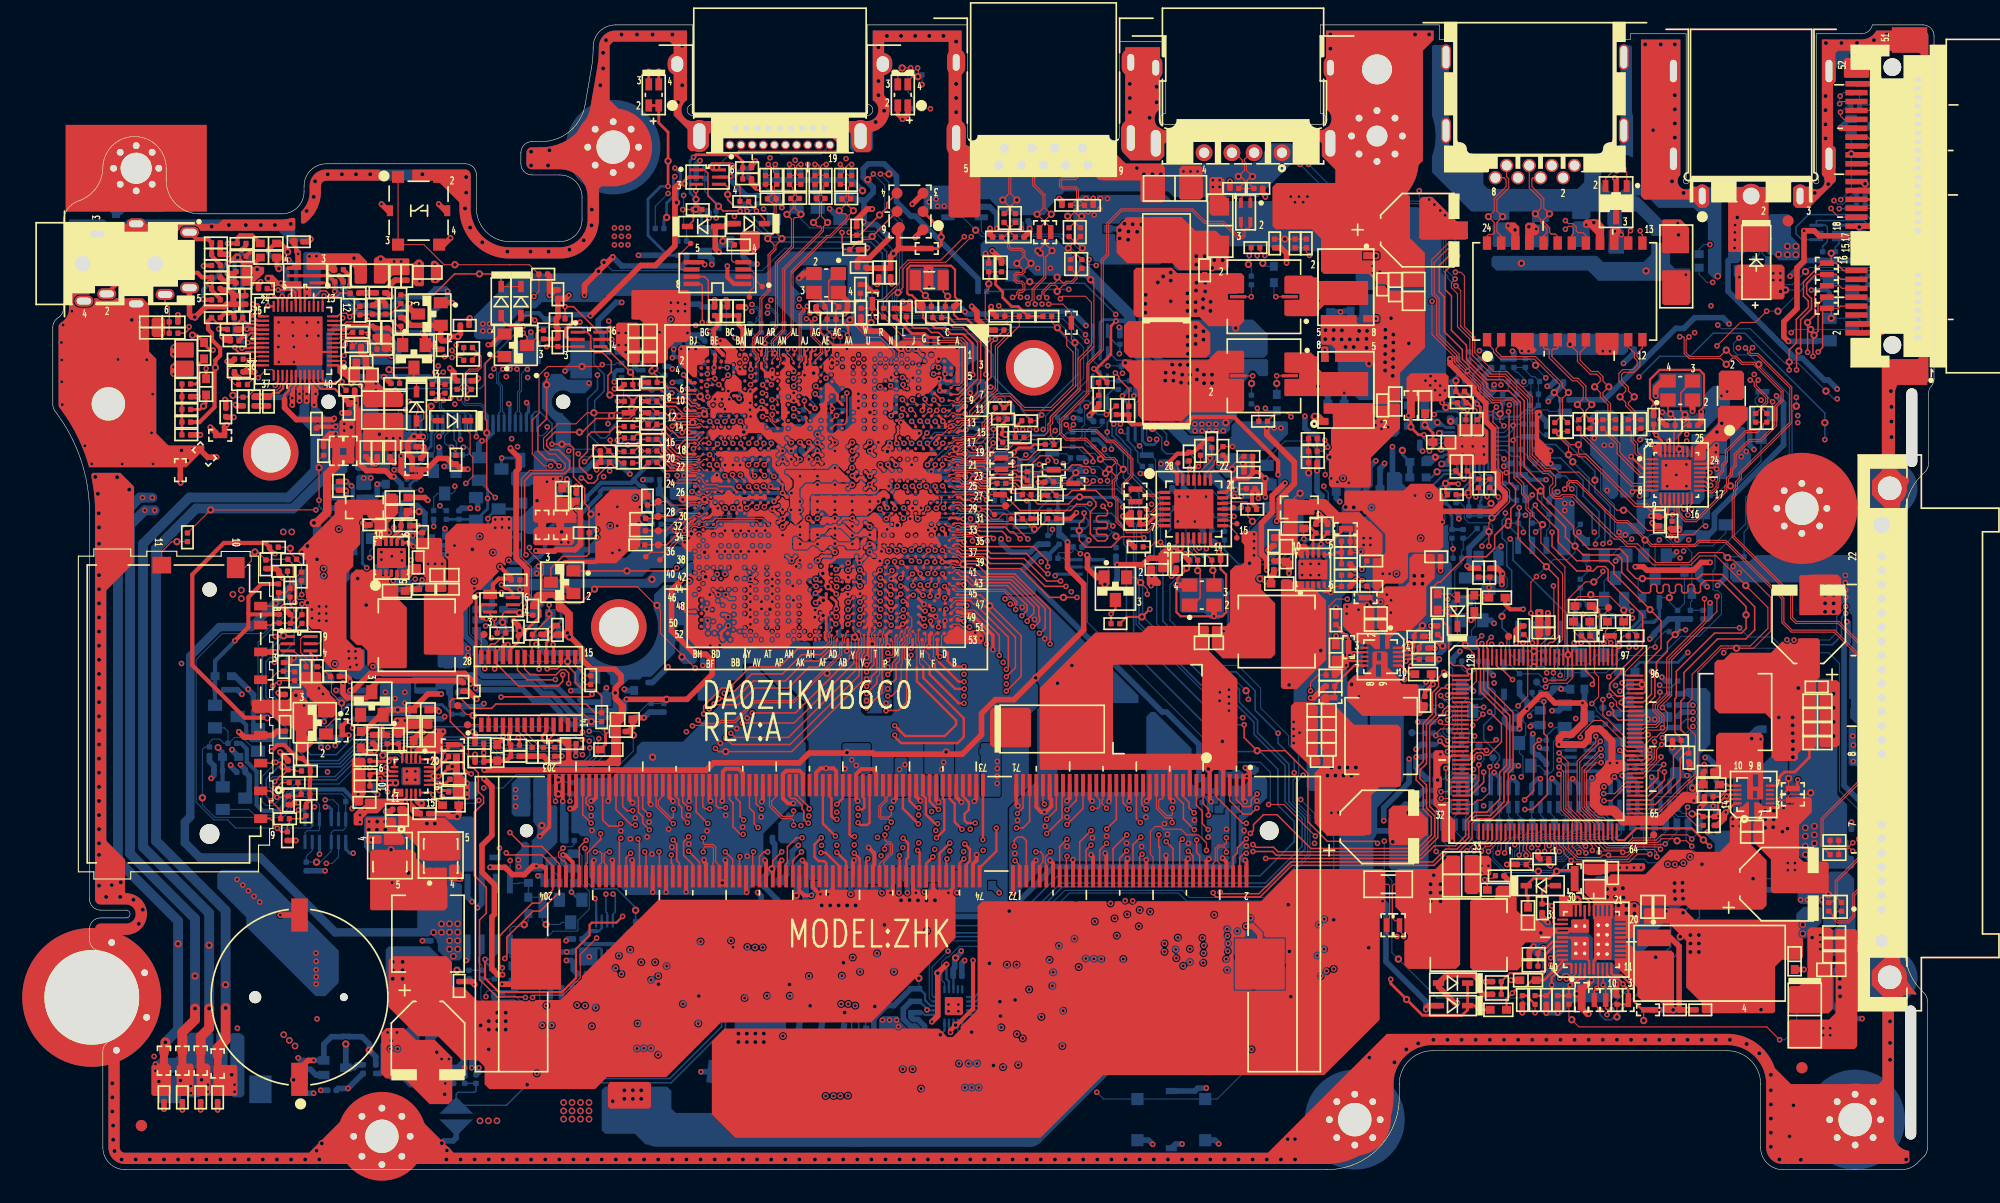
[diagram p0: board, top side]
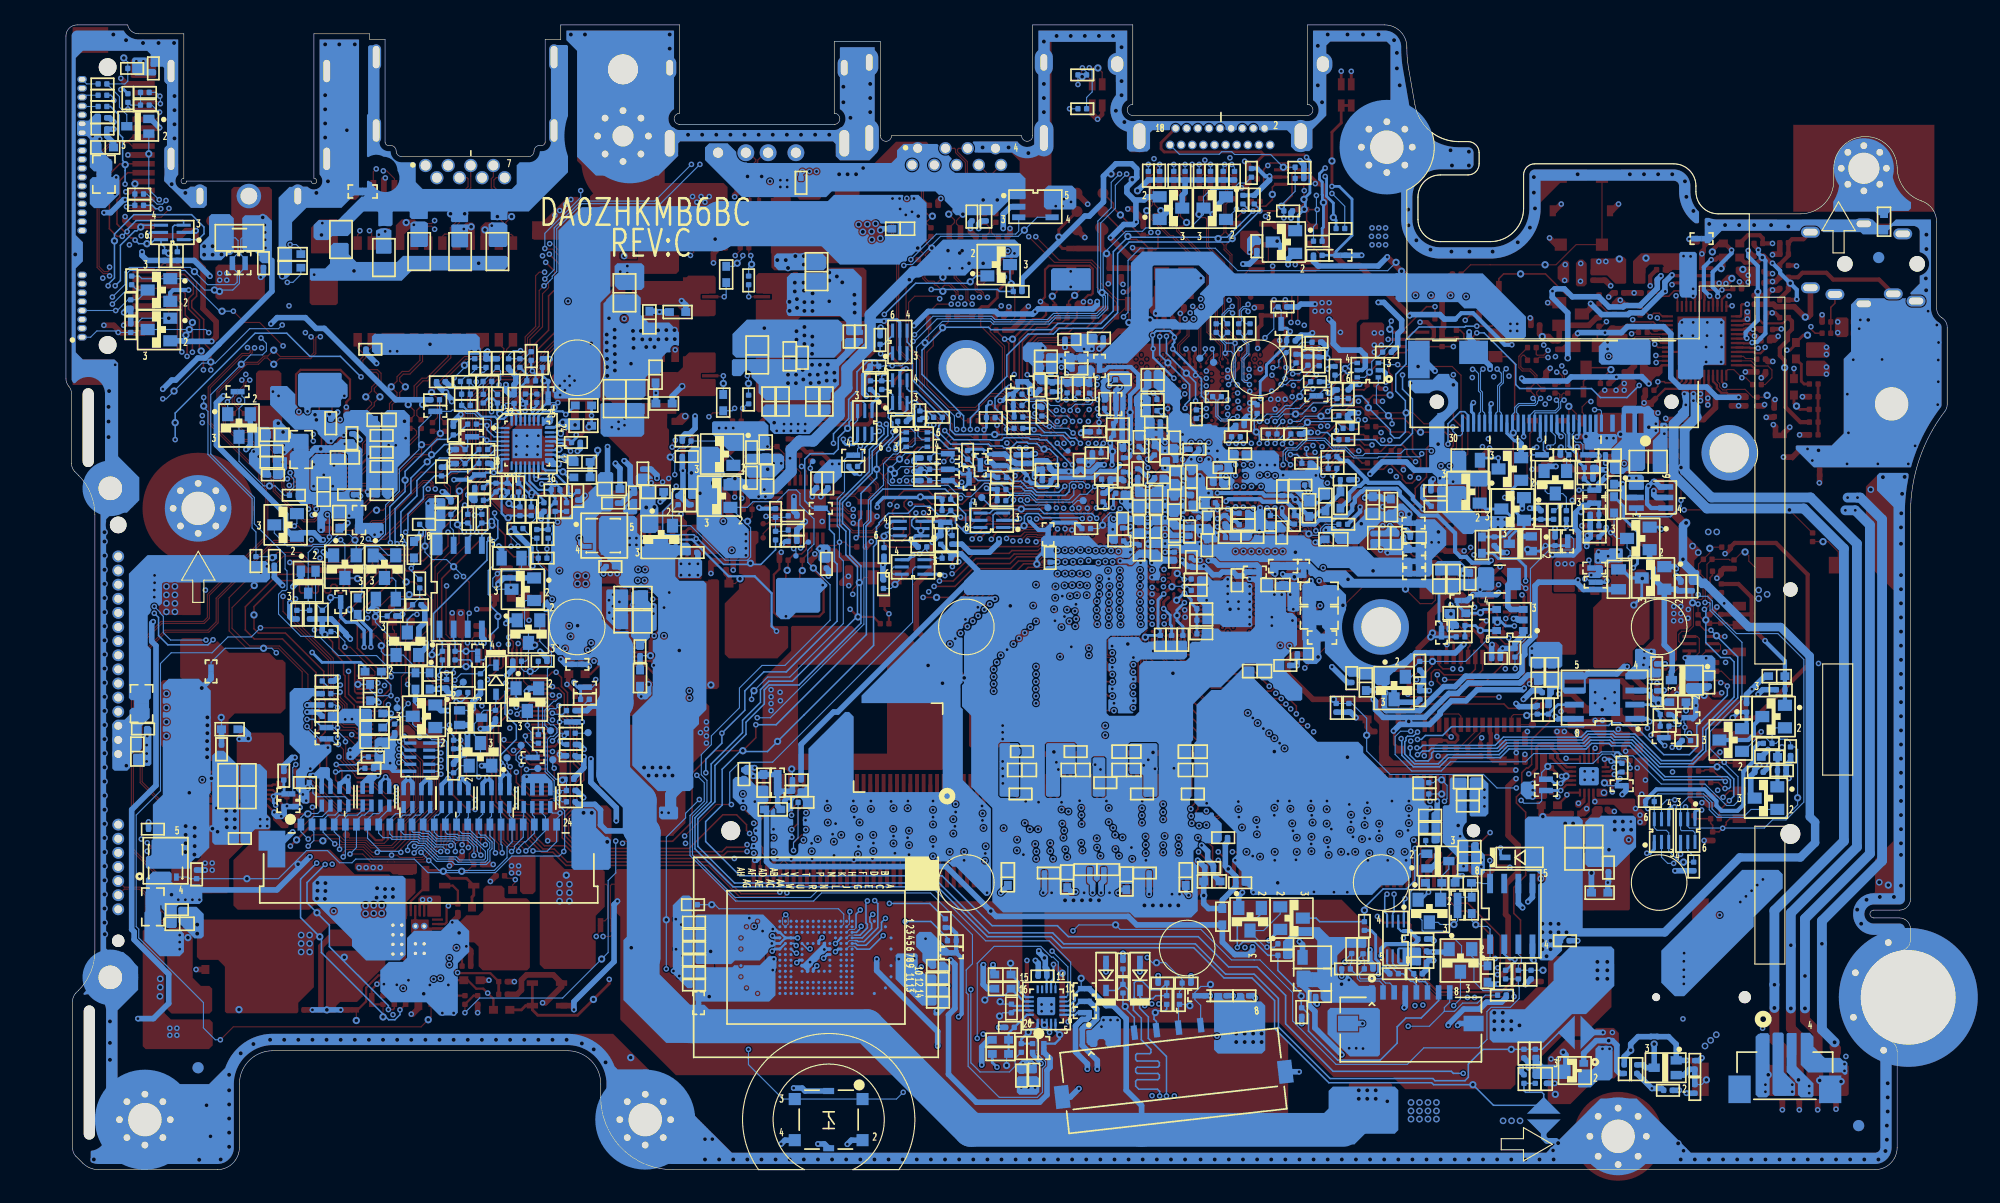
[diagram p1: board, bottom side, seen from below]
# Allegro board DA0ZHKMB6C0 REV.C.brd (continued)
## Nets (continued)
MX2: CN17.16 CP10.7 RP6.3 U18.56
MX3: CN17.14 CP10.3 RP6.4 U18.57
MX4: CN17.7 CP6.5 RP6.6 U18.58
MX5: CN17.3 CP7.5 RP6.7 U18.59
MX6: CN17.2 CP7.3 RP6.8 U18.60
MX7: CN17.1 CP7.1 RP6.9 U18.61
MY0: CN17.4 CP7.7 R394.1 U18.53
MY1: CN17.5 CP6.1 U18.52
MY2: CN17.6 CP6.3 U18.51
MY3: CN17.8 CP6.7 U18.50
MY4: CN17.9 CP11.1 U18.49
MY5: CN17.10 CP11.3 U18.48
MY6: CN17.11 CP11.5 U18.47
MY7: CN17.12 CP11.7 U18.43
MY8: CN17.13 CP10.1 U18.42
MY9: CN17.15 CP10.5 U18.41
MY10: CN17.18 CP9.3 U18.40
MY11: CN17.19 CP9.5 U18.39
MY12: CN17.21 CP8.1 U18.38
MY13: CN17.22 CP8.3 U18.37
MY14: CN17.23 CP8.5 U18.36
MY15: CN17.24 CP8.7 U18.35
NB670BST: PR40.1 PU8.10
NB670BST_S: PC49.1 PR40.2
NB670EN: PC43.2 PR147.2 PR148.2 PU8.13
NB670ENLDO: PR37.1 PR39.2 PU8.12
NB670PG: PR38.2 PU8.4
NB670SW: PC49.2 PL11.1 PR146.2 PU8.8 PU8.9 PU8.15 PU8.16
NB670VOUT: PC48.1 PR42.1 PU8.7
NB671BST: PR47.1 PU10.10
NB671BST_S: PC61.1 PR47.2
NB671EN: PC176.2 PR163.2 PU10.13
NB671FB: PR52.2 PR53.1 PU10.12
NB671PG: PR49.2 PU10.4
NB671SW: PC61.2 PL10.1 PR157.2 PU10.8 PU10.9 PU10.15 PU10.16
NBSWON#: D15.1 SW6.1 SW6.3 U18.95
NOVRP1: R112.1 U13.25
NOVRP2: R113.1 U13.24
NOVRP3: R133.1 U13.20
NOVRP4: R144.1 U13.19
PCBEEP: C40.1 U9.12
PCBEEP_EC: D16.2 U18.118
PCH_DISP_ON: Q8.3 R31.2 R111.2 U21.3
PCH_DISP_ON_C: Q8.1 U12.N30
PCH_DPST_PWM: Q29.3 R277.1 R304.1
PCH_DPST_PWM_C: Q29.4 U12.M30
PCH_LVDS_BLON: Q29.6 Q34.2 R300.2 R377.2 R535.1
PCH_LVDS_BLON_C: Q29.1 U12.J30
PCH_SLP_S0#: Q18.1 U12.G18
PCH_SLP_S0_N: Q18.3 R230.1 U18.28
PCIE_CLKREQ3#: R237.2 TP22.1 U12.BE3
PCIE_CLKREQ_CR#: R239.2 U12.BG3
PCIE_CLKREQ_LAN#: Q30.1 R242.2 U12.BG5
PCIE_CLKREQ_LAN#_IC: Q30.3 R150.2 U11.12
PCIE_CLKREQ_WLAN#: Q19.1 R246.2 R537.1 U12.BD7
PCIE_RXN1_WLAN: CN10.23 U12.AT9
PCIE_RXN2_LAN: C76.2 U12.AP10
PCIE_RXP1_WLAN: CN10.25 U12.AT10
PCIE_RXP2_LAN: C77.2 U12.AP12
PCIE_TXN1_WLAN: C154.1 CN10.31
PCIE_TXN1_WLAN_C: C154.2 U12.AV4
PCIE_TXN2_LAN: C152.1 U11.14
PCIE_TXN2_LAN_C: C152.2 U12.AT6
PCIE_TXP1_WLAN: C155.1 CN10.33
PCIE_TXP1_WLAN_C: C155.2 U12.AV6
PCIE_TXP2_LAN: C153.1 U11.13
PCIE_TXP2_LAN_C: C153.2 U12.AT7
PCIE_WAKE#_R: CN10.1 Q20.1 R232.1
PCLK_TPM: C106.1 R98.1 U16.21
PCU_V3P3_G3_PWR: C183.1 C185.2 R257.2 U12.N18 U12.N22 U12.P18
PD#: D31.2 D32.2 R82.2 U9.47
PGANG: R114.2 U13.23
PLTRST#: C359.2 Q21.6 R202.1 R217.2 R235.1 R322.1 R530.1 U11.19 U16.16 U18.7
PLTRST#_2: CN10.22 R216.1 R217.1
PM_EXTTS#0: JDIM6.198 R398.2
PMU_BATLOW#_R: R301.2 U12.K26
PROCHOT_EC: Q33.2 R358.2 U18.111
PSELF: R115.1 U13.22
PWR_SD_EN: C156.2 PQ2.2 Q46.6 R185.2
PWRLED#: R192.2 U18.62
PWROK_EC_UR: R375.1 U18.74
R_SPK+: R191.2 U9.45
R_SPK+_1: C139.1 CN19.1 R191.1
R_SPK-: R190.2 U9.44
R_SPK-_1: C138.1 CN19.2 R190.1
REGOUT: L13.1 U11.24
RESET#_USB: C248.2 R306.1 R308.2 R322.2 U13.17
RF_EN: CN10.20 U18.83
RING2: Q7.3 R30.1 R37.1 U9.17
RREF: R154.1 U13.8
RSET: R97.2 U11.31
RSMRST#: R58.2 R373.2 U12.B10
RSMRST#_UR: R373.1 U18.75
RTC_VCC_P22_PWR: C221.2 R288.1 U12.P22
RTC_X1: C46.2 R59.1 U12.C9 Y7.1
RTC_X2: C47.2 R59.2 U12.A9 Y7.2
S5_ON: PQ33.2 PQ37.2 PR126.2 PR148.1 PR163.1 PR184.2 R387.1 R391.1 U18.26
S5D: PC133.1 PQ13.2 PQ17.2 PU16.9
SATA_GP0: R252.1 U12.BA12
SATA_GP1: R260.1 U12.AY14
SATA_RCOMP_DN: R163.2 U12.AT18
SATA_RCOMP_DP: R163.1 U12.AU18
SATA_RXN0: C124.2 U12.AV16
SATA_RXN0_R: C124.1 CN14.5
SATA_RXP0: C123.2 U12.AU16
SATA_RXP0_R: C123.1 CN14.6
SATA_TXN0: C130.2 U12.BG7
SATA_TXN0_R: C130.1 CN14.3
SATA_TXP0: C129.2 U12.BF6
SATA_TXP0_R: C129.1 CN14.2
SD3_WP: R316.2 U12.BD5
SDIO3_1P8_EN#: Q50.5 U12.BF22
SDIO3_CD: Q46.2 Q46.3 R184.2
SDIO3_CD#: CN4.10 R363.2 T10.1 U12.BC24
SDIO3_CLK: R543.2 U12.AY26
SDIO3_CMD: CN4.2 R548.2 T13.1 U12.AV28
SDIO3_DATA_0: R542.2 U12.AT28
SDIO3_DATA_0C: CN4.7 R542.1 R547.2 T14.1
SDIO3_DATA_1: R541.2 U12.BD26
SDIO3_DATA_1C: CN4.8 R541.1 R546.2 T15.1
SDIO3_DATA_2: R540.2 U12.AU28
SDIO3_DATA_2C: CN4.9 R540.1 R545.2 T11.1
SDIO3_DATA_3: R544.2 U12.BA26
SDIO3_DATA_3C: CN4.1 R544.1 R549.2 T12.1
SDIO3_PWR_EN#: Q50.2 Q51.2 R365.2 U12.BD22
SDIO3_RCOMP: R293.2 U12.BF26
SDVO_CLK: Q6.4 R219.2 U12.C28
SDVO_DATA: Q6.1 R218.2 U12.C26
SENSEA: R22.1 U9.13
SERIRQ: R83.1 U18.125
SERIRQ_R: R172.2 R539.1 U16.27 U24.4
SIO_EXT_SCI#: R395.1 U18.29 U26.3
SIO_EXT_SMI#: R370.1 U18.9 U26.1
SIO_RCIN#: TP19.1 U18.122
SLEEVE: Q7.6 R33.1 R68.1 U9.18
SLP_S0IX#: Q21.4 U12.F18
SLP_S3#: Q23.4 R86.1 U12.D22
SLP_S4#: Q23.1 Q53.2 R87.1 U12.F22
SLP_SUS#_EC: Q21.3 R241.2 U18.79
SLP_SUS_ON: PR159.1 R343.1 U18.96
SMB_RUN_CLK: JDIM6.202 Q16.1 Q40.3 R67.1
SMB_RUN_DAT: JDIM6.200 Q16.4 Q40.6 R62.1
SMB_SOC_ALERTB_C: R80.2 U12.BG11
SMB_SOC_CLK: Q40.4 R73.2 U12.BH10
SMB_SOC_DATA: Q40.1 R79.2 U12.BG12
SMC: PJ7.4 PR179.1
SMD: PJ7.3 PR180.1
SOC_CLKOUT_0: R90.2 R98.2 U12.BG15
SOC_CLKOUT_1: R274.2 U12.BH14
SOC_CLKRUN#: R167.1 R279.2 U12.BG16
SOC_CORE_PIN_AA22: TP25.1 U12.AA22
SOC_CORE_PINAF30: TP26.1 U12.AF30
SOC_DDIO_RCOMP: R264.1 U12.AK13
SOC_DDIO_RCOMP_P: R264.2 U12.AK12
SOC_DRAM_PWROK: C256.1 R315.1 U12.AD42
SOC_GPIO_RCOMP: R299.2 U12.N26
SOC_GPOI7: R36.1 U12.C15
SOC_JTAG2_TCK: R60.1 U12.B16
SOC_JTAG2_TDI: R81.1 U12.A17
SOC_JTAG2_TDO: R61.1 U12.C17
SOC_JTAG2_TMS: R88.1 U12.C18
SOC_KBC_SCI: R243.1 R252.2 U26.4
SOC_KCB_SMI: R36.2 R256.1 U26.6
SOC_OVERRIDE: Q24.3 U12.BC30
SOC_OVERRIDE_NM: Q24.5 R283.1
SOC_PCIE_COMN: R263.2 U12.AP13
SOC_PCIE_COMP: R263.1 U12.AP14
SOC_PLTRST#: Q21.1 U12.F20
SOC_PMC_WAKE: R295.2 U12.F26 U25.4
SOC_PROCHOT#: R128.2 R130.2 U12.C24
SOC_PWR_BUT: R48.1 U12.N3
SOC_PWRBTN#: R280.1 U12.J26 U25.6
SOC_REST_BTN: R74.2 U12.BG9
SOC_RTEST#: C336.1 G7.1 R415.2 U12.C11
SOC_SENS_HUB_RST#: TP35.1 U12.AT32
SOC_SENSOR_HUB_WAKE: R265.2 U12.BF14
SOC_SERIRQ: R83.2 R84.2 R172.1 U12.BG13 U24.3
SOC_SPI_CLK: R121.2 U12.C22
SOC_SPI_CLK_R: R121.1 R311.1 U22.6
SOC_SPI_CLK_R1: R311.2 U18.92
SOC_SPI_CS#: R120.2 R305.2 U12.C23
SOC_SPI_CS#_R: R120.1 R354.1 U22.1
SOC_SPI_CS#_R1: R354.2 U18.90
SOC_SPI_MISO: R352.2 U12.B22
SOC_SPI_MISO_R: R352.1 R353.1 U22.2
SOC_SPI_MISO_R1: R353.2 R362.2 U18.86
SOC_SPI_MOSI: R116.2 U12.A21
SOC_SPI_MOSI_R: R116.1 R310.1 U22.5
SOC_SPI_MOSI_R1: R310.2 U18.87
SOC_UART_RX: R273.2 U12.BC16
SOC_UART_TX: R273.1 U12.BD14
SOC_USB_OC0: R105.1 U12.C20 U19.3
SOC_VCCA_PWROK: C261.1 Q32.3 R328.1 U12.AB42
SPI_3P: R319.2 U22.3
SPI_7P: R318.2 U22.7
SRT_CRST#: C332.1 G6.1 R413.2 U12.C12
SUS_LED#: R195.2 U18.16
SUS_PWRDOWNACK: R287.2 R291.2 U12.D26
SUSB#: Q23.3 R86.2 R268.1 R320.1 U18.21
SUSC#: Q23.6 R87.2 R245.1 R324.1 U18.20
SUSON: PR162.1 R171.1 U18.117
SUSWARN#_EC: R287.1 U18.113
SVID_ALERT#_SOC: R129.1 U12.B24
SVID_CLK_SOC: R134.1 U12.C25
SVID_DATA_SOC: R135.1 U12.A25
SYS_HWPG: PR36.2 PR38.1 PR49.1
SYS_SHDN#: PQ36.3 PR32.1 PR41.1 PR147.1 SW8.1 SW8.3
TEMP_MBAT: C110.2 PR174.1 PR178.1 U18.97
TEMP_MBAT_C: PJ7.5 PR178.2
THER_CPU: R327.2 R337.1
THERMDA: TP8.1 U7.2
THERMDC: TP9.1 U7.3
THRM_MOINTOR: C274.2 R337.2 R345.1 U18.100
TOUCH_PANEL_SOC_RST#: R269.2 U12.BD16
TOUCH_SCREEN_PWR: C202.2 C210.1 CN16.11 R294.1
TOUCH_SCREEN_SEL: CN16.29 Q12.3 R153.1
TOUCHPANEL_INTR#_SOC: TP21.1 U12.AU32
TP_EN_EC: CN18.8 R536.1 U18.73
TP_INT_C: Q12.1 U12.G24
TP_INT_EC#: Q41.3 R420.2 U18.11
TP_NC: R155.1 TP27.1 U12.BH30
TP_NC1: R156.1 TP32.1 U12.BG30
TP_POWER_ON: PU16.2 TP43.1 U18.25
TP_SENSOR_INT: Q42.3 R513.1 U12.B18
TP_SENSOR_INT_R: C358.2 CN18.7 Q41.1 Q45.2 R420.1 R534.1
TPCLK: C330.2 CN18.2 R406.2 U18.72
TPDATA: C329.2 CN18.3 R405.2 U18.71
TPM_VDD: C105.1 C107.1 C118.1 C119.1 C355.1 R178.2 R180.1 R182.2 R526.2 R539.2 U16.10 U16.19 U16.24
TPM_VSB: C356.2 C357.1 R526.1 R527.2 R528.2 U16.5
ULT_EDP_HPD: CN16.12 Q28.2 R276.2
UNCORE_V1P8_AN32_PWR: C241.2 C245.2 C265.2 R321.1 U12.AM30 U12.AN32 U12.U38
USB3_P0_REXT: R351.2 U12.M7
USB3_P1_REXT: R258.2 U12.M12
USB3_V1P0_G3: C165.2 C171.1 C172.2 C193.1 C220.2 R238.2 U12.B6 U12.C3 U12.C5 U12.U22 U12.V22 U12.Y19
USB30_RX1+: C23.1 R13.2 U12.D4
USB30_RX1+_R: CN6.6 R13.1
USB30_RX1-: C22.1 R12.2 U12.E3
USB30_RX1-_R: CN6.5 R12.1
USB30_TX1+: C26.1 U12.K6
USB30_TX1+_C: C26.2 R20.2
USB30_TX1+_R: C18.1 CN6.9 R20.1
USB30_TX1-: C25.1 U12.K7
USB30_TX1-_C: C25.2 R19.2
USB30_TX1-_R: C17.1 CN6.8 R19.1
USB_BT_N: CN10.36 U13.3
USB_BT_P: CN10.38 U13.4
USB_H1_N: R131.1 U12.G14
USB_H1_N1: R131.2 U13.1
USB_H1_P: R139.1 U12.J14
USB_H1_P1: R139.2 U13.2
USB_HSIC_RCOMP: R55.2 U12.A7
USB_HSIC_V1P2_G3: R240.1 U12.V18
USB_HUB_5V: TP15.1 U13.27
USB_RCOMP: R247.2 U12.C7 U12.D6
USB_USB_N: L7.2 U13.6
USB_USB_P: L7.3 U13.7
USBON#: U18.112 U19.4
USBP0+: R17.2 U12.M16
USBP0+_R: CN6.3 R17.1
USBP0-: R18.2 U12.K16
USBP0-_R: CN6.2 R18.1
USBP1+_CN: CN8.3 D7.1 L7.4
USBP1-_CN: CN8.2 D8.1 L7.1
USBP2+: CN16.27 U12.K12
USBP2-: CN16.26 U12.J12
USBP3+: CN16.24 U12.K10
USBP3-: CN16.23 U12.H10
V_BLIGHT: C190.1 C192.1 C206.2 CN16.1 CN16.2 CN16.3 R106.2 R107.2
VCORF_UR: C126.1 U18.44
VIS_V1P0_SIOX_PW: C209.1 C232.1 C233.1 C239.1 C255.1 R309.2 U12.AF21 U12.AG21 U12.AN29 U12.AN30 U12.V24 U12.Y22 U12.Y24
VL: PC47.2 PR172.1 PR173.1 PU8.11
VR_SVID_ALERT#: PR97.1 PR99.2 R127.1 R129.2
VR_SVID_CLK: PR95.2 PR96.2 R134.2
VR_SVID_DATA: PR98.2 PR104.2 R135.2
VRON: TP45.1 U18.80
WAKE_SRC_1: Q20.3 Q25.1 R266.2 R516.1 U18.84 U25.3
WIMAX_LED#: CN10.42 R204.1
WLAN_CLK_SCLK: CN10.30 Q16.6 R223.1
WLAN_CLK_SDATA: CN10.32 Q16.3 R222.1
WLAN_LED1#: CN10.44 R201.2 R203.1 R204.2
WPAN_LED#: CN10.46 R201.1
XDP_H_PRDY#: TP24.1 U12.D18
XDP_H_PREQ#: R63.1 U12.F16
XDP_H_TCK: R262.1 U12.D14
XDP_H_TDI: R251.1 U12.F12
XDP_H_TDO: R267.1 U12.G16
XDP_H_TMS: R259.1 U12.F14
XDP_H_TRST#: R250.2 U12.G12
XIN: C95.1 U13.10 Y9.1
XOUT: C96.1 U13.11 Y9.3
XTAL1: C79.1 U11.28 Y8.3
XTAL2: C78.1 U11.29 Y8.1
XTAL25_IN: C32.1 R42.1 U12.AH12 Y6.3
XTAL25_OUT: C33.1 R42.2 U12.AH10 Y6.1
N52444: PC57.2 PR43.2 PU9.5
N2441980: PC113.1 PR11.1 PU12.22
N2441992: PC19.1 PR12.2 PU12.21
N2443322: PC117.1 PR109.2
N2443370: PC101.1 PR85.2
N2443568: PR13.2 PR19.2
N2443616: PL7.4 PR89.1
N2443620: PL7.3 PR91.1
N2444597: PC123.2 PR116.2 PU12.11
N2445489: PR90.1 PR93.1 PU12.2
N2446506: PR79.2 PR86.1 TP23.1
N2446664: PR86.2 PU12.27
N2446955: PR6.1 PR7.1 PR8.2
N2448066: PR15.1 PR16.1 PR17.2
N2453156: PC95.1 PR77.2
N2453320: PR9.2 PR82.2
N2453360: PL6.4 PR75.1
N2453364: PL6.3 PR74.1
N2455134: PC111.1 PR92.2
N2455877: PC108.1 PR88.1 PU12.31
N2456910: PC98.1 PR76.1 PR78.2 PR80.1 PR81.2
N2456918: PC109.1 PR110.2 PR111.1 PU12.30
N2457578: PC16.1 PC102.2 PR10.2 PR81.1 PR87.2 PU12.29
N2457590: PC18.1 PR10.1
N2457790: PC102.1 PR80.2
N2457802: PC105.1 PR87.1
N2459346: PR107.2 PU12.8
N2459788: PC140.1 PR100.2 PR102.1 PR121.2 PR124.1
N2459816: PC137.1 PR105.2 PR106.2 PU12.12
N2460379: PC128.1 PC141.2 PR21.2 PR115.2 PR121.1 PU12.13
N2460411: PC141.1 PR124.2
N2460459: PC20.1 PR21.1
N2460593: PC136.1 PR115.1
N2481405: PC108.2 PR83.1
N2482435: PC123.1 PR117.2
N16509126: LED6.3 R192.1
N16512880: R24.1 U7.4
N16529605: TP31.1 U18.6
N16532690: R270.2 U12.M13
N16563782: PR98.1 PU12.5
N16563868: PR97.2 PU12.4
N16564009: PR95.1 PU12.3
N16585380: TP55.1 U13.18
N16624010: PC197.1 PR184.1 PU16.1
N16782265: PC112.2 PQ11.2 PQ22.3 PR134.2
N16827218: PC163.2 PQ18.3 PQ28.2 PR113.2
N16827382: LED6.1 LED6.2 R197.1 R198.1
N16853934: Q25.3 R298.2 R516.2 U11.21
N17396502: Q39.2 R414.1 R416.2
N17658483: PC78.1 PR56.1
N17711248: PR70.2 PU11.10
N17719024: PR60.1 PR61.2 PU11.37
N17726601: PC88.1 PR63.2 PU11.1
N17863079: PC89.2 PR68.1
N17863093: PR68.2 PU11.9
N17879873: TP56.1 U13.13
N17879875: TP57.1 U13.12
N18086472: LED7.3 R193.1
N18086480: LED7.4 R194.1
N18090006: R104.1 U12.B20
N18134434: D16.1 D19.1 R52.2
N18246859: C97.1 C98.1 C101.2 D24.2 R165.1 R166.1
N18278202: PR170.1 PR173.2 PU15.2
N18278204: PC183.2 PR168.1 PR169.1 PU15.8
N18278208: PD10.1 PQ35.1 PR166.1
N18278220: PQ35.3 PR169.2
N18278227: PQ33.3 PQ35.2 PR166.2
N18278261: PC188.2 PQ36.2 PR168.2 PU15.1
N18278273: PQ37.3 PR170.2
N18314354: PC28.1 PC31.1 PR23.1 PR25.1 PU7.9 PU7.10
N18314480: PC22.1 PC24.1 PR22.1 PR24.1 PU6.9 PU6.10
N18512754: PR138.2 PR139.2 PU13.6
N18512806: PC151.1 PR132.2 PU13.4
N18596580: LED6.4 R195.1
N19249672: C338.2 R426.2 U27.7 U27.8
N19253605: TP48.1 U12.G30
N19253641: TP50.1 U12.C27
N19253642: TP49.1 U12.B28
N19253643: TP51.1 U12.B26
N19253669: TP52.1 U12.AL3
N19253671: TP53.1 U12.AL1
N19661024: TP40.1 U18.107
N19667233: R181.1 R182.1 U16.7
N19667243: R180.2 U16.6
N19667397: R533.2 U16.15
N19667450: TP101.1 U16.1
N19667455: TP100.1 U16.2
N19667489: R530.2 U16.9
N19667717: TP99.1 U16.28
N19837103: Q42.2 Q45.3 R523.1
N19870274: C164.2 U8.3 U8.4 U8.9 U8.10
N20005341: Q46.5 R186.1 R363.1 R365.1
N20136993: C80.1 CN4.5 R543.1
N20159096: C282.1 D34.1 MR6.1 R361.1
N20218729: R419.2 U24.5
N20239051: PQ29.2 Q50.3 Q50.6 Q51.5 R187.2 R234.1
N20248245: PQ30.2 PQ31.2 Q51.3 Q51.6 R355.1 R356.2
N20295671: D24.1 R166.2 U18.4
N20307624: CN4.11 R316.1
N20310085: C226.2 Q27.2 R124.2 R297.1
N20311584: R34.2 U3.2
N20824488: R550.1 R551.1 U25.5
N20841552: HOLE9.1 HOLE9.2 HOLE9.3 HOLE9.4 HOLE9.5 HOLE9.6 HOLE9.7 HOLE9.8 HOLE9.9 R552.2
N38782190: PC181.2 PR167.1
N72970043: TP58.1 U13.15
N72970046: TP59.1 U13.16
N77036399: PR139.1 PR141.1
N77036417: PC155.2 PR140.1 PU13.1
N77036440: PR155.2 PU13.5
N77040681: PC154.2 PR146.1
N77040703: PR52.1 PR144.1
N77040765: PC68.2 PU10.11
N77090490: PC39.2 PR34.2
N77093840: PQ25.2 PQ26.3 PR142.2 PR143.1
N77097662: PQ21.2 PQ22.2 PQ24.3 PR136.1 PR137.2
N77098719: PC152.1 PQ24.2 PR133.2
N77135926: PR50.2 PU10.3
N77159527: PR154.2 PU14.1
N77159544: PR150.2 PR151.2 PU14.7
N77159572: PC173.2 PR153.1 PU14.2
N77164289: PQ18.2 PQ23.2 PQ27.3 PR129.2 PR130.1
N77164358: PC165.1 PQ27.2 PR152.2
N77164885: PQ12.2 PQ15.2 PQ20.3 PR118.2 PR119.1
N77164911: PC119.2 PQ14.2 PQ15.3 PR103.2
N77164954: PC143.1 PQ20.2 PR123.2
N77521058: TP41.1 U18.30
N77521417: R374.1 TP36.1
N77522500: TP18.1 U18.101
N77651911: CN10.45 R205.2
N77651913: CN10.47 R202.2
N77651966: CN10.16 R29.1
N77651968: CN10.14 R32.1
N77651970: CN10.12 R40.1
N77651972: CN10.10 R46.1
N77651974: CN10.8 R50.1
N77651983: CN10.51 R200.2
N77714296: PC34.2 PR33.2
N77766782: R535.2 U18.14
N107989610: C56.1 U9.7
N107992729: C68.2 U9.39
N107992826: C63.2 U9.35
N107992865: C63.1 U9.37
N107994632: C57.1 U9.34
N108778749: Q7.2 Q7.5 Q27.3 R35.1
N111127099: C35.1 U9.19
N202517111: PC174.2 PR157.1
N202572550: PQ12.3 PR101.2
N202573721: PQ23.3 PR127.2
N202573930: PQ25.3 PR125.2
N202576670: PQ21.3 PR135.2

Pads without a net: CN7 13 14; CN10 3 5 6 17 19 28 48 49; CN14 18 20 21 22; CN16 4; CN19 5 6; JDIM6 77 122 125; NOREF 1; NOREF#3 1; NOREF#6 1; NOREF#7 1; NOREF#8 1; NOREF#10 1; PU8 3 5; PU10 5 6; PU11 31; PU12 9 20; PU15 7; PU16 14 15; U9 14 16 20 48; U11 25 26 27; U12 AB2 AB3 AB7 AB9 AB12 AB13 AB14 AC1 AC3 AD2 AD3 AD4 AD6 AD9 AD10 AD12 AD40 AD41 AF2 AF3 AF4 AF6 AF13 AF14 AF40 AF41 AF48 AF50 AF51 AF52 AG51 AG53 AH13 AH14 AH40 AH44 AH52 AJ51 AK7 AK9 AK40 AK42 AK45 AK47 AK48 AK50 AK51 AK52 AL51 AL53 AM4 AM6 AM9 AM10 AM13 AM14 AM41 AM42 AM45 AM47 AM48 AM50 AM52 AP4 AP6 AP7 AP9 AP41 AP42 AP44 AP45 AP47 AP48 AP50 AP51 AP52 AR51 AR53 AT13 AT14 AT34 AT36 AT40 AT41 AT42 AT44 AT45 AT48 AT50 AT51 AU34 AU36 AU53 AV9 AV10 AV32 AV34 AV36 AV40 AV44 AV45 AV48 AV50 AV52 AW1 AW41 AW51 AW53 AY2 AY3 AY6 AY7 AY12 AY16 AY20 AY28 AY30 AY34 AY38 AY40 AY42 AY44 AY45 AY47 AY48 AY51 AY52 B4 B5 B12 B14 BA1 BA3 BA16 BA18 BA20 BA28 BA34 BA36 BA38 BA42 BA51 BB3 BB4 BB44 BB47 BB49 BB50 BB51 BC14 BC18 BC36 BC38 BC40 BC44 BC52 BC53 BD2 BD10 BD12 BD18 BD20 BD28 BD32 BD34 BD36 BD38 BD40 BD42 BD44 BD47 BE46 BE51 BE52 BF2 BF10 BF27 BF28 BF32 BF34 BF40 BF42 BF48 BF50 BF52 BG18 BG21 BG24 BG25 BG26 BG27 BG29 BG32 BG33 BG35 BG36 BG37 BG38 BG40 BG41 BG43 BG47 BH4 BH5 BH6 BH7 BH8 BH18 BH24 BH26 BH32 BH34 BH36 BH38 BH40 BH42 BH44 BH46 BH47 BH48 BH49 BH50 BJ9 BJ25 BJ29 BJ33 BJ37 BJ41 BJ45 C16 C21 C30 D2 D28 D32 D34 D48 E2 E46 F1 F28 F32 F34 G2 H3 H4 H5 H7 H8 J3 J18 J20 J24 J28 J34 K2 K3 K18 K20 K24 K28 K34 L1 L3 M2 M3 M4 M6 M9 M10 M18 M20 M22 M24 M32 N24 N32 N34 P2 P3 P6 P7 P10 P12 P14 P34 R1 R3 T2 T3 T4 T6 T7 T9 T10 T12 T13 T14 V2 V3 V4 V6 V9 V10 V13 V14 W1 W3 Y2 Y3 Y4 Y6 Y12 Y13; U16 3 8 12 13 14; U18 15 23 24 31 32 33 34 81 93 99 105 106 110 119 120 121; U30 A4 A6 A9 A11 AA1 AA2 AA7 AA8 AA9 AA10 AA11 AA12 AA13 AA14 AE1 AE14 AG2 AG13 AH4 AH6 AH9 AH11 B2 B13 D1 D14 H1 H2 H6 H7 H8 H9 H10 H11 H12 H13 H14 J1 J7 J8 J9 J10 J11 J12 J13 J14 K1 K3 K5 K7 K8 K9 K10 K11 K12 K13 K14 L1 L2 L3 L4 L12 L13 L14 M1 M2 M3 M5 M8 M9 M10 M12 M13 M14 N1 N2 N3 N10 N12 N13 N14 P1 P2 P3 P10 P12 P13 P14 R1 R2 R3 R5 R12 R13 R14 T1 T2 T3 T5 T12 T13 T14 U1 U2 U3 U6 U7 U10 U12 U13 U14 V1 V2 V3 V12 V13 V14 W1 W2 W3 W7 W8 W9 W10 W11 W12 W13 W14 Y1 Y3 Y6 Y7 Y8 Y9 Y10 Y11 Y12 Y13 Y14

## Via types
v1: diameter 0.508, hole 0.254, TOP to BOTTOM, 2595 vias
v2: diameter 0.66, hole 0.33, TOP to BOTTOM, 413 vias
v3: diameter 0.61, hole 0.356, TOP to BOTTOM, 577 vias
v4: diameter 0.66, hole 0.254, TOP to BOTTOM, 2 vias

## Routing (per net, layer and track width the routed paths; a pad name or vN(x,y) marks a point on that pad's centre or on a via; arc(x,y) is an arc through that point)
2.469V: length 4.8
  BOTTOM w0.102: v2(36.36,17.94) PR171.1 PR172.2 38.57,18.39 38.29,18.67 38.29,19.1 38.57,19.38 PU15.3
5V_HSMBCK: length 2.7
  TOP w0.14: D10.1 57.61,85.39 R14.1 v1(56.66,86.39)
5V_HSMBDT: length 2.6
  TOP w0.14: D9.1 64,85.54 v1(63.29,86.26) 63.29,86.28 62.59,86.99 R11.1
5VUSB_0:
  vias: v1(104.33,89.03) v1(104.33,88.42) v1(104.94,89.03) v1(104.94,88.42) v2(97.5,90.12) v3(98.14,89.56) v3(98.9,89.56) v3(99.66,89.56)
51216VBST: length 2.5
  TOP w0.203: PR51.2 34.2,33.63 v1(34.2,33.73) 34.02,33.92 PU9.15
51216VBST_S: length 3.8
  TOP w0.508: PR51.1 36.52,31.92 v2(36.37,31.77) 35.69,31.77 35.43,32.03 PC71.1
51216VDDQSNS: length 3.4
  TOP w0.203: PU9.9 29.59,35.02
  TOP w0.254: 29.59,35.02 v1(29.43,35.18)
  BOTTOM w0.102: v2(30.83,34.8) 30.57,34.54 PR161.1
  BOTTOM w0.254: PR161.1 29.67,34.94 v1(29.43,35.18)
+1.0V: length 118.4
  TOP w0.102: U12.AM18 66.04,65.05
  TOP w0.203: v1(75.9,65.35) 75.82,65.42 75.82,66.04 76.01,66.22 U12.M14 ; v1(64.56,61.47) 64.77,61.26 U12.AN25
  TOP w0.254: U12.AN21 65.26,63.53 v1(65.64,63.91) 66.02,63.53 U12.AM21 ; U12.U19 73.86,64.29 v1(73.48,64.67) 73.86,65.05 U12.U18 ; U12.AK18 66.8,65.05 v1(66.42,64.67) 66.04,65.05 ; v1(68.78,66.15) 69.12,65.81 U12.AF16 ; U12.Y18 72.29,65.05 v1(71.91,64.67) ; v1(56.73,71.5) 57.44,70.79 U12.BJ6 ; v1(77.63,73.84) 78.16,73.31 U12.G1 ; v1(68.78,65.43) 69.15,65.05 U12.AF18 ; v1(73.47,57.86) 73.42,57.91 73.41,57.91 73.1,58.22 U12.V32 ; U12.AN19 65.26,64.29 v1(65.64,64.67) 65.26,65.05 U12.AN18
  TOP w0.381: v1(88.64,61.85) 88.66,61.82 89.19,61.82 R128.1 ; v1(88.74,60.43) 88.99,60.68 R127.2
  IN1 w0.381: v1(48.23,70.76) 49.6,70.76 50.26,71.43 56.66,71.43 v1(56.73,71.5)
  IN2 w0.508: v1(51.91,62.59) 52.11,62.79 53.25,62.79 54.6,64.14 55.87,64.14 ; 58.28,65.86 58.46,66.04 64.94,66.04 65.64,65.34 v1(65.64,64.67)
  IN2 w1.016: 132.76,72.03 130.6,72.03 130.19,72.44 128.01,72.44 124.93,75.51 124.93,78.46 123.86,79.54 123.86,80.43 119.74,84.54 114.37,84.54 113.48,83.65 101.8,83.65 97.36,79.21 96.32,79.21 95.37,78.26 92.7,78.26 90.47,76.02 85.84,76.02 85.44,75.62 83.33,75.62 82.57,74.85 75.81,74.85 74.9,73.94
  BOTTOM w0.254: v1(75.9,65.35) 76.1,65.15 C194.2
  BOTTOM w0.381: C188.2 72.28,64.67 v1(71.91,64.67) ; v1(73.48,64.67) 73.48,64.18 73.61,64.05 C197.1 ; v1(73.47,57.86) 73.61,57.73 C243.2
  BOTTOM w0.508: v1(134.41,70.49) 134.66,70.49 135.07,70.89 PC103.1 ; PR99.1 134.59,64.8 v1(134.71,64.67) ; PR104.1 v1(134.71,63.53) 135.03,63.2 PR108.1 ; PR96.1 134.36,67.28 v1(133.7,67.95) ; v1(51.91,62.59) 50.82,63.68 48.66,63.68 47.92,62.94 46.47,62.94 46.4,63.02
  vias: v1(44.44,61.9) v1(45,62.15) v1(45.63,62.2) v1(76.95,73.84) v2(43.55,60.2)
+1.0V_S5: length 23.8
  BOTTOM w0.508: v1(35.5,55.32) 33.65,55.32 33.14,55.83 33.14,57.35 33.47,57.68 33.47,59.06 32.76,59.77 32.33,59.77 PR114.2
  BOTTOM w2.032: 65.01,79.63 48.9,79.63
  vias: v1(38.68,76.1) v1(38.68,75.46) v1(39.28,76.1) v1(39.28,75.46) v1(39.79,58.5) v1(39.79,57.76) v1(40.4,58.52) v1(40.4,57.79) v1(41.04,58.52) v1(41.04,57.76) v2(37.74,55.8)
+1.0VSX:
  vias: v1(45.74,56.44) v1(46.37,56.44) v2(45.76,57.38)
+1.5V: length 133.5
  TOP w0.203: 19.65,69.72 19.83,69.9 20.31,69.9 20.72,70.31 20.72,70.59 21.06,70.93 U9.40 ; 26,75.57 U9.9
  TOP w0.254: v1(65.64,57.85) 65.75,57.96 65.77,57.96 U12.AM32 ; 26.13,75.57 26,75.57
  TOP w0.381: 26.13,75.57 26.29,75.57 26.63,75.91 28.23,75.91 28.25,75.93 28.79,75.93 C51.1 C52.1 30.23,75.73 30.65,75.31 v1(30.78,75.31)
  TOP w0.508: v1(51.6,42.32) v2(55.2,42.32) 57.04,42.32 59.3,44.58 59.3,45.82 58.74,46.38 57.75,46.38 55.64,48.49 55.64,52.15 v1(56.48,52.98) ; R297.2 34.52,73.8 34.13,74.19 Q11.2 33.49,74.98 v1(33.24,75.24)
  IN1 w0.508: v1(28.78,45.26) 28.12,44.6 25.24,44.6 24.6,45.24 24.6,46.28 23.66,47.22 19.45,47.22 18.28,46.05 12.08,46.05 v1(11.57,45.54)
  IN2 w0.508: v1(65.64,57.85) 65.46,57.85 64.46,56.85 59.23,56.85 58.51,56.13 58.51,54.29 57.82,53.59 56.84,53.59 56.48,53.24 v1(56.48,52.98) ; v1(18.76,69.49) 18.46,69.49 17.95,68.99 17.95,68.45 15.69,66.19 15.69,63.96 14.14,62.41 14.14,55.93 11.57,53.37 v1(11.57,45.54)
  BOTTOM w0.254: C254.2 64.92,57.13 65.39,57.6 v1(65.64,57.85)
  BOTTOM w0.508: 36.8,44.5 37.7,44.5 38.29,43.92 38.29,43.92 38.42,43.79 43.07,43.79 44.01,42.85 44.82,42.85 46.98,40.69 50.71,40.69 51.43,41.4 51.43,42.14 v1(51.6,42.32) ; 32.6,44.38 32.38,44.6 29.71,44.6 29.05,45.26 v1(28.78,45.26) ; v1(33.24,75.24) 33.16,75.31 v1(30.78,75.31) 29.3,75.31 28.77,75.84 25.49,75.84 24.86,75.21 24.86,71.25 24.02,70.41 21.63,70.41 20.72,69.49 v1(18.76,69.49)
+1.05V: length 3.7
  BOTTOM w0.254: PR141.2 45.48,49.12 45.71,49.34 45.71,52.32
  vias: v2(53.89,53.11)
+1.05V_VTT_EC: length 2.5
  TOP w0.102: v1(124.81,40.28) 124.81,40.26 125.01,40.05 U18.12
  BOTTOM w0.102: R372.2 124.8,40.28 v1(124.81,40.28)
+1.8V: length 404.4
  TOP w0.279: v1(60.95,89.38) 60.87,89.31 Q6.5 ; 46.17,74.96 46.42,74.7 Q40.2 ; Q40.5 v1(50.28,74.7) ; v1(56.84,88.72) 56.84,88.98 57.17,89.31 Q6.2
  TOP w0.381: v1(52.95,68.1) R84.1 ; R74.1 53.03,70.84 v1(52.85,70.66) ; 39.59,52.04 39.59,52.65 40.11,53.18 41.12,53.18 R419.1 41.23,53.25 v1(40.22,54.25) ; Q8.2 40.38,75.18 39.41,74.22 v1(39.16,74.22) ; R165.2 130.62,50.88 131.08,50.42 132.25,50.42 v1(132.25,50.42) ; 49.04,54.92 48.8,54.67 46.07,54.67 45.76,54.36 45.76,52.91 Q12.2 ; v3(19.3,40.64) 19.27,40.67 17.26,40.67 12.55,45.38 12.55,53.55 15.39,56.39 19.12,56.39 R186.2 19.5,55.83 19.9,55.42 v1(19.98,55.42) ; R118.1 49.23,64.32 49.28,64.27 R119.1 49.06,63.65 48.91,63.5 v1(48.91,62.97) ; R79.1 v1(50.79,69.14) ; v1(47.41,76.25) 46.78,76.25 46.17,75.64 46.17,74.96 ; v1(92.07,59.11) 91.53,58.57 R147.1 ; R73.1 51.01,70.26 v1(50.51,70.26) ; R80.1 v1(52.95,69.14)
  TOP w0.508: v1(110.07,58.34) 110.3,58.57 110.3,60.34 111.67,61.71 111.67,63.66 109.19,66.14 v1(109.19,66.73) ; v1(48.35,76.84) 52.87,81.36 54.19,81.36 55.95,83.11 55.95,88.34 56.33,88.72 v1(56.84,88.72)
  IN1 w0.381: v1(34.26,57.86) 33.44,58.67 29.2,58.67 25.67,55.14 25.67,53.8 24.68,52.81 24.1,52.81 23.55,53.35 22.05,53.35 v1(19.98,55.42) ; v1(56.84,88.72) 57.5,89.38 v1(60.95,89.38) ; v1(142,50.25) 141.72,50.53 140.3,50.53 137.17,50.53 137.04,50.66 132.49,50.66 v1(132.25,50.42)
  IN1 w0.508: v1(82.54,58.57) v1(83.43,58.57) 85.97,58.57 v1(87.6,60.2) 88.05,60.2 88.46,59.79 91.38,59.79 v1(92.07,59.11)
  IN2 w0.381: v1(158.17,79.15) 154.65,75.63 154.65,70 v1(155.03,69.62)
  IN2 w0.508: 144.36,50.44 144.11,50.7 142.45,50.7 v1(142,50.25) ; 38.36,55.56 35.6,58.32 34.71,58.32 v1(34.26,57.86) ; v1(92.07,59.11) 92.07,58.73 92.7,58.09 93.92,58.09 97.3,54.71 101.11,54.71 101.31,54.51 103.34,54.51 103.5,54.66 109.11,54.66 110.07,55.63 v1(110.07,58.34)
  IN2 w1.016: 35.88,48.13 35.88,42.22 36.72,41.38 36.72,37.64 36.19,37.11 36.19,33.33 35.74,32.88 35.74,31.08 35.12,30.45 35.12,25.27 39.62,20.78 40.78,20.78 43.86,17.7 48.43,17.7 49.98,19.25 v1(50.92,19.25) 52.24,17.93 52.24,17.3 53.43,16.1 55.16,16.1 56.15,17.09 66.95,17.09 70.27,13.77 72.94,13.77 73.97,14.8 75.92,14.8 78.31,12.41 79.49,12.41 80.29,13.22 83.87,13.22 84.4,13.75 v1(88.92,13.75) 90.02,12.65 92.98,12.65 93.59,12.04 106.72,12.04 111.5,16.82 111.5,18.61 113.87,20.98 114.62,20.98 116.62,22.98 116.62,23.67 120.08,27.13 120.84,27.13 123.27,29.55 124.91,31.19 130.04,31.19
  IN2 w1.524: 143.48,54.89 143.48,53.62 144.36,52.73 144.36,49.4 145.76,48.01 145.76,44.98 145.9,44.84 145.9,39.4
  BOTTOM w0.203: 48.91,21.46 49.11,21.46 49.37,21.72 U27.2
  BOTTOM w0.254: Q29.5 87.68,58.43 87.85,58.6 87.85,59.94 v1(87.6,60.2) ; Q29.2 83.58,58.43 v1(83.43,58.57)
  BOTTOM w0.381: v1(158.17,79.15) 159.56,79.15 159.82,78.89 Q19.2 ; R243.2 55.48,72.27 v1(55.72,72.03) ; PQ31.1 18.05,40.08 PC200.2 18.77,41.16 v3(19.3,40.64) ; 44.24,76.53 43.7,77.06 42.64,77.06 39.79,74.22 v1(39.16,74.22) ; R242.1 58.17,73.36 57.96,73.16 R239.1 56.53,73.16 R246.1 55.78,73.11 ; 48.91,21.46 48.31,21.46 C339.2 47.6,20.62 47.92,20.29 50.49,20.29 50.92,19.86 v1(50.92,19.25) ; v1(82.54,58.57) 82.52,58.55 82.52,58.34 81.74,57.57 R321.2 80.86,57.73 80.38,58.22 78.36,58.22 R303.2 ; R260.2 55.79,70.89 v1(55.72,70.82) ; v1(142,50.25) 141.32,50.93 PR135.1 ; v1(60.95,89.38) 61.33,89.38 62.03,90.08 R206.2 ; 55.78,73.11 55.84,73.17 v1(55.84,73.82) ; 55.78,73.11 v1(55.72,73.05) ; R219.1 R218.1 ; v1(52.8,59.61) 52.8,59.2 R317.1 ; v1(88.92,13.75) 88.64,14.03 88.64,19.02 89.12,19.51 R326.2 R28.1 89.14,21.25 89.67,21.78 R15.1 ; v1(34.26,57.86) R307.1
  BOTTOM w0.508: 44.24,76.53 45.23,76.53 45.63,76.94 48.25,76.94 v1(48.35,76.84) ; v1(155.03,69.62) 155.67,68.99 155.67,65.2 149.44,58.98 149.44,57.63 148.81,57 Q30.2 148.12,57.3 146.9,57.3 146.27,56.67 v1(146.07,56.67) ; v1(55.84,73.82) 55.84,74.06 56.23,74.45 R237.1 ; v1(53.08,62.08) R292.1 ; R269.1 53.55,67.2 53.93,67.58 R265.1 53.68,68.1 v1(52.95,68.1) ; v1(60.95,89.38) 60.95,89.04 R218.1 ; R253.1 53.37,70.66 v1(52.85,70.66)
  vias: v1(49.11,58.96) v1(49.55,62.36) v1(50.77,59.65) v1(50.77,57.94) v1(50.97,55.74) v1(109.85,66.73) v1(110.46,66.73)
+1.8V_CARD: length 5.2
  BOTTOM w0.381: PQ30.3 17.39,40.01 17.39,39.17 17.9,38.66 PQ31.3
+1.8V_EMMC: length 4.6
  BOTTOM w0.203: U30.AA3 U30.Y4 U30.AA5
  BOTTOM w0.254: v1(103.4,20.85) U30.W4 U30.Y4 ; v1(105.63,21.64) 105.43,21.64 105.14,21.35 U30.AA3 ; U30.K6 99.74,19.85 99.98,19.61 v1(99.99,19.61) ; v1(105.71,20.35) U30.AA5
  vias: v1(90.49,20.14) v1(91.89,20.78) v1(106.54,21.46) v1(107.74,22.63) v2(111.22,19.63)
+1.8V_S5: length 341.9
  TOP w0.254: R104.2 86.57,66.51 v1(86.63,66.57) 86.63,66.86 R61.2 ; v1(86.07,69.01) 85.61,68.55 R60.2 85.18,68.92 v1(85.18,69.19) ; R81.2 85.46,67.15 v1(85.46,66.98) 85.44,66.95 R88.2 ; v1(84.8,80.32) 84.8,79.63 85.44,78.99 85.44,78.46 86.24,77.66 86.83,77.66 R41.1 R63.2 ; v1(86.45,64.54) 86.86,64.95 87.94,64.95 88.24,65.25 R105.2 ; R550.2 94.82,70.88 v1(93.64,72.06) 93.87,72.06 95.16,73.36 95.16,75.9 95.61,76.34 v1(95.62,76.34) ; R44.1 84.18,82.15 v1(83.89,82.44) ; R305.1 87.32,62.34 86.62,62.34 v1(86.5,62.46)
  TOP w0.381: v1(74.11,78.97) 73.75,78.97 73.08,79.64 R48.2
  IN2 w0.254: v1(51.15,17.6) 51.15,16.64 52.47,15.32 55.52,15.32 56.4,16.21 66.54,16.21 69.84,12.9 74.29,12.9 75.6,11.58 84.85,11.58 86.2,12.93 87.54,12.93 88.64,11.84 92.45,11.84 93.11,11.18 106.95,11.18 112.51,16.74 112.51,17.12 119.07,23.67 119.07,24.59 120.44,25.96 121.08,25.96 125.32,30.2 130.52,30.2 130.9,30.58 134.59,30.58 135.55,29.62 142.98,29.62 146.96,33.6 146.96,34.38 147.82,35.24 147.82,37.44 147.56,37.7 147.56,38.95 147.03,39.47 147.03,44.22
  IN2 w0.381: 147.03,44.22 147.03,45.51 148.81,47.29 148.81,48.59 147.22,50.19 147.22,55.89 147.13,55.98 v1(147.13,56.67)
  IN2 w1.016: 96.84,64.95 97.31,64.48 100.56,64.48 101.32,63.72 101.32,62.68 101.9,62.1 104.33,62.1 105.78,60.66 ; 148.15,66.8 149.17,67.82 149.17,72.19 150.54,73.56 150.54,74.5 149.95,75.08 148.76,75.08 146.98,73.3 144.24,73.3 143.22,72.29 142.33,72.29 141.67,71.63 138.04,71.63 135.14,74.52 129.38,74.52 127.47,76.43 127.47,83 126.23,84.24 125.22,84.24 120.54,88.92 109.18,88.92 107.78,87.52 97.42,87.52 92.68,82.78 90.67,82.78 89.81,81.92 ; 72.13,82.73 66.69,82.73 63.85,79.88 61.03,79.88 60.29,79.15 55.52,79.15 55.24,78.87 55.23,78.87 54.78,78.41 51.55,78.41 v1(51.17,78.03)
  BOTTOM w0.254: Q21.2 Q21.5 94.2,76.23 94.45,76.48 95.48,76.48 v1(95.62,76.34) ; v1(86.45,64.54) 86.73,64.81 87.99,64.81 R280.2 ; v1(51.15,17.6) 51.15,18.69 51.4,18.95 51.4,21.11 51.82,21.53 R513.2 ; v1(86.63,66.57) 86.41,66.79 R85.1 86.41,68.67 v1(86.07,69.01) ; v1(93.64,72.06) 93.92,72.06 94.2,71.78 Q23.5 Q23.2
  BOTTOM w0.381: R251.2 84.37,69.78 84.95,69.19 v1(85.18,69.19) ; R251.2 R259.2 83.99,68.3 83.92,68.23 R267.2 ; R251.2 83.99,69.85 83.59,70.25 R244.2 ; R282.2 86.25,64.37 86.45,64.57 v1(86.45,64.54) ; R289.2 98.78,63.15 98.26,62.64 v1(97.82,62.64) ; v1(86.41,61.32) 86.36,61.27 R295.1 85.44,60.19 R301.1 ; R291.1 85.59,62.28 85.76,62.46 v1(86.5,62.46)
  BOTTOM w0.406: v1(95.62,76.34) 95.66,76.38 96.87,76.38
  BOTTOM w0.508: v1(51.17,78.03) 50.66,78.03 49.06,76.43 49.06,75.57 49.42,75.21 49.42,74.13 R256.2
  BOTTOM w1.016: 105.53,61.27 103.98,62.81 103.98,64.8 103.22,65.56 102,65.56 99.66,67.89 99.66,69.62 98.96,70.32 98.96,72.05 96.87,74.15 96.87,76.9 93,80.77 92.52,80.77
  vias: v1(88.59,81.1) v1(89.73,81.1) v1(106.29,60.55) v1(106.9,60.55) v1(135.98,59.94) v1(135.98,59.31) v1(136.62,59.94) v1(146.96,66.17) v1(146.96,65.56) v2(88.81,82.47)
+1.8VPCU: length 86
  TOP w0.254: v1(114.68,56.56) 115.05,56.56 115.91,57.42 PR26.2
  TOP w0.381: v1(110.2,62.54) 110.2,63.75 106.24,67.72 102.53,67.72 101.87,67.06 97.04,67.06 96.79,67.31 R245.2 96.77,67.94 R268.2
  IN1 w0.254: v1(129.63,43.79) 130.12,43.79 131.31,44.98 133.9,44.98 134.2,45.29 135.47,45.29 135.7,45.06 143.17,45.06 144.64,46.53 v1(147.06,46.53)
  IN2 w0.254: v1(114.68,56.56) 114.88,56.56 116.93,54.51 118.08,54.51 118.53,54.05 118.53,53.57 119.09,53.01 121.02,53.01 121.4,53.38 121.4,53.81 122,54.41 125.31,54.41 126.08,53.65 126.08,52.78 128.49,50.37 128.49,48.9 127.78,48.18 127.78,44.83 128.82,43.79 v1(129.63,43.79)
  BOTTOM w0.203: v1(114.68,56.56) 114.55,56.69 112.89,56.69 109.59,53.39 107.26,53.39 105.73,51.87 105.73,48.88 v1(105.29,48.44)
  BOTTOM w0.254: 142.31,44.81 142.31,45.24 142.71,45.64 146.17,45.64 v1(147.06,46.53)
  vias: v1(108.04,57.18) v1(108.04,56.54) v1(108.04,55.91) v1(108.04,55.27) v2(107.64,54.56)
+1.8VREF: length 5
  TOP w0.203: v1(30.83,36.93) 30.83,36.73 30.73,36.63 PU9.6
  TOP w0.254: v1(30.83,36.93) 30.73,37.03 30.34,37.03 30.04,36.73 28.6,36.73 PC59.1
  BOTTOM w0.254: PR158.1 29.37,36.68 30.16,36.68 v1(30.22,36.75) 30.41,36.93 v1(30.83,36.93)
+1.35V: length 82.7
  TOP w0.254: 68.37,65.05 67.61,64.29 U12.AJ19 ; 68.37,65.05 U12.AG18 ; 68.37,65.05 v1(67.99,65.43)
  TOP w0.381: U12.BD1 60.27,73.35 59.49,74.13 59.49,75.6 59.78,75.9 59.78,76.6 C42.2 C43.2 C44.1 61.69,76 62.02,75.67 v1(62.02,73.89)
  IN2 w0.508: v1(67.99,65.43) 67.99,65.83 66.74,67.08 66.36,67.08 65.95,67.49 ; v1(43.48,47.27) 43.35,47.4 43.35,51.33 47.11,55.09 47.11,57.1 46.4,57.81 46.4,59.51 46.55,59.66 46.55,59.69 46.91,60.05 46.93,60.05 47.36,60.48 49.16,60.48 50.69,62 50.69,63.17 52.32,64.8 52.32,64.92 52.34,64.95 52.34,65.66 53.94,67.26 53.94,68.55 54.63,69.24 56.71,69.24
  BOTTOM w0.508: PR127.1 29.58,52.2 32.71,52.2 33.37,52.86 36.74,52.86 37.08,52.53 37.08,48.03 37.99,47.12 37.99,46.36 38.24,46.1 38.24,44.82 38.67,44.4 43.32,44.4 44.26,43.46 45.28,43.46 47.44,41.3 50.46,41.3 50.61,41.45 50.61,44.2 PQ28.1 ; v1(43.48,47.27) 44.25,46.5 47.78,46.5 48.15,46.13
  vias: v2(54.35,50.77)
+1.35VSUS: length 166.7
  TOP w0.254: U12.H46 78.36,50.88 v1(78.36,50.87) ; U12.C51 80.2,49.34 v1(80.25,49.39) ; U12.AK38 66.81,55.17 v1(66.45,54.8) 66.05,55.19 U12.AM38 ; v1(59.85,51.74) 59.84,51.74 U12.BF44 ; U12.M42 75.73,53.04 75.53,53.04 v1(75.4,53.16) 75.67,53.43 75.72,53.43 U12.M41 ; U12.D44 79.73,51.74 v1(79.59,51.6) ; v1(58.89,49.4) 58.92,49.38 U12.BG51 ; v1(60.74,49.71) 60.52,49.93 U12.BD49 ; v1(60.51,51.74) 60.88,51.38 U12.BB46 ; U12.V38 73.09,55.14 72.56,54.61 v1(72.55,54.61) 72.3,54.86 U12.Y38 ; U12.F49 78.96,49.84 79.33,49.84 v1(79.39,49.77) ; U12.BJ48 56.95,50.21 v1(56.4,50.75) ; U12.F53 78.85,47.12 v1(78.78,47.04) ; U12.BD53 60.11,47.84 U12.BD52 60.11,48.32 v1(60.74,48.95)
  TOP w0.305: 80.52,24.91 80.96,25.35 JDIM6.82 ; U12.AV41 63.21,53.59 v1(62.74,53.12) 62.87,53.12 63.11,52.88 U12.AV42 ; v1(84.56,46.79) 84.56,48.07 82.59,50.04 81.82,50.04 81.7,50.17 81.41,50.17 U12.A48 ; U12.F53 78.85,48.08 79,48.24 U12.F52
  TOP w0.356: JDIM6.93 77.66,33.57 v1(78.03,33.19) ; v1(75.34,24.91) 75.35,24.91 75.56,25.11 JDIM6.100 ; JDIM6.94 77.36,25.18 v1(77.63,24.91) ; v1(79.66,33.05) 79.46,33.25 JDIM6.87 ; v1(75.62,33.17) 75.86,33.4 JDIM6.99 ; JDIM6.123 68.66,35.73 69.04,36.11 v1(69.55,36.11) 70.21,36.11 70.46,35.87 JDIM6.117 ; JDIM6.75 83.06,33.31 v1(82.88,33.14) ; JDIM6.88 79.16,25.3 79.54,24.91 ; v1(69.04,24.78) 68.97,24.78 68.36,25.4 68.36,26.4 JDIM6.124 ; v1(73.37,28.98) 73.89,28.47 73.89,27.45 73.76,27.32 JDIM6.106 ; JDIM6.105 74.06,35.77 73.79,36.04 72.71,36.04 72.26,35.59 JDIM6.111 72.26,33.3 v1(72.39,33.17) ; v1(72.06,27.83) 71.96,27.72 JDIM6.112 ; v1(83.09,28.34) 83.09,27.82 82.76,27.49 JDIM6.76 ; v1(69.72,24.78) 70.16,25.22 JDIM6.118 ; JDIM6.81 81.26,33.53 v1(81.72,33.06)
  TOP w0.381: 80.52,24.91 v1(80.55,24.91)
  IN2 w0.254: v3(30.57,18.69) 30.26,19.01 29.49,19.01 26.41,22.1 26.41,33.88 26.94,34.42 28.57,34.42 v1(29.23,33.76)
  IN2 w0.508: v1(49.8,43.36) 50.54,43.36 51.1,43.92 53.11,43.92 55.03,45.85 56.15,45.85 58.44,48.13 58.44,48.67
  IN2 w1.016: 38.07,14.38 31.31,14.38 25.47,20.22 25.47,34.7 26.41,35.64 26.41,36.6 28.44,38.63 30.6,38.63 30.75,38.79 32.2,38.79 32.86,38.13 33.75,38.13
  BOTTOM w0.381: 89.62,55.09 89.62,55.38 R323.2
  BOTTOM w0.508: 87.85,53.11 99.79,41.17 100.17,41.17 103.08,38.26 R388.1 ; v1(66.45,54.8) 65.94,54.8 65.54,54.4 62.11,54.4 61.88,54.17 R334.2 ; R328.2 89.62,55.09 89.31,55.4 88.68,55.4 87.21,53.93 87.21,53.49 ; v1(29.23,33.76) 28.89,34.1 PR161.2 ; v1(49.8,43.36) 49.75,43.31 PQ28.3 49.5,42.06 47.69,42.06 PC169.2
  vias: v1(34.43,39.42) v1(35.09,39.42) v1(84.95,39.95) v1(84.95,39.34) v1(84.95,38.74) v2(69.64,44.66) v2(84.27,50.73) v3(30.57,17.93) v3(30.57,17.17) v3(31.46,18.69) v3(31.46,17.93) v3(31.46,17.17) v3(38.47,12.98) v3(39.21,13.36) v3(39.21,12.6) v3(39.97,14.12) v3(39.97,13.36) v3(39.97,12.6) v3(40.73,14.12) v3(40.73,13.36) v3(40.73,12.6) v3(69.16,23.77) v3(69.92,23.77) v3(70.68,23.77) v3(71.44,23.77) v3(72.2,23.77) v3(76.29,24.23) v3(77.05,24.26) v3(77.82,24.23) v3(78.58,24.23) v3(79.34,24.23)
+1.35VSUS_VSM: length 8.5
  TOP w0.254: U12.AD38 U12.AF38 v1(68.79,54.82)
  BOTTOM w0.508: R334.1 63.07,53.77 63.41,53.43 C270.1 64.21,53.76 65.21,53.76 65.44,53.53 66.04,53.53 66.79,54.28 v1(66.86,54.28) 66.94,54.2 67.91,54.2 C267.1 68.31,54.27 68.79,54.76 v1(68.79,54.82)
+1.35VSX: length 43.7
  TOP w0.203: U12.AA25 71.88,61.62 71.92,61.62 v1(71.92,61.62)
  TOP w0.254: U12.V36 73.11,55.95 73.48,56.31 v1(73.48,56.3) 73.48,56.31 73.72,56.31 73.87,56.16 U12.U36 ; U12.AF19 69.15,64.29 v1(68.78,64.67) 68.4,64.29 U12.AG19 ; v1(67.99,58.6) 68.36,58.22 U12.AG32 ; U12.AD36 v1(70.35,55.55)
  IN1 w0.508: v1(73.48,56.3) 73.48,56.3 73.46,56.31 73.02,56.31 72.4,55.69 70.49,55.69 v1(70.35,55.55) 68.49,55.55 67.99,56.06 v1(67.99,58.6)
  IN2 w0.508: v1(68.78,64.67) 69.28,64.67 70.01,63.93 70.6,63.93 71.08,63.45 71.08,62.05 71.52,61.62 v1(71.92,61.62) 71.14,60.83 70.19,60.83 69.56,60.2 69.56,58.39 69.13,57.96 68.47,57.96 67.99,58.45 v1(67.99,58.6) 67.83,58.45 66.92,58.45 66.39,57.91 66.39,56.92 65.7,56.24 59.48,56.24 59.14,55.9 59.14,53.71 58.33,52.91 57.3,52.91 57.24,52.96 v1(57.24,52.98)
  BOTTOM w0.381: C263.1 72.79,56.31 73.47,56.31 73.48,56.31 v1(73.48,56.3) 73.48,56.31 73.81,56.31 C257.2 ; C264.1 69.51,55.55 v1(70.35,55.55)
  BOTTOM w0.508: C219.1 71.3,62.15 71.8,61.65 71.9,61.65 v1(71.92,61.62) ; C191.1 68.62,64.82 v1(68.78,64.67)
  vias: v2(56.58,46.13)
+3V: length 536.5
  TOP w0.203: C61.1 17.12,71.87 17.63,72.37 U9.36
  TOP w0.254: v1(49.8,39.47) 49.72,39.4 49.72,38.29 R178.1
  TOP w0.279: v1(40.35,52.63) 40.71,52.27 40.99,52.27 41.37,51.89 U24.6 ; v1(38.24,51.71) 38.07,51.54 38.07,43.33 v1(38.04,43.31)
  TOP w0.356: v1(45.86,33.14) 45.86,33.15 JDIM6.199
  TOP w0.381: U7.1 61.27,79.7 60.67,80.29 v1(60.67,81.31) ; R31.1 45.34,74.74 R67.2
  TOP w0.508: v1(75.25,83.85) 73.45,82.04 72.64,82.04 72.37,81.78 L1.2 ; R71.1 38.06,70.99 v1(38.27,71.2) ; v1(29.76,71.32) 29.83,71.32 R101.2 ; R67.2 45.43,75.67 45.3,75.8 R62.2 45.43,76.69 C38.1 46.13,78.38 v1(46.42,78.66) ; v1(37.33,63.02) 36.74,63.02 R521.2 35.94,63.49 35.45,63.98 34.61,63.98 33.62,62.99 R122.2 33.1,62.52 32.93,62.36 31.82,62.36 31.33,62.84 v1(31.33,64.21) ; v1(18.15,71.78) C61.1 ; v1(43.45,55.68) 43.48,55.65 45.13,55.65 45.25,55.78 46.98,55.78 47.45,56.25 R153.2 47.45,59.14 v1(47.16,59.44) ; C89.1 v1(26.39,61.92)
  IN1 w0.279: v1(40.35,52.63) 39.44,51.71 v1(38.24,51.71)
  IN1 w0.508: v1(156.25,80.39) 156.25,78.33 154.02,76.1 v1(150.77,76.1) ; v1(95.91,75.79) 97.13,75.79 99.28,73.64 99.28,70.71 99.86,70.13 101.95,70.13 102.77,69.3 111.7,69.3 112.53,68.48 116.42,68.48 119.85,65.05 v1(120.49,65.05) ; v1(129.28,39.73) 129.79,39.73 130.45,39.07 132.17,39.07 132.32,39.22 v1(133.11,39.22) ; v1(26.84,70.71) 26.38,70.26 25.37,70.26 22.32,73.3 20.11,73.3 18.58,71.78 v1(18.15,71.78) ; v1(98.83,53.39) 98.83,54.88 97.53,56.18 97.53,58.39 96.31,59.61 v1(96.23,59.61) ; v1(43.45,55.68) 43.53,55.75 43.53,58.8 39.31,63.02 v1(37.33,63.02) ; 24.63,42.16 26.66,42.16 28.82,44.32 37.96,44.32 38.27,44.02 38.27,43.54 v1(38.04,43.31)
  IN1 w1.016: 150.59,53.49 148.61,53.49 146.73,51.61 144.19,51.61 143.84,51.26 142.7,51.26 142.43,51.53 137.59,51.53 137.46,51.66 131.81,51.66 131.12,50.97 127.21,50.97 126.91,50.67
  IN2 w0.381: v1(49.8,39.47) 48.84,40.44 47.54,40.44 46.9,39.8 46.9,38.2 46.37,37.67 46.37,34.01 45.86,33.5 v1(45.86,33.14)
  IN2 w0.508: 124.55,50.57 124.91,50.22 124.91,46.79 126.14,45.56 126.14,42.33 128.11,40.36 128.64,40.36 v1(129.28,39.73) ; v1(43.45,55.68) 43.45,55.27 42.71,54.53 42.26,54.53 v1(40.35,52.63)
  IN2 w0.635: v1(72.94,85.27) 70.86,85.27 69.36,83.77 65.78,83.77 65.02,83.01 62.45,83.01
  IN2 w1.016: 47.29,79.63 54.37,79.63 55.16,80.42 59.78,80.42 v1(60.67,81.31) 61.18,81.81 61.87,81.81 ; 157.47,54.2 156.2,54.2 152.77,57.63 152.77,61.39 156.29,64.91 156.55,64.91 159.2,67.56 159.2,71.86 163.08,75.74 ; 99.94,52.15 100.63,51.46 100.63,50.06 105.27,45.42 114.9,45.42 118,48.51 120.84,48.51 122.9,50.57 124.55,50.57 ; 24.45,57.76 23.79,57.1 22.57,57.1 21.03,55.56 21.03,54.85 18.1,51.92 18.1,47.04 17.54,46.48 ; 31.13,71.88 36.05,76.8
  BOTTOM w0.305: R304.2 R300.1 90.55,60.48 95.67,60.48 96.23,59.92 v1(96.23,59.61)
  BOTTOM w0.381: 52.29,62.03 52.06,61.8 49.29,61.8 48.06,60.57 48.06,60.34 v1(47.16,59.44) ; 52.29,62.03 52.29,62.15 53.92,63.78 54.52,63.78 R167.2 ; 52.29,62.03 52.8,61.52 53.13,61.52 53.79,60.86 53.79,60.3 R302.2 ; U21.4 26.63,59.53 26.99,59.89 26.99,61.39 v1(26.86,61.52) 26.48,61.9 26.41,61.9 v1(26.39,61.92)
  BOTTOM w0.508: v1(31.33,64.21) 31.43,64.31 R275.2 ; Q15.2 71.95,87.53 72.23,87.25 73.12,87.25 ; U21.6 25.83,61.43 26.32,61.92 v1(26.39,61.92) ; 73.12,87.25 72.97,87.1 72.97,85.29 v1(72.94,85.27) 73.17,85.04 74.06,85.04 v1(75.25,83.85) ; 73.12,87.25 73.78,87.91 73.78,88.39 72.89,89.28 72.89,90.04 73.35,90.5 74.77,90.5 75.89,89.38 75.89,87.07 77.16,85.8 77.56,85.8 83.22,80.15 R230.2 ; v1(162.36,82.58) 162.36,82.26 161.91,81.8 R223.2 R222.2 157.67,81.8 v1(156.25,80.39) ; v1(49.8,39.47) 49.22,40.06 46.55,40.06 45.61,41 45.61,41.17 44.59,42.19 43.27,42.19 42.28,43.18 38.17,43.18 v1(38.04,43.31) ; R385.1 134.33,36.61 133.6,37.34 133.37,37.34 133.09,37.62 133.09,39.19 v1(133.11,39.22) ; v1(120.49,65.05) 120.49,62.51 ; v1(150.77,76.1) 150.21,76.66 147.67,76.66 146.7,75.69 145.96,75.69 139.54,69.27 PR90.2 ; v1(164.01,77.11) 163.64,77.49 R231.1 R232.2 ; v1(16.88,36.42) 17.31,35.99 17.31,35.77 PC204.2 17.67,35.42 17.67,33.78 PQ29.3 ; v1(95.91,75.79) 95.98,75.73 R235.2 ; 119.98,41.71 121.94,41.71 122.34,41.3 R370.2 ; 117.42,30.48 120.59,30.48 121.12,31.01 121.12,32.36 121.63,32.87 123.17,32.87 R395.2 ; v1(38.27,71.2) 38.04,70.96 34.18,70.96 33.82,71.32 v1(29.76,71.32) 29.73,71.35 27.47,71.35 v1(26.84,70.71) ; PR175.1 75.65,14.76 75.02,14.76 73.84,13.58 73.84,7.15 72.46,5.77 72.46,3.58
  BOTTOM w3.048: 117.24,19.1 117.24,30.3 117.59,30.66 117.59,33.2 119.98,35.59 119.98,41.71 119.68,42.01 119.68,46.89 ; 113.12,12.9 97.15,12.9 87.82,3.58 54.32,3.58
  vias: v1(16.58,26.11) v1(17.09,25.6) v1(17.59,25.1) v1(18.1,24.59) v1(18.61,24.08) v1(23.66,19.48) v1(23.69,18.75) v1(23.69,17.98) v1(23.69,17.35) v1(23.69,16.71) v1(23.94,43.31) v1(24.3,42.8) v1(62.73,82.55) v1(98.79,52.55) v1(125.44,50.47) v1(126.05,50.47) v1(151.12,54.28) v1(151.68,53.72) v1(161.23,53.47) v1(161.23,52.81) v1(161.26,52.15) v1(161.26,51.51) v1(164.68,89.28) v1(164.79,87.78) v2(50.36,6.15) v3(51.4,7.14) v3(51.4,6.38) v3(52.16,7.14) v3(52.16,6.38) v3(52.92,7.14) v3(52.92,6.38)
+3V3_SD_SW:
  vias: v2(21.86,42.67)
+3V_EMMC:
  vias: v1(92.9,19) v1(93.64,18.97) v1(94.3,18.95) v1(100.99,19.81) v1(102.28,18.67) v1(105.54,18.94) v1(105.63,17.96) v2(111.34,15.57)
+3V_HDD:
  vias: v2(163.77,36.35)
+3V_LDO: length 1.8
  TOP w0.203: PU8.6 116.18,45.76
  vias: v1(116.33,45.37)
+3V_MINI1_VDD: length 8.7
  TOP w0.254: v1(163.88,87.27) 163.65,87.27 163.63,87.3 CN10.24
  TOP w0.508: v1(165.79,75.97) 164.9,75.97 164.23,75.3 CN10.2
  BOTTOM w0.254: v1(164.26,97.18) 164,97.18 R203.2
  BOTTOM w0.508: v1(163.88,87.27) 164.01,87.27 165.18,86.11 v1(165.78,86.11)
  vias: v1(162.23,99.72) v1(162.87,99.72) v1(166.17,92.74) v1(166.8,92.99)
+3V_RTC: length 139.7
  IN2 w0.508: v1(86.35,63.65) 87.37,62.64 89.25,62.64 91.41,60.48 91.41,58.27 92.24,57.43 93.3,57.43 93.96,56.76 93.96,53.92 103.98,43.9 103.98,41.54 110.05,35.47 110.05,32.7 111.1,31.65 111.1,28.05 104.89,21.84 104.89,18.89 103.62,17.63 97.6,17.63 v1(96.28,18.95) ; v1(90.8,11.13) 86.99,11.13 86.1,10.24 74.82,10.24 73.57,11.48 69.02,11.48 67.04,13.46 60.35,13.46 59.24,12.35 48.89,12.35 48.71,12.17 45.61,12.17 43.04,9.6 42.13,9.6 40.89,8.36 37.56,8.36 37.05,8.86 v1(37.05,9.17)
  BOTTOM w0.508: D36.3 34.29,10.33 v2(34.54,10.57) ; v1(90.8,11.13) 90.8,12.42 96.28,17.91 v1(96.28,18.95) ; v1(86.35,63.65) 85.96,63.65 R288.2
+3V_S5: length 437.8
  TOP w0.508: v1(50.36,82.12) v2(49.08,80.84) 47.82,79.58 v1(47.82,78.66) ; R551.2 94.07,68.71 v1(93.23,67.87) ; v1(41.16,64.92) 41.16,64.82 41.93,64.06 41.93,63.07 41.67,62.81 41.67,55.02 42.64,54.05 v1(42.64,51.74) ; v1(37.76,39.42) 37.98,39.2 R528.1 ; v1(142.33,54.25) 143.06,54.25 143.37,53.94 147.57,53.94 148.26,54.64 v1(149.06,54.64) ; v1(156.1,74.52) 155.69,74.93 155.69,76.3 156.87,77.48 156.87,81.14 157.51,81.77 v1(157.51,84.48) 158.41,84.48 158.87,84.02 v1(161.69,84.02) ; R159.2 98.59,55.02 98.01,54.43 v1(95.72,54.43) ; v1(26.74,43.11) 27.02,43.11 28.57,44.65 37.05,44.65 37.57,44.14 v1(37.57,43.71) ; v1(125.67,72.95) 125.67,72.83 125.67,72.5 127.83,70.34 127.83,70.04 128.88,68.99 128.88,67.33 129.58,66.62 129.58,62.94 129.99,62.54 129.99,61.52 130.62,60.89 130.62,60.27 129.58,59.23 125,59.23 ; v1(109.19,53.95) 109.19,54.92 108.7,55.4 108.7,58.16 109.67,59.13 109.67,60.62 v1(110.82,61.77)
  IN1 w0.508: v1(92.27,18.24) 91.63,18.87 v1(89.65,18.87) 87.82,20.7 77.56,20.7 76.52,21.74 59.48,21.74 v1(58.26,20.52) ; v1(74.42,70.44) 74.41,70.44 74.41,71.17 76.47,73.23 77.88,73.23 78.3,73.64 78.3,75.03 79.14,75.87 79.82,75.87 81.4,77.44 81.78,77.44 v1(82.03,77.19) ; v1(149.06,54.64) 150.84,56.41 150.84,62.26 153,64.42 v1(153,64.8)
  IN1 w1.016: 121.5,52.53 121.5,52.12 122.13,51.5 123.42,51.5 124.96,53.04 129.42,53.04 130.13,53.74 132.58,53.74 133.31,54.48 138.8,54.48
  IN2 w0.508: v1(76.45,78.11) 76.24,78.31 72.43,78.31 71.97,78.77 71.97,81.33 71.57,81.74 67.17,81.74 64.46,79.02 61.56,79.02 61.18,78.64 61.18,78 60.82,77.65 58.16,77.65 57.01,76.51 v1(55.59,76.51) 55.26,76.51 55.08,76.68 51.2,76.68 49.22,78.66 v1(47.82,78.66) 47.82,78.54 45.98,76.7 45.98,73.19 45.41,72.62 45.41,71.3 44.47,70.36 44.47,67.69 42.66,65.89 42.66,64.82 42.18,64.34 41.52,64.34 41.16,64.69 v1(41.16,64.92) ; 112.29,32.23 112.82,32.23 114.48,33.9 116.75,33.9 118.04,35.19 120.7,35.19 121.53,36.02 122.44,36.02 123.41,36.99 123.41,37.52 123.12,37.82 v1(122.61,37.82) ; 112.29,32.23 112.29,27.14 108.88,23.74 108.88,21.75 106.79,19.66 106.79,18.03 105.27,16.51 96.99,16.51 95.27,18.24 v1(92.27,18.24) ; 112.29,32.23 111.02,33.5 111.02,36.95 108.04,39.92 108.04,40.79 106.65,42.19 106.65,43.18 105.9,43.93 105.24,43.93 99.41,49.77 99.41,50.84 99.11,51.14 97.87,51.14 95.72,53.29 v1(95.72,54.43) 96.41,54.43 96.74,54.1 100.85,54.1 101.13,53.82 103.52,53.82 103.65,53.95 v1(109.19,53.95) ; v1(40.35,51.92) 40.35,47.88 37.89,45.42 37.89,44.03 v1(37.57,43.71) 37.15,43.71 36.9,43.46 36.9,42.62 37.76,41.76 v1(37.76,39.42) ; v1(156.1,74.52) 155.57,73.99 155.57,70.74 156.19,70.12 156.19,69.43 154.91,68.15 154.91,66.7 v1(153,64.8) ; v1(24.12,38) 24.12,37.59 24.45,37.27 25.5,37.27 26.03,37.79 26.03,41.42 26.74,42.14 v1(26.74,43.11) ; 93.36,70.05 92.7,70.71 92.7,73.23 92.16,73.77 92.16,75.33 92.78,75.95 v1(92.93,75.95)
  BOTTOM w0.254: Q16.5 161.56,84.33 161.69,84.19 v1(161.69,84.02)
  BOTTOM w0.381: 52.34,72.21 52.62,71.93 U26.5
  BOTTOM w0.508: v1(40.35,51.92) 40.53,51.74 v1(42.64,51.74) 43.17,51.21 PR132.1 ; v1(125.67,72.95) 125.68,72.96 PR79.1 ; v1(74.42,70.44) 74.42,70.41 74.76,70.06 R257.1 ; R411.1 57.99,20.25 v1(58.26,20.52) ; 52.34,72.21 52.34,73.28 52.8,73.74 54.63,73.74 55.21,74.32 55.21,76.12 v1(55.59,76.51) ; Q25.2 152.62,65.18 v1(153,64.8) ; v1(93.23,67.87) 93.23,67.68 93.25,67.68 R266.1 ; v1(92.93,75.95) 91.66,77.22 85.59,77.22 85.36,76.99 82.24,76.99 v1(82.03,77.19) 81.78,77.45 76.83,77.45 76.45,77.83 v1(76.45,78.11) ; PR112.1 122.93,60.24 v1(122.52,60.66) ; R338.1 95.72,53.12 v1(95.72,54.43) 95.62,54.53 R364.1 ; PC170.1 25.62,42.06 25.86,42.31 PC168.2 26.37,42.31 26.74,42.67 v1(26.74,43.11) PU14.3 ; PR183.1 80.69,10 80.69,9.21 80.97,8.93 80.97,6.73 81.63,6.07 87.32,6.07 89.83,8.58 89.83,13.92 89.25,14.5 89.25,18.47 v1(89.65,18.87) ; v1(24.12,38) 24.12,38.33 23.85,38.6 R162.1 ; v1(50.36,82.12) 51.17,81.31 56.58,81.31 57,81.72 R198.2 ; R382.2 123.04,38.25 v1(122.61,37.82) ; Q20.2 158.65,74.57 158.6,74.52 v1(156.1,74.52) ; R241.1 96.88,72.05 97.45,71.48 97.45,69.85 v1(97.22,69.62)
  vias: v1(119.63,53.62) v1(120.23,53.62) v1(140.86,57.35) v1(141.44,57.12) v3(116.28,59.62) v3(117.01,59.58)
+3V_USB: length 26.4
  TOP w0.279: v1(104.83,56.22) 104.69,56.08 104.28,56.08 104.12,56.24 U13.14
  TOP w0.305: U13.21 105.51,60.94 105.83,61.27 ; U13.28 101.12,62.58 100.63,63.07 ; v1(101.41,55.88) 101.62,56.09 U13.9 ; U13.5 99.29,58.94 98.52,58.17 v1(98.39,58.17)
  TOP w0.381: C90.2 C92.2 98.29,58.06 v1(98.39,58.17) ; v1(109.06,60.5) 109.03,60.53 v2(109.03,62.18) 108.45,62.76 C87.2 ; 105.83,61.27 105.83,61.67 106.35,62.19 107.47,62.19 107.92,62.65 C87.2 ; R113.2 103.81,65.74 103.22,65.15 R112.2 103.12,65.06 102.62,64.55 R367.2 102.06,64.41 101.16,64.41 100.28,63.54 v1(100.28,63.49) 100.28,63.42 100.63,63.07 ; v1(108.42,60.4) 108.42,60.97 R133.2 107.86,61 107.86,59.98 108.27,59.57 R144.2 ; C87.2 R115.2
  BOTTOM w0.381: v1(106.87,59.57) 106.77,59.47 R306.2 ; C258.2 104.51,56.54 v1(104.83,56.22)
  vias: v1(99.66,63.5) v1(100.83,55.65)
+3VPCU: length 344.7
  TOP w0.381: v1(76.42,94.51) 76,94.93 LED7.2 ; R35.2 26,80.02 26,80.16 v1(25.75,80.42)
  TOP w0.508: LED7.1 76.9,94.99 v1(76.42,94.51) ; v1(131.92,39.68) 131.92,40.8 v1(132.59,41.47) 133.86,42.74 134.34,42.74 135.1,41.99 v1(137.58,41.99) ; PR36.1 v1(115.41,50.57) ; PC198.1 36.73,43.99 29.28,43.99 28.69,43.41 PQ38.3 28.21,42.47 26.48,42.47 26.1,42.85 v1(26.1,43.79) ; v1(147.23,36.08) 147.23,36.6 R386.2 ; v1(145.64,37.97) 145.66,38 145.67,38 145.68,38 R383.2
  TOP w0.635: v1(137.58,41.99) 137.74,41.83 137.74,40.28 136.59,39.14 135.78,39.14 135.47,38.84 v1(135.47,38.25) 136.91,38.25 136.92,38.24 137.66,38.24 138.1,38.68 138.1,39.27 138.5,39.66 139.15,39.66 140.22,38.58 140.22,36.42
  TOP w0.889: 138.68,34.29 138.68,32.9 139.27,32.31 140.38,32.31 141.28,31.41 144.62,31.41 146.69,33.48 146.93,33.48
  TOP w1.016: 118.3,57.66 117.31,58.65 115.46,58.65 114.27,59.84 113.26,59.84 PR23.2
  IN1 w0.508: v1(76.42,94.51) 75.68,93.78 75.68,89.89 74.18,88.39 72.51,88.39 71.52,87.4 57.8,87.4 v1(52.67,82.27) 51.58,81.18 37.63,81.18 v1(35.5,79.05) ; v1(19.93,45.64) 21.1,45.64 22.52,44.22 24.63,44.22 25.09,43.76 26.08,43.76 v1(26.1,43.79)
  IN1 w1.016: 67.3,16.38 78.38,16.38 79.01,15.75 82.29,15.75 83.4,14.63 89.3,14.63 90.52,13.41 107.13,13.41 110.33,16.62 110.33,20.24 115.36,25.26 115.36,30.45 ; 138.4,34.32 137.81,33.73 133.74,33.73 133.28,34.19 128.69,34.19 ; 48.33,15.52 49.22,15.52 50.13,14.61 55.31,14.61 56.02,13.89 57.32,13.89 57.98,14.55 60.32,14.55 ; 128.69,34.19 v1(128.69,34.19) ; 128.69,34.19 127.04,32.53 124.37,32.53 122.98,31.14 121.02,31.14
  IN2 w0.508: v3(34.13,73.03) 33.29,72.19 33.29,67.89 33.95,67.24 33.95,63.37 33.24,62.66 33.24,61.33 29.91,58 29.49,58 26.66,55.17 26.66,53.87 25.22,52.43 21.38,52.43 19.37,50.42 19.37,46.05 19.78,45.64 v1(19.93,45.64) 21.66,43.92 21.66,40.23 22.32,39.57 22.32,37.36 22.72,36.96 22.72,13.26 24.22,11.76 28.39,11.76 29.28,10.87 v1(30.37,10.87) v1(31,10.87) ; v1(137.58,41.99) 137.61,42.01 137.61,47.24 v1(137.46,47.4) ; v1(128.69,34.19) 125.77,34.19 125.35,34.61 124.6,34.61 123.34,33.35 122.77,33.35 v1(122.65,33.48)
  BOTTOM w0.254: RP6.5 135.6,38.38 v1(135.47,38.25)
  BOTTOM w0.305: 140.05,36.09 139.79,35.84 RP6.10
  BOTTOM w0.508: R391.2 123.28,34.11 v1(122.65,33.48) ; v1(132.59,41.47) 132.59,42.13 131.92,42.8 R359.1 ; R197.2 v1(52.67,82.27) ; v1(68.01,17.42) 68.01,16.81 PR174.2 ; v1(137.46,47.4) 137.46,48.72 136.92,49.25 136.92,50.5 137.24,50.82 R345.2 ; R371.1 130.57,40.26 131.16,39.68 v1(131.92,39.68) ; R536.2 39.66,15.5 40.09,15.07 41.44,15.07 42.05,14.45 43.48,14.45 44.87,13.06 v1(44.87,12.98) ; v3(34.13,73.03) 34.13,77.09 35.53,78.49 35.53,79.02 v1(35.5,79.05) 35.3,79.25 34.43,79.25 33.72,78.54 31.33,78.54 30.42,77.62 29.15,77.62 29.02,77.75 27.63,77.75 26.08,79.3 26.08,80.09 v1(25.75,80.42) ; v1(137.58,41.99) 137.76,42.16 R361.2 ; 147.03,43.03 146.83,42.82 R366.2 ; R522.1 139.64,38.99 139.95,38.68
  BOTTOM w1.016: 114.81,32.24 114.81,33.72 114,34.53
  vias: v1(47.16,14.81) v1(47.87,14.76) v1(115,32.11) v1(115.61,32.13) v1(117.28,56.81) v1(117.28,56.2) v1(117.89,56.82) v1(117.89,56.21) v1(118.5,56.82) v1(118.5,56.21) v1(140.05,36.58) v1(140.68,36.6) v1(147.59,33.2) v1(147.9,33.76) v2(114.04,46.71) v3(114.65,35.46) v3(115,36.18) v3(115.36,35.46) v3(115.72,36.18) v3(116.08,35.46) v3(116.45,36.18) v3(116.8,35.46) v3(117.2,36.18)
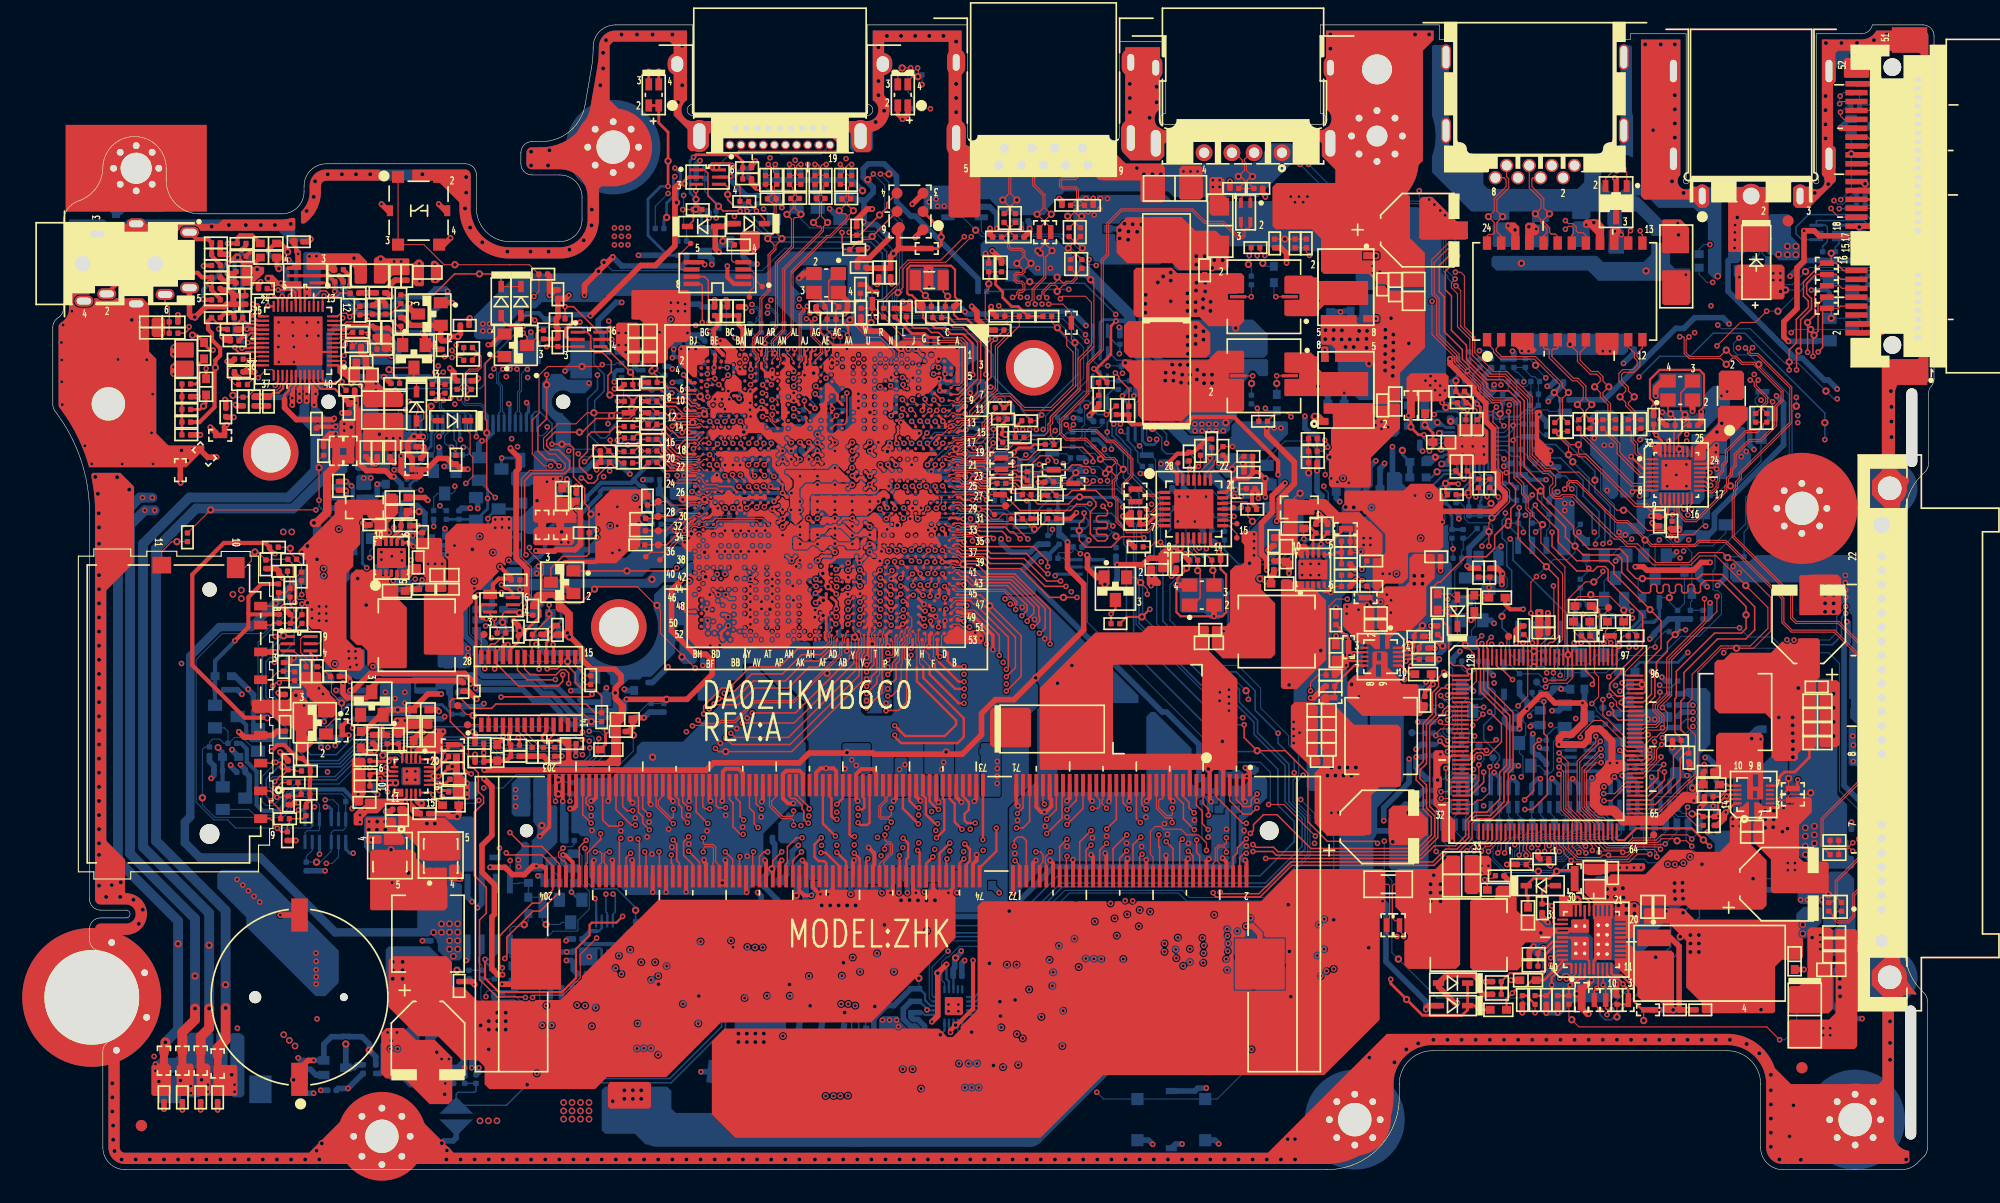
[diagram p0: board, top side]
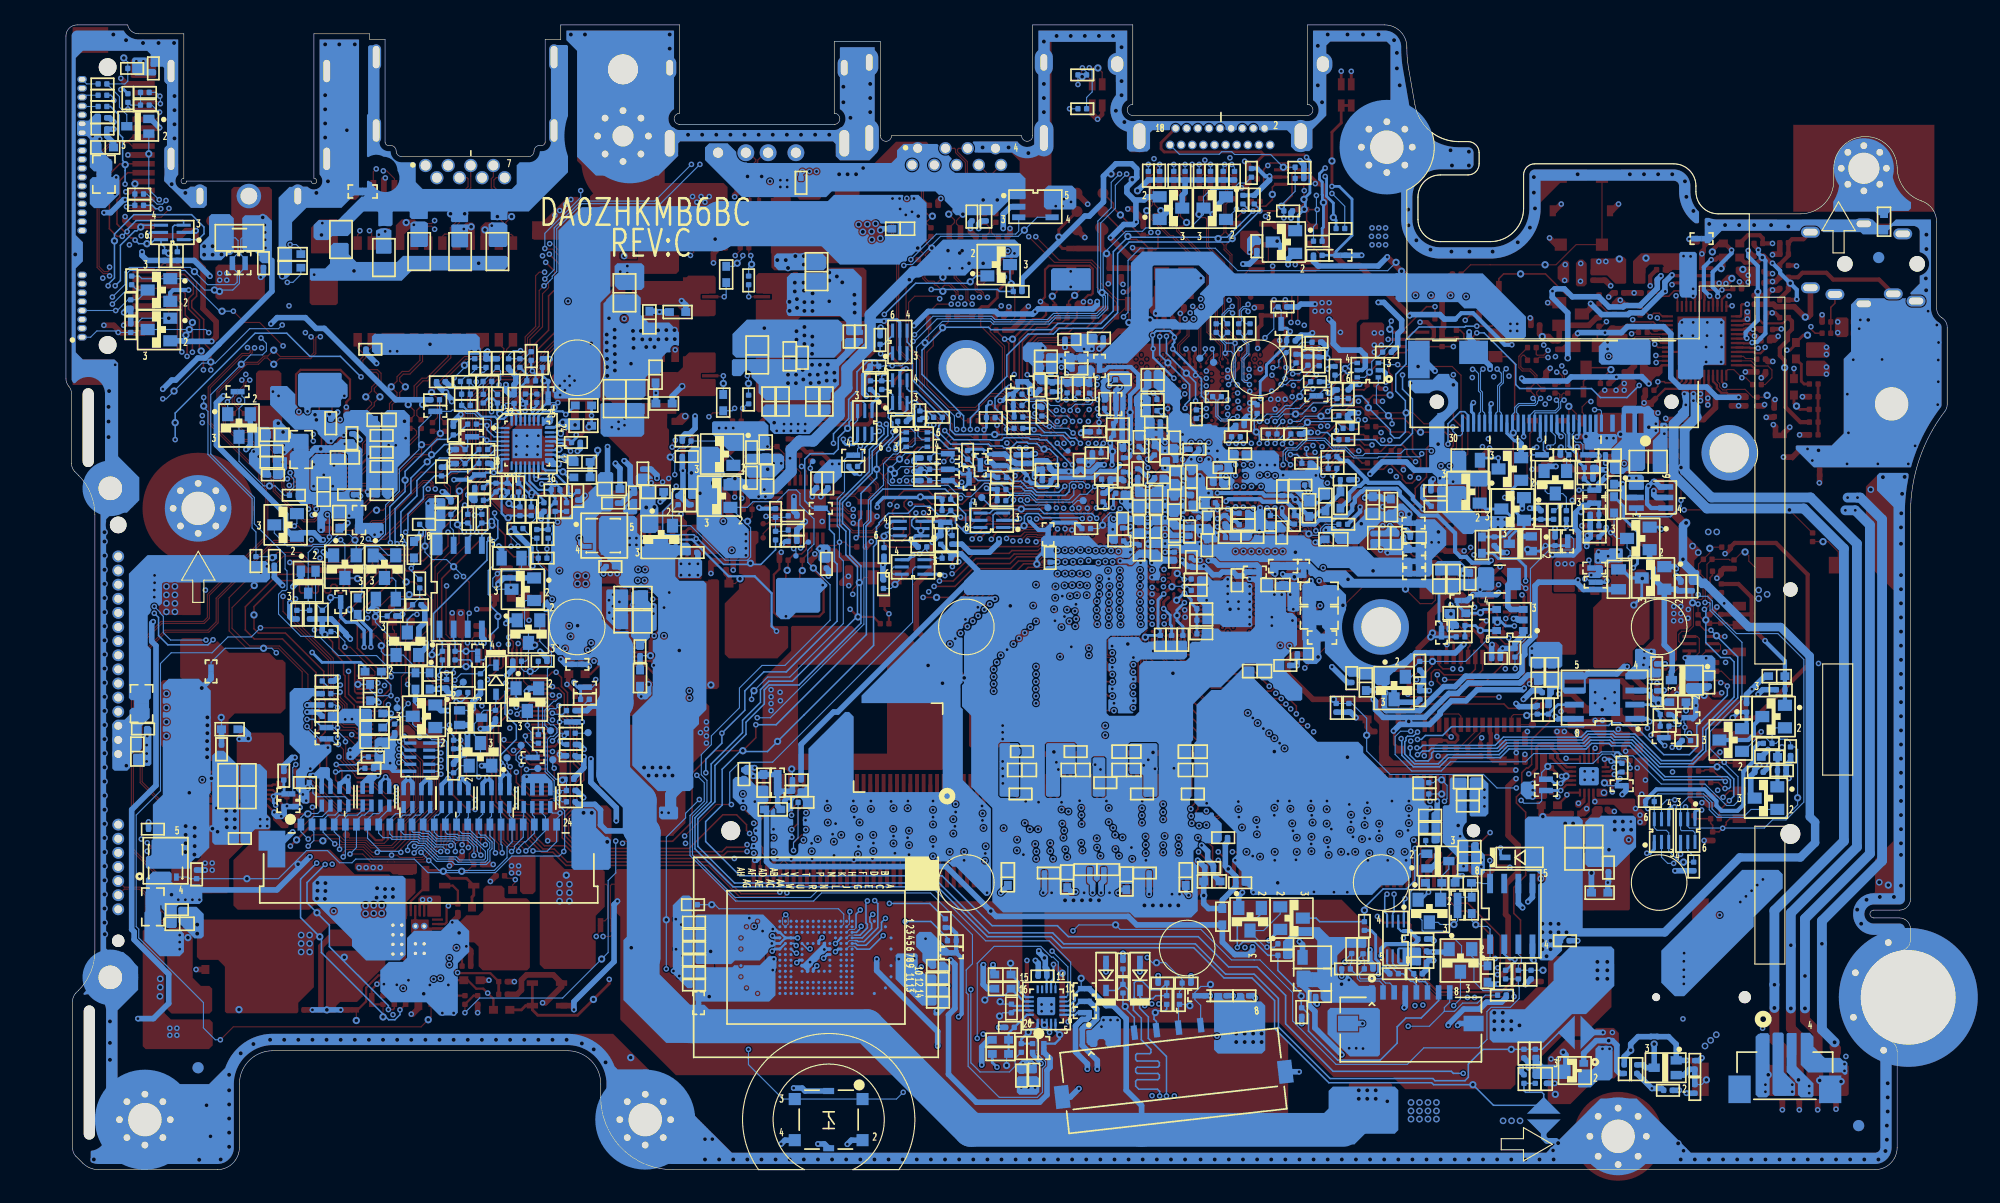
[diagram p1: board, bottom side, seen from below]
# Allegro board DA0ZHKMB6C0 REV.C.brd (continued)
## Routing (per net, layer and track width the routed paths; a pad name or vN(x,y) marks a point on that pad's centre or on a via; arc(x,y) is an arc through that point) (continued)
+3VPCU_EC: length 16.5
  TOP w0.203: U18.19 125.81,37.25 125.67,37.11 125.06,37.11 v1(124.81,37.36) ; C108.1 133.55,48.15 133.55,47.15 133.46,47.06 U18.115 ; U18.46 133.46,29.35 v1(133.57,29.24) ; v1(143.63,37.14) 143.63,36.96 143.12,36.45 U18.76
  TOP w0.508: v1(133.57,28.63) 133.57,28.16 C125.1
  IN2 w0.762: v1(125.87,29.59) 130.78,29.59 131.16,29.97 133.09,29.97 133.44,29.62
  BOTTOM w0.508: C296.1 124.68,37.24 v1(124.81,37.36)
  vias: v1(133.7,50.06) v1(142.08,49.63) v1(143.48,40.54) v1(143.63,37.74) v1(144.09,40.51) v2(124.55,35.05)
+5V: length 268.5
  TOP w0.203: U9.46 23.46,70.91 24.13,70.25 25.37,70.25 26.24,69.38 ; 20.84,69.34 20.84,69.7 21.23,70.08 21.23,70.41 21.46,70.65 U9.41
  TOP w0.508: D9.2 60.67,85.12 60.42,84.86 D10.2 59.58,84.73 59.58,82.88 v1(59.91,82.55) ; v1(25.31,67.59) 25.21,67.49 23.71,67.49 ; R82.1 27.15,69.6 27.26,69.49 v1(27.26,69) ; 26.24,69.38 26.64,68.99 C72.1 26.76,69 v1(27.26,69) ; 23.71,67.49 21.91,67.49 20.84,68.55 20.84,69.34 ; 23.71,67.49 C71.1 ; v1(30.67,62.36) 30.45,62.36 29.91,62.89 28.21,62.89 27.52,63.58 27.52,68.25 27.26,68.51 v1(27.26,69)
  IN1 w0.508: v1(136.97,40.59) 137.76,39.8 141.6,39.8 143.04,41.24 144.22,41.24 147.56,37.9 148.78,37.9 149.32,37.36 149.32,32.55 146.78,30.01 146.78,28.63 v1(147.26,28.14)
  IN1 w2.286: 56.81,3.53 63.31,3.53 68.04,8.26 73.91,8.26 76.7,5.46 108.7,5.46 118.43,15.19 119.97,15.19 120.28,15.49 122.19,15.49 ; 10.2,48.92 7.03,45.75 7.03,29.85 19.04,17.83
  IN2 w0.508: v1(130.27,56.1) 130.33,56.03 133.44,56.03 136.19,53.29 136.19,46.43 137,45.62 137,42.77 136.52,42.29 136.52,41.05 v1(136.97,40.59)
  IN2 w1.016: 35.46,80.96 52.73,80.96 53.45,81.67 57.56,81.67 58.44,82.55 v1(59.91,82.55)
  IN2 w2.032: 16.5,17.78 11.32,22.96 11.32,34.8 13.2,36.68 13.2,47.68 15.51,49.99
  BOTTOM w0.508: v1(130.27,56.1) 130.02,55.85 PR125.1 ; v1(59.91,82.55) 59.91,83.08 60.29,83.46 Q17.3 ; v1(30.67,62.36) 31.35,61.68 R294.2 ; PR176.2 76.5,14.46 76.5,13.56 77.14,12.91 77.56,12.91 77.79,12.68 77.79,11.18 76.45,9.83 v1(76.45,9.04) ; 157.45,25.3 157.32,25.17 150.23,25.17 v1(147.26,28.14)
  vias: v1(34.36,81.43) v1(34.41,80.01) v1(157.19,24.28) v1(157.83,24.28) v1(158.46,24.28) v1(159.1,24.28) v2(159.71,24.74) v3(16.2,51.77) v3(16.96,52.15) v3(16.96,51.38) v3(20.77,12.14) v3(21.28,11.63) v3(21.78,11.13) v3(38.42,4.39) v3(39.18,4.39) v3(39.95,4.39)
+5V_HDD:
  vias: v1(158.97,21.11) v1(158.97,20.47) v1(158.97,19.84) v2(158.23,20.88)
+5V_S5: length 31.5
  TOP w0.203: 155.08,34.55 PU10.7
  TOP w0.254: PC45.1 157.98,37.08 156.67,35.78 155.73,35.78 155.31,35.36 155.31,34.78 155.08,34.55
  BOTTOM w0.381: v1(134.31,62.08) 132.87,62.08 PR107.1
  BOTTOM w0.508: R416.1 v1(23.46,6.87) ; v3(156.99,43.33) 156.15,44.17 PR144.2 ; R417.1 v1(24.1,7.14)
  BOTTOM w4.064: 120.71,84.66 110.74,84.66 110.28,85.12 100.52,85.12
  vias: v1(23.29,50.4) v1(23.31,49.62) v1(23.96,50.67) v1(23.96,50.04) v1(23.96,49.4) v1(24.59,50.67) v1(24.59,50.04) v1(24.61,49.38) v1(26.61,46.63) v1(26.64,46) v1(26.74,45.21) v1(27.22,46.63) v1(27.25,46.03) v1(27.32,45.42) v1(27.63,31.9) v1(27.63,31.27) v1(28.03,32.49) v1(31.69,33.12) v1(50.51,84.73) v1(50.51,83.97) v1(50.51,83.21) v1(51.12,84.73) v1(51.15,83.97) v1(51.12,83.21) v1(51.73,84.73) v1(51.73,83.21) v1(51.78,83.97) v1(52.54,10.9) v1(53.15,10.92) v1(53.79,10.92) v1(78.81,87.07) v1(79.44,87.33) v1(79.57,86.69) v1(80.18,86.69) v1(92.93,87.38) v1(93.11,86.18) v1(93.67,85.9) v1(94.23,87.38) v1(94.17,86.44) v1(94.86,87.38) v1(123.46,70.99) v1(123.92,71.4) v1(123.89,70.56) v1(124.35,70.97) v1(124.32,70.13) v1(124.76,69.7) v1(124.78,70.54) v1(125.21,70.1) v2(23.77,54.92) v3(20.73,57.38) v3(21.49,57.38) v3(22.39,55.52) v3(22.9,56.11) v3(45.94,6.05) v3(45.94,5.28) v3(45.94,4.55) v3(46.7,6.05) v3(46.7,5.28) v3(46.7,4.55) v3(47.46,6.05) v3(47.46,5.28) v3(47.46,4.55) v3(48.23,6.05) v3(48.23,5.28) v3(48.23,4.55) v3(156.48,40.69) v3(156.48,39.98) v3(156.48,39.27) v3(156.51,38.56) v3(156.51,37.82) v3(156.51,37.11) v3(157.62,30.76) v3(157.62,30) v3(157.62,29.11) v3(157.65,28.35) v3(158.44,30.91) v3(158.44,30.12) v3(158.44,29.36) v3(158.46,28.58)
+5VA:
  vias: v1(17.9,80.47) v1(17.9,79.86) v1(17.97,77.17) v1(17.97,76.53) v1(32.96,81.53) v1(32.99,79.93) v2(18.38,81)
+12VALW: length 238.6
  IN1 w0.254: v1(37.91,52.96) 37.41,52.45 29.2,52.45 28.24,53.42 v1(28.24,54.15)
  IN1 w0.381: v1(35.02,33.55) 35.42,33.15 35.42,32.64 36.72,31.34 37.33,31.34 37.74,30.94 37.74,27.04 38.92,25.85 40.19,25.85 44.86,21.18 46.37,21.18 47.43,20.13 49.32,20.13 50.06,20.88 55.26,20.88 57.5,18.64 60.42,18.64 60.95,19.18 63.84,19.18 65.32,20.66 75.9,20.66 76.84,19.72 79.38,19.72 80.03,19.08 81.12,19.08 81.7,19.66 v1(81.7,19.69) 87.93,19.69 89.3,18.31 90.87,18.31 91.74,17.45 94.2,17.45 95.19,16.46 105.83,16.46 107.31,17.94 107.31,20.73 110.82,24.24 110.82,33.36 109.12,35.07 109.12,39.73 110.81,41.43 113.65,41.43 116.48,44.26 117.62,44.26 117.82,44.05 120.73,44.05 121.26,43.53 122.33,43.53 123.56,42.29 123.56,40.61 124.44,39.74 125.49,39.74 126.05,40.3 126.05,42.06 126.27,42.28 126.27,43.19 129.13,46.04 133.5,46.04 134.01,46.55 135.9,46.55 136.3,46.15 140.9,46.15 v1(141.77,47.02)
  IN2 w0.381: v1(26.92,32.49) 27.63,33.2 28.85,33.2 29.23,32.82 30.42,32.82 31.39,31.85 33.98,31.85 34.76,32.64 34.76,33.3 v1(35.02,33.55) 35.32,33.86 35.32,38.15 35.68,38.51 35.68,39.75 35.22,40.21 32.73,40.21 32.38,39.85 30.5,39.85 29.89,40.45 29.16,40.45 28.24,41.38 v1(28.24,54.15)
  BOTTOM w0.203: PU16.13 81,17.41 PC189.1
  BOTTOM w0.254: v1(37.91,52.96) 37.91,54.25 38.65,54.99 40.38,54.99 40.84,55.46 PR103.1 ; v1(28.24,54.15) 27.85,54.53 27.85,57.38 29.1,58.62 29.1,59.69 PR113.1
  BOTTOM w0.305: PR134.1 142.97,49.68 141.77,48.49 v1(141.77,47.02)
  BOTTOM w0.381: v1(26.92,32.49) 27.13,32.7 R187.1 27.13,33.24 26.15,34.21 21.81,34.21 20.76,33.16 20.76,32.75 20.29,32.28 18.86,32.28 18.33,32.82 18.33,35.81 17.44,36.7 17.44,37.85 16.93,38.35 R356.1
  BOTTOM w0.508: PC189.1 80.98,18.05 81.12,18.19 81.12,18.97 v2(81.19,19.05) 81.7,19.56 v1(81.7,19.69)
+A3VPCU: length 11.2
  TOP w0.102: v1(138.42,41.94) 139.03,42.55 139.03,44.35 138.66,44.72 U18.102 138.66,47.65 C109.1 138.24,48.07 C103.1
  BOTTOM w0.102: v1(138.42,41.94) 138.83,41.53 138.83,41.33 139.54,40.61 139.87,40.61 L18.2
+VCC_CORE: length 27.3
  TOP w0.102: 72.3,59.76 U12.Y29 72.3,59.72 ; U12.AA27 71.57,60.5 ; U12.AA30 71.57,58.98 ; U12.Y27 72.26,60.5 ; U12.Y30 72.26,58.98 ; v1(71.91,59.33) 71.91,59.35 ; 71.52,59.76 U12.AA29 71.52,59.72
  TOP w0.254: v1(74.24,60.12) 74.24,60.21 74.25,60.22 74.25,60.24 74.46,60.45 74.46,60.68 U12.P26 ; v1(74.24,60.12) 74.24,60.11 U12.U29 ; v1(74.24,60.12) 73.87,60.49 U12.U27
  TOP w0.305: v1(70.34,60.12) 69.97,60.5 U12.AD27 U12.AF27 69.15,60.5 v1(68.78,60.12) ; v1(70.34,60.12) 70.33,60.12 U12.AD29 70.33,59.36 v1(70.34,59.36) ; v1(70.34,60.12) 70.36,60.12 U12.AC29 ; v1(70.34,60.12) 70.72,60.5 U12.AC27 U12.AA27 ; v1(68.78,60.12) 68.4,60.5 U12.AG27 ; v1(68.78,60.12) 68.76,60.12 U12.AG29 68.4,59.74 v1(68.78,59.36) ; v1(68.78,60.12) 68.79,60.12 U12.AF29 68.79,59.36 v1(68.78,59.36) ; U12.AD30 69.96,58.98 v1(70.34,59.36) ; v1(70.34,59.36) 70.72,58.98 U12.AC30 U12.AA30 ; v1(70.34,59.36) 70.36,59.36 U12.AC29 ; 72.3,59.76 72.23,59.76 72.23,59.79 71.89,60.13 ; v1(73.48,60.12) 73.1,60.5 U12.V27 U12.Y27 ; v1(73.48,60.12) 73.47,60.12 U12.V29 ; v1(73.48,60.12) 73.49,60.12 U12.U29 73.49,59.36 v1(73.48,59.36) ; v1(73.48,60.12) 73.86,60.5 U12.U27 ; v1(73.48,59.36) 73.1,58.98 U12.V30 U12.Y30 ; v1(73.48,59.36) 73.47,59.36 U12.V29 ; U12.V29 U12.Y29 ; U12.AA29 U12.AC29 ; 71.57,58.98 v1(71.91,59.33) ; v1(71.91,59.33) 72.26,58.98 ; v1(71.91,59.33) 72.3,59.72 ; v1(71.91,59.33) 71.52,59.72 ; 72.26,60.5 71.89,60.13 ; 71.89,60.13 71.59,60.42 71.57,60.42 71.57,60.5 ; 71.89,60.13 v1(71.89,60.12) ; 71.89,60.13 71.52,59.76 ; v1(68.78,59.36) 68.4,58.98 U12.AG30 ; U12.P26 75.11,60.62 U12.P27
  TOP w0.33: U12.AD29 69.94,59.74 69.56,59.36 ; U12.AF29 69.18,59.74 69.56,59.36 ; 69.56,59.36 69.94,58.98 U12.AD30
  BOTTOM w0.508: v1(92.92,63.69) 92.92,63.85 92.74,64.03 PR102.2
  vias: v2(96.46,72.59) v3(100.05,70.99) v3(100.09,71.7) v3(100.68,72.44) v3(100.83,71.7) v3(100.78,70.99) v3(101.39,72.42) v3(101.48,70.82) v3(101.58,71.53) v3(102.1,72.42) v3(102.23,70.76) v3(102.3,71.53) v3(102.94,71.96) v3(102.89,71.09) v3(103.53,71.53) v3(103.55,70.76) v3(104.26,71.53) v3(104.26,70.76)
+VCC_GFX: length 4.5
  BOTTOM w0.508: v1(56.86,77.88) 58.13,77.88 58.39,77.62 PR76.2 ; v1(57.09,75.29) 57.29,75.08 58.12,75.08 R236.1
  vias: v1(54.58,75.34) v1(55.59,78) v1(55.59,77.24) v1(56.23,78) v1(56.23,77.24) v1(56.86,77.24) v1(66.43,60.88) v1(66.39,59.36) v1(67.21,62.4) v1(67.21,60.12) v1(67.17,59.36) v1(68.78,62.4) v1(70.34,63.15) v2(100.55,78.13) v3(98.26,77.9) v3(98.26,77.11) v3(98.29,78.71) v3(99.38,79.83) v3(99.86,80.37) v3(100.55,80.72) v3(100.55,80) v3(102.05,78.84) v3(102.06,78.05) v3(102.06,77.27) v3(102.86,79.81) v3(102.82,79.1) v3(102.78,78.05) v3(102.78,77.27) v3(103.46,78.33) v3(103.45,77.54) v3(103.65,79.81) v3(103.65,79.02) v3(104.13,78.08) v3(104.12,77.27)
+VDDQ: length 99.7
  IN1 w0.508: v1(29.58,39.62) 29.99,39.22 31.82,39.22 32.5,38.53 32.5,37.92 34.05,36.37 34.94,36.37 35.98,35.33 35.98,32.87 36.91,31.94 37.67,31.94 38.32,31.29 38.32,27.23 39.08,26.47 40.34,26.47 45.08,21.73 46.6,21.73 47.29,21.04 48.11,21.04 48.73,21.65 55.36,21.65 57.75,19.25 59.96,19.25 60.47,19.76 62.2,19.76 v1(62.48,20.04)
  BOTTOM w0.508: v1(62.48,20.04) 62.48,19.71 62.83,19.35 64.07,19.35 65.19,20.47 R401.2 72.9,22.02 73.66,22.78 85.54,22.78 v2(86.02,23.27) 90.02,27.27 105.75,27.27 106.19,27.71 106.19,32.23 R396.1
+VDDQ_VTT: length 31.3
  TOP w0.203: PC53.1 32.45,38.15 32.23,37.92 PU9.3 ; v1(34.28,37.01) 34.19,36.92 PU9.1
  TOP w0.356: v1(43.5,27.31) 44.03,27.31 44.36,26.98 JDIM6.204 ; JDIM6.203 44.66,30.85 v1(43.81,30)
  TOP w0.508: PC53.1 32.45,38.74 33.06,39.34 v1(33.29,39.34) ; v1(39.34,27.2) 40.68,27.2 41.34,26.54 42.41,26.54 43.17,27.31 v1(43.5,27.31)
  IN1 w0.508: v1(33.29,39.34) 33.29,38 v1(34.28,37.01) 35.17,37.01 36.59,35.58 36.59,33.17 37.2,32.56 38.17,32.56 38.98,31.75 38.98,27.56 v1(39.34,27.2)
  vias: v2(43.98,30.96)
+VIN: length 110.1
  TOP w0.508: PR39.1 124.25,46.94 v1(124.3,46.89)
  TOP w0.762: v3(23.49,58.19) 23.74,58.19 24.68,59.13 24.68,62.54 25.49,63.35 R106.1 R107.1
  IN1 w0.102: v1(34.81,59.74) 27.12,59.74 25.57,58.19 v3(23.49,58.19)
  IN1 w0.508: v1(126.56,46.63) 126.31,46.89 v1(124.3,46.89)
  IN2 w0.508: v1(149.06,51) 149.06,50.83 149.08,50.8 149.08,50.3 150.99,48.39 150.99,46.13 150.64,45.77 149.57,45.77 149.06,45.26 149.06,38.35 149.52,37.9 149.52,34.7 151.5,32.72
  BOTTOM w0.102: v1(34.81,59.74) 35.26,59.29 PR118.1
  BOTTOM w0.508: v1(86.83,9.42) 86.83,11.05 86.2,11.68 PR182.2 ; PR137.1 148.86,49.55 149.06,49.75 v1(149.06,51) ; PR142.1 125.94,46.02 v1(126.56,46.63)
  BOTTOM w0.762: 21.61,52.58 17.85,48.82 14.98,48.82 12.36,46.2 12.36,31.75 11.88,31.27 11.88,29.41 13.2,28.09 18.66,28.09 25.4,21.35 33.7,21.35 ; v3(23.49,58.19) 23.77,57.91 23.77,54.61 22.93,53.77
  vias: v1(82.03,7.39) v1(82.64,7.39) v1(83.28,7.39) v1(111.34,87.55) v1(111.73,87.05) v1(112.08,87.55) v1(112.46,87.05) v1(112.84,87.55) v1(114.99,62.19) v1(115.54,61.87) v1(116.56,61.8) v1(118.71,81.31) v1(118.71,80.67) v1(118.96,67.59) v1(118.96,66.98) v1(119.35,80.8) v1(119.5,67.28) v1(119.5,66.65) v1(119.98,51.74) v1(120.01,50.7) v1(119.98,49.58) v1(120.11,66.8) v1(120.36,51.23) v1(120.34,50.11) v1(151.1,31.52) v1(151.1,30.91) v1(151.73,31.52) v1(151.73,30.91) v2(148.33,27.48) v3(33.65,31.14) v3(34.24,21.35) v3(34.36,31.14) v3(34.95,22.11) v3(34.95,21.35) v3(35.68,22.12) v3(35.68,21.36) v3(35.68,20.6) v3(35.68,19.84) v3(36.03,19.2) v3(36.41,22.12) v3(36.41,21.36) v3(36.41,20.6) v3(36.41,19.84) v3(122.45,53.43) v3(122.45,52.72) v3(123.19,53.43) v3(123.19,52.72) v3(139.79,25.25) v3(139.79,24.54) v3(140.5,25.25) v3(140.5,24.54) v3(141.22,25.32) v3(141.27,24.47) v3(145.86,25.78) v3(145.86,25.07) v3(145.91,24.36) v3(146.57,25.81) v3(146.57,25.1) v3(146.63,24.38)
GND: length 793.1
  TOP w0.178: U12.E8 79.33,69.82 79.89,69.27 v1(79.98,69.27)
  TOP w0.203: PU9.4 31.83,37.76 v1(31.66,37.92) ; v1(125.44,37.62) 125.48,37.65 U18.18 ; C47.1 78.27,77.64 78.27,76.66 78.86,76.07 78.99,76.07 79.34,75.72 80.25,75.72 80.79,75.18 81.88,75.18 82.74,74.32 v1(82.74,71.53) ; v1(77.69,78.08) 77.69,78.26 77.26,78.69 77,78.69 76.85,78.84 76.85,81.05 77.13,81.33 80.79,81.33 81.14,80.98 81.14,78.51 v1(81.55,78.11) ; v1(133.01,28.98) 133.06,29.03 133.06,29.11 133.06,29.11 U18.45 ; U12.A43 81.86,52.73 v1(81.95,52.63) ; C96.2 105.03,54.04 105.53,53.54 105.53,50.14 105.17,49.78 v1(104.44,49.78) 101.44,49.78 101.06,50.17 101.06,52.51 v1(101.13,52.59) 101.13,53.19 102.19,54.25 C95.2 ; C46.1 81.05,76.93 81.45,76.53 82.24,76.53 83.91,74.85 v1(83.91,71.55) ; U18.116 133.06,47.37 v1(133.08,47.4) ; U18.5 125.6,42.85 v1(125.44,42.7) ; v1(56.78,57.48) 56.78,57.71 57.4,58.32 57.54,58.32 57.75,58.52 U12.BJ31 ; 71.47,75.01 71.54,75.08 71.54,75.82 71.06,76.3 71.06,76.91 v1(71.19,77.04) ; 71.47,75.01 v1(71.47,75.08) ; 71.47,75.01 71.47,74.24 ; U12.A27 81.66,60.5 81.9,60.26 v1(82.73,60.26) ; U18.89 141.35,41.65 141.06,41.94 v1(141.06,42.04) ; v1(143.98,68.61) 143.98,69.06 143.65,69.39 143.65,71.09 144.52,71.96 148.1,71.96 148.5,71.55 148.5,68.63 148.25,68.38 v1(148.25,68.2) ; v1(140.94,37.72) 141.4,37.25 U18.78 ; 70.27,74.12 v1(69.51,74.88) 69.03,75.36 69.03,76.99 v1(68.98,77.04) ; PU9.7 30.34,35.82 v1(29.96,36.2) ; PU9.10 30.27,34.62 30.12,34.47 v1(30.12,33.99)
  TOP w0.254: v1(44.62,38.94) 44.77,38.94 45.04,39.21 U16.11 ; U12.AT4 63.73,72.13 U12.AU3 ; Q46.1 v1(20.01,47.97) ; U12.A47 82.08,50.88 v1(82.21,50.75) ; v1(82.05,68.68) 81.9,68.68 81.49,68.27 U12.A11 ; U12.J40 77.6,54.06 78.01,53.66 v1(78.01,53.63) 78.01,53.44 78.26,53.18 U12.G42 ; v1(81.95,56.49) 81.82,56.61 U12.A35 ; U12.AH3 U12.AH2 68.18,73 68.18,73.55 v1(68.47,73.84) ; U12.AA53 71.5,46.75 v1(71.41,46.66) ; v1(80.2,52.47) 80.59,52.09 U12.C45 ; U12.N51 75.26,48.43 U12.P52 74.99,47.98 74.99,47.25 75.11,47.12 v1(75.11,47.11) ; U12.D16 79.51,65.65 79.51,65.42 v1(79.44,65.35) ; v1(82.02,64.42) 81.99,64.39 U12.A19 ; U12.AE1 69.56,73.74 v1(69.66,73.84) ; U12.AB51 71.02,49.35 U12.AB50 ; U12.J53 77.33,47.07 v1(77.2,46.93) ; U12.M51 76.13,48.77 v1(76.44,49.08) 76.54,49.18 76.69,49.18 U12.K50 ; v1(63.62,73.86) 63.73,73.75 U12.AU1 ; U12.D38 80,54.86 v1(80,54.68) 80.01,54.67 U12.C39 80.67,54.67 80.75,54.75 81.29,54.75 U12.A39 ; U12.BJ11 57.24,68.27 57.11,68.41 v1(56.96,68.41) ; U12.AN53 U12.AN51 ; U12.BJ19 57.02,64.39 v1(56.86,64.54) ; v1(67.73,73.84) 67.62,73.72 U12.AJ1 67.73,73.2 67.73,72.69 U12.AJ3 67.62,72.15 67.68,72.09 ; U12.AE48 69.44,50.39 U12.AF47 ; v1(23.56,46.05) 23.19,46.43 Q46.4 ; v1(41.87,38.86) 41.97,38.76 C356.1 ; v1(80.33,50.42) 80.2,50.3 U12.C49 ; v1(57.06,70.26) 57.2,70.12 U12.BJ7 ; v1(82.13,66.58) 82.03,66.47 81.52,66.47 U12.A15 ; U12.C34 80.29,57.25 80.02,57.52 v1(80.02,57.65) ; v1(57.22,66.33) U12.BJ15 ; 73.24,48.97 73.04,48.77 U12.V51 ; v1(56.78,62.46) 56.8,62.44 U12.BJ23 ; U12.AW3 62.76,72.04 v1(62.79,72.01) ; U12.E53 79.55,46.39 v1(79.79,46.15) ; 69.56,49.81 U12.AE50 U12.AE51 69.45,48.32 69.45,47.79 U12.AE53 ; U12.M47 75.49,50.35 v1(75.4,50.35) 75.34,50.35 74.95,50.75 U12.P47 ; U12.A23 81.95,62.44 v1(82.08,62.32) ; U12.C14 80.29,67.08 v1(80.05,67.32) 80.05,67.47 U12.D12 ; U12.AB10 70.58,69.26 70.58,69.71 U12.AD7 ; U12.AN3 65.82,72.57 U12.AM3 ; v1(81.95,49.33) 81.87,49.41 81.47,49.41 U12.A49 ; U12.AB4 71.46,71.64 ; U12.C31 80.72,58.64 81.29,58.64 U12.A31 81.9,58.56 v1(81.91,58.55) ; U12.AN1 65.77,73.31 U12.AM2 ; U12.AE45 U12.AE46 69.92,50.75 U12.AD47 ; v1(80.03,53.63) 80.03,53.48 U12.C42 ; U16.18 45.04,47.2 v1(45,47.24) ; U12.AB6 71.49,70.96 ; v1(73.19,46.08) 73.32,46.2 73.32,47.55 U12.U53 73.34,47.79 73.34,48.32 U12.U51 73.45,48.77 73.59,48.92
  TOP w0.279: U24.2 38.62,50.83 38.45,50.65 38.45,49.76 38.62,49.58 v1(39.01,49.58)
  TOP w0.305: U12.G10 78.32,68.44 v1(78.2,68.31) ; v1(100.12,28.27) 100.16,28.23 JDIM6.26 ; U12.BE1 59.57,72.77 U12.BE2 59.52,72.22 v1(59.47,72.17) 59.47,71.74 U12.BF4 ; U12.D36 79.7,56.29 U12.E35
  TOP w0.356: JDIM6.44 94.76,28.36 v1(94.64,28.47) ; JDIM6.178 52.16,27.78 v1(52.1,27.83) ; JDIM6.185 50.06,33.28 v1(49.94,33.17) ; JDIM6.54 v1(91.76,27.89) ; v1(105.21,28.04) 105.56,27.69 JDIM6.8 ; v1(60.2,33.17) 60.26,33.22 JDIM6.151 60.26,35.81 60.51,36.06 61.68,36.06 62.06,35.68 JDIM6.145 ; JDIM6.184 50.36,27.8 v1(50.32,27.83) ; v1(64.04,27.83) 64.16,27.71 JDIM6.138 ; JDIM6.172 v1(53.96,24.96) ; v1(60.48,27.83) 60.56,27.76 JDIM6.150 ; JDIM6.195 47.06,33.51 47.07,33.49 47.07,32.7 46.85,32.48 v1(46.51,32.48) ; JDIM6.66 88.16,27.57 v1(88.42,27.83) ; v1(62.4,24.94) 62.36,24.98 JDIM6.144 ; v1(93.37,28.34) 93.56,28.16 JDIM6.48 ; v1(68.23,24.68) 67.57,24.68 67.16,25.09 JDIM6.128 ; JDIM6.127 67.46,35.59 67.16,35.89 65.96,35.89 65.66,35.59 JDIM6.133 65.66,33.41 66.11,32.96 v1(66.6,32.96) ; JDIM6.190 48.56,27.72 v1(48.67,27.83) ; v1(91.22,33.17) 91.46,33.41 JDIM6.55 ; JDIM6.60 89.96,27.57 v1(89.69,27.83) ; v1(86.81,32.72) 86.66,32.87 JDIM6.71 ; JDIM6.49 93.26,33.38 v1(93.47,33.17) ; v1(104.17,33.12) 104.06,33.23 JDIM6.13 104.06,35.85 104.37,36.16 104.99,36.16 105.26,35.89 JDIM6.9 ; v1(52.15,33.01) 51.86,33.31 JDIM6.179 ; v1(107.26,27.84) 107.36,27.74 JDIM6.2 ; JDIM6.65 88.46,32.62 88.9,32.18 v1(89.18,32.18) 89.3,32.18 89.81,32.68 89.81,33.3 89.66,33.45 JDIM6.61 ; JDIM6.38 96.56,27.71 96.66,27.82 v1(96.66,27.99) ; v1(100.74,33.17) 100.46,33.45 JDIM6.25 100.46,36.06 100.76,36.37 101.99,36.37 102.26,36.1 JDIM6.19 ; v1(57.23,33.17) 57.26,33.2 JDIM6.161 ; JDIM6.20 101.96,27.84 v1(102.09,27.98) ; JDIM6.14 103.76,27.75 v1(103.97,27.96) ; v1(98.38,33.17) 98.66,33.44 JDIM6.31 ; v1(63.76,33.12) 63.76,33.12 63.86,33.22 JDIM6.139 ; v1(58.57,27.88) 58.57,27.71 58.76,27.52 JDIM6.156 ; v1(45.89,28.32) 46.09,28.32 46.76,27.66 JDIM6.196 ; JDIM6.189 48.86,33.48 48.54,33.17 v1(48.42,33.17) ; JDIM6.155 59.06,33.27 v1(59.16,33.17) ; JDIM6.43 95.06,33.2 v1(94.99,33.13) ; JDIM6.3 107.06,33.3 v1(107.24,33.12) ; v1(56.96,24.99) JDIM6.162 ; JDIM6.32 98.36,27.83 98.37,27.84 v1(98.34,27.89) ; JDIM6.173 53.66,32.98 v1(53.78,32.86) ; JDIM6.167 55.46,33.49 v1(55.78,33.17) ; v1(96.8,33.17) 96.86,33.22 JDIM6.37 ; JDIM6.134 65.36,27.63 v1(65.56,27.83) ; v1(55.16,24.96) JDIM6.168 ; JDIM6.72 v1(86.36,24.91)
  TOP w0.381: v1(105.55,63.55) 105.55,63.97 R114.1 ; v1(45.79,37.21) 45.77,37.2 R181.2 ; U7.5 58.43,81.65 v1(58.64,81.43) ; U16.25 40.49,47.08 40.66,47.24 v1(40.94,47.24) ; C71.2 23.85,66.85 v1(25.44,66.85) ; v1(47.03,37.24) 47.03,38.29 C118.2 ; C156.1 26.51,44.37 26.74,44.15 v1(26.74,43.92) ; v1(88.74,58.7) 88.61,58.57 R146.2 ; U16.4 40.49,38.98 v1(40.5,38.97) 40.5,38.79 C357.2 ; C80.2 21.29,45.63 v1(21.68,46.03)
  TOP w0.508: D15.2 44.67,80.4 v1(44.67,78.66) 45.16,79.16 C38.2 ; v1(87.85,84.68) 87.85,84.41 C23.2 ; v1(90.52,87.38) 90.76,87.13 C17.2 ; v1(148.15,32.59) 148.55,32.99 PC68.1 ; v1(20.01,46.56) 19.75,46.56 19.73,46.58 CN4.6 ; v1(109.31,55.73) 109.74,56.15 PC28.2 ; PC21.2 46.24,61.77 v1(46.24,62.13) ; C46.1 81.12,77.67 v1(81.55,78.11) ; T11.2 v1(21.86,29.61) ; C85.2 30.32,63.97 v1(30.71,63.58) ; CN10.40 160.84,93.7 v1(160.78,93.75) ; v1(15.69,72.72) 16.14,72.72 C57.2 ; SW6.4 35.17,83.23 v1(35.77,83.83) ; JDIM6.206 41.65,16.69 v1(40.4,16.69) ; PC85.1 v1(131.16,17.04) ; C84.1 29.18,63.65 v1(29.05,63.53) 28.79,63.53 C83.1 ; C350.1 v1(157.5,18.01) ; C82.1 33.33,65.05 v1(33.29,65.04) 33.37,65.01 33.37,64.28 C86.2 ; C61.2 16.34,71.59 16.68,71.25 v1(16.73,71.25) ; v1(20.72,53.22) 20.33,53.6 T15.2 20.1,54.08 T10.2 ; PC26.1 114.65,58.22 v1(113.88,58.98) 113.88,58.47 113.6,58.19 PC27.1 ; C18.2 v1(93.57,87.39) ; C78.2 145.05,66.98 v1(144.54,67.49) ; v1(38.12,42.32) 37.39,43.04 PC198.2 ; MR6.3 140.61,89.1 v1(140.48,89.23) ; D6.2 62.84,90.38 v1(63.19,90.73) ; v1(164.26,98.2) 163.77,97.7 CN10.50 ; PC38.1 116.69,52.54 v1(117.16,53.01) ; C226.1 37.44,76.56 v1(37.51,76.63) ; v1(138.93,49.97) 138.93,50.29 138.52,50.7 L14.1 ; C87.1 107.14,63.43 v1(107.03,63.55) ; PC32.2 v1(124.82,53.9) ; v1(100.63,53.42) 101.06,53.85 C94.1 ; R64.2 84.4,77.23 v1(84.4,77.65) ; v1(117.11,54) 116.69,54.42 PR29.2 ; PR8.1 110.46,82.95 110.96,82.44 v1(110.96,81.59) ; v1(84.29,84.68) 84.29,84.16 C22.2 ; v1(20.29,42.9) 20.44,42.75 20.89,42.75 C147.2 ; Y9.4 v1(101.13,52.59) ; JDIM6.205 108.56,21.23 107.89,21.9 v1(107.31,21.9) ; v1(11.65,5.39) C137.2 ; R97.1 v1(143.98,68.61) ; v1(127.22,54.31) 127.41,54.11 C97.2 ; C42.1 v1(59.53,78.26) ; C119.2 51.76,39.42 52.16,39.83 52.16,40.5 C355.2 52.33,40.67 v1(53.18,40.67) ; v1(111.19,53.65) 111.19,54.65 PC31.2 110.71,54.65 110.59,54.77 PC34.1 ; CN10.4 163.88,76.1 v1(164.01,75.97) ; v1(23.21,83.72) 22.98,83.49 C27.2 ; v1(63.47,88.34) 63.27,88.34 62.84,88.76 C7.2 ; C126.2 v1(130.78,27.46) ; v1(134.71,27.33) 134.54,27.5 C125.2 ; v1(25.44,66.22) 24.96,66.22 24.35,65.61 R111.1 ; v1(27.91,58.19) 28.08,58.01 PC24.2 ; v1(71.19,77.04) 71.22,77.04 71.48,77.29 C33.2 71.48,78.12 Y6.4 ; U3.3 78.27,87.83 v1(77.31,86.87) ; T14.2 20.72,50.6 v1(20.72,50.62) ; PC70.1 30.39,32.23 v1(29.94,32.23) ; v1(109.06,87.53) 109.06,87.66 108.81,87.91 D8.2 ; v1(26.39,61.08) 26.33,61.14 C89.2 ; v1(73.7,86.44) 73.24,86.44 72.3,85.5 T3.2 ; PC199.1 28.06,37.59 28.87,37.59 v1(28.92,37.64) 29.07,37.8 29.07,38.09 PC56.2 ; v1(60.54,78.26) 60.67,78.13 C43.1 ; C32.2 68.65,77.61 68.65,77.37 v1(68.98,77.04) ; v1(41.44,49.38) 41.88,48.95 C105.2 ; v1(32.86,57.94) PC25.1 ; C41.2 29.91,77.93 29.61,78.23 v1(29.4,78.23) 28.95,77.78 28.79,77.78 R51.1 ; C101.1 127.85,49.73 v1(127.55,49.43) ; v1(104.87,55.55) 105.03,55.39 C96.2 ; v1(67.12,80.21) 67.54,80.63 Y6.2 ; U3.1 78.25,84.56 v1(77.56,83.87) ; SW6.5 30.16,86.28 v1(29.56,86.88) ; CN10.26 163.4,88.1 163.52,87.99 v1(163.82,87.99) ; v1(82.64,77.67) 83.13,77.19 83.13,76.53 84.12,75.54 R58.1 ; PC86.2 37.68,16.93 v1(37.94,16.66) ; SW6.6 35.31,86.28 v1(34.71,86.88) ; R154.2 97.25,56.03 v1(96.77,56.52) ; v1(15.64,67.03) 15.44,66.84 R25.1 ; PC48.2 114.42,43.49 113.38,42.44 v1(113.12,42.44) ; v1(33.72,60.22) 33.47,60.48 PC22.2 ; C91.2 144.12,57.93 v1(143.86,58.19) ; v1(84.5,82.66) 85.32,81.83 R54.2 ; C37.2 30.06,78.89 v1(30.45,78.51) ; v1(74.13,79.65) 74.29,79.81 C19.1 ; Y9.2 v1(104.44,49.78) ; C107.2 45.1,48.95 v1(44.76,48.62) 44.3,48.16 C106.2 ; R23.1 v1(14.73,64.11) ; Q27.1 v1(35.93,78) ; v1(13.3,5.39) C138.2 ; CN10.18 163.41,84.9 163.88,85.37 v1(163.88,85.75) ; v1(22.06,33.02) 21.71,33.02 21.53,32.84 T12.2 ; v1(93.03,55.3) 93.03,55.27 93.06,55.25 93.06,54.13 93.89,53.29 94.56,53.29 ; PC156.2 34.56,41.4 v1(34.74,41.22) ; C44.2 62.24,77.63 v1(62.32,77.55) ; v1(105.87,88.93) D7.2 ; v1(138.14,14) 138.01,14 137.51,14.5 PR62.1 ; v1(10,5.44) C136.2 ; C343.1 15.63,67.69 v1(16.28,67.69) ; v1(73.27,82.96) 73.09,82.78 T2.2 ; v1(123.94,48.93) PR37.2 ; v1(16.73,39.4) 17.21,38.91 18.55,38.91 18.7,39.07 CN4.3 19.79,39.08 20.15,39.44 C157.1 ; CN10.34 v1(163.63,91.3) ; PR17.1 v1(113.72,62.89) ; v1(144.16,69.62) 144.16,70.33 144.78,70.95 Y8.4 ; v1(131.03,25.93) 130.53,26.43 PC78.2 ; C79.2 148.25,67.28 v1(148.25,68.2) ; Y8.2 v1(147.47,68.22) ; v1(14.82,5.39) C139.2 ; R70.1 36.08,71.26 36.08,71.73 v1(35.71,72.11) ; v1(130.33,52.65) 130.33,53.74 129.95,54.11 C98.2 ; v1(134.46,50.09) 134.46,50.09 134.46,50.04 134.46,50.04 134.46,49.31 C102.2 C108.2 ; T13.2 21.15,36.86 v1(20.44,37.57) ; R49.1 72.69,76.1 73.35,75.44 74.54,75.44 76.11,73.86 v1(76.26,73.86) ; CN15.2 v1(20.46,22.91) ; PR60.2 v1(128.87,16.92) ; PC87.2 v1(132.17,14.12) ; R26.1 11.47,61.82 v1(11.5,61.8) ; v1(131.61,47.37) 131.61,48.54 132,48.93 R171.2 ; v1(75.45,79.71) 75.35,79.81 C16.1 ; v1(101.85,55.4) 101.85,55.19 C95.2 ; PC43.1 v1(123.82,47.98) ; PC23.2 v1(47.08,61.47) ; v1(26.02,68.09) C72.2 ; PC44.1 v1(115.41,48.03)
  IN1 w0.508: v1(149.14,77.72) 148.91,77.72 148.43,78.21 148.43,84.91 147.11,86.23 143.48,86.23 v1(140.48,89.23)
  BOTTOM w0.076: 104.24,22.1 U30.Y2 104.74,22.1 104.74,22.65 v1(104.46,22.94) 104.24,22.72 104.24,22.1
  BOTTOM w0.152: v1(67.61,71.48) 67.4,71.48 67.07,71.15 67.07,69.62 v1(66.63,69.18)
  BOTTOM w0.203: v1(48.76,24.38) 48.87,24.27 U27.1 ; v1(69.55,71.21) 71.42,73.08 v1(71.42,73.86) 71.47,73.91 v1(71.47,75.08) 71.47,75.13 71.14,75.46 69.92,75.46 69.51,75.06 v1(69.51,74.88) 69.51,74.42 69.66,74.27 v1(69.66,73.84) 67.61,71.79 v1(67.61,71.48) ; U30.Y5 U30.AA6 ; v1(99.99,20.35) 99.49,20.84 U30.K4
  BOTTOM w0.254: U30.P5 101.49,20.57 v1(101.18,20.88) ; v1(25.72,57.63) 25.9,57.81 PQ18.1 ; v1(82.13,66.58) 82.25,66.7 R271.2 ; v1(99.28,65.71) 99.28,65.46 99.05,65.23 98.34,65.23 98,65.57 Q24.4 ; v1(105.66,21.03) 105.47,20.85 U30.AA4 ; v1(101.67,18.34) 101.99,18.01 U30.R10 ; v1(101.06,19.02) 100.73,19.35 U30.M7 ; v1(103.47,18.62) 103.24,18.85 U30.U8 ; Q24.1 96.7,68.93 96.21,69.42 v1(96.21,69.62) ; v1(105.68,19.66) 105.66,19.63 105.44,19.85 U30.AA6 ; Q42.1 v1(61,20.6)
  BOTTOM w0.279: CN16.22 39.6,66.25 38.93,65.58 v1(38.6,65.58) ; Q51.4 v1(23.98,28.38) ; v1(95.34,57.91) 94.92,58.33 Q53.4 ; CN16.13 35.1,66.32 v1(34.74,65.96) ; v1(41.01,68.91) 41.11,68.81 41.11,68.12 41.1,68.11 CN16.25 ; Q53.1 92.79,57.03 v1(93.18,56.64) ; v1(36.67,65.68) 36.6,65.76 CN16.16 ; v1(38.1,65.96) CN16.19 ; Q51.1 22.68,32.21 22.53,32.36 v1(22.09,32.36) ; CN16.28 42.6,68.01 42.79,68.2 42.79,68.83 v1(42.61,69.01) ; Q32.4 93.45,54.88 v1(93.03,55.3) ; Q32.1 90.29,53.58 v1(90.16,53.44) ; v1(24.53,32.64) 24.83,32.64 25.05,32.43 Q50.4 ; v1(27.02,28.47) 26.71,28.47 26.35,28.84 Q50.1
  BOTTOM w0.305: CP6.8 140.12,35 v1(140.45,35.33) 140.91,34.87 CP6.6
  BOTTOM w0.356: 145.63,35.23 145.41,35 CP7.4
  BOTTOM w0.381: PC142.1 46.45,59.69 47.21,60.45 47.21,61.34 v1(47.08,61.47) ; C234.1 65.64,59.81 v1(65.64,59.39) ; C267.2 67.74,54.81 v1(67.19,54.81) ; v1(59.82,59.51) 59.82,58.94 58.96,58.08 C240.1 ; v1(94.58,64.8) 94.58,65.08 93.97,65.68 U25.2 ; v1(74.58,24.91) 74.3,25.19 C327.2 ; C265.1 80.03,54.65 v1(80,54.68) ; v1(96.21,69.62) 96.78,70.2 R324.2 ; R320.2 92.24,67.64 v1(91.79,67.64) ; v1(30.67,57.79) 30.67,57.57 PR122.2 ; v1(24.4,40.31) 24.4,40.59 24.76,40.95 PC173.1 ; v1(102.96,89.81) 103.09,89.69 C145.2 ; U26.2 50.74,71.93 50.5,71.69 v1(50.5,70.87) ; R286.1 62.24,68.99 v1(62.73,68.99) ; v1(54.46,17.42) C330.1 ; v1(133.71,38.01) 133.85,37.86 R377.1 ; v1(68.23,24.68) 68.48,24.94 C324.2
  BOTTOM w0.406: CP10.8 133.01,34.65 133.54,35.18 v1(133.8,35.18) CP10.6 ; v1(138.42,35.26) 138.42,35.2 ; 138.42,35.2 138.83,34.8 CP11.2 ; 138.42,35.2 138.04,34.82 CP11.4 ; CP10.4 134.61,34.98 v1(134.84,35.2) 135.4,34.65 CP10.2 ; CP11.8 136.44,34.93 v1(136.69,35.18) 137.23,34.65 CP11.6 ; PC197.2 82.26,10.35 81.53,9.61 81.53,9.58 v1(81.5,9.55) ; CP9.2 131.72,34.77 131.33,35.15 v1(131.33,35.31) 130.93,34.9 CP9.4 ; CP7.2 146.19,35.38 ; CP9.6 130.12,35.26 v1(129.63,35.74) 129.33,35.43 CP9.8
  BOTTOM w0.457: C190.2 30.73,63.6 v1(30.71,63.58)
  BOTTOM w0.508: SW8.5 102.72,7.08 102.99,7.34 v1(103.75,7.34) ; v1(123.2,64.64) 122.94,64.9 PC113.2 ; v1(148.15,32.59) 148.23,32.66 PR164.2 ; v1(87.11,84.68) 87.11,85.09 86.84,85.36 C148.1 ; v1(164.9,94.26) 165.28,94.64 C141.1 ; PR119.2 36.76,59.51 v1(37.56,59.51) ; v1(142.76,65.68) 143.28,66.2 C187.2 ; v1(126.46,58.56) 126.46,58.98 PC137.2 ; C296.2 123.3,37.14 v1(122.62,37.14) 122.62,36.2 122.65,36.17 122.65,36.12 123.53,35.24 R387.2 ; C284.1 141.22,42.19 v1(141.06,42.04) ; PC204.1 15.99,36.31 v1(15.99,36.4) ; v1(122.13,45.3) 122.29,45.47 PR145.2 ; R276.1 34.79,64.32 34.79,64.95 v1(34.74,65) ; VC6.2 C144.2 57.87,90.44 58,90.58 v1(58.21,90.78) ; v1(151.69,80.29) 151.44,80.54 PC93.1 ; C359.1 133.93,42.82 134.69,42.82 134.97,43.1 R358.1 135.59,43.32 v1(135.65,43.26) 135.68,43.23 C282.2 ; C322.2 v1(71.78,24.78) ; v1(132.88,39.88) 133.01,40.01 Q35.1 ; v1(65.57,86.56) 65.57,86.82 Q14.1 ; PC201.2 16.6,43.18 v1(17.01,42.77) ; v1(160.78,93.75) 161.57,94.54 Q13.1 ; v1(137.25,57.35) 137.25,57.18 137.63,56.79 R327.1 ; C339.1 46.32,20.75 v1(46.17,20.6) ; C221.1 81.38,63.01 ; 81.38,63.01 C207.1 ; 81.38,63.01 81.81,63.01 82.08,62.75 v1(82.08,62.32) ; C143.2 164.92,92.39 165.52,92.99 C142.1 v1(164.9,93.62) ; v1(144.77,68.15) 145.37,67.55 C182.2 ; C268.1 100.63,53.94 v1(100.63,53.42) ; v1(67.99,63.91) 67.99,63.99 67.32,64.66 C191.2 ; v1(130.33,52.65) 130.33,52.73 129.81,53.24 PQ25.1 ; PU14.8 35.05,40.57 v1(35.25,40.77) ; v1(118.99,63.78) 118.96,63.78 118.46,63.27 118.46,61.62 118.08,61.24 PC131.2 118.32,60.87 119.22,59.97 PC135.2 ; C206.1 v1(29.18,61.67) 29.18,60.66 29,60.48 U21.2 ; PC193.2 62.42,15.65 v1(62.22,15.44) ; U21.5 26.15,60.48 26.39,60.72 v1(26.39,61.08) ; v1(39.01,49.58) 38.73,49.58 38.6,49.46 PU13.2 ; v1(76.86,24.91) 76.86,25.73 77.11,25.98 C320.2 ; v1(139.95,41.05) C290.1 ; PC194.1 v1(64.23,15.65) ; v1(45.89,28.32) 45.89,27.64 46.42,27.1 PQ33.1 ; v1(130.5,63.28) 130.56,63.34 130.77,63.34 130.96,63.53 PC118.2 ; v1(143.86,58.19) 144.34,57.71 C242.1 ; PR111.2 v1(92.96,62) ; v1(57.22,66.33) 57.75,66.33 57.89,66.19 R285.1 ; PR171.2 37.93,16.66 v1(37.94,16.66) ; PR151.1 36.98,41.66 38.5,41.66 v1(38.78,41.94) ; PR177.2 v1(66.29,15.65) ; PQ12.1 38.32,65.3 v1(38.6,65.58) ; PC132.1 113.2,59.83 113.98,60.61 PC133.2 113.71,61.05 113.71,62.88 v1(113.72,62.89) 113.77,62.94 PC116.1 ; v1(52.39,60.45) 52.29,60.55 C233.2 50.97,60.55 50.77,60.35 C232.2 ; C205.1 77.61,63.79 v1(77.24,63.42) 76.88,63.78 C194.1 ; C274.1 139.09,49.81 v1(138.93,49.97) ; v1(38.19,23.57) 38.57,23.95 PU15.6 ; v1(85.12,24.91) 84.48,25.55 C325.2 ; v1(40.4,16.69) 41.16,16.69 PC188.1 ; v1(53.18,40.67) 53.68,41.16 PC171.2 PC172.2 ; R21.1 23.16,83.77 v1(23.21,83.72) ; C220.1 74.22,62.13 R299.1 75.27,61.57 v1(75.19,61.49) 75.19,61.38 75.71,60.87 R314.2 ; R414.2 22.31,9.81 v1(22.06,10.06) ; v1(144.71,44.31) 145.06,43.97 R362.1 ; R355.2 14.09,36.75 14.49,36.36 PC202.2 14.49,35.45 v1(14.24,35.2) ; v1(59.02,85.62) 59.02,86.12 R220.1 ; PD11.2 v1(75.66,17.81) ; v1(129.63,70.63) 129.6,70.59 129.6,70.07 129.26,69.73 PC109.2 128.9,70.64 128.74,70.79 128.74,71.4 129.39,72.04 PC98.2 ; v1(77.93,66.25) 77.79,66.4 R270.1 ; PC168.1 25.51,43.09 v1(25.47,43.13) ; PC129.1 46.43,61.94 v1(46.24,62.13) ; HOLE19.6 HOLE19.1 ; C326.2 78.77,24.99 v1(78.39,24.99) ; C146.1 95.88,84.66 95.95,84.58 v3(95.95,84.53) ; PC159.2 v1(25.37,45.5) ; R234.2 v1(24.49,26.89) ; PC203.2 16.12,37.74 v1(16.12,37.8) ; v1(103.72,60.55) 103.72,59.23 103.46,58.97 R308.1 ; PC164.2 53.93,43.83 v1(55.34,45.24) ; v1(59.27,81.43) 59.27,81.94 Q17.2 ; C288.2 146.53,41.17 v1(147.51,41.17) ; C149.1 87.85,85.23 v1(87.85,84.68) ; v1(82.05,68.68) 81.52,68.68 R262.2 ; v1(86.68,18.44) 86.71,18.42 86.71,16.66 86.33,16.28 PC192.2 ; v1(56.83,56.44) 56.53,56.44 56.25,56.72 C255.2 ; PQ15.1 38.22,60.31 v1(38.22,59.49) ; v1(44.03,12.98) 43.86,13.15 CN18.10 ; v1(24.38,53.45) 23.97,53.05 PR130.2 ; Q33.1 136.82,46.96 v1(136.82,47.4) ; v1(35.27,57.68) PC143.2 ; C335.2 v1(35.3,7.76) ; PC187.1 85.82,17.7 v1(85.82,18.44) ; v1(48.84,14.58) 48.74,14.67 CN18.4 ; v1(69.87,86.46) Q15.1 ; v1(76.26,73.86) 75.9,74.22 C161.2 ; HOLE14.1 6.64,15.5 HOLE14.4 ; PC186.2 v1(33.24,20.6) ; C200.1 C199.1 82.39,64.32 82.3,64.42 v1(82.02,64.42) ; PC191.2 v1(74.13,19.46) ; v1(98.92,2.29) 98.56,2.65 SW8.2 ; PR136.2 PC152.2 ; PC152.2 146.15,49.54 R343.2 ; PC152.2 145.33,49.55 144.03,48.24 144.03,48.14 v1(143.63,47.75) ; C358.1 v1(58.06,13.15) ; v1(51.4,43.23) 51.53,43.1 PC166.2 ; PQ23.1 24.54,54.25 v1(24.36,54.08) ; v1(40.94,47.24) 40.97,47.21 PC155.1 ; v1(119.78,63.55) 119.78,63.5 119.37,63.09 PC127.2 ; C256.2 88.63,56.28 87.91,55.56 86.14,55.56 85.28,56.41 v1(85.28,56.74) ; v1(43.63,26.44) 43.93,26.44 44.26,26.11 PC183.1 ; PQ24.1 148.07,53.17 v1(148.8,52.44) ; v1(78.1,7.29) 78.85,6.54 PJ7.9 ; v1(39.59,55.52) 40.11,55.52 PC119.1 ; v1(101.31,60.55) 101.31,60.6 100.68,61.24 C222.1 ; v1(134.51,69.11) 134.51,69.29 135.86,70.65 PC103.2 ; v1(129.63,49.15) 129.35,49.43 PQ26.1 ; C331.2 56.8,15.04 v1(56.68,14.91) ; C332.2 37.68,9.67 v1(37.68,9.17) ; v1(37.18,18.82) 37.3,18.95 PU15.4 ; PC145.1 112.36,55.43 v1(112.36,54.51) ; C338.1 46.74,19.58 v1(46.22,19.58) 45.05,19.58 PQ36.1 ; v1(38.12,42.32) 37.33,43.1 36.6,43.1 PC167.1 ; CN16.34 47.1,72.89 v1(46.07,71.86) ; C223.1 102.07,60.98 v1(102.07,60.55) ; v1(102.71,58.32) 102.71,58.31 C248.1 C258.1 ; PC189.2 81.75,17.43 81.75,18.57 v1(82.01,18.82) ; v1(42.99,75.36) 42.99,74.84 42.6,74.45 CN16.33 42.34,73.54 41.11,72.31 v1(41.11,72.03) ; PC99.2 131.41,72.96 ; 131.41,72.96 131.41,73.52 131.4,73.53 131.39,73.53 v1(131.28,73.63) ; 131.41,72.96 PC100.2 ; v1(104.87,2.31) 104.53,2.65 SW8.4 ; v1(134.84,41.3) 135.47,41.3 Q34.1 ; PJ7.10 v1(58.29,8.81) ; v1(93.18,56.64) 92.57,56.03 C261.2 ; v1(101.57,2.31) 100.98,2.31 100.6,1.93 SW8.6 ; v1(127.22,54.31) 127.38,54.47 127.38,55.94 128.88,57.44 PC140.2 ; C164.1 142.21,73.49 v1(141.27,72.54) ; v1(135.35,60.99) 135.22,60.99 134.58,60.34 C238.1 ; Q36.1 v1(131.82,36.35) ; U22.4 131.79,47.9 131.61,47.73 v1(131.61,47.37) ; v1(92.92,62.83) 92.49,62.83 PR106.1 ; R329.2 150.46,53.3 v1(149.72,52.57) ; v1(148.61,37.08) 148.86,37.08 149.61,36.34 PC176.1 ; v1(115.75,60.1) 115.43,60.41 PC130.2 ; PC163.1 47.11,44.62 47.11,43.84 47.44,43.51 PC169.1 v1(46.58,43.1) ; PU15.5 37.3,24.51 v1(37.71,24.1) ; v1(62.75,67.77) 62.98,67.77 63.23,67.52 C217.1 ; PC139.2 48.29,57.21 48.63,57.56 v1(48.91,57.56) ; C319.2 75.86,25.98 76.1,25.73 v1(76.1,24.91) ; PC205.2 16.4,44.4 v1(17.57,43.23) 18.05,42.75 PC200.1 ; C228.2 142.84,60.73 v1(142.71,60.6) ; PD12.2 v1(72.61,17.81) ; U19.2 84.24,86.64 84.9,85.98 v1(84.9,84.68) ; PC126.2 PC134.2 132.58,60.22 v1(133.06,60.71) ; v1(146.04,55.59) 145.73,55.27 PQ22.1 ; v1(51.93,19.79) 51.93,18.75 51.65,18.46 C329.1 ; PC178.1 v1(161.77,31.28) ; PC146.1 120.85,54.03 v1(120.85,53.62) ; R221.2 62.09,82.14 62.75,81.48 v1(63.34,81.48) ; v1(129.56,44.48) 129.01,45.03 PR143.2 ; v1(140.55,54.76) 141.06,55.27 PQ21.1 ; C323.2 81.19,25.03 v1(81.31,24.91) ; 62.81,42.88 C277.1 ; PC120.2 116.59,63.03 116.05,62.49 v1(116.05,62.2) ; G7.2 36.29,2.87 36.01,2.59 35.2,2.59 v3(34.99,2.39) ; v1(35.2,63.27) 35.86,63.27 Q28.1 ; v1(63.39,24.94) 63.72,24.61 Q45.1 ; v1(79.35,73.99) C162.1 ; v1(55.67,69.88) 55.41,69.88 55.13,70.16 R254.2 ; PC170.2 v1(23.49,41.3) ; PC190.2 v1(70.97,17.45) ; v1(147.51,41.78) 147.46,41.78 147.44,41.81 R368.2 ; C231.1 72.81,61.11 C209.2 ; R372.1 v1(122.77,40.28) ; v1(148.81,30.38) 150.34,28.85 CN17.25 ; C336.2 38.32,8.8 v1(38.32,9.17) ; C210.2 C202.1 31.59,63.17 31.39,62.97 v1(30.7,62.97) ; PC196.1 v1(85.31,12.8) ; v1(67.06,29.18) 66.51,28.63 66.51,27.89 66,27.37 C318.2 66,26.53 C328.2 ; PC158.1 v1(58.46,45.36) PC157.2 ; v1(38.4,56.97) PQ20.1 ; G6.2 v1(30.95,12.34) ; CN18.9 v1(52.59,13.15) ; v1(112.61,67.79) 112.61,66.7 113.12,66.19 113.5,66.19 113.77,65.93 PC112.1 ; v1(156.68,26.96) PC182.2
  vias: v1(9.11,10.19) v1(16.6,12.73) v1(20.31,76.23) v1(20.33,75.04) v1(20.29,74.02) v1(20.34,72.67) v1(20.64,34.14) v1(21.58,76.23) v1(21.6,75.04) v1(21.68,74.02) v1(21.68,72.67) v1(22.85,76.23) v1(22.87,75.04) v1(23.86,76.23) v1(23.89,75.04) v1(27.14,35.05) v1(27.47,33.78) v1(27.88,36.14) v1(28.45,31.32) v1(29.05,70.74) v1(29.05,70.13) v1(29.56,55.58) v1(29.56,54.89) v1(29.79,70.13) v1(29.91,42.95) v1(29.91,41.99) v1(30.12,12.34) v1(30.55,74.45) v1(30.55,73.84) v1(30.5,55.19) v1(30.8,70.13) v1(30.78,42.39) v1(31,40.41) v1(31.36,55.58) v1(31.41,54.81) v1(31.66,42.95) v1(31.66,41.99) v1(31.66,40.41) v1(31.84,35.84) v1(31.84,35.08) v1(32.6,35.84) v1(32.6,35.08) v1(33.75,54.51) v1(34.38,54.51) v1(34.66,72.31) v1(34.97,9.96) v1(35.02,54.51) v1(35.24,73.16) v1(35.63,9.96) v1(35.78,69.41) v1(36.16,68.88) v1(36.29,74.19) v1(37.35,46.89) v1(37.35,46.28) v1(37.28,34.75) v1(37.28,34.14) v1(37.28,33.53) v1(39.41,71.4) v1(40.78,71.35) v1(41.62,34.19) v1(41.62,33.48) v1(41.62,32.69) v1(41.88,27.86) v1(41.9,27.25) v1(42.71,71.27) v1(43.53,53.65) v1(43.68,54.28) v1(48.25,38.56) v1(48.42,31.85) v1(48.49,30.52) v1(50.13,57.94) v1(50.89,75.29) v1(50.89,74.19) v1(50.92,66.32) v1(51.08,30.47) v1(51.53,75.29) v1(51.53,74.19) v1(51.53,73.56) v1(51.95,29.76) v1(52.35,67.47) v1(52.39,31.64) v1(53.45,29.94) v1(53.62,31.28) v1(53.88,28.39) v1(55.39,30.64) v1(55.68,29.02) v1(56.5,73.84) v1(56.65,60.3) v1(56.98,39.4) v1(57.16,73.84) v1(57.15,31.88) v1(57.21,29.31) v1(57.83,75.97) v1(57.82,73.84) v1(58.81,50.42) v1(58.84,30.49) v1(59.05,41.45) v1(59.09,51.74) v1(59.15,47.14) v1(59.55,69.32) v1(59.73,62.48) v1(59.76,55.63) v1(60.04,74.6) v1(59.98,47.17) v1(60.04,38.37) v1(60.18,69.32) v1(60.45,68.42) v1(60.47,63.4) v1(60.45,57.5) v1(60.45,55.63) v1(60.39,42.86) v1(60.52,31.88) v1(60.75,70.05) v1(60.84,69.32) v1(61.16,57.5) v1(61.16,55.63) v1(61.18,63.4) v1(61.31,85.78) v1(61.5,39.68) v1(61.79,72.03) v1(61.81,63.4) v1(61.79,59.56) v1(61.87,57.48) v1(61.87,55.63) v1(62.05,30.82) v1(62.45,40.64) v1(62.46,28.21) v1(62.59,57.46) v1(62.59,55.63) v1(62.73,70.03) v1(62.7,68.38) v1(62.74,52.48) v1(62.74,51.81) v1(62.74,51.1) v1(62.74,50.39) v1(62.74,49.72) v1(62.74,49.07) v1(63.3,57.47) v1(63.3,55.63) v1(63.69,68.53) v1(63.74,51.11) v1(63.74,50.46) v1(63.71,31.72) v1(64.01,55.63) v1(64.08,57.51) v1(64.51,91.04) v1(64.58,78.23) v1(64.71,71.93) v1(64.71,71.3) v1(64.71,53.12) v1(64.71,52.5) v1(64.71,51.81) v1(64.71,51.1) v1(65.64,57.09) v1(66.42,63.91) v1(66.56,52.53) v1(66.63,71.86) v1(66.63,69.9) v1(66.61,51.23) v1(66.77,90.83) v1(67.15,78.33) v1(67.2,57.84) v1(67.21,57.11) v1(67.29,30.96) v1(67.91,90.45) v1(68,31.82) v1(68.09,77.09) v1(68.54,49.71) v1(68.58,50.36) v1(68.78,61.64) v1(69.14,29.18) v1(69.51,6.63) v1(70.34,64.67) v1(70.34,61.64) v1(70.34,58.6) v1(70.35,57.07) v1(70.51,32.17) v1(70.51,29.19) v1(71.25,36.06) v1(71.34,90.96) v1(71.54,54.6) v1(71.54,53.29) v1(71.51,51.79) v1(71.52,6.66) v1(71.86,36.88) v1(71.91,57.88) v1(72.08,29.22) v1(72.27,36.37) v1(72.18,14.76) v1(72.46,69.8) v1(72.46,69.16) v1(72.46,68.52) v1(72.43,31.87) v1(72.61,51.82) v1(73.19,44.13) v1(73.19,42.19) v1(74.26,65.43) v1(74.17,29.9) v1(74.38,54.76) v1(74.53,55.63) v1(74.49,28.25) v1(74.62,13.46) v1(74.94,41.96) v1(75.05,57.61) v1(75.01,30.76) v1(75.09,45.2) v1(75.09,43.26) v1(75.25,13.46) v1(75.4,71.27) v1(75.89,13.46) v1(76.06,12.87) v1(76.15,36.01) v1(76.46,28.98) v1(76.64,36.44) v1(77.08,78.11) v1(77.11,58.57) v1(77.35,71.25) v1(77.33,59.51) v1(77.87,31.91) v1(77.88,29.41) v1(78.1,59.54) v1(78.73,57.56) v1(78.83,80.82) v1(78.83,79.43) v1(79.04,32.22) v1(79.34,57.66) v1(79.32,28.81) v1(79.42,30.51) v1(79.7,71.15) v1(79.94,36) v1(80.12,36.65) v1(80.56,14.86) v1(80.56,14.25) v1(80.67,28.67) v1(81.34,73.92) v1(81.45,14.86) v1(81.45,14.25) v1(81.95,44.58) v1(81.95,42.61) v1(81.92,28.62) v1(82.36,9.55) v1(82.52,30.63) v1(82.97,48.31) v1(83.13,9.55) v1(83.48,47.8) v1(83.67,28.72) v1(84.03,56.57) v1(84.95,36.73) v1(84.95,36.09) v1(84.94,35.4) v1(84.94,34.75) v1(85.48,45.65) v1(85.63,51.36) v1(85.76,43.7) v1(86.52,28.45) v1(86.77,31.42) v1(87.24,66.6) v1(87.18,50.6) v1(87.65,78.49) v1(88.3,49.51) v1(88.97,77.88) v1(88.9,54.7) v1(89.22,47.78) v1(89.25,30.89) v1(89.91,16.54) v1(89.98,17.75) v1(90.87,14.3) v1(91.22,31.72) v1(91.22,29.08) v1(91.6,52) v1(93.5,29.86) v1(94.77,30.01) v1(96.26,58.78) v1(96.58,29.38) v1(97.93,29.08) v1(98.3,31.72) v1(98.82,59.87) v1(99.98,31.13) v1(100.25,30.18) v1(101.18,58.32) v1(101.69,89.81) v1(102.14,29.36) v1(102.33,89.81) v1(102.71,67.08) v1(102.73,66.47) v1(102.68,31.45) v1(103.34,67.08) v1(103.37,66.47) v1(103.92,29.92) v1(103.98,67.08) v1(104,66.47) v1(104.61,67.08) v1(104.64,66.47) v1(104.87,63.55) v1(104.97,42.95) v1(104.94,42.19) v1(105.27,66.47) v1(105.57,30.63) v1(105.78,43.18) v1(105.78,42.55) v1(105.78,41.94) v1(105.78,41.3) v1(107.15,30.51) v1(107.34,29.12) v1(108.3,33.17) v1(111.6,40.28) v1(111.6,39.65) v1(111.6,39.01) v1(111.6,38.38) v1(112.13,39.32) v1(112.36,53.49) v1(113.12,54.51) v1(113.12,53.49) v1(113.74,19.26) v1(113.86,22.05) v1(113.88,54.51) v1(113.88,53.49) v1(114.04,17.42) v1(114.35,22.54) v1(114.33,19.83) v1(114.56,17.87) v1(116.37,50.03) v1(116.39,50.66) v1(117.44,50.38) v1(118.2,50.83) v1(123.79,87.29) v1(124.26,86.83) v1(124.79,86.3) v1(125.22,85.87) v1(126.34,82.22) v1(126.71,66.04) v1(126.76,65.08) v1(126.79,64.34) v1(127.73,66.04) v1(127.71,65.08) v1(127.75,64.31) v1(127.77,35.36) v1(128.49,27.33) v1(128.49,26.7) v1(128.69,66.04) v1(128.69,65.08) v1(128.72,64.34) v1(129.12,27.33) v1(129.12,26.7) v1(131,68.81) v1(136.49,24.28) v1(137.13,24.28) v1(138.65,65.81) v1(139.54,65.18) v1(139.51,34.44) v1(139.79,61.11) v1(139.79,13.94) v1(140.17,65.18) v1(140.94,27.18) v1(141.14,35.46) v1(141.57,27.18) v1(142.21,27.18) v1(142.84,27.18) v1(143.81,35.32) v1(144.77,38.86) v1(145.1,63.37) v1(145.2,61.49) v1(145.25,27.48) v1(146.02,62.51) v1(146.68,55.65) v1(146.93,63.45) v1(146.93,61.49) v1(147.06,58.9) v1(146.98,35.46) v1(147.67,75.31) v1(151.6,73.94) v1(151.86,64.16) v1(152.31,64.62) v1(153.03,71.55) v1(154.74,80.65) v1(154.74,80.04) v1(155.37,80.65) v1(155.37,80.04) v1(155.67,32.54) v1(156.05,27.58) v1(156.05,26.95) v1(156.68,27.58) v1(159.22,12.73) v1(159.22,12.09) v1(159.86,12.73) v1(159.86,12.09) v1(161.89,39.01) v1(161.94,38.2) v1(161.94,37.44) v1(161.94,36.73) v1(162.44,84.02) v1(162.42,29.74) v1(163.49,83.21) v1(164.77,72.42) v1(165.89,80.21) v2(5.3,25.6) v2(23.71,1.7) v2(30.42,28.79) v2(35.25,6.78) v2(35.45,1.73) v2(53.94,37.11) v2(60.21,25.81) v2(64.5,50.42) v2(71.43,37.54) v2(73.7,47.3) v2(80.34,37.59) v2(90.36,43.76) v2(91.66,45.36) v2(105.5,67.21) v2(106.39,75.72) v2(111.07,2.74) v2(111.73,2.74) v2(118.38,72.52) v2(118.41,10.08) v2(120.36,76.61) v2(121.96,74.35) v2(138.75,67.34) v2(143.93,93.52) v2(155.39,79.02) v2(155.57,30.4) v2(156.02,30.68) v2(156.2,3) v2(156.56,5.79) v3(3.83,62.33) v3(4.06,60.81) v3(4.13,59.06) v3(4.16,57.79) v3(4.16,56.31) v3(4.16,53.49) v3(4.16,52.22) v3(4.16,50.95) v3(4.16,49.68) v3(4.16,48.41) v3(4.16,47.14) v3(4.16,45.87) v3(4.16,44.6) v3(4.16,43.33) v3(4.16,42.06) v3(4.16,40.79) v3(4.16,39.52) v3(4.16,38.25) v3(4.16,36.98) v3(4.16,35.71) v3(4.16,34.44) v3(4.16,33.17) v3(4.16,31.9) v3(4.16,30.63) v3(4.16,29.36) v3(4.16,28.32) v3(4.16,25.55) v3(4.79,24.54) v3(5.35,7.77) v3(5.35,6.5) v3(5.35,5.23) v3(5.43,3.96) v3(5.43,2.69) v3(5.55,1.68) v3(5.78,62.31) v3(6.06,24.54) v3(6.11,25.86) v3(6.19,0.91) v3(6.87,61.19) v3(7.26,24.28) v3(7.46,0.91) v3(7.74,22.12) v3(8.09,23.39) v3(8.73,0.91) v3(10,0.91) v3(11.27,0.91) v3(12.54,0.91) v3(13.81,0.91) v3(15.08,0.91) v3(16.35,0.91) v3(17.62,0.91) v3(18.89,0.91) v3(20.16,0.91) v3(21.43,0.91) v3(22.7,0.91) v3(22.83,86.26) v3(23.46,87.53) v3(23.59,88.93) v3(23.97,0.91) v3(24.2,2.36) v3(24.73,89.56) v3(26,89.56) v3(27.27,89.56) v3(28.43,30.58) v3(28.54,89.56) v3(29.15,30.58) v3(29.18,31.32) v3(29.9,31.32) v3(29.9,30.58) v3(33.24,89.56) v3(35.4,0.91) v3(36.67,0.91) v3(37.08,86.49) v3(37.18,89.31) v3(37.18,87.91) v3(37.53,84.76) v3(37.94,0.91) v3(38.62,83.44) v3(39.21,0.91) v3(40.48,0.91) v3(40.89,82.6) v3(41.75,0.91) v3(42.97,82.6) v3(43.02,91.59) v3(43.02,90.35) v3(43.02,0.91) v3(44.29,0.91) v3(44.54,90.35) v3(44.67,91.72) v3(44.59,82.6) v3(45.56,0.91) v3(46.47,82.78) v3(46.83,0.91) v3(47.74,83.62) v3(48.1,0.91) v3(48.45,84.96) v3(48.48,86.39) v3(49.24,97.56) v3(49.37,0.91) v3(49.5,100.48) v3(49.5,99.09) v3(49.75,101.63) v3(50.64,0.91) v3(51.15,102.13) v3(51.91,0.91) v3(52.54,102.13) v3(53.18,0.91) v3(53.94,102.13) v3(54.45,0.91) v3(55.72,102.13) v3(55.72,0.91) v3(56.23,96.04) v3(56.61,101.12) v3(56.61,97.56) v3(56.99,0.91) v3(58.26,0.91) v3(59.53,0.91) v3(60.8,0.91) v3(62.07,0.91) v3(63.34,0.91) v3(64.61,0.91) v3(65.88,0.91) v3(67.15,0.91) v3(68.55,0.91) v3(69.82,0.91) v3(71.09,0.91) v3(72.36,0.91) v3(73.63,0.91) v3(74.01,94.26) v3(74.26,100.99) v3(74.26,97.94) v3(74.26,96.67) v3(74.77,95.28) v3(74.9,0.91) v3(75.02,102.01) v3(76.17,0.91) v3(76.29,102.01) v3(77.44,0.91) v3(77.56,102.01) v3(78.71,0.91) v3(78.83,102.01) v3(79.98,0.91) v3(80.1,102.01) v3(81.25,101.5) v3(81.25,97.69) v3(81.25,96.42) v3(81.25,95.15) v3(81.25,0.91) v3(82.52,0.91) v3(82.64,91.47) v3(83.79,0.91) v3(84.42,91.97) v3(85.06,0.91) v3(86.33,0.91) v3(86.76,91.97) v3(87.6,0.91) v3(88.87,0.91) v3(90.14,0.91) v3(91.41,0.91) v3(92.68,0.91) v3(93.95,0.91) v3(95.22,0.91) v3(95.95,83.79) v3(96.38,85.12) v3(96.49,0.91) v3(96.74,84.4) v3(96.71,83.67) v3(96.87,97.69) v3(96.87,96.42) v3(96.87,95.15) v3(97.12,85.06) v3(97.53,84.38) v3(97.76,0.91) v3(97.91,85.04) v3(98.64,94.64) v3(99.03,0.91) v3(99.28,97.43) v3(99.28,96.04) v3(100.3,0.91) v3(100.55,93.12) v3(101.57,0.91) v3(101.82,93.12) v3(102.07,74.96) v3(102.07,74.19) v3(102.1,73.41) v3(102.84,82.19) v3(102.84,81.43) v3(102.78,75.82) v3(102.78,75.06) v3(102.78,74.3) v3(102.84,0.91) v3(103.09,93.12) v3(103.5,75.44) v3(103.5,74.68) v3(103.6,82.19) v3(104.11,0.91) v3(104.26,81.13) v3(104.36,93.12) v3(104.46,81.84) v3(105.22,81.84) v3(105.38,0.91) v3(105.63,93.12) v3(106.65,0.91) v3(106.9,93.12) v3(107.92,0.91) v3(108.17,93.12) v3(109.19,0.91) v3(109.44,93.12) v3(110.46,0.91) v3(110.71,93.12) v3(111.73,0.91) v3(111.98,93.12) v3(113.25,93.12) v3(114.47,75.54) v3(114.44,74.73) v3(114.9,102.13) v3(114.9,100.86) v3(115.21,75.54) v3(115.18,74.73) v3(115.94,75.51) v3(115.92,74.7) v3(116.27,74.02) v3(116.65,74.7) v3(117.01,74.02) v3(117.36,74.7) v3(117.49,75.46) v3(118.15,74.75) v3(118.15,73.94) v3(118.2,75.46) v3(119.85,75.57) v3(119.85,74.85) v3(119.85,74.12) v3(119.83,73.38) v3(119.83,72.64) v3(119.83,71.91) v3(120.56,75.13) v3(120.56,74.42) v3(120.56,73.69) v3(120.54,72.95) v3(120.54,72.21) v3(120.51,71.43) v3(120.51,29.49) v3(120.67,9.65) v3(121.73,10.82) v3(121.91,32.11) v3(122.52,102.13) v3(122.65,32.11) v3(122.8,11.35) v3(123.79,102.13) v3(124.17,11.68) v3(125.44,11.68) v3(126.71,11.68) v3(127.98,11.68) v3(129.25,11.68) v3(130.52,11.68) v3(131.79,11.68) v3(133.06,11.68) v3(134.33,11.68) v3(135.6,11.68) v3(136.87,11.68) v3(138.14,11.68) v3(139.41,11.68) v3(140.68,11.68) v3(141.95,11.68) v3(143.22,101.24) v3(143.22,11.68) v3(144.49,11.68) v3(144.62,101.24) v3(145.63,88.93) v3(145.76,11.68) v3(145.89,101.24) v3(145.89,96.67) v3(145.89,95.4) v3(145.89,94.13) v3(145.89,92.86) v3(146.68,87.88) v3(147.03,11.68) v3(148.3,11.68) v3(149.57,11.68) v3(149.75,80.39) v3(150.84,11.68) v3(152.34,11.3) v3(153.48,10.47) v3(154.02,32.28) v3(154.02,31.52) v3(154.02,30.76) v3(154.52,8.53) v3(154.52,7.14) v3(154.52,5.87) v3(154.52,4.6) v3(154.52,3.33) v3(154.52,2.06) v3(154.73,30.81) v3(154.78,32.28) v3(154.78,31.52) v3(155.29,0.91) v3(157.22,0.89) v3(157.39,22.05) v3(157.39,21.23) v3(158.46,87.88) v3(159.44,96.6) v3(159.44,95.33) v3(159.44,94.06) v3(159.44,92.79) v3(159.4,52.48) v3(159.4,51.71) v3(159.4,50.95) v3(159.4,50.19) v3(159.48,101.37) v3(159.69,88.67) v3(160.16,52.48) v3(160.16,51.71) v3(160.16,50.95) v3(160.16,50.19) v3(160.16,42.82) v3(160.16,41.55) v3(160.16,40.28) v3(160.16,39.01) v3(160.72,17.17) v3(160.72,16.41) v3(160.75,15.6) v3(160.87,101.37) v3(162.27,101.37) v3(163.8,101.63) v3(164.94,102.13) v3(165.24,13.34) v3(165.24,11.4) v3(165.24,9.88) v3(165.32,70.05) v3(165.37,68.63) v3(165.37,67.31) v3(165.37,65.91) v3(165.73,57.35) v3(165.73,56.52) v3(165.73,55.25) v3(165.73,53.98) v3(165.73,52.71) v3(165.73,51.44) v3(165.73,50.17) v3(165.73,48.9) v3(165.73,47.63) v3(165.73,46.36) v3(165.73,45.09) v3(165.73,43.82) v3(165.73,42.55) v3(165.73,41.28) v3(165.73,40.01) v3(165.73,38.74) v3(165.73,37.47) v3(165.73,36.2) v3(165.73,34.93) v3(165.73,33.66) v3(165.73,32.39) v3(165.73,31.12) v3(165.73,29.85) v3(165.73,28.58) v3(165.73,27.31) v3(165.73,26.04) v3(165.73,24.77) v3(165.73,23.5) v3(165.73,22.23) v3(165.71,21.18) v3(166.69,0.91) v3(168.37,82.35)
V1P8_AA18_PEW: length 10.7
  TOP w0.254: U12.AA18 71.53,65.05 v1(71.91,65.43)
  IN2 w0.508: 80.64,67.87 81.19,68.42 81.19,68.83 82.24,69.88 v1(82.52,69.88) ; v1(71.91,65.43) 73.16,66.67 76.49,66.67
  BOTTOM w0.508: C170.2 81.92,69.88 v1(82.52,69.88) 82.52,70.6 R244.1
V1P8_S5_PWR: length 16
  TOP w0.254: U12.V25 73.1,61.26 v1(73.48,61.64) ; v1(75.82,63.43) 75.82,63.56 U12.N20 ; U12.U24 73.86,62.02 v1(73.48,61.64) ; U12.U25 73.86,61.26 v1(73.48,61.64)
  IN2 w0.381: v1(73.48,61.64) 73.51,61.64 74.63,62.76 75.29,62.76 75.82,63.3 v1(75.82,63.43)
  BOTTOM w0.508: v1(75.82,63.43) 76.37,63.43 76.98,62.81 77.62,62.81 77.82,63.01 C205.2 78.26,62.82 v1(79.01,62.82) 80.4,62.82 C207.2 80.74,63.15 80.74,63.53 80.99,63.78 81.96,63.78 82.19,63.54 C199.2 C200.2 83.86,63.67 84.03,63.67 84.72,64.37 R282.1
VCC_AXG_SENSE: length 8.7
  TOP w0.254: v1(61.74,69.39) 61.51,69.62 U12.BB8
  BOTTOM w0.254: PR78.1 59.38,75.71 v1(59.09,75.42) 59.09,75.19 59.41,74.87 R236.2 59.41,74.23 61.23,72.41 61.23,71.48 61.78,70.92 61.78,69.44 v1(61.74,69.39)
VCC_POR#: length 6.3
  TOP w0.102: v1(144.54,42.97) 144.54,42.5 143.92,41.88 143.92,41.27 144.49,40.7 144.49,40.34 144.2,40.05 U18.85
  BOTTOM w0.102: R366.1 144.69,42.82 v1(144.54,42.97)
VCC_SENSE: length 21.4
  TOP w0.254: U12.P28 74.76,59.83 v1(75.04,59.55)
  IN1 w0.254: v1(89.49,63.81) 89.5,63.8 89.5,63.49 87.85,61.84 87.85,61.49 86.71,60.35 85.48,60.35 84.52,59.39 81.85,59.39 80.66,58.19 78.66,58.19 78.05,57.58 76.06,57.58 75.83,57.81 75.48,58.16 75.48,59 75.04,59.45 v1(75.04,59.55)
  BOTTOM w0.254: PR100.1 v1(89.49,63.81) ; R296.2 74.99,60.65 74.99,59.6 v1(75.04,59.55)
VCCRTC_1: length 7.6
  BOTTOM w0.508: D36.1 32.69,10.48 31.56,11.61 v2(30.45,11.61) 30.12,11.61 29.71,11.2 29.71,8.92 29.45,8.65 R412.2
VCCRTC_2: length 11.7
  TOP w0.508: CN15.1 22.19,9.04 22.98,9.83 v1(23.46,9.83)
  BOTTOM w0.508: v1(23.46,9.83) Q39.1 24.38,11.28 25.06,11.96 26.05,11.96 26.07,11.99 26.64,11.99 26.67,11.96 27.8,11.96 28.46,11.3 v2(28.46,10.74) 29.05,10.16 R412.1
VCCRTC_3: length 3.8
  BOTTOM w0.508: v2(26.36,11.3) Q39.3 27.09,9.17 27.36,9.43 R418.2
VCCRTC_4: length 3
  BOTTOM w0.508: R418.1 v1(26.56,7.31) 25.67,7.31 R417.2
VCCSPI: length 9.4
  TOP w0.102: U18.88 141.11,41.25 140.63,41.73 140.63,42.11 140.1,42.65 v1(139.97,42.65)
  BOTTOM w0.102: R357.2 140.83,44.32 140.68,44.17 140.55,44.17 139.97,43.59 v1(139.97,42.65) 141.32,42.65 141.85,43.18 C284.2 v2(142.94,43.66)
VDD10: length 6.9
  TOP w0.203: U11.8 142.2,61.11 v1(142.08,60.99) ; U11.22 148.68,63.11 148.74,63.17 149.52,63.17 v1(149.65,63.04) ; U11.30 145.42,65.5 v1(145.36,65.56) ; v1(141.95,64.16) 143,63.11 U11.3
  vias: v1(149.7,63.65) v1(150.08,69.62) v1(150.59,70) v2(146.68,67.46)
VDD_3V3_MIC1: length 8.2
  TOP w0.508: 76.06,82.88 R34.1 ; 76.06,82.88 v2(75.61,82.42) 75.35,82.17 C16.2 C19.2 73.22,81.11 L1.1 ; 76.06,82.88 76.06,84.63 76.04,84.66 U3.6
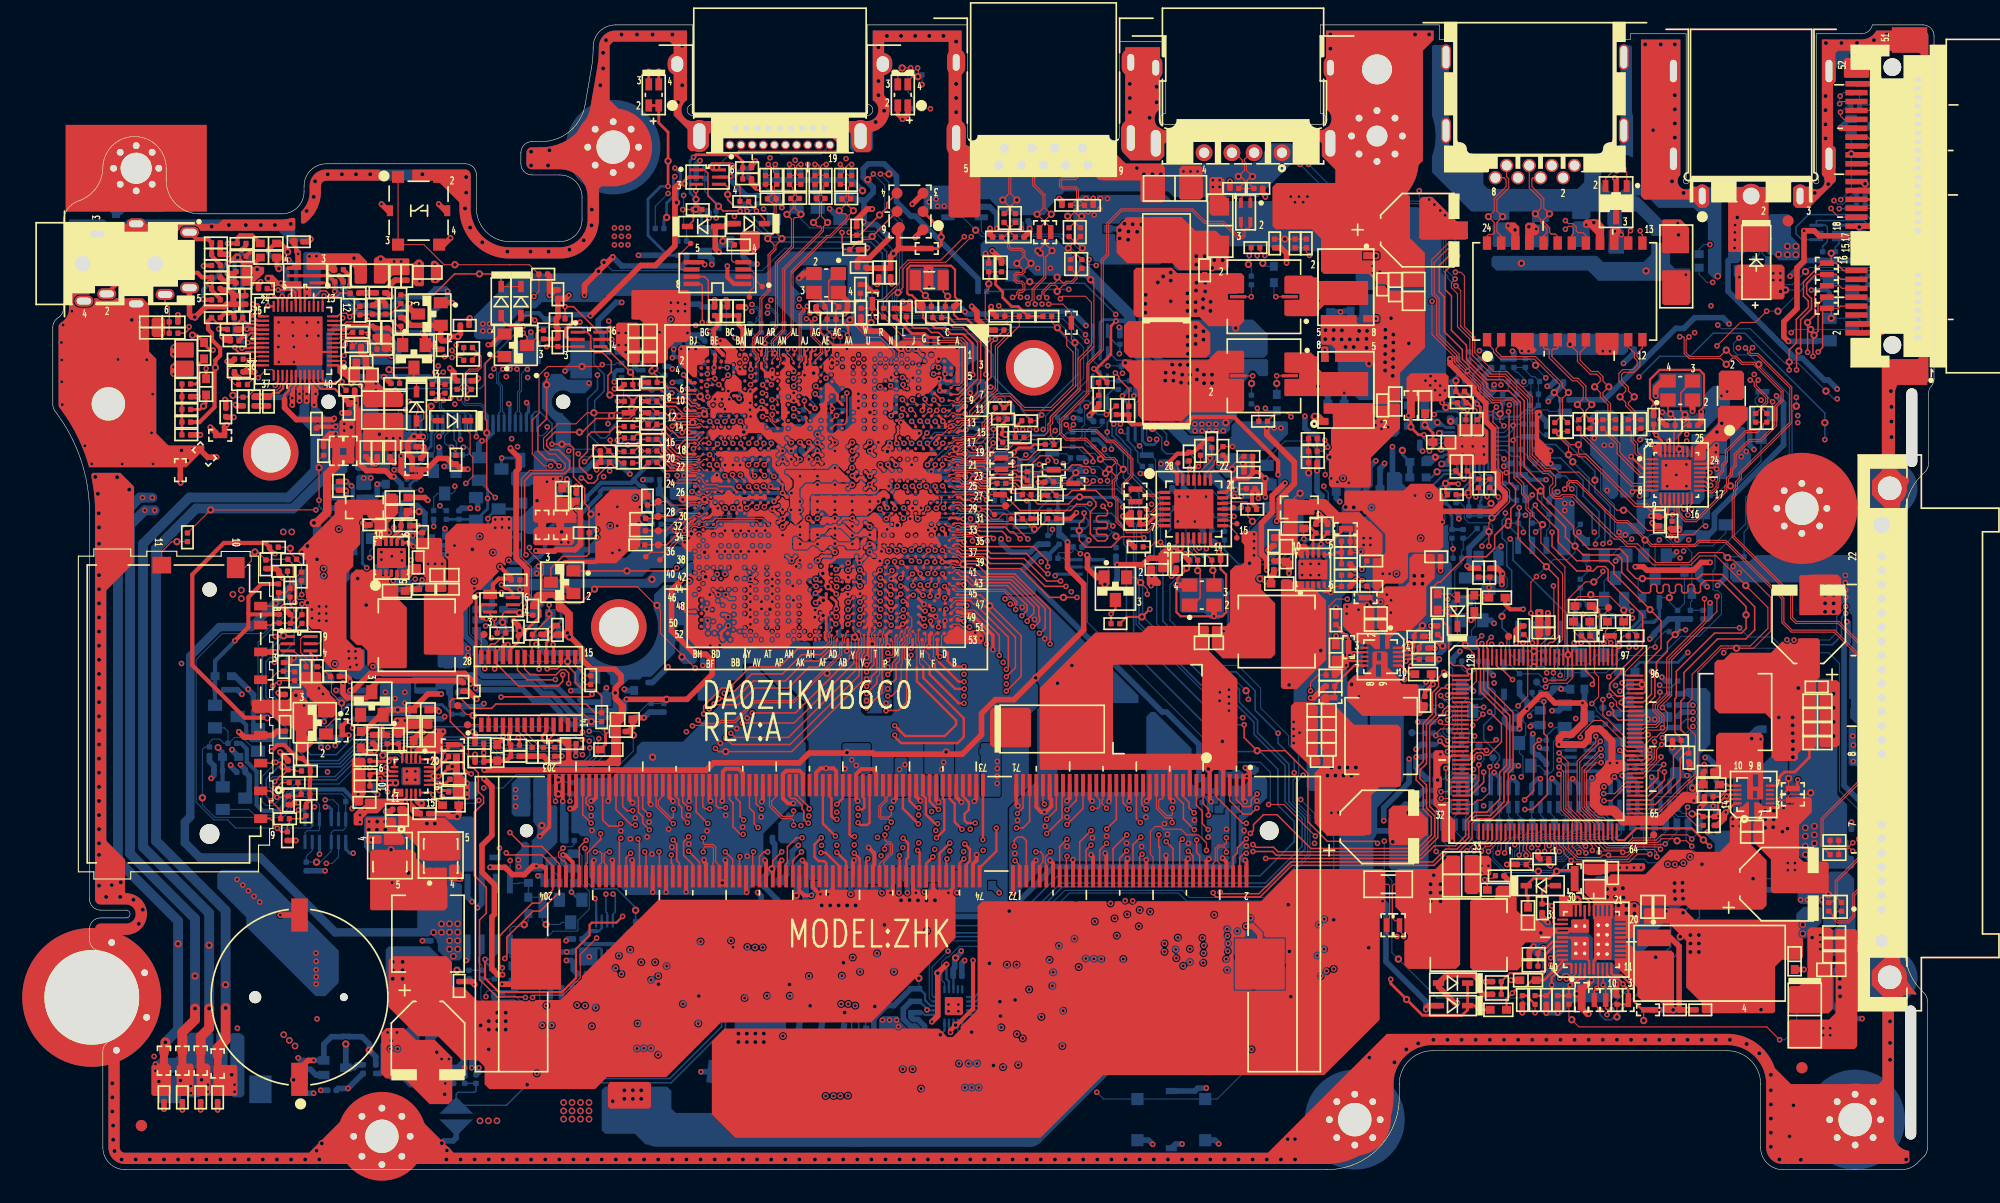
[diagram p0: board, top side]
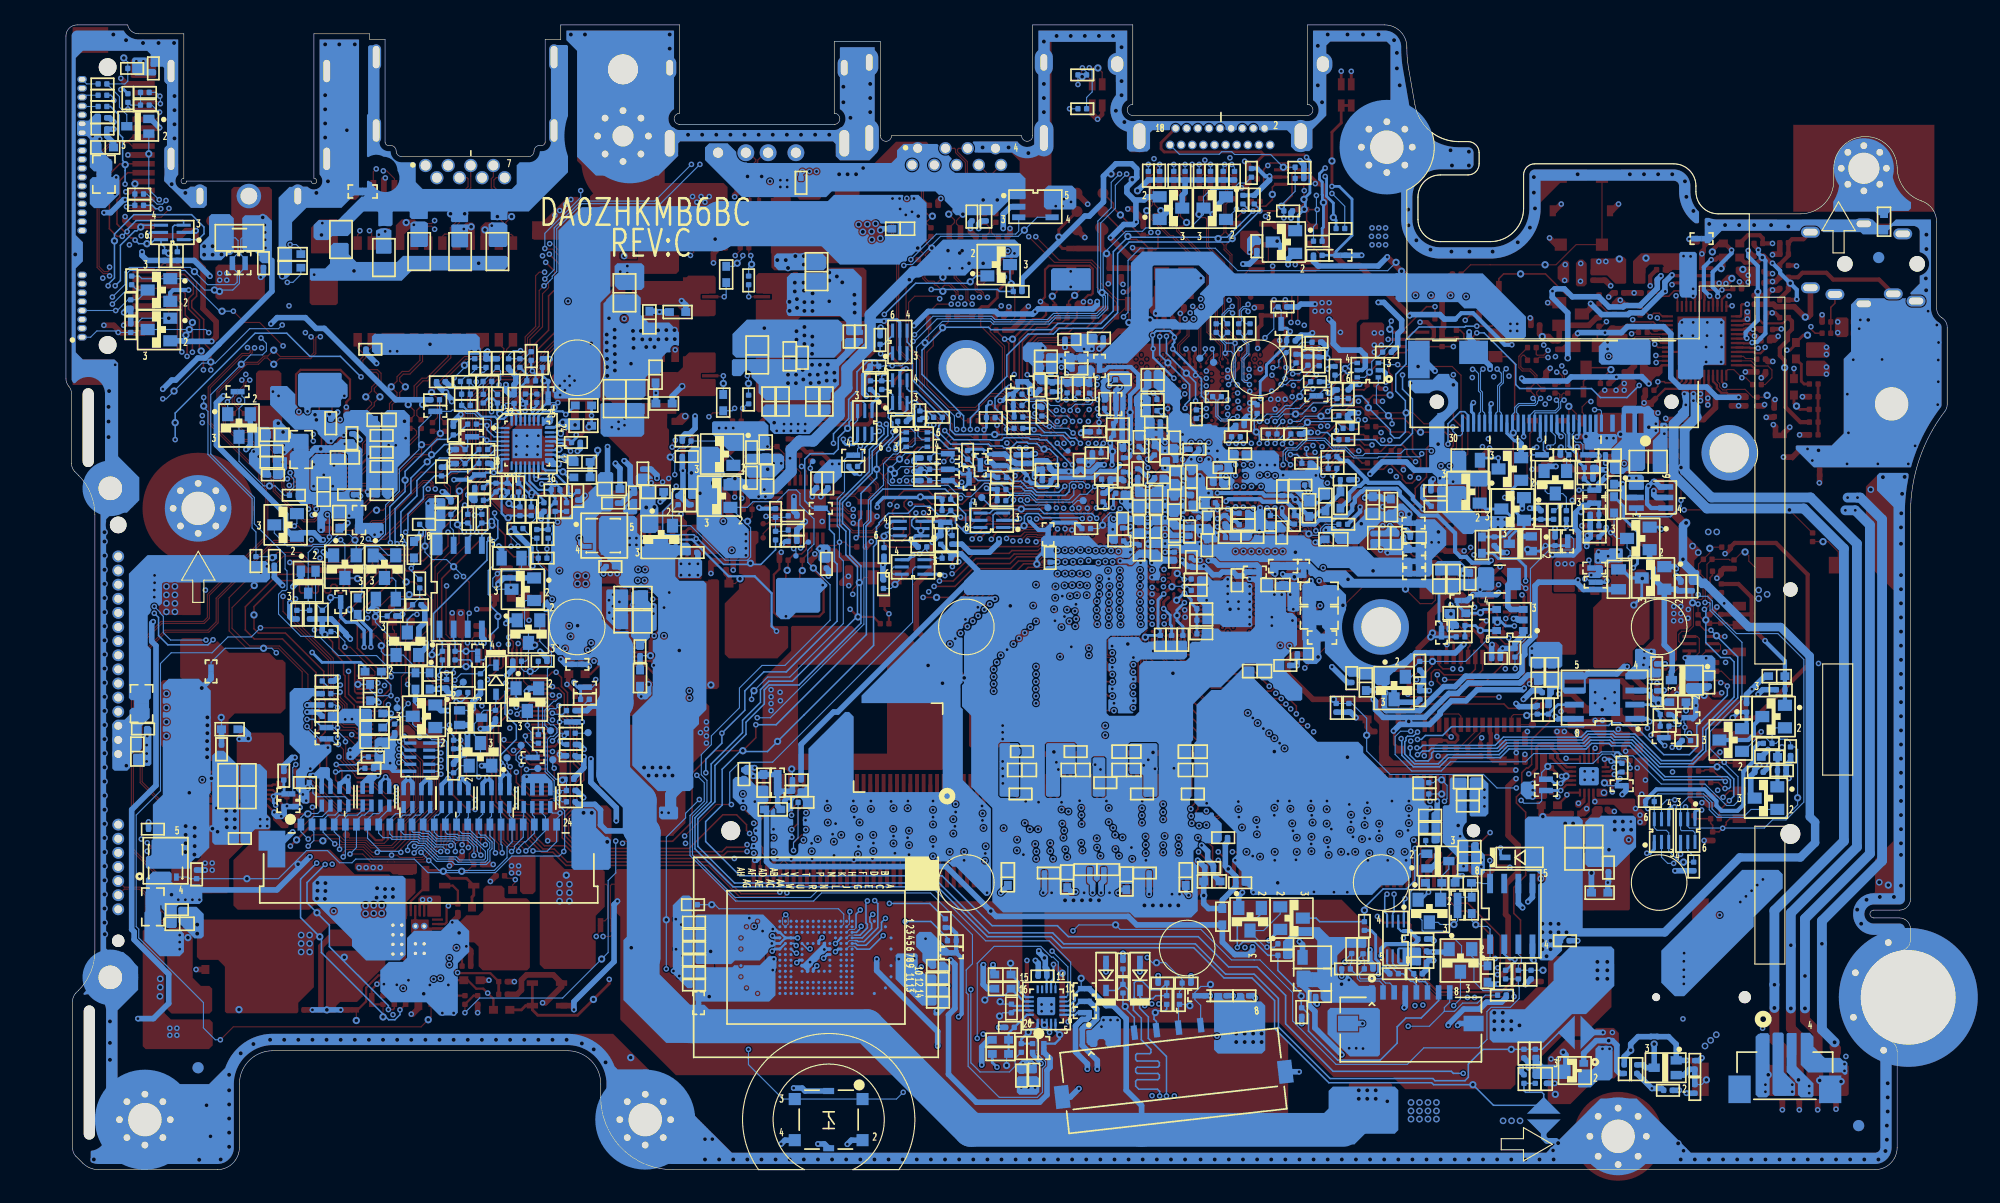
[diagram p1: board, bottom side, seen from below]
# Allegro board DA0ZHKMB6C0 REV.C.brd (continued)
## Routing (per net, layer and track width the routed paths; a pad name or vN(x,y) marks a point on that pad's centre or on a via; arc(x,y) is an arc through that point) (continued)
VDDI_DSC: length 14.8
  BOTTOM w0.076: U30.K2 99.24,22.1 99.24,22.62
  BOTTOM w0.102: C272.2 v2(111.12,23.84) 110.83,23.84 110.46,23.47 99.73,23.47 99.24,22.99 99.24,22.62
VDDREG/VDD33:
  vias: v1(149.62,65.18) v1(149.57,64.54) v2(150.11,67.16)
VSS_AD18_AD16_PWR: length 3.1
  TOP w0.254: U12.AD18 69.97,65.05 v1(70.34,65.43) 69.96,65.81 U12.AD16
  BOTTOM w0.508: C181.2 R272.1 70.77,65.85 v1(70.34,65.43)
VSS_AXG_SENSE: length 2
  BOTTOM w0.254: R290.1 88.4,61.37 88.84,61.37 88.89,61.42 88.91,61.42 PR110.1
VSS_SENSE: length 21.3
  TOP w0.254: U12.N28 75.73,59.76 v1(75.73,59.49)
  IN1 w0.254: v1(75.73,59.49) 75.86,59.36 75.86,58.32 75.99,58.19 76.22,57.96 77.89,57.96 78.5,58.57 80.5,58.57 81.69,59.77 84.36,59.77 85.33,60.73 86.55,60.73 87.47,61.65 87.47,62 88.74,63.27 88.74,63.45 v1(88.73,63.46)
  BOTTOM w0.254: v1(75.73,59.49) 75.73,59.49 75.71,59.51 75.71,59.89 R314.1 ; v1(88.73,63.46) 88.41,63.46 87.98,63.02 R290.2 88.6,62.57 89.04,63.02 PR105.1
554EN_1.0V:
  vias: v1(32.02,53.49)
554EN_1.8V: length 2.9
  TOP w0.102: PR32.2 PC38.2 115.41,52.48 115.27,52.34 114.77,52.34 114.71,52.27 114.5,52.27 114.35,52.43 PU7.5
554FB_1.0V: length 4.1
  TOP w0.305: v1(32.43,56.08) 32.12,56.39 PU6.6
  BOTTOM w0.508: v1(32.43,56.08) 32.43,56.6 PR122.1 PR120.2 PC138.1
554FB_1.0V_S: length 2
  BOTTOM w0.305: PR120.1 PC138.2 31.33,59.94 PR114.1
554FB_1.8V: length 3.7
  TOP w0.254: PU7.6 115.15,55.34 115.34,55.52 PC30.1 ; PC30.1 PR29.1 ; PC30.1 PR27.2
554FB_1.8V_S: length 3.1
  TOP w0.102: PC30.2 117.57,55.52 v1(117.64,55.6)
  TOP w0.254: PC30.2 PR27.1 PR26.1
554LX_1.0V:
  vias: v2(27.42,53.19)
554LX_1.8V:
  vias: v2(111.19,43.61)
554NC_1.0V: length 2.9
  TOP w0.305: PC29.2 32.63,57.31 v1(32.38,57.05) 31.31,57.05 30.96,56.7 PU6.7
554NC_1.8V: length 2.3
  TOP w0.254: PC26.2 114.07,56.71 v1(114.07,56.29) 113.85,56.07 PU7.7
554PG_1.0V: length 1.5
  TOP w0.305: PU6.4 30.96,53.3 30.63,52.98 v1(30.62,52.98)
  BOTTOM w0.305: v1(30.62,52.98) 30.75,52.86 PR128.2
554PG_1.8V: length 4.5
  TOP w0.102: PU7.4 113.85,52.39 114.31,51.93 v1(114.94,51.93) 117.22,51.93 PR35.2
554SVIN_1.0V: length 4.4
  TOP w0.254: v2(32.93,59.21) PR24.2
  TOP w0.305: PR24.2 31.94,58.93 31.33,58.31 PC25.2 31.33,57.65 30.46,56.78 PU6.8
554SVIN_1.8V: length 4.2
  TOP w0.102: v1(112.52,56.76) 112.51,56.77 PR25.2
  TOP w0.254: PU7.8 113.35,57.03 PC27.2 113.2,57.68 PR25.2
670AGND: length 6.9
  TOP w0.203: PU8.14 121.32,46.96 121.76,47.4 v1(121.96,47.4)
  TOP w0.508: v1(124.71,45.92) 124.22,45.92 124.22,45.93 PC47.1
  IN2 w0.508: v1(121.96,47.4) 122.75,47.4 124.22,45.92 v1(124.71,45.92)
  BOTTOM w0.508: PR145.1 124.25,45.47 v1(124.71,45.92)
671AGND: length 5
  TOP w0.203: PU10.14 151.26,32.95 v1(150.46,32.16)
  TOP w0.508: PR53.2 149.71,30.97 150.33,31.59 150.33,32.03 v1(150.46,32.16)
  BOTTOM w0.508: PR164.1 149.58,32.05 v1(149.84,31.79) 150.25,31.79 150.46,32 v1(150.46,32.16)
8002LX1.05V: length 5.6
  BOTTOM w0.102: v1(37.91,52.3) 37.94,52.3 38.78,53.14 PL14.1
  BOTTOM w0.508: PU13.3 39.25,50.41 39.51,50.67 39.51,52.59 PL14.1
8690_CLK: length 2.6
  TOP w0.14: PR66.2 138.65,16.12 138.85,16.32 v1(138.87,16.32) 138.85,16.33 138.99,16.47 PU11.7
8690_DATA: length 2.6
  TOP w0.14: PR67.2 139.67,16.41 v1(139.44,16.63) 139.44,16.63 139.44,17.32 139.39,17.37 PU11.8
8690AGND: length 6.9
  TOP w0.508: v1(134.46,22.25) 133.95,22.76 PC82.1 ; v1(138.4,17.04) 137.61,16.26 PR62.2 ; v1(133.19,20.09) 132.8,19.7 PC84.2 PR59.2 ; PC88.2 v1(134.33,14.09) ; PR64.2 v1(135.35,14.09) ; v1(140.61,16.69) 140.61,15.73 PC89.1
  vias: v2(137.02,15.82)
51216DRVH: length 10.3
  IN1 w0.762: v1(33.16,32.97) 33.47,32.66 33.47,32.13 32.86,31.52 32.86,27.08 33.75,26.19 v3(36.54,26.19)
51216DRVL: length 6.1
  IN1 w0.762: v1(28.65,29.68) 30.26,29.68 30.87,30.29 v3(30.87,33.92)
51216MODE: length 2.5
  TOP w0.203: 34.31,35.82 PU9.19
  TOP w0.254: 34.31,35.82 35.59,37.1 PR45.2
51216PG: length 3.1
  TOP w0.203: PU9.20 34.2,36.22
  TOP w0.254: 34.2,36.22 35.04,37.06 35.04,37.39 35.59,37.94 PR44.2
51216REFIN: length 4.1
  TOP w0.203: v1(29.94,35.56) 30.08,35.42 PU9.8
  TOP w0.254: v1(29.94,35.56) 29.84,35.66 28.65,35.66 PC62.1 PR48.1
  BOTTOM w0.254: PR158.2 29.54,35.78 29.76,35.56 v1(29.94,35.56)
51216S3: length 4.2
  TOP w0.203: PU9.17 34.29,35.02 34.56,34.75 v1(34.76,34.75)
  TOP w0.254: PC63.1 35.34,34.75 v1(34.76,34.75)
  BOTTOM w0.254: v2(34.28,35.41) 34.28,35.23 v1(34.76,34.75) 35.31,34.75 PR159.2
51216S5: length 3.1
  TOP w0.203: PU9.16 34.25,34.62 34.57,34.29 34.64,34.29 v1(34.76,34.11)
  TOP w0.254: v1(34.76,34.11) 35.47,34.11 PC67.1
  BOTTOM w0.254: v1(34.76,34.11) PR162.2
51216SW: length 7.7
  IN1 w0.762: v1(32.43,32.48) 32,32.05 v3(32,26.7)
  BOTTOM w0.508: v3(32,26.7) PR167.2
51216TRIP: length 2.2
  TOP w0.203: v1(34.69,35.38) 34.65,35.42 PU9.18
  TOP w0.254: v1(34.69,35.38) 34.83,35.38 PR46.2
95833_BOOT1: length 3.3
  BOTTOM w0.203: PR109.1 124,62.28 v2(124.5,62.79) 124.63,62.92 126.08,62.92 126.31,63.15 PU12.16
95833_BOOTG: length 4.4
  BOTTOM w0.203: PR92.1 124.21,67.95 v1(124.25,67.95) 124.53,68.22 126.28,68.22 126.71,67.79 PU12.26
95833_COMP: length 6.4
  TOP w0.254: PR18.1 126.2,62.84 v1(126.91,62.13)
  BOTTOM w0.203: PU12.14 127.11,62.33 v1(126.91,62.13) 126.89,62.15 125.57,62.15 124.77,61.36 PC128.2 124.77,60.95 124.18,60.36 PC136.2
95833_COMPG: length 5.3
  TOP w0.203: PR14.2 127.09,67.85 127.22,67.97 v1(127.22,68.38) 126.84,68.38 126.33,68.89 PC16.2 125.7,68.99 v2(125.29,68.58)
  BOTTOM w0.203: PU12.28 127.51,67.86 127.22,68.15 v1(127.22,68.38) 126.85,68.75 PC105.2
95833_ISUMN: length 37.2
  TOP w0.102: v1(130.01,60.53) 130.01,60.6 PR20.2 ; PR13.1 108.47,68.37 v1(108.33,68.5)
  IN2 w0.102: v1(130.01,60.53) 128.01,62.54 126.33,62.54 125.62,61.82 121.86,61.82 121.05,62.64 119.56,62.64 115.7,66.5 113.86,66.5 113.53,66.83 112.67,66.83 111.98,67.51 111.98,67.99 111.62,68.35 109.79,68.35 109.23,68.91 108.74,68.91 v1(108.33,68.5)
  BOTTOM w0.102: PR89.2 107.93,68.9 v1(108.33,68.5)
  BOTTOM w0.203: PR116.1 PR117.1 129.23,58.85 v2(129.43,58.65) 129.61,58.65 130.01,59.06 v1(130.01,60.53) 129.71,60.53 129.51,60.73 PC124.2 129.77,61.24 130.26,61.24 PC125.2 131.27,60.22 PC134.1
95833_ISUMNG: length 43.6
  TOP w0.102: v1(107.61,82.25) 107.78,82.41 PR9.1
  IN2 w0.102: v1(130.24,70.61) 129.79,71.07 127.8,71.07 126.33,72.54 125.42,72.54 123.3,74.66 123.3,77.29 121.63,78.96 121.63,80.86 119.22,83.27 114.9,83.27 113.94,82.31 113.94,81.92 113.43,81.41 112.64,81.41 111.93,82.12 109.83,82.12 109.35,81.64 108.22,81.64 v1(107.61,82.25)
  BOTTOM w0.102: PR75.2 107.8,81.19 v2(107.53,81.46) 107.53,82.17 v1(107.61,82.25) ; v1(130.24,70.61) 130.24,70.94 130.1,71.08 130.1,71.87 130.4,72.17 PC99.1 131.67,70.92 PR83.2 ; PR83.2 131.66,70.9 PR88.2 ; PR83.2 131.68,70.9 132.12,70.46 132.48,70.46 PR84.2 132.94,69.88 PC104.2 PC110.2
95833_ISUMP: length 33.5
  TOP w0.102: PR19.1 PR20.1 128.74,61.63 128.74,60.81 v1(129,60.55)
  IN2 w0.102: v1(109.06,68.5) 109.41,68.15 111.54,68.15 111.78,67.91 111.78,67.41 112.56,66.62 113.43,66.62 113.78,66.27 115.64,66.27 119.47,62.43 120.97,62.43 121.78,61.62 125.44,61.62 125.8,61.27 128.29,61.27 v1(129,60.55)
  BOTTOM w0.102: PR91.2 109.28,68.28 v1(109.06,68.5)
  BOTTOM w0.203: v1(129,60.55) 129,61.44 129.31,61.76 PC124.1 ; PU12.10 128.71,62.77 129,62.48 129.33,62.48 129.51,62.31 PC124.1 ; PC126.1 131.27,61.76 PC125.1 PC124.1
95833_ISUMPG: length 47.5
  IN2 w0.102: v1(108.32,82.25) 108.73,81.84 109.26,81.84 109.74,82.32 112.01,82.32 112.72,81.61 113.34,81.61 113.73,82 113.73,82.39 114.82,83.48 119.3,83.48 121.86,80.92 121.86,79.17 123.5,77.53 123.5,75.7 127.85,71.35 129.86,71.35 130.12,71.09 132.1,71.09 v1(132.3,70.89)
  BOTTOM w0.102: PC110.1 PC104.1 133.61,70.82 PR84.1 133.29,71.35 133.01,71.35 132.45,71.91 132.45,72.17 PR82.1 PC100.1 131.42,71.92 131.44,71.92 131.61,71.75 131.75,71.75 132.3,71.2 v1(132.3,70.89) ; v1(108.32,82.25) 108.32,82.07 v2(108.83,81.56) 109.11,81.28 PR74.2
  BOTTOM w0.198: 129.11,67.81 PU12.32
  BOTTOM w0.203: PC110.1 133.55,68.76 133.1,68.31 132.38,68.31 131.82,67.74 130.61,67.74 130.42,67.56 129.82,67.56 129.48,67.89 129.2,67.89 129.11,67.81
95833_LGATE1: length 15.1
  IN2 w0.762: v1(114.4,73.76) 114.4,73 115.12,72.29 116.96,72.29 122.39,66.85 122.39,65.96 122.98,65.38 124.3,65.38 v3(124.86,64.82)
95833_LGATEG: length 13
  IN2 w0.762: v1(118.99,76.57) 119.04,76.51 119.04,71.45 124.25,66.24 v3(124.71,66.24)
95833_NTC: length 26.3
  TOP w0.102: PR15.2 PR16.2 114.31,64.64 v1(114.68,65.01) 114.68,65.35 v1(114.39,65.63)
  IN2 w0.102: v1(130.52,63.95) 130.09,63.52 130.09,62.7 130.42,62.37 130.42,60.36 130.16,60.1 127.25,60.1 126.55,60.8 125.59,60.8 125.18,61.21 121.61,61.21 120.8,62.03 119.27,62.03 115.66,65.63 v1(114.39,65.63)
  BOTTOM w0.102: v1(130.52,63.95) 130.14,64.33 PU12.7
95833_NTCG: length 32
  TOP w0.102: v1(124.04,78.13) 124.04,75.16 126.08,73.13 126.08,72.66 128.24,70.5 128.24,70.21 129.41,69.04 130.22,69.04 130.34,68.91 130.34,68.19 v2(130.16,68) 130.16,67.27 v1(130.52,66.93) ; PR7.2 PR6.2 112.74,82.55 v1(113.03,82.26)
  IN2 w0.102: v1(113.03,82.26) 113.33,82.55 113.33,82.56 114.65,83.88 119.47,83.88 122.27,81.09 122.27,79.91 v1(124.04,78.13)
  BOTTOM w0.102: PU12.1 130.32,66.73 v1(130.52,66.93)
95833_PHASE1: length 16
  IN1 w0.762: v4(124.35,64.11) 124.1,63.86 122.93,63.86 122.15,64.63 122.15,65.85 118.28,69.72 114.55,69.72 v3(113.78,70.49)
  BOTTOM w0.508: v3(113.78,70.49) 114.67,69.6 PR85.1
95833_PHASEG: length 19.4
  IN1 w0.762: v1(113.83,78.18) 113.88,78.18 114.44,77.62 119.19,77.62 121.35,75.46 121.35,70.41 v3(124.53,67.23)
  BOTTOM w0.508: v1(113.83,78.18) 113.45,77.8 PR77.1
95833_UGATE1: length 14.9
  IN2 w0.762: v3(113.5,67.79) 114.44,68.73 119.24,68.73 121.25,66.73 121.25,65.86 122.27,64.85 122.27,64.41 123.36,63.32 124.73,63.32 v3(124.91,63.5)
95833_UGATEG: length 19.7
  IN2 w0.762: v3(118.99,82.21) 118.22,82.21 117.95,81.94 117.95,78.89 121.38,75.46 121.38,70.51 123.36,68.53 124.48,68.53 125.24,67.77 125.29,67.77 v4(125.72,67.34)
+BATCHG: length 17.6
  TOP w0.102: PR57.2 120.23,22.64 120.23,25.55 120.11,25.68 PR55.2
  TOP w0.508: v1(123.51,14.4) 123.54,14.43 123.54,14.55 123.74,14.76 PD9.2
  BOTTOM w0.508: v1(119.6,24.16) 119.9,23.85 119.9,18.72 123.51,15.11 v1(123.51,14.4)
  vias: v2(118.36,19.96) v3(61.66,12.24) v3(61.66,11.48) v3(62.42,12.24) v3(62.42,11.48) v3(63.19,12.24) v3(63.19,11.48) v3(63.95,12.24) v3(63.95,11.48)
+LCDVCC:
  vias: v1(27.96,62.23) v1(28.6,62.23) v1(30.01,65.81) v1(30.62,65.81) v1(31.23,65.81) v2(29.38,66.17)
+SMDDR_VREF_DIMM: length 15
  TOP w0.356: JDIM6.126 67.76,27.49 v1(67.42,27.83)
  BOTTOM w0.508: v1(67.42,27.83) 67.22,27.64 67.21,27.64 C318.1 66.78,26.03 66.87,25.93 v2(66.87,24.66) 66.87,23.93 66.44,23.5 R401.1 65.19,24.26 63.98,25.47 R399.1 63.98,26.38 v2(64.66,27.06) 64.93,27.32 64.93,29.29 64.73,29.49 R397.2
+SMDDR_VREF_DQ: length 5.1
  BOTTOM w0.102: R388.2 103.86,35.98 v2(103.92,36.05)
  BOTTOM w0.508: R388.2 R392.1 103.87,34.06 105.16,34.06 R390.1 105.19,32.7 R396.2
+SMDDR_VREF_DQ0: length 6.1
  TOP w0.356: JDIM6.1 107.66,35.77 v1(107.26,36.17)
  BOTTOM w0.508: v1(107.26,36.17) 107.98,36.17 C302.1 108.04,35.79 107.78,35.79 v1(107.38,35.4) 107.02,35.4 106.86,35.55 C305.1 R390.2
+TPVDD: length 96.5
  TOP w0.508: PC199.2 27.98,39.42 29.48,40.92 PQ38.1 30.17,41.38 v2(31.03,41.38) 32.33,41.38 PC156.1 33.75,42.8 v1(34.94,42.8) ; v1(38.78,35.18) 39.49,34.47 39.49,30.07 38.6,29.18 38.6,26.77 39.72,25.65 39.72,22.96 39.49,22.73 39.49,18.06 40,17.55 v1(40.45,17.55) ; v1(37.98,37.36) R527.1
  IN1 w0.508: v1(77.33,9.04) 77.33,9.37 76.78,9.93 67.38,9.93 65.47,8.03 56.77,8.03 54.46,10.34 v1(54.45,10.34) 54.4,10.29 52.09,10.29 51.45,10.92 47.79,10.92 44.64,14.07 43.07,14.07 41.29,15.85 41.29,16.94 40.89,17.35 40.65,17.35 v1(40.45,17.55) ; v1(38.78,35.18) 39.16,35.18 39.62,35.64 39.62,36.07 38.53,37.15 38.19,37.15 v1(37.98,37.36) 36.85,38.5 36.85,40.89 v1(34.94,42.8)
  BOTTOM w0.508: PR181.2 77.17,13.74 77.4,13.52 77.82,13.52 78.4,12.93 78.4,10.59 77.33,9.53 v1(77.33,9.04) ; v1(54.45,10.34) 56.87,12.76 56.87,14.24 57.41,14.78 57.41,16 57.99,16.57 R407.1
+TPVDD_1: length 106.8
  IN1 w0.508: v1(121.99,36.96) 121.99,38.1 123.08,39.19 125.82,39.19 126.66,40.03 126.66,41.88 126.84,42.06 126.84,42.37 127.52,43.05 v1(127.78,43.05) ; v1(53.81,17.07) 53.25,17.07 52.04,18.29 50.77,18.29 v1(50.61,18.14) 47.51,18.14 46.83,18.82 v1(46.19,18.82)
  IN2 w0.508: v1(55.21,18.31) 55.74,18.85 70.45,18.85 73.4,15.9 82.11,15.9 83.35,14.66 89.42,14.66 90.47,13.61 93.79,13.61 94.48,12.93 106.39,12.93 110.33,16.87 110.33,18.71 112.27,20.65 112.27,21.91 117.29,26.92 117.29,28.7 119.7,31.12 v1(119.7,31.39)
  BOTTOM w0.508: v1(119.7,31.39) 119.7,32.56 121.99,34.85 v1(121.99,36.96) ; v1(46.19,18.82) 46.64,18.82 R426.1 46.82,18.01 R408.2 ; v1(50.61,18.14) 50.61,18.1 R404.2 ; Q41.2 127.52,43.31 v1(127.78,43.05)
  vias: v2(54.47,16.69)
+VA: length 128.7
  TOP w0.508: v1(126.33,15.01) 126.08,15.01 124.63,16.46 PD8.2 125.37,17.53 127.77,17.53 128.24,17.07 128.24,16.15 128.62,15.77 PR61.1
  IN2 w0.508: v1(162.73,13.59) 162.55,13.77 150.84,13.77 149.6,15.01 v1(126.33,15.01) ; v1(161.36,49.3) 163.4,51.34 163.4,57.07 162.69,57.78 162.69,68.04 v1(160.49,70.23)
  BOTTOM w0.102: PR71.1 153.34,83.85 153.47,83.72 153.47,82.33 PR72.2
  BOTTOM w0.508: v1(162.73,13.59) 161.33,13.59 159.96,14.96 159.96,17.58 163.07,20.69 163.07,21.4 163.29,21.62 163.29,32.39 161.1,34.57 161.1,47.14 161.48,47.52 161.48,49.17 v1(161.36,49.3) ; 150.67,81.81 150.67,79.04 155.46,74.25 156.68,73.03 157.34,73.03 159.33,71.04 159.68,71.04 v1(160.49,70.23)
  vias: v1(151.26,82.93) v1(151.31,84.99) v1(151.28,84.33) v1(151.28,83.67) v2(151.5,85.67)
+VA_IACM: length 3.2
  BOTTOM w0.102: PR71.2 153.98,83.85 153.72,83.59 153.72,82.46 PR73.2
  vias: v1(145.12,23.26) v2(153.64,14.4) v3(147.29,21.11) v3(147.29,20.35) v3(147.29,19.58) v3(148.05,21.11) v3(148.05,20.35) v3(148.05,19.58) v3(155.21,82.35) v3(156.01,83.08) v3(156.01,82.32) v3(156.77,83.08) v3(156.77,82.32)
+VAD:
  vias: v2(144.17,19.11)
+VAD_LD: length 53.9
  TOP w0.254: v1(120.34,17.12) 120.34,16.74 v2(121.76,15.32) 123.18,13.89 126.76,13.89 127.25,14.38 PD9.1 ; PR69.1 128.24,14.38 127.85,14.76 PD9.1 ; PD8.1 PD9.1
  IN1 w0.254: v1(85.46,9.22) 86.76,7.93 108.75,7.93 117.95,17.12 v1(120.34,17.12)
  BOTTOM w0.254: v1(85.46,9.22) 85.89,9.65 PR185.2
+VSDIO: length 108.3
  TOP w0.254: U12.AN27 65.23,60.5 v1(64.86,60.13)
  TOP w0.381: R545.1 22.77,32.92 23.12,33.27 R549.1 23.12,34.99 23.15,35.02 R548.1 23.15,36.28 R233.1 22.02,37 20.82,38.2 20.18,38.2 v1(19.65,37.67) ; v1(16.38,47.59) 17.59,48.8 17.59,50.04 ; R547.1 17.68,49.95 17.59,50.04 ; 17.59,50.04 17.59,51.51 18.78,52.7 R546.1
  IN1 w0.381: v1(41.01,54.81) 41.01,55.37 40.15,56.24 36.59,56.24 35.7,57.12 28.59,57.12 26.51,55.04 26.51,53.67 25.16,52.32 23.44,52.32 23.17,52.59 21.37,52.59 18.89,50.11 18.89,48.36 18.56,48.03 16.82,48.03 v1(16.38,47.59) ; v3(14.86,37.99) 15.36,38.48 18.84,38.48 v1(19.65,37.67)
  IN2 w0.381: v1(16.38,47.59) 14.86,46.07 v3(14.86,37.99)
  BOTTOM w0.381: PQ30.1 14.6,43.17 PC201.1 14.6,43.19 PC205.1 14.6,45.77 16.4,47.57 16.4,47.59 v1(16.38,47.59) ; v1(41.01,54.81) 41.22,54.61 42.74,54.61 43.26,55.13 43.77,55.13 44.26,55.63 44.26,57.28 45.84,58.85 47.39,58.85 49.24,60.71 49.24,61.01 49.5,61.27 52.37,61.27 52.62,61.01 52.72,61.01 53.28,60.45 53.28,60.05 53.51,59.82 53.51,59.33 54.04,58.8 54.91,58.8 55.26,58.45 56.48,58.45 56.89,58.04 57.88,58.04 58.13,58.29 58.13,58.57 58.42,58.86 C240.2 58.71,59.38 59.43,60.1 61.56,60.1 61.79,60.33 64.66,60.33 v1(64.86,60.13) ; PQ29.1 15.27,34.46 PC202.1 15.26,35.9 PC203.1 15.26,37.59 v3(14.86,37.99)
AC_PRESENT: length 23.9
  TOP w0.102: 82.41,64.18 82.21,63.99 81.84,63.99 81.72,64.11 81.2,64.11 81.11,64.19 80.87,64.19 80.86,64.19 80.84,64.19 80.75,64.09 80.51,64.09 80.41,64.19 80,64.19 U12.D20
  TOP w0.14: v1(84.57,65.38) 84.57,65.28 84.25,64.95 84.25,64.73 83.75,64.24 82.46,64.24 82.41,64.18
  IN1 w0.14: v1(96.05,66.44) 95.44,66.44 95.08,66.8 94.47,66.8 93.85,66.18 92.51,66.18 92.24,65.91 90.14,65.91 89.73,66.32 89.73,66.93 89.4,67.26 86.35,67.26 84.99,65.9 84.99,65.8 v1(84.57,65.38)
  BOTTOM w0.14: R289.1 97.58,63.69 97.58,64.57 97.35,64.8 97.35,64.95 96.7,65.6 Q24.6 96.32,66.21 96.09,66.44 v1(96.05,66.44)
AC_PRESENT_EC: length 67.5
  TOP w0.14: v1(138.47,43.66) 138.6,43.79 138.6,44.15 137.86,44.89 U18.104
  IN1 w0.14: v1(138.47,43.66) 136.8,43.66 135.7,42.57 133.3,42.57 133.14,42.74 131.3,42.74 130.67,42.11 128.59,42.11 128.26,41.78 128.26,41.68 128.16,41.58 128.16,39.57 128.44,39.29 128.44,38.91 127.02,37.49 127.02,37.03 125.31,35.33 123.77,35.33 122.7,34.26 122.29,34.26 122.24,34.21 122.22,34.21 121.68,33.68 121.63,33.68 121.61,33.66 113.5,33.66 111.65,35.51 v1(111.65,35.71)
  BOTTOM w0.14: R281.2 100.53,59.12 100.53,57.6 100.09,57.16 100.09,54.73 99.84,54.48 99.84,49.35 104.41,44.78 106.43,44.78 108.14,43.07 108.14,41.33 v1(110.2,39.27) 110.2,38.37 111.65,36.92 v1(111.65,35.71)
AC_PRESENT_NM: length 15.1
  BOTTOM w0.14: Q24.2 97.35,68.91 97.58,69.14 98.44,69.14 98.57,69.01 98.57,67.47 98.77,67.27 98.77,66.83 v2(98.9,66.7) 99.74,65.86 99.74,64.83 100.15,64.41 102.26,64.41 102.75,63.93 102.75,60.19 102.07,59.51 R281.1
ACIN: length 36.4
  TOP w0.203: PR59.1 PC84.1 133.58,19.59 133.95,19.96 v1(134.08,19.96) 134.33,19.96 134.87,20.5 PU11.36 ; v1(149.01,29.11) v2(148.45,29.67) 147.41,30.71 142.41,30.71 141.34,29.64 140.78,29.64 140.66,29.77 U18.64
  IN1 w0.254: v1(149.01,29.11) 149.01,24.49 143.37,18.85 135.6,18.85 134.48,19.96 v1(134.08,19.96)
ACZ_BCLK: length 6.7
  TOP w0.102: U12.BJ21 57.68,63.48 56.26,63.48 56.09,63.65
  TOP w0.14: R109.1 52.26,64.62 52.84,65.19 54.55,65.19 54.78,64.96 54.78,64.67 55.79,63.65 56.09,63.65
ACZ_RST#: length 5.3
  TOP w0.102: 56,63.4 56.12,63.27 57.45,63.27 57.59,63.14 57.92,63.14 58.01,63.22 58.25,63.22 58.54,62.93 U12.BG22
  TOP w0.14: R110.1 54.4,64.67 55.67,63.4 56,63.4
ACZ_RST#_AUDIO: length 43.7
  TOP w0.14: v1(52.92,64.67) R110.2 ; Q11.1 31.46,75.21 31.31,75.36 R124.1 31.06,75.89 v1(30.65,76.3) ; U9.11 25.82,76.37 v1(26.08,76.63)
  IN1 w0.14: v1(30.65,76.3) 30.34,76.61 30.34,76.73 30.17,76.91 26.36,76.91 v1(26.08,76.63) 25.65,76.2 25.65,74.24 26.1,73.79 27.32,73.79 29.28,71.83 30.24,71.83 32.76,69.32 32.76,69.22 32.73,69.19 32.73,68.78 34.03,67.49 42.59,67.49 44.19,65.89 47.13,65.89 48.73,64.29 52.54,64.29 v1(52.92,64.67)
ACZ_RST#_AUDIO_R: length 6.2
  TOP w0.14: R101.1 31.19,71.04 v2(30.24,71.98) 30.42,72.16 Q11.3 32.48,71.17 32.71,70.93 D31.1
ACZ_SDIN: length 1.9
  TOP w0.14: R65.2 26.76,75.34 26.6,75.17 U9.8
ACZ_SDIN0: length 39.1
  TOP w0.102: 56.34,64.45 56.68,64.1 57.92,64.1 58.01,64.19 58.3,64.19 U12.BG19
  TOP w0.14: R65.1 28.26,75.34 v1(28.39,75.21) ; v1(54.93,66.5) 55.59,65.84 55.59,65 56.14,64.45 56.34,64.45
  IN1 w0.14: v1(54.93,66.5) 54.93,66.45 54.12,65.63 51.38,65.63 50.84,65.1 49.24,65.1 47.59,66.75 45.2,66.75 43.63,68.32 43.63,68.73 42.87,69.49 39.3,69.49 38.25,68.44 34.42,68.44 33.65,69.22 33.65,69.88 30.88,72.64 30.22,72.64 28.39,74.47 v1(28.39,75.21)
ACZ_SDOUT: length 5.6
  TOP w0.102: U12.BG20 58.55,63.9 58.26,63.61 58.01,63.61 57.92,63.7 56.38,63.7 56.24,63.84
  TOP w0.14: R103.1 54.37,65.71 55.06,65.02 55.06,64.77 55.92,63.91 56.17,63.91 56.24,63.84
ACZ_SDOUT_AUDIO: length 33.4
  TOP w0.14: v1(26.31,74.27) 26.01,73.97 U9.5 ; v1(51.73,65.2) 52.39,65.2 52.9,65.71 R103.2
  IN1 w0.14: v1(51.73,65.2) 51.22,64.69 49.09,64.69 47.49,66.29 44.36,66.29 42.76,67.89 34.28,67.89 33.15,69.02 33.15,69.81 30.73,72.24 29.73,72.24 27.7,74.27 v1(26.31,74.27)
ACZ_SPKR: length 31.1
  TOP w0.102: 56.31,67.83 56.35,67.79 58,67.79 58,67.79 U12.BH12
  TOP w0.14: D19.2 40.33,76.53 40.96,75.9 v1(42.31,75.9) ; 56.31,67.83 56.17,67.97 56.13,67.97 55.88,68.22 55.88,68.22 v1(55.72,68.22)
  BOTTOM w0.14: v1(42.31,75.9) 43.32,75.9 43.4,75.81 47.52,75.81 48.67,74.66 48.67,72.48 49.6,71.55 49.6,70.05 48.73,69.19 48.73,66.37 49.27,65.84 49.72,65.84 50.08,66.19 50.08,66.57 v2(52.06,68.55) 52.06,69.01 52.67,69.62 53.18,69.62 53.43,69.37 53.43,69.06 53.64,68.86 55.08,68.86 v1(55.72,68.22)
ACZ_SYNC: length 7.3
  TOP w0.102: U12.BH20 56.54,63.9 56.37,64.07
  TOP w0.14: 56.37,64.07 56.26,64.19 56.02,64.19 55.34,64.87 55.34,65.48 54.68,66.14 52.5,66.14 R102.1
ACZ_SYNC_AUDIO: length 32.5
  TOP w0.14: v1(28.29,76.48) 28.08,76.28 26.43,76.28 26.13,75.97 U9.10 ; R102.2 50.97,65.84 v1(50.77,65.63)
  IN1 w0.14: v1(28.29,76.48) 28.92,75.84 31.33,75.84 31.84,75.34 31.84,73.3 34.58,70.57 43.39,70.57 44.75,69.22 44.75,68.68 45.58,67.84 48.1,67.84 49.65,66.29 50.11,66.29 v1(50.77,65.63)
ADOGND: length 23.3
  TOP w0.203: U9.25 18.67,76.77 18.53,76.91 18.53,77.78 18.44,77.87 v1(17.98,77.87) ; v1(20.01,70.56) 20.01,70.64 20.26,70.89 U9.38
  TOP w0.254: Q7.1 24.6,79.78 v1(24.75,79.63)
  TOP w0.381: C53.1 15.65,75.64 v1(14.93,75.64) ; C49.2 16.29,76.68 16.29,76.91 16.11,77.09 v1(15.74,77.09) 15.49,77.09 R53.1
  TOP w0.508: C343.2 15.56,69.22 v1(15.49,69.29) ; C39.2 16.34,79.91 v1(15.71,79.91) 15.44,79.91 D11.1 ; C69.2 18.75,68.72 v1(18.76,68.73) 18.77,68.72 C70.2 ; 16.35,78.65 15.85,79.15 v1(15.71,79.15) 15.19,79.15 C24.1 ; 16.35,78.65 R47.2 ; 16.35,78.65 17.34,78.65 D18.1 ; C342.2 v1(13.28,66.12) ; D17.1 v1(11.25,76.91) ; v1(30.27,79.53) 30.69,79.95 D37.1 C337.1 ; R25.2 14.66,66.3 v1(14.16,66.8) ; v1(16.43,68.83) 16.54,68.72 C68.1 ; R45.2 27.56,78.89 v1(28.16,78.89) C37.1 ; v1(18.69,79.88) 18.5,79.7 C35.2 ; C48.1 D20.1 15.66,82.37 v1(15.71,82.32) ; v1(15.71,80.62) 16.29,80.62 C36.2 ; C347.1 v1(13.02,69.55)
  vias: v1(0.78,74.42) v1(0.8,72.85) v1(0.8,70.89) v1(0.85,68.83) v1(0.93,76) v1(1.72,77.24) v1(2.89,65.13) v1(3.5,63.5) v1(5.86,72.9) v1(6.24,63.5) v1(7.81,76.45) v1(7.92,75.67) v1(8.45,72.87) v1(8.88,66.29) v1(8.98,69.77) v1(9.01,63.5) v1(12.13,63.81) v1(12.56,64.85) v1(22.06,82.4) v2(7.1,76.45) v2(11.57,64.72) v3(1.87,84.13) v3(1.87,82.83) v3(1.92,80.19) v3(1.9,79.12) v3(14.29,84.86) v3(15.84,84.99) v3(17.36,84.99) v3(18.71,84.99) v3(19.98,84.99) v3(21.4,85.09)
ALERT#: length 3.7
  TOP w0.102: TP6.1 56.41,82.38 56.41,81.1 56.51,81 U7.6
AMP_MUTE#: length 167.4
  TOP w0.102: v1(37.15,61.75) 37.79,62.38 37.79,64.08 37.53,64.34 37.53,66.24 37.31,66.47 D32.1
  TOP w0.14: v1(131.28,44.09) 130.27,45.11 130.06,45.11 129.86,45.31 U18.124
  IN1 w0.102: v1(37.15,61.75) 39.11,61.75 42.08,58.78 42.08,54.69 41.11,53.72 41.11,51.51 40.71,51.11 40.71,47.83 40.33,47.45 40.33,45.64 v1(39.74,45.06)
  IN2 w0.14: v1(131.28,44.09) 131.53,44.09 131.79,43.84 131.79,42.77 131.37,42.35 131.37,38.61 130.05,37.29 128.69,37.29 128.48,37.51 128.04,37.51 126.78,36.25 126.78,36.09 125.73,35.04 124.42,35.04 123.29,33.9 123,33.9 122.82,33.9 122.42,33.9 121.52,32.99 119.17,32.99 115.7,29.53 115.7,27.62 110.84,22.75 110.84,21.08 108.68,18.92 108.68,17.25 106.05,14.62 105.62,14.62 95.84,14.62 95.83,14.63 95.77,14.63 94.33,16.08 89.27,16.08 88.17,17.18 75.62,17.18 72.51,20.29 65,20.29 64.56,20.73 62.07,20.73 61.38,20.04 53.48,20.04 53.05,20.47 50.21,20.47 49.17,21.51 43.55,21.51 37.74,27.33 37.74,32.04 38.75,33.05 38.75,33.64 38.27,34.11 38.27,36.48 38.75,36.95 38.75,40.23 39.74,41.22 v1(39.74,45.06)
BATDIS_G: length 13
  TOP w0.508: PR70.1 v1(144.49,14.38) ; PQ10.1 145.51,20.85 146.27,20.09 146.27,14.39 PC90.1 v1(147.03,14.38) PC91.1
  BOTTOM w0.508: v1(147.03,14.38) v2(145.74,14.38) v1(144.49,14.38)
BATLED0#: length 135
  TOP w0.102: v1(126.2,79.53) 126.64,79.1 126.64,75.89 127.69,74.83 127.69,73.25 129.37,71.57 130.66,71.57 132.85,69.39 132.85,64.21 134.18,62.88 134.66,62.88 135.17,62.36 135.17,61.57 134.85,61.25 134.85,60.87 135.14,60.58 135.55,60.58 135.7,60.73 136.8,60.73 140.59,56.93 141.02,56.93 141.65,56.31 142.54,56.31 144.23,54.62 147.14,54.62 148.05,55.53 150.18,55.53 v2(150.64,55.07) 150.86,54.85 151.15,54.85 154.53,51.47 154.53,48.47 152.97,46.91 150.08,46.91 147.96,44.79 147.96,35.52 147.29,34.85 147.18,34.85 144.38,32.05 U18.65
  IN1 w0.102: v1(78.93,95.45) 78.93,92.08 80.61,90.4 83.96,90.4 84.68,89.69 96.92,89.69 97.69,90.45 v1(112.18,90.45)
  BOTTOM w0.102: v1(126.2,79.53) 126.13,79.53 125.67,79.98 125.67,79.99 125.47,80.19 125.47,80.39 125.06,80.8 125.06,84.66 122.8,86.92 115.71,86.92 v1(112.18,90.45) ; v1(78.93,95.45) R193.2
BATLED1#: length 137.9
  TOP w0.102: U18.66 144.48,32.45 147.08,35.05 147.16,35.05 147.74,35.63 147.74,39.08 147.06,39.75 147.06,41.99 147.44,42.36 147.44,44.56 150,47.12 152.67,47.12 154.26,48.71 154.26,50.57 v2(152.27,52.56) 149.61,55.21 148.12,55.21 147.32,54.42 143.92,54.42 142.28,56.06 141.6,56.06 140.93,56.73 140.43,56.73 137.1,60.06 137.1,60.07 136.64,60.53 135.88,60.53 135.73,60.38 135.05,60.38 134.62,60.81 134.62,61.44 134.91,61.73 134.91,62.2 134.48,62.62 134.02,62.62 132.64,64.01 132.64,69.29 130.56,71.36 129.15,71.36 127.46,73.06 127.46,74.72 126.34,75.84 126.34,78.81 125.79,79.35 125.79,79.8 v1(126.13,80.14)
  IN1 w0.102: v1(78.18,97.64) 78.18,92.47 80.51,90.14 83.86,90.14 84.52,89.48 97.01,89.48 97.77,90.25 111.65,90.25 111.85,90.04 112.54,90.04 v1(112.94,90.45)
  BOTTOM w0.102: v1(126.13,80.14) 125.29,80.98 125.29,84.73 122.88,87.15 116.25,87.15 v1(112.94,90.45) ; R194.2 v1(78.18,97.64)
BATT_EN#: length 4.9
  BOTTOM w0.102: PJ7.6 67.15,14.78 67.67,15.3 PR177.1 67.67,15.94 67.12,16.48 66.44,16.48 v2(66.26,16.66)
BEEP_1: length 4.1
  TOP w0.14: C40.2 28.02,76.9 28.1,76.98 R51.2 C41.1 30.37,76.98 R52.1
BIOS_STRAP: length 8.9
  TOP w0.102: v1(61.16,59.54) 61.52,59.18 U12.BA30
  BOTTOM w0.102: v1(61.16,59.54) 60.87,59.24 R312.1 60.24,58.86 58.84,57.46 57.66,57.46 v2(57.42,57.21) 57.28,57.08 56.61,57.08 56.37,57.31 56.37,57.66 55.97,58.06 R317.2
BIT_CLK_AUDIO: length 31.7
  TOP w0.14: v1(50.13,65.63) 50.13,65.43 50.94,64.62 R109.2 ; U9.6 25.75,74.37 26.08,74.7 26.61,74.7 26.93,74.38 C55.2 27.44,74.55 27.98,74.55 28.39,74.14 28.39,73.81 29.02,73.18 v1(30.45,73.18)
  IN1 w0.14: v1(50.13,65.63) 49.47,65.63 47.82,67.28 45.4,67.28 44.21,68.47 44.21,68.94 43.1,70.05 34.36,70.05 31.23,73.18 v1(30.45,73.18)
BL#: length 11.3
  BOTTOM w0.102: Q36.2 133.69,36.35 R385.2 134.7,35.7 134.97,35.97 134.97,38.51 135.14,38.68 136.29,38.68 137.46,39.85 137.79,39.85 138.01,40.08 Q34.3 138.94,40.79 R522.2
BLON_CON: length 200.1
  TOP w0.102: R521.1 36.26,64.59 v1(35.86,65)
  IN1 w0.102: v1(132.07,35.33) 131.66,35.74 131.16,35.74 130.55,35.13 128.4,35.13 128.38,35.11 128.38,35.1 128.02,34.75 128.02,34.75 127.68,34.41 124.68,34.41 123.14,32.87 114.82,32.87 114.22,32.26 114.22,25.43 109.18,20.39 109.18,16.92 106.76,14.5 94.51,14.5 93.93,15.09 90.06,15.09 89.66,15.49 89.17,15.49 88,16.66 79.6,16.66 78.89,17.37 72.13,17.37 71.26,18.24 65.32,18.24 64.68,17.59 62,17.59 60.05,15.63 50.37,15.63 49.5,16.51 46.14,16.51 42.31,20.34 40.29,20.34 39.44,19.48 39.44,16.64 37.91,15.11 30.27,15.11 27.83,17.55 27.83,22 22.67,27.15 22.67,36.88 23.49,37.69 23.49,38.96 v1(23.18,39.27)
  IN2 w0.102: v1(23.18,39.27) 23.54,39.62 23.54,40.08 22.52,41.1 22.52,50.65 23.26,51.38 25.54,51.38 27.6,53.44 27.6,54.96 29.62,56.97 31.02,56.97 33.59,59.54 33.95,59.54 34.79,60.38 34.79,63.75 35.86,64.82 v1(35.86,65)
  BOTTOM w0.102: v1(132.07,35.33) 132.22,35.48 132.22,37.19 131.92,37.49 Q36.3 131.92,38.56 132.48,39.12 132.48,40.11 131.92,40.67 Q35.3 131.82,41.13 131.61,41.33 R371.2 130.57,41.91 130.52,41.96 D35.2 ; v1(35.86,65) 35.65,65.2 35.42,65.2 35.25,65.38 35.25,66.04 35.6,66.39 CN16.14
BOARD_ID1: length 19.7
  TOP w0.102: U12.C13 80.69,67.36 80.97,67.36 81.22,67.61 82.21,67.61 82.46,67.86 82.46,68.25 84.19,69.98 84.5,69.98 84.78,70.26 84.78,74.09 86.07,75.39 86.07,75.9 85.69,76.28 84.24,76.28 83.86,76.66 83.86,78.93 84.18,79.25 v2(84.18,79.7) R44.2 R54.1
BOARD_ID2: length 70.3
  TOP w0.102: v1(85.08,77.72) 85.62,77.18 R64.1 R41.2 86.93,75.91 84.98,73.97 84.98,70.17 84.58,69.77 84.47,69.77 82.67,67.97 82.67,67.78 82.3,67.4 81.62,67.4 81.52,67.3 U12.A13
  IN2 w0.102: v1(85.08,77.72) 84.24,76.89 82.78,76.89 82.01,76.12 74.92,76.12 73.07,74.27 69.16,74.27 68.72,74.7 65.55,74.7 65.12,75.13 62.17,75.13 61.84,75.46 60.24,75.46 59.43,74.65 55.95,74.65 54.78,75.82 49.96,75.82 48.46,77.32 47.59,77.32 46.97,76.7 46.97,68.62 45.18,66.83 v1(44.47,66.83)
  BOTTOM w0.102: v1(44.47,66.83) 44.47,66.45 44.06,66.04 43.78,66.04 43.6,66.22 CN16.30
BOARD_ID3: length 8.1
  TOP w0.102: U12.C19 80.79,64.54 81.07,64.54 81.2,64.67 81.7,64.67 81.85,64.82 82.2,64.82 82.48,64.54 83.63,64.54 83.91,64.82 83.91,65.3 84.6,65.99 v1(84.6,66.62)
  BOTTOM w0.102: R271.1 84,66.62 v1(84.6,66.62) 84.6,66.83 85.44,67.67 R85.2
BRIGHT: length 3
  BOTTOM w0.14: R277.2 36.05,64.48 36.31,64.74 36.31,65.44 36.1,65.65 CN16.15
BRTC_EXTPAD: length 12.2
  TOP w0.14: U12.B8 81.43,69.76 82.24,70.56 82.24,74.4 81.78,74.85 80.14,74.85 79.67,75.32 79.02,75.32 78.63,75.72 77.44,75.72 76.78,76.38 C45.1
BT_POWERON: length 70.1
  TOP w0.102: v1(134.97,52.53) 135.01,52.48 135.01,48.15 134.69,47.83 134.44,47.83 133.86,47.25 U18.114
  IN1 w0.102: v1(156.94,67.84) 156.94,67.78 151.28,62.13 151.28,56.17 149.27,54.15 148.29,54.15 146.41,52.27 143.92,52.27 143.56,51.92 142.98,51.92 142.7,52.19 137.86,52.19 137.58,52.47 135.02,52.47 v1(134.97,52.53)
  IN2 w0.102: v1(160.81,87.27) 161.39,86.69 161.39,85.41 159.63,83.65 159.63,73.51 157.84,71.72 157.84,67.54 157,66.7 156.87,66.7 156.43,67.14 156.43,67.34 v1(156.94,67.84)
  BOTTOM w0.102: Q13.2 v2(161.75,91.4) 161.75,88.19 160.83,87.27 v1(160.81,87.27)
BT_PWRON: length 8.8
  BOTTOM w0.102: Q13.3 163.73,94.93 164.39,95.59 164.39,96.55 R200.1 163.89,97.69 163.64,97.94 R196.1 163.64,99.66 v2(164,100.03)
C_TX0_HDMI+: length 12.4
  TOP w0.102: C13.2 69.25,89.44 69.09,89.6 69.09,90.31 69.23,90.44 v1(69.56,90.44)
  IN1 w0.102: v1(69.56,90.44) 69.56,90.45 69.18,90.45 69,90.27 69,89.94 69.23,89.71 69.87,89.71 70.1,89.94 70.1,90.66 69.29,91.46 64.6,91.46 64.35,91.7 64.35,92.02 64.18,92.2 CN7.7
  BOTTOM w0.102: R213.2 v1(69.56,90.44)
C_TX0_HDMI-: length 12.4
  TOP w0.102: C12.2 68.78,89.44 68.91,89.57 68.91,90.34 68.8,90.44 v1(68.55,90.44)
  IN1 w0.102: CN7.9 64.73,92.2 64.55,92.01 64.55,91.78 64.67,91.65 69.37,91.65 70.29,90.74 70.29,89.86 69.95,89.52 69.15,89.52 68.81,89.86 68.81,90.18 v1(68.55,90.44)
  BOTTOM w0.102: R212.2 v1(68.55,90.44)
C_TX1_HDMI+: length 15.6
  TOP w0.102: C11.2 67.04,89.44 66.91,89.57 66.91,90.34 67.02,90.45 67.27,90.45 v1(67.28,90.44)
  IN2 w0.102: v1(67.28,90.44) 67.14,90.44 66.96,90.26 66.96,90.01 66.64,89.69 65.89,89.69 65.54,90.04 65.54,90.68 64.75,91.47 64.2,91.47 64.1,91.36 60.45,91.36 60.07,91.74 60.07,92.52 60.54,92.99 62.56,92.99 62.72,93.14 62.72,93.38 CN7.4
  BOTTOM w0.102: R211.2 v1(67.28,90.44)
C_TX1_HDMI-: length 15.6
  TOP w0.102: C10.2 66.6,89.44 66.73,89.57 66.73,90.34 66.62,90.45 66.26,90.45 v1(66.26,90.44)
  IN2 w0.102: v1(66.26,90.44) 66.62,90.44 66.77,90.3 66.77,90.08 66.56,89.88 65.97,89.88 65.73,90.12 65.73,90.75 64.82,91.66 64.12,91.66 64.02,91.55 60.53,91.55 60.27,91.82 60.27,92.44 60.62,92.8 62.64,92.8 62.91,93.07 62.91,93.45 63.16,93.7 CN7.6
  BOTTOM w0.102: R210.2 v1(66.26,90.44)
C_TX2_HDMI+: length 9.5
  TOP w0.102: C9.2 64.81,89.75 64.81,90.27 v1(64.99,90.44)
  IN1 w0.102: v1(64.99,90.44) 64.86,90.32 64.86,90.31 64.82,90.27 64.82,89.4 64.51,89.08 62.49,89.08 62.11,89.46 62.11,90.7 61.95,90.86 61.52,90.86 61.22,91.16 61.22,91.88 CN7.1
  BOTTOM w0.102: v1(64.99,90.44) 65.12,90.32 R209.2
C_TX2_HDMI-: length 9.5
  TOP w0.102: v1(64.35,90.44) 64.63,90.17 64.63,89.69 64.39,89.44 C8.2
  IN1 w0.102: CN7.3 61.61,92.2 61.41,92 61.41,91.24 61.6,91.05 62.03,91.05 62.3,90.78 62.3,89.54 62.56,89.27 64.43,89.27 64.63,89.47 64.63,90.22 64.41,90.44 v1(64.35,90.44)
  BOTTOM w0.102: v1(64.35,90.44) 64.1,90.19 R208.2
C_TXC_HDMI+: length 13.2
  TOP w0.102: C15.2 71.57,89.44 71.3,89.71 71.3,90.18 71.57,90.45 71.84,90.45 v1(71.85,90.44)
  IN1 w0.102: CN7.10 65.58,93.7 65.89,93.38 65.89,93.1 66.13,92.86 70.31,92.86 72.42,90.75 72.42,90.17 72.13,89.88 71.65,89.88 71.47,90.06 71.47,90.32 71.59,90.45 71.84,90.45 v1(71.85,90.44)
  BOTTOM w0.102: R215.2 v1(71.85,90.44)
C_TXC_HDMI-: length 13.2
  TOP w0.102: C14.2 71.12,89.73 71.12,90.15 v1(70.83,90.44)
  IN1 w0.102: v1(70.83,90.44) 70.84,90.45 71.16,90.45 71.28,90.34 71.28,89.98 71.57,89.69 72.21,89.69 72.61,90.09 72.61,90.83 70.39,93.05 66.21,93.05 66.08,93.18 66.08,93.38 CN7.12
  BOTTOM w0.102: R214.2 v1(70.83,90.44)
CARD_ON_OFF: length 5.6
  TOP w0.102: U18.27 127.35,34.05 128.26,34.97 v1(128.26,36.42)
  BOTTOM w0.102: TP44.1 128.26,37.82 128.72,37.36 128.72,36.88 v1(128.26,36.42)
CBST1: length 6.9
  TOP w0.254: PC83.1 132.68,24.54 132.52,24.69 PD7.1 133.18,26.21 134.62,26.21 v2(135.26,26.85) 135.34,26.92 PR54.2
CCD_PWR: length 5.5
  TOP w0.508: R122.1 C86.1 31.94,64.39 31.94,65.02 C82.2 31.91,65.39 v2(32.49,65.97) 33.29,65.97 v1(33.32,65.94)
  BOTTOM w0.254: CN16.9 33.1,66.16 v1(33.32,65.94)
CHG_BST: length 2.7
  TOP w0.203: PU11.26 138.19,24.14 PR54.1
CHG_CEN: length 4.4
  TOP w0.203: PR64.1 PR65.2 136.36,16.51 v1(136.47,16.61) 136.75,16.89 137.05,16.89 137.33,17.17 137.66,17.17 137.79,17.3 PU11.4
CHG_LX:
  vias: v2(133.84,21.3)
CHG_VAC: length 7.6
  TOP w0.203: PR69.2 130.75,15.37 v1(131.27,15.89) 131.66,16.28 132.3,16.28 133.06,17.04 134.13,17.04 135.79,18.7 PU11.40
CHG_VBATT: length 4.7
  TOP w0.102: PR55.1 120.62,25.68 120.49,25.55 120.49,22.63 120.73,22.39 PR58.2
  vias: v2(124.2,26.49) v3(123.92,25.68) v3(123.92,24.92) v3(123.92,24.16) v3(124.81,25.68) v3(124.81,24.92) v3(124.81,24.16) v3(140.81,23.77) v3(140.81,23.06) v3(141.52,23.77) v3(141.52,23.06) v3(142.26,23.75) v3(142.26,23.04)
CHG_VDDP: length 5.9
  TOP w0.203: PU11.32 135.12,22.1 134.97,22.25 134.97,23.57 v1(134.81,23.73) 134.63,23.91 PC82.2 133.95,25.1 134.41,25.55 PD7.2
CLK_24M_DEBUG: length 215.3
  IN1 w0.14: v1(163.88,88.67) 163.19,87.97 163.19,86.16 162.73,85.7 162.73,85.41 162.87,85.27 164.23,85.27 164.51,85.55 164.51,87.02 164.68,87.2 165.09,87.2 165.27,87.02 165.27,85.24 164.91,84.89 164.61,84.89 164.33,84.61 161.61,84.61 160.74,83.73 160.74,83.53 161.83,82.44 161.83,82.24 161.64,82.04 161.44,82.04 160.34,83.14 160.14,83.14 159.95,82.94 159.95,82.74 161.04,81.65 161.04,81.45 160.85,81.25 160.65,81.25 159.55,82.35 159.35,82.35 159.15,82.15 159.15,81.95 160.25,80.86 160.25,80.66 160.05,80.46 159.86,80.46 158.76,81.56 158.56,81.56 158.36,81.36 158.36,81.16 159.25,80.28 159.25,80.04 159.1,79.88 158.85,79.88 157.97,80.77 157.52,80.77 157.33,80.58 157.33,80.19 157.46,80.05 157.74,80.05 157.88,79.91 157.88,79.63 157.74,79.49 157.46,79.49 157.33,79.35 157.33,78.07 153.65,74.39 151.44,74.39 150.53,73.48 144.33,73.48 142.6,71.74 142.48,71.74 140.63,69.89 136.09,69.89 134.8,68.61 131.84,68.61 130.8,69.65 129.09,69.65 126.1,72.64 126.1,73.13 124.31,74.92 124.31,76.33 124.58,76.61 124.58,78.64 124.22,78.99 124.22,79.39 124.08,79.53 122.86,79.53 122.72,79.67 122.72,79.94 122.86,80.08 124.08,80.08 124.22,80.22 124.22,80.5 124.08,80.64 122.86,80.64 122.72,80.78 122.72,81.06 122.86,81.2 124.08,81.2 124.22,81.34 124.22,81.62 124.08,81.76 122.86,81.76 122.72,81.9 122.72,82.18 122.86,82.32 124.08,82.32 124.22,82.46 124.22,82.98 123.58,83.62 123.38,83.62 122.69,82.93 122.49,82.93 122.3,83.13 122.3,83.33 122.99,84.02 122.99,84.22 122.79,84.42 122.59,84.42 121.9,83.72 121.7,83.72 121.51,83.92 121.51,84.12 122.2,84.81 122.2,85.01 122,85.21 121.8,85.21 121.11,84.51 120.91,84.51 120.71,84.71 120.71,84.91 121.41,85.6 121.41,85.8 121.05,86.16 120.14,86.16 120,86.02 120,85.59 119.86,85.45 119.58,85.45 119.44,85.59 119.44,86.02 119.3,86.16 119.02,86.16 118.88,86.02 118.88,85.59 118.74,85.45 118.46,85.45 118.32,85.59 118.32,86.02 118.18,86.16 117.9,86.16 117.76,86.02 117.76,85.59 117.62,85.45 117.34,85.45 117.2,85.59 117.2,86.02 117.07,86.16 116.79,86.16 116.65,86.02 116.65,85.59 116.51,85.45 116.23,85.45 116.09,85.59 116.09,86.02 115.95,86.16 115.67,86.16 115.53,86.02 115.53,85.59 115.39,85.45 115.11,85.45 114.97,85.59 114.97,86.02 114.83,86.16 114.14,86.16 113.96,86.33 113.52,86.33 113.38,86.2 113.38,85.53 113.24,85.4 112.96,85.4 112.83,85.53 112.83,86.2 112.69,86.33 112.41,86.33 112.27,86.2 112.27,85.53 112.13,85.4 111.85,85.4 111.71,85.53 111.71,86.2 111.57,86.33 111.55,86.33 110.94,86.94 110.42,86.94 110.28,86.8 110.28,86.07 110.14,85.93 109.87,85.93 109.73,86.07 109.73,86.8 109.59,86.94 95.12,86.94 95.12,86.95 90.14,86.95 89.91,87.18 83.43,87.18 82.77,87.83 78.38,87.83 77.92,87.38 76.93,87.38 73.95,84.4 73.95,82.98 71.8,80.82 71.8,78.51 71.31,78.03 70.76,78.03 69.16,76.43 69.16,75.9 68.57,75.31 65.53,75.31 65.07,74.85 62.91,74.85 62.42,74.37 61.43,74.37 61.13,74.07 58.66,74.07 57.04,72.46 50.33,72.46 49.83,71.96 49.44,71.96 v1(48.99,71.5)
  BOTTOM w0.14: R274.1 51.45,65.68 50.94,65.18 49.17,65.18 48.1,66.24 48.1,69.34 48.99,70.23 v1(48.99,71.5) ; v1(163.88,88.67) 163.88,89.88 163.87,89.89 v2(163.87,90.43) 163.87,90.57 164.1,90.79 164.1,92.86 164.42,93.18 164.42,94.88 165.19,95.66 R205.1
CLK_24M_KBC: length 162.5
  TOP w0.14: U18.2 127.38,44.05 127.53,44.2 127.53,44.65 126.81,45.36 125.95,45.36 125.57,45.75 125.57,48.79 124.68,49.68 124.2,49.68 124.02,49.86 124.02,52.3 124.58,52.86 124.78,52.86 127.07,55.14 128.92,55.14 129.68,55.91 129.68,57.07 v2(130.93,58.32) 131.13,58.52 131.13,59.46 131.56,59.89 131.56,61.27 130.98,61.85 130.98,68.14 v1(130.92,68.2) ; R90.1 53.17,67.46 v1(52.98,67.46)
  IN1 w0.14: v1(52.98,67.46) 53.41,67.89 53.41,69.35 53.55,69.49 54.31,69.49 54.45,69.63 54.45,69.91 54.31,70.05 53.55,70.05 53.41,70.19 53.41,70.46 53.69,70.74 54.91,70.74 55.34,70.31 56.51,70.31 57.58,71.38 57.58,71.58 57.23,71.93 57.23,72.13 57.43,72.33 57.63,72.33 57.98,71.98 58.18,71.98 58.37,72.18 58.37,72.37 58.03,72.72 58.03,72.92 58.22,73.12 58.42,73.12 58.77,72.77 58.99,72.77 59.13,72.91 59.13,73.5 59.27,73.63 59.55,73.63 59.69,73.5 59.69,72.91 59.83,72.77 60.11,72.77 60.25,72.91 60.25,73.5 60.39,73.63 60.67,73.63 60.81,73.5 60.81,73.3 60.98,73.13 61.21,73.13 61.54,73.46 62.3,73.46 63.16,74.32 65.03,74.32 65.67,74.97 68.96,74.97 69.43,75.44 69.85,75.44 69.99,75.58 69.99,76.16 70.15,76.33 70.38,76.33 70.55,76.16 70.55,75.58 70.69,75.44 71.01,75.44 71.22,75.65 71.88,75.65 72.15,75.92 72.15,80.67 74.29,82.81 74.29,83.88 76.67,86.26 80.41,86.26 80.78,86.63 81.03,86.63 81.17,86.77 81.17,87.19 81.31,87.33 81.59,87.33 81.73,87.19 81.73,86.77 81.87,86.63 82.14,86.63 82.28,86.77 82.28,87.19 82.42,87.33 82.7,87.33 82.84,87.19 82.84,86.74 82.93,86.66 89.33,86.66 89.58,86.41 91.96,86.41 92.9,85.48 94.36,85.48 95.21,86.33 99.9,86.33 101.24,84.99 101.59,84.99 101.73,85.13 101.73,86.25 101.87,86.39 102.15,86.39 102.29,86.25 102.29,85.13 102.43,84.99 102.71,84.99 102.85,85.13 102.85,86.25 102.99,86.39 103.27,86.39 103.41,86.25 103.41,85.13 103.55,84.99 103.83,84.99 103.97,85.13 103.97,86.25 104.11,86.39 104.38,86.39 104.52,86.25 104.52,85.13 104.66,84.99 104.94,84.99 105.08,85.13 105.08,86.25 105.22,86.39 105.5,86.39 105.64,86.25 105.64,85.13 105.78,84.99 106.06,84.99 106.2,85.13 106.2,86.25 106.34,86.39 106.62,86.39 106.76,86.25 106.76,85.13 106.9,84.99 107.18,84.99 107.32,85.13 107.32,86.25 107.46,86.39 107.74,86.39 107.88,86.25 107.88,85.13 108.02,84.99 108.43,84.99 108.57,85.13 108.57,85.71 108.71,85.85 108.99,85.85 109.13,85.71 109.13,85.13 109.27,84.99 109.77,84.99 109.91,85.13 109.91,85.26 110.05,85.4 110.33,85.4 110.47,85.26 110.47,85.13 110.61,84.99 119.42,84.99 122.21,82.2 122.21,78.63 123.78,77.05 123.78,74.22 128.88,69.12 129.92,69.12 130.84,68.2 v1(130.92,68.2)
CLK_PCIE_LANN: length 106.9
  TOP w0.102: U12.AK4 67.07,71.64 v1(66.63,71.2) ; v1(147.39,59.44) 147.23,59.59 147.23,59.74 147.42,59.92 U11.16
  IN1 w0.102: v1(147.39,59.44) 147.16,59.66 147.16,60.02 146.56,60.62 145.11,60.62 143.06,62.67 131.7,62.67 131.01,61.99 127.45,61.99 126.72,61.27 121.29,61.27 120.21,62.34 118.7,62.34 116.76,64.29 113.56,64.29 112.33,65.52 108.67,65.52 108.25,65.94 108.04,65.94 102.6,65.94 100.82,67.72 98.52,67.72 96.8,69.43 96.8,72.12 96.27,72.66 95.84,72.66 93.53,74.97 93.53,77.93 94.11,78.51 94.11,80.1 92.55,81.66 91.42,81.66 90.54,82.54 85.04,82.54 84.3,81.8 81.93,81.8 80.83,80.7 80.83,78.3 79.4,76.87 78.72,76.87 76.34,74.5 76.05,74.5 72.3,70.75 71.36,70.75 69.99,69.38 68.28,69.38 67.71,69.95 67.71,70.71 67.42,71.01 66.83,71.01 v1(66.63,71.2)
CLK_PCIE_LANP: length 106.9
  TOP w0.102: U12.AK6 66.99,70.96 66.64,70.61 v1(66.64,70.51) ; U11.15 147.02,59.65 146.8,59.44 v1(146.7,59.44)
  IN1 w0.102: v1(66.64,70.51) 66.64,70.64 66.82,70.82 67.34,70.82 67.52,70.63 67.52,69.87 68.2,69.19 70.07,69.19 71.44,70.56 72.38,70.56 76.13,74.31 76.42,74.31 78.8,76.68 79.48,76.68 81.02,78.22 81.02,80.62 82.01,81.61 84.38,81.61 85.12,82.35 90.46,82.35 91.34,81.47 92.47,81.47 93.92,80.02 93.92,78.59 93.34,78.01 93.34,74.89 95.76,72.47 96.19,72.47 96.61,72.04 96.61,69.35 98.44,67.53 100.75,67.53 102.52,65.75 108.12,65.75 108.12,65.75 108.18,65.75 108.6,65.33 112.25,65.33 113.48,64.1 116.68,64.1 118.62,62.15 120.13,62.15 121.21,61.07 126.8,61.07 127.52,61.8 131.09,61.8 131.78,62.48 142.98,62.48 145.04,60.43 146.48,60.43 146.97,59.94 146.97,59.6 146.8,59.44 v1(146.7,59.44)
CLK_PCIE_WLAN_REQ#_R: length 8.3
  BOTTOM w0.102: CN10.7 v1(164.73,77.3) 164.59,77.3 163.62,78.27 R231.2 162.73,78.27 Q19.3 162.81,79.15 R537.2
CLK_PCIE_WLANN: length 135.8
  TOP w0.102: U12.AF9 68.83,69.54 v1(68.57,69.8)
  IN1 w0.102: CN10.11 167.44,79.2 166.73,79.2 166.31,79.63 166.31,80.91 165.57,81.65 164.07,81.65 154.65,72.23 154.65,71.13 152.99,69.47 152.99,67.68 150.89,65.58 148.77,65.58 147.54,66.81 146,66.81 144.9,65.71 143.94,65.71 142.9,64.67 140.82,64.67 140.09,63.93 131.99,63.93 130.66,62.6 126.69,62.6 125.97,61.87 121.54,61.87 120.46,62.95 118.96,62.95 116.99,64.92 113.87,64.92 112.66,66.13 108.93,66.13 108.28,66.77 105.58,66.77 104.86,67.5 101.95,67.5 101.12,68.33 99.11,68.33 97.46,69.97 97.46,72.87 96.47,73.86 95.5,73.86 94.14,75.22 94.14,77.52 94.72,78.11 94.72,81.3 93.71,82.31 91.65,82.31 90.81,83.15 84.03,83.15 83.3,82.42 81.53,82.42 80.88,81.78 77.7,81.78 76.17,80.24 76.17,79.08 75.8,78.71 75.8,75.11 72.27,71.58 71.18,71.58 69.65,70.05 68.83,70.05 v1(68.57,69.8)
CLK_PCIE_WLANP: length 135.7
  TOP w0.102: U12.AF7 68.86,70.25 v1(68.62,70.49)
  IN1 w0.102: CN10.13 167.44,79.39 166.81,79.39 166.5,79.71 166.5,80.99 165.65,81.84 164,81.84 154.46,72.3 154.46,71.21 152.8,69.55 152.8,67.76 150.81,65.77 148.85,65.77 147.62,67.01 145.92,67.01 144.82,65.9 143.86,65.9 142.82,64.86 140.75,64.86 140.01,64.12 131.92,64.12 130.58,62.79 126.61,62.79 125.89,62.07 121.62,62.07 120.54,63.14 119.03,63.14 117.07,65.11 113.95,65.11 112.74,66.32 109.01,66.32 108.36,66.96 105.66,66.96 104.93,67.69 102.03,67.69 101.2,68.52 99.19,68.52 97.65,70.05 97.65,72.95 96.55,74.05 95.57,74.05 94.33,75.3 94.33,77.44 94.91,78.03 94.91,81.38 93.79,82.5 91.73,82.5 90.89,83.34 83.95,83.34 83.22,82.61 81.45,82.61 80.8,81.97 77.62,81.97 75.98,80.32 75.98,79.16 75.61,78.79 75.61,75.19 72.19,71.77 71.1,71.77 69.57,70.24 68.86,70.24 v1(68.62,70.49)
CLKRUN#: length 163.9
  TOP w0.14: v1(47.74,44.08) 47.74,43.86 47.95,43.65 R533.1 ; v1(107.94,28.63) 109.71,28.63 110.04,28.3 122.99,28.3 124.57,29.87 124.57,31.95 123.84,32.68 123.84,39.92 125.02,41.1 125.02,41.28 125.45,41.71 125.67,41.71 125.72,41.65 U18.8
  IN1 w0.14: v1(107.94,28.63) 107.94,27.23 106.54,25.83 97.7,25.83 97.4,25.53 89.6,25.53 88.43,24.36 80.46,24.36 79.09,25.73 73.2,25.73 72.29,26.64 60.21,26.64 60.07,26.5 60.07,24.83 59.93,24.69 59.65,24.69 59.51,24.83 59.51,26.5 59.37,26.64 59.09,26.64 58.95,26.5 58.95,24.83 58.81,24.69 58.53,24.69 58.39,24.83 58.39,26.5 58.25,26.64 57.92,26.64 57.78,26.5 57.78,25.51 57.64,25.37 57.37,25.37 57.23,25.51 57.23,26.5 57.09,26.64 56.68,26.64 56.54,26.5 56.54,25.24 56.4,25.1 56.12,25.1 55.98,25.24 55.98,26.5 55.84,26.64 55.6,26.64 55.46,26.5 55.46,25.87 55.32,25.73 55.04,25.73 54.9,25.87 54.9,26.5 54.76,26.64 54.48,26.64 54.34,26.5 54.34,25.87 54.2,25.73 53.92,25.73 53.78,25.87 53.78,26.5 53.64,26.64 52.34,26.64 51.58,27.41 48.49,27.41 47.44,28.46 47.44,29.85 47.77,30.18 47.77,33.91 46.78,34.9 46.78,35.42 46.6,35.6 46.23,35.6 46.09,35.74 46.09,36.02 46.23,36.16 46.57,36.16 46.77,36.35 46.77,36.74 46.32,37.19 46.32,37.59 46.7,37.97 46.7,40.59 47.1,40.99 47.1,41.19 46.64,41.65 46.64,41.85 46.84,42.04 47.03,42.04 47.5,41.58 47.69,41.58 48,41.88 48,42.3 47.86,42.44 47.22,42.44 47.08,42.58 47.08,42.86 47.22,43 47.86,43 48,43.14 48,43.41 47.87,43.54 47.16,43.54 46.94,43.75 46.94,44.03 46.73,44.25 46.73,44.83 46.96,45.06 47.2,45.06 47.34,44.92 47.34,44.47 v1(47.74,44.08) 47.87,44.08 48.05,44.25 48.05,44.73 48.2,44.88 49.34,44.88 49.5,45.03 49.5,45.36 49.34,45.52 47.46,45.52 47.12,45.86 47.12,50.18 50.44,53.49 52.19,53.49 54.39,55.69 54.39,58.03 55.16,58.8 55.16,62.31 v1(55.29,62.43)
  BOTTOM w0.14: v1(55.29,62.43) 54.9,62.82 R279.1
CODEC_JDREF: length 4.6
  TOP w0.14: R45.1 25.87,78.87 25.59,78.59 25.04,78.59 24.55,79.07 24.1,79.07 23.46,78.44 U9.15
CODEC_VREF:
  vias: v1(17.47,75.62)
CORE_PWROK: length 16.3
  TOP w0.102: U12.B7 81.02,70.58 81.52,70.58 81.78,70.84 81.78,72.27 81.79,72.28 81.79,72.62 81.78,72.63 81.78,74.17 81.53,74.42 78.57,74.42 78.22,74.78 76.65,74.78 74.72,76.71 R57.2 73.93,77.51 R56.1 ; R56.1 73.7,77.11 73.6,77.01 v2(73.6,76.23) ; R56.1 73.23,77.51 R49.2
CORE_V1P05: length 20.8
  TOP w0.203: U12.AC32 71.12,58.6 v1(71.91,58.6)
  TOP w0.254: U12.Y32 72.29,58.22 v1(71.91,58.6)
  IN2 w0.508: v1(71.91,58.6) 71.57,58.6 70.78,57.81 70.15,57.81 69.71,57.38 69.71,54.88 68.97,54.13 68.37,54.13 67.45,53.21 65.8,53.21 65.27,53.75 61.92,53.75 61.08,52.91 60.11,52.91 59.76,53.26 v1(59.76,53.58)
  BOTTOM w0.508: 58.72,53.34 v2(58.72,53.34) ; 58.72,53.34 58.57,53.48 R333.2 ; 58.72,53.34 58.8,53.42 59.6,53.42 v1(59.76,53.58)
CORE_V1P05_S3_PW:
  vias: v1(60.45,53.58) v1(68.78,57.11) v1(70.34,57.7) v1(71.91,57.06) v1(73.48,57.12)
CPU_VREF: length 5.7
  TOP w0.254: v1(68.6,51.87) 68.73,52 68.91,52 U12.AF44
  BOTTOM w0.254: v2(69.3,51.23) 69.28,51.23 68.66,51.86 68.61,51.86 v1(68.6,51.87) 68.59,51.86 68.56,51.86 68,51.29 68,50.98 C273.1 67.49,49.44 R342.1 R344.2
CPUFAN#: length 2.2
  TOP w0.102: U18.22 127.73,36.05 v1(127.78,36)
  BOTTOM w0.102: TP38.1 126.85,36 v1(127.78,36)
DARM_V1P0_SOIX_PWR:
  vias: v1(67.21,56.3) v1(68.78,56.3) v1(70.34,56.33) v1(71.91,56.3) v2(58.62,55.55)
DCAP: length 4
  BOTTOM w0.102: PC187.2 84.24,17.6 v2(84.24,18.57)
  BOTTOM w0.203: PC187.2 83.53,16.89 83.53,16.15 82.91,15.53 PU16.16
DDI1_DDCDATA: length 4.2
  TOP w0.102: v1(74.39,59.47) 74.39,59.42 U12.P30
  BOTTOM w0.102: R303.1 76.27,57.68 v2(75.96,57.99) 75.96,58.45 75.3,59.11 74.75,59.11 v1(74.39,59.47)
DDI1_EDP_HPD_R: length 71.8
  TOP w0.102: v1(57.78,45.14) 54.65,48.26 54.65,50.37 52.57,52.45 48.94,52.45 v2(48.72,52.24) 47.41,50.93 46.35,50.93 46.04,51.23 46.04,51.66 45.53,52.17 44.11,52.17 44.01,52.27 44.01,53.47 44.11,53.57 44.11,54.41 44.09,54.43 44.09,54.45 42.87,55.67 v1(42.87,55.98) ; U12.K30 76.89,59.17 v1(76.52,59.54)
  IN1 w0.102: v1(36.16,61.49) 36.87,62.2 39.31,62.2 42.87,58.65 v1(42.87,55.98) ; v1(57.78,45.14) 57.78,45.77 58.59,46.58 58.59,47.32 58.87,47.6 60.19,47.6 62.27,49.68 62.27,53.57 62.73,54.03 64.84,54.03 65.83,55.02 65.83,56.21 65.17,56.87 65.17,58.7 65.44,58.98 66.16,58.98 66.34,58.8 67.19,58.8 68.01,59.62 68.01,60.27 68.27,60.53 76.01,60.53 76.52,60.02 v1(76.52,59.54)
  BOTTOM w0.102: v1(36.16,61.49) 36.16,61.06 35.93,60.83 Q28.3 34.59,60.83 34.26,60.5 R307.2
DDI_V1P0_SOIX: length 29.7
  TOP w0.254: v1(67.21,65.43) 67.59,65.05 U12.AJ18 ; U12.AK21 66.83,63.53 v1(67.21,63.91) 66.83,64.29 U12.AK19 ; v1(66.42,65.43) 66.04,65.81 U12.AM16
  IN2 w0.508: v1(66.42,65.43) 66.42,65.7 65.42,66.7 57.8,66.7 56.89,67.62 55.16,67.62 54.3,66.75 54.3,64.69 53,63.4 51.83,63.4 51.3,62.87 51.3,61.57 49.5,59.77 48.91,59.77 48.17,59.03 48.17,57.25 48.53,56.9 v1(48.91,56.9)
  vias: v1(50.33,55.5)
DGPU_CL_HDMIP: length 11.8
  BOTTOM w0.508: R212.1 R211.1 R210.1 R209.1 R208.1 ; R212.1 68.55,87.91 68.8,87.66 Q15.3 ; R212.1 R213.1 R214.1 R215.1 72.61,88.29 72.62,88.29 v2(72.83,88.08)
DIMM0_SA0: length 3.3
  TOP w0.102: v1(46.51,33.14) 46.46,33.2 JDIM6.197
  BOTTOM w0.102: v1(46.51,33.14) 46.63,33.26 R393.1 v2(45.47,33.8)
DIMM0_SA1: length 5
  TOP w0.102: JDIM6.201 45.26,33.18 v1(45.22,33.14)
  BOTTOM w0.102: R389.1 46.2,34.82 45.95,35.07 v2(45.47,35.07) 44.99,34.59 44.99,33.37 v1(45.22,33.14)
DMIC_CLK: length 62.4
  TOP w0.14: U3.4 75.91,87.86 75,86.95 75,86.54 v2(74.36,85.9) 72.55,84.09 T3.1 71.86,84.09 v1(71.62,84.33) ; v1(26.2,73.25) 26.12,73.17 U9.3
  IN1 w0.14: v1(26.2,73.25) 25.59,73.25 25.09,73.76 25.09,76.51 26.03,77.44 30.5,77.44 30.95,76.99 36.11,76.99 36.85,77.72 36.85,78.61 38.22,79.98 53.53,79.98 57.75,84.2 69.36,84.2 69.79,83.77 71.06,83.77 v1(71.62,84.33)
DMIC_DAT: length 64.5
  TOP w0.14: v1(70.98,84.33) 70.98,82.98 71.19,82.78 T2.1 72.46,83.55 72.77,83.55 72.77,83.57 72.9,83.69 73.42,83.69 v2(73.69,83.97) 75.93,86.21 U3.5 ; U9.2 26.05,72.77 26.18,72.64 v1(26.18,72.62)
  IN1 w0.14: v1(70.98,84.33) 70.83,84.48 57.63,84.48 53.42,80.26 37.99,80.26 36.47,78.74 36.47,77.72 36.03,77.29 31.13,77.29 30.7,77.72 25.77,77.72 24.6,76.56 24.6,73.58 25.57,72.62 v1(26.18,72.62)
DNBSWON#: length 68.8
  TOP w0.14: U18.91 141.41,42.45 141.27,42.59 140.7,42.59 140.05,43.24 140.05,43.71 141.01,44.68 141.01,44.93 142.99,46.91 142.99,49.9 139.89,53.01 139.89,53.99 139.62,54.26 138.94,54.26 138.54,53.87 137.07,53.87 134.84,56.09 v1(134.84,57.35)
  IN1 w0.14: v1(134.84,57.35) 134.13,58.06 133.47,58.06 133.17,58.37 132.26,58.37 132.25,58.38 127.14,58.38 126.89,58.13 125.96,58.13 125.76,58.33 120.51,58.33 120.43,58.41 120.41,58.41 119.85,58.97 118.32,58.97 116.72,60.58 114.03,60.58 111.38,63.23 107.96,63.23 107.84,63.1 104.66,63.1 104.21,63.54 101.75,63.54 100.81,64.48 95.55,64.48 v1(95.22,64.82)
  BOTTOM w0.14: v1(95.22,64.82) 95.22,65.21 94.09,66.33 U25.1
DPWROK_EC: length 106.2
  TOP w0.102: v1(126.13,82.88) 126.08,82.83 125.44,82.83 124.24,81.63 124.24,78.85 124.69,78.4 124.69,75.18 126.48,73.38 126.48,72.83 128.64,70.67 128.64,70.38 129.57,69.44 131.24,69.44 131.7,68.99 131.7,62.35 132.3,61.75 132.3,60.89 132.7,60.5 132.7,59.52 133.09,59.13 133.09,58.83 133.85,58.07 133.85,56.39 136,54.24 136,47.08 135.86,46.94 U18.109 ; R57.1 74.72,78.03 75.61,78.92 v2(76.01,78.92) 76.47,79.38 76.47,81.05 77.05,81.64 80.3,81.64 v1(82.61,83.95)
  IN2 w0.102: v1(82.61,83.95) 83.24,83.31 89.32,83.31 89.7,83.69 92.37,83.69 97.49,88.8 102.78,88.8 103.75,89.78 121.21,89.78 v1(122.9,88.09)
  BOTTOM w0.102: v1(126.13,82.88) 126.13,84.25 122.9,87.48 v1(122.9,88.09)
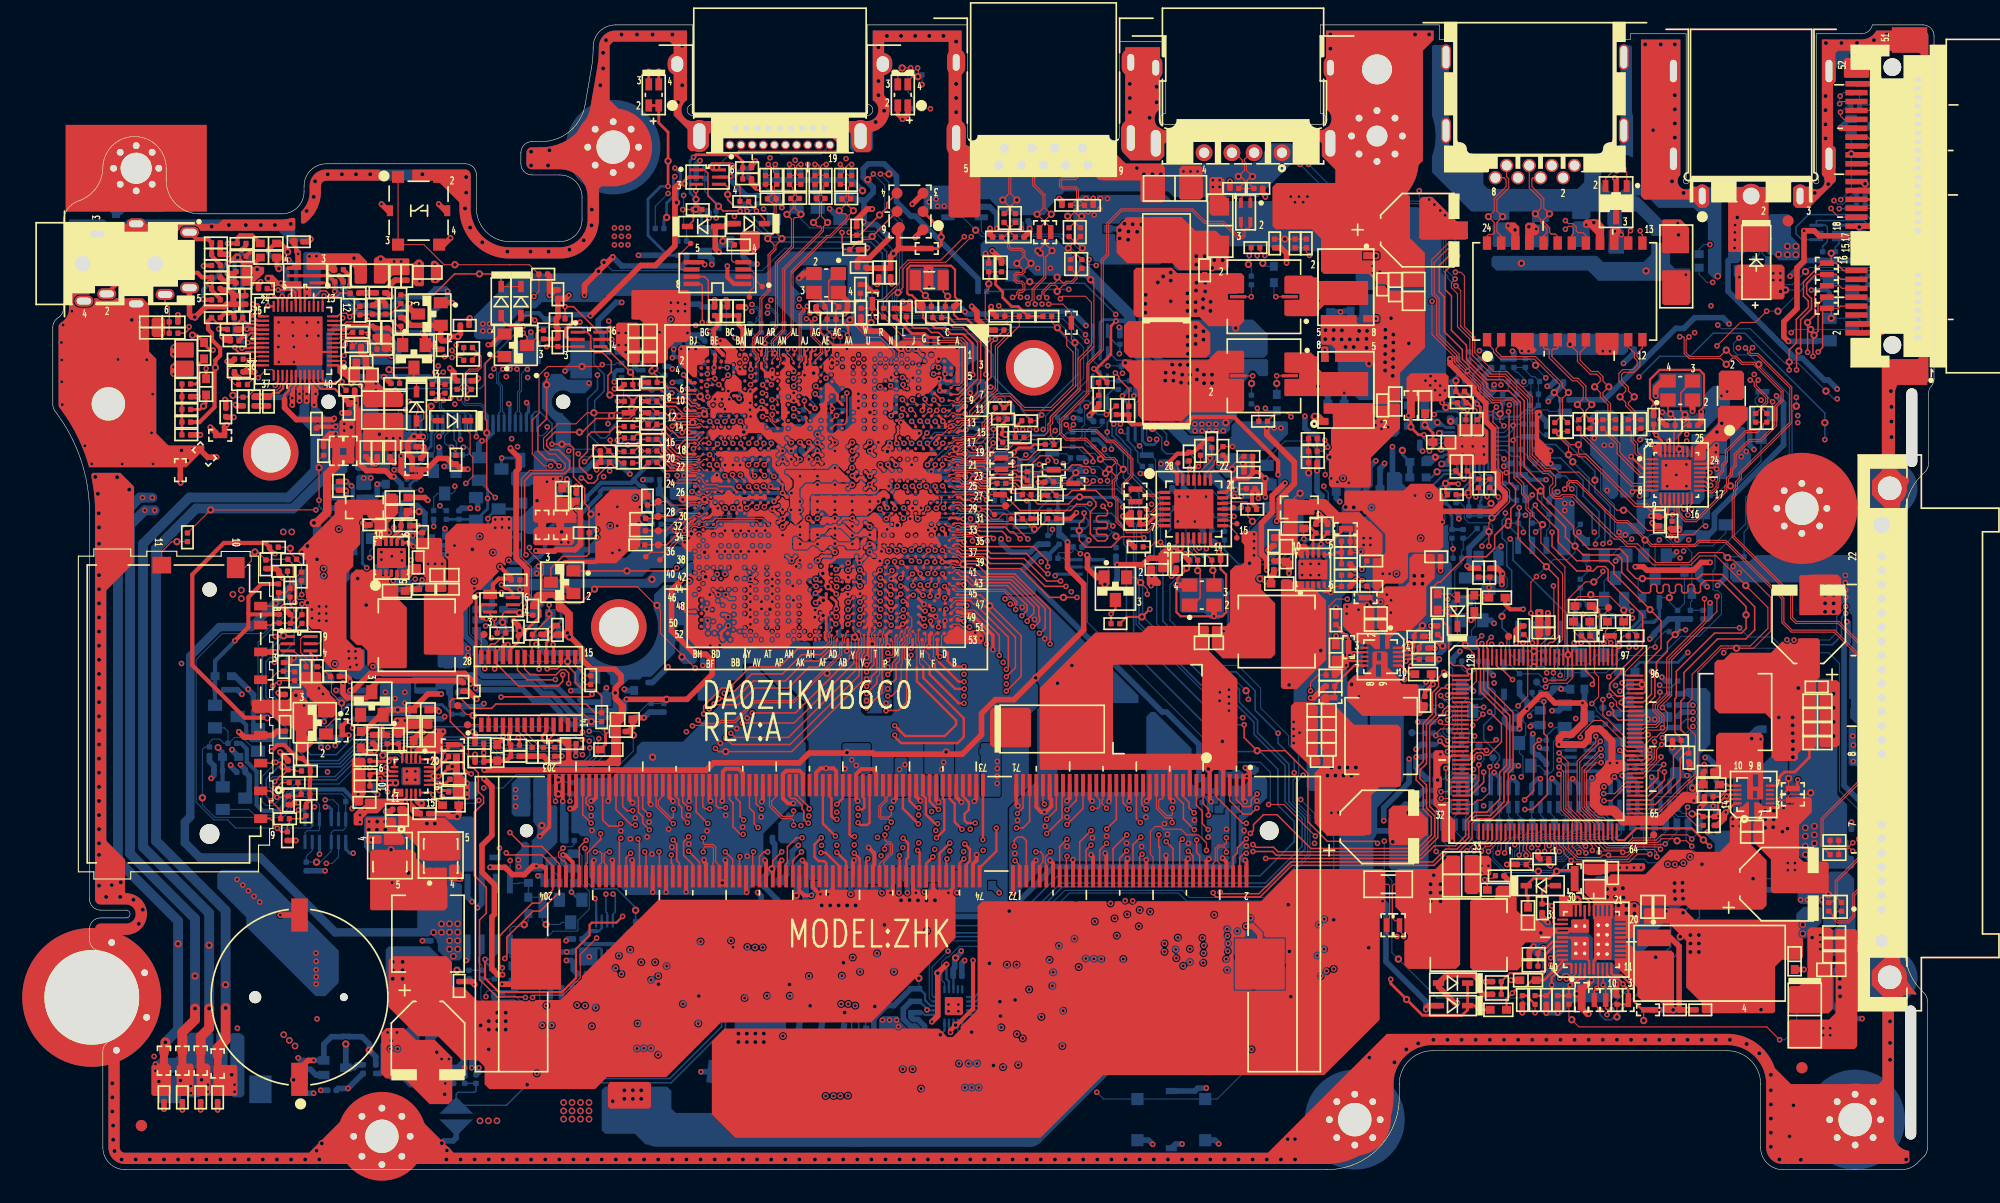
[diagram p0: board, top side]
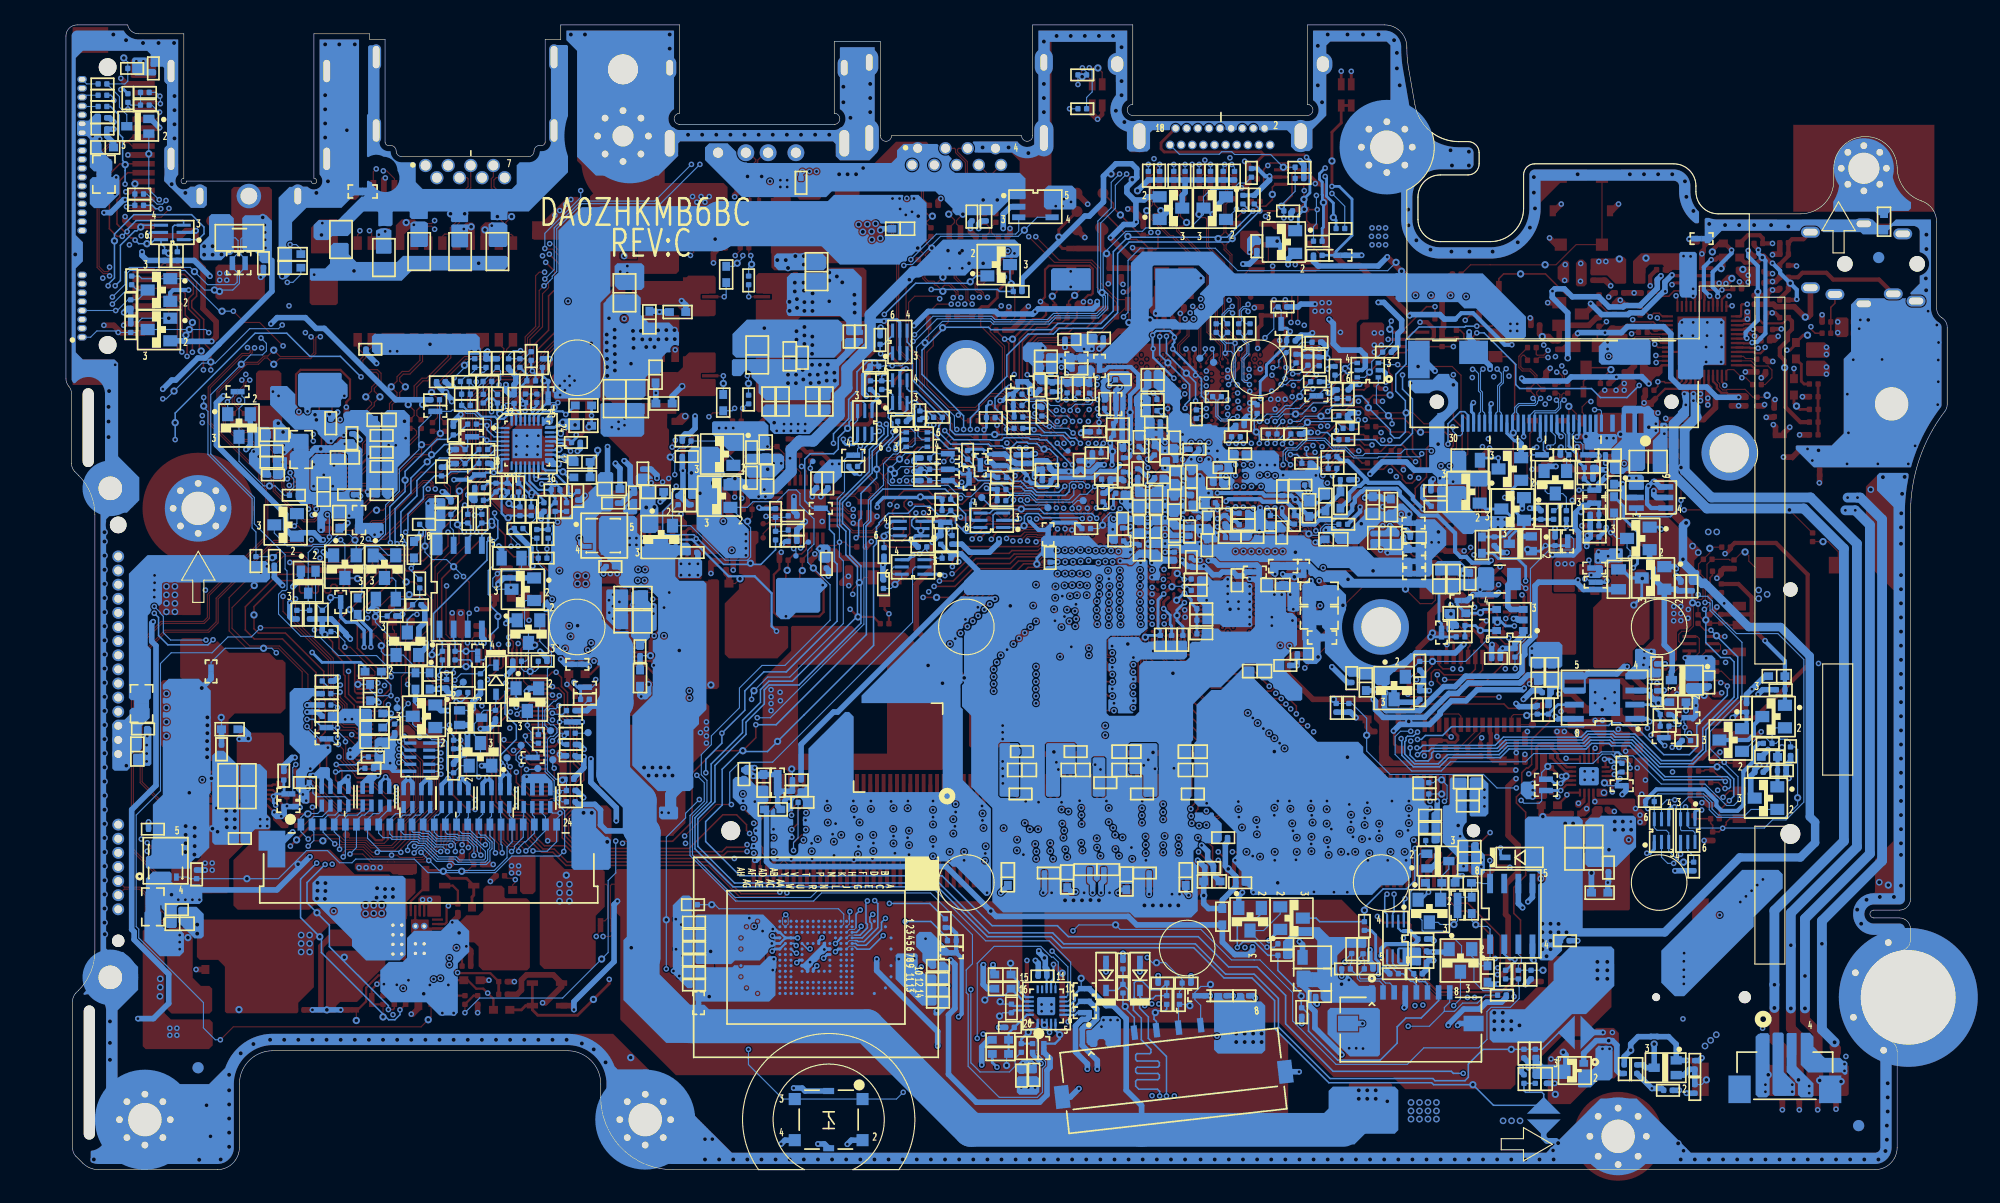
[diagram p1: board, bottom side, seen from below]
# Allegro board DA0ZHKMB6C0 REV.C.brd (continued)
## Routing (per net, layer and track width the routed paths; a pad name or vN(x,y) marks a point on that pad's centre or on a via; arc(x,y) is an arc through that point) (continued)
DRAM_RCOMP0: length 6
  TOP w0.254: v1(70.47,51.8) 70.09,52.17 U12.AD44
  BOTTOM w0.254: v1(70.47,51.8) 70.47,51.79 70.98,51.28 70.98,48.74 70.78,48.54 R349.2 71.96,48.07 v2(72.12,47.91)
DRAM_RCOMP1: length 4.1
  TOP w0.254: U12.AF45 69.04,51.46 v1(68.6,51.02)
  BOTTOM w0.254: v1(68.6,51.02) 69.28,50.34 v2(69.28,49.86) 69.28,49.4 68.74,48.86 R347.2
DRAM_RCOMP2: length 3.9
  TOP w0.254: U12.AD45 70.08,51.46 70.47,51.06 v1(70.47,50.47)
  BOTTOM w0.254: R348.1 69.76,48.92 69.89,49.05 69.89,49.89 v1(70.47,50.47)
DRM_PWOK_C1: length 4.1
  BOTTOM w0.102: R364.2 v2(95.62,57) 95.62,57.2 95.47,57.35 95.29,57.35 ; Q53.5 94.96,57.68 95.29,57.35 ; 95.29,57.35 94.97,57.03 Q53.6
DRM_PWOK_C2: length 4.6
  BOTTOM w0.102: Q32.5 94.73,54.23 94.96,54 94.96,53.75 94.79,53.58 Q32.6 94.03,53.25 v2(94.63,52.65) 95,52.29 R338.2
E775AGND: length 14.1
  TOP w0.102: C109.2 137.2,48.03 136.77,48.46 C103.2 136.77,49.99 136.9,50.11 L14.2 136.9,51.26 137.2,51.56 140.07,51.56 v2(141.29,50.34) C104.1 141.29,48.82 141.62,48.49 142.01,48.49 C110.1
  TOP w0.203: C109.2 138.26,47.27 U18.103
EC_FPBACK#: length 12.1
  TOP w0.102: v1(140.94,43.05) 140.99,43.05 141.59,43.65 U18.94
  IN1 w0.102: v1(140.94,43.05) 140.45,43.05 140.38,43.13 139.56,43.13 139.46,43.23 136.9,43.23 135.5,41.83 134.66,41.83 133.72,40.89 132.91,40.89 v1(132.83,40.82)
  BOTTOM w0.102: Q35.2 133.11,41.33 132.83,41.05 v1(132.83,40.82)
EC_GPIO50_SUS: length 95
  TOP w0.102: v1(26.97,39.73) 27.68,40.44 PQ38.2
  IN1 w0.102: v1(26.97,39.73) 27.47,40.23 29.81,40.23 30.14,39.9 33.67,39.9 33.85,39.73 33.85,38.64 34.57,37.92 35.22,37.92 37.08,36.07 37.08,35.56 37.76,34.87 38.22,34.87 v1(38.75,34.34) 39.67,33.43 39.67,28.01 45.3,22.38 55.67,22.38 57.98,20.07 59.27,20.07 60.44,21.23 62.53,21.23 62.76,21.01 76.04,21.01 76.98,20.07 80.1,20.07 v1(80.51,19.66)
  BOTTOM w0.102: v1(38.75,34.34) 40.49,34.34 41.71,35.56 50.11,35.56 52.21,37.67 v2(52.21,39.09) 52.21,40.61 53.54,41.94 PC171.1 PC172.1 ; PU16.10 79.25,15.53 79.09,15.7 79.09,18.25 80.51,19.67 v1(80.51,19.66)
EC_PECR_R: length 5.4
  TOP w0.102: U18.13 124.83,39.65 124.38,39.21 v1(124.38,39.05) 124.43,39 125.02,39 v1(125.44,38.58)
  BOTTOM w0.102: R374.2 124.75,39.27 v1(125.44,38.58)
EC_PWROK: length 232
  TOP w0.102: v1(109.35,32.85) 110.72,32.85 v1(113.56,30.01) ; R56.2 73.7,78.28 74.64,78.28 76.15,79.79 76.15,81.06 76.93,81.84 79.87,81.84 v1(81.97,83.95)
  IN1 w0.102: v1(156.61,47.65) 156.23,47.27 154.47,47.27 153.31,46.1 148.68,46.1 147.74,45.16 147.74,42.13 147.92,41.95 147.92,40.28 v1(147.51,39.88) 145.41,41.99 142.41,41.99 140.63,40.21 138.83,40.21 138.01,41.02 136.74,41.02 136.08,40.36 136.08,39.83 135.07,38.81 135.07,37.52 133.49,35.94 131.07,35.94 130.46,35.33 128.31,35.33 128.17,35.19 128.17,35.19 127.93,34.95 127.93,34.95 127.59,34.61 124.6,34.61 123.06,33.07 114.58,33.07 113.56,32.05 v1(113.56,30.01)
  IN2 w0.102: v1(160.49,69.35) 160.49,67.84 158.78,66.13 158.78,64.99 161.67,62.09 161.67,57.11 162.38,56.4 162.38,51.8 v1(161.26,50.67) ; v1(149.75,76) 147.49,76 146.93,75.44 146.02,75.44 145.38,74.8 144.16,74.8 142.43,73.08 137.53,73.08 135.42,75.18 129.68,75.18 128.13,76.74 128.13,83.27 126.48,84.92 125.47,84.92 120.82,89.58 103.99,89.58 102.99,88.59 97.56,88.59 92.46,83.49 89.79,83.49 89.41,83.11 82.87,83.11 82.03,83.95 v1(81.97,83.95)
  BOTTOM w0.102: v1(161.26,50.67) 160.72,50.14 160.72,50.06 160.44,49.78 160.44,48.31 159.78,47.65 v1(156.61,47.65) ; Q32.2 92.83,54.23 93.06,54 93.06,49.25 105.64,36.67 108.6,36.67 109.5,35.76 109.5,33 v1(109.35,32.85) ; v1(160.49,69.35) 160.18,69.35 v2(159.48,70.05) 156.96,72.57 155.77,72.57 152.67,75.67 150.08,75.67 v1(149.75,76) ; R375.2 146.4,38.76 v1(147.51,39.88)
EDID_PWR: length 3.5
  BOTTOM w0.102: CN16.10 33.6,66.27 33.7,66.17 33.72,66.14 33.72,65.77 33.41,65.46 32.99,65.46 32.77,65.24 R275.1
EDP_AUX#_C: length 10.4
  TOP w0.102: C65.1 38.52,73.19 38.52,72.16 38.22,71.86 37.53,71.86 37.08,71.4 37.08,70.76 R71.2 37.1,69.67 37.1,69.55 v1(37.25,69.39)
  BOTTOM w0.102: v1(37.25,69.39) 37.02,69.16 37.02,69.03 37.12,68.94 38.55,68.94 38.9,68.58 38.9,68.15 39.1,67.95 CN16.21
EDP_AUX_C: length 10.5
  TOP w0.102: v1(36.57,69.39) 36.92,69.75 36.92,69.95 36.67,70.21 R70.2 36.9,70.74 36.9,71.47 37.46,72.03 38.14,72.03 38.35,72.24 38.35,73.11 38.18,73.28 38.07,73.28 37.74,72.96 C64.1
  BOTTOM w0.102: CN16.20 38.6,67.99 38.73,68.12 38.73,68.51 38.47,68.76 37.05,68.76 36.85,68.96 36.85,69.11 v1(36.57,69.39)
EDP_TX0#_C: length 5.5
  TOP w0.102: v1(35.14,69.24) 35.07,69.24 34.84,69.47 34.84,69.75 34.96,69.87 C67.1
  BOTTOM w0.102: CN16.18 37.6,67.8 37.13,68.28 35.27,68.28 34.94,68.61 34.94,69.04 v1(35.14,69.24)
EDP_TX0_C: length 5.5
  TOP w0.102: C66.1 34.52,69.87 34.66,69.72 34.66,69.44 v1(34.46,69.24)
  BOTTOM w0.102: v1(34.46,69.24) 34.61,69.24 34.76,69.09 34.76,68.53 35.2,68.1 37.05,68.1 37.1,68.05 CN16.17
EEPROM_SDA: length 2.5
  TOP w0.102: R367.1 102.25,63.72 v1(102.25,63.1) 102.12,62.97 U13.26
  BOTTOM w0.102: v1(102.25,63.1) 102.25,63.5 TP54.1
EMMC_CLK: length 112.8
  TOP w0.14: U12.AT22 64.36,62.88 v1(64.86,62.38)
  IN2 w0.14: v1(103.5,19.48) 104.03,20.02 104.03,20.9 99.18,25.75 87.41,25.75 85.9,27.27 66.35,27.27 66.23,27.15 52.17,27.15 51.94,27.38 48.45,27.38 47.26,28.58 47.26,29.24 46.52,29.97 46.52,31.17 44.7,32.99 44.7,33.62 45.33,34.25 45.33,37.62 46.22,38.51 46.22,40.01 46.26,40.05 46.26,40.07 47.27,41.08 47.29,41.08 47.97,41.76 47.97,42.93 49.67,44.63 52.8,44.63 55.52,47.35 55.52,51.69 54.99,52.21 54.99,57.82 55.5,58.33 58.21,58.33 58.97,59.08 62.58,59.08 62.86,59.36 62.86,59.77 63.44,60.35 63.59,60.35 64.16,60.92 64.62,60.92 64.99,61.29 64.99,61.87 64.86,62 v1(64.86,62.38)
  BOTTOM w0.14: v1(103.5,19.48) 103.62,19.48 U30.W6
EMMC_CMD: length 115.5
  TOP w0.14: U12.AV26 62.94,61.1 v1(62.58,61.46)
  IN2 w0.14: v1(62.58,61.46) 62.58,61.11 62.09,60.63 58.53,60.63 57.4,59.5 55.11,59.5 53.84,58.22 53.84,56.06 50.97,53.2 49.48,53.2 46.89,50.61 46.89,46.45 46.55,46.11 46.55,44.58 45.86,43.89 45.86,41.33 45.11,40.58 45.11,40.09 44.15,39.13 44.15,34.7 43.55,34.11 43.55,32.56 45.22,30.9 45.22,29.33 45.09,29.2 45.09,28.02 45.9,27.22 46.83,27.22 47.77,26.28 51.48,26.28 51.88,25.87 66.63,25.87 66.92,26.16 82.91,26.16 85.12,23.95 v1(95.14,23.95) 95.62,23.47 97.2,23.47 97.73,24 99.46,24 103.29,20.17 v1(103.52,20.17)
  BOTTOM w0.14: U30.W5 103.7,20.35 v1(103.52,20.17) ; R15.2 91.5,23.95 v1(95.14,23.95)
EMMC_DATA_0: length 111.6
  TOP w0.14: v1(62.58,63.42) 62.94,63.79 U12.AV20
  IN2 w0.14: v1(97.68,21.9) 97.27,21.49 94.66,21.49 94.26,21.88 93.26,21.88 93.11,22.03 80.3,22.03 79.35,22.98 73.11,22.98 73.04,23.06 73.04,23.06 67.71,23.06 67.38,23.39 52.07,23.39 51.67,23.79 48.38,23.79 47.72,24.45 46.49,24.45 45,25.93 43.5,25.93 43.04,26.39 43.04,28.52 42.42,29.15 42.01,29.15 41.31,29.85 40.94,29.85 40.66,30.12 40.66,30.68 41.02,31.05 41.02,34.44 42.59,36.01 42.59,45.49 43.22,46.13 44.5,46.13 45.43,47.06 45.43,51.56 49.32,55.45 49.98,55.45 52.09,57.56 52.09,59.56 52.59,60.07 52.85,60.07 54.47,61.7 54.47,62.36 55.08,62.97 62.2,62.97 62.58,63.35 v1(62.58,63.42)
  BOTTOM w0.14: v1(97.68,21.9) 97.68,21.77 98.1,21.35 U30.H3
EMMC_DATA_1: length 107.3
  TOP w0.14: v1(64.02,62.45) 63.65,62.82 U12.AU22
  IN2 w0.14: v1(64.02,62.45) 64.02,62.25 63.75,61.98 62.48,61.98 62.14,61.65 62.14,61.24 61.84,60.93 58.42,60.93 57.27,59.79 55.24,59.79 54.91,59.79 53.55,58.43 53.55,56.19 50.85,53.49 49.27,53.49 46.6,50.83 46.6,46.58 45.38,45.36 45.38,44.93 44.76,44.31 44.76,40.15 43.86,39.25 43.86,34.82 43.18,34.15 43.18,32.5 44.92,30.76 44.92,29.45 44.8,29.33 44.8,27.9 45.77,26.92 46.02,26.92 46.7,26.92 47.65,25.98 51.36,25.98 51.76,25.58 66.77,25.58 67.06,25.87 82.71,25.87 85.1,23.49 94.79,23.49 95.16,23.11 96.49,23.11 v1(96.64,22.96)
  BOTTOM w0.14: v1(96.64,22.96) 96.89,22.71 96.89,22.3 96.74,22.15 96.74,21.69 97.58,20.85 U30.H4
EMMC_DATA_2: length 107.6
  TOP w0.14: U12.AV22 62.94,62.63 v1(63.14,62.43)
  IN2 w0.14: v1(63.14,62.43) 62.42,62.43 62.02,62.03 61.66,62.03 61.43,61.8 61.33,61.8 60.82,61.29 58.36,61.29 57.6,60.53 57.22,60.53 57.02,60.73 55.41,60.73 54.92,60.23 54.92,60.21 53.18,58.47 53.18,56.23 50.73,53.78 49.13,53.78 46.31,50.97 46.31,46.7 45.05,45.44 45.05,45.04 44.47,44.45 44.47,40.34 43.5,39.37 43.5,34.93 42.82,34.24 42.82,32.44 44.63,30.62 44.63,29.57 44.5,29.45 44.5,27.78 45.67,26.62 46.59,26.62 46.68,26.54 46.7,26.52 46.92,26.29 47.53,25.69 51.24,25.69 52.47,24.46 66.08,24.46 67.2,25.58 82.59,25.58 85.02,23.15 94.6,23.15 95.14,22.61 v1(95.5,22.61)
  BOTTOM w0.14: v1(95.5,22.61) 95.85,22.25 95.85,21.59 97.25,20.19 98.01,20.19 98.17,20.35 U30.H5
EMMC_DATA_3: length 119.1
  TOP w0.14: U12.AT20 64.36,63.79 v1(64,63.42)
  IN2 w0.14: v1(98.7,23.22) 98.7,22.28 97.04,20.63 93.31,20.63 92.5,21.44 80.07,21.44 79.11,22.4 77.82,22.4 77.62,22.19 67.71,22.19 67.13,22.78 51.86,22.78 51.42,23.21 48.1,23.21 47.47,23.84 46.25,23.84 46.19,23.9 46.17,23.9 44.77,25.3 43.25,25.3 42.41,26.14 42.41,28.33 42.18,28.56 41.77,28.56 41.07,29.26 40.69,29.26 40.06,29.9 40.06,30.98 40.44,31.36 40.44,34.71 41.42,35.69 41.42,39.27 41.88,39.73 41.88,45.68 42.92,46.71 43.73,46.71 44.02,47 44.02,51.09 49.14,56.21 49.84,56.21 51.41,57.78 51.41,60.54 52.44,61.57 53.17,61.57 53.56,61.96 53.56,62.03 53.56,62.28 54.83,63.55 57.67,63.55 58.94,64.82 59.58,64.82 59.91,64.49 63.06,64.49 64,63.55 v1(64,63.42)
  BOTTOM w0.076: U30.J2 98.74,22.1 98.74,22.56
  BOTTOM w0.14: v1(98.7,23.22) 98.74,23.17 98.74,22.56 98.74,22.56
EMMC_DATA_4: length 109
  TOP w0.14: v1(61.84,62.48) 61.84,62.34 U12.AY24
  IN2 w0.14: v1(61.84,62.48) 61.69,62.48 61.31,62.1 61.18,62.1 60.67,61.6 56.74,61.6 56.2,61.05 55.34,61.05 55.31,61.02 55.29,61.02 54.63,60.35 54.63,60.33 52.89,58.59 52.89,56.35 50.61,54.08 48.94,54.08 46.02,51.16 46.02,46.82 44.74,45.54 44.5,45.54 43.55,45.54 43.21,45.2 43.21,35.05 42.52,34.36 42.52,32.22 44.29,30.45 44.29,29.64 44.21,29.57 44.21,27.66 45.54,26.33 45.79,26.33 46.41,26.33 47.34,25.4 51.1,25.4 52.35,24.14 66.45,24.14 67.58,25.27 73.18,25.27 74.87,23.58 79.51,23.58 79.53,23.57 79.6,23.57 80.34,22.82 94.29,22.82 94.96,22.15 96.54,22.15 v1(97.76,23.37)
  BOTTOM w0.076: U30.J3 98.74,21.6 98.3,21.6 98.14,21.77
  BOTTOM w0.14: v1(97.76,23.37) 98.14,22.99 98.14,21.77
EMMC_DATA_5: length 105.7
  TOP w0.14: v1(63.29,61.46) 63.65,61.1 U12.AU26
  IN2 w0.14: v1(63.29,61.46) 63.29,61.39 62.22,60.33 58.63,60.33 57.52,59.21 55.24,59.21 54.13,58.1 54.13,55.94 51.1,52.91 49.65,52.91 47.18,50.44 47.18,44.42 47.01,44.25 47.01,41.97 45.45,40.4 45.45,40.39 45.41,40.34 45.41,38.84 44.52,37.95 44.52,34.59 43.88,33.95 43.88,32.66 45.51,31.03 45.51,29.21 45.38,29.08 45.38,28.14 46.02,27.51 47.08,27.51 48.02,26.57 51.6,26.57 52.01,26.16 66.49,26.16 66.78,26.45 85.55,26.45 87.11,24.89 95.01,24.89 96.13,23.77 96.71,23.77 v1(97.12,24.18)
  BOTTOM w0.076: U30.J4 98.74,21.1 98.24,21.1
  BOTTOM w0.14: 98.24,21.1 97.78,21.1 97.12,21.76 97.12,22.07 97.25,22.2 97.25,24.05 v1(97.12,24.18)
EMMC_DATA_6: length 106.6
  TOP w0.14: v1(63.92,61.49) 64.36,61.05 U12.AT26
  IN2 w0.14: v1(63.92,61.49) 63.92,61.44 63.41,60.93 63.29,60.93 62.35,60 58.72,60 57.57,58.85 55.29,58.85 54.42,57.98 54.42,51.97 54.98,51.41 54.98,47.65 52.54,45.21 49.5,45.21 47.36,43.08 47.36,41.88 47.08,41.6 47.06,41.6 45.74,40.28 45.74,40.27 45.7,40.22 45.7,38.72 44.81,37.83 44.81,34.47 44.17,33.83 44.17,32.78 46,30.95 46,29.71 46.74,28.97 46.74,28.36 48.24,26.86 51.73,26.86 52.13,26.45 66.32,26.45 66.62,26.75 85.67,26.75 87.22,25.2 95.46,25.2 v1(96.46,24.21)
  BOTTOM w0.076: U30.J5 98.74,20.6 98.24,20.6
  BOTTOM w0.14: v1(96.46,24.21) 96.18,23.93 96.18,21.77 97.43,20.52 97.96,20.52 98.04,20.6 98.24,20.6
EMMC_DATA_7: length 114.8
  TOP w0.14: v1(63.29,63.42) 63.65,63.79 U12.AU20
  IN2 w0.14: v1(63.29,63.42) 63.29,63.63 62.75,64.16 59.68,64.16 59.43,63.91 58.79,63.91 58.14,63.26 54.96,63.26 53.85,62.16 53.85,61.84 53.29,61.28 52.96,61.28 52.95,61.27 52.57,61.27 51.73,60.43 51.73,57.68 49.88,55.83 49.29,55.83 45.11,51.65 45.11,50.28 44.31,49.48 44.31,47.12 44.31,47.12 44.31,46.88 44.31,46.84 43.9,46.42 43.08,46.42 42.3,45.63 42.3,36.13 40.73,34.57 40.73,31.19 40.35,30.81 40.35,30.02 40.81,29.55 41.19,29.55 41.89,28.85 42.3,28.85 42.7,28.45 42.7,26.28 43.35,25.63 44.87,25.63 46.37,24.13 47.63,24.13 48.26,23.5 51.55,23.5 51.98,23.07 67.25,23.07 67.84,22.49 77.42,22.49 77.62,22.69 79.23,22.69 80.18,21.74 92.88,21.74 93.07,21.55 94.03,21.55 94.53,21.06 v1(95.7,21.06)
  BOTTOM w0.076: U30.J6 98.74,20.1 98.3,20.1 98.22,20.02
  BOTTOM w0.14: v1(95.7,21.06) 96.92,19.84 98.04,19.84 98.22,20.02
EMMC_RCOMP: length 3.6
  TOP w0.14: v1(61.87,65.35) 61.87,65.22 U12.AY18
  BOTTOM w0.14: v1(61.87,65.35) 61.87,66.1 v2(62.14,66.37) 62.32,66.55 62.32,67.54 62.07,67.79 R286.2
EMMC_RESET: length 119.2
  TOP w0.14: v1(61.13,62.54) 61.13,62.34 U12.BA24
  IN2 w0.14: v1(102.28,19.86) 102.28,20.52 99.13,23.67 98.44,23.67 98.24,23.47 98.24,23.19 96.84,21.79 94.89,21.79 94.35,22.33 v1(93.72,22.33) 80.42,22.33 79.47,23.27 73.45,23.27 72.41,24.31 68.65,24.31 68.19,23.85 52.02,23.85 51.64,24.23 49.62,24.23 48.81,25.04 47.24,25.04 46.24,26.04 45.91,26.04 45.91,26.04 45.42,26.04 43.92,27.54 43.92,28.11 42.59,29.44 42.16,29.44 41.54,30.05 41.54,31.95 42.23,32.64 42.23,34.57 42.92,35.26 42.92,45.34 43.41,45.83 44.62,45.83 45.72,46.94 45.72,51.43 48.69,54.4 50.28,54.4 52.44,56.57 52.44,58.62 55.16,61.34 56.07,61.34 56.68,61.95 60.6,61.95 61.13,62.48 v1(61.13,62.54)
  BOTTOM w0.14: v1(93.72,22.33) 91.41,22.33 89.92,20.84 R28.2 ; U30.U5 102.51,19.86 v1(102.28,19.86)
EMU_LID: length 212.4
  TOP w0.102: v1(143.5,39.14) 143.21,38.85 U18.82
  IN1 w0.102: v1(143.5,39.14) 142.76,39.14 142.15,38.53 142.15,33.83 140.66,32.33 133.9,32.33 130.78,29.21 127.14,29.21 125.72,27.79 122.74,27.79 120.21,25.26 120.21,23.57 118.84,22.2 118.84,20.45 108.19,9.8 88.13,9.8 87.09,10.85 79.59,10.85 77.97,12.46 66.12,12.46 v1(65.68,12.01)
  IN2 w0.102: v1(65.68,12.01) 64.66,13.03 60.92,13.03 59.72,11.82 49.19,11.82 48.99,11.62 45.71,11.62 43.21,9.12 42.26,9.12 41.04,7.9 37.38,7.9 36.55,8.73 36.55,10.05 36.21,10.39 29.12,10.39 28.26,11.25 23.13,11.25 20.92,13.46 20.92,23.75 21.3,24.13 21.3,40.01 18.94,42.37 18.94,51.03 20.59,52.68 21.05,52.68 21.58,53.21 22.32,53.21 25.16,56.06 25.17,56.06 28.96,59.84 29.68,59.84 31.75,61.91 31.75,63.24 32.23,63.72 32.23,67.86 v1(31.72,68.38)
  BOTTOM w0.102: v1(31.72,68.38) 31.23,68.38 31.1,68.24 CN16.5
EN_OVERRIDE: length 55.2
  TOP w0.102: U18.10 125.88,40.85 125.49,40.46 125.45,40.46 v1(125.44,40.46)
  IN1 w0.102: v1(125.44,40.46) 124.02,41.88 124.02,42.47 122.55,43.93 122.55,45.85 121.56,46.85 121.56,47.3 120.81,48.04 116.89,48.04 116.09,47.25 116.09,44.7 114.88,43.49 111.62,43.49 110.72,42.58 107.8,42.58 v1(107.53,42.32)
  BOTTOM w0.102: R283.2 99.18,63.89 99.18,61.01 99.83,60.35 99.83,57.91 99.64,57.71 99.64,55.13 99.29,54.77 99.29,49.14 104.1,44.32 106.09,44.32 v2(107.32,43.09) 107.53,42.87 v1(107.53,42.32)
FANSIG: length 4.9
  TOP w0.102: TP20.1 143.7,29.85 142.09,29.85 141.61,29.36 140.58,29.36 140.26,29.68 U18.63
G5934CN: length 2.9
  BOTTOM w0.102: PC195.2 84.94,14.11 v2(85.23,13.82)
  BOTTOM w0.203: PC195.2 83.95,14.33 PU16.19
G5934CP: length 2.8
  BOTTOM w0.102: v2(85.18,15.11) 84.96,14.89 PC195.1
  BOTTOM w0.203: PU16.18 84,14.73 PC195.1
G5934DISC1: length 3.2
  BOTTOM w0.203: PU16.5 80.2,12.52 v2(79.82,12.14) 79.82,11.76 80.25,11.34 PR183.2
G5934DISC2: length 1.6
  BOTTOM w0.203: PR181.1 78.24,14.12 78.44,13.92 78.82,13.92 78.83,13.93 PU16.6
G5934DISC3: length 1.9
  BOTTOM w0.203: PU16.7 78.68,14.33 v1(78.63,14.38) 78.63,14.46 PR176.1
G5934DISC4: length 3.5
  BOTTOM w0.102: PR175.2 77.89,16.34 v2(77.89,17.22)
  BOTTOM w0.203: PR175.2 78.45,15.78 78.45,15.24 78.96,14.73 PU16.8
G5934VIN: length 5.6
  BOTTOM w0.102: PR185.1 84.6,10.23 v2(84.6,9.37)
  BOTTOM w0.203: PR185.1 PR182.1 84.42,12.29 PC196.2 82.78,13.93 PU16.20
G5934VOUT: length 5
  BOTTOM w0.102: v2(86.55,15.27) 86.22,15.6 84.88,15.6 PC192.1
  BOTTOM w0.203: PC192.1 83.04,15.13 PU16.17
GPIO_NC13: length 9.7
  TOP w0.102: R147.2 88.55,57.63 v2(88.28,57.63) 88.15,57.63 87.73,58.05 R146.1 86.8,58.98 85.46,58.98 85,58.52 84.47,58.52 83.73,59.26 81.64,59.26 U12.A29
GPIO_NC14: length 4.5
  TOP w0.102: TP16.1 84.17,59.46 81.88,59.46 81.54,59.81 81.21,59.81 81.12,59.72 80.82,59.72 U12.C29
GPIO_S0_SC_56: length 8.1
  TOP w0.102: U12.BC12 60.81,67.68 v1(60.45,67.32)
  BOTTOM w0.102: v1(60.45,67.32) 60.34,67.32 59.67,67.98 v2(58.61,67.98) 58.02,67.98 57.02,68.99 55.82,68.99 55.42,69.38 R254.1 R253.2
GPP_TX2N_LAN: length 10.3
  TOP w0.102: C76.1 153.54,67.25 153.66,67.13 153.66,66.92 153.24,66.5 152.24,66.5 150.44,64.69 150.44,63.75 150.11,63.42 150.11,62.91 149.74,62.55 149.74,62.02 149.6,61.88 149.6,61.44 149.24,61.08 149.02,61.08 148.59,61.51 U11.18
GPP_TX2P_LAN: length 10.3
  TOP w0.102: U11.17 148.74,61.11 148.94,60.91 149.31,60.91 149.77,61.37 149.77,61.81 149.91,61.95 149.91,62.47 150.28,62.84 150.28,63.35 150.61,63.68 150.61,64.62 152.31,66.32 153.32,66.32 153.84,66.84 153.84,67.08 154.01,67.25 C77.1
H_PROCHOT#: length 74.4
  TOP w0.14: R130.1 92.52,61.75 92.69,61.58 93.19,61.58 v1(93.59,61.98)
  IN1 w0.14: v1(93.59,61.98) 94.31,62.7 97.1,62.7 97.58,62.21 97.99,62.21 98.16,62.38 99.82,62.38 99.82,62.38 100.47,62.38 101.48,61.37 109.06,61.37 109.89,60.54 111.17,60.54 113.6,58.11 115.24,58.11 116.1,57.25 118.68,57.25 119.42,56.51 122.15,56.51 122.65,56.01 122.68,56.01 122.69,56 123.37,56 123.51,56.14 123.51,56.14 123.75,56.38 128.11,56.38 128.25,56.52 130.54,56.52 130.78,56.28 131.77,56.28 132.39,56.91 137.62,56.91 138.07,57.35 v1(138.65,57.35)
  IN2 w0.14: v1(138.65,57.35) 138.65,56.92 138.12,56.39 138.12,50.45 v1(137.63,49.96)
  BOTTOM w0.14: PU12.6 130.66,64.73 131.21,64.18 131.82,64.18 132.05,63.95 PC118.1 132.22,63.55 132.97,62.8 134.57,62.8 134.95,62.42 PR108.2 136.03,62.42 137.05,61.41 137.05,60.36 138.44,58.97 138.44,57.56 v1(138.65,57.35) ; v1(137.63,49.96) 137.99,49.96 138.5,49.45 Q33.3
HDA_RCOMP: length 2.2
  TOP w0.102: v1(59.07,64.34) 59.42,63.99 U12.BF20
  BOTTOM w0.14: R284.1 58.04,63.92 58.46,64.34 v1(59.07,64.34)
HDMI_5V: length 25.5
  TOP w0.254: C7.1 D6.1 62.06,90.71 61.46,91.31 ; v1(57.62,91.08) 57.85,91.31 61.46,91.31 ; 61.46,91.31 61.71,91.57 70.43,91.57 70.7,91.85 70.7,92.39 CN7.18
  BOTTOM w0.254: Q17.1 58.36,84.89 58.36,85.88 v2(57.83,86.41) 57.73,86.51 57.73,87.48 57.32,87.88 57.32,90.78 v1(57.62,91.08)
HDMI_HPD: length 23.4
  IN1 w0.102: v1(59.66,85.63) 60.72,86.69 63.67,86.69 v1(63.92,86.44)
  BOTTOM w0.102: v1(63.92,86.44) Q14.2 ; CN7.19 69.06,91.36 65.47,91.36 65.24,91.59 64.35,91.59 64.1,91.34 60.85,91.34 v2(59.71,90.2) C144.1 VC6.1 58.65,88.03 59.66,87.01 R220.2 v1(59.66,85.63)
HDMI_HPD_CON: length 64.6
  TOP w0.102: v1(79.47,59.51) 79.93,59.97 U12.D27
  IN1 w0.102: v1(89.08,66.6) 89.08,66.28 87.77,64.97 87.57,64.97 86.68,64.08 86.2,64.08 85.36,63.25 83.83,63.25 83.07,62.48 83.07,61.75 80.44,59.12 79.86,59.12 v1(79.47,59.51)
  BOTTOM w0.102: v1(89.08,66.6) 89.29,66.81 89.29,67.81 92.71,71.23 92.71,73.98 90.36,76.33 86.05,76.33 85.8,76.08 80.75,76.08 80.2,76.63 76.34,76.63 75.51,77.47 75.51,78.79 75.91,79.2 75.91,82.4 73.88,84.43 72.38,84.43 72.08,84.73 68.09,84.73 66.89,85.93 Q14.3 66.89,87.53 66.23,88.19 64.28,88.19 63.69,88.77 63.1,88.77 R206.1
HDMI_SCLK: length 22.5
  TOP w0.14: Q6.3 57.87,88.13 v1(57.83,88.09) 57.85,88.06 v2(57.85,87.3) 57.85,86.92 58.39,86.39 R14.2
  IN2 w0.14: v1(57.83,88.09) 60.57,90.83 61.36,90.83 61.97,90.22 63.9,90.22 64.94,89.18 68.9,89.18 69.99,90.27 69.99,90.82 70.58,91.41 70.58,92.48 70.27,92.79 68.49,92.79 CN7.15
HDMI_SDATA: length 23.4
  TOP w0.14: Q6.6 59.27,89.96 59.15,90.08 59.15,90.45 59.27,90.58 60.89,90.58 61.1,90.36 v1(61.1,90.35) 61.12,90.35 61.48,89.98 61.48,88.75 61.81,88.43 R11.2
  IN2 w0.14: v1(61.1,90.35) 61.12,90.35 61.64,89.83 63.73,89.83 64.77,88.79 69.07,88.79 70.4,90.12 70.4,90.65 70.98,91.24 70.98,92.71 70.58,93.12 68.55,93.12 68.4,93.26 CN7.16
HP_AGND: length 8
  TOP w0.508: D18.2 R47.1 15.63,77.87 15.41,77.64 13.75,77.64 12.81,76.71 v2(12.77,76.71) 12.51,76.71 12.3,76.92 CN11.5
HP_JD#: length 3.6
  TOP w0.14: R22.2 D17.2 10.47,77.58 10.1,77.95 CN11.6
HPL: length 18.6
  TOP w0.203: U9.32 18.43,73.97 18.42,73.97 17.76,73.97 17.71,73.91 v1(17.01,73.91)
  TOP w0.381: v1(15.71,83.34) R514.1 16.59,83.81 16.86,84.07 17.92,84.07 C348.2 ; R66.2 13.61,81.36 v1(13.55,81.31)
  IN2 w0.381: v1(15.71,83.34) 15.18,83.34 13.55,81.71 v1(13.55,81.31) 13.55,80.54 14.72,79.38 14.72,76.71 16.96,74.47 16.96,73.97 v1(17.01,73.91)
HPL-1_TIP_SENSE: length 4.7
  TOP w0.381: R66.1 15.06,81.45 14.28,82.23 D20.2 C48.2 13.95,83.72 12.93,83.72 CN11.1
HPR: length 17.8
  TOP w0.203: v1(16.38,73.99) 16.38,73.86 16.78,73.46 17.29,73.46 17.41,73.57 U9.33
  TOP w0.381: R27.2 13.58,78.26 v1(13.53,78.31) ; v1(15.71,81.56) 15.82,81.56 16.45,82.19 R515.1 16.59,82.1 17.09,81.61 18.2,81.61 C349.2
  IN2 w0.381: v1(16.38,73.99) 16.37,73.99 15.17,73.99 13.53,75.63 v1(13.53,78.31)
  BOTTOM w0.381: v1(13.53,78.31) 13.53,79.17 v2(14.11,79.76) 15.03,80.67 15.03,80.87 v1(15.71,81.56)
HPR_SYS: length 12.7
  TOP w0.381: R27.1 15.06,78.35 14.28,79.13 C24.2 D11.2 13.43,80.29 13.02,80.7 10.86,80.7 10.25,80.09 6.14,80.09 CN11.2
HWPG1.8VD: length 131.4
  TOP w0.508: v1(80.38,18.47) 79.6,17.68 v2(79.6,17.68) 79.6,13.85 v1(79.06,13.31)
  IN1 w0.508: v1(128.69,32.74) 128.67,32.74 128.64,32.72 128.64,32.69 127.62,31.67 124.77,31.67 123.27,30.18 118,30.18 116.42,28.6 116.42,23.09 114.73,21.39 114.25,21.39 111.4,18.55 111.4,16.21 107.69,12.5 88.51,12.5 87.39,13.61 83.07,13.61 82.64,13.18 79.19,13.18 v1(79.06,13.31)
  IN2 w0.508: v1(118.61,59.58) 118.83,59.36 120.12,59.36 122.66,56.82 v1(123.03,56.82) 123.05,56.79 126.09,56.79 126.8,56.08 127.68,56.08 129.31,54.45 134.01,54.45 135.58,52.88 135.58,46.15 136.36,45.36 136.36,43.05 135.86,42.55 135.86,40.67 136.62,39.9 140.05,39.9 141.75,38.2 141.75,34.24 140.09,32.58 139.11,32.58 137.13,34.57 131.31,34.57 129.48,32.74 v1(128.69,32.74)
  BOTTOM w0.203: PU16.12 80.6,16.93 80.38,17.15 v1(80.38,18.47)
  BOTTOM w0.381: v1(123.03,56.82) 122.96,56.75 122.96,56.34 122.69,56.07 PQ16.4
HWPG_1.0V: length 207.3
  TOP w0.102: R160.2 118.19,54.6 117.74,54.15 v1(117.74,54)
  IN1 w0.102: v1(24.74,38.01) 23.11,36.37 23.11,27.51 28.26,22.35 28.26,17.75 30.49,15.52 37.71,15.52 38.6,16.41 38.6,18.01 38.19,18.42 38.19,21.67 38.54,22.01 42.18,22.01 42.71,21.47 42.71,20.65 46.63,16.74 49.7,16.74 50.39,16.05 60.13,16.05 61.89,17.81 64.32,17.81 65.87,19.36 71.11,19.36 71.82,18.64 76.07,18.64 76.93,17.78 79.05,17.78 79.82,17.02 87.95,17.02 89.27,15.7 89.74,15.7 90.15,15.29 94.01,15.29 94.5,14.81 106.33,14.81 108.89,17.36 108.89,17.4 108.9,17.41 108.9,20.39 113.48,24.97 v1(113.48,29.36)
  IN2 w0.102: v1(113.48,29.36) 113.63,29.36 118.53,34.26 121.05,34.26 121.92,35.13 121.96,35.13 121.96,35.13 122.78,35.13 124.38,36.73 125.24,36.73 126.15,37.64 126.15,38.18 127.67,39.7 128.24,39.7 128.64,39.29 129.54,39.29 129.89,39.64 129.89,41.78 129.05,42.62 127.64,42.62 127.37,42.88 127.37,48.51 127.96,49.09 127.96,50.06 125.65,52.37 125.64,52.37 123.96,54.05 122.28,54.05 121.87,53.63 121.87,53.34 121.2,52.68 118.81,52.68 117.74,53.75 v1(117.74,54) ; v1(32.6,53.14) 32.6,53.71 32.15,54.17 28.83,54.17 28.44,54.56 28.06,54.56 27.8,54.31 27.8,53.36 25.61,51.16 23.34,51.16 22.72,50.55 22.72,41.22 24.74,39.21 v1(24.74,38.01)
  BOTTOM w0.102: PR128.1 32.1,52.86 32.38,53.14 32.6,53.14 v1(32.6,53.14)
HWPG_1.5V: length 179.8
  TOP w0.203: v1(124.76,38.56) 125.23,38.09 125.57,38.09 125.61,38.05 U18.17
  TOP w0.381: v1(82.77,18.82) 82.77,14.48 81.3,13.01 v2(81.19,13.01) 80.74,12.55 v1(80.74,12.34) ; v1(26.64,39.09) 26.59,39.13 PR154.1
  IN1 w0.254: v1(26.64,39.09) 27.19,38.53 30.27,38.53 31.46,37.34 32.33,37.34 34.26,35.41 34.26,33.59 34.99,32.85 34.99,32.44 36.52,30.91 37.08,30.91 37.28,30.71 37.28,26.72 38.7,25.3 40.15,25.3 45.38,20.07 46.6,20.07 46.96,19.71 49.5,19.71 50.16,20.37 54.83,20.37 57.06,18.14 60.8,18.14 61.38,18.72 63.97,18.72 65.5,20.24 75.73,20.24 76.67,19.3 78.79,19.3 80.16,17.93 81.88,17.93 v1(82.77,18.82)
  IN1 w0.305: 124.27,37.19 124.27,38.07 v1(124.76,38.56) ; 124.27,37.19 124.3,37.17 124.3,37.15 124.6,36.86 125.49,36.86 126.33,37.69 126.33,38.89 127.25,39.8 127.25,41.73 127.35,41.83 127.35,41.88 128.72,43.26 128.72,45.01 129.31,45.6 133.69,45.6 134.2,46.11 135.71,46.11 136.12,45.7 141.37,45.7 142.38,46.71 v1(142.38,47.02) ; 124.27,37.19 124.03,37.19 122.85,36.02 122.67,36.02 121.23,34.57 116.3,34.57 115.97,34.9 114.11,34.9 112.43,36.58 111.11,36.58 110.33,35.8 110.33,34.49 111.28,33.54 111.28,24.07 107.89,20.68 107.89,17.7 106.17,15.98 94.91,15.98 94,16.89 91.05,16.89 90.69,17.25 89.48,17.25 87.65,19.08 83.02,19.08 v1(82.77,18.82)
  BOTTOM w0.203: PU16.4 80.6,12.48 v1(80.74,12.34) 81,12.61 PU16.3
  BOTTOM w0.305: PR133.1 144.49,50.69 144.49,49.73 144.02,49.26 143.12,49.26 142.38,48.52 v1(142.38,47.02) ; R382.1 124.45,38.25 v1(124.76,38.56)
HWPG_1.05V: length 5.3
  BOTTOM w0.102: R162.2 23.11,38.61 23.61,39.12 23.61,39.45 23.58,39.48 v1(23.58,39.8) 23.58,40.12 23.67,40.21 PR152.1 23.94,40.4 23.94,40.03 24.07,39.9 PR153.2 25.1,39.83 PR155.1
HWPG_1.8V: length 2.2
  TOP w0.102: R164.2 118.47,52.2 PR35.1 118.85,51.08 v1(119.42,51.08)
HWPG_1.35V: length 77.5
  TOP w0.254: v1(37.63,35.61) 37.43,35.61 36.92,36.12 36.92,38.02 36.72,38.23 PR44.1
  TOP w0.508: v1(91.27,56.45) 91.27,54.14 92.72,52.69 92.72,48.56 v2(88.41,44.25) 86.45,42.29 84.78,42.29 83.53,41.04 83.53,39.13 81.79,37.38 73.86,37.38 73.76,37.49 68.03,37.49 67.15,36.6 59.43,36.6 58.78,35.96 v1(38.8,35.96)
  IN1 w0.508: v1(38.8,35.96) 37.98,35.96 v1(37.63,35.61)
  BOTTOM w0.279: Q53.3 90.59,58.33 R315.2
  BOTTOM w0.508: v1(91.27,56.45) 91.27,56.53 90.74,57.06 R323.1 90.52,58.23 R315.2
I2C_0_SCL: length 4.7
  TOP w0.102: U12.BG23 58.32,62.61 58.04,62.61 57.92,62.72 57.41,62.72 57.26,62.87 55.84,62.87
  TOP w0.14: R117.1 55.1,62.87 55.84,62.87
I2C_0_SDA: length 6.7
  TOP w0.102: U12.BH22 57.5,62.93 57.36,63.07 55.99,63.07 55.91,63.14
  TOP w0.14: 55.91,63.14 55.57,63.14 54.56,64.15 53.19,64.15 52.63,63.58 R108.1
I2C_5_SCL: length 6.2
  TOP w0.102: U12.BG28 58.69,59.87 58.42,59.87 58.27,59.72 58.01,59.72 57.92,59.81 57.34,59.81 56.99,59.46 56.35,59.46 55.67,58.78 54.63,58.78
  TOP w0.14: R145.1 54.27,58.6 TP34.1 54.63,58.78
I2C_5_SDA: length 5
  TOP w0.102: U12.BH28 57.26,60.01 57.03,59.79 55.59,59.79 55.26,60.12 TP33.1 54.45,60.1
  TOP w0.14: R140.1 54.16,59.81 54.45,60.1
I2C_6_SCL: length 55.5
  TOP w0.14: v1(47.54,62.23) 47.67,62.23 48.12,61.77 48.66,61.77 49,62.12 49,62.42 50.06,63.48 R119.2 50.7,63.02 52.93,63.02 R117.2
  IN1 w0.14: v1(47.54,62.23) 47.54,61.09 46.73,60.27 46.73,58.88 47.5,58.1 47.5,54.8 44.1,51.4 44.1,48.53 44.56,48.07 44.56,46.6 43.2,45.24 43.2,39.9 42.41,39.12 42.41,36.09 43.68,34.82 43.68,32.18 44.75,31.11 44.75,29.57 44.34,29.16 44.34,27.99 46.08,26.25 46.85,26.25 47.69,25.41 49.13,25.41 v1(49.75,24.79)
  BOTTOM w0.14: v1(49.75,24.79) 49.75,23.19 49.87,23.06 U27.3
I2C_6_SCL_R: length 5.5
  BOTTOM w0.14: CN18.6 46.74,16.7 46.96,16.92 47.49,16.92 47.98,17.41 R408.1 48.46,18.11 49.43,18.11 49.87,18.55 U27.6
I2C_6_SDA: length 57.7
  TOP w0.14: R108.2 51.1,63.58 R118.2 49.48,65.2 48.99,65.2 48.61,64.82 48.61,64.39 47.92,63.7 v1(47.82,63.7)
  IN1 w0.14: v1(47.82,63.7) 46.93,62.81 46.93,62.21 46.09,61.37 46.09,58.47 46.98,57.58 46.98,55.02 43.58,51.61 43.58,48.1 44.03,47.64 44.03,46.81 42.59,45.36 42.59,40.39 41.24,39.04 41.24,38.17 41.82,37.59 41.82,35.94 43.12,34.65 43.12,32 44.23,30.89 44.23,29.79 43.78,29.34 43.78,27.81 45.86,25.73 46.63,25.73 48.56,23.8 49.75,23.8 50.38,24.44 v1(50.38,24.79)
  BOTTOM w0.14: v1(50.38,24.79) 50.59,24.59 50.59,23.19 50.37,22.98 U27.4
I2C_6_SDA_R: length 4.8
  BOTTOM w0.14: U27.5 50.37,18.56 49.97,18.15 49.88,18.15 R404.1 48.94,17.63 48.25,16.94 48.02,16.94 47.74,16.66 CN18.5
IACM: length 97
  TOP w0.102: PU11.2 136.99,17.63 136.78,17.42 136.44,17.42 136.24,17.63 135.93,17.63 v1(135.53,17.22)
  IN1 w0.102: v1(165.03,78.51) 164.64,78.13 164.18,78.13 162.02,75.97 162.02,64.06 162.55,63.53 162.55,55.35 163.11,54.79 163.11,48.7 161.28,46.87 161.28,35.37 156.81,30.9 156.81,30.35 152.04,25.58 150.75,25.58 143.73,18.57 136.87,18.57 v1(135.53,17.22)
  BOTTOM w0.102: v1(165.03,78.51) 163.9,79.64 163.9,80.77 163.49,81.18 158.02,81.18 v2(157.64,80.8) 156.47,79.63 154.03,79.63 153.8,79.86 153.8,80.74 PR73.1
IACP: length 96.2
  TOP w0.102: v1(136.14,17.15) 136.95,17.15 137.39,17.58 PU11.3
  IN1 w0.102: v1(165.03,77.88) 165.03,77.58 164.42,76.97 164.42,76.95 164.18,76.71 164.15,76.71 162.27,74.83 162.27,64.31 162.87,63.72 162.87,55.45 163.31,55.01 163.31,48.61 161.48,46.78 161.48,35.28 157.01,30.81 157.01,30.25 152.14,25.38 150.84,25.38 143.8,18.34 137.33,18.34 v1(136.14,17.15)
  BOTTOM w0.102: v1(165.03,77.88) 163.69,79.21 163.69,80.67 163.47,80.9 158.48,80.9 156.72,79.15 v2(155.85,79.15) 154.19,79.15 153.6,79.75 153.6,80.66 PR72.1
ICHM: length 19.4
  TOP w0.102: PU11.39 135.32,19.3 135.14,19.12 135.14,18.7 134.88,18.44 v1(134.71,18.44) ; PR57.1 119.98,21.23 120.23,20.98 v1(120.9,20.98)
  IN1 w0.102: v1(134.71,18.44) 134.59,18.57 133.45,18.57 132.71,17.83 122.65,17.83 121.25,19.23 121.25,20.63 v1(120.9,20.98)
ICHP: length 18
  TOP w0.102: v1(121.5,20.98) 121.5,21.11 121.12,21.49 PR58.1 ; PU11.38 135.32,19.7 134.71,19.09 v1(134.71,19.05)
  IN1 w0.102: v1(134.71,19.05) 134.48,18.82 133.38,18.82 132.59,18.03 122.73,18.03 121.5,19.26 v1(121.5,20.98)
ICLK_DRAM_TERMN_0: length 2.6
  TOP w0.102: v1(68.65,52.48) 68.51,52.48 U12.AH42
  BOTTOM w0.102: R339.2 68.35,52.48 v1(68.65,52.48) 69.7,52.48 v2(69.73,52.45)
ICLK_DRAM_TERMN_1: length 2.1
  TOP w0.102: v1(68.62,53.11) 68.85,52.88 U12.AF42
  BOTTOM w0.102: v2(69.25,53.65) 68.72,53.11 v1(68.62,53.11) 68.6,53.14 R336.2
ICLK_ICOMP: length 4.9
  TOP w0.14: v1(71.42,69.88) 71.42,67.28 71.18,67.05 70.38,67.05 U12.AD14
  BOTTOM w0.14: R255.1 71.08,69.54 v1(71.42,69.88)
ICLK_RCOMP: length 2.5
  TOP w0.14: v1(70.48,67.85) U12.AD13
  BOTTOM w0.14: v1(70.48,67.85) 70.64,67.85 R261.1 70.89,68.47 v1(70.11,68.47)
ICLK_USB_TERMN_0: length 1.3
  TOP w0.102: v1(79.23,69.27) 79.69,68.81 U12.D10
  BOTTOM w0.102: R249.1 79.16,69.34 v1(79.23,69.27)
ICLK_USB_TERMN_1: length 1.6
  TOP w0.102: U12.F10 78.76,68.81 78.45,69.11 v1(78.45,69.32)
  BOTTOM w0.102: R248.1 78.45,69.58 v1(78.45,69.32)
ICMNT: length 70.1
  TOP w0.102: v1(140.12,47.4) 139.66,47.86 R173.2 139.66,48.48 139.82,48.64 C104.2 ; v1(133.32,14.12) PR63.1
  TOP w0.203: PC87.1 132.54,15.66 PR63.1
  IN2 w0.102: v1(140.12,47.4) 140.12,46.81 141.81,45.13 141.81,39.29 142.38,38.72 142.38,34 140.35,31.98 138.81,31.98 137.02,33.76 131.36,33.76 129.71,32.11 124.78,32.11 122.62,29.95 120.13,29.95 v1(119.75,29.57)
  BOTTOM w0.102: v1(119.75,29.57) 119.75,26.7 120.44,26.01 120.44,19.53 v2(121.02,18.95) 124.53,15.44 131.99,15.44 v1(133.32,14.12)
ICMNT_R: length 2.1
  TOP w0.102: U18.98 140.26,46.95 140.56,47.25 140.56,47.65 140.44,47.78 R173.1
IMVP_PWRGD: length 236.1
  TOP w0.102: v1(43.15,15.49) 43.35,15.7 45.87,15.7 47.44,17.26 47.44,19.37 v1(48.91,20.84)
  IN2 w0.102: v1(123.78,60.66) 123.84,60.6 126.46,60.6 127.19,59.87 130.22,59.87 131.99,61.65 142.68,61.65 145,59.33 145.89,59.33 148.14,57.09 148.14,50.53 149.93,48.74 149.93,47.14 148.34,45.55 148.34,40.81 147.92,40.39 147.92,37.73 148.1,37.55 148.1,35.09 147.26,34.26 147.26,33.51 141.85,28.09 132.9,28.09 132.52,27.71 131.39,27.71 131.23,27.86 124.2,27.86 119.86,23.53 119.5,23.53 112.92,16.94 112.92,16.58 107.18,10.85 92.98,10.85 92.27,11.56 88.36,11.56 87.27,12.65 86.43,12.65 84.97,11.19 75.54,11.19 74.26,12.47 74.19,12.47 74.18,12.47 69.59,12.47 67.12,14.94 62.09,14.94 61.15,15.88 56.48,15.88 55.64,15.04 51.86,15.04 50.87,16.03 43.68,16.03 v1(43.15,15.49) ; v1(48.91,20.84) 48.19,20.12 43.32,20.12 38.02,25.43 38.01,25.43 37.28,26.15 37.28,32.89 37.68,33.3 37.68,34.98 37.13,35.53 37.13,37.08 37.61,37.57 37.61,38.43 38.32,39.14 38.32,40.56 39.21,41.46 39.21,43.94 38.85,44.3 v1(38.85,45.08)
  BOTTOM w0.102: v1(38.85,45.08) 38.88,45.1 PR140.2 38.47,46.52 38.47,47.22 37.48,48.21 37.48,54.08 35.81,55.75 33.8,55.75 33.6,55.96 33.6,56.74 33.78,56.93 PR123.1
  BOTTOM w0.198: PU12.15 126.71,62.76
  BOTTOM w0.203: 126.71,62.76 126.53,62.59 125.13,62.59 124,61.46 124,60.88 v1(123.78,60.66) 123.61,60.66 123.25,61.02 PR112.2
IN_CLK: length 20
  TOP w0.102: C15.1 71.57,88.38 71.57,87.54 R10.1 71.47,87.06 71.47,86.82 v2(72,86.28) 71.62,85.9 71.62,85.55 69.93,83.86 69.67,83.86 66.58,80.77 66.58,75.35 65.37,74.14 65.37,73.16 65.48,73.05 65.48,72.79 65.38,72.69 65.38,72.42 U12.AP3
IN_CLK#: length 20
  TOP w0.102: C14.1 71.17,88.66 71.39,88.44 71.39,87.63 71.11,87.35 R10.2 71.29,87.04 71.29,86.84 v2(70.73,86.28) 71.01,86 71.29,86 71.44,85.85 71.44,85.62 69.86,84.04 69.6,84.04 66.4,80.84 66.4,75.43 65.19,74.22 65.19,73.08 65.18,73.07 65.18,72.93 U12.AP2
IN_D0: length 19
  TOP w0.102: C13.1 69.34,88.44 69.34,88.17 69.13,87.96 69.13,87.69 R9.1 69.43,87.38 69.13,87.07 69.13,85.78 v2(69.68,85.22) 69.31,84.85 69.31,84.46 65.83,80.98 65.83,75.55 64.81,74.52 64.81,73.87 64.98,73.69 64.98,73.14 64.7,72.86 U12.AR3
IN_D0#: length 19
  TOP w0.102: U12.AR1 64.7,73.72 64.63,73.79 64.63,74.6 65.65,75.62 65.65,81.05 69.13,84.53 69.13,84.79 69.03,84.89 68.75,84.89 v2(68.41,85.22) 68.95,85.76 68.95,87.09 R9.2 68.95,87.66 68.95,88.04 69.16,88.24 69.16,88.69 69.05,88.8 68.68,88.8 C12.1
IN_D1: length 18.5
  TOP w0.102: C11.1 66.84,88.66 66.72,88.54 66.72,88.29 66.87,88.14 66.87,87.66 R8.1 66.97,87.38 66.77,87.17 66.77,86.49 v2(67.3,85.96) 67.3,85.95 67.01,85.66 66.73,85.66 66.62,85.55 66.62,83.01 65.17,81.56 65.17,75.82 64.08,74.73 64.08,74.27 64.3,74.04 64.3,73.2 64.21,73.11 U12.AT2
IN_D1#: length 18.6
  TOP w0.102: U12.AT3 64.21,72.5 63.92,72.8 63.92,73.07 64.13,73.27 64.13,73.97 63.9,74.19 63.9,74.8 64.99,75.89 64.99,81.64 66.44,83.08 66.44,85.54 v2(66.03,85.95) 66.59,86.52 66.59,87.16 R8.2 66.69,87.69 66.69,88.06 66.54,88.21 66.54,88.37 66.26,88.65 C10.1
IN_D2: length 18.1
  TOP w0.102: C9.1 64.89,88.43 64.89,87.73 65.05,87.57 R7.1 65.05,84.29 v2(65.57,83.77) 65.6,83.74 65.04,83.19 65.04,82.78 64.51,82.25 64.51,79.07 63.77,78.33 63.77,75.38 63.14,74.75 63.14,73.68 63.44,73.38 63.44,73.15 63.54,73.05 63.54,72.81 63.24,72.52 U12.AV3
IN_D2#: length 18.1
  TOP w0.102: C8.1 64.52,88.66 64.71,88.47 64.71,87.79 R7.2 64.58,87.04 64.69,87.04 64.87,86.86 64.87,84.35 v2(64.3,83.77) 64.86,83.21 64.86,82.85 64.33,82.32 64.33,79.14 63.59,78.41 63.59,75.46 62.96,74.82 62.96,73.61 63.24,73.32 U12.AV2
INT_AMIC-VREFO: length 17
  TOP w0.203: R53.2 14.79,76.15 16.59,76.15 C49.1 17.09,76.52 17.54,76.07 18.28,76.07 18.38,75.97 U9.27
  TOP w0.381: R53.2 13.96,76.34 13.96,75.62 14.32,75.26 14.32,74.65 15.05,73.91 15.05,73.25 14.62,72.82 v2(14.62,72.16) 14.55,72.09 14.55,68.61 13.2,67.26 R428.2
INT_EDP_AUXN: length 45.1
  TOP w0.102: C65.2 36.96,73.37 36.87,73.28 36.29,73.28 35.91,73.66 v1(35.91,73.71) ; v1(67.1,77.67) 67.3,77.67 67.45,77.52 67.45,77.32 67.13,76.99 U12.AK2
  IN1 w0.102: v1(35.91,73.71) 35.91,73.63 36.1,73.44 36.39,73.44 36.73,73.79 36.73,76.84 37.86,77.97 44.03,77.97 44.31,78.24 49.33,78.24 50.04,77.53 50.38,77.2 50.71,76.86 50.84,76.73 53.05,76.73 53.69,76.1 57.1,76.1 57.83,76.83 60.6,76.83 61.21,76.22 64.5,76.22 64.96,76.68 66.82,76.68 67.45,77.32 67.45,77.56 67.34,77.67 v1(67.1,77.67)
INT_EDP_AUXP: length 45.1
  TOP w0.102: v1(35.91,73.08) 35.93,73.1 36.69,73.1 C64.2 ; U12.AK3 67.13,72.52 67.42,72.81 67.42,73.07 67.31,73.18 67.31,76.92 67.63,77.24 67.63,77.44 v1(67.86,77.67)
  IN1 w0.102: v1(35.91,73.08) 36.08,73.25 36.47,73.25 36.92,73.71 36.92,76.76 37.94,77.78 44.11,77.78 44.39,78.05 49.25,78.05 49.91,77.4 50.76,76.54 52.97,76.54 53.61,75.91 57.18,75.91 57.91,76.64 60.52,76.64 61.13,76.03 64.58,76.03 65.04,76.49 66.9,76.49 67.64,77.24 67.64,77.46 v1(67.86,77.67)
INT_EDP_TXN0: length 46.6
  TOP w0.102: v1(35.12,71.76) 34.97,71.76 34.61,71.4 34.61,70.89 34.86,70.65 C67.2 ; v1(67.78,76.56) 67.99,76.56 68.19,76.35 68.19,75.01 69.03,74.17 69.03,73.55 68.79,73.31 U12.AG1
  IN1 w0.102: v1(35.12,71.76) 34.87,71.76 34.76,71.65 34.76,71.36 34.87,71.26 35.54,71.26 38.07,73.79 38.07,76.52 38.77,77.23 47.36,77.23 48.7,75.9 52.24,75.9 53.32,74.82 58.88,74.82 59.35,75.28 60.87,75.28 61.14,75.55 64.79,75.55 65.24,76 65.24,76 68.03,76 68.19,76.16 68.19,76.35 67.99,76.56 v1(67.78,76.56)
INT_EDP_TXP0: length 46.6
  TOP w0.102: U12.AG3 68.59,72.86 69.21,73.47 69.21,74.24 68.37,75.08 68.37,76.38 v1(68.55,76.56) ; v1(34.36,71.76) 34.43,71.68 34.43,70.95 C66.2
  IN1 w0.102: v1(68.55,76.56) 68.38,76.39 68.38,76.09 68.11,75.81 65.32,75.81 64.87,75.36 61.21,75.36 60.95,75.09 59.42,75.09 58.96,74.63 53.24,74.63 52.16,75.7 48.62,75.7 47.29,77.04 38.85,77.04 38.26,76.44 38.26,73.71 35.62,71.07 34.79,71.07 34.57,71.28 34.57,71.54 v1(34.36,71.76)
INTD_DSI_TE: length 5.6
  TOP w0.102: TP17.1 85.94,58.32 84.29,58.32 83.58,59.03 81,59.03 U12.B30
IOAC_PCIERST#: length 76.2
  TOP w0.102: v1(130.28,47.26) 130.26,47.24 U18.123
  IN1 w0.102: v1(130.28,47.26) 130.95,46.59 133.28,46.59 133.78,47.1 136.12,47.1 136.53,46.69 140.44,46.69 141.38,47.63 142.93,47.63 143.46,48.15 144.42,48.15 145.3,49.03 151.08,49.03 154.04,51.99 156.53,51.99 156.66,52.12 v1(156.66,52.15)
  IN2 w0.102: v1(156.66,52.15) 156.66,52.81 152.11,57.35 152.11,61.87 156.51,66.27 156.86,66.27 158.17,67.58 158.17,71.76 159.83,73.43 159.83,83.57 161.79,85.52 161.79,87.25 161.35,87.69 160.63,87.69 160.39,87.45 160.39,87.39 v1(160.2,87.2)
  BOTTOM w0.102: R216.2 161.92,87.78 161,86.87 160.53,86.87 v1(160.2,87.2)
ISOLATEB: length 30.7
  TOP w0.102: v1(149.29,62.15) 148.84,62.15 148.68,62.31 U11.20
  IN2 w0.102: v1(156.81,69.48) 156.81,68.85 155.54,67.58 155.54,66.57 151.12,62.15 v1(149.29,62.15)
  BOTTOM w0.102: v1(156.81,69.48) v2(156.81,68.71) 156.81,68.61 156.43,68.22 156.43,64.36 152.46,60.4 152.46,57.73 152.11,57.38 R330.2 R329.1
L_SPK+: length 77.4
  TOP w0.889: R188.2 10,10.87 10.13,11 v3(10.13,11.46)
  IN1 w0.889: v1(8.07,60.47) v1(8.96,60.47) 8.97,60.45 21.17,60.45 23.59,62.87 23.59,66.12 21.5,68.2
  BOTTOM w0.889: v3(10.13,11.46) 11.27,12.6 v2(11.27,20.32) 11.27,22.38 5.86,27.79 5.86,58.51 7.81,60.47 v1(8.07,60.47) v1(8.96,60.47)
  vias: v1(21.53,69.42) v1(21.53,68.81)
L_SPK+_1:
  vias: v1(9.24,9.5) v1(9.24,8.89) v2(9.54,7.93)
L_SPK-: length 77.4
  TOP w0.889: v3(12.79,14.5) 12.79,13.49 11.65,12.34 R189.2
  IN1 w0.889: v1(8.27,59.32) v1(9.16,59.32) 21.57,59.32 24.6,62.36 24.6,66.52 22.8,68.33
  BOTTOM w0.889: v1(9.16,59.32) v1(8.27,59.32) 6.95,58 6.95,28.42 12.79,22.58 v2(12.79,17.42) v3(12.79,14.5)
  vias: v1(22.19,69.8) v1(22.19,69.19)
L_SPK-_1:
  vias: v1(12.41,7.52) v1(12.41,6.88) v2(11.47,8.03)
LAD0: length 225.2
  TOP w0.14: R50.2 159.17,73.97 v1(158.77,73.57) ; v1(129.38,47.9) 128.97,47.5 128.97,46.95 129.06,46.86 U18.126 129.06,43.42 131.33,41.15 131.33,36.09 130.9,35.66 130.9,33.05 129.43,31.58 128.09,31.58 127.65,31.14 127.65,29.79 126.42,28.56 125.4,28.56 124.22,27.38 111.44,27.38 108.6,24.54 104.61,24.54 104.36,24.79 v1(104.36,24.92) ; v1(56.23,65.05) 56.84,65.66 57.95,65.66 U12.BH16 ; U16.26 39.84,45.57 41.9,43.51 45.43,43.51 45.86,43.94 v1(45.86,44.53)
  IN1 w0.14: v1(56.23,65.05) 55.97,64.79 55.97,64.15 54.56,62.74 54.56,59.11 53.8,58.36 53.8,56.1 51.81,54.11 50.17,54.11 46.44,50.38 46.44,46.69 46.44,46.2 45.86,45.63 v1(45.86,44.53) 45.86,38.66 45,37.8 45,36.78 45.5,36.28 45.5,34.94 47.01,33.43 47.01,30.53 46.82,30.34 46.82,28.26 48.25,26.82 51.24,26.82 54.09,23.98 56.53,23.98 56.94,23.57 60.98,23.57 61.12,23.71 61.12,25.11 61.26,25.25 61.54,25.25 61.54,25.24 61.68,25.1 61.68,23.71 61.82,23.57 62.1,23.57 62.24,23.71 62.24,24.17 62.38,24.31 62.66,24.31 62.8,24.17 62.8,23.71 62.94,23.57 63.22,23.57 63.36,23.71 63.36,24.17 63.5,24.31 63.78,24.31 63.92,24.17 63.92,23.71 64.06,23.57 64.37,23.57 64.51,23.71 64.51,25.02 64.89,25.4 66.36,25.4 67.02,26.06 71.94,26.06 74.25,23.75 93.42,23.75 94.45,24.79 98.47,24.79 98.59,24.92 v1(104.36,24.92) ; v1(129.38,47.9) 130.24,47.9 131.28,46.86 133.16,46.86 133.67,47.37 136.24,47.37 136.64,46.96 140.33,46.96 141.27,47.9 142.82,47.9 143.44,48.53 144.26,48.53 145.14,49.41 150.92,49.41 154.31,52.79 154.31,55.9 153.23,56.98 153.23,61.19 157.3,65.26 157.75,65.26 158.89,66.4 158.89,73.46 v1(158.77,73.57)
LAD1: length 223.8
  TOP w0.14: v1(57.04,65.15) 57.25,65.36 U12.BJ17 ; v1(45.2,44.09) 45.18,44.07 42.66,44.07 41.79,44.94 U16.23 ; R46.2 159.17,78.29 158.76,77.88 158.76,75.44 v2(158.41,75.08) 158.31,74.98 v1(158.31,73.18) ; v1(128.53,47.34) 128.66,47.21 U18.127 128.66,45.24 128.7,45.2 128.7,43.2 131.04,40.86 131.04,36.21 130.52,35.69 130.52,33.09 129.3,31.87 127.96,31.87 127.35,31.26 127.35,29.91 126.3,28.85 125.28,28.85 124.12,27.69 111.34,27.69 108.48,24.83 105.13,24.83 v1(104.99,24.97)
  IN1 w0.14: v1(128.53,47.34) 128.95,47.75 128.95,48.11 129.18,48.34 130.41,48.34 130.93,47.82 140.77,47.82 141.16,48.21 142.69,48.21 143.3,48.82 144.14,48.82 145.02,49.7 150.78,49.7 154.02,52.93 154.02,55.78 152.94,56.86 152.94,61.31 157.18,65.55 157.63,65.55 158.6,66.52 158.6,72.89 v1(158.31,73.18) ; v1(57.04,65.15) 57.04,65.38 56.61,65.81 56.13,65.81 55.67,65.35 55.67,64.32 54.26,62.91 54.26,59.35 53.51,58.6 53.51,56.22 51.69,54.41 50.03,54.41 46.14,50.52 46.14,46.57 46.14,46.32 45.2,45.38 v1(45.2,44.09) 45.2,38.66 44.57,38.02 44.57,36.63 44.79,36.4 44.79,32.96 46.5,31.26 46.5,28.16 48.13,26.53 51.08,26.53 54.07,23.55 56.48,23.55 56.79,23.24 64.78,23.24 64.92,23.38 64.92,23.89 65.06,24.03 65.33,24.03 65.47,23.89 65.47,23.38 65.61,23.24 66.26,23.24 66.45,23.44 66.45,23.63 65.42,24.67 65.42,24.85 65.43,24.85 65.63,25.05 65.64,25.04 65.83,25.04 66.85,24.03 67.05,24.03 67.28,24.26 67.28,24.4 67.14,24.54 66.91,24.54 66.77,24.68 66.77,24.96 66.91,25.1 67.14,25.1 67.28,25.24 67.28,25.37 67.67,25.77 71.82,25.77 74.13,23.46 93.68,23.46 94.68,24.46 95.52,24.46 96.23,23.75 97.37,23.75 97.96,24.33 104.61,24.33 104.99,24.71 v1(104.99,24.97)
LAD2: length 217.9
  TOP w0.14: v1(157.83,73.55) v2(157.83,76.23) 157.83,76.25 158.47,76.9 158.47,78.82 R40.2 ; U12.BJ13 56.13,67.3 v1(55.73,66.9) ; v1(128.52,48.03) 128.08,47.6 128.08,47.04 128.26,46.87 U18.128 128.26,45.21 128.41,45.07 128.41,43.01 130.75,40.67 130.75,36.37 130.14,35.76 130.14,33.33 128.97,32.16 127.84,32.16 127.06,31.38 127.06,30.04 126.16,29.14 124.25,29.14 123.11,28 v1(109.08,28) ; v1(43.74,45.03) U16.20
  IN1 w0.14: v1(109.08,28) 109.08,26.71 105.87,23.5 100.24,23.5 99.18,22.43 96.41,22.43 95.75,23.09 94.43,23.09 94.19,22.85 68.8,22.85 68.57,22.63 68.57,22.61 56.23,22.61 55.93,22.9 53.8,22.9 50.77,25.93 47.9,25.93 46.33,27.5 45.59,27.5 45.15,27.94 45.15,29.24 45.3,29.39 45.3,31.29 44.2,32.4 44.2,35.04 44.21,35.05 44.21,35.54 43.12,36.63 43.12,38.84 44.36,40.08 44.36,42.47 43.74,43.09 v1(43.74,45.03) 45.56,46.85 45.56,50.8 49.75,54.99 51.45,54.99 52.92,56.46 52.92,59 53.66,59.74 53.66,63.17 54.96,64.47 54.96,65.68 55.73,66.46 v1(55.73,66.9) ; v1(157.83,73.55) 157.83,73.06 158.3,72.58 158.3,66.64 157.5,65.84 157.05,65.84 152.65,61.43 152.65,56.68 153.69,55.64 153.69,53.02 150.66,49.99 144.9,49.99 144.02,49.11 143.16,49.11 142.56,48.51 141.05,48.51 140.65,48.11 131.05,48.11 130.52,48.64 129.05,48.64 128.52,48.11 v1(128.52,48.03)
LAD3: length 227.7
  TOP w0.102: U12.BG14 58.54,66.82 58.25,67.11 58.01,67.11 57.92,67.02 57.37,67.02
  TOP w0.14: 57.37,67.02 56.49,67.02 v1(56.34,66.88) ; U18.1 125.77,44.45 125.47,44.76 v1(125.11,44.76) 124.64,44.28 124.64,43.48 124.09,42.93 124.09,40.99 123.26,40.16 123.26,36.73 122.62,36.09 122.62,35.05 123.26,34.42 123.26,32.44 123.99,31.71 123.99,30.12 122.77,28.9 113.15,28.9 110.12,31.93 108.88,31.93 107.99,31.04 107.99,30.53 v1(107.71,30.25) ; v1(156.84,71.96) 156.84,73.46 v2(157.04,73.66) 157.2,73.82 157.2,76.47 158.18,77.45 158.18,78.37 157.74,78.81 157.74,79.75 158.54,80.54 R32.2 ; v1(44.47,45.06) 45.36,45.06 45.69,45.39 45.69,46.12 U16.17
  IN1 w0.14: v1(156.84,71.96) 156.84,71.66 158.01,70.49 158.01,66.76 157.38,66.14 156.93,66.14 152.35,61.55 152.35,56.52 153.36,55.51 153.36,53.11 150.54,50.29 144.76,50.29 143.88,49.4 143.02,49.4 142.43,48.82 140.94,48.82 140.53,48.41 131.29,48.41 130.12,49.58 129.34,49.58 127.96,48.21 127.96,46.69 126.03,44.76 v1(125.11,44.76) ; v1(107.71,30.25) 108.66,29.31 108.66,27.01 105.47,23.83 100.09,23.83 99.01,22.75 97.7,22.75 97.01,23.44 94.15,23.44 93.87,23.17 74,23.17 71.75,25.43 68.09,25.43 67.63,24.97 67.63,24.13 66.44,22.94 56.38,22.94 56.07,23.24 53.94,23.24 50.96,26.23 48.02,26.23 46.45,27.79 45.71,27.79 45.46,28.04 45.46,29.12 45.71,29.36 45.71,31.3 44.5,32.51 44.5,36.09 43.76,36.83 43.76,38.71 44.85,39.8 44.85,42.44 44.47,42.82 v1(44.47,45.06) 44.47,45.34 45.85,46.72 45.85,50.66 49.89,54.7 51.57,54.7 53.22,56.34 53.22,58.84 53.97,59.6 53.97,63.05 55.38,64.46 55.38,65.47 56.13,66.22 56.13,66.66 v1(56.34,66.88)
LAN_MCT0:
  vias: v1(140.49,84.42) v1(141.06,84.13)
LAN_MCT1:
  vias: v1(137.91,85.01) v2(138.6,85.22)
LAN_MCT2:
  vias: v1(133.42,84.63) v2(132.76,84.84)
LAN_MCT3:
  vias: v1(130.9,84.94) v2(131.51,84.56)
LAN_MX0+: length 10.2
  TOP w0.102: v1(142.76,84.48) 142.76,84.3 142.97,84.1 U8.13
  IN1 w0.089: CN9.1 136.86,89.41 140.7,85.57 141.85,85.57 142.6,84.82 142.6,84.65 v1(142.76,84.48)
LAN_MX0-: length 10.2
  TOP w0.102: v1(141.9,84.48) 141.7,84.28 U8.14
  IN1 w0.089: v1(141.9,84.48) 142.21,84.48 142.36,84.63 142.36,84.72 141.75,85.33 140.6,85.33 136.69,89.24 136.68,89.25 CN9.2
LAN_MX1+: length 9.7
  TOP w0.102: U8.17 137.89,84.05 137.63,84.3 137.18,84.3 137.01,84.47 137.01,84.82 136.71,85.12 136.31,85.12 v1(136.04,85.39)
  IN1 w0.089: CN9.3 134.82,88.94 134.41,88.52 134.41,88.33 135.42,87.31 135.42,85.34 135.59,85.18 135.82,85.18 135.82,85.17 v1(136.04,85.39)
LAN_MX1-: length 9.7
  TOP w0.102: U8.18 136.62,84.07 136.77,84.23 136.77,84.72 136.61,84.88 136.31,84.88 v1(136.04,84.61)
  IN1 w0.089: CN9.6 132.86,88.16 134.23,88.16 135.18,87.21 135.18,85.24 135.49,84.94 135.72,84.94 v1(136.04,84.61)
LAN_MX2+: length 8.2
  TOP w0.102: CN9.4 133.14,89.25 133.03,89.15 133.03,88.45 134.1,87.38 134.1,86.52 v2(134.61,86) 134.08,85.47 134.08,85.29 134.63,84.74 134.63,84.31 134.76,84.18 135.13,84.18 135.35,83.96 U8.19
LAN_MX2-: length 8.2
  TOP w0.102: U8.20 134.08,84 134.39,84.31 134.39,84.64 133.84,85.19 133.84,85.48 133.34,85.98 v2(133.34,86) 133.86,86.52 133.86,87.28 132.79,88.35 CN9.5
LAN_MX3+: length 8.1
  TOP w0.102: CN9.7 130.76,89.34 130.95,89.15 130.95,88.34 129.88,87.27 129.88,86.27 v2(130.39,85.75) 129.88,85.24 129.88,84.39 130.27,84 U8.23
LAN_MX3-: length 8.1
  TOP w0.102: CN9.8 130.51,89.25 130.71,89.05 130.71,88.44 129.64,87.37 129.64,86.27 v2(129.12,85.75) 129.64,85.24 129.64,84.28 129.51,84.15 129.15,84.15 129,84 U8.24
LANCT3:
  vias: v1(146.88,80.53) v2(132.08,81.55) v2(143.29,80.86)
LANVCC: length 3.2
  TOP w0.203: C91.1 145.01,58.71 145.16,58.86 145.16,59.04 145.28,59.16 145.28,59.63 145.42,59.77 U11.11
  TOP w0.508: C91.1 144.37,58.83 v1(143.74,58.83)
  vias: v1(144.11,65.3) v1(146.27,57.55) v2(146.3,64.85)
LFRAME#: length 236.7
  TOP w0.14: v1(59,65.37) 58.99,65.36 U12.BG17 ; U16.22 42.44,45.03 42.95,44.52 45.25,44.52 45.71,44.98 46.09,44.98 46.4,44.68 v1(46.4,43.74) ; v1(156.18,71.95) v2(156.18,72.67) 156.18,73.76 156.81,74.4 156.81,76.5 157.89,77.57 157.89,78.16 157.45,78.59 157.45,79.87 159.14,81.56 R29.2 ; U18.3 125.63,43.65 v1(125.44,43.46) 125.31,43.33 124.91,43.33 124.38,42.81 124.38,40.87 123.55,40.04 123.55,36.54 122.95,35.94 122.95,35.2 123.55,34.61 123.55,32.56 124.28,31.83 124.28,30 122.89,28.61 110.2,28.61 109.8,29.01 108.18,29.01 v1(107.94,29.25)
  IN1 w0.14: v1(59,65.37) 56.6,62.97 55.19,62.97 54.85,62.62 54.85,58.97 54.09,58.22 54.09,55.98 51.94,53.82 50.29,53.82 46.83,50.36 46.83,45.59 46.4,45.16 v1(46.4,43.74) 46.16,43.5 46.16,38.39 45.33,37.57 45.33,36.91 45.8,36.44 45.8,35.17 47.46,33.5 47.46,30.45 47.15,30.14 47.15,28.34 48.37,27.11 51.36,27.11 53.05,25.43 54.25,25.43 54.5,25.17 54.5,24.61 54.78,24.33 56.73,24.33 57.06,24 60.49,24 60.67,24.18 60.67,26.14 60.88,26.35 61.18,26.35 61.32,26.21 61.32,25.84 61.43,25.73 61.76,25.73 61.88,25.85 61.88,26.21 62.02,26.35 62.3,26.35 62.44,26.21 62.44,25.57 62.58,25.43 62.86,25.43 63,25.57 63,26.21 63.14,26.35 63.42,26.35 63.56,26.21 63.56,25.57 63.7,25.43 63.97,25.43 64.11,25.57 64.11,26.21 64.25,26.35 64.47,26.35 64.61,26.21 64.61,25.84 64.75,25.71 65.03,25.71 65.17,25.84 65.17,26.21 65.31,26.35 65.59,26.35 65.73,26.21 65.73,25.84 65.87,25.71 66.15,25.71 66.29,25.84 66.29,26.21 66.43,26.35 72.16,26.35 73.09,25.43 78.97,25.43 80.33,24.07 88.8,24.07 89.88,25.15 90.23,25.15 90.37,25.01 90.37,24.27 90.51,24.13 90.79,24.13 90.93,24.27 90.93,25.01 91.07,25.15 91.35,25.15 91.49,25.01 91.49,24.27 91.63,24.13 91.91,24.13 92.05,24.27 92.05,25.01 92.19,25.15 92.47,25.15 92.61,25.01 92.61,24.27 92.75,24.13 93.03,24.13 93.17,24.27 93.17,25.01 93.3,25.15 97.81,25.15 98.09,25.43 106.59,25.43 108.37,27.2 108.37,28.82 v1(107.94,29.25) ; v1(156.18,71.95) 156.18,71.91 157.72,70.36 157.72,66.88 157.26,66.43 156.81,66.43 152.06,61.68 152.06,56.4 153.07,55.39 153.07,53.31 150.34,50.58 144.64,50.58 143.76,49.7 142.88,49.7 142.31,49.12 140.81,49.12 140.41,48.72 131.61,48.72 130.42,49.91 129.1,49.91 127.67,48.48 127.67,47.06 126.1,45.49 125.19,45.49 124.43,44.73 124.43,44.06 125.03,43.46 v1(125.44,43.46)
LGND:
  vias: v1(146.14,85.17) v2(146.22,84.1)
LID#: length 75.6
  TOP w0.102: v1(140.66,89.87) 140.35,89.87 139.66,89.17 MR6.2 ; v1(134.23,44.04) 136.06,44.04 136.26,44.24 U18.108 136.26,47.27 136.21,47.32 136.21,51.26 137.84,52.88 v2(138.6,52.88) 138.65,52.88 139.42,53.65 v1(139.42,53.83)
  IN1 w0.102: v1(139.42,53.83) 139.42,53.82 142.51,53.82 142.51,53.85 142.54,53.87 145.81,53.87 149.06,57.12 149.06,60.91 148.61,61.37 148.61,63.45 149.22,64.06 150.23,64.06 153.6,67.43 153.6,69.2 v1(153.64,69.24)
  IN2 w0.102: v1(153.64,69.24) 153.51,69.24 152.3,70.45 152.27,70.45 151.2,71.53 151.2,77.24 148.89,79.55 148.89,83.08 v1(149.04,83.24) 149.04,83.77 146.57,86.23 143.07,86.23 141.06,88.24 141.06,89.46 v1(140.66,89.87)
  BOTTOM w0.102: v1(134.23,44.04) 133.66,44.61 R359.2 131.14,45.39 D35.1 ; v1(149.04,83.24) 148.48,83.24 148.07,82.83 D33.1
LINE1-L: length 8.3
  TOP w0.203: U9.22 20.66,78.41 20.64,78.44 v1(20.64,78.57)
  TOP w0.381: v2(21.12,82.58) 21.12,82.73 20.51,83.34 C348.1 20.01,83.34 v1(19.4,82.73)
  BOTTOM w0.381: v1(20.64,78.57) 20.64,78.97 21.1,79.43 21.1,80.75 19.4,82.45 v1(19.4,82.73)
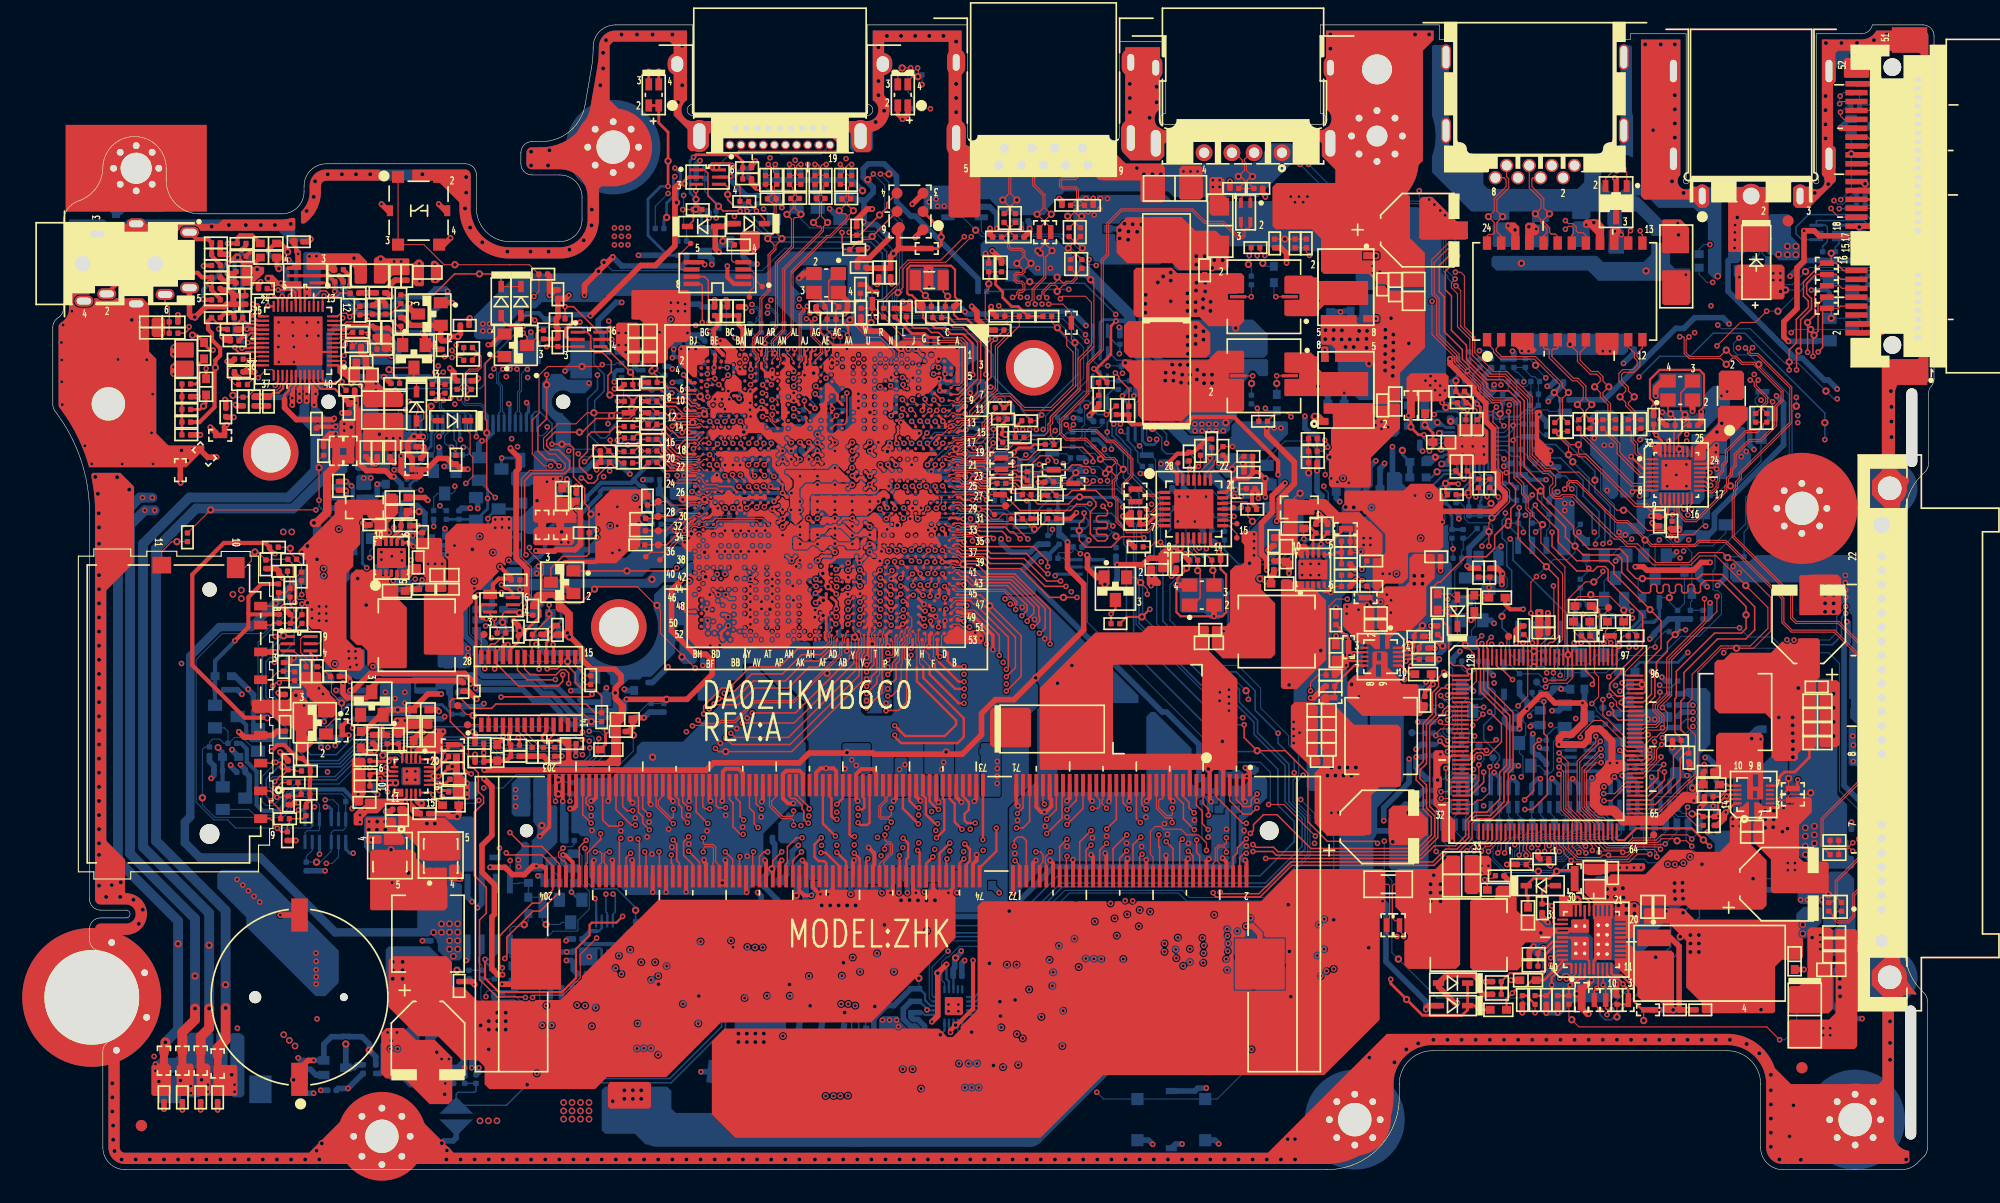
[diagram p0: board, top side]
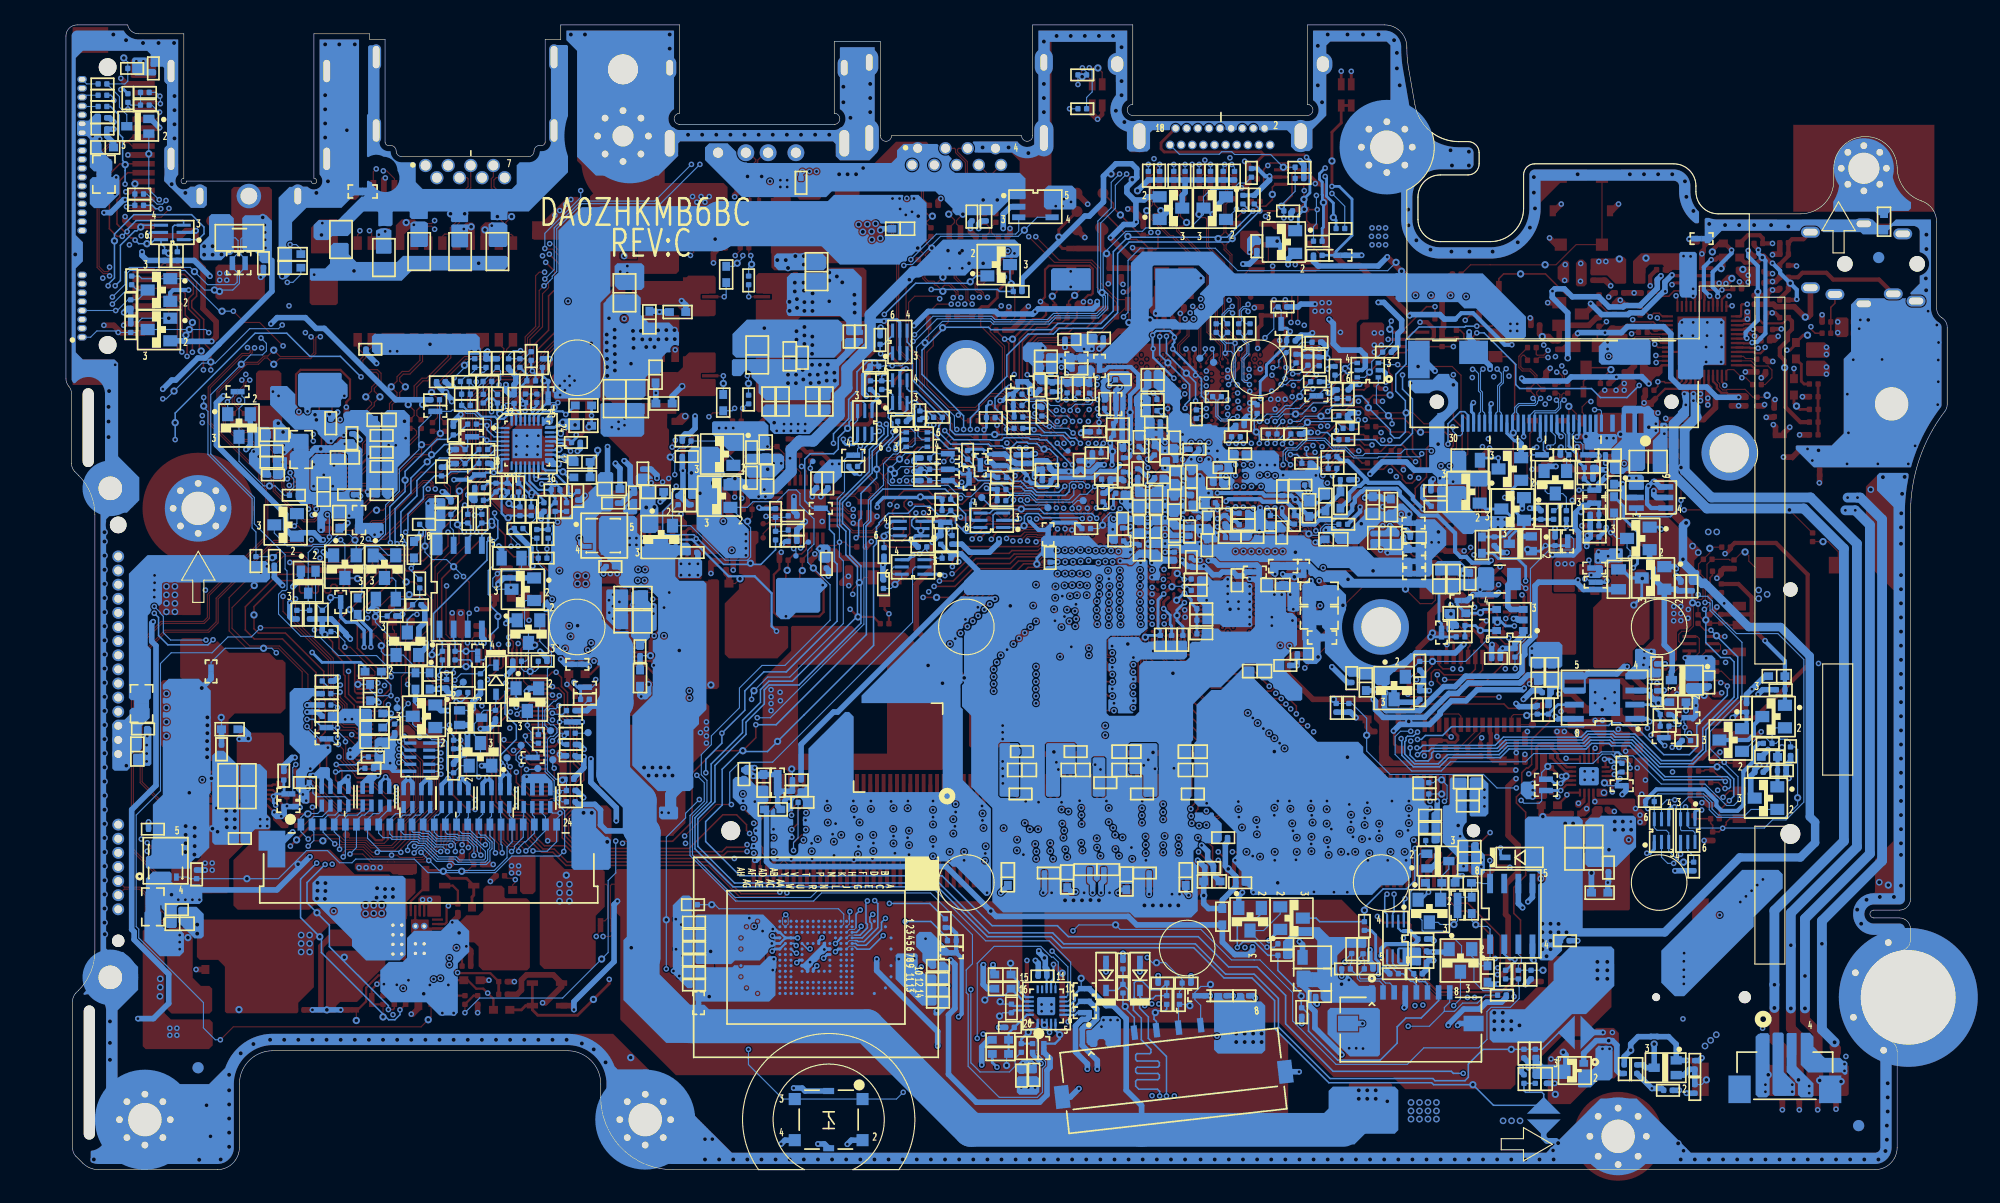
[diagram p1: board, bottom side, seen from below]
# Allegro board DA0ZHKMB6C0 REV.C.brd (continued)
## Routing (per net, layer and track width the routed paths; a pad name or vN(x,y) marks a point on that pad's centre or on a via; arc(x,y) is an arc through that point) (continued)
LINE1-R: length 7.1
  TOP w0.203: v1(21.37,78.61) 21.34,78.61 21.06,78.34 U9.21
  TOP w0.381: v1(21.23,81.86) 21.2,81.89 20.82,81.89 20.64,82.07 C349.1 20.13,81.28 v2(20.34,81.08)
  BOTTOM w0.381: v1(21.23,81.86) 21.89,81.2 21.89,79.13 v1(21.37,78.61)
LINE1-VREFO-L: length 11.5
  TOP w0.203: U9.31 18.33,74.37 18.3,74.35 17.62,74.35 v1(17.54,74.42)
  TOP w0.381: R514.2 17.37,83.14 v1(16.98,82.75)
  BOTTOM w0.381: v1(17.54,74.42) 17.5,74.46 17.11,74.46 16.79,74.78 16.79,74.79 16.35,75.24 16.35,81.79 v2(16.63,82.07) 16.98,82.42 v1(16.98,82.75)
LINE1-VREFO-R: length 10.4
  TOP w0.203: v1(18.03,74.8) 18.05,74.77 U9.30
  TOP w0.381: v1(17.9,82.69) 17.87,82.69 R515.2
  BOTTOM w0.381: v1(18.03,74.8) 18.13,74.9 18.13,75.34 17.03,76.43 v2(17.03,79) 17.03,81.31 17.9,82.17 v1(17.9,82.69)
LPC_RCOMP: length 1.8
  TOP w0.14: v1(59.78,65.3) 59.78,65.25 U12.BF18
  BOTTOM w0.14: R285.2 59.03,66.06 v1(59.78,65.3)
LPC_V3P3_PWR: length 16.2
  TOP w0.203: v1(65.64,60.88) 65.64,61.62 U12.AN24
  TOP w0.305: U12.AM27 66.02,60.5 v1(65.64,60.88)
  BOTTOM w0.381: v1(65.64,60.88) 61.61,60.88 61.37,60.65 C224.2 58.99,60.65 v2(58.64,60.3) 58.16,59.82 58.16,59.54 C236.1 56.91,58.78 56.43,59.26 C235.1 55.92,59.51 54.58,60.86 R302.1 54.58,60.99 R292.2
M_A_A0: length 30.2
  TOP w0.216: U12.K45 77.11,51.69 v1(77.39,51.69) ; v1(76.16,28.24) JDIM6.98
  IN2 w0.102: 78.93,44.54 78.93,45.36 78.76,45.54 78.76,46.13 78.6,46.28 78.1,46.28 77.91,46.46 77.91,47.96 77.3,48.57 77.3,51.6 v1(77.39,51.69)
  IN2 w0.203: v1(76.16,28.24) 76.77,28.24 77.16,28.63 77.16,29.69 77.38,29.92 77.79,29.92 77.94,30.07 77.94,30.38 77.77,30.56 77.08,30.56 76.85,30.79 76.85,31.19 77.08,31.41 77.08,31.81 76.85,32.03 76.85,34.62 78.93,36.7 78.93,44.54
M_A_A1: length 31.5
  TOP w0.216: v1(78.46,50.26) 78.28,50.26 U12.H47 ; JDIM6.97 76.46,32.5 v1(77.85,31.1)
  IN2 w0.102: 79.24,47.42 79.24,47.65 78.62,48.26 78.29,48.26 77.84,48.72 77.84,50.4 77.92,50.48 78.23,50.48 v1(78.46,50.26)
  IN2 w0.203: v1(77.85,31.1) 77.85,31.19 78.56,31.9 78.56,32.82 79.75,34.01 80.23,34.01 80.48,34.26 80.48,34.98 80.69,35.18 80.97,35.18 81.15,35.36 81.15,35.79 80.99,35.94 80.69,35.94 80.51,36.12 80.51,36.37 80.69,36.55 80.98,36.55 81.21,36.78 81.21,39.34 80.98,39.57 80.41,39.57 80.23,39.75 80.23,40 80.41,40.18 81.03,40.18 81.21,40.36 81.21,40.68 81,40.89 80.48,40.89 80.15,41.22 80.15,45.57 80.48,45.9 80.48,46.13 79.98,46.63 79.64,46.63 79.24,47.04 79.24,47.42
M_A_A2: length 29.7
  TOP w0.216: JDIM6.96 76.76,27.92 76.93,28.09 76.93,29.37 v1(76.48,29.81) ; U12.L41 76.47,53.43 v1(76.26,53.22)
  IN2 w0.102: v1(76.26,53.22) 76.49,53.22 76.67,53.04 76.67,51.56 77.05,51.18 77.05,48.34 77.6,47.79 77.6,46.16 78.01,45.75
  IN2 w0.203: 78.01,45.75 78.32,45.44 78.32,36.98 76.22,34.88 76.22,30.08 v1(76.48,29.81)
M_A_A3: length 31
  TOP w0.216: JDIM6.95 77.06,33.17 77.67,32.56 v1(77.88,32.56) ; v1(78.27,51.68) 78.24,51.68 U12.H44
  IN2 w0.102: 79.29,45.69 79.06,45.92 79.06,46.43 78.85,46.64 78.29,46.64 78.17,46.76 78.17,47.99 77.53,48.63 77.53,50.94 v1(78.27,51.68)
  IN2 w0.203: 79.29,45.69 79.4,45.69 79.54,45.55 79.54,39.14 79.72,38.96 80.42,38.96 80.6,38.79 80.6,38.53 80.42,38.35 79.72,38.35 79.54,38.18 79.54,37.92 79.72,37.74 80.42,37.74 80.6,37.57 80.6,37.31 80.42,37.14 79.77,37.14 79.54,36.91 79.54,36.42 79.21,36.09 79.21,35.81 79.38,35.64 79.54,35.64 79.72,35.46 79.72,35.21 79.54,35.03 78.12,35.03 77.94,34.85 77.94,34.6 78.12,34.42 78.6,34.42 78.78,34.24 78.78,33.99 78.6,33.81 77.94,33.81 77.46,33.33 77.46,32.98 v1(77.88,32.56)
M_A_A4: length 30.2
  TOP w0.216: JDIM6.92 77.96,28.54 v1(77.78,28.72) ; U12.H50 78.21,48.9 v1(78.42,48.9)
  IN2 w0.203: v1(78.42,48.9) 78.67,48.9 79.77,47.8 79.77,47.47 79.98,47.27 80.3,47.27 81.53,46.05 81.53,45.72 81.3,45.5 80.97,45.5 80.76,45.29 80.76,44.89 80.97,44.68 81.12,44.68 81.32,44.48 81.32,44.07 81.12,43.87 80.97,43.87 80.76,43.67 80.76,43.26 80.97,43.06 81.12,43.06 81.35,42.83 81.35,42.42 81.22,42.29 80.94,42.29 80.79,42.14 80.79,41.76 80.92,41.63 81.12,41.63 81.82,40.93 81.82,34.67 80.15,33.01 80.15,32.25 79.68,31.77 79.33,31.77 78.91,31.34 78.91,29.71 78.69,29.49 78.69,28.61 78.39,28.31 78,28.31 77.78,28.54 v1(77.78,28.72)
M_A_A5: length 31.9
  TOP w0.102: 78.86,45.24 78.86,45.28 78.17,45.98 78.17,47.67 U12.G53
  TOP w0.165: 78.86,45.24 78.86,44.86
  TOP w0.216: v1(81.95,41.96) 81.47,41.96 78.86,44.58 78.86,44.86 ; v1(79.59,31.13) 79.35,31.13 78.52,31.96 78.52,33.42 78.26,33.68 JDIM6.91
  IN2 w0.203: v1(79.59,31.13) 79.97,31.13 80.86,32.03 80.86,32.85 82.44,34.43 82.44,34.95 82.62,35.13 83.51,35.13 83.68,35.31 83.68,35.56 83.51,35.74 82.61,35.74 82.43,35.92 82.43,36.17 82.61,36.35 83.51,36.35 83.68,36.53 83.68,36.78 83.51,36.96 82.61,36.96 82.43,37.14 82.43,37.39 82.61,37.57 83.16,37.57 83.34,37.75 83.34,38 83.16,38.18 82.61,38.18 82.43,38.36 82.43,38.61 82.61,38.79 83.07,38.79 83.25,38.96 83.25,39.22 83.07,39.4 82.61,39.4 82.43,39.57 82.43,39.83 82.61,40.01 82.95,40.01 83.14,40.2 83.14,40.47 82.95,40.67 82.67,40.67 82.44,40.89 82.44,41.18 81.95,41.66 v1(81.95,41.96)
M_A_A6: length 32.9
  TOP w0.216: U12.H49 78.26,49.56 v1(78.34,49.56) ; v1(79.15,28.14) 78.56,27.55 JDIM6.90
  IN1 w0.102: 78.78,48.41 78.32,48.41 77.99,48.74 77.99,49.2 v1(78.34,49.56)
  IN1 w0.203: 78.78,48.41 79.39,47.8 80.13,47.8 81.11,46.82 81.11,41.3 81.42,40.98 81.42,36.65 80.1,35.33 79.16,35.33 77.24,33.41 77.24,30.67 76.95,30.38 76.95,27.21 77.34,26.82 77.72,26.82 78.07,27.18 78.07,27.71 78.5,28.14 v1(79.15,28.14)
M_A_A7: length 29.5
  TOP w0.216: v1(80.67,29.38) 79.76,28.46 JDIM6.86 ; v1(79.67,48.82) 79.67,49.28 U12.D50
  IN2 w0.203: v1(80.67,29.38) 80.95,29.11 81.17,29.11 81.94,29.88 82.64,29.88 83.57,30.81 83.99,30.81 85.08,31.9 85.08,33.39 86.02,34.33 86.02,40.18 83.91,42.29 83.91,44.57 v1(79.67,48.82)
M_A_A8: length 32.2
  TOP w0.102: U12.G52 78.51,48.15 78.51,47.55 78.37,47.41 78.37,46.76 78.8,46.33 78.8,46.02 79.34,45.49
  TOP w0.216: 79.34,45.49 79.34,45.08 81.16,43.26 v1(81.98,43.26) ; JDIM6.89 78.86,33.15 79.6,32.4 v1(79.66,32.4)
  IN1 w0.203: v1(81.98,43.26) 82.18,43.26 82.45,42.98 82.45,41.55 82.03,41.14 82.03,35.73 80.75,34.44 80.13,34.44 79.85,34.72 79.6,34.72 79.42,34.54 79.42,34.29 79.55,34.16 79.55,33.91 79.37,33.73 78.86,33.73 78.68,33.56 78.68,33.05 78.35,32.72 78.35,29.62 78.65,29.32 79.87,29.32 80.31,29.76 80.31,32.21 80.12,32.4 v1(79.66,32.4)
M_A_A9: length 32.3
  TOP w0.102: U12.E52 79.48,48.28 79.2,48 79.2,46.18 79.74,45.63
  TOP w0.216: v1(79.48,29.86) 80.18,30.56 80.18,33.26 80.06,33.38 JDIM6.85 ; v1(81.96,43.9) 81.47,43.9 79.74,45.63
  IN2 w0.203: v1(79.48,29.86) 79.8,30.18 80.31,30.18 80.48,30 81.18,30 81.36,30.18 81.36,30.43 81.18,30.61 80.91,30.61 80.74,30.79 80.74,31.04 80.91,31.22 82.15,31.22 82.34,31.4 82.34,31.66 82.15,31.85 81.68,31.85 81.5,32.03 81.5,32.28 81.68,32.46 82.16,32.46 82.39,32.69 82.39,33.51 83.4,34.52 83.76,34.52 84.29,35.05 84.29,37.89 83.86,38.32 83.86,40.62 82.69,41.78 82.69,43.68 82.46,43.9 v1(81.96,43.9)
M_A_A10: length 34.5
  TOP w0.102: U12.K48 76.88,49.99 77.26,49.61 77.26,48.88 77.14,48.76 77.14,48.65 76.97,48.48 76.97,48.36 77.18,48.16 77.18,47.97 77.05,47.84 77.05,47.36 76.79,47.1 76.79,46.49 77,46.28 v1(77.2,46.28)
  TOP w0.216: JDIM6.107 73.46,31.22 73.25,31.01 72.63,31.01 v1(72.42,31.22)
  IN1 w0.203: v1(77.2,46.28) 77.42,46.51 77.61,46.51 77.75,46.37 77.75,45.72 78.53,44.95 78.53,39.35 76.59,37.41 76.04,37.41 75.07,36.44 75.07,36.2 75.54,35.73 75.54,35.47 75.36,35.29 75.11,35.29 74.64,35.76 74.39,35.76 74.21,35.58 74.21,35.33 74.68,34.86 74.68,34.61 74.5,34.43 74.24,34.43 74.16,34.52 73.8,34.52 73.5,34.22 73.5,33.33 73.31,33.15 73.05,33.15 72.86,33.33 72.86,33.44 72.64,33.67 72.19,33.67 71.72,33.2 71.72,30.66 71.93,30.45 72.22,30.45 72.42,30.66 v1(72.42,31.22)
M_A_A11: length 31.4
  TOP w0.216: U12.E51 78.95,49.05 v1(78.95,49.35) ; JDIM6.84 80.36,27.9 v1(80.42,27.96)
  IN1 w0.203: v1(80.42,27.96) 80.42,26.24 80.67,25.98 81.07,25.98 81.32,26.24 81.32,30.08 80.93,30.47 80.93,33.48 82.64,35.19 82.64,40.88 83.08,41.31 83.08,44 82.46,44.62 82.46,45.53 82.12,45.88 82.12,46.69 80.45,48.36 79.47,48.36 78.95,48.88 v1(78.95,49.35)
M_A_A12: length 29.4
  TOP w0.216: U12.F47 78.86,50.69 v1(79.17,50.38) ; JDIM6.83 80.66,33.38 81.12,32.92 81.12,31.28 v1(81.77,30.63)
  IN1 w0.203: v1(81.77,30.63) 81.77,30.91 81.87,31.01 82.23,31.01 82.52,31.3 82.52,31.62 82.36,31.78 81.88,31.78 81.7,31.95 81.7,32.36 82.19,32.84 82.19,33.84 83.25,34.9 83.25,40.63 83.7,41.08 83.7,44.26 83.08,44.88 83.08,45.79 82.74,46.14 82.74,46.95 81.83,47.86 81.83,48.36 81.53,48.67 81.25,48.67 81.03,48.88 81.03,49.59 80.71,49.92 80.17,49.92 79.71,50.38 v1(79.17,50.38)
M_A_A13: length 33.9
  TOP w0.102: 77.72,45.24 77.72,47.27 77.61,47.37 77.61,48.15 U12.J51
  TOP w0.216: v1(75.73,39.96) 76.67,39.01 80.23,39.01 81.25,40.03 81.25,40.41 77.72,43.94 77.72,45.24 ; JDIM6.119 69.86,33.58 70.03,33.4 70.03,31.81 70.33,31.52 v1(70.51,31.52)
  IN2 w0.203: v1(75.73,39.96) 74.84,39.96 72.33,37.45 71.78,37.45 71.31,36.98 71.31,36.7 71.72,36.3 71.72,35.32 71.31,34.91 71.31,30.66 71.09,30.43 70.77,30.43 70.51,30.69 v1(70.51,31.52)
M_A_A14: length 32.6
  TOP w0.102: 82.78,49.32 82.36,49.73 81.65,49.73 81.52,49.86 81.18,49.86 U12.B49
  TOP w0.216: JDIM6.80 81.56,27.57 v1(81.94,27.96) ; 82.78,49.32 83.98,48.11 v1(83.98,47.3)
  IN1 w0.203: v1(81.94,27.96) 81.94,26.75 82.28,26.41 84.62,26.41 84.85,26.64 84.85,30.02 84.22,30.64 84.22,34.13 84.47,34.37 84.47,40.12 84.93,40.58 84.93,44.79 84.33,45.39 84.33,46.31 83.98,46.65 v1(83.98,47.3)
M_A_A15: length 31.5
  TOP w0.102: v1(82.46,48.82) 81.81,48.82 81.55,49.08 80.96,49.08 80.8,48.92 U12.B50
  TOP w0.216: v1(82.02,29.3) 82.48,28.84 82.48,27.77 82.16,27.44 JDIM6.78
  IN1 w0.203: v1(82.46,48.82) 82.46,48.11 83.36,47.21 83.36,46.39 83.7,46.05 83.7,45.14 84.31,44.53 84.31,40.83 83.86,40.38 83.86,34.64 83.6,34.38 83.6,32.66 83.15,32.21 83.15,31.78 83.49,31.43 83.49,30.51 84.17,29.83 84.17,27.56 83.85,27.24 83.47,27.24 82.52,28.19 82.52,28.81 v1(82.02,29.3)
M_A_BS#0: length 34.3
  TOP w0.216: v1(72.42,32.52) 72.53,32.41 72.81,32.41 72.99,32.59 72.99,33.38 72.86,33.51 JDIM6.109 ; v1(76.48,51.14) 76.69,51.14 76.88,50.95 U12.K47
  IN1 w0.102: 78.37,46.13 78.37,46.3 78.01,46.66 78.01,47.4 77.89,47.53 77.75,47.53 77.55,47.32 77.29,47.32 77.12,47.5 77.12,47.75 77.38,48.02 77.38,48.19 76.91,48.65 76.91,48.92 77.18,49.19 77.18,49.56 76.91,49.83 76.91,50.21 77.15,50.44 77.15,50.75 76.76,51.14 v1(76.48,51.14)
  IN1 w0.203: v1(72.42,32.52) 72.83,32.52 73.05,32.29 73.05,30.92 73.23,30.75 73.49,30.75 73.66,30.92 73.66,31.16 73.9,31.39 74.06,31.39 74.29,31.62 74.29,31.93 74.06,32.16 73.84,32.16 73.66,32.34 73.66,32.59 73.84,32.77 74.08,32.77 74.26,32.94 74.26,33.2 74.11,33.35 74.11,33.66 74.27,33.82 74.75,33.82 77.22,36.29 77.22,36.55 77.03,36.74 77.03,36.99 77.21,37.17 77.46,37.17 77.65,36.98 77.9,36.98 78.08,37.16 78.08,37.41 77.89,37.6 77.89,37.85 78.11,38.07 78.38,38.07 78.58,37.87 78.81,37.87 79.16,38.22 79.16,45.16 78.37,45.95 78.37,46.13
M_A_BS#1: length 34.5
  TOP w0.216: v1(76.27,52.51) 76.54,52.51 U12.K44 ; v1(73.3,27.96) 73.16,27.82 JDIM6.108
  IN1 w0.102: v1(76.27,52.51) 76.74,52.03 76.74,51.76 77.71,50.79 77.71,48.68 79.18,47.21 79.59,47.21
  IN1 w0.203: 79.59,47.21 79.84,47.21 80.38,46.67 80.38,40.77 80.8,40.35 80.8,38.06 76.55,33.81 76.55,31.01 75.28,29.74 75.28,27.84 74.61,27.17 73.53,27.17 73.3,27.4 v1(73.3,27.96)
M_A_BS#2: length 29.9
  TOP w0.102: 80.23,46.76 79.92,47.07 79.92,48 U12.D52
  TOP w0.216: v1(81.95,45.26) 80.99,45.26 80.48,45.77 80.48,46.51 80.23,46.76 ; JDIM6.79 81.86,33.6 82.39,33.07 82.39,32.39 82.01,32 82.01,31.42 82.24,31.19 v1(82.96,31.19)
  IN2 w0.203: v1(81.95,45.26) 82.23,45.26 82.39,45.11 82.39,44.73 82.52,44.6 83,44.6 83.3,44.3 83.3,42.04 84.5,40.84 84.5,38.55 84.79,38.25 85.28,38.25 85.41,38.13 85.41,34.58 84.74,33.91 83.65,33.91 83.47,33.73 83.47,33.48 83.65,33.3 84.12,33.3 84.29,33.12 84.29,32.87 84.12,32.69 83.15,32.69 82.97,32.51 82.97,32.26 83.15,32.08 83.73,32.08 83.91,31.9 83.91,31.65 83.73,31.47 83.24,31.47 v1(82.96,31.19)
M_A_CAS#: length 30.1
  TOP w0.216: v1(75.35,52.5) 75.68,52.17 U12.M44 ; v1(70.52,32.88) 71.06,33.42 JDIM6.115
  IN2 w0.102: v1(75.35,52.5) 75.07,52.78 74.94,52.78 74.86,52.71 74.86,49.58 74.76,49.48 74.76,48.82 74.23,48.29 74.23,47.73 74.41,47.55 75.37,47.55 75.6,47.32 75.6,44.64
  IN2 w0.203: 75.6,44.64 75.6,40.86 75.3,40.57 74.59,40.57 72.08,38.06 71.01,38.06 70.7,37.75 70.7,34.95 70.48,34.72 69.96,34.72 69.78,34.54 69.78,34.29 69.96,34.11 70.53,34.11 70.7,33.93 70.7,33.68 70.53,33.5 70.06,33.5 69.87,33.32 69.87,33.06 70.06,32.88 v1(70.52,32.88)
M_A_CKE0: length 32.2
  TOP w0.102: v1(80.22,51.45) 80.22,50.99 U12.C47
  TOP w0.216: v1(83.66,29.69) JDIM6.73
  IN2 w0.203: v1(80.22,51.45) 81.42,50.26 81.42,49.07 85.13,45.35 85.13,42.8 87.24,40.69 87.24,33.81 86.3,32.87 86.3,31.29 84.68,29.68 83.67,29.68 v1(83.66,29.69)
M_A_CKE1: length 30.7
  TOP w0.216: v1(84.87,30.73) 84.87,28.67 83.36,27.16 JDIM6.74 ; v1(78.9,51.6) 78.9,52.07 U12.F44
  IN2 w0.203: v1(78.9,51.6) 78.9,51.52 79.67,50.75 79.67,50.18 79.97,49.88 80.44,49.88 80.79,49.53 80.79,48.83 84.52,45.1 84.52,42.54 86.63,40.43 86.63,34.08 85.69,33.14 85.69,31.55 v1(84.87,30.73)
M_A_CLKN0: length 32.3
  TOP w0.102: U12.M48 76.16,50.04 v1(76.5,50.38) ; JDIM6.103 74.66,33.72 74.84,33.54 74.84,33.25 74.29,32.69 74.29,31.75 74.5,31.54 75.14,31.54 v1(75.41,31.27)
  IN2 w0.102: v1(76.5,50.38) 75.84,49.72 75.84,48.67 76.58,47.93 76.58,46.01 77.33,45.25 77.33,38.32 77.18,38.17 77.18,37.73 77.33,37.58 77.33,37.38 77,37.04 76.6,37.04 76.27,37.36 75.57,37.36 75.09,36.88 75.09,36.52 75.54,36.07 75.54,35.82 75.41,35.69 74.69,35.69 74.45,35.45 74.45,34.8 74.69,34.56 75.1,34.56 75.23,34.43 75.23,33.9 75.13,33.81 74.01,33.81 73.79,33.59 73.79,31.53 74.05,31.27 74.39,31.27 74.78,31.66 75.02,31.66 v1(75.41,31.27)
M_A_CLKN1: length 31.6
  TOP w0.102: JDIM6.104 74.36,27.53 75.35,28.52 75.35,29.18 75.2,29.34 75.04,29.34 74.81,29.11 v1(74.81,28.85) ; U12.P48 75.05,50.04 v1(75.41,49.68)
  IN2 w0.102: v1(74.81,28.85) 74.48,29.17 74.13,29.17 74.01,29.05 74.01,28.62 73.77,28.38 73.01,28.38 72.65,28.75 72.65,29.26 72.85,29.47 72.85,34.06 73.38,34.59 73.38,35.71 73.79,36.12 73.79,36.92 75.16,38.29 75.98,38.29 76.41,38.72 76.41,44.86 76.05,45.22 76.05,47.42 75,48.47 75,49.16 75.41,49.57 v1(75.41,49.68)
M_A_CLKP0: length 32.3
  TOP w0.102: v1(75.41,32.54) 75.41,31.92 75.24,31.74 75.23,31.74 75.2,31.72 74.57,31.72 74.46,31.82 74.46,32.61 75.02,33.17 75.02,33.49 75.26,33.72 JDIM6.101 ; v1(76.48,49.72) 76,49.72 75.89,49.61 U12.M50
  IN2 w0.102: v1(75.41,32.54) 75.41,32.17 75.1,31.85 74.7,31.85 74.31,31.46 74.13,31.46 73.98,31.61 73.98,33.51 74.09,33.62 75.21,33.62 75.42,33.82 75.42,34.51 75.18,34.75 74.77,34.75 74.64,34.87 74.64,35.37 74.77,35.5 75.49,35.5 75.73,35.74 75.73,36.14 75.28,36.6 75.28,36.8 75.65,37.17 76.2,37.17 76.52,36.85 77.08,36.85 77.52,37.3 77.52,37.66 77.37,37.81 77.37,38.09 77.52,38.24 77.52,45.33 76.77,46.09 76.77,48.01 76.03,48.75 76.03,49.64 76.23,49.84 76.36,49.84 v1(76.48,49.72)
M_A_CLKP1: length 31.5
  TOP w0.102: v1(74.83,30.12) 74.83,29.68 75,29.51 75.27,29.51 75.53,29.26 75.53,28.45 74.72,27.64 74.72,27.46 74.96,27.23 JDIM6.102 ; v1(75.41,48.99) 75.04,49.36 U12.P50
  IN2 w0.102: v1(74.83,30.12) 74.83,29.55 74.64,29.36 74.05,29.36 73.82,29.12 73.82,28.7 73.69,28.58 73.09,28.58 72.84,28.83 72.84,29.18 73.04,29.39 73.04,33.99 73.57,34.51 73.57,35.63 73.98,36.04 73.98,36.84 75.24,38.1 76.06,38.1 76.6,38.64 76.6,44.94 76.24,45.3 76.24,47.5 75.19,48.54 75.19,48.89 75.3,48.99 v1(75.41,48.99)
M_A_CS#0: length 33.9
  TOP w0.216: v1(70.51,28.54) 71.36,27.7 JDIM6.114 ; v1(75.37,51.74) 75.32,51.74 U12.P44
  IN1 w0.102: v1(75.37,51.74) 75.75,51.74 76.08,51.41 76.08,50.52 76.03,50.47 76.03,48.77 76.34,48.46
  IN1 w0.203: 76.34,48.46 76.41,48.39 76.41,46.16 77.82,44.76 77.82,39.52 76.32,38.02 75.78,38.02 73.45,35.69 73.45,35.03 72.73,34.31 71.95,34.31 71.1,33.46 71.1,29.86 71.34,29.62 71.34,27.71 71.11,27.48 70.74,27.48 70.51,27.71 v1(70.51,28.54)
M_A_CS#1: length 34.8
  TOP w0.216: v1(75.4,51.03) 74.97,51.46 U12.P45 ; v1(70.39,30.02) 69.26,31.15 JDIM6.121
  IN1 w0.102: 75.81,48.36 75.81,50.54 75.87,50.6 75.87,51.25 75.78,51.34 75.46,51.34 75.4,51.28 v1(75.4,51.03)
  IN1 w0.203: 75.81,48.36 75.74,48.29 75.27,48.29 75.04,48.06 75.04,47.79 75.31,47.53 75.78,47.53 75.93,47.38 75.93,45.77 77.17,44.53 77.17,39.76 76.04,38.63 75.53,38.63 72.84,35.94 72.84,35.32 72.67,35.15 72.39,35.15 72.23,35.32 72.23,35.72 72.06,35.9 71.76,35.9 71.09,35.23 71.09,34.31 70.01,33.24 70.01,30.88 70.39,30.51 v1(70.39,30.02)
M_A_DM0: length 53.1
  TOP w0.14: U12.G36 77.96,55.78 v1(77.96,55.75) ; JDIM6.11 104.66,33.54 107.03,31.17 v1(107.34,31.17)
  IN2 w0.14: v1(77.96,55.75) 78.37,56.16 80.48,56.16 80.61,56.04 88.18,56.04 89.48,54.74 89.6,54.74 92.54,51.8 92.54,50.8 100.64,42.7 100.64,39.81 101.02,39.42 101.22,39.42 101.37,39.57 101.56,39.57 101.76,39.37 101.76,39.17 101.62,39.03 101.62,38.83 101.82,38.63 102.01,38.63 102.16,38.78 102.35,38.78 102.55,38.58 102.55,38.38 102.41,38.24 102.41,38.04 102.61,37.84 102.8,37.84 102.95,37.99 103.15,37.99 103.34,37.79 103.34,37.59 103.2,37.45 103.2,37.25 103.4,37.05 103.59,37.05 103.74,37.2 103.94,37.2 104.13,37 104.13,36.8 103.99,36.66 103.99,36.46 104.19,36.26 104.38,36.26 104.53,36.41 104.73,36.41 104.92,36.21 104.92,36.01 104.78,35.87 104.78,35.67 104.98,35.47 105.17,35.47 105.32,35.62 105.52,35.62 105.71,35.42 105.71,35.22 105.57,35.08 105.57,34.88 105.77,34.68 105.96,34.68 106.11,34.82 106.31,34.82 106.5,34.63 106.5,34.43 106.36,34.29 106.36,34.09 106.65,33.8 106.65,31.98 107.34,31.28 v1(107.34,31.17)
M_A_DM1: length 48.8
  TOP w0.14: v1(99.47,30.12) 99.47,29.06 99.56,28.97 JDIM6.28 ; U12.B36 81.15,56.29 81.53,56.29 81.75,56.06 88.21,56.06 89.48,54.79 v1(89.48,54.25)
  IN1 w0.14: v1(99.47,30.12) 99.47,29.2 99.69,28.98 99.69,28.4 99.32,28.04 98.82,28.04 98.64,28.21 98.64,30.79 99.23,31.37 99.23,31.57 98.96,31.84 98.96,37.55 98.68,37.83 97.64,37.83 97.47,38 97.47,41.76 96.46,42.77 96.46,46.55 94.9,48.11 94.9,51.02 92.17,53.75 90.9,53.75 90.39,54.25 v1(89.48,54.25)
M_A_DM2: length 40.2
  TOP w0.14: v1(89.18,32.89) 89.06,33.01 JDIM6.63 ; U12.F38 79.21,55.16 79.34,55.04 v1(79.34,54.68)
  IN1 w0.102: 80.43,54.92 80.25,55.09 79.74,55.09 v1(79.34,54.68)
  IN1 w0.14: v1(89.18,32.89) 89.51,33.22 89.51,33.95 91.11,35.55 91.11,38.28 91.25,38.42 91.69,38.42 91.82,38.56 91.82,38.84 91.69,38.98 91.25,38.98 91.11,39.12 91.11,39.4 91.25,39.54 91.69,39.54 91.82,39.68 91.82,39.95 91.69,40.09 91.25,40.09 91.11,40.23 91.11,40.51 91.25,40.65 91.69,40.65 91.82,40.79 91.82,41.07 91.69,41.21 91.25,41.21 91.11,41.35 91.11,41.63 91.25,41.77 91.69,41.77 91.82,41.91 91.82,42.19 91.69,42.33 91.25,42.33 91.11,42.47 91.11,42.75 91.25,42.89 91.81,42.89 91.95,43.03 91.95,43.31 91.81,43.45 91.25,43.45 91.11,43.59 91.11,44.13 90.12,45.12 90.12,47.47 89.74,47.85 89.74,48.05 89.81,48.11 89.81,48.27 89.61,48.47 89.37,48.47 89.35,48.45 89.15,48.45 88.77,48.83 88.77,49.7 88.49,49.97 88.04,49.97 87.7,50.31 87.7,50.79 87.43,51.06 86.59,51.06 86.37,51.28 86.37,51.48 86.62,51.73 86.62,51.91 86.38,52.15 86.2,52.15 85.94,51.89 85.56,51.89 85.25,52.2 83.91,52.2 82.08,54.03 81.32,54.03 80.43,54.92
M_A_DM3: length 38.8
  TOP w0.14: U12.B42 81.09,53.11 82.13,53.11 82.69,52.55 85.84,52.55 87.62,50.77 87.62,50.3 v1(87.16,49.84) ; JDIM6.46 94.16,28.74 v1(94.77,29.35)
  IN2 w0.14: v1(94.77,29.35) 94.24,29.89 94.24,31.54 94.45,31.75 95.32,31.75 95.6,32.03 95.6,33.65 93.5,35.74 91.11,35.74 90.96,35.9 90.96,43.21 86.93,47.24 86.93,49.61 v1(87.16,49.84)
M_A_DM4: length 30.3
  TOP w0.102: 74.59,47.22 74.71,47.35 74.71,47.85 74.61,47.95 74.61,48.19 74.71,48.29 74.71,48.58 U12.P51
  TOP w0.14: v1(65.56,28.59) 64.76,27.79 JDIM6.136 ; 74.59,47.22 74.59,42.94 v1(73.19,41.54)
  IN1 w0.14: v1(73.19,41.54) 72.71,41.54 72.4,41.23 68.81,41.23 68.21,40.63 67.24,40.63 64.92,38.31 64.92,33.86 64.77,33.72 64.77,30.98 65.56,30.19 v1(65.56,28.59)
M_A_DM5: length 40.6
  TOP w0.14: JDIM6.170 54.56,28.55 v1(54.51,28.59) ; v1(72.55,53.29) 72.96,52.88 U12.V42
  IN1 w0.102: 73.02,48.94 73.02,52.83 v1(72.55,53.29)
  IN1 w0.14: 73.02,48.94 72.11,48.03 69.76,48.03 69.56,48.23 65.94,48.23 64.38,46.67 63.53,46.67 57.65,40.79 57.52,40.79 54.09,37.36 54.09,36.57 54.35,36.32 54.35,36.02 54.09,35.76 54.09,35.46 54.35,35.2 54.35,34.9 54.09,34.64 54.09,34.28 54.35,34.02 54.35,31.37 54.51,31.2 v1(54.51,28.59)
M_A_DM6: length 33.2
  TOP w0.14: U12.Y50 71.8,49.36 v1(71.51,49.07) ; JDIM6.153 59.66,32.76 59.86,32.56 v1(60.51,32.56)
  IN2 w0.14: v1(60.51,32.56) 61.31,33.36 61.31,33.55 60.56,34.3 60.56,34.52 60.95,34.9 61.15,34.9 61.64,34.41 61.84,34.41 62.04,34.61 62.04,34.81 61.54,35.3 61.54,35.5 61.74,35.69 61.94,35.69 62.43,35.2 62.63,35.2 62.83,35.4 62.83,35.6 62.33,36.09 62.33,36.29 62.53,36.48 62.73,36.48 63.22,35.99 63.42,35.99 63.62,36.19 63.62,36.39 63.12,36.88 63.12,37.08 63.32,37.27 63.52,37.27 64.01,36.78 64.21,36.78 64.41,36.98 64.41,37.18 63.92,37.67 63.92,37.87 68.93,42.88 68.93,44.12 68.79,44.26 68.56,44.26 68.42,44.4 68.42,44.68 68.56,44.82 68.79,44.82 68.93,44.96 68.93,45.24 68.79,45.38 68.56,45.38 68.42,45.52 68.42,45.8 68.56,45.94 68.79,45.94 68.93,46.08 68.93,46.52 70.02,47.62 70.42,47.62 71.51,48.71 v1(71.51,49.07)
M_A_DM7: length 37.3
  TOP w0.102: 71.7,46.28 71.83,46.41 71.83,47.91 U12.Y52
  TOP w0.14: v1(51.08,31.13) 50.86,30.91 50.01,30.91 49.46,31.47 JDIM6.187 ; v1(62.91,41.1) 66.8,41.1 71.64,45.95 71.64,46.22 71.7,46.28
  IN2 w0.14: v1(51.08,31.13) 51.39,31.13 51.68,31.42 51.68,31.7 51.47,31.92 51.47,33.53 56.83,38.89 57.77,38.89 61.46,42.57 62.32,42.57 62.91,41.99 v1(62.91,41.1)
M_A_DQ0: length 52.7
  TOP w0.14: v1(108.32,33.81) 107.79,33.28 107.79,32.77 107.68,32.66 107.08,32.66 106.46,33.29 JDIM6.5 ; U12.M36 76.58,55.74 v1(76.58,55.69)
  IN2 w0.14: v1(76.58,55.69) 76.58,55.81 77.44,56.67 80.86,56.67 81.75,57.56 83.69,57.56 83.81,57.67 88.22,57.67 101.68,44.21 101.68,40.93 101.99,40.61 102.19,40.61 102.39,40.81 102.59,40.81 102.79,40.61 102.79,40.41 102.59,40.22 102.59,40.02 102.78,39.82 102.98,39.82 103.18,40.02 103.38,40.02 103.58,39.82 103.58,39.62 103.38,39.43 103.38,39.23 103.58,39.03 103.77,39.03 103.97,39.23 104.17,39.23 104.37,39.03 104.37,38.83 104.17,38.64 104.17,38.44 104.37,38.24 104.56,38.24 104.76,38.44 104.96,38.44 105.16,38.24 105.16,38.04 104.96,37.85 104.96,37.65 108.32,34.29 v1(108.32,33.81)
M_A_DQ1: length 52.3
  TOP w0.14: U12.J36 77.23,55.76 v1(77.23,55.74) ; v1(107.34,29.76) 106.54,28.96 106.54,28.5 106.16,28.11 JDIM6.6
  IN2 w0.14: v1(77.23,55.74) 77.9,56.41 81.27,56.41 81.91,57.05 83.91,57.05 84.09,57.23 88.02,57.23 95.22,50.03 95.22,49.48 101.24,43.46 101.24,40.74 107.79,34.19 107.79,31.9 108.16,31.53 108.16,29.97 107.96,29.76 v1(107.34,29.76)
M_A_DQ2: length 52.3
  TOP w0.14: v1(75.06,54.67) 75.06,54.36 U12.P40 ; v1(102.13,28.65) 102.56,28.22 JDIM6.18
  IN2 w0.102: 79.98,51.97 79.85,51.97 79.67,52.15 77.2,52.15 76.88,52.46 76.88,53.17 76.34,53.72 76.23,53.72 75.64,54.31 75.43,54.31 v1(75.06,54.67)
  IN2 w0.14: v1(102.13,28.65) 101.82,28.65 101.67,28.5 101.67,27.61 101.51,27.46 101.26,27.46 101.11,27.61 101.11,28.7 100.96,28.85 100.7,28.85 100.55,28.7 100.55,27.61 100.4,27.46 100.14,27.46 99.03,28.58 99.03,30.87 99.53,31.37 99.53,33.55 94.23,38.86 94.23,43.52 90.27,47.48 90.27,48.14 86.56,51.85 82.78,51.85 82.39,51.46 81.25,51.46 80.74,51.97 79.98,51.97
M_A_DQ3: length 52.7
  TOP w0.14: v1(102.87,29.66) 102.87,28.54 103.16,28.25 JDIM6.16 ; v1(75.71,54.71) 75.71,54.47 U12.M40
  IN2 w0.102: 80.85,52.84 80.67,53.02 77.33,53.02 75.71,54.64 v1(75.71,54.71)
  IN2 w0.14: v1(102.87,29.66) 102.44,29.66 101.74,30.35 101.74,33 101.59,33.15 101.34,33.15 101.18,33 101.18,31.81 101.03,31.66 100.32,31.66 100.17,31.81 100.17,33.81 95.13,38.84 95.13,39.98 95.29,40.13 95.52,40.13 95.67,40.28 95.67,40.54 95.52,40.69 95.29,40.69 95.13,40.84 95.13,41.1 95.29,41.25 95.52,41.25 95.67,41.4 95.67,41.66 95.52,41.81 94.9,41.81 94.7,42.01 94.7,42.24 94.82,42.37 95.45,42.37 95.6,42.52 95.6,42.77 95.45,42.93 94.8,42.93 94.67,43.05 94.67,43.7 91.02,47.35 91.02,48.01 86.57,52.47 82.52,52.47 82.14,52.1 81.6,52.1 80.85,52.84
M_A_DQ4: length 52.6
  TOP w0.14: U12.P36 75.19,55.7 v1(75.2,55.7) ; JDIM6.4 106.76,28.08 107.15,28.47 v1(107.34,28.47)
  IN2 w0.102: v1(75.2,55.7) 75.63,55.27 76.27,55.27 76.8,54.75 76.8,54.46 77.02,54.24 81.37,54.24
  IN2 w0.14: 81.37,54.24 86.68,54.24 92.55,48.38 92.55,47.96 97.23,43.27 97.23,40.81 104.61,33.43 104.61,27.79 105.03,27.37 105.79,27.37 106.89,28.47 v1(107.34,28.47)
M_A_DQ5: length 53.1
  TOP w0.14: U12.N36 75.91,55.7 v1(75.93,55.7) ; JDIM6.7 105.86,33.2 107.07,31.98 107.74,31.98 v1(108.3,32.54)
  IN2 w0.14: v1(75.93,55.7) 75.93,55.79 77.04,56.91 80.47,56.91 81.63,58.06 83.53,58.06 83.61,58.14 88.38,58.14 102.12,44.4 102.12,41.9 108.93,35.09 108.93,33.17 v1(108.3,32.54)
M_A_DQ6: length 52.3
  TOP w0.14: JDIM6.15 103.46,32.93 103.94,32.45 v1(103.94,31.9) ; v1(76.34,54.62) 76.79,54.17 U12.K40
  IN2 w0.102: v1(76.34,54.62) 76.93,54.04 80.19,54.04 80.56,53.67 81.31,53.67
  IN2 w0.14: 81.31,53.67 86.63,53.67 92.1,48.19 92.1,47.53 96.72,42.91 96.72,39.46 96.84,39.34 97.24,39.34 97.54,39.65 97.76,39.65 97.94,39.47 97.94,39.26 97.63,38.95 97.63,38.75 97.83,38.55 98.03,38.55 98.34,38.86 98.55,38.86 98.73,38.68 98.73,38.47 98.42,38.16 98.42,37.96 98.62,37.76 98.82,37.76 99.13,38.07 99.34,38.07 99.52,37.89 99.52,37.68 99.21,37.37 99.21,37.17 99.41,36.97 99.61,36.97 99.92,37.28 100.13,37.28 100.31,37.1 100.31,36.89 100,36.58 100,36.38 100.2,36.18 100.4,36.18 100.69,36.48 100.91,36.48 101.09,36.3 101.09,36.08 100.79,35.79 100.79,35.59 100.99,35.39 101.19,35.39 101.5,35.7 101.71,35.7 101.89,35.52 101.89,35.3 101.58,35 101.58,34.8 101.78,34.6 101.98,34.6 102.29,34.91 102.5,34.91 102.68,34.73 102.68,34.51 102.37,34.21 102.37,34.01 102.57,33.81 102.77,33.81 103.06,34.11 103.28,34.11 103.46,33.93 103.46,33.71 103.17,33.42 103.17,33.22 104.12,32.27 104.12,32.07 v1(103.94,31.9)
M_A_DQ7: length 53
  TOP w0.14: JDIM6.17 102.86,32.79 103.38,32.26 103.38,31.13 v1(103.92,30.6) ; v1(77.32,53.61) 76.9,53.19 U12.K42
  IN2 w0.102: 81.44,53.07 81.17,53.07 81.01,53.22 77.7,53.22 v1(77.32,53.61)
  IN2 w0.14: 81.44,53.07 86.6,53.07 91.66,48.01 91.66,47.34 96.12,42.89 96.12,39.05 95.93,38.87 95.93,38.67 96.13,38.47 96.33,38.47 96.7,38.84 96.91,38.84 97.09,38.66 97.09,38.45 96.72,38.08 96.72,37.88 96.92,37.68 97.12,37.68 97.49,38.05 97.7,38.05 97.88,37.87 97.88,37.66 97.51,37.29 97.51,37.09 97.71,36.89 97.91,36.89 98.28,37.26 98.49,37.26 98.67,37.08 98.67,36.87 98.31,36.5 98.31,36.3 98.5,36.1 98.7,36.1 99.07,36.47 99.28,36.47 99.46,36.29 99.46,36.08 99.1,35.71 99.1,35.51 99.29,35.31 99.49,35.31 99.86,35.68 100.07,35.68 100.25,35.5 100.25,35.29 99.89,34.92 99.89,34.72 100.08,34.52 100.28,34.52 100.65,34.89 100.86,34.89 101.04,34.71 101.04,34.49 100.68,34.13 100.68,33.93 100.87,33.73 101.07,33.73 101.4,34.06 101.69,34.06 102.2,33.56 102.2,33.17 103.52,31.85 103.52,31 v1(103.92,30.6)
M_A_DQ8: length 48.5
  TOP w0.14: v1(87.7,56.74) 86.34,58.1 81.7,58.1 81.63,58.17 81.08,58.17 U12.B32 ; v1(101.59,29.74) 101.36,29.51 JDIM6.22
  IN1 w0.14: v1(101.59,29.74) 101.95,30.1 101.95,33.55 101.31,34.18 101.31,38.25 100.61,38.95 100.61,39.45 101.83,40.67 101.83,41.83 98.75,44.91 98.75,47.42 97.04,49.12 97.04,52.08 95.76,53.37 95.76,53.75 94.66,54.84 94.66,55.59 94.06,56.19 93.01,56.19 92.19,57 90.53,57 90.26,56.73 87.71,56.73 v1(87.7,56.74)
M_A_DQ9: length 48.1
  TOP w0.102: 82.13,57.81 81.65,57.81 81.52,57.94 81.28,57.94 81.11,57.78 80.85,57.78 80.75,57.88 80.48,57.88 U12.C32
  TOP w0.14: v1(87,56.76) 86.39,57.38 86.07,57.38 85.64,57.81 82.13,57.81 ; v1(102.65,32.12) 102.2,32.57 102.2,33.05 101.66,33.59 JDIM6.21
  IN1 w0.14: v1(102.65,32.12) 102.39,32.38 102.39,36.53 102.24,36.68 101.91,36.68 101.76,36.83 101.76,37.21 101.91,37.36 102.24,37.36 102.39,37.52 102.39,37.8 101.26,38.93 101.26,39.45 102.39,40.58 102.39,41.9 99.2,45.1 99.2,47.61 97.49,49.31 97.49,52.27 96.61,53.14 96.61,54.27 93.44,57.45 90.35,57.45 90.08,57.18 88.1,57.18 87.93,57.35 87.61,57.35 87.03,56.76 v1(87,56.76)
M_A_DQ10: length 49.2
  TOP w0.102: 81.79,55.7 81.57,55.92 81.2,55.92 81.11,55.83 80.85,55.83 80.73,55.96 80.46,55.96 U12.C36
  TOP w0.14: v1(89.5,53.62) 89.37,53.62 87.54,55.45 84.37,55.45 84.12,55.7 81.79,55.7 ; JDIM6.34 97.76,28.17 v1(97.97,28.38)
  IN1 w0.14: v1(89.5,53.62) 89.67,53.45 89.67,53.08 92.97,49.79 92.97,47.31 94.53,45.75 94.53,41.95 95.28,41.2 95.28,39.24 94.53,38.49 94.53,34.19 95.41,33.31 95.41,32.51 94.99,32.08 94.99,31.22 95.41,30.79 95.41,28.22 95.19,27.99 94.48,27.99 94.12,27.64 94.12,26.66 94.43,26.35 97.1,26.35 97.85,27.1 97.85,28.25 v1(97.97,28.38)
M_A_DQ11: length 49.5
  TOP w0.14: v1(98.33,32.46) 97.93,32.85 97.93,33.43 98.06,33.55 JDIM6.33 ; U12.A37 81.48,55.64 81.72,55.4 83.91,55.4 84.32,54.99 87.37,54.99 89.4,52.96 v1(90.64,52.96)
  IN1 w0.14: v1(90.64,52.96) 91.91,52.96 94.3,50.57 94.3,47.87 95.86,46.3 95.86,42.53 96.87,41.52 96.87,37.41 97.05,37.24 98.22,37.24 98.37,37.09 98.37,36.88 98.22,36.73 97.06,36.73 96.92,36.58 96.92,36.38 97.06,36.23 98.18,36.23 98.32,36.1 98.32,35.92 98.18,35.79 96.78,35.79 96.63,35.64 96.63,35.44 96.78,35.29 98.22,35.29 98.37,35.15 98.37,34.94 98.22,34.8 96.88,34.8 96.73,34.65 96.73,34.44 96.88,34.29 98.23,34.29 98.37,34.16 98.37,33.97 98.23,33.83 97.2,33.83 97.06,33.7 97.06,33.51 97.2,33.38 97.82,33.38 97.95,33.24 97.95,33.05 97.82,32.92 97.53,32.92 97.4,32.78 97.4,32.59 97.53,32.46 v1(98.33,32.46)
M_A_DQ12: length 48.7
  TOP w0.102: U12.C33 80.78,57.43 81.08,57.43 81.21,57.3 81.68,57.3 81.73,57.35 82.97,57.35 83.09,57.24
  TOP w0.14: v1(84.61,56.79) 84.4,56.99 83.33,56.99 83.09,57.24 ; JDIM6.24 100.76,28.88 v1(100.13,29.51)
  IN1 w0.14: v1(100.13,29.51) 100.33,29.51 101.44,30.61 101.44,33.43 100.67,34.2 100.67,38.25 100.17,38.76 100.17,39.63 101.39,40.85 101.39,41.65 98.31,44.73 98.31,47.11 96.6,48.82 96.6,51.89 95.31,53.18 95.31,53.56 94.22,54.66 94.22,55.41 93.88,55.75 92.71,55.75 92.43,56.02 89.71,56.02 89.45,56.28 84.73,56.28 84.61,56.41 v1(84.61,56.79)
M_A_DQ13: length 49.4
  TOP w0.102: 83.15,57.49 83.06,57.58 U12.A33
  TOP w0.14: v1(85.97,56.72) 85.97,56.74 85.77,56.95 85.77,57.05 85.39,57.43 83.4,57.43 83.34,57.49 83.15,57.49 ; v1(102.67,30.6) 101.69,31.57 101.69,32.92 101.06,33.55 JDIM6.23
  IN1 w0.14: v1(85.97,56.72) 85.99,56.73 86.22,56.73 87.28,57.79 89.25,57.79 89.49,58.03 91.13,58.03 91.27,57.89 93.62,57.89 97.06,54.45 97.06,53.34 97.93,52.47 97.93,49.5 99.7,47.74 99.7,45.23 103.11,41.81 103.11,31.05 102.67,30.6 v1(102.67,30.6)
M_A_DQ14: length 49.2
  TOP w0.102: 81.88,55.14 81.64,55.14 81.49,55.3 81.26,55.3 81.11,55.45 80.82,55.45 U12.C37
  TOP w0.14: v1(91.12,52.48) 89.24,52.48 87.19,54.53 84.29,54.53 83.68,55.14 81.88,55.14 ; JDIM6.35 97.46,31.6 v1(97.82,31.24)
  IN1 w0.14: v1(91.12,52.48) 91.76,52.48 93.86,50.38 93.86,47.68 95.42,46.12 95.42,42.32 96.27,41.47 96.27,38.3 96.11,38.13 95.66,38.13 95.55,38.02 95.55,37.76 95.73,37.58 96.11,37.58 96.27,37.41 96.27,37.18 96.11,37.02 95.58,37.02 95.42,36.85 95.42,36.6 95.56,36.46 96.11,36.46 96.27,36.29 96.27,36.06 96.11,35.9 95.58,35.9 95.42,35.74 95.42,35.5 95.58,35.34 96.11,35.34 96.27,35.18 96.27,35 96.09,34.82 95.94,34.82 95.8,34.68 95.8,34.48 95.94,34.34 96.2,34.34 96.38,34.16 96.38,32.18 96.53,32.03 97.38,32.03 97.53,31.88 97.53,31.67 97.37,31.52 97.37,31.14 97.23,30.99 97.02,30.99 96.87,31.14 96.87,31.36 96.7,31.52 96.47,31.52 96.3,31.36 96.3,30.72 96.48,30.54 96.87,30.54 97.13,30.28 97.35,30.28 97.82,30.75 v1(97.82,31.24)
M_A_DQ15: length 48.8
  TOP w0.102: U12.B38 81.05,55.09 81.4,55.09 81.73,54.76 81.88,54.76
  TOP w0.14: v1(92.11,51.49) v2(90.9,51.49) 89.6,51.49 87.01,54.08 84.22,54.08 83.53,54.76 81.88,54.76 ; JDIM6.36 97.16,29.23 v1(97.85,29.93)
  IN1 w0.14: v1(97.85,29.93) 97.25,29.32 97.25,27.13 96.92,26.8 95.62,26.8 95.42,27 95.42,27.59 95.86,28.03 95.86,30.97 95.43,31.4 95.43,31.9 95.86,32.33 95.86,33.65 94.97,34.53 94.97,38.3 95.83,39.16 95.83,41.29 94.97,42.14 94.97,45.94 93.41,47.5 93.41,50.19 v1(92.11,51.49)
M_A_DQ16: length 40.6
  TOP w0.14: v1(91.22,29.72) 90.56,29.07 JDIM6.58 ; U12.F36 79.36,55.8 v1(79.36,55.73)
  IN1 w0.14: v1(91.22,29.72) 91.66,30.17 91.66,33.55 93.49,35.38 93.49,45.31 91.86,46.94 91.86,48.86 86.72,54 84.01,54 82.38,55.63 81.37,55.63 80.86,56.14 79.77,56.14 79.36,55.73 v1(79.36,55.73)
M_A_DQ17: length 42.2
  TOP w0.14: v1(78.75,55.71) 78.75,55.6 U12.G38 ; JDIM6.56 91.16,28.13 v1(91.22,28.19)
  IN1 w0.14: v1(91.22,28.19) 92.16,29.13 92.16,33.2 93.93,34.98 93.93,45.5 92.37,47.07 92.37,48.98 86.78,54.57 84.07,54.57 82.59,56.06 81.57,56.06 81.13,56.5 79.53,56.5 78.75,55.72 v1(78.75,55.71)
M_A_DQ18: length 42.4
  TOP w0.14: U12.F42 79.02,52.91 v1(78.7,52.59) ; v1(86.68,30.74) 87.27,30.74 87.86,31.33 JDIM6.67
  IN1 w0.14: v1(78.7,52.59) 78.7,52.83 79.04,53.17 80.75,53.17 82.1,51.82 82.55,51.82 88.36,46.01 88.36,45.75 88.22,45.61 87.67,45.61 87.53,45.47 87.53,45.19 87.67,45.05 88.27,45.05 88.41,44.91 88.41,44.63 88.27,44.49 87.67,44.49 87.53,44.35 87.53,44.07 87.67,43.93 88.29,43.93 88.43,43.79 88.43,43.51 88.29,43.37 87.67,43.37 87.53,43.23 87.53,42.95 87.67,42.81 88.04,42.81 88.18,42.67 88.18,42.39 88.04,42.25 87.67,42.25 87.53,42.11 87.53,41.83 87.67,41.69 88.04,41.69 88.18,41.55 88.18,41.12 87.98,40.92 87.72,40.92 87.47,40.67 87.47,40.41 87.72,40.16 88.23,40.16 89.12,39.27 89.12,36.09 87.71,34.68 87.71,33.44 87.57,33.3 87.48,33.3 87.34,33.16 87.34,32.88 87.48,32.74 87.57,32.74 87.71,32.6 87.71,32.32 87.57,32.18 87.48,32.18 87.34,32.04 87.34,31.76 87.48,31.62 87.57,31.62 87.71,31.48 87.71,31 87.45,30.74 v1(86.68,30.74)
M_A_DQ19: length 41.6
  TOP w0.14: U12.J42 77.37,52.95 v1(77.37,52.56) ; v1(86.54,27.8) 86.96,27.39 JDIM6.70
  IN1 w0.102: v1(77.37,52.56) 77.87,52.06 77.87,51.39 77.99,51.27 78.59,51.27 78.9,50.95 80.61,50.95 81.77,49.79 82.07,49.79
  IN1 w0.14: 82.07,49.79 82.39,49.79 86.19,45.99 86.19,42.88 85.59,42.28 85.59,34.49 84.85,33.76 84.85,31.34 85.48,30.72 85.48,26.02 86.07,25.43 88.1,25.43 88.26,25.58 88.26,25.91 87.98,26.19 86.96,26.19 86.54,26.61 v1(86.54,27.8)
M_A_DQ20: length 42.2
  TOP w0.14: v1(89.39,31.53) 90.26,32.4 JDIM6.59 ; U12.G40 78.31,54.37 v1(78.62,54.68)
  IN1 w0.102: 80.67,55.31 79.6,55.31 79.41,55.12 79.06,55.12 78.87,55.31 78.45,55.31 78.32,55.17 78.32,54.99 v1(78.62,54.68)
  IN1 w0.14: v1(89.39,31.53) 89.89,31.03 90.15,31.03 90.3,31.18 90.3,32 90.14,32.17 90.01,32.17 89.91,32.27 89.91,32.59 90.16,32.84 90.16,33.73 90.32,33.9 90.53,33.9 92.55,35.91 92.55,37.03 92.41,37.17 91.93,37.17 91.79,37.31 91.79,37.59 91.93,37.73 92.41,37.73 92.55,37.87 92.55,44.48 90.82,46.2 90.82,48.63 86.64,52.81 83.93,52.81 82.15,54.59 81.39,54.59 80.67,55.31
M_A_DQ21: length 40.9
  TOP w0.14: v1(80.01,55.71) 80.29,55.44 U12.C38 ; v1(89.39,30.24) 90.77,31.62 90.77,33.46 90.86,33.55 JDIM6.57
  IN1 w0.14: v1(89.39,30.24) 90,30.24 90.75,31 90.75,33.36 93.04,35.65 93.04,45.12 91.42,46.75 91.42,48.67 86.68,53.41 83.97,53.41 82.33,55.04 81.44,55.04 80.77,55.71 v1(80.01,55.71)
M_A_DQ22: length 41.9
  TOP w0.14: JDIM6.68 87.56,29.61 87.25,29.92 86.77,29.92 86.48,29.62 v1(86.48,29.1) ; v1(78.01,52.61) 78.32,52.3 U12.G44
  IN1 w0.102: 82.26,50.32 82.06,50.32 80.37,52.01 78.51,52.01 78.01,52.51 v1(78.01,52.61)
  IN1 w0.14: v1(86.48,29.1) 86.82,29.1 87.06,28.85 87.06,26.85 87.21,26.7 87.58,26.7 87.71,26.82 87.71,29.63 87.34,30 86.2,30 85.92,30.28 85.92,30.91 85.46,31.37 85.46,33.19 86.2,33.93 86.2,42.26 86.63,42.69 86.63,46.33 85.44,47.52 85.28,47.52 82.49,50.32 82.26,50.32
M_A_DQ23: length 42
  TOP w0.14: JDIM6.69 87.26,32.55 v1(86.76,32.05) ; v1(79.38,52.57) 79.7,52.88 U12.D42
  IN1 w0.102: 81.56,51.69 80.32,52.94 79.38,52.94 79.26,52.81 79.26,52.69 v1(79.38,52.57)
  IN1 w0.14: v1(86.76,32.05) 86.36,31.65 86.03,31.65 85.91,31.78 85.91,33.01 86.81,33.91 86.81,35.47 86.95,35.61 87.19,35.61 87.45,35.35 87.74,35.35 88.17,35.78 88.17,36.05 88.05,36.17 86.95,36.17 86.81,36.31 86.81,36.59 86.95,36.73 88.4,36.73 88.54,36.87 88.54,37.15 88.4,37.29 86.95,37.29 86.81,37.43 86.81,37.71 86.95,37.85 88.4,37.85 88.54,37.99 88.54,38.27 88.4,38.41 86.95,38.41 86.81,38.54 86.81,38.82 86.95,38.96 88.01,38.96 88.15,39.1 88.15,39.38 87.91,39.62 87.44,39.62 87.34,39.52 86.95,39.52 86.81,39.66 86.81,40.67 87.09,40.95 87.09,46.51 82.77,50.83 82.77,50.95 82.44,51.28 81.97,51.28 81.56,51.69
M_A_DQ24: length 40.4
  TOP w0.14: v1(87.64,49.35) 87.64,49.47 88.23,50.06 88.23,50.65 86.07,52.81 82.87,52.81 82.31,53.37 81.7,53.37 U12.A41 ; v1(94.8,30.66) 95.66,31.52 JDIM6.41
  IN2 w0.14: v1(94.8,30.66) 95.24,30.66 96.19,31.61 96.19,33.89 93.75,36.34 92.86,36.34 92.68,36.52 92.68,37.41 92.52,37.57 92.27,37.57 92.12,37.41 92.12,36.49 91.96,36.34 91.71,36.34 91.56,36.49 91.56,43.46 87.53,47.49 87.53,49.24 v1(87.64,49.35)
M_A_DQ25: length 39.8
  TOP w0.102: U12.C41 80.92,53.7 81.2,53.98 81.53,53.98 81.76,53.75 81.88,53.75
  TOP w0.14: v1(88.12,48.87) 88.31,48.87 88.76,49.33 88.76,49.71 88.69,49.78 88.69,50.62 86.22,53.09 83.13,53.09 82.46,53.75 81.88,53.75 ; v1(96.8,32.46) 96.26,33 JDIM6.39
  IN2 w0.14: v1(96.8,32.46) 97.12,32.46 97.25,32.58 97.25,33.47 97.04,33.68 96.89,33.68 96.76,33.81 96.76,33.96 92.69,38.02 92.17,38.02 92,38.19 92,38.44 92.14,38.58 92.59,38.58 92.74,38.74 92.74,38.99 92.59,39.14 92.14,39.14 92,39.28 92,39.56 92.14,39.7 92.59,39.7 92.74,39.85 92.74,40.11 92.59,40.26 92.14,40.26 92,40.4 92,40.68 92.14,40.82 92.59,40.82 92.74,40.97 92.74,41.22 92.59,41.38 92.14,41.38 92,41.52 92,41.8 92.14,41.94 92.56,41.94 92.71,42.09 92.71,42.34 92.56,42.49 92.14,42.49 92,42.63 92,42.79 92.35,43.13 92.35,43.3 88.12,47.52 v1(88.12,48.87)
M_A_DQ26: length 41
  TOP w0.14: v1(85.76,43.05) 87.09,44.38 87.09,48.03 83.4,51.71 81.41,51.71 U12.A45 ; JDIM6.51 92.66,32.5 v1(91.22,31.06)
  IN2 w0.14: v1(91.22,31.06) 90.64,30.49 90.64,27.03 90.49,26.87 88.03,26.87 87.88,27.03 87.88,40.94 v1(85.76,43.05)
M_A_DQ27: length 39.9
  TOP w0.102: 81.63,51.46 81,51.46 U12.B46
  TOP w0.14: JDIM6.53 92.06,33.22 v1(91.22,32.38) ; v1(85.76,44.35) 86.58,45.17 86.58,47.9 83.02,51.46 81.63,51.46
  IN2 w0.14: v1(85.76,44.35) 85.79,44.35 88.33,41.8 88.33,30.38 88.48,30.23 88.84,30.23 88.99,30.07 88.99,29.82 88.84,29.67 88.47,29.67 88.32,29.52 88.32,29.26 88.47,29.11 88.84,29.11 88.99,28.96 88.99,27.48 89.15,27.33 90.03,27.33 90.19,27.48 90.19,31.35 v1(91.22,32.38)
M_A_DQ28: length 41
  TOP w0.102: 81.75,54.51 81.65,54.51 81.53,54.39 81.2,54.39 81.11,54.47 80.87,54.47 80.58,54.18 U12.C40
  TOP w0.14: v1(89.7,47.3) 89.7,50.42 86.53,53.59 83.99,53.59 83.07,54.51 81.75,54.51 ; v1(96.59,30.12) 95.36,28.88 JDIM6.42
  IN2 w0.14: v1(89.7,47.3) 89.7,47.2 93.63,43.27 93.63,38.59 98.82,33.4 98.82,31.55 97.39,30.12 v1(96.59,30.12)
M_A_DQ29: length 39.9
  TOP w0.102: U12.B40 81.69,54.18
  TOP w0.14: 81.69,54.18 82.66,54.18 83.51,53.34 86.4,53.34 89.25,50.5 89.25,48.7 88.81,48.26 v1(88.73,48.26) ; JDIM6.40 95.96,28.04 v1(96.59,28.67)
  IN2 w0.14: v1(96.59,28.67) 95.75,28.67 95.6,28.82 95.6,29.08 95.75,29.24 95.85,29.24 96.1,29.49 96.1,30.63 97.69,32.22 97.69,33.65 93.18,38.16 93.18,43.09 88.73,47.54 v1(88.73,48.26)
M_A_DQ30: length 39.1
  TOP w0.102: U12.B48 80.78,50.08 81.25,50.55 81.75,50.55 81.95,50.34 82.87,50.34 82.96,50.25
  TOP w0.14: 82.96,50.25 85.13,48.09 v1(85.13,46.28) ; JDIM6.52 92.36,29.48 v1(93.37,30.5)
  IN2 w0.14: v1(93.37,30.5) 92.95,30.07 92.51,30.07 92.31,30.28 92.31,30.91 92.46,31.06 93.49,31.06 93.64,31.22 93.64,31.47 93.49,31.62 92.46,31.62 92.31,31.78 92.31,32.03 92.46,32.18 92.92,32.18 93.08,32.33 93.08,32.59 92.92,32.74 92.46,32.74 92.31,32.89 92.31,33.15 92.46,33.3 92.95,33.3 93.11,33.45 93.11,33.71 92.95,33.86 92.09,33.86 91.91,34.04 90.26,34.04 90.03,33.81 89.5,33.81 89.26,34.05 89.26,42.51 85.48,46.28 v1(85.13,46.28)
M_A_DQ31: length 40.3
  TOP w0.102: 81.63,51.21 81.22,51.21 81.11,51.11 81.11,51.1 80.92,50.91 80.92,50.91 80.79,50.78 U12.B47
  TOP w0.14: v1(85.76,45.01) 85.94,45.19 85.94,47.9 82.96,50.89 82.84,50.89 82.52,51.21 81.63,51.21 ; JDIM6.50 92.96,27.68 92.93,27.71 92.93,28.76 v1(93.37,29.2)
  IN2 w0.14: v1(93.37,29.2) 93.82,28.76 93.82,27.86 93.67,27.71 92.55,27.71 91.86,28.4 91.86,33.44 91.71,33.59 90.54,33.59 90.39,33.44 90.39,32.18 90.24,32.03 89.91,32.03 89.75,32.18 89.75,33.16 89.6,33.31 88.97,33.31 88.81,33.46 88.81,42.17 85.97,45.01 v1(85.76,45.01)
M_A_DQ32: length 30.8
  TOP w0.102: U12.K52 76.84,48.07 76.84,47.44 76.59,47.18 76.59,46.01 76.63,45.96
  TOP w0.14: JDIM6.131 66.26,33.56 66.42,33.39 66.78,33.39 67.39,32.78 67.39,32.43 67.54,32.28 67.54,31.51 67.88,31.17 v1(67.95,31.17) ; v1(74.94,41.29) 74.97,41.31 76.05,41.31 76.8,42.06 76.8,45.79 76.63,45.96
  IN1 w0.14: v1(74.94,41.29) 74.87,41.29 73.11,39.53 69.51,39.53 68.91,38.93 68.26,38.93 67.74,38.41 67.74,38.22 67.38,37.87 67.02,37.87 66.66,37.51 66.66,36 66.77,35.88 67.07,35.88 67.21,35.74 67.21,35.47 67.07,35.33 66.79,35.33 66.65,35.19 66.65,34.91 66.79,34.77 66.87,34.77 67.01,34.63 67.01,34.38 66.62,33.99 66.62,33.55 67.38,32.78 67.38,31.74 v1(67.95,31.17)
M_A_DQ33: length 31.2
  TOP w0.102: U12.K51 76.67,48.59 76.67,48.32 76.54,48.19 76.54,47.95 76.64,47.85 76.64,47.53 76.38,47.27 76.38,45.49 76.29,45.4 76.29,44.09
  TOP w0.14: 76.29,44.09 76.29,43.46 75.44,42.61 v1(75.09,42.61) ; JDIM6.129 66.86,33.77 68.03,32.6 v1(68.03,32.47)
  IN1 w0.14: v1(75.09,42.61) 75.37,42.34 75.37,40.99 73.46,39.08 71.54,39.08 71.37,38.91 70.76,38.91 70.58,39.08 69.76,39.08 69.44,38.77 69.44,38.57 69.9,38.12 69.9,37.83 69.75,37.69 69.54,37.69 69.05,38.18 68.85,38.18 68.65,37.98 68.65,37.78 69.16,37.28 69.16,37.08 68.96,36.88 68.76,36.88 68.26,37.39 68.06,37.39 67.66,36.98 67.66,36.54 67.8,36.4 68.23,36.4 68.37,36.26 68.37,35.98 68.23,35.84 67.8,35.84 67.66,35.7 67.66,35.42 67.8,35.28 68.23,35.28 68.37,35.14 68.37,34.86 68.23,34.72 67.8,34.72 67.66,34.58 67.66,33.14 68.03,32.77 v1(68.03,32.47)
M_A_DQ34: length 30.9
  TOP w0.102: 73.86,47.12 73.86,47.36 73.93,47.43 U12.T52
  TOP w0.14: v1(64.29,28.59) 63.97,28.59 63.56,28.18 JDIM6.140 ; v1(73.19,44.78) 73.86,45.45 73.86,47.12
  IN1 w0.14: v1(73.19,44.78) 73.12,44.78 71.29,42.95 67.68,42.95 66.85,42.12 66.42,42.12 61.93,37.63 61.93,32.99 62.7,32.21 62.7,29.54 63.65,28.59 v1(64.29,28.59)
M_A_DQ35: length 30.9
  TOP w0.102: 73.62,47.14 73.62,47.41 73.73,47.52 73.73,47.85 73.65,47.93 73.65,47.94 73.64,47.95 73.64,48.19 73.93,48.48 U12.T51
  TOP w0.14: v1(63.02,28.59) 62.96,28.53 JDIM6.142 ; 73.62,47.14 73.62,45.74 73.31,45.43 v1(73.19,45.43)
  IN1 w0.14: v1(73.19,45.43) 72.93,45.43 70.89,43.4 67.5,43.4 66.66,42.56 66.23,42.56 61.31,37.64 61.31,35.08 61.49,34.9 61.49,30.13 v1(63.02,28.59)
M_A_DQ36: length 29.9
  TOP w0.102: 75.78,45.87 75.95,46.04 75.95,47.72 76.21,47.98 76.21,48.28 U12.L51
  TOP w0.14: v1(67.34,28.59) 66.56,27.81 JDIM6.130 ; v1(75.09,44.55) 75.53,44.99 75.53,45.62 75.78,45.87
  IN1 w0.14: v1(75.09,44.55) 75.2,44.55 76.23,43.52 76.23,42.73 76.26,42.71 76.26,39.73 76.04,39.52 75.36,39.52 75.15,39.31 75.15,39.14 73.63,37.62 72.86,37.62 72.61,37.87 72.23,37.87 71.97,37.62 71.09,37.62 70.32,36.86 70.32,35.46 69.35,34.48 69.35,30.85 68.67,30.17 68.67,28.73 68.54,28.59 v1(67.34,28.59)
M_A_DQ37: length 29.7
  TOP w0.102: U12.L53 76.16,47.48 76.16,45.8 76.07,45.71
  TOP w0.14: JDIM6.132 65.96,27.47 66.07,27.58 66.07,29.05 66.89,29.86 v1(67.39,29.86) ; 76.07,45.71 75.85,45.49 75.85,44.16 75.6,43.91 v1(75.09,43.91)
  IN1 w0.14: v1(67.39,29.86) 67.73,29.86 68.9,31.03 68.9,33.41 68.76,33.55 68.3,33.55 68.16,33.68 68.16,33.96 68.3,34.1 68.76,34.1 68.9,34.24 68.9,36.2 70.96,38.25 71.85,38.25 72.03,38.43 73.09,38.43 73.27,38.25 73.44,38.25 75.28,40.09 75.28,40.16 75.81,40.69 75.81,42.52 75.79,42.54 75.79,43.21 v1(75.09,43.91)
M_A_DQ38: length 31
  TOP w0.102: U12.R51 74.22,48.24 74.22,47.95 74.14,47.86 74.14,47.16 74.11,47.13 74.11,47.02
  TOP w0.14: v1(63.43,30.79) 63.08,31.14 63.08,32.11 62.66,32.54 JDIM6.143 ; 74.11,47.02 74.11,44.84 73.63,44.35 73.63,43.92 v1(73.19,43.49)
  IN1 w0.14: v1(63.43,30.79) 63.15,31.07 63.15,32.4 62.58,32.97 62.58,35.46 62.72,35.6 62.72,35.95 62.58,36.09 62.58,36.37 62.72,36.51 63.14,36.51 63.28,36.65 63.28,36.93 63.14,37.07 62.72,37.07 62.58,37.21 62.58,37.65 66.6,41.68 67.1,41.68 67.94,42.51 71.69,42.51 72.67,43.49 v1(73.19,43.49)
M_A_DQ39: length 30.6
  TOP w0.102: U12.R53 74.42,47.46 74.36,47.4 74.36,44.54 74.12,44.31 74.12,44.09
  TOP w0.14: v1(63.75,32.43) 63.26,32.92 JDIM6.141 ; v1(73.19,42.84) 74.12,43.76 74.12,44.09
  IN1 w0.14: v1(63.75,32.43) 63.02,33.15 63.02,33.36 63.21,33.55 63.91,33.55 64.05,33.69 64.05,34.01 63.91,34.15 63.16,34.15 63.02,34.29 63.02,34.57 63.16,34.71 64.06,34.71 64.2,34.85 64.2,35.13 64.06,35.27 63.3,35.27 63.16,35.41 63.16,35.69 63.3,35.83 63.99,35.83 64.18,36.01 64.18,36.27 63.85,36.6 63.76,36.68 63.76,37.23 63.36,37.63 63.36,37.81 66.79,41.23 67.5,41.23 68.33,42.06 68.82,42.06 69.05,41.83 69.45,41.83 69.69,42.06 69.96,42.06 70.2,41.83 70.6,41.83 70.83,42.06 71.09,42.06 71.32,41.83 71.74,41.83 72.75,42.84 v1(73.19,42.84)
M_A_DQ40: length 40.8
  TOP w0.14: U12.T47 74.13,50.75 v1(74.46,50.42) ; JDIM6.164 56.36,27.58 56.13,27.81 56.13,29.32 v1(55.78,29.66)
  IN1 w0.102: v1(74.46,50.42) 74.61,50.42 74.79,50.24 74.79,48.65 71.44,45.29
  IN1 w0.14: v1(55.78,29.66) 56.65,28.8 56.65,28.47 56.9,28.22 57.35,28.22 57.63,28.5 57.63,29.91 58.45,30.73 58.45,31.34 58.6,31.5 58.6,33.52 58.92,33.83 58.92,34.53 58.78,34.67 58.53,34.67 58.39,34.81 58.39,35.09 58.52,35.23 58.78,35.23 58.92,35.37 58.92,35.65 58.78,35.79 58.59,35.79 58.45,35.93 58.45,36.21 58.59,36.35 58.78,36.35 58.92,36.49 58.92,36.77 58.78,36.91 58.64,37.05 58.64,37.65 62.52,41.52 63.37,41.52 65.45,43.61 66.23,43.61 67.06,44.44 70.29,44.44 71.14,45.29 71.44,45.29
M_A_DQ41: length 39
  TOP w0.14: U12.T45 74.22,51.16 v1(74.43,51.16) ; v1(55.63,28.31) 55.63,27.58 55.76,27.46 JDIM6.166
  IN1 w0.102: v1(74.43,51.16) 74.99,50.6 74.99,48.46 72.79,46.25 72.79,46.13 71.41,44.76 71.24,44.76
  IN1 w0.14: v1(55.63,28.31) 56.53,27.42 57.75,27.42 58.08,27.74 58.08,28.93 58.51,29.36 58.77,29.36 59.31,29.9 59.31,30.89 59.5,31.08 59.5,32.89 59.77,33.16 59.77,33.52 59.52,33.77 59.52,36.84 62.32,39.65 62.32,39.85 65.63,43.16 66.42,43.16 67.25,43.99 70.48,43.99 71.24,44.76
M_A_DQ42: length 39.5
  TOP w0.14: U12.Y40 71.87,54.3 v1(71.52,53.95) ; v1(52.63,29.74) 52.76,29.62 JDIM6.176
  IN1 w0.14: v1(71.52,53.95) 71.29,53.95 70.91,53.57 70.36,53.57 69.89,53.11 69.89,51.77 69.56,51.44 67.42,51.44 66.68,50.7 66.26,50.7 63.72,48.16 62.5,48.16 51.72,37.38 51.72,32.09 51.96,31.85 51.96,30.42 v1(52.63,29.74)
M_A_DQ43: length 40.4
  TOP w0.14: v1(72.59,53.97) 72.6,53.97 U12.V41 ; v1(53.66,30.58) 53.05,31.19 53.05,31.78 52.67,32.16 52.67,33.48 52.46,33.7 JDIM6.177
  IN1 w0.102: v1(72.59,53.97) 72.05,53.42 72.05,53.16 71.73,52.85 71.27,52.85 71.04,52.62
  IN1 w0.14: v1(53.66,30.58) 52.92,31.31 52.92,32.28 52.76,32.45 52.76,33.01 52.16,33.6 52.16,36.99 62.88,47.71 63.91,47.71 65.47,49.28 68.91,49.28 69.31,49.67 69.31,49.96 71.04,51.7 71.04,52.62
M_A_DQ44: length 40
  TOP w0.14: JDIM6.163 56.66,33.09 v1(57.23,32.52) ; v1(74.35,49.76) 74.08,50.04 U12.T48
  IN1 w0.102: 71.21,46.18 71.72,46.18 73.83,48.29 73.83,49.63 73.96,49.76 v1(74.35,49.76)
  IN1 w0.14: v1(57.23,32.52) 57.12,32.41 56.87,32.41 56.68,32.6 56.68,32.93 56.06,33.56 56.06,36.2 56.37,36.52 56.57,36.52 56.93,36.16 57.08,36.16 57.3,36.38 57.3,36.58 56.96,36.91 56.96,37.11 57.16,37.31 57.53,37.31 57.75,37.53 57.75,38.23 62.62,43.1 62.82,43.1 63.15,42.77 63.35,42.77 63.55,42.97 63.55,43.16 63.22,43.5 63.22,43.69 63.42,43.89 63.61,43.89 63.95,43.56 64.14,43.56 64.34,43.76 64.34,43.95 64.01,44.29 64.01,44.48 64.32,44.8 66.17,44.8 66.89,45.52 66.89,46.19 67.02,46.32 67.47,46.32 67.61,46.18 67.61,45.63 67.75,45.49 68.03,45.49 68.16,45.63 68.16,46.18 68.3,46.32 68.58,46.32 68.72,46.18 68.72,45.63 68.86,45.49 69.14,45.49 69.28,45.63 69.28,46.18 69.42,46.32 69.7,46.32 69.84,46.18 69.84,45.89 69.98,45.75 70.26,45.75 70.4,45.89 70.4,46.18 70.54,46.32 71.02,46.32 71.16,46.18 71.21,46.18
M_A_DQ45: length 40.3
  TOP w0.14: v1(57.08,31.23) 56.57,31.74 56.57,32.57 56.29,32.85 56.29,33.31 56.06,33.55 JDIM6.165 ; v1(74.35,49.05) 74.26,49.05 U12.T50
  IN1 w0.102: v1(74.35,49.05) 74.35,48.51 71.54,45.7 71.37,45.7
  IN1 w0.14: 71.37,45.7 70.91,45.7 70.2,44.98 66.98,44.98 66.09,44.09 65.31,44.09 63.18,41.97 62.33,41.97 58.2,37.84 58.2,37.3 58.01,37.11 58.01,35.54 57.75,35.28 57.17,35.28 57.08,35.37 56.77,35.37 56.54,35.13 56.54,34.86 56.68,34.72 57.87,34.72 58.01,34.58 58.01,34.3 57.87,34.16 56.64,34.16 56.5,34.02 56.5,33.74 56.64,33.6 57.87,33.6 58.01,33.46 58.01,31.83 57.85,31.67 57.85,31.07 57.16,30.38 56.64,30.38 56.52,30.51 56.52,30.67 v1(57.08,31.23)
M_A_DQ46: length 40.5
  TOP w0.14: v1(53.62,31.93) 53.06,32.5 JDIM6.175 ; v1(72.61,52.53) 72.25,52.88 U12.Y42
  IN1 w0.14: v1(53.62,31.93) 53.62,32.32 53.2,32.74 53.2,33.27 52.61,33.87 52.61,34.33 52.75,34.47 53.36,34.47 53.5,34.61 53.5,34.89 53.36,35.03 52.75,35.03 52.61,35.17 52.61,35.45 52.75,35.59 53.36,35.59 53.5,35.73 53.5,36.01 53.36,36.15 52.75,36.15 52.61,36.29 52.61,36.73 63.14,47.27 64.13,47.27 65.69,48.83 69.31,48.83 69.43,48.96 69.9,48.96 70.22,48.64 71.7,48.64 72.01,48.96 72.01,49.85 72.1,49.94 72.1,52.31 72.32,52.53 v1(72.61,52.53)
M_A_DQ47: length 40.1
  TOP w0.14: v1(70.45,54) 70.58,54 70.88,54.3 U12.AB40 ; JDIM6.174 53.36,28.48 v1(53.24,28.59)
  IN1 w0.14: v1(70.45,54) 70.06,53.62 67.66,53.62 67.42,53.38 67.42,52.71 63.31,48.6 62.31,48.6 58.44,44.73 58.06,44.73 50.87,37.54 50.87,32.06 51.52,31.41 51.52,29.59 51.88,29.23 52.61,29.23 v1(53.24,28.59)
M_A_DQ48: length 31.2
  TOP w0.14: U12.V45 72.97,51.46 v1(72.59,51.09) ; v1(61.8,28.16) 61.8,27.95 61.76,27.91 JDIM6.146
  IN2 w0.102: v1(72.59,51.09) 73.5,50.18 73.5,47.12 72.73,46.35 72.73,45.35
  IN2 w0.14: 72.73,45.35 72.73,42.38 67.91,37.57 67.91,32.96 63.97,29.02 62.66,29.02 v1(61.8,28.16)
M_A_DQ49: length 32.7
  TOP w0.14: v1(60.48,28.59) 61.16,27.92 JDIM6.148 ; U12.V47 72.96,50.75 v1(72.61,50.39)
  IN2 w0.102: v1(72.61,50.39) 72.89,50.39 73.29,49.99 73.29,47.38 72.3,46.38 72.3,46.24 72.13,46.06
  IN2 w0.14: v1(60.48,28.59) 61.37,28.59 62.43,29.65 63.62,29.65 65.24,31.27 65.24,31.52 64.99,31.78 64.99,32.03 65.32,32.36 65.51,32.36 65.7,32.17 65.9,32.17 66.09,32.37 66.09,33.13 66.77,33.81 67.03,33.81 67.4,34.18 67.4,37.69 72.13,42.42 72.13,46.06
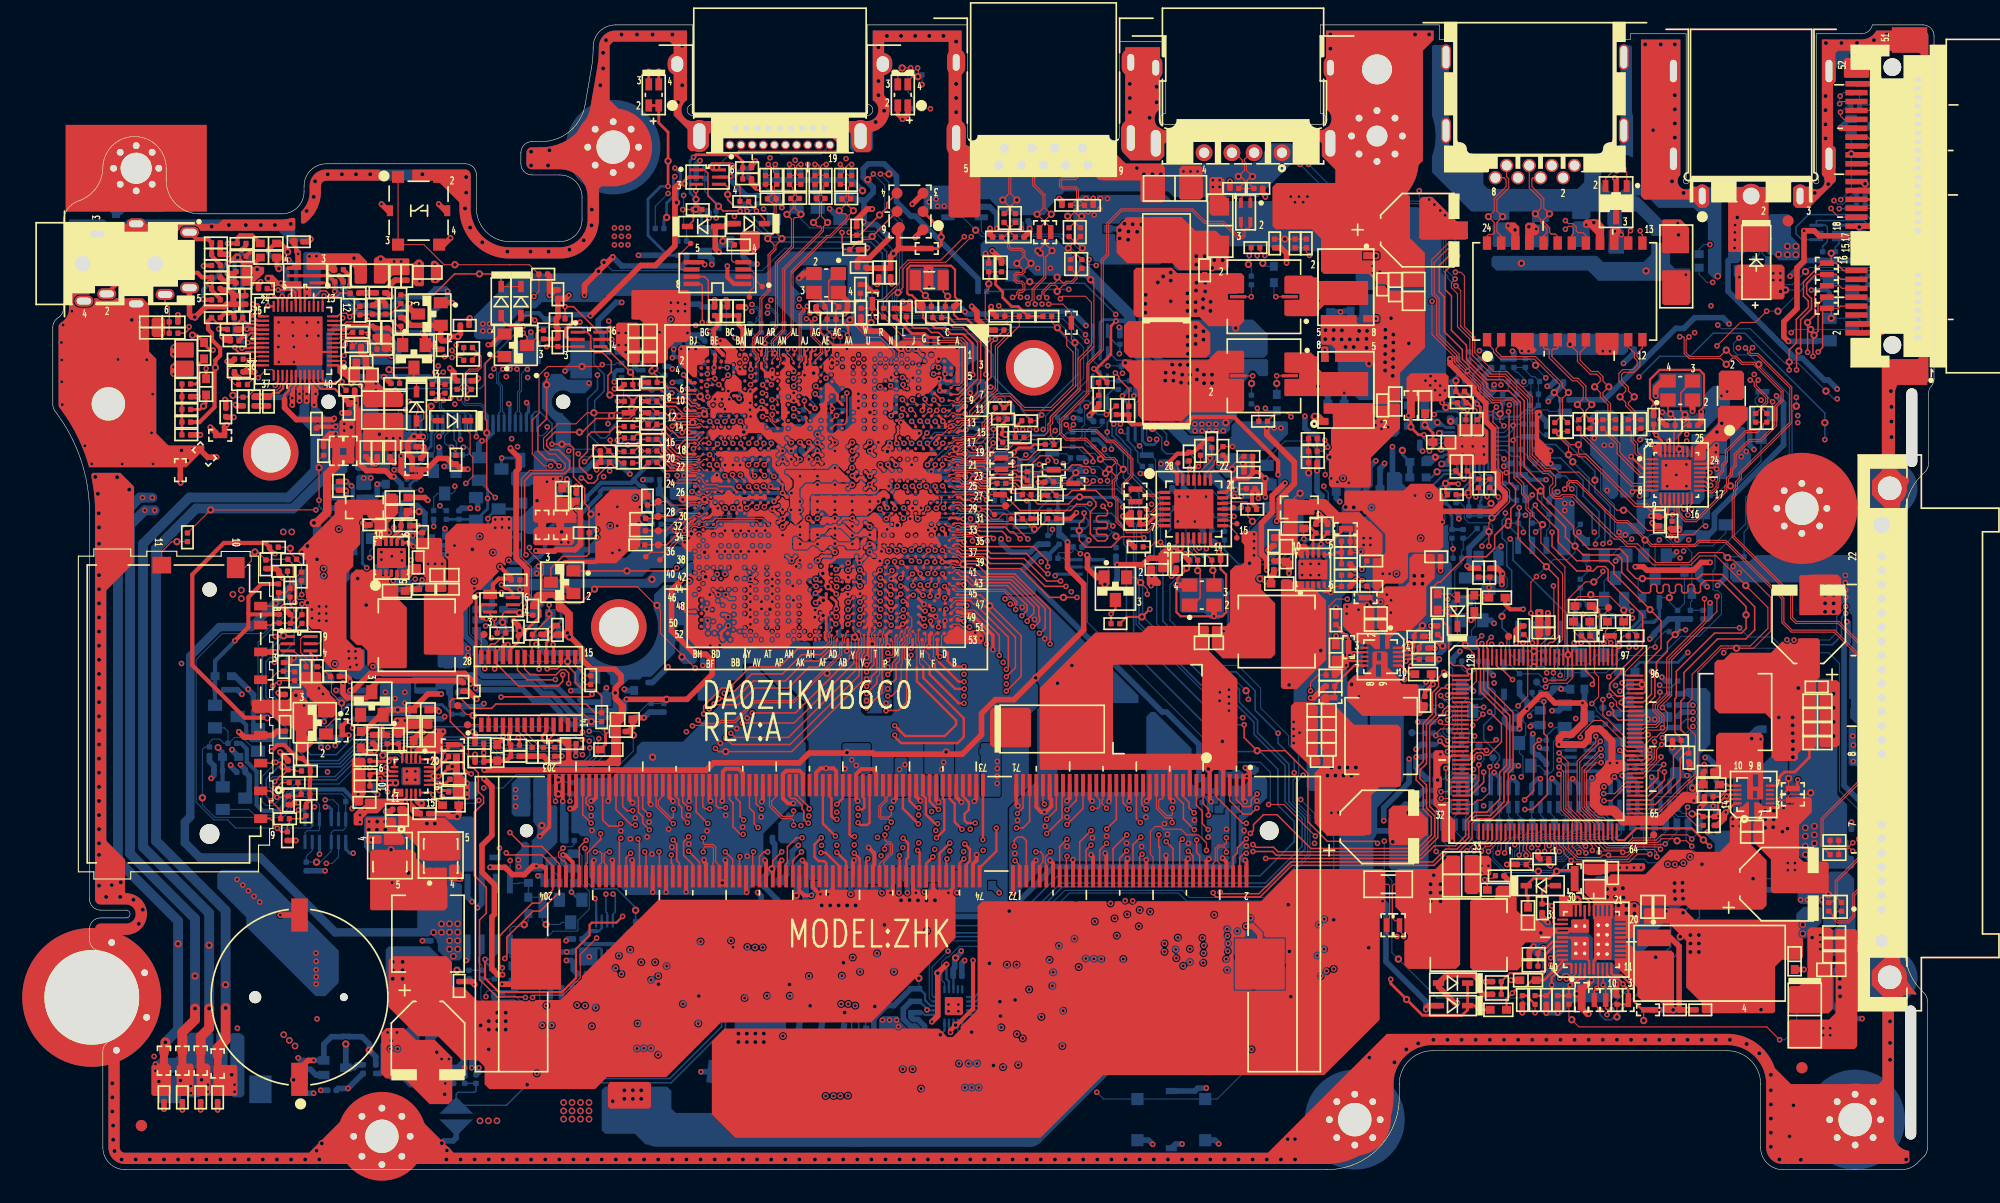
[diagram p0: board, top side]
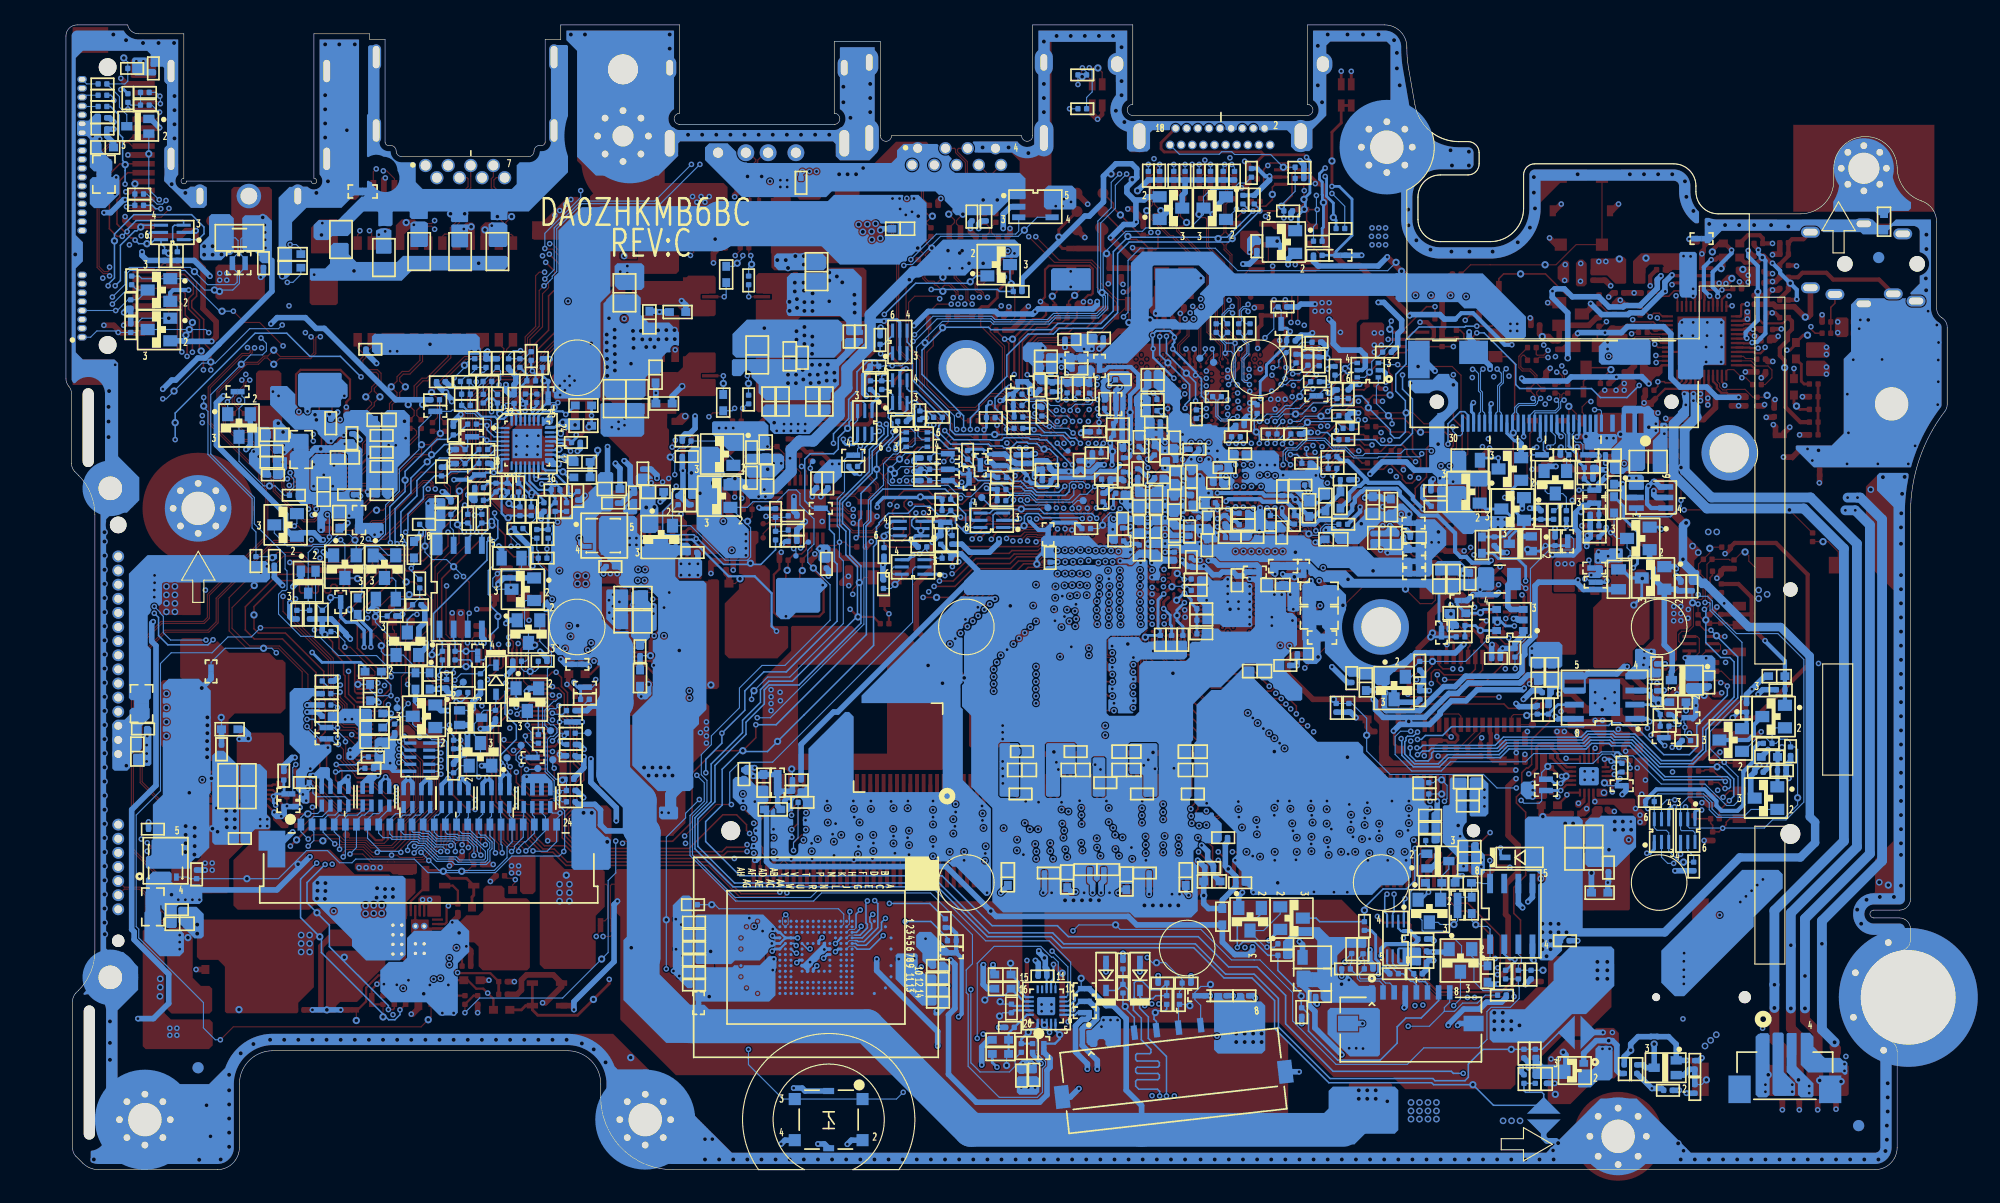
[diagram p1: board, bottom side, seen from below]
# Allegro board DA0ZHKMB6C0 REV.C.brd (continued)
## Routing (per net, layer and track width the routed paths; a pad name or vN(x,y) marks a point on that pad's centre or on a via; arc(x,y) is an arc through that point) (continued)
M_A_DQ50: length 32.9
  TOP w0.14: v1(57.18,28.65) 58.16,27.67 JDIM6.158 ; v1(70.47,49.76) 70.42,49.76 U12.AD48
  IN2 w0.14: v1(70.47,49.76) 69.19,49.76 68.61,49.17 67.78,49.17 64.86,46.25 64.86,41.55 59.42,36.11 58.15,36.11 56.27,34.23 56.27,28.86 56.48,28.65 v1(57.18,28.65)
M_A_DQ51: length 33.3
  TOP w0.14: U12.AD50 70.42,49.1 v1(70.42,49.1) ; JDIM6.160 57.56,27.45 56.73,28.27 56.73,29.51 v1(57.18,29.95)
  IN2 w0.14: v1(70.42,49.1) 69.37,49.1 67.03,46.76 66.61,46.76 65.37,45.52 65.37,44.62 65.51,44.48 65.99,44.48 66.13,44.34 66.13,44.06 65.99,43.92 65.51,43.92 65.37,43.78 65.37,43.5 65.51,43.36 65.99,43.36 66.13,43.23 66.13,42.95 65.99,42.81 65.51,42.81 65.37,42.67 65.37,41.42 59.61,35.66 58.33,35.66 57.69,35.02 57.69,30.47 v1(57.18,29.95)
M_A_DQ52: length 31.1
  TOP w0.14: v1(62.08,30.17) 61.85,30.17 61.18,30.84 61.18,33 60.86,33.32 JDIM6.149 ; v1(72.57,49.72) 72.89,50.04 U12.V48
  IN2 w0.102: v1(72.57,49.72) 72.74,49.89 72.93,49.89 73.09,49.73 73.09,47.71 71.53,46.15 71.53,45.9
  IN2 w0.14: 71.53,45.9 71.53,42.45 66.96,37.87 66.96,34.63 64.35,32.03 64.35,31.11 63.41,30.17 v1(62.08,30.17)
M_A_DQ53: length 32.7
  TOP w0.14: v1(72.53,49.07) 72.82,49.36 U12.V50 ; v1(62.14,31.46) 61.81,31.78 61.81,33.07 61.46,33.43 JDIM6.147
  IN2 w0.102: 72.83,47.93 72.83,48.97 72.73,49.07 v1(72.53,49.07)
  IN2 w0.14: 72.83,47.93 72.07,47.17 71.27,47.17 70.93,46.84 70.93,42.48 66.38,37.92 66.38,37.37 66.51,37.24 66.51,36.6 66.01,36.09 66.01,35.62 66.5,35.13 66.5,34.93 66.3,34.74 66.1,34.74 65.47,35.36 65.28,35.36 65.08,35.17 65.08,34.97 65.71,34.34 65.71,34.14 65.51,33.94 65.31,33.94 64.68,34.57 64.48,34.57 64.29,34.38 64.29,34.18 64.92,33.55 64.92,33.35 64.72,33.15 64.52,33.15 63.89,33.78 63.69,33.78 63.21,33.3 63.21,32.54 v1(62.14,31.46)
M_A_DQ54: length 32.6
  TOP w0.14: v1(71.51,52.4) 71.23,52.4 U12.AB44 ; JDIM6.157 58.46,32.68 58.66,32.47 v1(59.07,32.47)
  IN2 w0.102: v1(71.51,52.4) 71.08,52.4 70.88,52.2 70.88,48.98 70.52,48.62
  IN2 w0.14: v1(59.07,32.47) 59.07,31.81 58.89,31.62 58.55,31.62 58.29,31.88 58.29,33.91 58.41,34.03 58.58,34.03 58.94,33.67 59.19,33.67 59.37,33.86 59.37,34.8 66.64,42.07 66.64,45.73 69.53,48.62 70.52,48.62
M_A_DQ55: length 33
  TOP w0.14: v1(71.54,51.07) 71.61,51.07 U12.Y45 ; v1(58.91,31.15) 57.86,32.2 JDIM6.159
  IN2 w0.102: v1(71.54,51.07) 71.35,51.26 71.21,51.26 71.1,51.16 71.1,48.74 70.59,48.23
  IN2 w0.14: 70.59,48.23 70.52,48.16 69.71,48.16 67.78,46.24 67.78,44.98 67.64,44.84 67.29,44.84 67.15,44.7 67.15,44.42 67.29,44.28 67.64,44.28 67.78,44.14 67.78,43.86 67.64,43.72 67.29,43.72 67.15,43.58 67.15,43.3 67.29,43.16 67.64,43.16 67.78,43.02 67.78,42.58 59.97,34.76 59.97,33.69 59.62,33.35 59.62,32.96 59.77,32.81 59.77,31.57 59.21,31.01 59.05,31.01 v1(58.91,31.15)
M_A_DQ56: length 38.8
  TOP w0.102: U12.V52 72.96,46.76
  TOP w0.14: 72.96,46.76 72.96,46.51 72.77,46.31 72.77,43.92 66.46,37.62 v2(60.52,37.62) 59.88,37.62 v1(59.6,37.9) ; JDIM6.182 50.96,29.69 v1(51.08,29.81)
  IN2 w0.14: v1(51.08,29.81) 51.88,29.02 53.98,29.02 54.2,29.24 54.2,33.78 57.68,37.25 58.95,37.25 v1(59.6,37.9)
M_A_DQ57: length 38.2
  TOP w0.102: U12.W51 72.67,48.24 72.67,47.93 72.76,47.84 72.76,47.18 72.72,47.14 72.72,46.76
  TOP w0.14: 72.72,46.76 72.72,46.62 72.53,46.42 72.53,44.47 66.31,38.25 61.08,38.25 v1(60.51,38.82) ; JDIM6.183 50.66,32.39 52.04,31.01 v1(52.39,31.01)
  IN2 w0.14: v1(60.51,38.82) 60.51,38.92 60.16,39.27 59.84,39.27 58.37,37.8 57.45,37.8 57.12,37.46 53.34,33.69 53.34,32.55 53.16,32.37 53.16,30.36 53.02,30.22 52.51,30.22 52.39,30.33 v1(52.39,31.01)
M_A_DQ58: length 39
  TOP w0.102: 70.12,46.51 70.45,46.84 70.45,47.6 U12.AC53
  TOP w0.14: JDIM6.193 47.66,31.95 v1(48.42,31.19) ; v1(59.47,41.89) 59.53,41.83 61.65,41.83 63.15,43.33 66.13,43.33 68.01,45.21 68.83,45.21 70.12,46.51
  IN2 w0.14: v1(59.47,41.89) 59.3,42.06 56.61,42.06 55.61,41.07 55.41,41.07 55.1,41.38 54.91,41.38 54.71,41.18 54.71,40.98 55.02,40.67 55.02,40.47 54.82,40.28 54.62,40.28 54.31,40.59 54.12,40.59 53.92,40.39 53.92,40.19 54.23,39.88 54.23,39.68 54.03,39.49 53.83,39.49 53.52,39.8 53.33,39.8 53.13,39.6 53.13,39.4 53.44,39.09 53.44,38.89 53.05,38.51 51.64,38.51 48.86,35.73 48.86,31.63 v1(48.42,31.19)
M_A_DQ59: length 38.5
  TOP w0.102: 69.99,46.87 70.25,47.12 70.25,47.84 70.53,48.13 U12.AC51
  TOP w0.14: JDIM6.191 48.26,33.71 47.97,33.43 47.97,32.95 v1(48.42,32.51) ; v1(59.9,42.38) 61.43,42.38 63.01,43.97 65.88,43.97 67.68,45.77 68.89,45.77 69.99,46.87
  IN2 w0.14: v1(59.9,42.38) 59.59,42.7 54.58,42.7 53.8,41.93 53.8,41.73 54.05,41.49 54.05,41.29 53.85,41.09 53.65,41.09 53.41,41.33 53.21,41.33 52.11,40.23 52.11,40.04 52.54,39.61 52.54,39.41 52.34,39.22 52.14,39.22 51.72,39.64 51.52,39.64 51.32,39.44 51.32,39.25 51.37,39.2 51.37,39 51.17,38.81 50.97,38.81 50.93,38.85 50.73,38.85 50.53,38.65 50.53,38.46 50.58,38.41 50.58,38.21 50.38,38.02 50.18,38.02 50.14,38.06 49.94,38.06 49.74,37.86 49.74,37.67 49.79,37.62 49.79,37.42 49.59,37.23 49.39,37.23 49.35,37.27 49.15,37.27 48.95,37.07 48.95,36.88 49,36.83 49,36.63 48.8,36.44 48.6,36.44 48.56,36.48 48.36,36.48 47.97,36.09 47.97,32.95 v1(48.42,32.51)
M_A_DQ60: length 38.3
  TOP w0.102: U12.W53 72.48,47.02
  TOP w0.14: JDIM6.181 51.26,32.68 51.64,32.3 v1(52.16,32.3) ; 72.48,47.02 72.48,46.71 72.28,46.52 72.28,45.01 66.16,38.89 61.36,38.89 v1(60.98,39.26)
  IN2 w0.14: v1(52.16,32.3) 52.44,32.3 52.61,32.48 52.61,33.9 57.05,38.34 58.07,38.34 59.54,39.81 59.95,39.81 60.42,40.28 60.42,40.73 60.61,40.92 61.05,40.92 61.52,41.39 61.52,41.77 61.69,41.94 62.07,41.94 62.32,41.68 62.32,41.12 60.98,39.78 v1(60.98,39.26)
M_A_DQ61: length 38.8
  TOP w0.102: 72.04,46.13 72.04,46.63 72.16,46.75 72.16,47.83 72.3,47.97 72.3,48.19 71.99,48.5 U12.Y51
  TOP w0.14: v1(62.02,40.19) 66.67,40.19 72.04,45.56 72.04,46.13 ; JDIM6.180 51.56,28.05 v1(51.97,28.47)
  IN2 w0.14: v1(62.02,40.19) 62.02,39.54 59.18,36.7 57.9,36.7 54.75,33.55 54.75,33.25 54.89,33.11 55.17,33.11 55.31,32.97 55.31,32.69 55.17,32.55 54.89,32.55 54.75,32.41 54.75,32.13 54.89,31.99 55.2,31.99 55.36,31.83 55.36,31.6 55.2,31.43 54.92,31.43 54.75,31.27 54.75,30.33 55.21,29.87 55.21,28.6 54.55,27.94 53.1,27.94 52.58,28.47 v1(51.97,28.47)
M_A_DQ62: length 38.1
  TOP w0.102: 69.58,46.87 70.04,47.33 70.04,48.07 U12.AD52
  TOP w0.14: v1(49.27,30.23) 49.27,29.71 48.07,28.51 48.07,27.61 47.96,27.49 JDIM6.192 ; v1(58.54,41.01) 58.54,41.71 60.16,43.33 60.53,43.33 60.8,43.06 61.33,43.06 62.87,44.6 65.62,44.6 67.35,46.33 69.05,46.33 69.58,46.87
  IN2 w0.14: v1(49.27,30.23) 49.5,30.45 49.5,35.59 50.77,36.86 51.64,36.86 51.9,36.6 52.13,36.6 52.52,36.99 52.52,37.19 52.22,37.48 52.22,37.68 52.42,37.88 52.62,37.88 52.91,37.58 53.11,37.58 56.83,41.3 58.25,41.3 v1(58.54,41.01)
M_A_DQ63: length 39
  TOP w0.102: U12.AD51 70.04,48.48 69.75,48.19 69.75,47.94 69.84,47.85 69.84,47.48 69.45,47.09 69.25,46.89 69.05,46.89
  TOP w0.14: 69.05,46.89 67.02,46.89 65.37,45.24 62.73,45.24 v1(60.98,43.49) ; JDIM6.194 47.36,29.03 v1(47.97,29.64)
  IN2 w0.14: v1(60.98,43.49) 54.48,43.49 47.34,36.35 47.34,30.28 v1(47.97,29.64)
M_A_DQSN0: length 52.1
  TOP w0.102: U12.K38 76.89,55.13 v1(77.23,54.79) ; v1(105.55,28.57) 105.55,28.83 105.35,29.03 104.92,29.03 104.73,28.84 104.73,27.76 104.96,27.53 JDIM6.10
  IN2 w0.102: v1(105.55,28.57) 105.8,28.82 106.14,28.82 106.48,29.16 106.48,31.07 105.82,31.73 105.82,33.56 98.78,40.6 98.78,40.78 99.88,41.89 99.88,42.26 99.46,42.68 99.09,42.68 98.7,42.29 98.49,42.29 98.18,42.6 98.18,42.81 98.67,43.3 98.67,43.6 86.99,55.28 77.92,55.28 77.43,54.79 v1(77.23,54.79)
M_A_DQSN1: length 47.9
  TOP w0.102: v1(83.37,56.57) 82.79,57.15 81.88,57.15 81.82,57.1 U12.B34 ; v1(100.68,32.53) 100.68,31.96 100.57,31.85 100.19,31.85 99.46,32.57 99.46,33.23 99.57,33.34 99.75,33.34 99.86,33.45 JDIM6.27
  IN1 w0.102: v1(83.37,56.57) 83.21,56.4 83.21,56.21 83.89,55.52 89.08,55.52 89.41,55.2 92.06,55.2 92.9,54.36 93.07,54.36 94.94,52.49 95.84,51.58 95.84,48.51 97.55,46.8 97.55,43.1 98.85,41.81 100.16,41.81 100.49,41.48 100.49,41.02 100.16,40.69 98.53,40.69 98.42,40.57 98.42,39.44 99.91,37.94 99.91,32.27 100.22,31.96 100.58,31.96 100.68,32.06 v1(100.68,32.53)
M_A_DQSN2: length 41.4
  TOP w0.102: v1(89.72,28.59) 89.26,28.14 89.26,27.58 89.36,27.48 JDIM6.62 ; v1(78.7,53.63) 79.02,53.95 U12.F40
  IN1 w0.102: v1(89.72,28.59) 89.46,28.59 89.31,28.74 89.31,29.31 89.09,29.53 88.78,29.53 88.66,29.65 88.66,34.24 90.11,35.69 90.11,40.13 89.9,40.35 89.45,40.35 89.34,40.47 89.34,40.97 89.45,41.08 89.9,41.08 90.11,41.3 90.11,41.99 89.9,42.2 89.27,42.2 89.13,42.34 89.13,42.8 89.27,42.94 89.87,42.94 90.14,43.21 90.14,43.84 89.92,44.06 89.56,44.06 89.36,44.25 89.36,46.74 88.76,47.33 88.41,47.33 88.22,47.53 88.22,48.1 87.96,48.35 87.52,48.35 87.39,48.48 87.39,48.87 87.15,49.11 86.62,49.11 86.45,49.28 86.45,49.74 86.22,49.97 85.76,49.97 85.63,50.1 85.63,50.69 85.39,50.93 84.79,50.93 84.7,51.02 84.7,51.51 84.48,51.73 83.87,51.73 83.86,51.73 82.12,53.47 81.27,53.47 80.47,54.28 79.35,54.28 v1(78.7,53.63)
M_A_DQSN3: length 39.6
  TOP w0.102: v1(94.77,32.52) 94.37,32.93 94.37,33.27 94.46,33.36 JDIM6.45 ; v1(86.6,50.4) 86.6,50.72 86.71,50.83 86.71,51.12 85.62,52.21 81.43,52.21 81.11,52.53 80.82,52.53 U12.C43
  IN2 w0.102: v1(94.77,32.52) 94.33,32.52 94.23,32.62 94.23,33.93 93.17,34.99 90.49,34.99 90.21,35.28 90.21,42.9 85.82,47.28 84.91,47.28 84.78,47.41 84.78,47.89 84.91,48.02 85.94,48.02 86.17,48.26 86.17,48.9 85.94,49.14 84.17,49.14 83.91,49.39 83.91,49.67 84.12,49.87 86.08,49.87 v1(86.6,50.4)
M_A_DQSN4: length 30.1
  TOP w0.102: v1(75.09,45.85) 75.33,46.09 75.57,46.09 75.75,46.27 75.75,47.94 U12.M52 ; v1(66.63,32.28) 66.63,31.95 66.48,31.79 65.63,31.79 64.66,32.76 64.66,33.18 65.06,33.58 JDIM6.135
  IN1 w0.102: v1(75.09,45.85) 74.88,46.06 74.45,46.06 74.29,45.9 74.29,45.21 74.39,45.11 74.39,43.08 74.13,42.82 74.13,41.62 72.8,40.28 69.2,40.28 68.6,39.69 67.69,39.69 65.87,37.86 65.87,31.78 66.03,31.61 66.39,31.61 66.63,31.85 v1(66.63,32.28)
M_A_DQSN5: length 39.8
  TOP w0.102: v1(74.41,51.87) 74.11,52.17 U12.T44 ; v1(55.81,32.43) 55.81,31.74 55.71,31.64 55.59,31.64 54.46,32.77 54.46,33.22 54.86,33.61 JDIM6.169
  IN1 w0.102: v1(74.41,51.87) 74.27,52 73.71,52 73.6,51.89 73.6,48.86 71.82,47.08 68.55,47.08 68.36,47.27 67.97,47.27 67.87,47.17 67.52,47.17 67.4,47.28 67.18,47.28 67.06,47.17 66.76,47.17 66.64,47.28 66.34,47.28 66.13,47.08 66.13,45.83 65.86,45.56 64,45.56 55.3,36.86 55.3,31.87 55.38,31.79 55.87,31.79 56.04,31.95 56.04,32.2 v1(55.81,32.43)
M_A_DQSN6: length 32.4
  TOP w0.102: JDIM6.152 59.96,27.37 59.62,27.7 59.62,29.01 59.38,29.25 58.63,29.25 58.5,29.38 v1(58.5,29.86) ; U12.Y48 71.85,50.04 71.53,49.72 v1(71.51,49.72)
  IN2 w0.102: v1(58.5,29.86) 58.5,29.44 58.77,29.17 58.94,29.17 59.53,29.76 59.53,30.26 62.26,32.99 62.26,33.76 65.38,36.88 65.38,38.27 69.73,42.61 69.73,46.3 71.92,48.5 71.92,49.6 71.81,49.72 v1(71.51,49.72)
M_A_DQSN7: length 38.2
  TOP w0.102: v1(57.53,39.93) 57.54,39.93 57.59,39.98 59.86,39.98 60.11,40.23 61.38,40.23 63.16,42.01 66.64,42.01 70.94,46.32 70.94,47.2 71.2,47.46 71.2,47.82 71.33,47.96 71.33,48.26 U12.AA51 ; v1(50.07,28.59) 49.79,28.59 49.58,28.39 49.58,27.61 49.76,27.43 JDIM6.186
  IN2 w0.102: v1(57.53,39.93) 57.53,40.05 57.33,40.25 57.12,40.25 52.18,35.31 51.88,35.31 51.41,35.78 51.23,35.78 50.96,35.51 50.96,35.18 51.35,34.79 51.35,34.48 50.55,33.68 50.55,29.98 50.18,29.62 50,29.62 49.64,29.25 49.64,29.03 49.69,28.98 v1(50.07,28.59)
M_A_DQSP0: length 52
  TOP w0.102: U12.J38 77.6,55.06 v1(77.94,54.72) ; v1(105.55,29.86) 105.55,29.39 105.37,29.21 104.84,29.21 104.55,28.92 104.55,27.76 104.36,27.57 JDIM6.12
  IN2 w0.102: v1(77.94,54.72) 77.94,55.03 78,55.09 86.91,55.09 98.48,43.52 98.48,43.38 97.99,42.89 97.99,42.52 98.41,42.1 98.78,42.1 99.17,42.49 99.39,42.49 99.69,42.18 99.69,41.97 98.59,40.86 98.59,40.52 105.63,33.48 105.63,31.65 106.29,30.99 106.29,29.24 106.06,29.01 105.76,29.01 105.55,29.22 v1(105.55,29.86)
M_A_DQSP1: length 47.8
  TOP w0.102: JDIM6.29 99.26,32.49 100.1,31.64 100.61,31.64 100.68,31.57 v1(100.68,31.23) ; U12.C35 80.82,56.81 81.11,56.81 81.2,56.89 81.91,56.89 81.96,56.95 82.71,56.95 82.82,56.83 82.82,56.68 v1(82.71,56.57)
  IN1 w0.102: v1(100.68,31.23) 99.72,32.19 99.72,37.86 98.23,39.36 98.23,40.65 98.45,40.88 100.08,40.88 100.3,41.1 100.3,41.4 100.08,41.62 98.77,41.62 97.36,43.03 97.36,46.72 95.65,48.43 95.65,51.5 94.86,52.3 92.99,54.17 92.83,54.17 91.98,55.01 89.33,55.01 89.01,55.33 83.82,55.33 83,56.15 83,56.28 v1(82.71,56.57)
M_A_DQSP2: length 41.4
  TOP w0.102: JDIM6.64 88.76,27.38 89.06,27.68 89.06,28.37 88.83,28.59 v1(88.42,28.59) ; U12.D40 79.56,54.17 79.34,53.96 v1(79.34,53.63)
  IN1 w0.102: v1(79.34,53.63) 79.21,53.76 79.21,53.86 79.43,54.09 80.39,54.09 81.19,53.28 82.05,53.28 83.73,51.6 83.79,51.54 84.4,51.54 84.51,51.43 84.51,50.94 84.71,50.74 85.32,50.74 85.44,50.62 85.44,50.03 85.68,49.78 86.14,49.78 86.26,49.66 86.26,49.2 86.54,48.92 87.07,48.92 87.2,48.79 87.2,48.4 87.44,48.16 87.89,48.16 88.03,48.02 88.03,47.45 88.33,47.14 88.68,47.14 89.17,46.66 89.17,44.17 89.48,43.87 89.84,43.87 89.95,43.76 89.95,43.28 89.79,43.13 89.19,43.13 88.94,42.88 88.94,42.26 89.19,42.01 89.82,42.01 89.92,41.91 89.92,41.38 89.82,41.27 89.37,41.27 89.15,41.05 89.15,40.39 89.37,40.16 89.82,40.16 89.92,40.06 89.92,35.77 88.47,34.32 88.47,29.57 88.7,29.34 89.01,29.34 89.12,29.23 89.12,28.8 88.91,28.59 v1(88.42,28.59)
M_A_DQSP3: length 39.6
  TOP w0.102: v1(93.5,32.52) 94,32.52 94.16,32.68 94.16,33.27 93.86,33.57 JDIM6.47 ; U12.B44 81.2,52.03 85.55,52.03 86.53,51.05 86.53,50.9 86.4,50.77 86.22,50.77 v1(86.12,50.88)
  IN2 w0.102: v1(93.5,32.52) 93.94,32.52 94.04,32.62 94.04,33.85 93.09,34.8 90.42,34.8 90.02,35.2 90.02,42.82 85.74,47.09 84.83,47.09 84.59,47.33 84.59,47.97 84.83,48.21 85.86,48.21 85.98,48.34 85.98,48.82 85.86,48.95 84.09,48.95 83.72,49.31 83.72,49.75 84.04,50.06 86,50.06 86.12,50.18 v1(86.12,50.88)
M_A_DQSP4: length 30
  TOP w0.102: JDIM6.137 64.46,32.68 65.54,31.59 66.45,31.59 66.63,31.41 v1(66.63,31.01) ; U12.N53 75.55,47.53 75.55,46.35 75.48,46.29 75.3,46.29 v1(75.09,46.5)
  IN1 w0.102: v1(75.09,46.5) 74.85,46.25 74.37,46.25 74.1,45.98 74.1,45.13 74.2,45.03 74.2,43.16 73.94,42.9 73.94,41.7 72.72,40.48 69.12,40.48 68.52,39.88 67.62,39.88 65.68,37.94 65.68,31.7 65.95,31.42 66.39,31.42 66.63,31.18 v1(66.63,31.01)
M_A_DQSP5: length 39.7
  TOP w0.102: JDIM6.171 54.26,32.69 v1(55.81,31.13) ; v1(74.43,52.58) 74.13,52.88 U12.T42
  IN1 w0.102: v1(55.81,31.13) 55.81,31.51 55.72,31.6 55.3,31.6 55.11,31.79 55.11,36.93 63.92,45.75 65.78,45.75 65.94,45.91 65.94,47.16 66.26,47.47 66.72,47.47 66.83,47.36 66.98,47.36 67.1,47.47 67.48,47.47 67.6,47.36 67.79,47.36 67.9,47.46 68.43,47.46 68.62,47.27 71.74,47.27 73.41,48.94 73.41,51.97 73.63,52.2 74.05,52.2 v1(74.43,52.58)
M_A_DQSP6: length 32.3
  TOP w0.102: JDIM6.154 59.36,27.56 59.42,27.63 59.42,28.9 59.27,29.05 58.68,29.05 58.5,28.87 v1(58.5,28.59) ; v1(71.51,50.39) 71.64,50.39 U12.Y47
  IN2 w0.102: v1(71.51,50.39) 71.87,50.03 71.87,49.92 72.11,49.68 72.11,48.42 69.92,46.23 69.92,42.53 65.57,38.19 65.57,36.8 62.45,33.68 62.45,32.91 59.72,30.18 59.72,29.68 59.02,28.98 58.89,28.98 v1(58.5,28.59)
M_A_DQSP7: length 38.1
  TOP w0.102: U12.AB52 71.02,47.53 70.77,47.28 70.77,46.39 66.57,42.19 63.09,42.19 61.31,40.41 60.04,40.41 59.78,40.16 58.36,40.16 58.08,40.44 v1(58.04,40.44) ; v1(48.8,28.59) 49.23,28.59 49.38,28.44 49.38,27.65 49.16,27.43 JDIM6.188
  IN2 w0.102: v1(48.8,28.59) 49.12,28.59 49.44,28.92 49.44,29.33 49.92,29.81 50.1,29.81 50.36,30.06 50.36,33.76 51.16,34.56 51.16,34.71 50.77,35.11 50.77,35.59 51.15,35.97 51.49,35.97 51.95,35.5 52.1,35.5 57.04,40.44 v1(58.04,40.44)
M_A_DRAMRST#: length 75.6
  TOP w0.102: U12.P41 75.17,53.59 v1(75.47,53.9) ; v1(103.76,28.72) 103.76,29.38 103.03,30.12 101.98,30.12 101.47,30.63 99.91,30.63 99.66,30.87 99.16,30.87 98.72,30.43 98.72,28.7 98.73,28.69 98.73,28.36 98.96,28.13 JDIM6.30
  IN1 w0.102: v1(103.76,28.72) 103.79,28.72 104.69,29.62 104.69,35.59 103.87,36.41 103.87,42.13 100.45,45.54 100.45,48.05 99.36,49.14 99.36,52.78 99.16,52.98 98.52,52.98 97.86,53.64 97.86,54.74 93.95,58.65 91.74,58.65 91.28,59.11 87.52,59.11 85.97,57.56 81.96,57.56 81.13,56.73 79.44,56.73 78.98,56.26 74.44,56.26 74.05,55.87 74.05,55.14 73.95,55.04 73.95,55.01 73.95,54.59 74.2,54.33 74.58,54.33 75.01,53.9 v1(75.47,53.9)
  BOTTOM w0.102: v1(103.76,28.72) 103.76,29.45 103.35,29.86 C321.2
M_A_ODT0: length 34.9
  TOP w0.216: v1(69.09,28.52) 69.52,28.52 70.76,27.28 JDIM6.116 ; U12.T41 74.07,53.59 v1(74.41,53.93)
  IN2 w0.102: v1(74.41,53.93) 73.7,53.22 73.7,46.68 73.97,46.41 73.97,44.38
  IN2 w0.203: v1(69.09,28.52) 68.79,28.22 68.14,28.22 67.91,28.45 67.91,28.76 68.12,28.96 68.32,28.96 68.52,29.17 68.52,29.57 68.32,29.78 68.09,29.78 67.89,29.98 67.89,30.38 68.55,31.04 68.55,37.32 70.51,39.28 71.58,39.28 73.65,41.35 73.65,43.46 73.97,43.78 73.97,44.38
M_A_ODT1: length 34.1
  TOP w0.216: v1(69.12,29.86) 68.51,29.25 68.51,28.13 68.88,27.76 69.39,27.76 69.56,27.58 JDIM6.120 ; v1(74.43,53.24) 74.54,53.24 U12.P42
  IN2 w0.102: 74.59,44.38 74.59,46.68 73.95,47.33 73.95,52.75 v1(74.43,53.24)
  IN2 w0.203: 74.59,44.38 74.59,42.52 74.26,42.19 74.26,41.1 71.83,38.67 70.76,38.67 70.08,37.99 70.08,35.98 69.17,35.06 69.17,31.95 69.4,31.72 69.73,31.72 69.91,31.55 69.91,31.29 69.73,31.12 69.33,31.12 69.16,30.94 69.16,30.68 69.33,30.51 69.74,30.51 69.93,30.32 69.93,30.05 69.74,29.86 v1(69.12,29.86)
M_A_RAS#: length 30.8
  TOP w0.216: v1(72.08,28.48) 72.56,28.01 JDIM6.110 ; U12.M45 75.93,51.46 v1(76.27,51.79)
  IN1 w0.102: 78.93,46.31 78.32,46.92 78.32,47.68 77.43,48.57 77.43,50.76 76.4,51.79 v1(76.27,51.79)
  IN1 w0.203: 78.93,46.31 79.77,45.46 79.77,37.97 74.9,33.09 74.9,31.29 v1(72.08,28.48)
M_A_WE#: length 34.4
  TOP w0.102: U12.H51 77.85,48.51 77.85,47.54 77.96,47.42 77.96,45.56 78.29,45.24
  TOP w0.216: v1(75.73,39.09) 75.73,38.94 76.29,38.38 81.37,38.38 81.93,38.94 81.93,40.61 78.29,44.26 78.29,45.24 ; v1(72.1,29.97) 71.85,29.97 71.66,30.16 JDIM6.113
  IN2 w0.203: v1(72.1,29.97) 71.92,30.15 71.92,34.52 72.48,35.08 72.48,35.94 72.99,36.45 72.99,37.24 74.84,39.09 v1(75.73,39.09)
MAIND: length 124.7
  IN1 w0.102: v1(124.43,28.63) 124.22,28.42 122.51,28.42 118.49,24.4 118.49,22.91 112.94,17.36 112.94,16.28 108.14,11.48 107.53,11.48 106.67,10.62 88.43,10.62 v1(87.24,11.81)
  BOTTOM w0.102: PQ26.2 126.58,47.55 125.53,46.5 125.53,45.4 125.9,45.03 125.9,42.13 126.34,41.69 126.34,39.43 126.1,39.19 126.1,35.81 125.29,35 125.29,33.22 124.35,32.28 124.35,28.7 v1(124.43,28.63) 124.83,28.22 129.09,28.22 130.59,26.72 136.64,26.72 137.86,27.94 143.15,27.94 143.48,27.61 144.58,27.61 145.68,28.7 147.57,28.7 150.09,26.18 v2(152.92,26.18) PC182.1 158.06,26.18 158.21,26.33 PQ34.4 ; PU16.11 80.2,16.79 79.95,17.04 79.95,18.67 80.41,19.13 80.56,19.13 81.53,20.09 85.72,20.09 87.24,18.57 v1(87.24,11.81)
MAINON: length 124.9
  TOP w0.102: U18.77 143.04,36.85 143.21,37.02 143.21,38.24 143.91,38.94 144.26,38.94 144.61,39.28 144.88,39.28 145.22,39.62 145.22,41.13 v1(144.77,41.58) 144.77,41.83 145.6,42.66 145.6,45.85 148.5,48.75 v1(151.71,48.75) ; PR65.1 136.36,13.74 v2(136.62,13.49) 137.25,12.85 154.14,12.85 v1(155.31,11.68)
  IN2 w0.102: v1(144.77,41.58) 144.77,40.46 144.36,40.06 142.69,40.06 142.01,40.73 142.01,45.59 140.83,46.77 140.83,54.18 142.01,55.36 v1(142.01,56.74)
  BOTTOM w0.102: v1(142.01,56.74) 141.8,56.54 141.09,56.54 140.45,57.18 140.45,59.79 139.21,61.03 139.21,63.02 137.46,64.78 137.46,66.78 136.37,67.87 PR93.2 ; v1(155.31,11.68) 155.77,11.68 156.84,12.75 156.84,15.04 162.65,20.85 162.65,21.64 162.88,21.87 162.88,31.9 160.7,34.09 160.7,45.54 159.73,46.51 156.05,46.51 154.63,47.93 152.53,47.93 v1(151.71,48.75) ; v1(144.77,41.58) 145,41.81 R368.1
MBCLK: length 132.8
  TOP w0.14: v1(139.16,14.38) 139.15,14.38 PR66.1 ; v1(144.89,36.45) 144.38,35.94 144.38,35.23 143.2,34.05 U18.70
  IN1 w0.14: v1(70.22,6.63) 70.22,5.36 72.48,3.1 109.34,3.1 119.12,12.88 138.17,12.88 139.16,13.87 v1(139.16,14.38) ; v1(146.65,27.58) 146.07,28.17 146.07,35.82 145.44,36.45 v1(144.89,36.45)
  BOTTOM w0.14: v1(70.22,6.63) 70.22,10.19 71.85,11.81 71.85,13.74 72.64,14.53 72.64,15.01 73.12,15.49 73.12,16.82 72.97,16.97 72.41,16.97 71.62,16.18 70.8,16.18 PC190.1 70.19,15.66 PR179.2 71.18,15.66 71.44,15.39 72.46,15.39 72.61,15.55 PD12.1 ; v1(146.65,27.58) 148.1,26.14 148.1,22.68 v2(146.37,20.96) 146.22,20.8 146.22,19.53 140.17,13.49 139.61,13.49 139.16,13.94 v1(139.16,14.38) ; R378.1 142.44,37.13 143.15,36.43 144.86,36.43 v1(144.89,36.45)
MBCLK2: length 156.1
  TOP w0.14: v1(126.05,81.64) 125.24,80.82 125.24,79.17 125.79,78.62 125.79,75.52 127.15,74.17 127.15,72.91 128.97,71.08 130.44,71.08 132.34,69.19 132.34,63.24 134.09,61.49 134.09,60.54 136.77,57.86 136.77,57.22 138.16,55.83 140.97,55.83 141.63,55.17 141.63,53.96 142.4,53.18 v2(142.97,53.18) 147.93,53.18 148.31,53.56 150.14,53.56 153.07,50.64 153.07,48.56 152.25,47.75 149.73,47.75 146.71,44.73 146.71,42.43 146.43,42.15 146.43,39.58 147.14,38.86 R386.1 146.82,37.46 146.37,37.01 146.37,35.1 144.13,32.85 U18.67 ; U7.8 58.25,79.7 58.41,79.54 v1(58.41,76.23)
  IN2 w0.14: v1(126.05,81.64) 125.82,81.86 125.32,81.86 120.24,86.94 113.73,86.94 112.44,85.65 100.96,85.65 97.12,81.81 95.67,81.81 94.17,80.32 91.41,80.32 90.54,79.45 85.92,79.45 85.31,78.84 81.63,78.84 79.83,77.04 74.67,77.04 74.54,77.16 73.75,77.16 72.51,75.92 69.4,75.92 69,75.51 67.4,75.51 66.84,76.07 62.5,76.07 62.09,76.48 60.14,76.48 59.33,75.67 58.74,75.67 58.41,76 v1(58.41,76.23)
MBDATA: length 141.4
  TOP w0.14: v1(140.2,14.4) 139.77,14.4 139.67,14.5 PR67.1 ; U18.69 143.54,33.65 144.95,35.06 v1(144.95,35.79)
  IN1 w0.14: v1(144.95,35.79) 145.46,35.28 145.46,27.89 v1(145.89,27.46) ; v1(140.2,14.4) 139.74,14.86 138.19,14.86 136.82,13.49 118.91,13.49 109.13,3.71 74.3,3.71 74.16,3.85 74.16,4.33 74.02,4.47 73.74,4.47 73.6,4.33 73.6,3.85 73.46,3.71 72.92,3.71 72.71,3.92 72.71,4.12 73.68,5.09 73.68,5.28 73.48,5.48 73.28,5.48 72.31,4.51 72.11,4.51 71.92,4.71 71.92,4.91 72.89,5.88 72.89,6.07 72.64,6.32 72.3,6.32 71.36,5.38 71.16,5.38 70.83,5.72 v1(70.83,6.63)
  BOTTOM w0.14: R384.1 142.68,36.11 142.9,35.88 144.55,35.88 144.65,35.79 v1(144.95,35.79) ; v1(70.83,6.63) 70.83,7.04 71.03,7.24 72.71,7.24 72.99,7.52 72.99,7.96 72.85,8.1 71,8.1 70.86,8.24 70.86,8.52 71,8.66 72.85,8.66 72.99,8.8 72.99,9.08 72.85,9.22 71,9.22 70.86,9.35 70.86,9.63 71,9.77 72.85,9.77 72.99,9.91 72.99,10.31 72.86,10.44 71.72,10.44 71.62,10.54 71.62,10.82 72.48,11.68 72.48,13.64 73.19,14.35 73.19,14.81 73.68,15.29 73.68,16.21 PR180.2 ; PR180.2 74.68,16.12 PD11.1 ; PR180.2 PC191.1 ; v1(145.89,27.46) 147.51,25.83 147.51,24 v2(146.63,23.11) 145.51,22 145.51,20.07 140.2,14.76 v1(140.2,14.4)
MBDATA2: length 161.6
  TOP w0.14: v1(59.02,76.23) 58.95,76.3 58.95,80.01 58.61,80.35 U7.7 ; v1(125.72,82.37) 124.7,81.35 124.7,78.98 125.16,78.52 125.16,75.4 126.78,73.78 126.78,72.92 128.98,70.71 128.98,70.42 129.32,70.08 130.96,70.08 132,69.04 132,62.59 133.53,61.06 133.53,60.33 136.05,57.81 136.05,56.9 137.64,55.31 140.75,55.31 141.11,54.95 141.11,53.74 142.96,51.89 143.57,51.89 143.71,52.03 143.71,52.51 143.85,52.65 144.13,52.65 144.27,52.51 144.27,52.03 144.41,51.89 144.69,51.89 144.83,52.03 144.83,52.51 144.97,52.65 145.25,52.65 145.39,52.51 145.39,52.03 145.52,51.89 145.8,51.89 145.94,52.03 145.94,52.51 146.08,52.65 146.36,52.65 146.5,52.51 146.5,52.03 146.64,51.89 146.92,51.89 147.06,52.03 147.06,52.51 147.2,52.65 147.48,52.65 147.62,52.51 147.62,52.03 147.76,51.89 148.05,51.89 148.19,52.04 148.19,52.61 148.58,53 149.95,53 152.29,50.66 v2(152.29,49.91) 152.29,48.67 151.89,48.28 149.46,48.28 146.01,44.83 146.01,42.48 145.89,42.35 145.89,39.36 146.46,38.79 R383.1 146.46,37.91 145.76,37.21 145.76,35.25 143.76,33.25 U18.68
  IN2 w0.14: v1(125.72,82.37) 125.52,82.58 125.36,82.58 120.07,87.86 113.91,87.86 112.23,86.18 100.73,86.18 100.73,86.16 96.92,82.35 95.47,82.35 93.97,80.85 91.13,80.85 90.26,79.98 85.61,79.98 85,79.38 81.35,79.38 79.59,77.62 75.53,77.62 75.43,77.72 72.97,77.72 71.75,76.51 69.16,76.51 68.7,76.05 67.62,76.05 67.06,76.61 62.75,76.61 62.32,77.04 59.83,77.04 v1(59.02,76.23)
MDI_0+: length 4.5
  TOP w0.102: R96.1 142.33,66.69 142.19,66.55 142.19,65.67 142.54,65.33 142.54,64.57 143.19,63.91 U11.1
MDI_0+_C: length 10.1
  TOP w0.102: U8.12 142.97,73.94 142.49,73.46 142.49,73.15 142.74,72.9 142.74,72.26 142.22,71.74 141.29,71.74 141.1,71.55 141.1,71.02 141.71,70.41 141.71,70.05 v2(142.23,69.53) 141.71,69.01 141.71,68.83 142.37,68.17 142.37,67.62 142.52,67.47 R96.2
MDI_0-: length 4.5
  TOP w0.102: U11.2 143.25,63.51 142.29,64.47 142.29,65.23 141.95,65.57 141.95,66.44 R95.1
MDI_0-_C: length 10.1
  TOP w0.102: R95.2 142,67.47 142.13,67.6 142.13,68.07 141.47,68.73 141.47,69.02 v2(140.96,69.53) 141.47,70.04 141.47,70.31 140.86,70.92 140.86,71.65 141.19,71.98 142.12,71.98 142.5,72.36 142.5,72.8 142.24,73.05 142.24,73.47 141.7,74.02 U8.11
MDI_1+: length 6.9
  TOP w0.102: U11.4 143.28,62.71 143.2,62.63 142.85,62.63 140.94,64.54 140.94,65.35 139.95,66.34 139.95,66.55 140.09,66.69 R94.1
MDI_1+_C: length 9.7
  TOP w0.102: U8.8 137.89,74.07 137.37,73.55 137.37,72.82 138.37,71.82 138.95,71.82 139.42,71.35 139.42,70.96 v2(139.95,70.43) 139.42,69.91 139.42,69.61 140.1,68.93 140.1,67.6 140.23,67.47 R94.2
MDI_1-: length 6.9
  TOP w0.102: U11.5 143.28,62.31 143.2,62.39 142.75,62.39 140.69,64.44 140.69,65.25 139.7,66.24 139.7,66.4 R93.1
MDI_1-_C: length 9.7
  TOP w0.102: U8.7 136.62,74.07 137.13,73.56 137.13,72.72 138.27,71.58 138.85,71.58 139.18,71.25 139.18,70.94 v2(138.67,70.43) 139.18,69.92 139.18,69.51 139.86,68.83 139.86,67.58 139.75,67.47 R93.2
MDI_2+: length 9.1
  TOP w0.102: U11.6 143.36,61.91 143.2,61.75 142.08,61.75 137.67,66.16 137.67,66.44 137.92,66.69 R92.1
MDI_2+_C: length 9.7
  TOP w0.102: R92.2 137.89,67.85 137.89,68.31 v2(138.41,68.84) 137.89,69.37 137.89,70.51 137.18,71.22 136.76,71.22 134.83,73.15 134.83,73.22 134.83,73.22 134.83,73.73 134.93,73.84 135.25,73.84 135.35,73.94 U8.6
MDI_2-: length 9.1
  TOP w0.102: U11.7 141.98,61.51 137.42,66.06 137.42,66.52 R91.1
MDI_2-_C: length 9.7
  TOP w0.102: U8.5 134.08,73.94 134.18,73.84 134.49,73.84 134.59,73.73 134.59,73.46 134.59,73.46 134.59,73.05 136.66,70.97 137.08,70.97 137.65,70.41 137.65,69.37 v2(137.12,68.84) 137.65,68.31 137.65,67.87 R91.2
MDI_3+: length 14.4
  TOP w0.102: U11.9 144.62,59.93 144.77,59.77 144.77,59.59 144.66,59.47 143.84,59.47 143.41,59.91 142.4,59.91 137.93,64.38 137.34,64.38 137.22,64.5 v2(137.22,65.23) 136.49,65.23 135.5,66.22 135.5,66.37 135.56,66.44 R100.1
MDI_3+_C: length 12.5
  TOP w0.102: U8.2 130.27,74.32 129.81,73.86 129.81,73.66 130.31,73.16 133.35,73.16 135.75,70.76 135.75,70.49 v2(136.32,69.93) 135.79,69.4 135.79,67.67 R100.2
MDI_3-: length 14.4
  TOP w0.102: R99.1 135.25,66.28 135.25,66.12 136.32,65.06 v2(136.32,64.33) 137.05,64.33 137.24,64.14 137.83,64.14 142.3,59.66 143.31,59.66 143.74,59.23 144.76,59.23 145.02,59.49 U11.10
MDI_3-_C: length 12.5
  TOP w0.102: U8.1 129,74.37 129.57,73.8 129.57,73.56 130.21,72.92 133.25,72.92 135.51,70.66 135.51,70.4 v2(135.04,69.93) 135.54,69.43 135.54,67.67 R99.2
MIC1_INT_L: length 10.2
  TOP w0.203: U9.24 19.4,77.67 v1(19.35,77.72)
  TOP w0.254: C345.2 v1(13.78,72.09)
  IN1 w0.254: v1(19.35,77.72) 19.35,76.48 18.41,75.54 17.03,75.54 16.63,75.13 16.63,74.93 v1(13.78,72.09)
MIC1_INT_L_C: length 2.4
  TOP w0.254: R511.1 13.25,68.4 v2(13.55,68.7) 13.78,68.94 C345.1
MIC1_INT_R: length 12.1
  TOP w0.203: U9.23 20.26,78.31 19.96,78.61 v1(19.63,78.61)
  TOP w0.254: v1(14.42,73.74) 14.14,73.74 13.61,74.27 C344.2 12.95,75.08 v2(12.56,75.08)
  IN1 w0.254: v1(19.63,78.61) 19.3,78.61 18.81,78.13 18.81,76.68 18.18,76.05 16.7,76.05 15.97,75.31 15.97,75.03 14.67,73.74 v1(14.42,73.74)
MIC1_INT_R_C: length 3
  TOP w0.254: R510.1 12.87,70.69 13.12,70.94 13.12,72.47 C344.1
MIC1_INTL1: length 4.6
  TOP w0.254: R510.2 C347.2 R511.2 R428.1 C342.1
MIC2-VREFO: length 15.5
  TOP w0.203: v1(17.34,75.01) 17.44,75.11 17.62,75.11 17.77,75.26 18.27,75.26 18.36,75.17 U9.29
  TOP w0.381: v1(17.34,75.01) 17.17,75.01 R68.2 ; v1(26.71,79.53) 26.71,80.4 R30.2
  IN2 w0.381: v1(17.34,75.01) 17.8,75.46 17.92,75.46 20.13,77.67 24.45,77.67 26.31,79.53 v1(26.71,79.53)
MIC2_MIC_RING2_MIC:
  vias: v1(30.7,81.71) v1(31.33,81.71) v2(29.48,81.94)
MIC2_MIC_SLEEVE_MIC:
  vias: v1(9.85,76.28) v1(9.85,75.31) v1(10.86,73.99) v1(10.86,73.36)
MX0: length 22.7
  TOP w0.102: v1(137.27,28.55) 137.18,28.55 136.66,29.07 U18.54 136.66,31.35 135.65,32.36 135.65,35.41 v1(135.47,35.59)
  BOTTOM w0.102: RP6.1 135.73,35.84 v1(135.47,35.59) ; CP9.7 129.33,31.85 129.07,31.6 CN17.20 129.07,29.49 129.53,29.03 129.53,28.07 130.67,26.92 135.64,26.92 v1(137.27,28.55)
MX1: length 23.5
  TOP w0.102: v1(135.47,36.22) 135.88,35.81 135.88,32.41 137.06,31.23 U18.55 137.06,29.33 137.86,28.53 137.86,28.52 v1(137.89,28.5)
  BOTTOM w0.102: v1(135.47,36.22) 135.73,36.47 RP6.2 ; CP9.1 131.72,31.98 132.07,31.62 CN17.17 132.07,30.28 131.89,30.1 131.49,30.1 130.88,29.49 130.88,28.87 131.07,28.68 131.07,27.78 131.39,27.46 134.2,27.46 134.48,27.74 135.88,27.74 137.1,28.96 137.44,28.96 137.84,28.55 137.86,28.55 137.89,28.52 v1(137.89,28.5)
MX2: length 23.3
  TOP w0.102: v1(137.86,29.11) 137.76,29.11 137.46,29.41 U18.56 137.46,31.12 136.08,32.5 136.08,36.25 v1(135.47,36.86)
  BOTTOM w0.102: RP6.3 135.73,37.11 v1(135.47,36.86) ; CP10.7 133.01,31.7 133.07,31.64 CN17.16 133.07,30.77 132.2,29.9 131.57,29.9 131.08,29.4 131.08,28.96 131.27,28.77 131.27,27.88 131.49,27.66 133.93,27.66 134.2,27.94 135.78,27.94 137,29.16 137.83,29.16 137.86,29.13 v1(137.86,29.11)
MX3: length 26.9
  TOP w0.102: v1(135.47,37.49) 136.29,36.68 136.29,32.69 137.86,31.12 U18.57 137.86,29.68 137.97,29.57 138.02,29.57 138.47,29.12 v1(138.47,28.73)
  BOTTOM w0.102: RP6.4 135.73,37.74 v1(135.47,37.49) ; v1(138.47,28.73) 138.47,29.16 138.12,29.52 137.64,29.52 137.49,29.36 136.9,29.36 135.68,28.14 134.08,28.14 133.8,27.86 131.61,27.86 131.48,28 131.48,28.64 132.34,29.5 132.38,29.5 132.93,30.05 133.87,30.05 134,30.18 134.89,30.18 135.07,30.36 CN17.14 135.07,31.67 134.61,32.13 CP10.3
MX4: length 20.2
  TOP w0.102: v1(139.08,28.55) 139.08,28.85 138.26,29.68 U18.58 138.26,31.12 137.1,32.28 137.1,36.75 138.78,38.43 v1(138.78,38.99)
  BOTTOM w0.102: v1(138.78,38.99) 138.78,38.53 138.62,38.38 RP6.6 ; v1(139.08,28.55) 139.17,28.64 140.89,28.64 142.07,29.82 CN17.7 142.07,31.53 141.57,32.03 141.06,32.03 140.91,32.18 CP6.5
MX5: length 23.6
  TOP w0.102: v1(145.03,29.31) 144.95,29.24 142.35,29.24 141.66,28.55 v1(141.21,28.55) 141.01,28.75 139.59,28.75 138.66,29.68 U18.59 138.66,31.12 137.33,32.45 137.33,36.67 138.97,38.3 138.98,38.3 139.18,38.51 v1(139.18,38.53)
  BOTTOM w0.102: v1(145.03,29.31) 146.07,30.36 CN17.3 146.07,31.47 145.63,31.9 145,31.9 144.59,32.31 CP7.5 ; RP6.7 138.56,37.74 139.18,38.37 v1(139.18,38.53)
MX6: length 25.3
  TOP w0.102: v1(147.41,29.11) 146.93,29.59 v2(146.09,29.59) 145.91,29.77 144.67,29.77 144.34,29.44 142.26,29.44 141.78,28.96 139.79,28.96 139.06,29.68 U18.60 139.06,31.12 138.88,31.3 138.76,31.3 137.53,32.54 137.53,36.14 v1(139.23,37.85)
  BOTTOM w0.102: v1(147.41,29.11) 146.9,29.62 146.9,30.38 147.07,30.55 CN17.2 147.07,31.61 146.9,31.78 146.14,31.78 145.41,32.51 CP7.3 ; v1(139.23,37.85) 138.92,37.53 138.92,37.48 138.9,37.46 138.9,37.36 138.65,37.11 RP6.8
MX7: length 24.1
  TOP w0.102: v1(139.28,37.24) 139.03,37.24 137.74,35.94 137.74,32.62 138.85,31.51 139.07,31.51 139.46,31.12 U18.61 139.46,29.62 139.92,29.16 141.7,29.16 142.18,29.64 144.19,29.64 144.67,30.12 147.03,30.12 v1(147.41,29.74)
  BOTTOM w0.102: v1(139.28,37.24) 138.52,36.47 RP6.9 ; v1(147.41,29.74) 148.07,30.4 CN17.1 148.07,31.68 147.71,32.04 v1(147.36,32.04) 146.56,32.04 146.19,32.41 CP7.1
MY0: length 20.6
  TOP w0.102: v1(144.59,28.83) 144.39,29.03 142.43,29.03 141.54,28.14 140.07,28.14 v1(139.91,28.3) 139.4,28.3 139.2,28.09 137.15,28.09 136.3,28.94 136.3,29.5 136.26,29.54 U18.53
  BOTTOM w0.102: v1(144.59,28.83) 144.59,29.92 145.07,30.4 CN17.4 145.07,31.45 144.62,31.9 144.19,31.9 143.81,32.28 CP7.7 143.81,33.25 144.11,33.55 146.66,33.55 146.99,33.88 146.99,34.5 R394.1
MY1: length 17
  TOP w0.102: U18.52 135.86,29.13 136.11,28.88 136.11,28.85 137.07,27.89 139.72,27.89 141.6,27.89 142.51,28.8 144.01,28.8 144.26,28.55 v1(144.26,28.14)
  BOTTOM w0.102: v1(144.26,28.14) 144.07,28.33 CN17.5 144.07,31.69 143.86,31.9 142.97,31.9 142.51,32.36 CP6.1
MY2: length 15.8
  TOP w0.102: U18.51 135.46,29.24 135.91,28.79 135.91,28.47 v1(136.57,27.81) 136.69,27.69 139.64,27.69 139.64,27.69 140.27,27.69 141.8,27.69 142.51,28.4 v1(143.65,28.4)
  BOTTOM w0.102: v1(143.65,28.4) 143.07,28.98 CN17.6 143.07,31.42 142.59,31.9 142.33,31.9 141.72,32.51 CP6.3
MY3: length 11.1
  TOP w0.102: v1(135.5,28.63) 135.22,28.91 135.22,29.49 135.06,29.65 U18.50
  BOTTOM w0.102: v1(135.5,28.63) 135.87,28.63 136.81,29.57 137.4,29.57 137.56,29.72 139.87,29.72 140.02,29.87 140.68,29.87 141.07,30.26 CN17.8 141.07,31.51 140.12,32.46 CP6.7
MY4: length 11
  TOP w0.102: v1(134.89,28.63) 134.99,28.73 134.99,29.34 134.66,29.67 U18.49
  BOTTOM w0.102: CP11.1 138.83,32.36 139.16,32.03 139.54,32.03 140.07,31.5 CN17.9 140.07,30.21 139.81,29.94 137.49,29.94 137.32,29.77 136.72,29.77 135.99,29.03 135.3,29.03 v1(134.89,28.63)
MY5: length 9.4
  TOP w0.102: U18.48 134.26,29.49 v1(134.59,29.16)
  BOTTOM w0.102: v1(134.59,29.16) 134.66,29.24 135.9,29.24 136.64,29.97 137.24,29.97 137.41,30.15 138.8,30.15 139.07,30.42 CN17.10 139.07,31.73 138.9,31.9 138.27,31.9 138.04,32.13 CP11.3
MY6: length 9.7
  TOP w0.102: v1(134.18,28.63) 134.18,29.26 133.86,29.58 U18.47
  BOTTOM w0.102: CP11.5 137.23,32.06 137.38,31.9 137.76,31.9 138.07,31.59 CN17.11 138.07,30.44 137.99,30.35 137.32,30.35 137.23,30.25 136.63,30.25 135.94,29.57 134.42,29.57 134.18,29.33 v1(134.18,28.63)
MY7: length 10.5
  TOP w0.102: U18.43 132.26,28.73 132.5,28.48 v1(132.5,28.27)
  BOTTOM w0.102: v1(132.5,28.27) 132.5,29.05 133.09,29.64 134.1,29.64 134.23,29.77 135.86,29.77 136.55,30.45 136.82,30.45 137.07,30.71 CN17.12 137.07,31.58 136.44,32.21 CP11.7
MY8: length 10.1
  TOP w0.102: U18.42 131.86,29.68 131.92,29.62 131.92,28.33 v1(131.88,28.3)
  BOTTOM w0.102: v1(131.88,28.3) 132.2,28.61 132.2,29.03 133.01,29.85 134.02,29.85 134.15,29.97 135.69,29.97 136.07,30.35 CN17.13 136.07,31.74 135.91,31.9 135.73,31.9 135.4,32.23 CP10.1
MY9: length 6.4
  TOP w0.102: v1(131.49,29.24) 131.46,29.26 U18.41
  BOTTOM w0.102: CP10.5 133.8,31.93 134.07,31.65 CN17.15 134.07,30.75 133.57,30.25 132.84,30.25 132.29,29.7 132.25,29.7 131.78,29.24 v1(131.49,29.24)
MY10: length 6.5
  TOP w0.102: U18.40 131.06,29.68 130.69,29.32 130.69,28.63 130.57,28.51 v1(130.57,28.5)
  BOTTOM w0.102: v1(130.57,28.5) 130.57,28.51 130.67,28.61 130.67,29.64 131.07,30.04 CN17.18 131.07,31.65 130.93,31.79 CP9.3
MY11: length 6.4
  TOP w0.102: U18.39 130.66,29.68 130.27,29.29 130.27,28.8 v1(129.96,28.5)
  BOTTOM w0.102: v1(129.96,28.5) 129.96,29.17 130.07,29.28 CN17.19 130.07,31.71 130.12,31.75 CP9.5
MY12: length 6.8
  TOP w0.102: v1(129.12,28.63) 129.99,29.49 130.14,29.49 130.26,29.61 U18.38
  BOTTOM w0.102: v1(129.12,28.63) 128.87,28.88 128.87,29.11 128.07,29.91 CN17.21 128.07,31.74 128.03,31.78 CP8.1
MY13: length 7.2
  TOP w0.102: v1(128.49,28.65) 128.49,28.73 128.86,29.09 129.27,29.09 129.86,29.68 U18.37
  BOTTOM w0.102: CP8.3 127.25,31.93 127.07,31.75 CN17.22 127.07,30.27 127.85,29.49 127.95,29.49 128.49,28.95 v1(128.49,28.65)
MY14: length 7.6
  TOP w0.102: U18.36 129.46,29.68 129.07,29.3 128.45,29.3 v1(127.83,28.68)
  BOTTOM w0.102: CP8.5 126.43,32.13 126.07,31.77 CN17.23 126.07,30.51 126.84,29.74 126.84,29.66 v1(127.83,28.68)
MY15: length 9.5
  TOP w0.102: v1(127.19,28.68) 128.02,29.5 128.88,29.5 129.06,29.68 U18.35
  BOTTOM w0.102: v1(127.19,28.68) 127.17,28.65 125.92,28.65 125.07,29.5 CN17.24 125.07,31.55 124.76,31.86 v1(124.76,32.09) 125.44,32.09 125.64,32.29 CP8.7
NB670BST: length 2
  TOP w0.203: PR40.1 122.03,44.58 121.26,45.36 PU8.10
NB670BST_S: length 2.4
  TOP w0.381: PC49.1 123.41,42.98 124.1,43.66 v1(124.14,43.66) 124.06,43.75 124.06,44.09 123.98,44.17 PR40.2
NB670EN: length 9.4
  TOP w0.203: PU8.13 121.35,46.56 121.56,46.76 v1(122.27,46.76) 122.44,46.93 PC43.2 122.44,48.2 v2(123.18,48.95)
  IN1 w0.254: v1(123.51,43.87) 123.51,45.52 v1(122.27,46.76)
  BOTTOM w0.254: v1(123.51,43.87) 123.51,43.71 123.21,43.41 PR147.2 PR148.2
NB670ENLDO: length 6.3
  TOP w0.203: PU8.12 121.48,46.16 121.63,46.3 122.5,46.3 122.9,46.71 PR39.2 122.9,47.14 123.18,47.42 124.5,47.42 124.81,47.12 v2(125.01,47.12) 125.01,47.69 PR37.1
NB670PG: length 1.4
  TOP w0.203: PU8.4 116.62,46.56 PR38.2
NB670SW: length 2.5
  BOTTOM w0.508: PR146.2 117.57,42.67 v1(117.47,42.57) 117.09,42.57 116.81,42.85 v3(116.81,43.66)
NB670VOUT: length 4.5
  TOP w0.203: PU8.7 117.05,45.36 115.3,43.61 PC48.1 PR42.1
NB671BST: length 1.7
  TOP w0.203: PR47.1 150.59,34.65 150.68,34.55 PU10.10
NB671BST_S: length 2.3
  TOP w0.102: v2(147.46,34.34) 147.77,34.65 PR47.2
  TOP w0.508: PC61.1 148.43,35.72 PR47.2
NB671EN: length 4.6
  TOP w0.203: PU10.13 150.89,33.35 v1(150.33,32.79)
  BOTTOM w0.254: PC176.2 149.61,34.4 149.58,34.38 PR163.2 150.32,33.81 150.54,33.59 v1(150.54,33.58) 150.54,32.99 v1(150.33,32.79)
NB671FB: length 5.5
  TOP w0.203: PU10.12 150.61,33.75 149.78,32.93 149.78,32.09 PR53.1 PR52.2 148.14,32 v2(147.46,32)
NB671PG: length 3
  TOP w0.102: v2(156.12,35.2) PR49.2 155.18,33.35 PU10.4
NB671SW: length 2.4
  BOTTOM w0.508: PR157.2 153.23,39.62 152.8,39.19 v2(152.8,38.79) 152.85,38.74 v1(153.61,38.74)
NBSWON#: length 249.1
  TOP w0.102: v1(141.14,43.79) 141.4,44.05 U18.95 ; SW6.1 SW6.3 33.37,83.23 35.18,81.42 v2(36.17,81.42) 41.1,81.42 41.1,81.42 42.87,81.42 D15.1 43.72,79.01 v1(43.27,78.56)
  IN1 w0.102: v1(24.71,35.79) 25.09,35.41 25.09,26.58 28.46,23.21 28.46,17.83 30.57,15.72 37.61,15.72 38.4,16.51 38.4,17.91 37.99,18.31 37.99,21.75 38.45,22.21 42.26,22.21 42.92,21.56 42.92,20.73 46.71,16.94 49.78,16.94 50.48,16.25 60.03,16.25 61.79,18.01 64.23,18.01 65.78,19.56 72.8,19.56 73.52,18.85 76.15,18.85 77.02,17.98 79.14,17.98 79.9,17.22 88.26,17.22 89.58,15.9 89.82,15.9 90.23,15.49 94.38,15.49 94.77,15.11 106.15,15.11 106.32,15.11 108.69,17.49 108.69,20.48 111.79,23.57 111.79,31.96 113.11,33.27 121.83,33.27 122.44,33.88 123.58,33.88 124.52,34.82 126,34.82 126.45,35.27 126.45,35.73 127.67,36.95 127.67,37.51 128.82,38.66 128.82,40.08 129.07,40.34 132.96,40.34 133.16,40.54 134.94,40.54 135.96,41.55 135.96,41.86 137.1,43 138.75,43 138.95,42.8 138.95,42.09 139.21,41.83 139.56,41.83 139.97,42.24 140.15,42.24 140.55,42.65 141.37,42.65 141.6,42.88 141.6,43.33 v1(141.14,43.79)
  IN2 w0.102: v1(24.71,35.79) 22.77,37.72 22.77,40.08 22.29,40.56 22.29,50.72 23.34,51.77 25.36,51.77 27.19,53.61 27.19,55.13 29.45,57.38 30.85,57.38 31.51,58.04 31.51,58.76 33.65,60.89 33.65,62.49 34.38,63.23 34.38,64.06 35.14,64.82 35.14,67.18 33.98,68.35 33.98,69.52 36.62,72.16 36.62,73.41 38.07,74.85 38.07,76.91 38.6,77.44 42.16,77.44 v1(43.27,78.56)
NOVRP1: length 2.5
  TOP w0.102: R112.1 103.22,63.45 v1(103.04,63.27) 102.62,62.86 U13.25
NOVRP2: length 3.4
  TOP w0.102: U13.24 103.12,62.75 104.08,63.7 v1(104.08,64.01) 104.23,64.16 R113.1
NOVRP3: length 2.5
  TOP w0.102: R133.1 106.95,61.27 106.87,61.19 v1(106.39,61.19) 106.34,61.19 105.59,60.44 U13.20
NOVRP4: length 4.1
  TOP w0.102: v2(107.89,58.34) 107.49,58.74 R144.1 107.49,59.82 107.24,60.08 105.99,60.08 105.86,59.94 U13.19
PCBEEP: length 3.1
  TOP w0.14: U9.12 25.62,76.77 25.9,77.06 26.39,77.06 v1(26.71,76.73) 26.71,76.77 C40.1
PCBEEP_EC: length 178.3
  TOP w0.14: U18.118 132.26,47.37 v1(132.23,47.4) ; v1(44.42,71.53) v2(44.42,70.61) 44.42,67.56 43.63,66.78 43.63,64.67 44.42,63.88 44.97,63.88 v1(45.53,63.32) ; D16.2 42.94,76.84 v1(43.35,76.43)
  IN2 w0.14: v1(44.42,71.53) 44.42,71.58 44.48,71.64 44.48,72.97 44.94,73.43 44.94,74.84 v1(43.35,76.43) ; v1(45.53,63.32) 44.54,62.33 44.26,62.33 43.83,61.9 43.83,57.18 44.47,56.54 44.47,53.98 43.68,53.19 42.71,53.19 41.67,52.15 41.67,50.17 42.01,49.83 42.01,47.56 40.74,46.29 40.74,41.49 39.27,40.01 39.27,32.04 38.32,31.09 38.32,27.48 43.77,22.03 49.38,22.03 50.39,21.03 61.63,21.03 61.85,21.25 64.77,21.25 65.21,20.81 73.44,20.81 76.55,17.7 88.43,17.7 89.09,17.04 90.39,17.04 90.59,16.84 94.35,16.84 96.05,15.14 105.83,15.14 108.11,17.42 108.11,19.09 110.32,21.29 110.32,22.97 115.18,27.83 115.18,29.74 119,33.56 121.34,33.56 122.21,34.42 122.26,34.42 123.07,34.42 124.21,35.56 125.52,35.56 126.26,36.3 126.26,36.47 127.98,38.18 130.02,38.18 130.8,38.96 130.8,45.95 132.04,47.19 132.04,47.2 v1(132.23,47.4)
PCH_DISP_ON: length 43.7
  TOP w0.102: v1(23.94,60.22) v2(23.94,63.17) 23.94,63.87 R111.2
  TOP w0.14: v1(42.31,75.29) 42.66,74.93 Q8.3 42.82,74.17 43.48,74.83 43.48,75.21 43.79,75.52 R31.2
  IN1 w0.102: v1(27.7,70.56) 27.7,66.17 25.52,63.98 25.52,61.8 v1(23.94,60.22)
  BOTTOM w0.14: v1(42.31,75.29) 41.65,75.29 38.8,72.44 38.8,70.64 38.45,70.28 32,70.28 31.18,69.47 28.79,69.47 v1(27.7,70.56) ; v1(23.94,60.22) 23.94,59.69 24.88,58.75 27.7,58.75 27.96,59.01 U21.3
PCH_DISP_ON_C: length 79.1
  TOP w0.14: v1(39.79,60.48) 39.03,61.24 v2(39.03,66.29) 39.03,67.39 38.9,67.51 38.9,72.57 39.49,73.15 Q8.1 ; U12.N30 v1(74.97,58.55) ; v1(48.51,42.77) 48.28,42.55 40.34,42.55 v1(40.32,42.52)
  IN1 w0.14: v1(39.79,60.48) 41.8,58.47 41.8,54.86 40.89,53.95 40.89,51.61 40.4,51.13 40.4,48.08 39.95,47.63 39.95,46.66 39.31,46.03 39.31,44.48 40.32,43.47 v1(40.32,42.52)
  IN2 w0.102: v1(74.97,58.55) 74.87,58.55 74.31,57.99 74.31,57.23 73.8,56.71 72.96,56.71 72.74,56.49
  IN2 w0.14: v1(48.51,42.77) 49.6,41.68 51.57,41.68 54.15,44.26 59.2,44.26 62.42,47.49 63.35,47.49 65.42,49.56 66.49,49.56 68.38,51.45 69.04,51.45 69.97,52.38 69.97,54.15 70.66,54.85 70.66,54.91 71.61,55.85 72.1,55.85 72.74,56.49
PCH_DPST_PWM: length 233.5
  IN1 w0.14: v1(36.92,65) 36.26,64.34 35.14,64.34 31.33,60.53 26.84,60.53 25.16,58.85 22.98,58.85 22.42,58.29 19.7,58.29 19.32,57.91 19.32,51.84 15.56,48.08 11.98,48.08 8.88,44.98 8.88,30.91 21.45,18.34 21.45,13.23 22.93,11.76 23.69,11.76 27.25,8.2 32.22,8.2 33.21,7.21 42.08,7.21 v1(43.53,8.66)
  BOTTOM w0.14: v1(43.53,8.66) 44.42,8.66 44.6,8.85 55.23,8.85 59.5,13.12 59.5,15.67 62.07,18.24 64.63,18.24 67.35,20.96 79.04,20.96 80.03,21.95 85.91,21.95 90.39,26.44 108.58,26.44 111.67,29.53 111.67,31.31 110.18,32.8 110.18,36.02 108.59,37.62 106.11,37.62 v2(105.2,38.53) 102.84,40.89 102.84,40.89 96.56,47.17 96.56,56.06 96.31,56.31 96.31,57.83 96.06,58.08 96.06,58.21 95.21,59.06 93.46,59.06 92.83,59.69 91.51,59.69 90.69,58.88 90.05,58.88 R304.1 89.2,58.89 89.2,58.19 88.26,57.25 86.19,57.25 85.82,57.63 85.82,58.88 85.62,59.08 Q29.3 ; v1(36.92,65) 37.25,65 37.46,64.8 37.46,64.49 37.28,64.31 R277.1
PCH_DPST_PWM_C: length 11.5
  TOP w0.14: v1(76.5,58.6) 76.5,58.73 U12.M30
  BOTTOM w0.14: Q29.4 86.1,59.08 85.79,59.39 83.32,59.39 v2(83.28,59.44) 81.62,59.44 81.22,59.03 76.93,59.03 v1(76.5,58.6)
PCH_LVDS_BLON: length 88.7
  TOP w0.14: v1(107.15,40.03) 107.15,38.86 v2(108.32,37.69) 110.85,37.69 112.89,35.66 112.89,31.29 114.64,29.55 118.96,29.55 v1(119.14,29.36) ; v1(132.38,33.27) 133.19,34.09 133.19,38.13 v1(133.7,38.64)
  IN1 w0.14: v1(128.3,37.08) 128.3,37.68 128.79,38.18 133.23,38.18 v1(133.7,38.64) ; v1(132.38,33.27) 132.15,33.05 131.66,33.05 129.33,30.72 124.99,30.72 123.7,29.42 121.35,29.42 120.91,28.98 119.52,28.98 v1(119.14,29.36)
  BOTTOM w0.14: Q34.2 135.09,39.78 134.33,39.01 R377.2 v1(133.7,38.64) ; R535.1 v1(128.3,37.08) ; v1(107.15,40.03) 105.32,40.03 97.21,48.15 97.21,56.01 97.25,56.05 97.25,57.91 96.81,58.35 96.81,60.15 95.72,61.24 90.13,61.24 89.62,60.73 R300.2 88.28,58.99 88.28,58.21 87.85,57.78 Q29.6
PCH_LVDS_BLON_C: length 8.9
  TOP w0.14: v1(77.79,58.57) 77.6,58.76 U12.J30
  BOTTOM w0.14: Q29.1 83.19,57.78 v2(83.02,57.94) 83,57.96 83,58.8 82.77,59.03 81.75,59.03 81.37,58.65 77.87,58.65 v1(77.79,58.57)
PCH_SLP_S0#: length 41.3
  TOP w0.14: v1(77.96,65.35) 78.31,64.99 U12.G18
  IN2 w0.14: v1(95.6,76.95) 95.58,76.94 92.57,76.94 91.26,75.62 91.26,70.24 89.96,68.94 86.88,68.94 85.41,70.41 v1(84.34,70.41)
  BOTTOM w0.14: v1(77.96,65.35) 78.42,65.81 78.82,65.81 79.34,66.32 81.18,66.32 82.02,67.16 82.58,67.16 82.67,67.26 84.37,67.26 85.64,68.53 85.64,69.42 84.65,70.41 v1(84.34,70.41) ; v1(95.6,76.95) 94.33,78.21 94.32,78.21 92.78,79.76 88,79.76 v2(87.87,79.89) 87.34,80.42 Q18.1
PCH_SLP_S0_N: length 161.5
  TOP w0.14: v1(128.69,35.76) 128.69,34.85 127.5,33.65 U18.28
  IN1 w0.14: v1(128.69,35.76) 128.69,36.45 129.25,37.01 133.95,37.01 134.61,37.67 134.61,39.07 135.65,40.11 135.65,40.59 136.47,41.4 138.27,41.4 139.08,40.59 140.35,40.59 142.13,42.37 145.18,42.37 146.37,43.56 146.37,44.5 148.4,46.53 149.5,46.53 149.93,46.96 153.48,46.96 154.19,47.68 v1(155.97,47.68)
  IN2 w0.14: v1(142.66,71.32) 142.1,70.76 137.66,70.76 134.94,73.48 133.21,73.48 132.93,73.2 131.06,73.2 130.62,73.63 129.07,73.63 126.64,76.07 126.64,80.95 126.38,81.2 125.21,81.2 120.01,86.41 114.01,86.41 112.72,85.12 101.16,85.12 97.32,81.28 95.88,81.28 94.38,79.78 91.96,79.78 v1(91.38,79.2) ; v1(159.38,65.68) 162.05,63.01 162.05,57.27 162.76,56.56 162.76,51.57 v1(161.26,50.06)
  BOTTOM w0.14: Q18.3 84.29,80.09 84,79.79 R230.1 85.23,79.02 85.41,79.2 v1(91.38,79.2) ; v1(161.26,50.06) 160.87,49.68 160.87,48.06 160.04,47.22 156.43,47.22 v1(155.97,47.68) ; v1(159.38,65.68) v2(159.38,67.21) 159.38,68.07 152.19,75.26 149.34,75.26 147.26,73.18 144.52,73.18 v1(142.66,71.32)
PCIE_CLKREQ3#: length 5.5
  TOP w0.102: U12.BE3 60,72.16 v1(60.65,72.16)
  BOTTOM w0.102: v1(60.65,72.16) 60.24,72.16 60.11,72.29 60.11,72.85 TP22.1 58.99,73.97 58.54,73.97 58.06,74.45 R237.2
PCIE_CLKREQ_CR#: length 2.3
  TOP w0.102: U12.BG3 58.92,71.65 v1(58.87,71.6)
  BOTTOM w0.102: R239.2 58.28,71.6 v1(58.87,71.6)
PCIE_CLKREQ_LAN#: length 122
  TOP w0.102: v1(59.55,71.17) 59.01,71.17 U12.BG5 ; v1(126.15,80.75) 126.15,80.75 126.64,80.75 126.96,80.42 126.96,75.86 127.9,74.92 127.9,73.51 129.61,71.8 130.8,71.8 133.06,69.53 133.06,64.31 134.27,63.1 135.12,63.1 135.46,62.76 137.25,62.76 140.68,59.33 v2(141.27,59.33) 141.6,59.33 143.41,57.52 145.01,57.52 145.41,57.12 147.54,57.12 148.33,57.91 v1(148.66,57.91)
  IN2 w0.102: v1(126.15,80.75) 126.15,80.75 125.12,80.75 119.91,85.95 114.09,85.95 112.88,84.73 101.31,84.73 97.07,80.49 95.62,80.49 94.53,79.4 92.24,79.4 89.96,77.11 85.43,77.11 84.99,76.68 82.86,76.68 82.1,75.92 75.07,75.92 72.58,73.43 69.28,73.43 68.98,73.74 68.98,74.04 68.67,74.35 65.42,74.35 64.86,74.9 62.04,74.9 61.69,75.26 61.18,75.26 60.95,75.03 60.95,74.07 61.15,73.86 61.15,71.32 60.87,71.04 59.68,71.04 v1(59.55,71.17)
  BOTTOM w0.102: v1(148.66,57.91) 148.43,58.14 Q30.1 ; v1(59.55,71.17) 59.55,71.5 58.56,72.49 R242.2
PCIE_CLKREQ_LAN#_IC: length 10.9
  TOP w0.102: U11.12 145.82,59.06 v1(145.69,58.93) 145.63,58.88 R150.2
  BOTTOM w0.102: v1(145.69,58.93) 145.51,58.75 v1(145.51,56.93) 145.51,56.64 145.89,56.26 146.98,56.26 147.12,56.13 149.31,56.13 150.46,57.28 Q30.3
PCIE_CLKREQ_WLAN#: length 129.9
  TOP w0.102: v1(154.14,77.24) 153.13,76.23 151.78,76.23 v1(149.67,74.12) ; v1(59.91,70.64) 60.26,70.29 U12.BD7
  IN2 w0.102: v1(149.67,74.12) 148.02,72.47 144.57,72.47 142.46,70.36 137.53,70.36 134.79,73.1 133.37,73.1 133.09,72.82 130.88,72.82 130.5,73.2 128.18,73.2 125.69,75.69 125.69,78.92 124.53,80.09 124.53,80.69 120.4,84.82 119.95,85.27 114.16,85.27 113.19,84.31 101.5,84.31 97.17,79.98 95.72,79.98 94.73,78.99 92.45,78.99 90.16,76.71 85.59,76.71 85.16,76.28 83.03,76.28 82.27,75.51 75.33,75.51 72.81,73 65.93,73 64.46,74.47 61.76,74.47 61.36,74.07 61.36,71.09 61.1,70.84 60.11,70.84 v1(59.91,70.64)
  BOTTOM w0.102: R246.2 56.87,72.33 58.18,71.02 59.07,71.02 59.45,70.64 v1(59.91,70.64) ; v1(154.14,77.24) v2(155.16,77.24) 155.37,77.24 158.29,80.16 Q19.1 162.37,80.16 162.61,80.4 R537.1
PCIE_RXN1_WLAN: length 140
  TOP w0.102: v1(63.82,69.88) 63.87,69.93 64.22,69.93 64.3,69.84 64.3,69.62 U12.AT9
  IN1 w0.102: v1(63.82,69.88) 63.82,69.65 63.72,69.55 63.48,69.55 63.38,69.65 63.38,71.31 64.55,72.48 65.31,72.48 66.01,73.18 71.59,73.18 73.65,75.24 73.65,80.05 76.98,83.37 76.98,84.29 77.41,84.72 81.93,84.72 82.32,85.1 88.38,85.1 88.71,84.76 91.49,84.76 92.27,83.99 94.48,83.99 95.64,82.82 98.3,82.82 98.64,83.16 98.64,83.17 119.13,83.17 120.72,81.59 120.72,78.01 122.29,76.43 122.29,73.6 126.62,69.27 126.62,68 127,67.63 128.84,67.63 130.14,66.33 134.63,66.33 136.46,68.16 141.83,68.16 144.29,70.62 144.29,71.32 144.95,71.98 152.97,71.98 153.99,73.01 153.99,73.57 159.23,78.82 160.01,78.82 166.44,85.24 166.44,87.03 166.72,87.31 166.92,87.31 167.33,86.9 CN10.23
PCIE_RXN2_LAN: length 124.1
  TOP w0.102: v1(64.68,69.27) 64.74,69.32 64.99,69.32 65.2,69.11 U12.AP10 ; C76.2 153.61,68.49 153.61,68.63 154.07,69.09 154.07,69.45 153.03,70.49 153.03,70.84 152.82,71.04 v1(152.67,71.04)
  IN1 w0.102: v1(64.68,69.27) 64.84,69.11 65.15,69.11 65.28,69.24 65.28,71.39 66.46,72.57 71.84,72.57 74.65,75.38 74.65,80.14 78,83.49 82.93,83.49 83.59,84.15 91.22,84.15 92.04,83.32 94.24,83.32 95.71,81.85 95.71,77.69 95.14,77.11 95.14,75.63 95.88,74.89 96.88,74.89 98.47,73.3 98.47,70.37 99.52,69.32 101.58,69.32 102.41,68.49 105.3,68.49 106.01,67.78 110.28,67.78 110.94,67.12 113.07,67.12 113.67,66.52 114.59,66.52 115.2,65.91 117.7,65.91 119.45,64.16 120.79,64.16 122.08,62.88 125.56,62.88 126.28,63.6 129.3,63.6 130.97,65.27 134.91,65.27 136.67,67.02 144.76,67.02 145.56,67.82 147.93,67.82 149.18,66.57 150.48,66.57 152,68.09 152,69.93 152.82,70.75 152.82,70.89 v1(152.67,71.04)
PCIE_RXP1_WLAN: length 140
  TOP w0.102: v1(63.8,69.14) 64.11,68.83 U12.AT10
  IN1 w0.102: v1(63.8,69.14) 63.6,69.34 63.39,69.34 63.19,69.54 63.19,71.39 64.47,72.67 65.23,72.67 65.93,73.37 71.51,73.37 73.46,75.32 73.46,80.12 76.79,83.45 76.79,84.37 77.33,84.91 81.86,84.91 82.24,85.29 88.45,85.29 88.79,84.96 91.57,84.96 92.35,84.18 94.56,84.18 95.72,83.01 98.22,83.01 98.45,83.24 98.45,83.25 98.57,83.36 119.21,83.36 120.91,81.66 120.91,78.09 122.48,76.51 122.48,73.68 126.81,69.35 126.81,68.08 127.08,67.82 128.92,67.82 130.22,66.52 134.55,66.52 136.38,68.35 141.75,68.35 144.1,70.7 144.1,71.4 144.87,72.17 152.89,72.17 153.8,73.09 153.8,73.65 159.15,79.01 159.93,79.01 166.25,85.32 166.25,87.11 166.64,87.5 166.98,87.5 167.18,87.7 CN10.25
PCIE_RXP2_LAN: length 124.1
  TOP w0.102: v1(153.38,71.04) 153.2,70.87 153.2,70.56 154.25,69.52 154.25,69.01 153.79,68.55 153.79,68.41 C77.2 ; U12.AP12 v1(64.74,68.58)
  IN1 w0.102: v1(64.74,68.58) 65.08,68.92 65.23,68.92 65.47,69.16 65.47,71.31 66.54,72.38 71.92,72.38 74.84,75.3 74.84,80.06 78.08,83.3 83,83.3 83.67,83.96 91.14,83.96 91.96,83.13 94.16,83.13 95.52,81.77 95.52,77.77 94.95,77.19 94.95,75.55 95.8,74.7 96.8,74.7 98.28,73.23 98.28,70.29 99.44,69.13 101.5,69.13 102.33,68.3 105.22,68.3 105.93,67.59 110.2,67.59 110.86,66.93 112.99,66.93 113.59,66.33 114.51,66.33 115.12,65.72 117.62,65.72 119.37,63.97 120.71,63.97 122,62.69 125.64,62.69 126.36,63.41 129.38,63.41 131.05,65.08 134.99,65.08 136.74,66.83 144.84,66.83 145.64,67.63 147.86,67.63 149.1,66.38 150.56,66.38 152.19,68.01 152.19,69.85 v1(153.38,71.04)
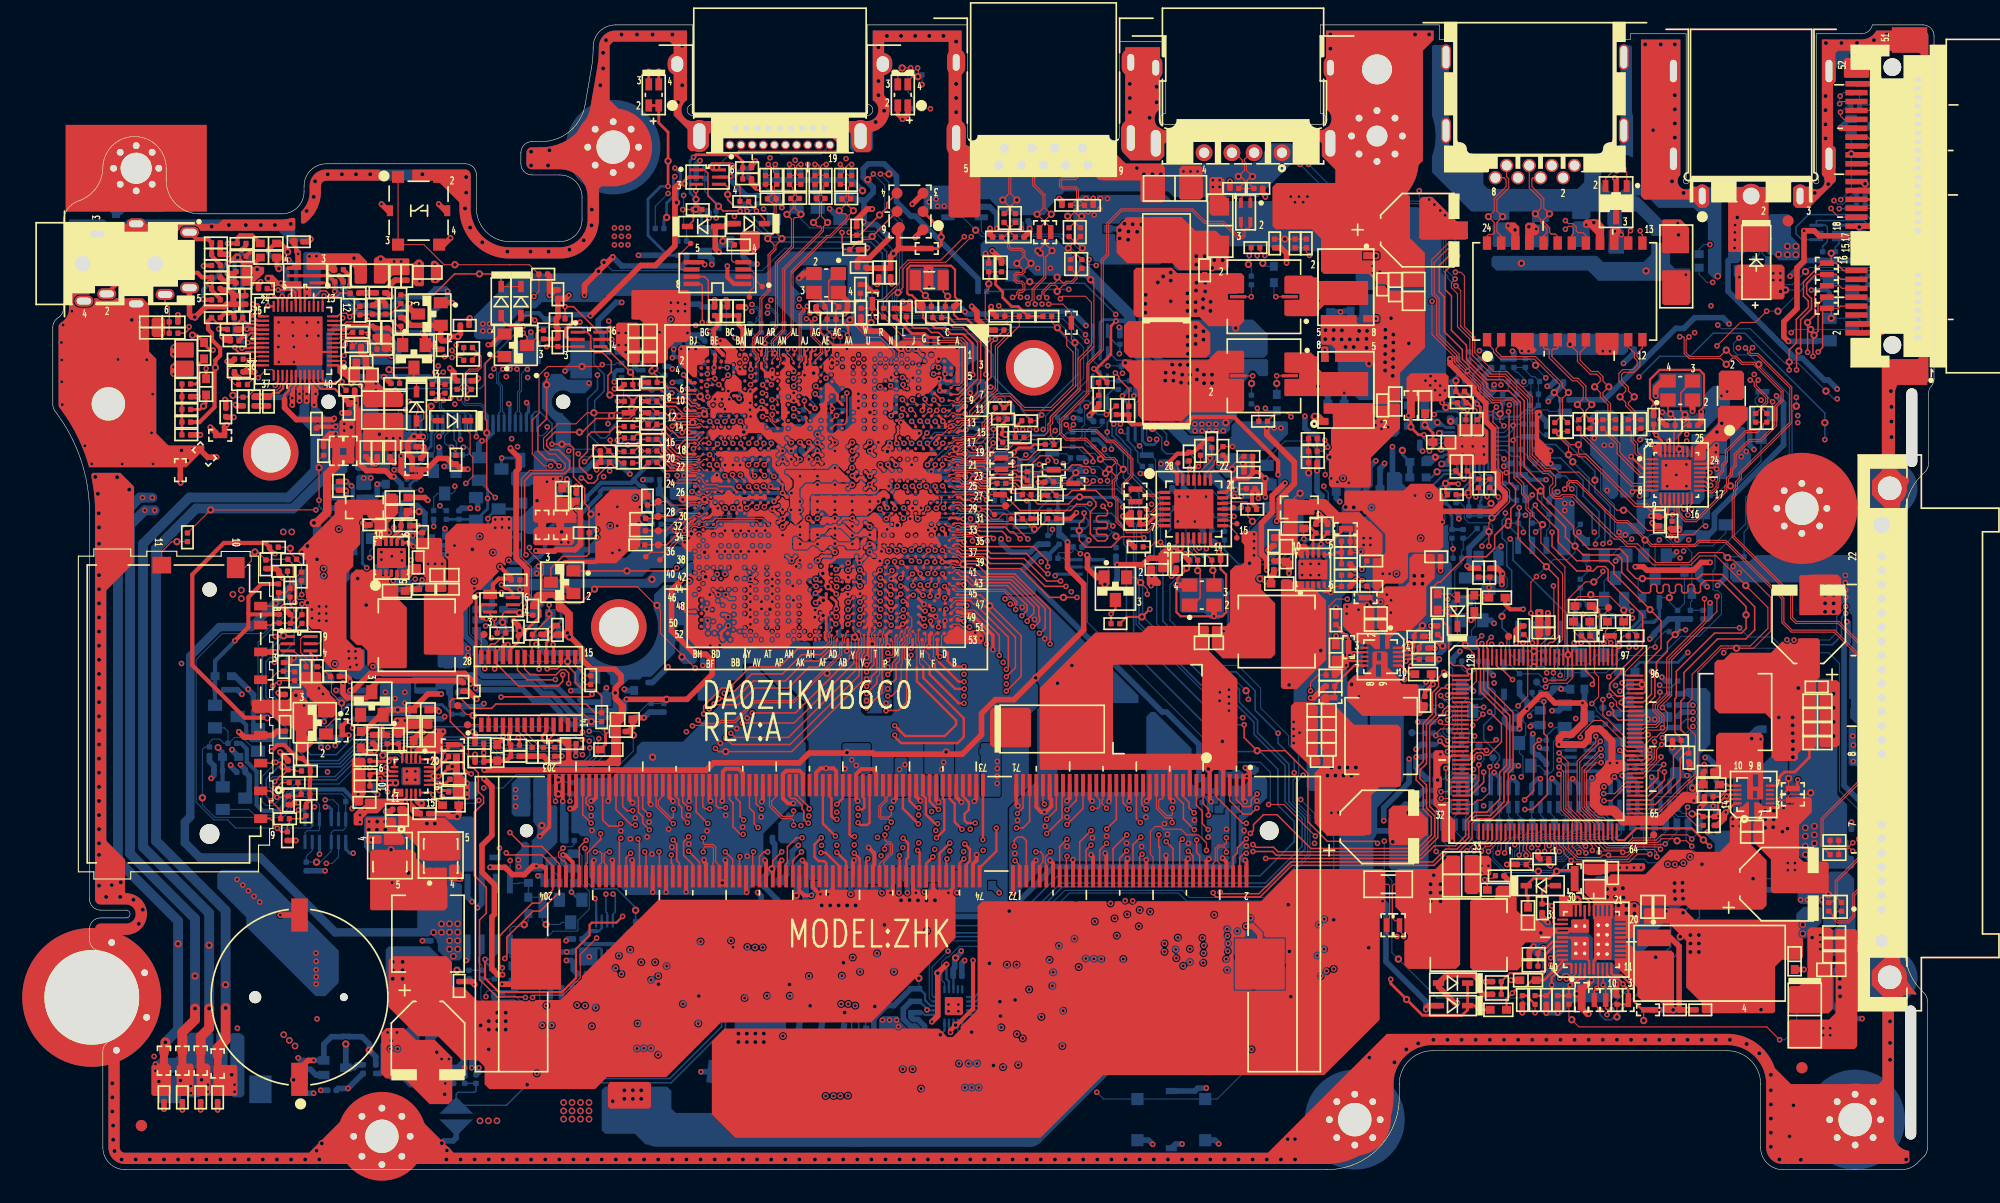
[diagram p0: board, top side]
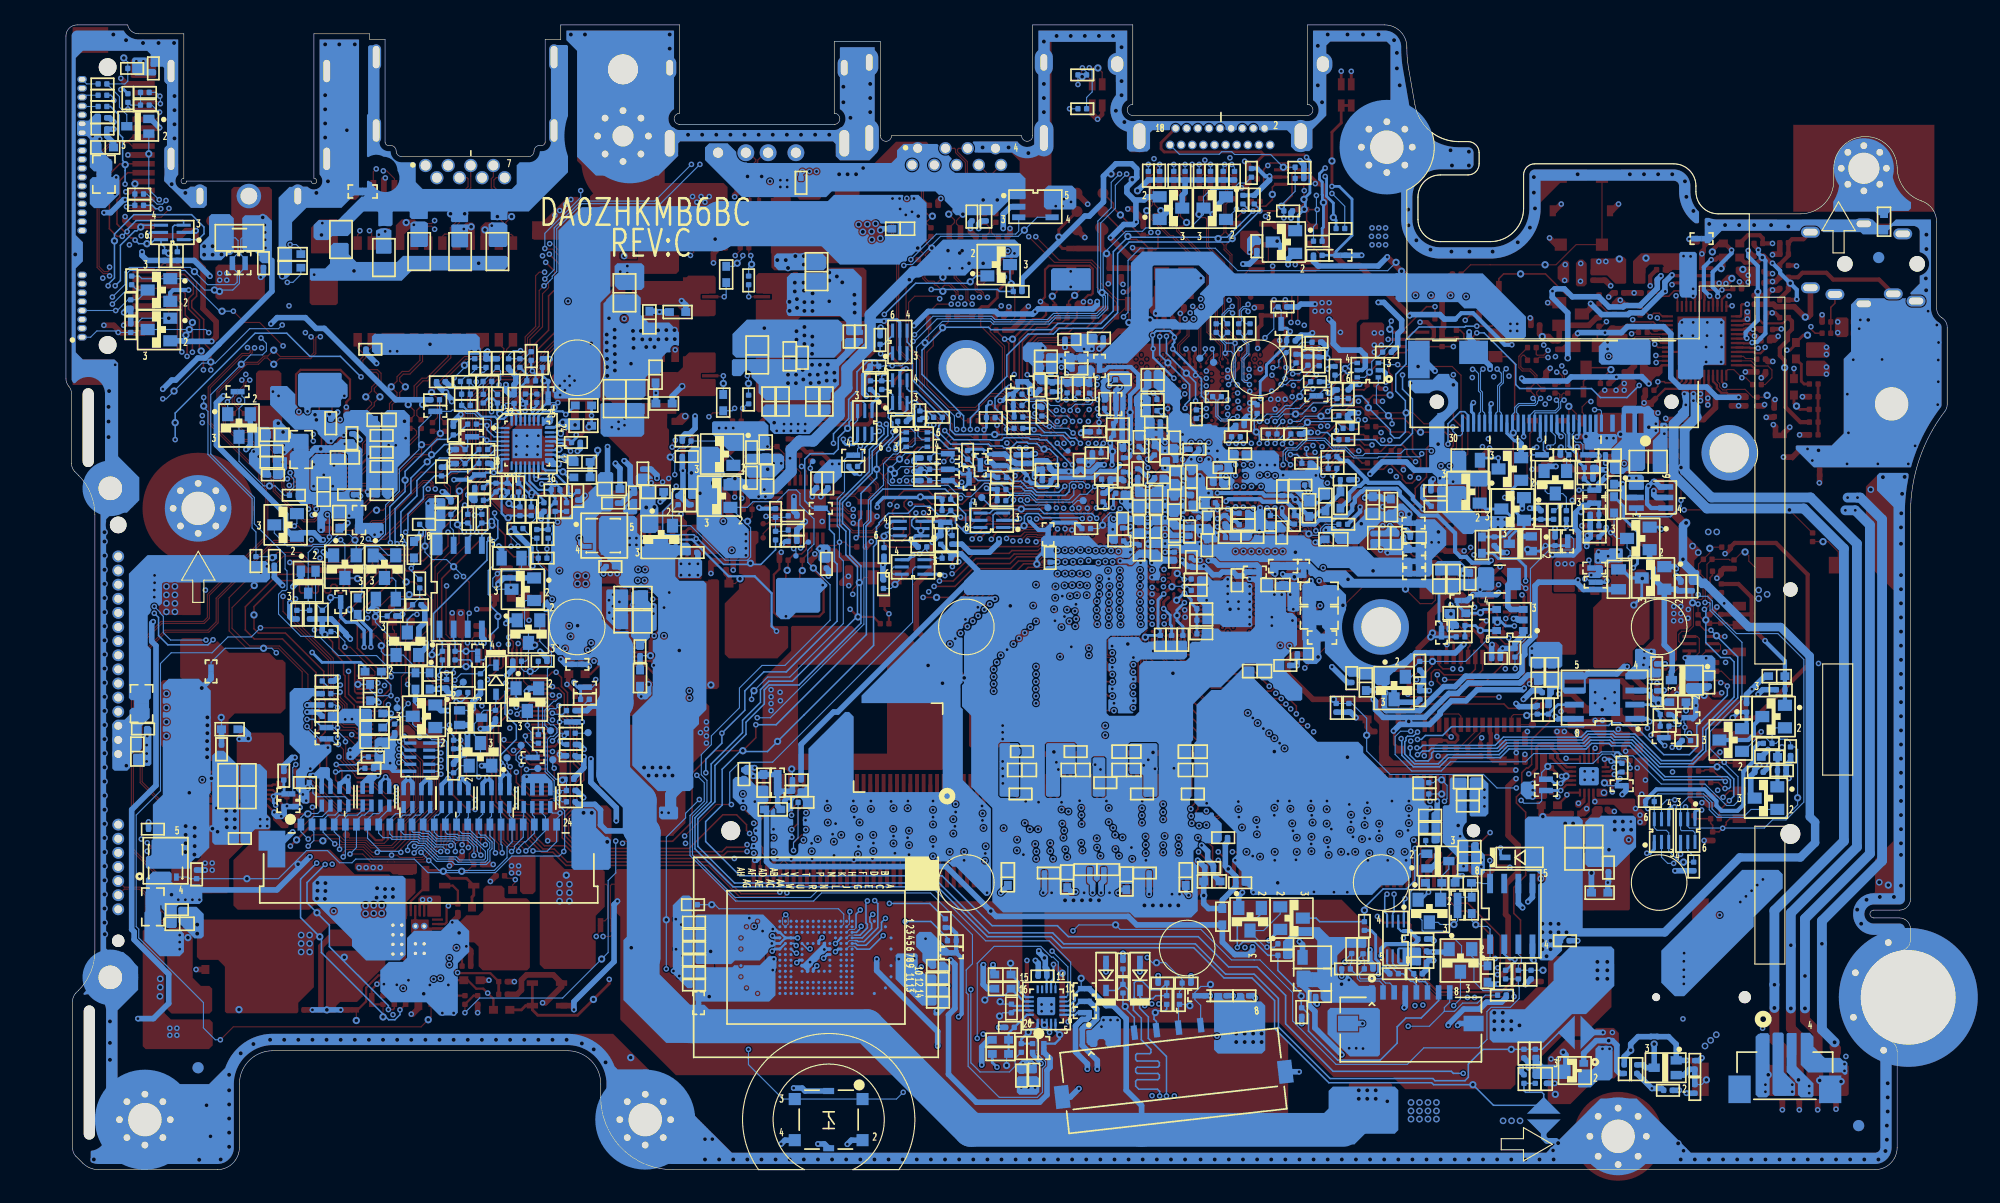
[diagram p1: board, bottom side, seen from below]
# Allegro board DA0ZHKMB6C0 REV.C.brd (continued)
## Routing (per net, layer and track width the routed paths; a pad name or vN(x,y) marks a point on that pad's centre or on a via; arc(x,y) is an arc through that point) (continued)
PCIE_TXN1_WLAN: length 135.8
  IN1 w0.102: CN10.31 167.59,90.26 164.15,90.26 162.56,88.67 162.56,86.77 157.15,81.37 154.59,81.37 149.88,76.66 147.38,76.66 145.76,75.04 143.76,75.04 141.7,72.99 131.33,72.99 131.33,72.97 130.85,72.49 128.52,72.49 127.66,73.34 127.66,74.16 126.78,75.04 126.78,82.92 121.97,87.72 115.22,87.72 113.73,89.21 106.69,89.21 106.46,89.45 104.01,89.45 103.24,88.68 84.17,88.68 83.54,89.31 77.5,89.31 77.01,88.81 76.15,88.81 74.55,87.21 73.74,87.21 72.43,85.9 72.43,83.96 71.39,82.92 67.23,82.92 63.75,79.44 63.75,77.75 63.44,77.44 63.11,77.44 v1(62.88,77.22)
  BOTTOM w0.102: C154.1 63.07,76.11 63.26,76.3 63.26,76.63 63.49,76.86 63.49,77.24 63.27,77.47 63.03,77.47 62.88,77.32 v1(62.88,77.22)
PCIE_TXN1_WLAN_C: length 6.2
  TOP w0.102: v1(62.78,71.38) 63.03,71.64 U12.AV4
  BOTTOM w0.102: v1(62.78,71.38) 62.78,71.2 62.97,71 63.12,71 63.25,71.13 63.25,72.91 62.81,73.36 62.81,74.27 63.21,74.68 63.21,74.98 62.86,75.33 C154.2
PCIE_TXN2_LAN: length 136.8
  TOP w0.102: U11.14 146.62,59.93 146.27,59.59 146.27,59.11 146.9,58.47 147.74,58.47 150.38,61.11 150.38,61.52 150.53,61.67 150.53,62.21 150.89,62.56 150.89,63.03 151.22,63.36 151.22,64.36 152.57,65.71 153.57,65.71 154.87,67.01 154.87,68.7 155.44,69.26 155.44,69.98 152.95,72.47 151.89,72.47 151.33,73.03 151.07,73.03 v2(150.51,72.47) 150,72.97 147.19,72.97 146.73,73.43 146.73,74.85 146.64,74.94 v1(146.32,74.94)
  IN1 w0.102: v1(64.3,77.67) 64.46,77.52 64.64,77.52 65.32,78.2 65.32,80.14 67.38,82.19 71.58,82.19 73.13,83.75 73.13,84.84 76.49,88.2 77.33,88.2 77.8,88.67 83.19,88.67 83.87,88 105.7,88 106.3,88.6 113.47,88.6 114.96,87.11 121.46,87.11 125.28,83.3 125.28,81.08 125.57,80.79 125.57,74.85 126.91,73.51 126.91,73.03 128.07,71.87 131.42,71.87 131.92,72.36 138.45,72.36 138.78,72.03 141.61,72.03 143.9,74.32 146.36,74.32 146.66,74.63 146.66,74.87 146.59,74.94 v1(146.32,74.94)
  BOTTOM w0.102: v1(64.3,77.67) 64.48,77.5 64.68,77.5 65.22,76.96 65.22,76.25 65.36,76.11 C152.1
PCIE_TXN2_LAN_C: length 6.6
  TOP w0.102: v1(64.63,70.64) 64.31,70.96 U12.AT6
  BOTTOM w0.102: v1(64.63,70.64) 64.33,70.94 64.33,71.09 64.22,71.21 64.22,73.43 64.42,73.63 64.77,73.63 v1(64.94,73.46) 64.94,74.21 65.32,74.59 65.32,74.9 C152.2
PCIE_TXP1_WLAN: length 135.8
  IN1 w0.102: CN10.33 167.3,90.45 164.07,90.45 162.37,88.74 162.37,86.85 157.07,81.56 154.51,81.56 149.8,76.85 147.3,76.85 145.69,75.24 143.68,75.24 141.62,73.18 131.26,73.18 131.14,73.07 131.14,73.05 130.77,72.68 128.59,72.68 127.85,73.42 127.85,74.23 126.97,75.12 126.97,83 122.05,87.91 115.3,87.91 113.81,89.4 106.77,89.4 106.54,89.64 103.93,89.64 103.16,88.87 84.24,88.87 83.62,89.5 77.42,89.5 76.93,89 76.07,89 74.47,87.4 73.66,87.4 72.24,85.98 72.24,84.04 71.31,83.11 67.15,83.11 63.55,79.51 63.55,77.83 63.36,77.64 63.1,77.64 63.03,77.71 63.02,77.71 v1(62.88,77.85)
  BOTTOM w0.102: v1(62.88,77.85) 63.08,77.65 63.34,77.65 63.67,77.32 63.67,76.79 63.44,76.56 63.44,76.39 C155.1
PCIE_TXP1_WLAN_C: length 6.2
  TOP w0.102: v1(62.75,70.64) 63.08,70.96 U12.AV6
  BOTTOM w0.102: v1(62.75,70.64) 62.94,70.83 63.2,70.83 63.43,71.06 63.43,72.99 62.98,73.43 62.98,74.2 63.39,74.6 63.39,75 C155.2
PCIE_TXP2_LAN: length 136.8
  TOP w0.102: U11.13 146.22,59.79 146.09,59.66 146.09,59.04 146.83,58.29 147.82,58.29 150.56,61.04 150.56,61.45 150.71,61.6 150.71,62.13 151.07,62.49 151.07,62.96 151.4,63.29 151.4,64.29 152.64,65.53 153.65,65.53 155.05,66.94 155.05,68.62 155.62,69.19 155.62,70.05 153.02,72.64 151.96,72.64 151.4,73.2 151.04,73.2 v2(150.51,73.74) 149.93,73.15 147.26,73.15 146.9,73.51 146.9,74.68 v1(147.16,74.93)
  IN1 w0.102: v1(64.28,77.06) 64.55,77.33 64.72,77.33 65.51,78.12 65.51,80.06 67.46,82 71.66,82 73.32,83.67 73.32,84.76 76.57,88.01 77.41,88.01 77.88,88.48 83.11,88.48 83.79,87.81 105.78,87.81 106.38,88.41 113.4,88.41 114.89,86.92 121.38,86.92 125.09,83.22 125.09,81 125.38,80.71 125.38,74.78 126.72,73.43 126.72,72.95 127.99,71.68 131.5,71.68 132,72.17 138.37,72.17 138.7,71.84 141.69,71.84 143.98,74.13 146.43,74.13 146.85,74.55 146.85,74.78 147.01,74.93 v1(147.16,74.93)
  BOTTOM w0.102: v1(64.28,77.06) 64.53,77.32 64.61,77.32 65.04,76.89 65.04,76.41 C153.1
PCIE_TXP2_LAN_C: length 6.6
  TOP w0.102: U12.AT7 64.21,70.25 v1(63.85,70.61)
  BOTTOM w0.102: v1(63.85,70.61) 64.15,70.92 64.15,71.02 64.04,71.13 64.04,73.5 64.12,73.58 64.12,74.3 v1(64.05,74.37) 64.84,74.37 65.14,74.67 65.14,74.92 C153.2
PCIE_WAKE#_R: length 9.2
  BOTTOM w0.102: CN10.1 166.99,74.9 166.42,75.46 164.77,75.46 164.64,75.33 v1(164.5,75.33) R232.1 162.88,75.33 162.74,75.46 162.74,76.23 162.36,76.61 Q20.1
PCLK_TPM: length 26.5
  TOP w0.14: v1(48.3,62.33) 47.36,63.27 47.36,63.88 48.09,64.61 48.09,66.03 48.43,66.37 50.11,66.37 50.59,66.85 R98.1 ; v1(44.64,50.8) 44.64,50.06 44.65,50.06 44.65,50.01 v2(44.64,50) 44.64,49.66 C106.1 43.14,47.75 42.92,47.53 42.92,47.14 43.09,46.97 U16.21
  IN1 w0.14: v1(44.64,50.8) 48.07,54.23 48.07,61.62 48.3,61.85 v1(48.3,62.33)
PCU_V3P3_G3_PWR: length 7.3
  TOP w0.254: U12.N22 75.11,63.29 v1(75.11,63.43) ; U12.P18 75.24,65.35 v1(75.29,65.35) 75.29,65.23 75.47,65.05 U12.N18
  BOTTOM w0.381: v1(75.29,65.35) 75.24,65.35 ; 75.24,65.35 75.21,65.32 75.21,64.76 v2(75.07,64.62) 75.11,64.58 v1(75.11,63.43) ; 75.24,65.35 75.21,65.37 75.21,65.86 C185.2 C183.1 74.76,67.32 R257.2
PD#: length 17.6
  TOP w0.102: D32.2 34.18,67.39 34.03,67.54 v2(34.03,68.68) 33.37,68.02 33.37,67.59 33.14,67.36 D31.2 32.71,68.03 32.83,68.15 32.83,68.63 32.35,69.11 v1(32.05,69.11)
  TOP w0.14: R82.2 26.03,70.48 v1(26.03,70.89) 26.02,70.9 25.45,70.9 25.35,70.8 24,70.8 23.86,70.94 U9.47
  IN1 w0.14: v1(26.03,70.89) 26.33,71.2 27.75,71.2 28.46,70.49 28.46,69.88 29.48,68.86 31.79,68.86 v1(32.05,69.11)
PGANG: length 4.5
  TOP w0.102: U13.23 103.62,62.61 104.46,63.45 104.46,63.72 104.61,63.87 104.61,64.42 R114.2 v1(106.1,65.06)
PLTRST#: length 326.5
  TOP w0.14: U18.7 127.43,42.05 127.88,41.61 v1(128.69,41.61) ; v1(134.1,42.11) 134.1,39.24 134.41,38.94 134.41,33.73 133.09,32.41 v1(132.4,32.41) ; U16.16 46.34,45.29 47.01,44.63 47.01,43.84 47.64,43.21 48.76,43.21 49.37,42.6 R530.1 49.36,41.1 48.76,41.1 47.96,41.9 39.86,41.9 39.46,41.5 37.58,41.5 36.72,42.37 35.98,42.37 35.75,42.14 35.75,40.31 36.39,39.68 36.39,39.68 37.38,38.69 37.38,36.45 37.68,36.14 37.84,36.14 38.26,35.72 38.26,34.02 38.75,33.53 38.75,32.99 37.91,32.16 37.91,26.47 38.98,25.4 38.98,23.06 38.38,22.46 38.38,17.11 39.95,15.55 42.46,15.55 v1(42.51,15.49) ; v1(149.11,61.57) 148.96,61.57 148.62,61.91 U11.19
  IN1 w0.14: v1(160.67,86.46) 161.67,87.46 161.67,92.53 164.9,95.76 v1(164.9,96.19) ; v1(132.4,32.41) 130.06,30.07 125.27,30.07 124,28.8 122.36,28.8 118.11,24.55 118.11,23.06 115.68,20.63 114.34,20.63 112.47,18.75 112.47,16.37 107.97,11.86 107.26,11.86 106.95,11.56 88.18,11.56 87.39,12.34 86.86,12.34 v1(86.71,12.19) ; v1(149.11,61.57) 149.44,61.24 149.44,56.97 145.92,53.45 141.75,53.45 141.68,53.37 139,53.37 138.73,53.65 134.36,53.65 v1(134.08,53.37) ; v1(134.1,42.11) 132.73,42.11 132.45,42.39 131.44,42.39 130.65,41.61 v1(128.69,41.61)
  IN2 w0.14: v1(160.67,86.46) 160.67,85.51 159.05,83.89 159.05,77.46 157.26,75.67 157.26,68.77 155.92,67.43 155.92,66.32 151.17,61.57 v1(149.11,61.57) ; v1(134.1,42.11) 134.1,42.82 133.78,43.15 133.78,44.94 134.92,46.08 134.92,50.49 134.21,51.2 134.21,53.24 v1(134.08,53.37) 133.57,53.87 128.81,53.87 127.53,55.15 126.91,55.15 125.87,56.19 122.14,56.19 119.65,58.67 116.48,58.67 115.26,59.89 115.26,59.89 114.32,60.83 v1(114.32,61.49) 113.94,61.49 110.35,65.08 109.21,65.08 107.43,66.85 106.39,66.85 105.07,68.17 102.93,68.17 101.1,70.01 99.41,70.01 96.85,72.57 96.77,72.57 v1(95.93,73.42) ; v1(86.71,12.19) 85.33,10.81 75.38,10.81 74.11,12.09 69.54,12.09 69.53,12.1 69.43,12.1 67.17,14.36 62.11,14.36 61.05,15.42 56.55,15.42 55.8,14.66 51.03,14.66 50.04,15.65 44.27,15.65 43.55,14.94 43.07,14.94 v1(42.51,15.49)
  BOTTOM w0.14: v1(160.67,86.46) 161.13,86.46 161.43,86.77 R217.2 ; v1(134.1,42.11) 133.6,42.11 133.05,42.66 C359.2 ; v1(114.32,61.49) 114.32,61.32 114.72,60.92 114.72,60.03 115.54,59.21 115.54,57.41 115.25,57.13 112.73,57.13 110.06,54.46 106.7,54.46 105.38,55.78 R322.1 ; v1(95.93,73.42) 95.98,73.47 R235.1 95.66,74.26 94.85,75.07 Q21.6 ; R202.1 165.17,96.67 164.9,96.4 v1(164.9,96.19)
PLTRST#_2: length 4.3
  TOP w0.102: CN10.22 163.49,86.5 163.63,86.64 v1(163.76,86.64)
  BOTTOM w0.102: v2(163,88.7) 163,88.69 R216.1 R217.1 163.5,86.77 163.63,86.64 v1(163.76,86.64)
PM_EXTTS#0: length 4.6
  TOP w0.102: JDIM6.198 46.16,27.62 45.99,27.79 45.84,27.79 45.48,28.14 45.48,28.52 v1(45.89,28.93)
  BOTTOM w0.102: R398.2 46.9,29.28 46.68,29.06 46.02,29.06 v1(45.89,28.93)
PMU_BATLOW#_R: length 9.6
  TOP w0.102: v1(76.67,61.47) 76.89,61.25 U12.K26
  BOTTOM w0.102: v1(76.67,61.47) 77.38,60.76 77.99,60.76 78.7,60.06 81.96,60.06 82.56,60.66 84.19,60.66 R301.2
PROCHOT_EC: length 10
  TOP w0.102: v1(134.97,44.7) 135.06,44.8 U18.111
  BOTTOM w0.102: v2(140.83,47.14) 140.83,46.61 140.53,46.3 138.88,46.3 137.96,45.39 136.2,45.39 135.98,45.17 135.98,44.27 135.78,44.07 135.38,44.07 135.35,44.1 R358.2 v1(134.97,44.7)
PSELF: length 4.5
  TOP w0.102: U13.22 104.12,62.65 104.36,62.89 105.96,62.89 v2(106.09,63.02) 106.09,63.35 106.9,64.16 R115.1
PWR_SD_EN: length 12
  TOP w0.102: PQ2.2 24.58,39.8 25.98,41.2 v2(25.98,41.99) 25.77,42.19 25.77,42.19 25.06,42.91 25.06,44.27 24.98,44.36 C156.2 24.96,44.37 24.1,45.24 23.8,45.24 R185.2 23.58,45.25 22.29,46.53 22.29,47.78 22.49,47.97 Q46.6
PWRLED#: length 132.8
  TOP w0.102: v2(73.3,89.08) v1(73.8,89.59) ; v1(139.26,36.63) 138.8,36.63 137.94,35.76 137.94,32.74 138.97,31.71 139.48,31.71 139.86,31.33 U18.62
  IN2 w0.102: v1(139.26,36.63) 137.89,38 136.36,38 135.6,38.76 134.71,38.76 133.71,39.76 133.71,41.06 132.68,42.09 132.68,47.68 129.88,50.48 129.27,50.48 126.61,53.13 126.61,53.9 125.6,54.92 122.25,54.92 119.31,57.86 115.93,57.86 113.34,60.44 113.34,60.71 110.07,63.98 108.93,63.98 107.08,65.84 102.76,65.84 102.04,66.56 102.04,67.69 100.69,69.04 99.01,69.04 96.85,71.2 95.42,71.2 94.58,72.03 94.58,73.05 93.1,74.53 v1(93.01,74.53) ; v1(73.8,89.59) 73.63,89.76 71.04,89.76 69.36,88.08 64.48,88.08 63.81,88.75 59.58,88.75 58.26,87.43 57.18,87.43 56.83,87.07 56.1,87.07 v1(55.34,87.83)
  BOTTOM w0.102: v1(73.8,89.59) 74.82,88.57 74.82,86.49 76.14,85.17 76.14,79.05 75.71,78.61 75.71,77.55 76.43,76.84 80.28,76.84 80.84,76.28 85.72,76.28 85.99,76.56 90.85,76.56 92.88,74.52 93,74.52 v1(93.01,74.53) ; v1(55.34,87.83) 54.19,86.68 R192.2
PWROK_EC_UR: length 4.9
  TOP w0.102: U18.74 143.03,35.65 144.24,36.86 144.24,37.8 v1(144.69,38.25)
  BOTTOM w0.102: R375.1 144.86,38.25 v1(144.69,38.25)
R_SPK+: length 72.4
  TOP w0.889: v3(15.54,14.55) 15.54,11.67 14.82,10.95 R191.2
  BOTTOM w0.889: 23.74,67.95 24.6,67.08 24.6,62.48 21.61,59.49 12.89,59.49 9.29,55.88 9.29,29.57 15.54,23.31 15.54,16.64 ; v2(15.54,16.64) 15.54,16.64 ; 15.54,16.64 v3(15.54,14.55)
  vias: v1(23.51,68.81) v1(23.64,69.8)
R_SPK+_1:
  vias: v1(16.35,7.65) v1(16.35,7.01) v2(16.09,8.53)
R_SPK-: length 72
  TOP w0.889: R190.2 13.3,11.96 14.06,12.73 v3(14.06,14.5)
  BOTTOM w0.889: 22.52,67.72 23.61,66.62 23.61,62.89 21.2,60.48 12.28,60.48 8.12,56.31 8.12,29.03 14.06,23.09 v2(14.06,20.19) v3(14.06,14.5)
  vias: v1(22.83,69.8) v1(22.83,69.19)
R_SPK-_1:
  vias: v1(13.94,7.65) v1(13.94,7.01) v2(13.38,8.08)
REGOUT:
  vias: v2(149.67,66.37)
RESET#_USB: length 5.6
  TOP w0.102: v1(106.24,58.78) 106.08,58.94 U13.17
  BOTTOM w0.102: R306.1 104.38,58.69 R308.2 ; R306.1 106.15,58.69 v1(106.24,58.78) ; R306.1 R322.2 104.36,57.44 C248.2
RF_EN: length 62.4
  TOP w0.102: CN10.20 160.63,85.7 159.93,86.4 v1(159.93,86.49) ; v1(149.67,51.58) 149.67,50.22 145.37,45.92 145.37,42.75 144.34,41.72 144.34,41.43 144.92,40.85 144.92,39.91 v1(144.78,39.76) 144.56,39.55 143.32,39.55 143.03,39.25 U18.83
  IN1 w0.102: v1(149.67,51.58) 150.53,51.58 152.49,53.54 152.49,55.15 151.48,56.16 151.48,61.92 156.78,67.21 v1(156.94,67.21)
  IN2 w0.102: v1(159.93,86.49) 160.11,86.49 160.49,86.87 160.85,86.87 161.19,86.53 161.19,85.5 159.43,83.73 159.43,73.6 157.64,71.81 157.64,67.91 v1(156.94,67.21)
RING2:
  vias: v1(22.85,79.25) v1(22.85,78.61) v1(23.08,82.17) v1(23.71,82.19) v2(27.09,82.02)
RREF: length 3.9
  TOP w0.102: R154.1 98.72,56.03 99.14,56.45 v1(99.63,56.45) 99.92,56.16 100.93,56.16 101.12,56.35 U13.8
RSET: length 2.9
  TOP w0.203: 144.69,65.61 144.69,65.53 145.02,65.21 U11.31
  TOP w0.254: 144.69,65.61 v1(144.21,66.09) 143.98,66.32 R97.2
RSMRST#: length 116.4
  TOP w0.102: 82.01,69.11 81.91,69.11 81.55,68.76 U12.B10
  TOP w0.14: 82.01,69.11 82.8,69.11 83.89,70.21 83.89,70.82 84.4,71.32 84.4,74.35 v1(84.78,74.73) 85.55,75.5 R58.2
  IN2 w0.14: v1(84.78,74.73) 83.43,73.38 83.43,70.31 85.18,68.55 90.14,68.55 91.99,70.41 91.99,73.12 91.93,73.18 91.91,73.18 91.58,73.51 91.58,75.59 92.52,76.53 93.77,76.53 96.97,73.33 96.97,72.95 99.58,70.33 101.19,70.33 103.09,68.43 105.2,68.43 106.22,67.4 110.95,67.4 112.31,66.04 113.17,66.04 114.01,65.21 115.56,65.21 119.11,61.65 120.64,61.65 122.07,60.22 126.31,60.22 126.82,59.71 127.05,59.49 130.36,59.49 132.01,61.13 134.48,61.13 135.06,60.56 141.74,60.56 142.12,60.18 143.62,60.18 145.67,58.13 146.43,58.13 147.76,56.81 147.76,50.38 149.5,48.63 149.5,47.25 147.96,45.71 147.96,40.96 v1(147.51,40.51)
  BOTTOM w0.14: R373.2 146.89,40.51 v1(147.51,40.51) ; v2(84.07,74.73) v1(84.78,74.73)
RSMRST#_UR: length 5.6
  TOP w0.102: v1(144.06,38.51) 144.03,38.48 144.03,36.97 143.12,36.05 U18.75
  BOTTOM w0.102: R373.1 145.1,39.78 144.06,38.74 v1(144.06,38.51)
RTC_VCC_P22_PWR: length 13.1
  TOP w0.254: U12.P22 74.43,63.26 v1(74.43,63.43)
  BOTTOM w0.381: R288.1 84.57,63.35 84.2,62.98 83.61,62.98 83.6,62.97 83.25,62.97 82.78,62.5 v2(82.78,62.15) 82.39,61.76 82,61.76 81.7,61.46 80.9,61.46 80.6,61.76 C221.2 80.35,62.26 76.77,62.26 76.14,62.88 74.83,62.88 74.43,63.28 v1(74.43,63.43)
RTC_X1: length 16.1
  TOP w0.102: U12.C9 81.01,69.2 81.2,69.01 81.51,69.01 81.95,69.44 82.13,69.44
  TOP w0.14: 82.13,69.44 82.69,69.44 83.16,69.92 83.16,70.6 83.46,70.89 83.46,74.73 82.11,76.07 81.21,76.07 80.63,76.66 R59.1 79.93,77 80.27,77.33 C46.2 80.27,77.99 80.48,78.21 v2(80.48,78.59) 80.08,78.99 Y7.1
RTC_X2: length 14.8
  TOP w0.14: Y7.2 77.58,79.56 v2(78.48,78.66) 79.02,78.12 C47.2 79.02,77.22 79.15,77.08 R59.2 79.62,76.19 80.57,76.19 80.99,75.77 81.86,75.77 83.18,74.45 83.18,71.14 U12.A9
S5_ON: length 315.7
  TOP w0.102: PQ37.2 97.37,53.29 v2(97.84,52.82) 98.44,52.22 v1(98.44,51.77) ; U18.26 125.83,34.45 125.38,34 v1(124.85,34)
  IN1 w0.102: v1(148.53,36.45) 147.88,37.1 147.42,37.1 144.82,39.7 142.38,39.7 142.08,39.4 138.4,39.4 138.02,39.02 138.02,37.37 135.35,34.7 133.71,34.7 133.53,34.87 128.43,34.87 128.1,34.54 128.1,34.54 127.56,34 v1(124.85,34) 123.51,32.66 114.93,32.66 114.42,32.16 114.42,25.35 109.43,20.35 109.43,16.88 106.82,14.28 94.45,14.28 93.84,14.88 89.98,14.88 89.57,15.29 88.72,15.29 87.81,16.2 v1(87.81,16.21) 87.62,16.41 79.57,16.41 78.8,17.17 72,17.17 71.15,18.02 65.4,18.02 64.76,17.39 62.09,17.39 60.13,15.43 50.27,15.43 49.44,16.26 46.1,16.26 42.39,19.96 40.4,19.96 39.64,19.2 39.64,16.26 v1(38.95,15.57) ; v1(23.77,13.56) 22.1,15.23 22.1,18.66 9.64,31.12 9.64,44.48 11.93,46.76 17.95,46.76 19.78,48.59 19.78,50.34 21.58,52.15 22.9,52.15 23.08,51.97 25.87,51.97 27.14,53.24 27.14,54.66 29.02,56.54 31.39,56.54 32.22,55.71 v1(32.22,54.84)
  IN2 w0.102: v1(98.44,51.77) 99.2,51.77 99.81,51.16 99.81,49.94 105.27,44.48 108.58,44.48 109.16,43.89 115.76,43.89 116.15,44.27 120.21,44.27 120.46,44.53 121.95,44.53 124.72,41.76 v1(124.86,41.76) ; v1(23.77,13.56) 23.79,13.54 37.2,13.54 38.68,12.06 40.85,12.06 41.47,12.69 41.47,15.37 41.27,15.57 v1(38.95,15.57)
  BOTTOM w0.102: PR126.2 32.13,54.75 v1(32.22,54.84) ; PQ33.2 47.41,28.42 47.59,28.25 47.59,25.68 48.25,25.02 48.25,23.46 47.24,22.44 47.24,21.55 47.15,21.46 45,21.46 43.68,20.14 43.68,19.15 43.4,18.87 42.84,18.87 42.56,18.59 42.56,16.92 41.75,16.1 39.13,16.1 38.95,15.93 v1(38.95,15.57) ; v1(87.81,16.21) 87.81,9.62 86.99,8.79 84.34,8.79 83.84,9.3 83.84,10 PR184.2 ; v1(148.53,36.45) 148.8,36.18 PR163.1 ; v1(124.85,34) 124.74,34.11 R391.1 124.18,35 R387.1 125.13,35.13 125.9,35.9 125.9,38.71 125.62,38.99 125.37,38.99 125.04,39.32 125.04,39.7 125.35,40.02 125.61,40.02 125.9,40.31 125.9,41.25 125.67,41.48 125.14,41.48 v1(124.86,41.76) 124.83,41.78 122.66,41.78 PR148.1
S5D: length 106.2
  BOTTOM w0.102: PC133.1 114.65,59.33 PQ17.2 113.01,57.94 109.9,54.83 107.91,54.83 107.62,55.11 107.62,57.77 PQ13.2 107.92,59.59 107.41,60.1 105.28,60.1 104.22,61.16 103.51,61.16 103.18,60.84 103.18,59.81 101.92,58.55 101.92,56.29 102.48,55.73 102.48,54.64 v2(101.97,54.13) 100.47,52.63 100.47,49.43 104.54,45.36 106.59,45.36 108.63,43.33 108.63,41.55 111.15,39.03 111.15,38.24 112.06,37.34 112.06,35.53 111.55,35.03 111.55,33.08 112.85,31.77 112.85,28.33 109.01,24.49 102.23,24.49 101.59,25.12 91.01,25.12 86.47,20.59 80.75,20.59 78.83,18.67 78.83,15.39 79.1,15.13 PU16.9
SATA_GP0: length 5.6
  TOP w0.102: v1(61.16,67.32) 61.52,67.68 U12.BA12
  BOTTOM w0.102: v1(61.16,67.32) 60.74,67.75 60.2,67.75 59.47,68.48 58.27,68.48 R252.1
SATA_GP1: length 6.9
  TOP w0.102: v1(61.85,67.32) 62.23,66.94 U12.AY14
  BOTTOM w0.102: R260.1 58.12,70.03 58.12,69.67 v2(58.23,69.56) 59.05,68.74 59.55,68.74 60.31,67.98 61.19,67.98 v1(61.85,67.32)
SATA_RCOMP_DN: length 1.3
  TOP w0.102: U12.AT18 64.63,65.13 v1(64.63,65.35)
  BOTTOM w0.102: v1(64.63,65.35) 64.36,65.61 R163.2
SATA_RCOMP_DP: length 1.4
  TOP w0.102: U12.AU18 63.65,64.87 63.96,65.18 v1(63.96,65.35)
  BOTTOM w0.102: R163.1 63.58,65.72 v1(63.96,65.35)
SATA_RXN0: length 137.5
  TOP w0.102: v1(62.59,65.35) 62.59,65.48 U12.AV16 ; C124.2 159.05,29.15 159.05,31.6 162.35,34.9 162.35,46.23 160.22,48.36 156.36,48.36 155.52,49.2 155.52,51.35 150.42,56.44 148.1,56.44 147.74,56.08 143.73,56.08 141.6,58.22 140.63,58.22 137.03,61.82 136.44,61.82 136.36,61.75 136.36,61.49 v1(136.62,61.24)
  IN1 w0.102: v1(136.62,61.24) 136.4,61.46 136.4,61.65 136.17,61.87 134.95,61.87 134.71,61.63 131.79,61.63 131.33,61.18 127.77,61.18 127.04,60.45 124.34,60.45 124.15,60.25 122.28,60.25 122.07,60.46 120.96,60.46 119.88,61.54 118.37,61.54 116.43,63.49 113.23,63.49 112,64.72 108.34,64.72 107.99,65.07 102.33,65.07 100.51,66.88 97.45,66.88 96.65,67.68 95.12,67.68 94.97,67.53 94.19,67.53 93.54,66.88 92.21,66.88 92.21,66.86 91.97,66.62 90.97,66.62 90.67,66.93 90.67,67.18 89.96,67.9 84.46,67.9 83.14,66.58 82.75,66.58 82.11,65.94 81.2,65.94 80.2,64.94 75.12,64.94 74.87,65.19 74.87,66.36 74.48,66.75 68.28,66.75 67.55,66.03 63.03,66.03 62.77,65.76 62.77,65.53 v1(62.59,65.35)
SATA_RXN0_R: length 4.8
  TOP w0.102: C124.1 160.63,28.74 160.82,28.93 161.61,28.93 v1(161.89,28.65)
  IN1 w0.102: CN14.5 163.96,29.04 163.86,29.04 162.65,29.04 162.56,28.95 162.19,28.95 v1(161.89,28.65)
SATA_RXP0: length 137.5
  TOP w0.102: v1(135.98,61.24) 136.18,61.44 136.18,61.57 136.19,61.57 136.19,61.82 136.36,62 137.1,62 140.71,58.39 141.67,58.39 143.81,56.26 147.67,56.26 148.02,56.62 150.5,56.62 155.69,51.42 155.69,49.28 156.43,48.54 160.29,48.54 162.53,46.3 162.53,34.83 159.22,31.52 159.22,29.22 159.34,29.11 159.72,29.11 159.85,29.24 C123.2 ; U12.AU16 63.3,65.48 v1(63.3,65.35)
  IN1 w0.102: v1(135.98,61.24) 136.21,61.47 136.21,61.57 136.09,61.68 135.03,61.68 134.79,61.44 131.87,61.44 131.41,60.99 127.84,60.99 127.11,60.26 124.42,60.26 124.23,60.06 122.2,60.06 121.99,60.27 120.88,60.27 119.8,61.35 118.29,61.35 116.35,63.3 113.15,63.3 111.92,64.53 108.26,64.53 107.91,64.88 102.25,64.88 100.44,66.69 97.37,66.69 96.57,67.49 95.2,67.49 95.05,67.34 94.27,67.34 93.62,66.69 92.3,66.69 92.05,66.43 90.89,66.43 90.48,66.85 90.48,67.1 89.88,67.7 84.54,67.7 83.22,66.39 82.83,66.39 82.19,65.75 81.28,65.75 80.28,64.75 75.04,64.75 74.68,65.11 74.68,66.28 74.4,66.56 68.36,66.56 67.63,65.84 63.11,65.84 62.96,65.68 62.96,65.53 63.14,65.35 v1(63.3,65.35)
SATA_RXP0_R: length 4.8
  TOP w0.102: C123.1 160.63,29.24 160.76,29.11 161.59,29.11 v1(161.89,29.41)
  IN1 w0.102: v1(161.89,29.41) 162.16,29.14 162.48,29.14 162.57,29.23 163.78,29.23 163.96,29.24 CN14.6
SATA_TXN0: length 183.7
  TOP w0.102: v1(58.91,69.55) 58.91,69.99 U12.BG7 ; v1(152.87,73.97) 152.63,73.72 152.63,73.55 152.75,73.43 153.38,73.43 156.4,70.41 156.4,67.18 151.86,62.63 151.86,62.16 151.51,61.82 151.51,61.28 151.35,61.12 151.35,60.64 151.22,60.51 151.22,57 156.48,51.75 156.48,49.68 156.84,49.33 160.65,49.33 163.31,46.66 163.31,28.76 160.49,25.94 160.49,24.42 C130.2
  IN1 w0.102: v1(58.91,69.55) 58.91,69.76 59.09,69.94 60.06,69.94 61.34,71.22 61.34,72.25 61.83,72.73 62.97,72.73 63.48,73.24 63.97,73.24 64.22,73.49 65.17,73.49 65.96,74.28 71.54,74.28 72.85,75.59 72.85,80.38 76.11,83.64 76.11,84.69 76.96,85.53 81.6,85.53 82,85.93 88.84,85.93 89.09,85.67 91.72,85.67 92.61,84.79 94.95,84.79 95.79,85.62 99.42,85.62 100.9,84.14 119.3,84.14 121.52,81.92 121.52,78.34 123.09,76.77 123.09,73.93 128.6,68.43 129.17,68.43 130.19,67.4 131.5,67.4 131.78,67.13 134.3,67.13 136.37,69.2 141.63,69.2 143.27,70.84 143.27,71.44 144.62,72.78 151.97,72.78 152.67,73.48 152.67,73.76 v1(152.87,73.97)
SATA_TXN0_R: length 8
  TOP w0.102: CN14.3 163.95,25.42 162.53,25.42 161.89,24.78 161.89,22.83 161.43,22.38 160.57,22.38 160.27,22.68 160.27,22.96 160.56,23.26 C130.1
SATA_TXP0: length 183.7
  TOP w0.102: v1(152.24,73.94) 152.45,73.73 152.45,73.48 152.67,73.25 153.31,73.25 156.23,70.33 156.23,67.25 151.68,62.7 151.68,62.24 151.33,61.89 151.33,61.36 151.17,61.2 151.17,60.71 151.04,60.59 151.04,56.93 156.3,51.67 156.3,49.61 156.76,49.15 160.57,49.15 163.14,46.59 163.14,28.83 160.32,26.01 160.32,24.38 159.97,24.04 C129.2 ; v1(58.81,70.56) 59.27,70.56 U12.BF6
  IN1 w0.102: v1(152.24,73.94) 152.48,73.7 152.48,73.56 151.89,72.97 144.54,72.97 143.08,71.52 143.08,70.92 141.56,69.39 136.29,69.39 134.22,67.32 131.86,67.32 131.58,67.6 130.27,67.6 129.25,68.62 128.68,68.62 123.28,74.01 123.28,76.84 121.71,78.42 121.71,82 119.38,84.33 100.98,84.33 99.5,85.81 95.71,85.81 94.87,84.98 92.69,84.98 91.8,85.86 89.17,85.86 88.92,86.12 81.92,86.12 81.53,85.73 76.88,85.73 75.92,84.77 75.92,83.72 72.66,80.46 72.66,75.67 71.46,74.47 65.88,74.47 65.09,73.68 64.14,73.68 63.89,73.43 63.4,73.43 62.89,72.92 61.75,72.92 61.15,72.32 61.15,71.3 59.98,70.13 58.97,70.13 58.81,70.29 v1(58.81,70.56)
SATA_TXP0_R: length 8
  TOP w0.102: CN14.2 163.96,25.24 162.6,25.24 162.07,24.71 162.07,22.76 161.51,22.2 160.5,22.2 160.09,22.61 160.09,22.9 C129.1
SD3_WP: length 61.7
  TOP w0.102: v1(23.66,59.36) v2(14.19,59.36) 12.12,57.29 R316.2 ; U12.BD5 60.31,71.06 60.73,71.48 v1(60.73,71.48)
  IN1 w0.102: v1(23.66,59.36) 25.85,61.54 25.85,63.35 29.38,66.88 42.33,66.88 44.39,64.82 45.2,64.82 45.51,65.13 47.18,65.13 48.53,63.78 49.17,63.78 v1(50.08,62.87)
  IN2 w0.102: v1(50.08,62.87) 50.08,63.17 51.32,64.41 51.32,65.38 51.55,65.61 51.71,65.61 53.53,67.44 53.53,68.73 55.13,70.33 56.53,70.33 58.23,72.03 59.02,72.03 59.33,71.73 60.49,71.73 v1(60.73,71.48)
SDIO3_1P8_EN#: length 80.4
  TOP w0.14: U12.BF22 59.42,63.06 v1(59.06,63.43)
  IN1 w0.102: v1(47.26,64.41) 47.11,64.26 44.16,64.26 41.95,66.47 40.3,66.47 39.92,66.09 39.92,63.63 44.24,59.31 44.24,55.47 41.55,52.78 41.55,50.14 41.9,49.78 41.9,47.27 40.94,46.3 40.94,41.83 40.91,41.8 40.91,41.76 40.25,41.1 37.89,41.1 35.75,43.23 34.2,43.23 31.94,40.97 26.61,40.97 26.13,40.49 26.13,37.82 25.52,37.21 24.73,37.21 23.79,36.27 23.79,33.99 v1(24.5,33.27)
  BOTTOM w0.102: v1(47.26,64.41) 47.26,64.31 47.44,64.14 51.12,64.14 51.22,64.03 53.38,64.03 54.17,64.82 55.26,64.82 56.05,65.61 57.62,65.61 58.49,64.74 59.27,64.74 59.5,64.52 59.5,63.87 v1(59.06,63.43) ; v1(24.5,33.27) 25.21,33.27 25.7,32.79 Q50.5
SDIO3_CD: length 4.4
  TOP w0.102: Q46.2 20.51,47.32 20.39,47.19 20.39,46.81 20.54,46.66 21.13,46.66 Q46.3 21.16,46.66 21.68,46.66 22.77,45.57 R184.2
SDIO3_CD#: length 99.5
  TOP w0.102: CN4.10 17.25,54.17 17.85,54.76 17.85,55.25 v2(18.18,55.58) 18.43,55.58 19.15,54.86 T10.1 19.57,54.86 19.63,54.92 R363.2 21.61,54.46 21.61,52.71 21.76,52.55 21.76,51.05 v1(21.78,51.03) ; U12.BC24 60.81,62.07 v1(60.45,62.43)
  IN1 w0.102: v1(48.25,39.45) 48.25,40.06 49.69,41.49 49.69,42.51 50.26,43.08 50.26,43.69 50.87,44.3 52.8,44.3 55.21,46.71 55.21,48.74 57.22,50.75 57.22,52.04 57.98,52.81 57.98,60.73 59.02,61.77 59.79,61.77 v1(60.45,62.43)
  BOTTOM w0.102: v1(48.25,39.45) 49.17,39.45 49.65,38.96 49.65,37.35 48.17,35.87 45.51,35.87 44.68,36.7 37.92,36.7 37.18,37.44 31.27,37.44 31.11,37.59 29.53,37.59 29.18,37.24 28.26,37.24 25.72,34.7 21.78,34.7 19.85,32.77 19.19,32.77 18.81,33.15 18.81,35.36 21.33,37.87 21.33,39.42 18.46,42.29 18.46,47.45 21.33,50.32 21.33,50.95 21.4,51.03 v1(21.78,51.03)
SDIO3_CLK: length 70.6
  TOP w0.14: U12.AY26 62.23,61.03 61.79,61.47 v1(61.71,61.47) ; v1(19.78,43.51) 20.08,43.82 v1(20.36,43.82) 20.56,44.01 R543.2
  IN1 w0.14: v1(61.71,61.47) 61.38,61.14 60.39,61.14 60.24,60.99 60.24,60.33 60.06,60.15 59.78,60.15 59.64,60.29 59.63,60.29 59.63,61.01 59.5,61.14 59.25,61.14 58.49,60.38 58.49,59.96 58.63,59.82 59.19,59.82 59.33,59.68 59.33,59.4 59.19,59.26 58.63,59.26 58.49,59.12 58.49,52.6 57.73,51.84 57.73,50.5 55.82,48.59 55.82,46.48 54.78,45.44 54.78,45.14 52.44,42.8 51.4,42.8 50.26,41.66 50.26,41.28 48.75,39.77 48.75,39.24 48.53,39.01 47.95,39.01 v1(47.64,38.71)
  BOTTOM w0.14: v1(19.78,43.51) 19.78,42.67 22.52,39.93 22.52,38 23.18,37.34 25.49,37.34 28.08,39.93 28.35,39.93 28.36,39.93 29.15,39.93 29.43,40.21 30.19,40.21 30.43,39.97 32.62,39.97 32.73,39.85 44.59,39.85 45.38,39.07 46.93,39.07 47.29,38.71 v1(47.64,38.71)
SDIO3_CMD: length 67.8
  TOP w0.14: T13.1 21.77,35.98 21.89,35.87 R548.2 ; T13.1 20.48,36.65 v1(20.06,36.65) 19.73,36.65 19.65,36.58 CN4.2 ; T13.1 20.56,35.4 20.43,35.4 v1(19.96,34.93) ; v1(62.4,59.54) 62.89,60.02 U12.AV28
  IN1 w0.14: v1(49.11,38.79) 49.29,38.96 49.29,39.57 51.17,41.45 51.86,41.45 54.98,44.58 55.46,44.58 56.35,45.47 56.35,48.18 58.31,50.14 58.31,51.66 59.02,52.38 59.02,58.09 59.86,58.93 61.79,58.93 v1(62.4,59.54)
  BOTTOM w0.14: v1(19.96,34.93) 20.11,35.08 25.49,35.08 28.55,38.13 30.2,38.13 30.42,38.35 31.98,38.35 32.48,37.85 39.4,37.85 40.19,37.07 44.84,37.07 45.66,36.25 48.01,36.25 49.05,37.28 49.05,38.72 v1(49.11,38.79)
SDIO3_DATA_0: length 76.1
  TOP w0.14: v1(21.25,48.54) 21.8,48.54 R542.2 ; v1(64,59.64) 64.36,60 U12.AT28
  IN1 w0.102: 64.25,58.37 64.56,58.06 64.56,55.27 64.2,54.92 63.97,54.92
  IN1 w0.14: v1(64,59.64) 64,58.62 64.25,58.37 ; v1(47.64,37.34) 48.89,37.34 51.53,39.98 51.53,40.21 54.5,43.18 54.83,43.18 56.91,45.26 56.91,47.17 58.03,48.29 59.73,48.29 59.91,48.46 59.91,50.11 60.47,50.67 61.08,50.67 61.48,51.08 61.48,53.86 62.54,54.92 63.97,54.92
  BOTTOM w0.14: v1(47.64,37.34) 47.54,37.34 47.21,37.67 46.63,37.67 46.38,37.91 40.48,37.91 39.74,38.65 32.81,38.65 32.28,39.18 30.12,39.18 29.87,38.93 28.2,38.93 25.8,36.53 22.85,36.53 21.71,37.67 21.71,39.57 18.84,42.44 18.84,46.13 v2(20.75,48.04) v1(21.25,48.54)
SDIO3_DATA_0C: length 5.1
  TOP w0.102: R542.1 v1(22.41,50.89)
  TOP w0.14: R542.1 21.63,49.16 T14.1 21.37,49.17 R547.2 19.8,49.17 19.63,49 CN4.7
SDIO3_DATA_1: length 78.4
  TOP w0.102: U12.BD26 59.97,61.02 59.68,61.32 58.77,61.32 58.62,61.17 58.37,61.17 58.11,61.43 58.11,61.56 57.89,61.77 v1(55.74,61.77)
  TOP w0.14: R541.2 21.34,50.84 21.76,50.42 v1(21.84,50.42)
  IN1 w0.14: v1(55.74,61.77) 55.74,58.7 54.86,57.81 54.86,55.45 54.5,55.09 54.5,46.94 52.62,45.06 50.38,45.06 48.95,43.62 48.95,42.15 47.16,40.36 47.16,38.56 47.69,38.02 v1(47.69,37.95)
  BOTTOM w0.14: v1(47.69,37.95) 47.39,37.95 47.16,38.18 40.66,38.18 39.91,38.92 32.92,38.92 32.52,39.32 32.52,39.33 32.4,39.45 30.01,39.45 29.76,39.2 28.09,39.2 25.7,36.8 22.98,36.8 21.99,37.8 21.99,39.7 19.17,42.52 19.17,45.69 19.55,46.08 20.36,46.08 21.71,47.42 v2(21.71,49.46) 21.71,50.29 v1(21.84,50.42)
SDIO3_DATA_1C: length 5.4
  TOP w0.14: T15.1 21.11,53.48 21.34,53.25 R541.1 20.95,51.92 R546.2 20.31,51.92 20.31,51.2 v1(20.06,50.95) 19.8,50.7 CN4.8
SDIO3_DATA_2: length 69.8
  TOP w0.14: v1(19.6,33.2) 20.5,32.3 R540.2 ; U12.AU28 63.65,59.95 v1(63.31,59.61)
  IN1 w0.14: v1(63.31,59.61) 62.3,58.6 59.96,58.6 59.3,57.94 59.3,55.45 60.09,54.66 60.62,54.66 61,54.28 61,51.49 60.47,50.95 60.34,50.95 59.48,50.09 59.48,49.23 59.1,48.84 57.93,48.84 56.63,47.55 56.63,45.36 55.06,43.79 54.58,43.79 51.26,40.48 51.26,40.09 49.12,37.95 v1(48.3,37.95)
  BOTTOM w0.14: v1(19.6,33.2) 19.19,33.6 19.19,35.15 20.29,36.25 v2(20.69,36.25) 25.9,36.25 28.31,38.67 29.98,38.67 30.23,38.91 32.17,38.91 32.7,38.39 39.63,38.39 40.37,37.64 46.19,37.64 46.37,37.47 46.37,37.08 46.68,36.78 47.79,36.78 48.3,37.29 v1(48.3,37.95)
SDIO3_DATA_2C: length 5.9
  TOP w0.14: CN4.9 19.55,31.58 19.87,31.26 19.87,31.04 v1(20.2,30.72) 20.52,30.39 T11.1 21.09,30.98 21.27,31.16 R540.1 22.5,31.57 R545.2
SDIO3_DATA_3: length 71.9
  TOP w0.102: v1(56.15,62.46) 56.15,62.23 56.33,62.05 57.8,62.05 58.03,62.28 58.23,62.28 58.46,62.05 58.46,61.91 58.75,61.62 59.75,61.62 59.91,61.47 59.91,61.47
  TOP w0.14: R544.2 20.58,34.83 20.03,34.29 v1(19.98,34.29) ; U12.BA26 61.03,61.47 59.91,61.47
  IN1 w0.14: v1(47.64,39.37) 47.64,40.28 49.24,41.88 49.24,43.41 50.61,44.78 52.75,44.78 54.78,46.81 54.78,54.92 55.13,55.27 55.13,57.63 56.07,58.57 56.07,61.11 56.4,61.44 56.4,62.18 56.15,62.43 v1(56.15,62.46)
  BOTTOM w0.14: v1(19.98,34.29) 19.63,34.29 19.5,34.42 19.5,35.07 19.79,35.36 25.38,35.36 28.43,38.4 30.09,38.4 30.34,38.65 32.06,38.65 32.59,38.12 39.51,38.12 40.3,37.34 44.95,37.34 45.77,36.51 47.9,36.51 48.78,37.39 48.78,38.51 48.68,38.61 48.68,38.86 48.54,39 48.01,39 v1(47.64,39.37)
SDIO3_DATA_3C: length 5.2
  TOP w0.14: CN4.1 19.58,34.08 v1(20.16,33.5) 20.58,33.5 20.7,33.62 T12.1 22.18,33.62 R549.2 22.34,34.06 22.05,34.36 R544.1
SDIO3_PWR_EN#: length 126.6
  TOP w0.102: R365.2 22.37,51.77 v1(22.39,51.74)
  TOP w0.14: v1(59.73,63.43) 60.1,63.06 U12.BD22
  IN1 w0.102: v1(46.4,64.67) 46.35,64.62 44.11,64.62 42.05,66.68 40.17,66.68 39.69,66.19 39.69,63.48 44,59.16 44,55.55 41.32,52.86 41.32,51.43 40.96,51.07 40.96,48.03 41.39,47.6 41.39,47.09 40.73,46.43 40.73,41.91 40.25,41.43 37.89,41.43 35.88,43.43 34.08,43.43 31.85,41.2 26.51,41.2 25.87,40.56 25.87,37.9 25.51,37.53 24.72,37.53 23.54,36.35 v1(23.54,32.64) 23.54,29.77 24.6,28.7 v1(24.6,27.56)
  BOTTOM w0.102: v1(23.54,32.64) 23.33,32.44 Q51.2 23.33,30.89 23.18,30.73 16.45,30.73 15.71,31.47 14.49,31.47 12.89,33.07 12.89,45.9 15.23,48.23 18.96,48.23 21.12,50.4 21.12,51.16 21.56,51.59 22.24,51.59 v1(22.39,51.74) ; v1(24.6,27.56) 25.14,27.56 25.7,28.12 Q50.2 ; v1(46.4,64.67) 46.55,64.82 48.78,64.82 49.17,64.44 52.37,64.44 52.57,64.24 53.3,64.24 54.08,65.02 55.18,65.02 55.96,65.81 57.71,65.81 58.57,64.95 59.4,64.95 59.73,64.62 v1(59.73,63.43)
SDIO3_RCOMP: length 3.2
  TOP w0.102: v1(57.47,61.01) 57.67,61.01 58,60.68 58.24,60.68 58.36,60.8 58.61,60.8 58.73,60.67 58.95,60.67 59.24,60.96 U12.BF26
  BOTTOM w0.14: v1(57.47,61.01) 57.79,61.33 R293.2
SDVO_CLK: length 64.5
  TOP w0.102: U12.C28 80.27,59.68 v1(80.13,59.54)
  TOP w0.14: Q6.4 60.43,88.66 60.7,88.39 v2(60.7,87.75) 60.7,87.27 61.28,86.69 62.01,86.69 v1(62.45,86.25)
  IN1 w0.14: v1(88.47,66.6) 86.89,65.02 86.17,65.02 84.93,63.78 83.66,63.78 82.57,62.69 82.57,61.98 v1(80.13,59.54)
  BOTTOM w0.14: v1(88.47,66.6) 88.47,67.82 92.21,71.56 92.21,73.74 90.15,75.79 86.23,75.79 86.01,75.58 80.55,75.58 79.99,76.13 76.13,76.13 75,77.26 75,82.59 73.7,83.9 64.76,83.9 62.45,86.21 v1(62.45,86.25) 62.71,86.25 R219.2
SDVO_DATA: length 57.4
  TOP w0.102: v1(80.03,61.52) 80.27,61.27 U12.C26
  TOP w0.14: v1(61.81,86.26) 60.67,86.26 60.67,86.26 60.29,86.26 v2(59.87,86.68) 58.92,87.63 58.92,89.66 58.62,89.96 Q6.1
  IN1 w0.14: v1(80.03,61.52) 81.98,63.47 82.79,63.47 83.53,64.21 84.8,64.21 86.05,65.46 86.71,65.46 v1(87.86,66.6)
  BOTTOM w0.14: R218.2 61.81,86.38 v1(61.81,86.26) 61.84,86.26 64.64,83.46 73.57,83.46 74.61,82.43 74.61,77.1 76.01,75.7 79.87,75.7 80.38,75.18 82.67,75.18 84.57,73.28 84.57,71.37 87.09,68.86 87.09,68.4 87.86,67.63 v1(87.86,66.6)
SENSEA: length 19.9
  TOP w0.14: v1(12.26,75.84) 12.26,75.64 11.88,75.26 R22.1 ; v1(24.39,78.62) 24.26,78.5 U9.13
  IN1 w0.14: v1(24.39,78.62) 24.24,78.62 22.95,79.91 21.58,79.91 19.63,81.86 17.54,81.86 16.81,81.13 14.9,81.13 14.22,80.44 14.22,78.11 12.26,76.15 v1(12.26,75.84)
SERIRQ: length 171.1
  TOP w0.102: U18.125 129.46,47.22 v1(129.41,47.27) ; R83.1 v2(48.66,68.1) 48.05,68.1 47.06,67.11 45.43,67.11 44.14,65.81 44.14,64.9 44.64,64.39 45.2,64.39 46.09,63.5 46.09,63.14 45.86,62.92 42.89,62.92 42.16,62.18 42.16,55.11 43.04,54.22 43.04,51.51 42.51,50.98 v1(42.51,50.6)
  IN2 w0.102: v1(42.51,50.6) 42.51,47.35 41.24,46.08 41.24,41.28 39.77,39.8 39.77,31.62 39.46,31.32 39.46,28.02 44.94,22.54 49.59,22.54 50.38,21.74 61.64,21.74 61.64,21.75 64.98,21.75 65.42,21.31 73.65,21.31 75.73,19.23 81.85,19.23 81.85,19.23 87.54,19.23 88.4,18.38 90.07,18.38 91.1,17.35 94.63,17.35 96.33,15.65 105.63,15.65 107.61,17.63 107.61,19.29 109.82,21.5 109.82,23.18 114.68,28.04 114.68,30.08 118.66,34.06 121.14,34.06 122,34.93 122.05,34.93 122.05,34.93 122.86,34.93 124.46,36.53 125.39,36.53 126.53,37.67 126.53,38.28 127.75,39.5 128.13,39.5 128.54,39.09 129.63,39.09 130.09,39.56 130.09,46.58 v1(129.41,47.27)
SERIRQ_R: length 7.7
  TOP w0.14: R539.1 42.43,49.89 42.14,50.18 U24.4 40.67,50.18 40.45,49.96 v2(40.45,49.25) 40.73,48.97 40.73,48.29 R172.2 39.75,47.3 39.41,47.3 39.18,47.07 39.18,46.13 U16.27
SIO_EXT_SCI#: length 165.8
  TOP w0.102: U18.29 125.72,33.25 125.58,33.39 v1(124.88,33.39) ; v1(49.42,72.43) 49.25,72.26 v2(47.59,72.26) 44.52,72.26 43.73,71.48 43.73,68.05 43.12,67.44 43.12,64.39 44.19,63.32 v1(44.77,63.32)
  IN2 w0.102: v1(44.77,63.32) 44.29,62.84 44.06,62.84 43.32,62.1 43.32,56.6 43.91,56.01 43.91,55.12 40.91,52.12 40.91,47.83 39.26,46.18 39.26,44.89 39.42,44.73 39.42,41.23 38.52,40.34 38.52,37.24 38.05,36.76 38.05,35.36 37.89,35.2 37.89,33.22 37.51,32.83 37.51,26.21 38.09,25.63 38.1,25.63 42.47,21.26 49.09,21.26 50.13,20.22 52.95,20.22 53.43,19.74 61.46,19.74 62.2,20.47 64.46,20.47 64.86,20.07 72.38,20.07 75.49,16.95 82.48,16.95 87.74,16.96 88.87,15.82 93.87,15.82 95.34,14.35 106.14,14.35 108.98,17.19 108.98,18.9 111.06,20.98 111.06,22.66 115.92,27.52 115.92,27.54 115.97,27.59 115.97,29.46 119.27,32.77 120.56,32.77 121.89,31.45 122.8,31.45 124.75,33.39 v1(124.88,33.39)
  BOTTOM w0.102: U26.3 50.71,72.58 50.56,72.43 v1(49.42,72.43) ; v1(124.88,33.39) 124.58,33.1 R395.1
SIO_EXT_SMI#: length 159.8
  TOP w0.102: v1(125.45,41.07) 125.63,41.25 U18.9
  IN2 w0.102: v1(125.45,41.07) 125.92,40.6 125.92,40.34 124.16,38.58 124.16,36.8 122.7,35.33 121.88,35.33 121.83,35.33 120.97,34.47 118.44,34.47 116.8,32.82 114.82,32.82 113.05,31.05 113.05,26.79 109.61,23.36 109.61,21.62 107.4,19.4 107.4,17.7 105.57,15.88 96.49,15.88 94.81,17.55 91.71,17.55 88.9,20.36 74.89,20.36 73.73,21.51 65.5,21.51 64.95,22.07 50.34,22.07 49.67,22.74 49.51,22.74 49.51,22.74 45.1,22.74 39.67,28.17 39.67,31.17 40.07,31.57 40.07,35.23 41.04,36.21 41.04,39.42 41.45,39.83 41.45,46 42.92,47.47 42.92,50.77 42.21,51.48 42.21,51.97 42.92,52.69 43.89,52.69 44.97,53.77 44.97,60.09 46.75,61.87 46.75,63.25 47.92,64.42 47.92,65.1 v1(49.93,67.11)
  BOTTOM w0.102: U26.1 51.16,70.67 51.34,70.5 51.34,68.93 v2(50.25,67.85) 49.93,67.52 v1(49.93,67.11) ; R370.1 124.51,40.97 125.35,40.97 v1(125.45,41.07)
SIO_RCIN#: length 2
  TOP w0.102: TP19.1 130.78,47.83 130.78,47.15 130.66,47.03 U18.122
SLEEVE:
  vias: v1(10.86,72.21) v1(10.86,71.58) v1(15.21,74.98) v1(19.9,79.73) v1(20.51,79.76) v2(19.37,80.19)
SLP_S0IX#: length 22.7
  TOP w0.14: v1(78.67,65.35) 78.67,65.22 U12.F18
  BOTTOM w0.14: Q21.4 93.55,74.47 93.08,74 93.08,71.07 89.67,67.65 89.67,66.58 89.23,66.15 v2(85.67,66.15) 81.57,66.15 81.47,66.05 79.52,66.05 78.82,65.35 v1(78.67,65.35)
SLP_S3#: length 19.8
  TOP w0.14: U12.D22 80.02,63.26 v1(80.02,63.43)
  BOTTOM w0.14: Q23.4 93.55,70.25 93.33,70.03 92.72,70.03 R86.1 90.38,67.26 90.69,66.95 90.69,66.35 89.63,65.28 86.22,65.28 86.05,65.11 84.98,65.11 84.83,64.95 84.19,64.95 83.68,65.46 82.76,65.46 82.64,65.34 81.87,65.34 81.37,64.84 v2(81.23,64.84) 80.73,64.84 80.02,64.13 v1(80.02,63.43)
SLP_S4#: length 47.1
  TOP w0.14: U12.F22 79.36,63.28 v1(79.36,63.43) ; v1(92.75,59.08) 92.75,58.57 92.32,58.14 v2(92.32,57.5) 92.32,56.62 92.93,56.01 95.19,56.01 96.13,56.95 98.04,56.95 v1(98.14,56.85)
  IN1 w0.14: v1(79.36,63.43) 79.82,62.97 80.74,62.97 81.76,63.99 82.5,63.99 v1(83.46,64.95)
  IN2 w0.14: v1(94.83,66.37) 94.6,66.61 90.98,66.61 90.07,67.51 83.96,67.51 83.46,67.01 v1(83.46,64.95)
  BOTTOM w0.14: Q53.2 92.85,57.68 93.13,57.96 93.13,58.42 92.75,58.8 v1(92.75,59.08) ; R87.1 95.33,70.2 94.85,69.71 Q23.1 94.85,68.57 95.24,68.17 95.24,67.67 94.83,67.26 94.83,66.4 ; 94.83,66.4 94.83,66.39 94.83,65.93 96.28,64.49 96.28,62.26 97.69,60.85 97.69,58.61 97.91,58.39 97.91,57.07 v1(98.14,56.85) ; 94.83,66.4 v1(94.83,66.37)
SLP_SUS#_EC: length 71.2
  TOP w0.102: U18.79 141.59,37.65 141.06,38.18 141.06,38.71 139.36,40.41 138.57,40.41 137.38,39.22 v1(137.38,38.91)
  IN2 w0.102: v1(137.38,38.91) 137.02,39.27 134.71,39.27 133.91,40.07 133.91,41.14 132.91,42.15 132.91,46.65 133.49,47.23 133.49,47.57 131.91,49.15 131.65,49.15 130.12,50.68 129.38,50.68 126.81,53.25 126.81,53.99 125.63,55.17 122.28,55.17 119.39,58.06 116.01,58.06 113.55,60.52 113.55,60.79 110.05,64.29 108.91,64.29 107.11,66.09 106.26,66.09 104.82,67.54 102.48,67.54 100.78,69.24 99.09,69.24 96.68,71.65 v1(96.21,71.65)
  BOTTOM w0.102: v1(96.21,71.65) 96.1,71.76 R241.2 95.72,72.29 95.68,72.33 v1(94.88,72.33) 94.03,72.33 93.55,72.81 Q21.3
SLP_SUS_ON: length 193.7
  TOP w0.102: U18.96 141.47,44.45 141.41,44.51 141.41,44.8 143.63,47.02 v1(144.11,47.02)
  IN1 w0.102: v1(28.52,36.14) 28.01,35.64 26.61,35.64 25.49,34.52 25.49,26.75 28.92,23.32 28.92,18.03 30.83,16.13 36.83,16.13 37.17,16.47 37.17,18.05 37.58,18.47 37.58,21.92 38.28,22.62 42.26,22.62 42.26,22.62 42.43,22.62 43.32,21.73 43.32,20.9 46.88,17.35 49.95,17.35 50.64,16.66 59.83,16.66 61.62,18.44 64.09,18.44 65.61,19.96 75.61,19.96 77.19,18.39 79.31,18.39 80.07,17.63 88.54,17.63 89.22,16.94 90.57,16.94 90.92,16.59 93.87,16.59 94.93,15.52 106.15,15.52 108.29,17.66 108.29,20.64 111.58,23.94 111.58,33.69 110.77,34.51 110.77,35.67 111.28,36.19 112.39,36.19 114.34,34.24 121.35,34.24 122.19,35.08 122.42,35.08 123.89,36.55 125.62,36.55 126.64,37.57 126.64,38.68 127.63,39.68 127.63,41.68 129.15,43.21 129.15,44.86 129.59,45.29 133.81,45.29 134.09,45.57 135.73,45.57 135.9,45.4 141.79,45.4 143.41,47.02 v1(144.11,47.02)
  BOTTOM w0.102: v1(144.11,47.02) 144.11,47.52 145,48.41 R343.1 ; v1(28.52,36.14) 28.52,36.53 28.94,36.96 29.73,36.96 30.17,37.39 31.03,37.39 31.87,36.55 35.65,36.55 v2(35.92,36.28) 36.47,35.73 PR159.1
SMB_RUN_CLK: length 277.9
  TOP w0.14: v1(40.78,28.5) 40.96,28.32 43.98,28.32 44.96,27.35 JDIM6.202 44.96,25.18 43.75,23.98 43.12,23.98 40.2,21.06 40.2,18.39 v1(40.43,18.16) ; v1(44.42,74.06) R67.1 45.44,74.05 Q40.3
  IN1 w0.14: v1(40.43,18.16) 41.85,18.16 48.16,11.85 54.87,11.85 56.59,10.13 65.77,10.13 66.48,10.84 66.61,10.84 66.61,10.84 77.62,10.84 79.49,8.97 83.79,8.97 84.57,9.75 85.89,9.75 86.39,9.25 86.41,9.25 87.1,8.56 108.5,8.56 120.13,20.19 120.13,21.49 121.76,23.11 121.76,25.2 123.08,26.52 126.91,26.52 127.8,25.63 129.74,25.63 130.61,26.5 135.5,26.5 136.39,27.38 139.77,27.38 140.28,27.89 142.79,27.89 144.29,26.39 147.31,26.39 148.44,27.51 148.44,29.35 148.77,29.69 149.25,29.69 149.53,29.41 155.15,29.41 156.31,30.56 156.31,31.11 160.78,35.58 160.78,46.66 160.78,46.66 160.78,47.08 162.6,48.9 162.6,54.58 161.92,55.27 161.92,63.19 161.52,63.59 161.52,65.78 159.92,67.38 159.92,72.22 161.26,73.57 161.26,75.93 164.35,79.01 164.99,79.01 165.29,79.31 165.29,79.41 v1(165.41,79.53) ; v1(41.8,65.05) 41.8,62.54 44.75,59.59 44.75,54.25 43.48,52.98 42.92,52.98 42.05,52.11 42.05,50.35 42.4,49.99 42.4,46.65 41.53,45.78 41.53,41.67 41.47,41.61 41.47,41.61 39.44,39.57 39.44,38.23 40.53,37.14 40.53,30.18 40.78,29.92 v1(40.78,28.5)
  IN2 w0.14: v1(41.8,65.05) 41.8,66.02 43.76,67.98 43.76,71.65 43.96,71.86 43.96,73.6 v1(44.42,74.06)
  BOTTOM w0.14: Q16.1 157.31,83.68 156.79,84.2 156.79,84.81 157.9,85.93 163.08,85.93 164.84,84.18 v2(164.84,83.57) 164.84,80.22 165.41,79.65 v1(165.41,79.53)
SMB_RUN_DAT: length 276.4
  TOP w0.14: v1(41.11,30.33) 42.36,29.08 43.98,29.08 45.56,27.51 JDIM6.200 45.56,24.97 43.86,23.27 43.2,23.27 40.83,20.9 40.83,19.18 v1(40.66,19) ; R62.1 46.07,76.56 v1(46.07,77.65) 46.83,77.65 49.13,75.35 Q40.6
  IN1 w0.14: v1(41.11,30.33) 41.11,37.29 40.02,38.38 40.02,39.17 42.05,41.2 42.05,45.57 43.05,46.56 43.05,47.45 43.06,47.46 43.06,51.84 45.27,54.04 45.27,54.06 45.28,54.08 45.28,59.79 43.06,62.01 43.06,64.71 42,65.76 v1(41.27,65.76) ; v1(40.66,19) 41.75,19 48.38,12.37 55.08,12.37 56.8,10.65 65.56,10.65 66.72,11.81 77.46,11.81 79,10.27 86.78,10.27 87.95,9.09 108.3,9.09 119.52,20.32 119.52,21.95 121.1,23.53 121.1,25.32 122.83,27.05 127.27,27.05 128.17,26.15 129.49,26.15 130.37,27.03 133.44,27.03 134.18,27.77 135.91,27.77 136.06,27.91 139.49,27.91 140,28.42 142.99,28.42 144.49,26.92 147.11,26.92 147.91,27.73 147.91,29.13 147.91,30.08 148.74,30.91 149.58,30.91 150.56,29.93 154.94,29.93 155.79,30.78 155.79,31.32 159.69,35.22 159.69,46.87 161.94,49.12 161.94,54.51 161.4,55.05 161.4,62.97 160.27,64.1 160.27,66.14 159.28,67.13 159.28,72.6 160.74,74.06 160.74,76.14 164.3,79.71 164.59,79.71 v1(164.77,79.53)
  IN2 w0.14: v1(41.27,65.76) 41.27,66.22 43.15,68.1 43.15,71.78 43.44,72.07 43.44,73.82 43.45,73.83 43.45,75.59 42.92,76.12 42.92,76.78 43.25,77.11 45.53,77.11 v1(46.07,77.65)
  BOTTOM w0.14: v1(164.77,79.53) 164.3,80 164.3,83.17 163,84.47 162.81,84.47 v2(162.47,84.81) 162.31,84.98 Q16.4
SMB_SOC_ALERTB_C: length 4.7
  TOP w0.102: 56.61,68.1 56.71,67.99 57.91,67.99 58.02,68.1 58.31,68.1 U12.BG11
  TOP w0.14: R80.2 54.79,68.68 56.02,68.68 56.61,68.1
SMB_SOC_CLK: length 11.7
  TOP w0.14: U12.BH10 57.94,68.95 57.56,68.95 57.12,69.39 55.49,69.39 54.71,70.17 52.52,70.17 52.51,70.17 52.46,70.17 52.45,70.15 52.17,70.43 R73.2 52.17,71.54 v2(51.96,71.76) 49.66,74.05 Q40.4
SMB_SOC_DATA: length 18.4
  TOP w0.102: 57.77,68.71 58.01,68.47 58.25,68.47 58.37,68.58 58.59,68.58 58.83,68.35 U12.BG12
  TOP w0.14: 57.77,68.71 57.41,68.71 57.08,69.04 55.11,69.04 54.5,69.65 53.77,69.65 53.76,69.65 52.74,69.65 52.73,69.65 52.68,69.65 R79.2 51.64,69.67 50.13,69.67 v2(50.11,69.7) 49.93,69.88 49.93,71.45 50.23,71.76 50.23,72.75 49.47,73.51 48.77,73.51 48.38,73.9 48.38,75.06 48.08,75.35 Q40.1
SMC: length 3.3
  BOTTOM w0.14: PJ7.4 71.12,13.33 71.32,13.53 71.34,13.53 71.34,14.02 v2(71.22,14.14) 71.07,14.29 70.36,14.29 70.2,14.45 PR179.1
SMD: length 4
  BOTTOM w0.14: PR180.1 74.13,14.88 v2(73.93,14.68) 73.93,14.5 73.11,13.68 PJ7.3
SOC_CLKOUT_0: length 7.3
  TOP w0.102: 57.75,65.91 57.78,65.91 58.21,66.34 58.48,66.34 U12.BG15
  TOP w0.14: R98.2 52.82,66.85 53.05,66.62 53.87,66.62 R90.2 54.95,67.08 55.56,66.47 55.72,66.47 56.29,65.9 57.74,65.9 57.75,65.91
SOC_CLKOUT_1: length 3.9
  TOP w0.14: U12.BH14 58.08,66.77 57.05,66.77 v1(56.61,66.33)
  BOTTOM w0.14: v1(56.61,66.33) 55.75,66.33 55.11,65.68 R274.2
SOC_CLKRUN#: length 5.4
  TOP w0.102: U12.BG16 58.54,65.84 58.13,65.43 58.13,65.28 57.88,65.04 57.79,65.04 v1(57.62,64.87)
  BOTTOM w0.14: v1(57.62,64.87) 57.62,64.27 57.44,64.08 56.23,64.08 56.15,64.16 R167.1 R279.2
SOC_CORE_PIN_AA22: length 1.8
  TOP w0.102: v1(71.89,63.15) 71.52,62.79 U12.AA22
  BOTTOM w0.102: v1(71.89,63.15) 71.89,63.31 72.64,64.06 TP25.1
SOC_CORE_PINAF30: length 2.4
  TOP w0.102: v1(68.78,58.6) 69.15,58.98 U12.AF30
  BOTTOM w0.102: v1(68.78,58.6) 68.77,58.6 68.36,58.19 67.73,58.19 67.33,58.6 TP26.1
SOC_DDIO_RCOMP: length 1.6
  TOP w0.102: U12.AK13 66.71,67.81 v1(66.63,67.81)
  BOTTOM w0.102: v1(66.63,67.81) 67.3,67.81 R264.1
SOC_DDIO_RCOMP_P: length 1.6
  TOP w0.102: v1(66.63,68.47) 66.77,68.47 U12.AK12
  BOTTOM w0.102: v1(66.63,68.47) 67.42,68.47 R264.2
SOC_DRAM_PWROK: length 27.5
  TOP w0.102: U12.AD42 70.06,52.88 v1(70.49,52.45)
  IN2 w0.102: v1(70.49,52.45) 71.11,53.07 71.11,54.76 71.4,55.04 72.97,55.04 73.09,54.92 73.73,54.92 74.11,55.3 74.11,55.91 74.69,56.49 75.99,56.49 76.63,57.13 80.07,57.13 80.73,57.79 80.73,58.11 81.6,58.98 88.13,58.98 88.26,59.11 88.91,59.11 89.91,58.11 v1(89.91,57.61)
  BOTTOM w0.102: v1(89.91,57.61) 89.91,57.2 89.76,57.06 C256.1 89.5,58.02 R315.1
SOC_GPIO_RCOMP: length 1.4
  TOP w0.102: v1(75.95,61.49) 75.77,61.31 75.77,61.28 U12.N26
  BOTTOM w0.102: v1(75.95,61.49) 75.95,62.03 R299.2
SOC_GPOI7: length 19.7
  TOP w0.102: R36.1 91.61,74.73 v2(91.93,74.4) 91.99,74.35 91.99,70.49 89.83,68.33 87.34,68.33 86.07,69.6 84.98,69.6 83.18,67.8 83.18,67.71 82.46,67 81.86,67 81.61,66.75 81.34,66.75 81.06,66.47 80.77,66.47 U12.C15
SOC_JTAG2_TCK: length 5.3
  TOP w0.102: R60.1 84.77,68.34 83.58,67.16 83.58,66.71 82.84,65.97 81.79,65.97 81.66,65.84 81.12,65.84 81.11,65.84 U12.B16
SOC_JTAG2_TDI: length 4.8
  TOP w0.102: R81.1 84.62,67.54 83.99,66.9 83.99,66.48 83.07,65.56 81.97,65.56 81.85,65.43 81.71,65.43 81.7,65.43 81.45,65.43 U12.A17
SOC_JTAG2_TDO: length 10.1
  TOP w0.102: U12.C17 80.77,65.36 80.78,65.37 80.93,65.37 81.2,65.64 81.75,65.64 81.8,65.68 81.81,65.68 81.89,65.76 82.92,65.76 83.79,66.62 83.79,67.03 84.7,67.95 87.38,67.95 R61.1 88.43,67.39 v1(88.94,67.89)
SOC_JTAG2_TMS: length 7.8
  TOP w0.102: R88.1 85,65.88 85,66.93 84.9,67.03 84.42,67.03 84.19,66.8 84.19,66.08 83.47,65.36 82.06,65.36 81.93,65.23 81.68,65.23 81.53,65.08 81.2,65.08 81.11,65.16 80.87,65.16 80.73,65.03 80.44,65.03 U12.C18
SOC_KBC_SCI: length 5
  BOTTOM w0.102: U26.4 53.65,72.58 v2(54.14,72.09) 54.74,71.49 R243.1 55.06,70.89 55.57,70.38 55.85,70.38 56.34,69.88 R252.2
SOC_KCB_SMI: length 52.7
  TOP w0.102: R36.2 91.61,77.11 90.85,77.88 v1(89.58,77.88)
  IN2 w0.102: v1(89.58,77.88) 89.09,77.39 86.33,77.39 85.59,78.13 83.73,78.13 81.93,76.33 74.69,76.33 72.84,74.47 69.33,74.47 68.8,75.01 65.65,75.01 65.32,75.34 62.32,75.34 61.99,75.67 60.09,75.67 59.5,75.08 57.95,75.08 57.14,75.9 55.01,75.9 54.83,76.07 50.94,76.07 50.67,76.35 v1(50,76.35)
  BOTTOM w0.102: v1(50,76.35) 50.13,76.23 v2(50.13,75.62) 49.88,75.36 49.88,74.46 R256.1 51.16,73.18 51.27,73.18 51.76,72.7 51.76,71.92 52.39,71.28 U26.6
SOC_OVERRIDE: length 47.9
  TOP w0.102: v1(60.46,59.54) 60.81,59.19 U12.BC30
  IN1 w0.102: v1(60.46,59.54) 61.08,60.15 62.91,60.15 63.24,60.48 64.61,60.48 67.02,62.89 68.9,62.89 69.74,62.05 70.83,62.05 70.86,62.02 72.09,62.02 72.58,62.52 72.58,62.87 73.99,64.27 80.48,64.27 81.48,65.27 82.39,65.27 82.48,65.35 83.71,65.35 84.29,64.77 84.65,64.77 86.17,66.29 86.17,66.7 86.47,67.01 89.27,67.01 89.5,66.78 89.5,66.27 89.43,66.19 89.43,65.89 89.83,65.48 92.37,65.48 92.66,65.78 94.03,65.78 94.14,65.89 98.47,65.89 v1(98.64,65.71)
  BOTTOM w0.102: Q24.3 98,67.43 98.39,67.03 98.39,65.96 v1(98.64,65.71)
SOC_OVERRIDE_NM: length 2.2
  BOTTOM w0.102: R283.1 98,64.87 v1(97.75,65.13) 97.35,65.52 Q24.5
SOC_PCIE_COMN: length 4.4
  TOP w0.102: v1(64.71,67.95) 64.71,67.43 64.89,67.26 65.05,67.26 U12.AP13
  BOTTOM w0.102: R263.2 65.6,69.23 65.6,67.87 65.27,67.54 64.78,67.54 64.63,67.69 64.63,67.87 v1(64.71,67.95)
SOC_PCIE_COMP: length 6
  TOP w0.102: v1(63.84,67.76) 64.3,67.76 64.53,67.53 64.53,67.36 U12.AP14
  BOTTOM w0.102: R263.1 65.78,69.26 65.78,67.8 65.34,67.36 64.71,67.36 64.31,67.76 v1(63.84,67.76)
SOC_PLTRST#: length 35.8
  TOP w0.14: v1(78.67,63.43) 78.67,63.56 U12.F20
  IN2 w0.14: v1(90.16,66.5) 90.39,66.27 94.18,66.27 94.52,65.92 96.98,65.92 97.3,66.24 99.61,66.24 100.17,65.68 v1(100.17,65.35)
  BOTTOM w0.14: Q21.1 95.07,73.45 95.7,72.82 96.59,72.82 96.64,72.87 96.97,72.87 98.05,71.79 98.05,70.05 98.81,69.3 98.81,67.57 100.17,66.21 v1(100.17,65.35) ; v1(90.16,66.5) 89.34,65.67 86.06,65.67 86.02,65.63 85.03,65.63 84.81,65.85 82.6,65.85 82.48,65.73 81.71,65.73 81.63,65.65 80.99,65.65 78.76,63.43 v1(78.67,63.43)
SOC_PMC_WAKE: length 25.5
  TOP w0.102: v1(78.55,61.49) 78.96,61.07 U12.F26
  BOTTOM w0.102: v1(78.55,61.49) 78.55,60.7 78.97,60.28 81.88,60.28 82.47,60.87 84.32,60.87 R295.2 85.08,61.62 86.08,61.62 86.22,61.76 86.6,61.76 87.8,60.55 88.29,60.55 88.6,60.86 89.12,60.86 89.83,61.57 95.03,61.57 95.27,61.81 95.27,62.89 v2(94.23,63.93) 93.72,64.44 92.75,64.44 92.16,65.03 U25.4
SOC_PROCHOT#: length 13.9
  TOP w0.102: U12.C24 80.58,61.96 80.87,62.25 81.11,62.25 81.2,62.16 81.62,62.16 81.87,61.91 82.25,61.91 82.36,62.03 82.52,62.03
  TOP w0.14: 82.52,62.03 83.3,62.03 83.56,61.77 84.11,61.77 84.53,62.18 86.02,62.18 86.17,62.03 86.9,62.03 87.33,61.59 87.94,61.59 88.1,61.76 88.1,62.12 88.33,62.35 89.55,62.35 R128.2 90.14,61.75 R130.2 91.4,62.09 v2(92.02,62.71)
SOC_PWR_BUT: length 9.1
  TOP w0.102: U12.N3 75.39,72.86 75.68,73.15 75.68,73.62 74.43,74.88 73.27,74.88 v2(71.7,76.45) 72.13,76.89 72.13,77.8 72.64,78.31 R48.1
SOC_PWRBTN#: length 19.1
  TOP w0.14: v1(77.31,61.49) 77.6,61.2 U12.J26
  BOTTOM w0.102: v1(77.31,61.49) 77.72,61.9 78.77,61.9 78.96,61.72 78.96,61.21 78.96,61.2
  BOTTOM w0.14: 78.96,61.2 78.96,61.02 79.31,60.67 81.94,60.67 82.36,61.09 82.96,61.09 83.33,61.46 84.08,61.46 84.48,61.85 85.84,61.85 85.99,62 87.19,62 87.52,62.33 87.52,63.34 R280.1 89.05,64.87 89.81,64.87 91.27,66.33 U25.6
SOC_REST_BTN: length 6.1
  TOP w0.102: 55.81,70.35 56.01,70.35 56.58,69.77 57.82,69.77 58.39,69.2 U12.BG9
  TOP w0.14: 55.81,70.35 55.35,70.35 54.86,70.84 R74.2 54.36,71.39 v2(53.89,71.86)
SOC_RTEST#: length 159.2
  TOP w0.14: U12.C11 80.59,68.31 v1(80.13,68.31)
  IN2 w0.14: v1(96.03,67.08) 95.6,67.51 95.14,67.51 95.02,67.39 92.92,67.39 92.58,67.73 92.58,67.93 92.11,68.41 91.01,68.41 90.76,68.16 84.84,68.16 82.55,70.45 81.94,70.45 80.13,68.63 v1(80.13,68.31)
  BOTTOM w0.14: R415.2 C336.1 38.07,7.1 37.93,6.96 36.45,6.96 36.29,6.79 G7.1 40.81,5.79 v2(42.66,7.65) 46.19,7.65 46.37,7.82 55.61,7.82 60.49,12.7 60.49,15.21 62.53,17.25 65.04,17.25 67.76,19.97 79.6,19.97 80.6,20.96 86.32,20.96 90.81,25.45 109.21,25.45 112.63,28.86 112.63,31.66 111.17,33.11 111.17,36.49 108.35,39.32 108.35,40.43 106.73,42.04 106.73,43.19 105.98,43.95 103.87,43.95 98.01,49.8 98.01,54.28 99.05,55.31 99.05,57.44 99.61,58 99.61,60.15 96.94,62.81 96.94,64.8 96.31,65.43 96.31,65.52 95.63,66.2 95.63,66.68 v1(96.03,67.08)
SOC_SENS_HUB_RST#: length 13
  TOP w0.102: TP35.1 53.74,55.55 54.96,55.55 56.48,57.08 56.96,57.08 57.21,57.33 57.21,57.78 57.5,58.07 57.71,58.07 58.01,58.36 58.25,58.36 58.35,58.26 58.61,58.26 58.71,58.36 59.38,58.36 59.61,58.6 63.83,58.6 U12.AT32
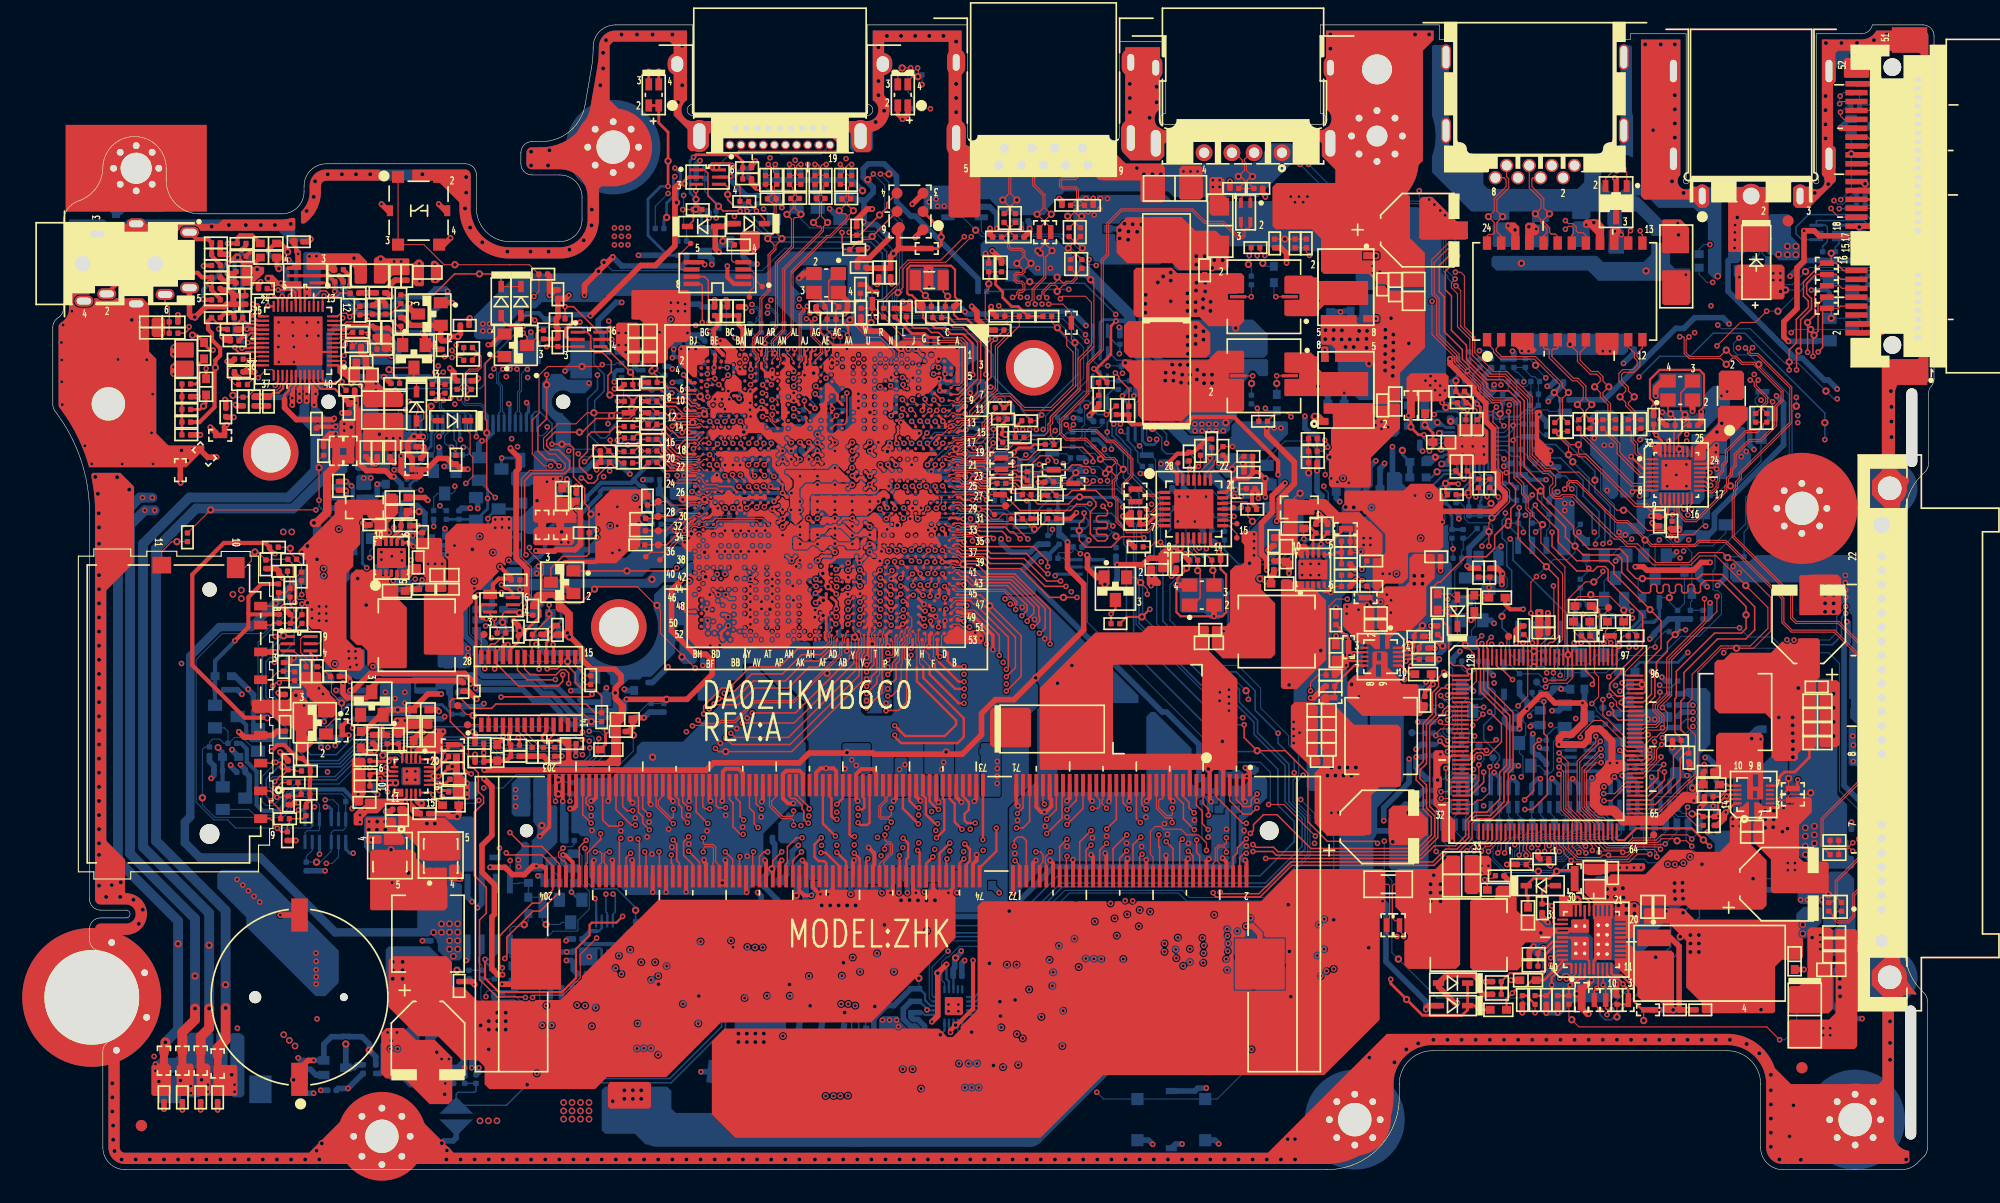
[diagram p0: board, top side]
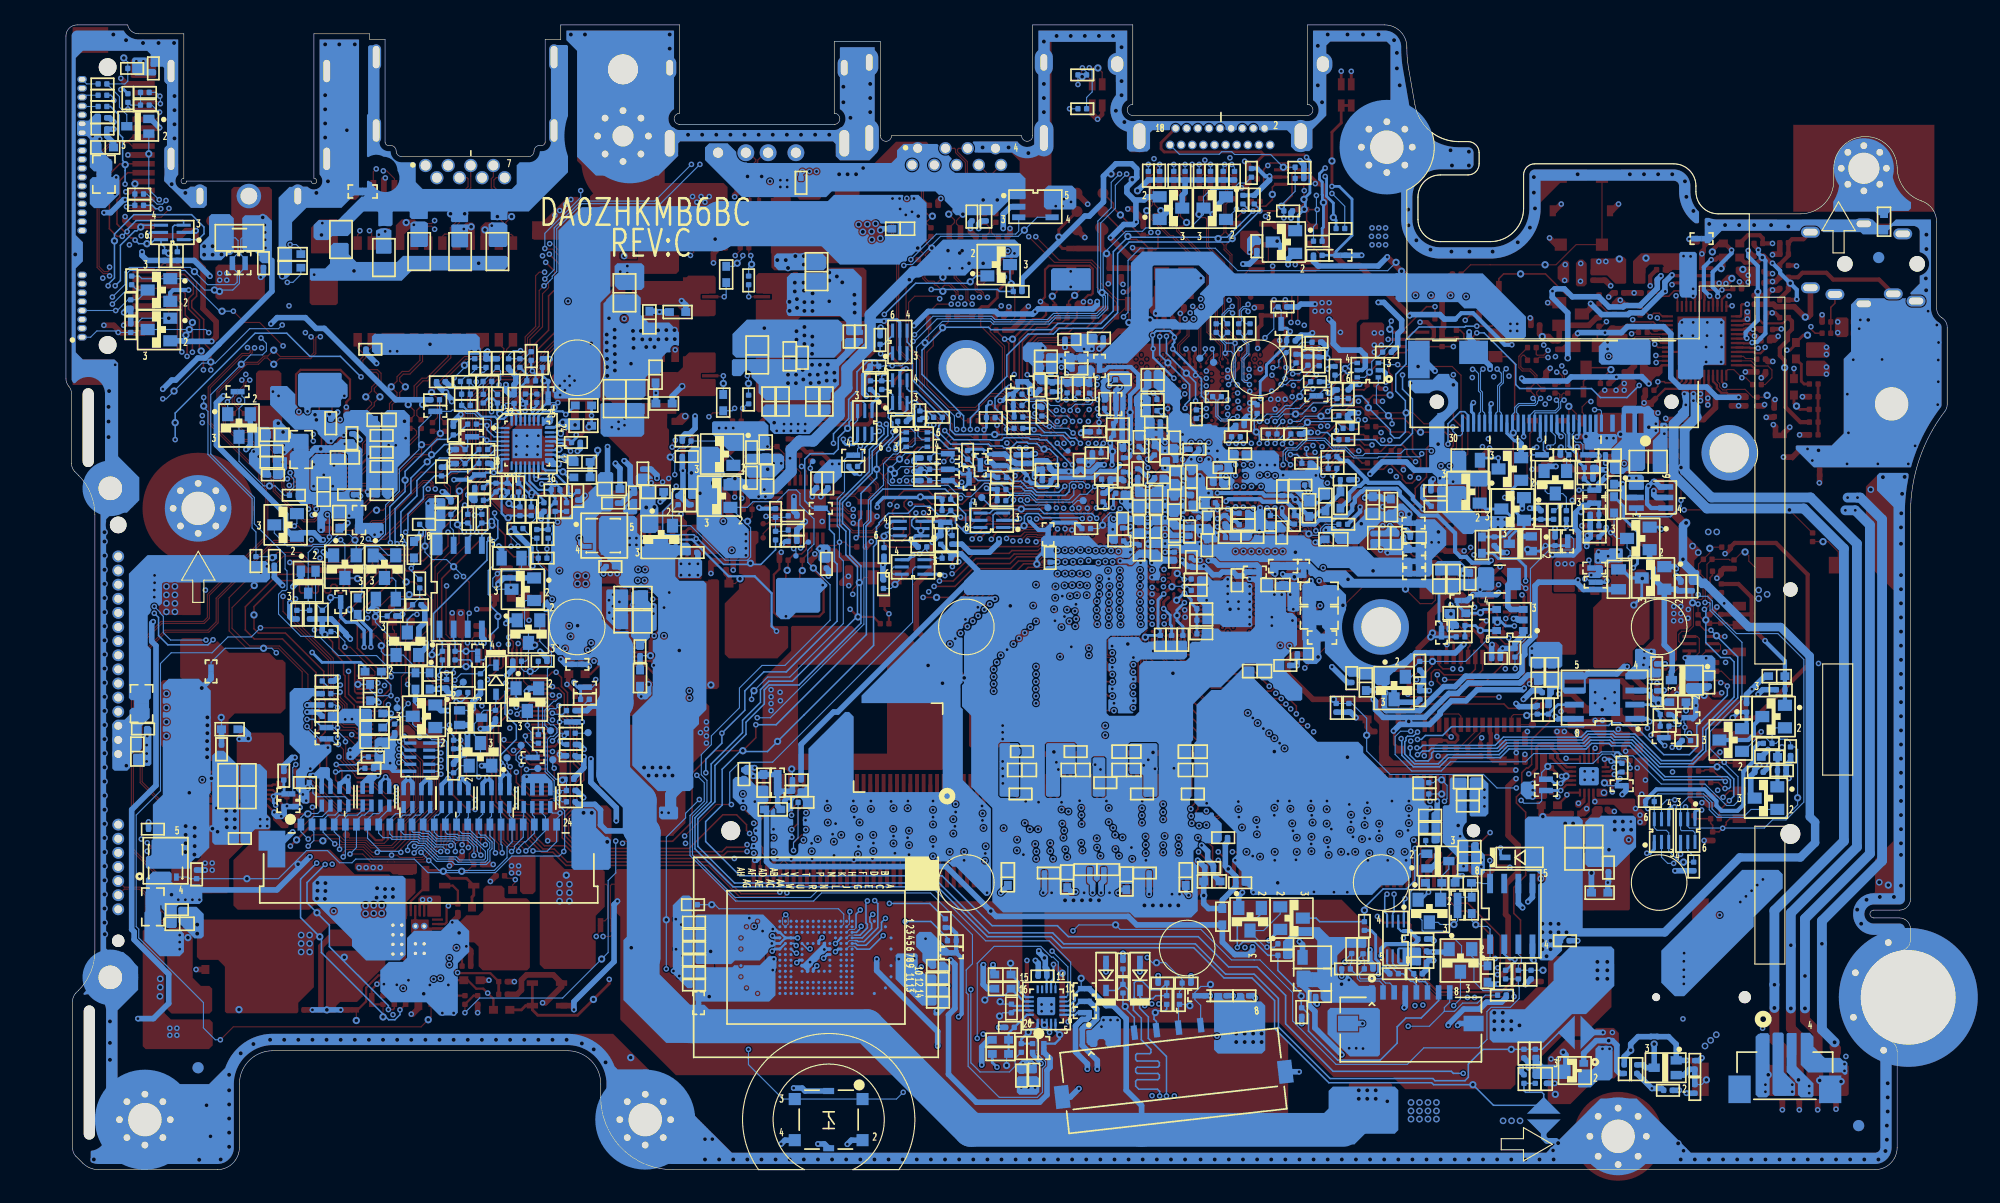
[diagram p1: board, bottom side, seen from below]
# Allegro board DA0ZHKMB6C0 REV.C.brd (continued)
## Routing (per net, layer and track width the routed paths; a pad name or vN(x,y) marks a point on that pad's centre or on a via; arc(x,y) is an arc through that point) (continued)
SOC_SENSOR_HUB_WAKE: length 5.4
  TOP w0.102: v1(59.09,67.32) 59.42,66.99 U12.BF14
  BOTTOM w0.102: v1(59.09,67.32) 58.21,67.32 57.74,67.79 v2(56.33,67.79) 56.15,67.62 54.94,67.62 R265.2
SOC_SERIRQ: length 40.3
  TOP w0.102: U12.BG13 58.32,67.47 58.03,67.47 57.91,67.59 56.1,67.59
  TOP w0.14: 56.1,67.59 55.59,67.59 55.08,68.1 R84.2 53.8,68.62 52.7,68.62 R83.2 52.17,67.9 51.85,67.59 50.3,67.59 50.29,67.59 50.28,67.59 50.28,67.59 48.86,67.59 47.63,66.35 v2(47.37,66.35) 45.16,66.35 44.42,65.61 44.42,65.12 44.77,64.77 45.48,64.77 46.47,63.78 46.47,63.07 46.04,62.64 43.07,62.64 42.43,62 42.43,55.45 v1(42.56,55.32) ; U24.3 39.33,49.96 v1(39.71,49.58) 39.71,49.01 39.96,48.75 R172.1
  IN2 w0.14: v1(42.56,55.32) 42.13,55.32 39.71,52.9 v1(39.71,49.58)
SOC_SPI_CLK: length 4.9
  TOP w0.102: 82.97,63.2 82.91,63.13 81.2,63.13 81.11,63.22 80.86,63.22 80.57,62.93 U12.C22
  TOP w0.14: 82.97,63.2 83.05,63.27 83.73,63.27 83.99,63.02 R121.2
SOC_SPI_CLK_R: length 62.1
  TOP w0.14: R121.1 85.91,63.23 86.53,63.23 86.66,63.35 87.91,63.35 88.8,64.24 89.72,64.24 v1(90.24,63.72)
  IN1 w0.14: v1(90.24,63.72) 90.24,63.72 90.24,62.31 90.68,61.86 90.88,61.86 91.18,62.16 91.38,62.16 91.57,61.96 91.57,61.76 91.28,61.47 91.28,61.27 91.58,60.96 92.09,60.96 92.45,61.32 92.45,61.85 91.91,62.38 91.91,63.37 92.56,64.01 92.56,64.02 92.69,64.16 94.51,64.16 94.71,63.95 100.61,63.95 101.98,62.58 109.56,62.58 110.03,62.11 110.38,62.11 110.62,62.35 111.52,62.35 113.82,60.06 114.99,60.06 115.95,59.1 117.46,59.1 118.11,58.45 119.18,58.45 119.83,57.81 125.54,57.81 125.75,57.61 127.1,57.61 127.35,57.86 132.04,57.86 132.05,57.84 132.9,57.84 v1(133.37,57.38)
  BOTTOM w0.14: v1(133.37,57.38) 133.44,57.38 133.99,57.92 v2(133.99,58.04) 133.85,58.18 R311.1 132.81,57.93 132.81,57.05 133.06,56.79 U22.6
SOC_SPI_CLK_R1: length 25.7
  TOP w0.14: v1(133.34,59.79) 133.34,59.61 135.4,57.55 135.4,56.44 137.05,54.79 139.92,54.79 140.41,54.3 140.41,53.64 v2(143.65,50.39) 144.64,49.4 144.64,46.89 143.23,45.47 143.23,43.01 143.07,42.85 U18.92
  BOTTOM w0.14: v1(133.34,59.79) 133.06,59.51 R311.2
SOC_SPI_CS#: length 9.9
  TOP w0.102: 82.56,62.68 82.51,62.72 81.2,62.72 81.03,62.56 80.75,62.56 U12.C23
  TOP w0.14: R120.2 89.05,62.97 88.88,62.8 R305.2 86.88,62.8 86.74,62.93 86.35,62.93 86.01,62.59 84.59,62.59 84.01,62.01 83.66,62.01 83.04,62.62 82.61,62.62 82.56,62.68
SOC_SPI_CS#_R: length 60
  TOP w0.14: v1(93.58,62.84) 93.16,63.26 92.54,63.26 92.39,63.41 91.67,63.41 91.23,62.97 R120.1
  IN1 w0.14: v1(93.58,62.84) 93.86,63.12 98.94,63.12 99.21,62.85 99.21,62.85 99.29,62.78 99.98,62.78 99.98,62.77 100.58,62.77 100.58,62.78 100.63,62.78 101.64,61.77 109.22,61.77 110.05,60.93 111.34,60.93 113.46,58.81 113.46,58.8 113.71,58.55 113.72,58.55 113.77,58.5 115.4,58.5 116.26,57.64 118.85,57.64 119.58,56.91 122.31,56.91 122.82,56.4 122.85,56.4 122.85,56.39 123.2,56.39 123.35,56.54 123.59,56.78 127.95,56.78 128.09,56.92 130.91,56.92 v1(131.08,56.74)
  BOTTOM w0.14: v1(131.08,56.74) 131.33,56.49 131.33,54.84 136.14,50.04 136.14,46.86 136.29,46.71 v2(136.29,46.33) 135.66,46.33 R354.1 135.35,47.42 135.6,47.68 U22.1
SOC_SPI_CS#_R1: length 18.9
  TOP w0.14: U18.90 143.06,42.05 143.78,42.77 143.78,44.83 v1(143.79,44.84)
  IN1 w0.14: v1(135.58,44.48) 139.18,44.48 139.77,43.89 140.15,43.89 140.78,44.53 141.95,44.53 142.43,44.04 143.76,44.04 144.8,45.09 145.15,45.09 145.36,45.29 145.36,45.72 145.15,45.92 144.87,45.92 143.79,44.84 v1(143.79,44.84)
  BOTTOM w0.14: R354.2 135.35,45.24 135.58,45.01 v1(135.58,44.48)
SOC_SPI_MISO: length 68.9
  TOP w0.102: U12.B22 83.24,62.93
  TOP w0.14: 83.24,62.93 83.34,62.93 v1(83.84,62.43)
  IN1 w0.14: v1(83.84,62.43) 84.24,62.84 86.17,62.84 86.37,63.04 87.47,63.04 89.06,64.63 92.46,64.63 92.54,64.71 93.89,64.71 94.44,65.26 95.81,65.26 96.19,64.88 100.98,64.88 101.87,63.98 107.42,63.98 107.78,63.62 111.54,63.62 114.19,60.97 116.88,60.97 117.77,60.09 119.29,60.09 120.57,58.81 124.78,58.81 124.97,58.99 127.63,58.99 127.71,59.08 v1(130.65,59.08)
  BOTTOM w0.14: v1(130.65,59.08) 130.65,58.7 130.36,58.41 130.36,56.83 130.78,56.41 130.78,54.33 131.21,53.9 131.21,51.77 131,51.56 131,50.72 130.34,50.06 v2(130.34,49.78) 130.34,48.77 131,48.11 131,46.48 131.62,45.86 R352.2
SOC_SPI_MISO_R: length 4.1
  BOTTOM w0.14: U22.2 134.33,47.68 134.2,47.55 R353.1 v2(133.21,46.64) R352.1
SOC_SPI_MISO_R1: length 23.7
  TOP w0.14: U18.86 140.78,40.45 140.37,40.86 140.37,41.32 140.2,41.5 v1(140.2,41.83)
  IN1 w0.14: v1(144.52,43.6) 142.32,43.6 141.7,44.22 140.94,44.22 140.64,43.93 140.64,43.65 v1(140.55,43.56) 140.5,43.51 140.2,43.51 140.12,43.59 139.64,43.59 139.06,44.17 136.41,44.17 136.26,44.01 135.34,44.01 135.2,43.87 135.2,43.47 135.06,43.33 134.89,43.33 134.75,43.47 134.75,44.31 v1(134.36,44.7)
  IN2 w0.14: v1(140.2,41.83) 140.48,42.11 140.48,43.49 v1(140.55,43.56)
  BOTTOM w0.14: R353.2 132.88,45.86 132.73,45.72 132.73,45.39 132.86,45.26 v2(133.21,45.26) 134.13,45.26 134.36,45.03 v1(134.36,44.7) ; R362.2 145.56,43.38 144.74,43.38 v1(144.52,43.6)
SOC_SPI_MOSI: length 3.9
  TOP w0.14: R116.2 84.47,63.58 82.9,63.58 82.68,63.36 81.43,63.36 U12.A21
SOC_SPI_MOSI_R: length 55
  TOP w0.14: v1(93.55,63.71) 93.55,64.05 92.62,64.99 90.63,64.99 90.42,64.77 88.58,64.77 87.69,63.88 86.97,63.88 86.76,64.09 86.08,64.09 86.02,64.03 R116.1
  IN1 w0.14: v1(93.55,63.71) 93.84,63.42 99.06,63.42 99.41,63.07 100.1,63.07 100.1,63.07 100.46,63.07 100.46,63.07 100.75,63.07 101.76,62.06 109.34,62.06 110.17,61.22 111.91,61.22 113.6,59.54 114.78,59.54 115.74,58.58 117.24,58.58 117.89,57.93 118.97,57.93 119.61,57.29 125.33,57.29 125.53,57.09 127.32,57.09 127.52,57.29 131.42,57.29 131.55,57.16 132.08,57.16 v1(132.26,57.35)
  BOTTOM w0.14: v1(132.26,57.35) 132.26,57.71 R310.1 131.78,58.17 131.06,58.17 v2(130.88,57.99) 131.79,57.07 U22.5
SOC_SPI_MOSI_R1: length 33.2
  TOP w0.14: U18.87 143.08,40.85 143.27,41.05 143.27,41.76 144.09,42.58 144.09,44.43 144.23,44.56 144.23,45.65 145.22,46.64 145.22,47.45 v2(145.91,48.15) 146.34,48.57 v1(146.85,48.57)
  IN1 w0.14: v1(146.36,55.04) 145.2,55.04 141.73,58.51 134.21,58.51 133.85,58.88 v1(132.45,58.88)
  IN2 w0.14: v1(146.85,48.57) 146.85,49.83 146.36,50.32 v1(146.36,55.04)
  BOTTOM w0.14: R310.2 132.37,58.96 v1(132.45,58.88)
SOC_UART_RX: length 1.5
  TOP w0.102: v1(61.16,65.35) 60.81,65.7 U12.BC16
  BOTTOM w0.102: v1(61.16,65.35) 61.06,65.45 R273.2
SOC_UART_TX: length 2
  TOP w0.102: U12.BD14 60.1,66.98 v1(59.76,67.32)
  BOTTOM w0.102: v1(59.76,67.32) 60.28,66.8 R273.1
SOC_USB_OC0: length 41.6
  TOP w0.102: U12.C20 80.4,63.79 80.67,63.79 80.85,63.61 81.11,63.61 81.2,63.7 81.55,63.7 81.67,63.58 82.57,63.58 82.8,63.81 83.98,63.81 84.77,64.6 85.75,64.6 86.39,65.24 87.6,65.24 88.07,65.71 89.59,65.71 R105.1 90.04,65.78 89.73,66.09 89.73,66.95 89.93,67.16 89.93,67.67 92.4,70.13 92.4,72.82 93.64,74.07 93.64,79.78 v2(93.35,80.07) 93.21,80.21 v1(93.21,81.89)
  BOTTOM w0.102: U19.3 83.51,84.45 83.79,84.18 90.92,84.18 v1(93.21,81.89)
SOC_VCCA_PWROK: length 33
  TOP w0.102: v1(70.49,53.11) 70.72,52.88 U12.AB42
  IN2 w0.102: v1(92.42,55.42) 91.79,56.06 91.79,56.57 89.02,59.33 88.15,59.33 88.02,59.21 81.25,59.21 80.2,58.17 78.68,58.17 77.94,57.43 76.45,57.43 75.73,56.72 74.6,56.72 73.87,55.99 73.87,55.38 73.63,55.14 73.19,55.14 73.06,55.27 71.34,55.27 70.88,54.82 70.88,53.49 v1(70.49,53.11)
  BOTTOM w0.102: v1(92.42,55.42) 92.39,55.42 C261.1 91.78,55.69 91.61,55.52 90.52,55.52 90.4,55.41 R328.1 90.9,55.02 91.04,54.88 Q32.3
SPI_3P: length 12.1
  TOP w0.102: v1(132.93,50.06) 132.93,52.86 v1(133.44,53.37)
  BOTTOM w0.102: U22.3 133.06,49.94 v1(132.93,50.06) ; R319.2 137.38,58.06 136.85,57.53 136.85,57.01 136.91,56.94 v2(136.91,56.11) 136.91,55.56 136.24,54.89 134.97,54.89 v1(133.44,53.37)
SPI_7P: length 5.4
  BOTTOM w0.102: U22.7 134.33,57.1 134.36,57.12 134.36,57.53 134.64,57.81 134.64,58.52 134.58,58.58 R318.2 133.93,59.61 133.93,60.95 v2(133.81,61.06)
SRT_CRST#: length 155
  TOP w0.102: U12.C12 80.57,67.79 80.88,68.1 81.09,68.1 81.24,67.95 81.63,67.95
  TOP w0.14: v1(82.05,68.02) 81.98,67.95 81.63,67.95
  IN2 w0.14: v1(82.05,68.02) 82.16,67.92 91.01,67.92 91.15,68.07 91.96,68.07 92.22,67.81 92.22,67.61 92.82,67.01 95.35,67.01 v1(95.42,67.08)
  BOTTOM w0.14: G6.1 34.92,12.34 36.43,10.83 R413.2 C332.1 38.07,10.82 v2(39.21,10.82) 41.75,10.82 43.07,9.5 43.07,8.31 43.37,8 46.06,8 46.26,8.2 55.5,8.2 60.15,12.85 60.15,15.41 62.34,17.59 64.9,17.59 67.62,20.31 79.46,20.31 80.45,21.3 86.18,21.3 90.66,25.79 109.07,25.79 112.36,29.09 112.36,31.56 110.83,33.1 110.83,36.37 108.04,39.16 108.04,40.26 106.39,41.9 106.39,43.17 105.96,43.61 103.26,43.61 97.7,49.17 97.7,54.32 98.71,55.33 98.71,57.53 99.36,58.18 99.36,60.02 96.69,62.69 96.69,64.64 95.28,66.05 95.28,66.94 v1(95.42,67.08)
SUS_LED#: length 120.7
  TOP w0.102: U18.16 129.58,38.45 v1(129.81,38.68) ; v2(75.2,89.59) v1(74.44,89.59)
  IN2 w0.102: v1(92.88,75.13) 92.6,74.85 92.6,74.22 94.23,72.59 94.23,72.09 95.32,70.99 96.77,70.99 98.92,68.83 100.58,68.83 101.77,67.64 101.77,66.5 102.68,65.58 107.04,65.58 108.9,63.73 110.04,63.73 113.14,60.63 113.14,60.35 115.84,57.65 119.23,57.65 122.17,54.71 125.51,54.71 126.41,53.82 126.41,53.05 130.81,48.64 130.81,47 130.3,46.49 130.3,39.17 v1(129.81,38.68) ; v1(56.73,87.66) 58.18,87.66 59.5,88.98 63.87,88.98 64.57,88.28 69.27,88.28 71.01,90.02 74.01,90.02 v1(74.44,89.59)
  BOTTOM w0.102: v1(74.44,89.59) 75.19,88.84 75.19,86.55 76.39,85.34 76.39,78.97 75.91,78.49 75.91,77.64 76.51,77.04 80.38,77.04 80.94,76.49 85.63,76.49 85.93,76.78 91.22,76.78 v1(92.88,75.13) ; v1(56.73,87.66) 56.73,85.11 57,84.85 R195.2
SUS_PWRDOWNACK: length 9.4
  TOP w0.14: U12.D26 79.36,61.15 v1(79.36,61.49)
  BOTTOM w0.14: v1(79.36,61.49) 79.91,60.94 81.86,60.94 82.27,61.35 82.73,61.35 83.32,61.94 84.07,61.94 84.42,62.28 R291.2 84.61,62.41 85.11,62.91 86.86,62.91 R287.2
SUSB#: length 66.8
  TOP w0.14: R268.1 95.58,68.72 94.81,67.95 v1(94.76,67.95) ; v1(129.23,41.18) 130.29,40.11 130.29,38.48 129.34,37.53 129.34,37.51 129.12,37.29 128.77,37.29 128.55,37.51 128.08,37.51 127.87,37.3 127.87,36.82 127.5,36.45 U18.21
  IN2 w0.14: v1(129.23,41.18) 129.23,41.91 128.89,42.25 127.48,42.25 126.72,43.01 126.72,45.82 126.13,46.4 126.13,48.85 126.66,49.38 126.66,50.83 125.49,52 125.49,52 125.44,52.04 121.47,52.04 121.29,52.22 117.3,52.22 116.74,52.79 116.74,53.36 115.41,54.69 115.41,55.22 114.82,55.81 113.9,55.81 109.95,59.77 109.95,60.48 109.06,61.37 106.26,61.37 104.69,62.94 103.32,62.94 99.76,66.5 97.21,66.5 95.77,67.95 v1(94.76,67.95)
  BOTTOM w0.14: v1(94.76,67.95) 93.97,67.95 93.55,68.37 Q23.3 93.34,68.98 93.13,69.19 92.78,69.19 92.4,68.81 R320.1 91.73,68.26 R86.2
SUSC#: length 75
  TOP w0.14: v1(128.95,37.72) 128.81,37.85 128.23,37.85 127.94,37.85 127.53,37.44 127.53,36.99 127.39,36.85 U18.20 ; v1(95.57,71.68) 95.88,71.37 95.88,71.15 96.79,70.23 R245.1
  IN1 w0.14: v1(128.95,37.72) 129.18,37.49 133.86,37.49 134.2,37.84 134.2,39.5 v1(134.71,40.01)
  IN2 w0.14: v1(134.71,40.01) 134.29,40.44 134.29,41.3 133.29,42.3 133.29,46.5 133.87,47.07 133.87,47.72 133.5,48.08 131.9,49.68 131.66,49.68 130.67,50.68 130.67,51.46 127.37,54.76 126.83,54.76 125.93,55.65 122.33,55.65 119.69,58.3 119.55,58.43 116.17,58.43 113.92,60.68 113.92,60.95 110.19,64.68 109.05,64.68 107.23,66.5 106.39,66.5 104.97,67.92 102.63,67.92 100.93,69.62 99.25,69.62 96.68,72.18 96.07,72.18 v1(95.57,71.68)
  BOTTOM w0.14: R87.2 95.83,71.43 v1(95.57,71.68) ; R87.2 R324.1 ; R87.2 94.9,70.98 Q23.6
SUSON: length 134.7
  TOP w0.102: v1(131.79,41.73) 132.66,42.6 132.66,44.55 132.66,44.55 U18.117 132.66,47.79 R171.1
  IN1 w0.102: v1(38.32,33.22) 39.46,32.09 39.46,27.93 45.25,22.14 55.58,22.14 57.85,19.86 59.48,19.86 60.65,21.03 62.12,21.03 v1(63.16,19.99)
  IN2 w0.102: v1(63.16,19.99) 63.66,19.49 72.19,19.49 75.18,16.51 82.67,16.51 83.89,15.29 93.54,15.29 95.16,13.67 106.15,13.67 109.51,17.03 109.51,18.8 111.51,20.8 111.51,22.34 116.51,27.35 116.51,29.2 119.42,32.11 120.46,32.11 121.85,30.72 122.76,30.72 124.6,32.56 127.65,32.56 128.24,33.15 129.31,33.15 130.55,34.39 130.55,36.3 132.33,38.07 132.33,40.51 131.79,41.05 v1(131.79,41.73)
  BOTTOM w0.102: v1(38.32,33.22) 38.07,32.97 36.69,32.97 36.47,33.19 PR162.1
SUSWARN#_EC: length 64.6
  TOP w0.14: U18.113 134.26,47.06 134.64,47.44 134.92,47.44 135.41,47.93 135.41,53.18 v2(134.33,54.25) 131.79,56.79 131.79,58.57 131.89,58.67 v1(131.89,59.56)
  IN1 w0.14: v1(87.52,64.31) 87.7,64.5 88.07,64.5 88.65,65.07 92.39,65.07 92.59,65.28 93.92,65.28 94.24,65.59 96.07,65.59 96.38,65.28 98.47,65.28 99.46,65.28 99.71,65.53 99.71,65.56 99.96,65.81 100.6,65.81 102.04,64.38 107.71,64.38 108.06,64.03 111.71,64.03 113.66,62.08 114.35,62.08 115.06,61.37 117.04,61.37 117.92,60.5 119.44,60.5 120.74,59.2 124.62,59.2 124.8,59.39 127.46,59.39 127.64,59.56 v1(131.89,59.56)
  BOTTOM w0.14: v1(87.52,64.31) 87,63.79 R287.1
SVID_ALERT#_SOC: length 4.3
  TOP w0.14: U12.B24 81,61.94 81.53,61.94 81.78,61.69 82.38,61.69 82.48,61.78 83.2,61.78 83.46,61.53 84.21,61.53 84.44,61.75 R129.1
SVID_CLK_SOC: length 4.6
  TOP w0.102: 82.77,61.3 82.67,61.3 82.59,61.23 81.55,61.23 81.52,61.19 81.2,61.19 80.92,61.47 U12.C25
  TOP w0.14: R134.1 84.12,60.73 83.81,61.04 83.26,61.04 83,61.3 82.77,61.3
SVID_DATA_SOC: length 6.2
  TOP w0.14: U12.A25 81.6,61.47 81.62,61.45 82.48,61.45 82.58,61.54 83.1,61.54 83.36,61.28 84.19,61.28 84.24,61.24 85.87,61.24 86.25,60.86 87.08,60.86 R135.1
SYS_HWPG: length 68.8
  TOP w0.254: PR38.1 116.55,47.78 v1(116.3,48.03) 115.79,48.54 115.79,48.66 PR36.2 ; PR49.1 156.9,35.04 v1(156.94,35.08)
  IN1 w0.102: v1(156.94,35.08) 158.39,35.08 159.31,36 159.31,47.13 158.08,48.36 152.75,48.36 151.81,47.42 149.55,47.42 149.11,46.99 146.17,46.99 145.61,47.55 144.06,47.55 143.85,47.34 143.28,47.34 143.2,47.42 141.46,47.42 140.53,46.49 136.45,46.49 136.04,46.9 133.87,46.9 133.36,46.39 128.75,46.39 125.93,43.56 125.93,42.42 125.75,42.24 124.56,42.24 124.25,42.56 124.25,43.7 123.87,44.07 123.87,46.14 121.76,48.25 116.51,48.25 v1(116.3,48.03)
SYS_SHDN#: length 141.2
  TOP w0.102: v1(117.77,53.01) 117.29,53.49 PR32.1 ; v1(113.12,43.08) 113.12,43.84 113.79,44.5 PR41.1 114.52,44.88 114.77,45.14 114.77,50.7 115.41,51.33 v1(116.42,51.33)
  IN1 w0.102: v1(115.21,18.06) 115.21,17.81 108.22,10.82 v1(107.81,10.82) ; v1(93.89,6.96) 93.87,6.99 86.38,6.99 85.46,7.9 79.58,7.9 77.14,10.34 66.69,10.34 65.9,9.55 56.46,9.55 54.66,11.35 47.96,11.35 44.55,14.76 v1(44.39,14.76) ; v1(116.42,51.33) 116.42,51.66 v1(117.77,53.01) ; v1(113.12,43.08) 114.77,43.08 116.3,44.61 116.3,47.17 116.97,47.84 120.72,47.84 121.3,47.26 121.3,44.35 v1(121.56,44.09)
  IN2 w0.102: v1(112.23,33.3) 112.06,33.48 112.06,36.73 112.61,37.29 112.61,42.57 v1(113.12,43.08)
  BOTTOM w0.102: PQ36.3 43.78,15.37 v1(44.39,14.76) ; v1(121.56,44.09) 121.56,43.71 121.86,43.41 PR147.1 ; v1(112.23,33.3) 113.47,32.06 113.47,31.65 115.21,29.91 v2(115.21,22.48) v1(115.21,18.06) ; v1(93.89,6.96) 94.5,6.35 SW8.1 SW8.3 104.72,6.35 107.81,9.45 v1(107.81,10.82)
TEMP_MBAT: length 108.8
  TOP w0.102: v1(139.95,44.35) 140.66,45.06 U18.97 140.66,46.99 140.81,47.14 140.81,47.52 141.32,48.03 C110.2
  IN2 w0.102: v1(139.95,44.35) 141.24,44.35 141.55,44.04 141.55,39.17 142.15,38.56 142.15,34.07 140.26,32.18 138.93,32.18 137.15,33.96 131.28,33.96 129.62,32.31 124.68,32.31 122.88,30.51 121.68,30.51 120.31,31.88 119.5,31.88 116.72,29.1 116.72,27.19 111.76,22.24 111.76,20.77 109.77,18.77 109.77,16.94 106.26,13.44 94.89,13.44 93.23,15.09 83.66,15.09 82.44,16.31 74.73,16.31 v1(71.95,19.09)
  BOTTOM w0.102: PR178.1 69.05,16.04 68.81,16.28 PR174.1 68.81,17.12 70.31,18.62 v2(71.11,18.62) 71.48,18.62 v1(71.95,19.09)
TEMP_MBAT_C: length 3.1
  BOTTOM w0.102: PJ7.5 69.13,14.8 PR178.2 68.24,14.88 v2(68.11,14.75)
THER_CPU: length 2.3
  BOTTOM w0.102: R337.1 138.14,53.88 v1(138.14,54.12) 137.9,54.36 R327.2
THERMDA: length 2.9
  TOP w0.102: U7.2 62.93,80.35 63.03,80.24 63.03,79.4 62.65,79.02 TP8.1
THERMDC: length 2.6
  TOP w0.102: U7.3 62.76,81 63.24,80.52 63.24,80.01 TP9.1
THRM_MOINTOR: length 10
  TOP w0.102: v1(139.51,47.4) 139.46,47.34 U18.100
  BOTTOM w0.102: R337.2 137.38,51.47 R345.1 138.4,50.44 139.67,50.44 C274.2 140.36,49.76 v2(141.37,49.76) 141.37,49.25 v1(139.51,47.4)
TOUCH_PANEL_SOC_RST#: length 8
  TOP w0.102: v1(60.45,65.35) 60.1,65.7 U12.BD16
  BOTTOM w0.102: v1(60.45,65.35) 59.66,66.14 59.66,66.45 59.27,66.83 57.95,66.83 v2(57.54,67.24) 57.47,67.31 54.94,67.31 R269.2
TOUCH_SCREEN_PWR: length 7.8
  BOTTOM w0.102: R294.1 v1(33.11,61.14)
  BOTTOM w0.254: CN16.11 34.1,66.3 34.03,66.23 34.03,65.1 33.34,64.41 33.34,63.87 C202.2 C210.1 32.13,61.65 R294.1
TOUCH_SCREEN_SEL: length 22.3
  TOP w0.127: v2(45.79,65.28) v1(44.9,65.28)
  TOP w0.14: Q12.3 44.8,54.13 45.86,55.19 48,55.19 48.23,55.42 R153.1 48.23,59.55 47.84,59.94 47.84,61.31 46.83,62.32 46.83,64.9 46.45,65.28 v2(45.79,65.28)
  BOTTOM w0.14: CN16.29 43.1,67.9 43.4,68.2 43.81,68.2 44.9,67.11 v1(44.9,65.28)
TOUCHPANEL_INTR#_SOC: length 11.3
  TOP w0.102: U12.AU32 63.34,58.37 59.83,58.37 59.73,58.27 59.73,57.89 59.59,57.76 58.73,57.76 58.61,57.88 58.35,57.88 58.25,57.78 58.01,57.78 57.92,57.86 57.59,57.86 57.41,57.69 57.41,57.23 57.06,56.87 56.61,56.87 TP21.1
TP_EN_EC: length 130.1
  TOP w0.102: v1(144.64,37.14) 144.64,36.96 143.23,35.55 143.23,35.45 143.04,35.25 U18.73
  IN1 w0.102: v1(144.64,37.14) 144.43,36.92 144.43,31.99 142.42,29.98 137.04,29.98 136.26,29.21 136.26,28.73 135.7,28.17 133.9,28.17 133.6,27.86 126.36,27.86 126.08,27.58 122.83,27.58 120.54,25.3 120.54,23.57 119.14,22.17 119.14,20.47 108.25,9.58 88,9.58 86.94,10.64 79.37,10.64 77.78,12.22 66.6,12.22 65.4,11.02 57.19,11.02 54.65,13.56 49.14,13.56 v1(48.48,12.9)
  BOTTOM w0.102: 45.23,14.25 44.31,14.25 43.58,14.99 42.26,14.99 41.55,15.7 R536.1 ; 45.23,14.25 45.23,14.58 44.74,15.07 CN18.8 ; 45.23,14.25 46.57,12.9 v1(48.48,12.9)
TP_INT_C: length 46
  TOP w0.14: v1(56.13,54.15) 55.85,53.87 v2(51.64,53.87) Q12.1 ; v1(77.94,61.49) 77.94,61.58 U12.G24
  IN2 w0.102: v1(77.94,61.49) 77.94,61.5 77.44,62 75.02,62 74.18,61.16 73.04,61.16 72.36,60.48 72.36,58.98 72.49,58.84 72.49,58.36 72.36,58.23 72.36,57.75 72.08,57.47 71.64,57.47 71.4,57.24
  IN2 w0.14: 71.4,57.24 71.01,56.85 71.01,55.6 70.35,54.94 70.35,54.91 69.22,53.78 69.22,53.78 69.07,53.64 68.54,53.64 67.94,53.04 67.94,51.51 66.69,50.27 65.45,50.27 63.59,48.41 62.68,48.41 62.07,49.02 62.07,51.16 60.9,52.32 56.28,52.32 55.72,52.88 55.72,53.75 v1(56.13,54.15)
TP_INT_EC#: length 6.8
  TOP w0.102: U18.11 128.1,40.45 v1(128.63,40.98)
  BOTTOM w0.102: R420.2 127.06,38.37 127.37,38.68 127.37,39.37 127.7,39.7 v1(127.7,39.98) Q41.3 128.32,41.28 128.62,40.98 v1(128.63,40.98)
TP_NC: length 5.5
  TOP w0.102: R155.1 TP27.1 55.16,57.48 56.72,59.04 58.13,59.04 U12.BH30
TP_NC1: length 7.1
  TOP w0.102: U12.BG30 58.54,59.04 58.25,58.75 58.01,58.75 57.92,58.84 57.59,58.84 57.32,58.57 57.05,58.57 56.89,58.41
  TOP w0.14: R156.1 TP32.1 55.21,56.21 56.35,57.35 56.35,57.88 56.89,58.41
TP_POWER_ON: length 81.6
  TOP w0.102: v1(125.29,36.12) 125.29,35.18 125.62,34.85 U18.25
  IN1 w0.102: v1(125.29,36.12) 123.92,36.12 122.47,34.67 122.09,34.67 121.45,34.04 113.91,34.04 v1(112.46,35.48)
  BOTTOM w0.102: v1(112.46,35.48) 111.79,34.81 111.79,33.15 113.07,31.87 113.07,28.26 108.98,24.17 101.96,24.17 101.24,24.89 91.43,24.89 87.67,21.13 87.67,18.52 88.23,17.96 88.23,15.93 88.05,15.75 88.05,9.3 85.26,6.5 81.83,6.5 81.37,6.96 81.37,9.1 81.09,9.38 81.09,9.72 81.33,9.96 81.37,9.96 81.86,10.45 81.86,10.73 81.86,10.73 81.86,12.06 81.4,12.52 PU16.2 ; v1(125.29,36.12) 125.42,36.25 TP43.1
TP_SENSOR_INT: length 80
  TOP w0.102: v1(82.85,64.95) 82.77,65.03 81.77,65.03 81.62,64.87 U12.B18
  IN1 w0.14: v1(82.85,64.95) 81.69,64.95 80.64,63.89 74.14,63.89 72.96,62.71 72.96,61.87 72.27,61.18 67.54,61.18 66.82,60.45 65.98,60.45 65.19,59.67 65.19,59.06 64.94,58.8 64.94,56.74 65.57,56.11 65.57,55.37 64.53,54.33 62.68,54.33 61.97,53.62 61.97,50.8 61.43,50.27 60.65,50.27 60.32,49.94 60.32,48.31 59.88,47.88 58.74,47.88 58.16,47.3 58.16,46.61 57.32,45.77 57.32,45.11 53.48,41.28 53.15,41.28 52.72,40.84 52.72,40.61 50.05,37.95 50.05,34.44 49.37,33.76 49.37,32.44 50.28,31.52 50.28,30.05 49.37,29.13 48.09,29.13 v1(47.86,28.91)
  BOTTOM w0.14: v1(47.86,28.91) 47.9,28.87 47.9,26 48.64,25.26 50.73,25.26 52.42,23.57 v2(52.42,23.34) R513.1 56.44,22.31 56.76,22.63 Q42.3
TP_SENSOR_INT_R: length 132.1
  IN2 w0.14: v1(129.89,36.32) 130.18,36.03 130.18,34.54 129.01,33.37 128.14,33.37 127.57,32.79 124.5,32.79 122.88,31.17 121.81,31.17 120.54,32.44 119.32,32.44 116.29,29.41 116.29,27.54 111.28,22.53 111.28,20.89 109.29,18.89 109.29,17.12 106.19,14.02 95.22,14.02 93.69,15.55 83.95,15.55 82.76,16.73 82.58,16.73 75.33,16.73 72.28,19.79 64.05,19.79 v1(63.85,19.99)
  BOTTOM w0.14: R420.1 126.71,41.88 127.17,42.34 128.52,42.34 128.72,42.55 Q41.1 129.43,43.31 129.71,43.03 129.71,41 128.69,39.98 128.69,38.71 130.12,37.29 130.12,36.88 129.89,36.65 v1(129.89,36.32) ; Q45.2 61.69,23.04 62.09,22.63 63.21,22.63 63.85,22 v1(63.85,19.99) 63.34,20.5 62.3,20.5 61.08,19.28 R534.1 60.2,17.92 58.1,15.82 v2(58.1,15.62) 58.1,14.61 C358.2 58.02,14.56 57.45,13.99 57.45,12.48 54.81,9.85 51,9.85 49.47,11.38 49.47,12.85 48.68,13.64 47.31,13.64 45.74,15.21 CN18.7
TPCLK: length 112.6
  TOP w0.102: U18.72 141.49,34.85 140.47,33.83 v1(139.48,33.83)
  IN1 w0.102: v1(71.54,14.91) 71.85,15.21 75.51,15.21 79.67,11.05 87.24,11.05 88.21,10.08 108.18,10.08 116.74,18.64 116.74,20.59 118.89,22.74 118.89,24.23 122.68,28.02 125.65,28.02 127.13,29.49 130.61,29.49 133.91,32.79 139.68,32.79 139.92,33.03 139.92,33.39 v1(139.48,33.83)
  IN2 w0.102: v1(71.54,14.91) 68.11,18.34 56,18.34 55.46,17.81 55.03,17.81 v1(54.17,18.66)
  BOTTOM w0.102: v1(54.17,18.66) 54.17,18.83 R406.2 53.56,18.69 53.68,18.58 C330.2 53.05,17.43 53.05,17.19 52.83,16.97 51.05,16.97 50.74,16.66 CN18.2
TPDATA: length 113.3
  TOP w0.102: U18.71 141.44,34.45 140.19,33.19 v1(139.51,33.19)
  IN1 w0.102: v1(70.91,14.91) 71.47,15.47 75.58,15.47 79.8,11.25 82.87,11.25 83.25,11.63 86.45,11.63 86.83,11.25 87.42,11.25 88.31,10.36 108.15,10.36 116.43,18.64 116.43,20.56 118.69,22.82 118.69,24.31 122.6,28.22 125.57,28.22 127.04,29.69 130.52,29.69 133.88,33.05 139.36,33.05 v1(139.51,33.19)
  IN2 w0.102: v1(52.92,18.66) 53.56,18.03 54.52,18.03 54.95,17.6 55.57,17.6 56,18.03 68.11,18.03 70.91,15.24 v1(70.91,14.91)
  BOTTOM w0.102: CN18.3 49.74,16.4 50.13,16.79 50.51,16.79 50.89,17.17 52.75,17.17 52.85,17.27 52.85,17.64 C329.2 52.43,18.86 52.54,18.97 R405.2 52.92,19.04 v1(52.92,18.66)
TPM_VDD: length 11.3
  TOP w0.254: U16.19 44.39,47.4 45.1,48.11 ; 43.48,50.67 43.84,50.31 43.84,49.8 42.07,48.02 C105.1 41.88,47.5 41.14,46.77 U16.24 ; U16.10 44.39,39.4 44.01,39.02 44.01,38.69 44.25,38.45 44.86,38.45 45.05,38.63 45.46,38.63
  vias: v2(46.3,48.29) v2(50.59,42.9)
TPM_VSB: length 7.3
  TOP w0.381: R528.2 v1(38.76,37.52) R527.2 38.86,36.78 C357.1 40.78,36.78 R526.1 C356.2 41.05,38.34 41.05,39.23 41.13,39.3 41.13,39.93 U16.5
ULT_EDP_HPD: length 4.6
  BOTTOM w0.102: CN16.12 34.6,66.41 34.31,66.12 34.31,64.6 R276.2 34.23,64.1 Q28.2
UNCORE_V1P8_AN32_PWR: length 14.2
  TOP w0.254: U12.U38 73.82,55.19 73.46,55.56 v1(73.46,55.56) ; U12.AN32 65.29,58.22 v1(65.64,58.57) 66.03,58.96 U12.AM30
  IN1 w0.508: 70.48,54.79 70.04,54.79 69.31,54.05 68.44,54.05 67.94,54.56 67.94,55.12 67.48,55.58 66.64,55.58 66.26,55.96 66.26,58.17 65.86,58.57 v1(65.64,58.57)
  BOTTOM w0.254: 81.25,55.65 81.88,55.02 v2(81.88,54.48)
  BOTTOM w0.381: v1(65.64,58.57) 65.42,58.57 65.13,58.86 C241.2 64.87,58.86 64.4,58.39 64.03,58.39 C245.2
USB3_P0_REXT: length 1.4
  TOP w0.102: U12.M7 75.64,70.25 v1(75.35,70.54)
  BOTTOM w0.102: v1(75.35,70.54) 74.82,71.07 R351.2
USB3_P1_REXT: length 1.4
  TOP w0.254: U12.M12 75.68,68.12 v1(75.4,67.84)
  BOTTOM w0.254: v1(75.4,67.84) 75.78,68.22 R258.2
USB3_V1P0_G3: length 24.8
  TOP w0.203: U12.C3 80.2,71.65 v1(80.25,71.6) 80.2,71.56 U12.C5 80.34,70.94 U12.B6
  TOP w0.254: U12.V22 73.1,62.77 v1(73.48,62.4) 73.86,62.77 U12.U22 ; v1(71.91,63.91) 72.29,64.29 U12.Y19
  IN2 w0.508: v1(73.48,62.4) 73.47,62.4 73.47,63.65 73.22,63.91 v1(71.91,63.91) 71.54,63.91 71.27,64.19 71.27,65.7 71.74,66.17 71.74,66.21 73.37,67.84 73.37,70.46 74.95,72.03 78.32,72.03 79.09,72.8 79.98,72.8 80.36,72.42 80.36,71.71 v1(80.25,71.6)
  BOTTOM w0.381: v1(73.48,62.4) 73.48,62.47 73.68,62.77 C220.2 ; C193.1 71.7,63.91 v1(71.91,63.91)
  vias: v1(79.68,72.95)
USB30_RX1+: length 70.7
  TOP w0.102: v1(79.22,71.6) 79.66,71.6 U12.D4 ; R13.2 86.15,84.8 86.15,84.34 C23.1 86.04,83.38 86.04,83.07 86.21,82.9 87.15,82.9 87.44,82.61 87.44,82.09 v2(87.98,81.55) 87.43,81.01 87.43,80.76 87.23,80.55 86.73,80.55 86.63,80.45 86.63,80.04 86.73,79.94 87.18,79.94 87.43,79.7 87.43,79.14 87.24,78.95 86.99,78.95 86.88,78.85 86.88,78.64 v1(87.04,78.49)
  IN1 w0.102: v1(79.22,71.6) 79.67,71.6 80.09,72.02 80.52,72.02 80.67,71.87 80.67,71.35 80.53,71.21 80.53,70.88 81,70.41 81,70.02 81.22,69.8 81.86,69.8 82.09,70.03 82.09,70.22 82.16,70.29 82.87,70.29 82.96,70.2 82.96,70.03 83.14,69.85 83.66,69.85 83.94,70.13 83.94,70.71 83.44,71.21 83.44,71.7 83.94,72.2 83.94,73.89 84.29,74.24 84.29,74.78 84.14,74.93 84.14,75.15 83.8,75.49 83.49,75.49 83.4,75.4 83.34,75.34 83.19,75.18 83.16,75.16 83.07,75.07 82.6,75.07 82.5,75.18 82.5,75.39 83.34,76.24 83.76,76.24 84.25,75.74 84.86,75.13 85.18,75.13 85.47,75.43 85.47,75.74 85.09,76.12 85.09,76.31 85.22,76.44 85.47,76.44 85.84,76.07 86.14,76.07 86.5,76.44 87.08,76.44 87.33,76.7 87.33,77.11 87.13,77.32 84.85,77.32 84.54,77 84.22,77 83.96,77.26 83.96,77.99 84.13,78.16 84.75,78.16 84.99,78.39 84.99,78.78 84.75,79.02 82.72,79.02 82.54,79.2 82.54,79.95 82.69,80.1 82.9,80.1 83.04,79.96 83.04,79.7 83.23,79.5 83.63,79.5 83.9,79.77 83.9,79.96 84,80.06 84.15,80.06 84.68,79.53 85.24,79.53 85.46,79.74 85.46,80.55 85.63,80.72 85.88,80.72 85.98,80.62 85.98,79.88 86.22,79.64 86.62,79.64 86.86,79.88 86.86,80.41 86.99,80.54 87.21,80.54 87.34,80.41 87.34,79.89 87.58,79.65 87.95,79.65 88.26,79.96 88.26,80.34 88.38,80.47 90.2,80.47 90.72,79.95 91.89,79.95 92.17,79.67 92.17,79.26 91.82,78.91 91.82,78.29 91.71,78.17 91.43,78.17 91.23,78.37 91.23,78.73 90.15,79.81 88.8,79.81 88.15,79.16 85.75,79.16 85.47,78.88 85.47,78.1 85.76,77.81 86.53,77.81 86.82,78.1 86.82,78.27 v1(87.04,78.49)
USB30_RX1+_R: length 5.4
  TOP w0.102: R13.1 86.16,86.43 86.16,86.7 v2(86.71,87.25) 86.16,87.8 86.16,89.46 CN6.6
USB30_RX1-: length 70.7
  TOP w0.102: v1(79.67,72.19) 79.44,72.42 79.21,72.42 79.14,72.34 U12.E3 ; v1(86.33,78.49) 86.45,78.49 86.71,78.74 86.71,78.92 86.91,79.13 87.17,79.13 87.25,79.21 87.25,79.62 87.11,79.76 86.66,79.76 86.45,79.97 86.45,80.52 86.66,80.73 87.16,80.73 87.26,80.83 87.26,80.99 v2(86.71,81.54) 87.26,82.1 87.26,82.54 87.07,82.72 86.13,82.72 85.86,83 85.86,83.38 C22.1 85.55,83.91 85.97,84.33 85.97,84.83 R12.2
  IN1 w0.102: v1(79.67,72.19) 79.77,72.09 79.88,72.09 80.01,72.21 80.6,72.21 80.86,71.95 80.86,71.27 80.73,71.13 80.73,70.96 81.19,70.49 81.19,70.09 81.3,69.99 81.78,69.99 81.9,70.11 81.9,70.3 82.08,70.49 82.95,70.49 83.15,70.28 83.15,70.1 83.21,70.04 83.58,70.04 83.75,70.21 83.75,70.63 83.25,71.13 83.25,71.78 83.75,72.28 83.75,73.97 84.1,74.32 84.1,74.7 83.95,74.85 83.95,75.07 83.72,75.3 83.57,75.3 83.47,75.2 83.4,75.13 83.3,75.02 83.15,74.88 82.53,74.88 82.31,75.1 82.31,75.47 83.26,76.43 83.84,76.43 84.94,75.32 85.1,75.32 85.28,75.5 85.28,75.66 84.9,76.04 84.9,76.39 85.14,76.63 85.55,76.63 85.92,76.26 86.06,76.26 86.42,76.63 87,76.63 87.14,76.77 87.14,77.04 87.05,77.13 84.93,77.13 84.61,76.81 84.14,76.81 83.77,77.18 83.77,78.07 84.05,78.35 84.67,78.35 84.8,78.47 84.8,78.7 84.67,78.83 82.64,78.83 82.35,79.12 82.35,80.03 82.61,80.29 82.98,80.29 83.23,80.04 83.23,79.78 83.31,79.69 83.55,79.69 83.71,79.85 83.71,80.04 83.92,80.25 84.23,80.25 84.76,79.72 85.17,79.72 85.27,79.82 85.27,80.63 85.55,80.91 85.96,80.91 86.17,80.7 86.17,79.96 86.3,79.83 86.54,79.83 86.67,79.96 86.67,80.49 86.91,80.73 87.29,80.73 87.53,80.49 87.53,79.97 87.66,79.85 87.87,79.85 88.07,80.04 88.07,80.42 88.3,80.66 90.28,80.66 90.8,80.14 91.97,80.14 92.36,79.75 92.36,79.18 92.02,78.83 92.02,78.21 91.79,77.98 91.35,77.98 91.04,78.3 91.04,78.65 90.07,79.62 88.88,79.62 88.23,78.97 85.83,78.97 85.67,78.8 85.67,78.18 85.84,78 86.45,78 86.63,78.18 86.63,78.36 86.5,78.49 v1(86.33,78.49)
USB30_RX1-_R: length 5.4
  TOP w0.102: CN6.5 85.98,89.51 85.98,87.8 v2(85.44,87.25) 85.98,86.7 85.98,86.43 R12.1
USB30_TX1+: length 64.9
  TOP w0.102: U12.K6 76.57,71.27 v1(76.42,71.27) ; v1(89.4,78.46) 89.15,78.71 89.15,78.93 89.79,79.58 90.19,79.58 90.33,79.43 v2(90.33,79.03) 90.88,79.58 91.02,79.58 91.2,79.76 91.71,79.76 92.13,80.18 92.13,80.67 C26.1
  IN1 w0.102: v1(89.4,78.46) 89.16,78.7 89.16,78.87 89.23,78.94 89.71,78.94 89.98,78.67 89.98,77.64 90.71,76.91 91,76.91 91.38,77.29 91.62,77.29 91.7,77.21 91.7,76.31 91.94,76.07 92.48,76.07 92.71,76.31 92.71,78.46 92.88,78.62 93.06,78.62 93.31,78.87 93.31,79.76 92.24,80.82 91.07,80.82 90.15,81.74 87.12,81.74 86.81,81.42 86.44,81.42 86.13,81.74 85.41,81.74 84.65,80.98 82.24,80.98 81.66,80.4 81.66,78.67 82.18,78.16 82.91,78.16 83.05,78.01 83.05,77.24 82.54,76.72 82.05,76.72 81.8,76.47 81.8,76.04 81.71,75.95 80.89,75.95 79.76,74.82 79.76,74.29 80.07,73.98 80.62,73.98 80.84,74.19 80.84,74.61 81.3,75.07 81.52,75.07 81.6,74.99 81.6,74.37 81.79,74.18 82.92,74.18 83.06,74.04 83.06,73.78 82.96,73.68 82.14,73.68 81.93,73.47 81.93,73.03 82.14,72.82 82.96,72.82 83.06,72.71 83.06,72.55 82.68,72.16 82.34,72.16 82.08,71.91 82.08,71.29 81.95,71.16 81.66,71.16 81.55,71.27 81.55,72.24 81.12,72.67 81.12,73.26 80.88,73.5 80.47,73.5 80.23,73.26 80.23,73.03 80.1,72.9 79.85,72.9 79.72,73.03 79.72,73.21 79.48,73.44 79.07,73.44 78.83,73.21 78.83,72.62 78.75,72.54 76.77,72.54 76.53,72.3 76.53,71.92 76.77,71.68 77.55,71.68 77.78,71.45 78.04,71.45 78.26,71.68 78.45,71.68 78.58,71.55 78.58,71.07 78.45,70.94 78.05,70.94 77.8,70.7 77.8,70.59 77.68,70.46 77.39,70.46 77.26,70.59 77.26,70.71 76.86,71.11 76.58,71.11 v1(76.42,71.27)
USB30_TX1+_C: length 2.9
  TOP w0.102: C26.2 92.09,82.33 92.09,82.42 v2(92.59,82.92) 92.02,83.5 92.02,83.56 R20.2
USB30_TX1+_R: length 10.2
  TOP w0.102: R20.1 92.01,85.15 92.01,85.26 v2(92.54,85.79) 92.28,85.79 92.01,86.06 92.01,86.23 92.26,86.47 92.26,86.64 92.38,86.77 C18.1 92.26,87.3 92.26,88.2 92.04,88.42 90.85,88.42 90.72,88.54 90.72,88.95 90.85,89.08 91.96,89.08 92.19,89.31 92.19,89.49 CN6.9
USB30_TX1-: length 64.9
  TOP w0.102: C25.1 91.95,80.67 91.95,80.25 91.64,79.93 91.13,79.93 90.95,79.76 90.87,79.76 v2(90.33,80.3) 90.33,80 90.08,79.76 89.72,79.76 88.97,79.01 88.97,78.73 v1(88.71,78.47) ; U12.K7 76.57,70.25 76.47,70.35 v1(76.47,70.64)
  IN1 w0.102: v1(88.71,78.47) 88.85,78.47 88.97,78.59 88.97,78.95 89.16,79.13 89.79,79.13 90.17,78.75 90.17,77.71 90.79,77.1 90.92,77.1 91.3,77.48 91.7,77.48 91.89,77.29 91.89,76.38 92.02,76.26 92.4,76.26 92.52,76.38 92.52,78.54 92.8,78.81 92.99,78.81 93.12,78.95 93.12,79.68 92.16,80.63 90.99,80.63 90.07,81.55 87.2,81.55 86.88,81.23 86.36,81.23 86.05,81.55 85.49,81.55 84.73,80.78 82.32,80.78 81.86,80.32 81.86,78.75 82.26,78.35 82.99,78.35 83.24,78.09 83.24,77.16 82.62,76.53 82.12,76.53 81.99,76.4 81.99,75.96 81.79,75.76 80.97,75.76 79.95,74.74 79.95,74.37 80.15,74.17 80.54,74.17 80.65,74.27 80.65,74.69 81.22,75.26 81.6,75.26 81.79,75.07 81.79,74.45 81.87,74.37 83,74.37 83.25,74.12 83.25,73.7 83.04,73.49 82.22,73.49 82.12,73.39 82.12,73.11 82.22,73.01 83.04,73.01 83.25,72.79 83.25,72.47 82.76,71.97 82.42,71.97 82.27,71.83 82.27,71.21 82.03,70.97 81.59,70.97 81.36,71.19 81.36,72.16 80.93,72.59 80.93,73.18 80.8,73.3 80.55,73.3 80.42,73.18 80.42,72.95 80.18,72.71 79.77,72.71 79.53,72.95 79.53,73.13 79.4,73.25 79.15,73.25 79.02,73.13 79.02,72.54 78.83,72.35 76.85,72.35 76.72,72.22 76.72,72 76.85,71.87 77.63,71.87 77.85,71.64 77.96,71.64 78.18,71.87 78.53,71.87 78.77,71.63 78.77,70.99 78.53,70.75 78.12,70.75 77.99,70.62 77.99,70.51 77.76,70.27 77.31,70.27 77.07,70.51 77.07,70.63 76.79,70.92 76.62,70.92 76.47,70.76 v1(76.47,70.64)
USB30_TX1-_C: length 2.9
  TOP w0.102: C25.2 91.91,82.25 91.91,82.33 v2(91.32,82.92) 91.84,83.43 91.84,83.53 R19.2
USB30_TX1-_R: length 10.2
  TOP w0.102: R19.1 91.84,85.17 91.84,85.23 v2(91.27,85.79) 91.52,85.79 91.84,86.11 91.84,86.31 92.08,86.55 92.08,86.64 91.95,86.77 C17.1 92.08,87.3 92.08,88.13 91.97,88.24 90.77,88.24 90.54,88.47 90.54,89.02 90.77,89.26 91.88,89.26 92.01,89.38 92.01,89.49 CN6.8
USB_BT_N: length 120.4
  TOP w0.102: CN10.36 163.25,92.1 163.55,92.41 164.98,92.41 166.22,91.16 166.22,81.25 165.76,80.8 165.43,80.8 165.28,80.95 v1(165.28,81.2) ; v1(98.39,59.41) 98.59,59.21 98.77,59.21 99.51,59.94 U13.3
  IN1 w0.102: v1(98.39,59.41) 98.62,59.18 98.84,59.18 99.11,58.92 99.11,56.54 100.03,55.62 100.03,50.05 101.64,48.44 101.64,47.72 104.11,45.25 105.3,45.25 106.9,43.65 110.55,43.65 111.26,44.36 114.52,44.36 114.81,44.66 114.81,48.28 115.66,49.12 122.38,49.12 125.35,52.1 130.54,52.1 131.25,52.8 134.26,52.8 134.6,53.14 137.86,53.14 138.14,52.87 142.79,52.87 142.87,52.95 146.13,52.95 149.95,56.77 149.95,62.61 151.26,63.92 151.26,64.41 154.08,67.23 154.08,69.56 155.48,70.96 155.48,72.19 164.09,80.8 165.13,80.8 165.28,80.95 v1(165.28,81.2)
USB_BT_P: length 120.4
  TOP w0.102: v1(165.28,80.42) 165.48,80.62 165.84,80.62 166.4,81.18 166.4,91.23 165.05,92.58 163.55,92.58 163.24,92.9 CN10.38 ; v1(98.39,58.78) 98.64,59.03 98.85,59.03 99.26,59.44 U13.4
  IN1 w0.102: v1(165.28,80.42) 165.09,80.61 164.17,80.61 155.67,72.11 155.67,70.88 154.27,69.48 154.27,67.15 151.45,64.33 151.45,63.84 150.14,62.53 150.14,56.69 146.21,52.76 142.95,52.76 142.87,52.68 138.06,52.68 137.78,52.95 134.68,52.95 134.34,52.61 131.32,52.61 130.62,51.91 125.43,51.91 122.46,48.93 115.74,48.93 115,48.2 115,44.58 114.6,44.17 111.34,44.17 110.63,43.46 106.82,43.46 105.22,45.06 104.03,45.06 101.45,47.64 101.45,48.36 99.84,49.97 99.84,55.54 98.92,56.46 98.92,58.84 98.76,58.99 98.61,58.99 v1(98.39,58.78)
USB_H1_N: length 28.7
  TOP w0.102: v1(78.01,67.36) 78.31,67.05 U12.G14 ; v1(91.8,67.03) 91.56,66.79 91.56,66.68 91.63,66.6 93.88,66.6 94.85,65.63 95.47,65.63 97.15,63.96 97.15,62.41 96.33,61.6 96.33,60.96 96.48,60.81 96.82,60.81 96.98,60.98 R131.1
  IN1 w0.102: v1(91.8,67.03) 91.34,67.49 91.34,68.01 90.78,68.57 84.14,68.57 82.84,67.27 80.57,67.27 80.18,66.88 77.73,66.88 77.63,66.98 77.63,67.18 77.81,67.36 v1(78.01,67.36)
USB_H1_N1: length 2.5
  TOP w0.102: R131.2 98.23,60.78 99.24,60.78 99.41,60.94 U13.1
USB_H1_P: length 28.7
  TOP w0.102: U12.J14 77.6,66.97 v1(77.25,67.32) ; v1(91.15,67.03) 91.38,66.8 91.38,66.6 91.56,66.42 93.81,66.42 94.77,65.46 95.4,65.46 96.97,63.88 96.97,62.48 96.16,61.67 96.16,60.88 96.41,60.63 96.84,60.63 96.98,60.49 R139.1
  IN1 w0.102: v1(91.15,67.03) 91.15,67.93 90.7,68.38 84.22,68.38 82.92,67.08 80.65,67.08 80.26,66.69 77.65,66.69 77.44,66.9 77.44,67.13 v1(77.25,67.32)
USB_H1_P1: length 2.5
  TOP w0.102: R139.2 98.27,60.6 99.24,60.6 99.41,60.44 U13.2
USB_HSIC_RCOMP: length 11.6
  TOP w0.102: U12.A7 81.5,70.37 81.62,70.37 82.01,70.76 82.01,74.3 81.68,74.63 79.7,74.63 79.47,74.85 79.47,74.86
  TOP w0.254: R55.2 77.25,75.24 78.41,75.24 78.76,74.88 79.45,74.88 79.47,74.86
USB_HSIC_V1P2_G3: length 10.8
  TOP w0.254: U12.V18 73.47,65.43 v1(73.48,65.43)
  BOTTOM w0.381: R240.1 75.74,71.93 75.45,72.21 73.42,72.21 72.76,71.55 72.76,70.41 73.49,69.68 v2(73.49,68.14)
  BOTTOM w0.508: v1(73.48,65.43) 73.48,68.12 v2(73.49,68.14)
USB_HUB_5V: length 1.7
  TOP w0.102: U13.27 101.62,62.58 101.18,63.02 TP15.1
USB_RCOMP: length 1.8
  TOP w0.254: U12.C7 79.81,70.05 v1(79.76,70.1) 79.8,70.14 U12.D6
  BOTTOM w0.381: R247.2 79.87,69.99 v1(79.76,70.1)
USB_USB_N: length 53.2
  TOP w0.102: L7.2 107.71,84.8 107.6,84.7 107.33,84.7 107.23,84.6 107.23,83.97 107.05,83.79 106.57,83.79 105.23,85.14 103.57,85.14 102.46,86.26 96.14,86.26 94.96,85.08 94.96,82.3 94.48,81.81 94.48,73.76 93.18,72.47 93.18,69.8 90.75,67.36 90.75,66.27 91.2,65.81 92.95,65.81 94.71,64.06 95.47,64.06 95.74,63.79 95.74,63.57 v2(96.28,63.02) 95.74,62.47 95.74,62.17 95.47,61.9 95.47,60.6 95.8,60.27 95.8,58.37 96.69,57.48 98.42,57.48 99.2,58.27 99.39,58.27 99.56,58.44 U13.6
USB_USB_P: length 53.2
  TOP w0.102: U13.7 99.53,57.94 99.38,58.09 99.28,58.09 98.49,57.3 96.62,57.3 95.62,58.3 95.62,60.2 95.29,60.53 95.29,61.97 95.56,62.24 95.56,62.47 95.5,62.53 95.49,62.54 v2(95.01,63.02) 95.56,63.57 95.56,63.72 95.4,63.88 94.63,63.88 92.88,65.63 91.13,65.63 90.57,66.2 90.57,67.44 93.01,69.88 93.01,72.54 94.3,73.84 94.3,81.89 94.78,82.37 94.78,85.15 96.07,86.44 102.53,86.44 103.65,85.32 105.3,85.32 106.65,83.97 106.98,83.97 107.05,84.05 107.05,84.58 106.86,84.78 L7.3
USBON#: length 96.5
  TOP w0.102: U18.112 134.66,46.92 134.8,47.06 135.15,47.06 135.79,47.69 135.79,53.61 132.81,56.59 132.81,58.53 132.86,58.58 132.86,59.06 132.49,59.42 132.49,60.41 132.1,60.81 132.1,61.57 131.42,62.24 131.42,68.98 131.16,69.24 129.49,69.24 128.44,70.29 128.44,70.59 126.28,72.75 126.28,73.27 124.46,75.09 124.46,78.33 124.03,78.76 124.03,81.87 125.47,83.31 v1(125.7,83.31)
  IN2 w0.102: v1(93.84,81.36) 95.22,82.73 96.54,82.73 100.35,86.54 100.35,86.56 108.96,86.56 110.63,88.24 120.27,88.24 125.2,83.31 v1(125.7,83.31)
  BOTTOM w0.102: U19.4 81.84,85.69 v2(83,84.53) 83.56,83.97 90.54,83.97 93.08,81.43 93.77,81.43 v1(93.84,81.36)
USBP0+: length 68.7
  TOP w0.102: U12.M16 76.18,65.73 v1(76.56,65.35) ; R17.2 89.13,83.57 89.13,83.22 v2(88.6,82.68) 89.13,82.15 89.13,80.31 88.08,79.26 88.08,78.26 v1(87.7,77.88)
  IN1 w0.102: v1(76.56,65.35) 76.8,65.59 76.8,65.77 76.71,65.86 75.63,65.86 75.38,66.12 75.38,67.13 75.61,67.36 76.42,67.36 77.01,67.95 77.43,67.95 77.59,68.11 77.59,68.63 77.82,68.86 77.82,69.64 78.09,69.91 78.65,69.91 79.46,70.73 79.99,70.73 80.51,70.21 80.51,69.57 80.62,69.46 80.73,69.35 80.73,68.15 80.86,68.02 81.26,68.02 81.39,68.15 81.39,68.96 81.74,69.32 84.13,69.32 84.81,70.01 84.81,70.53 84.43,70.91 84.43,73.69 86.7,75.96 89.78,75.96 92.04,73.7 92.04,73.14 92.21,72.97 93.09,72.97 93.33,72.74 93.33,72.32 93.09,72.09 92.14,72.09 92.02,71.96 92.02,71.35 92.09,71.27 92.24,71.27 92.55,71.58 93.62,71.58 93.86,71.34 93.86,70.93 93.62,70.69 92.93,70.69 92.8,70.56 92.8,70.31 92.93,70.18 93.46,70.18 93.67,69.98 93.67,69.47 94.58,68.55 95.71,68.55 95.84,68.68 95.84,69.09 95.59,69.33 95.06,69.33 94.39,70 94.39,70.35 94.59,70.55 95.47,70.55 95.6,70.68 95.6,70.93 95.47,71.06 94.67,71.06 94.39,71.34 94.39,71.68 94.75,72.04 94.75,72.32 93.38,73.69 92.98,73.69 90.07,76.59 88.09,76.59 87.85,76.83 87.85,77.72 v1(87.7,77.88)
USBP0+_R: length 9.4
  TOP w0.102: CN6.3 88.91,91.9 89.01,91.8 89.01,91.59 88.13,90.7 88.13,88.57 89.06,87.64 89.06,86.5 v2(88.53,85.97) 89.11,85.39 89.11,85.12 R17.1
USBP0-: length 68.7
  TOP w0.102: v1(77.24,65.35) 76.89,65.7 U12.K16 ; R18.2 89.31,83.52 89.31,83.25 v2(89.87,82.69) 89.31,82.13 89.31,80.24 88.26,79.18 88.26,77.98 v1(88.36,77.88)
  IN1 w0.102: v1(77.24,65.35) 76.99,65.6 76.99,65.85 76.79,66.05 75.71,66.05 75.57,66.2 75.57,67.05 75.69,67.17 76.5,67.17 77.09,67.76 77.51,67.76 77.78,68.03 77.78,68.55 78.01,68.78 78.01,69.56 78.17,69.72 78.73,69.72 79.54,70.54 79.91,70.54 80.32,70.13 80.32,69.49 80.37,69.44 80.49,69.32 80.54,69.27 80.54,68.07 80.78,67.83 81.34,67.83 81.58,68.07 81.58,68.89 81.82,69.13 84.2,69.13 85,69.93 85,70.61 84.62,70.99 84.62,73.61 86.78,75.77 89.7,75.77 91.85,73.62 91.85,73.06 92.13,72.78 93.01,72.78 93.14,72.66 93.14,72.4 93.01,72.28 92.06,72.28 91.82,72.04 91.82,71.27 92.01,71.08 92.32,71.08 92.63,71.39 93.54,71.39 93.67,71.26 93.67,71.01 93.54,70.88 92.85,70.88 92.61,70.64 92.61,70.23 92.85,69.99 93.38,69.99 93.48,69.9 93.48,69.39 94.5,68.36 95.79,68.36 96.03,68.61 96.03,69.16 95.67,69.52 95.14,69.52 94.58,70.08 94.58,70.27 94.67,70.36 95.55,70.36 95.79,70.6 95.79,71.01 95.55,71.25 94.75,71.25 94.58,71.42 94.58,71.6 94.94,71.96 94.94,72.4 93.46,73.88 93.06,73.88 90.15,76.78 88.17,76.78 88.04,76.91 88.04,77.64 88.28,77.88 v1(88.36,77.88)
USBP0-_R: length 9.4
  TOP w0.102: R18.1 89.29,85.21 89.29,85.46 v2(89.8,85.97) 89.24,86.53 89.24,87.71 88.31,88.64 88.31,90.63 89.19,91.51 89.19,91.8 89.29,91.9 CN6.2
USBP1+_CN: length 6.7
  TOP w0.102: L7.4 106.86,87.41 107.24,87.8 107.24,88.18 107.13,88.29 D7.1 107.23,88.87 107.23,88.98 106.84,89.36 v2(106.63,89.36) 107.18,89.91 107.18,90.46 106.98,90.66 106.98,90.83 106.31,91.5 CN8.3
USBP1-_CN: length 6.6
  TOP w0.102: CN8.2 107.78,91.5 107.15,90.87 107.15,90.73 107.35,90.53 107.35,89.91 v2(107.9,89.36) 107.76,89.36 107.41,89.01 107.41,88.92 D8.1 107.53,88.29 107.42,88.18 107.42,87.8 107.71,87.51 L7.1
USBP2+: length 77
  TOP w0.102: v1(76.42,68.45) 76.9,67.97 U12.K12
  IN1 w0.102: v1(76.42,68.45) 76.42,68.58 76.33,68.67 76.04,68.67 75.69,68.31 75.3,68.31 74.94,68.67 74.72,68.67 74.49,68.44 74.49,68.3 74.91,67.88 74.91,67.54 74.62,67.25 74.28,67.25 73.86,67.67 73.72,67.67 73.29,67.23 71.79,67.23 71.4,67.63 71.15,67.63 70.76,67.23 70.18,67.23 69.76,67.65 69.55,67.65 69.13,67.23 67.98,67.23 67.25,66.51 65.45,66.51 65.18,66.24 62.75,66.24 62.45,65.94 58.37,65.94 56.88,67.42 54.99,67.42 53.72,66.15 51.68,66.15 50.25,67.58 49.75,67.58 49.34,67.98 48.68,67.98 46.48,70.18 44.77,70.18 44.52,70.43 44.52,71.03 44.93,71.45 47.06,71.45 47.41,71.81 47.41,74.28 46.57,75.12 45.29,75.12 45.13,74.96 45.13,74.42 45.25,74.3 46.5,74.3 46.74,74.06 46.74,73.59 46.5,73.36 45.25,73.36 45.13,73.23 45.13,72.26 44.89,72.02 44.02,72.02 43.78,72.26 43.78,74.27 44.2,74.69 44.2,74.93 44.06,75.07 43.71,75.07 43.01,74.37 41.64,74.37 41.41,74.61 41.41,75.1 41.28,75.22 40.91,75.22 40.77,75.08 40.77,72.85 40.9,72.72 41.15,72.72 41.28,72.85 41.28,73.43 41.57,73.72 43.05,73.72 43.29,73.49 43.29,72.93 43.05,72.7 42.31,72.7 42.18,72.57 42.18,71.83 42.33,71.68 42.54,71.68 42.69,71.83 v1(42.69,72.01)
  BOTTOM w0.102: v1(42.69,72.01) 42.54,72.01 42.16,71.63 42.16,70.06 41.97,69.88 41.97,68.19 42.1,68.06 CN16.27
USBP2-: length 77
  TOP w0.102: U12.J12 77.6,68.06 77.27,68.39 v1(77.17,68.39)
  IN1 w0.102: v1(77.17,68.39) 76.7,68.86 75.96,68.86 75.61,68.5 75.38,68.5 75.02,68.86 74.64,68.86 74.3,68.52 74.3,68.22 74.72,67.8 74.72,67.62 74.54,67.44 74.36,67.44 73.94,67.86 73.64,67.86 73.21,67.42 71.87,67.42 71.48,67.82 71.07,67.82 70.68,67.42 70.26,67.42 69.84,67.84 69.47,67.84 69.05,67.42 67.9,67.42 67.17,66.7 65.37,66.7 65.1,66.43 62.68,66.43 62.37,66.13 58.45,66.13 56.96,67.62 54.92,67.62 53.65,66.35 51.76,66.35 50.33,67.77 49.83,67.77 49.42,68.17 48.76,68.17 46.56,70.37 44.85,70.37 44.71,70.51 44.71,70.96 45.01,71.26 47.14,71.26 47.6,71.73 47.6,74.36 46.65,75.31 45.21,75.31 44.94,75.03 44.94,74.34 45.17,74.1 46.42,74.1 46.55,73.98 46.55,73.67 46.42,73.55 45.17,73.55 44.94,73.31 44.94,72.34 44.81,72.21 44.1,72.21 43.97,72.34 43.97,74.19 44.39,74.61 44.39,75.01 44.14,75.26 43.63,75.26 42.93,74.56 41.72,74.56 41.6,74.69 41.6,75.17 41.36,75.41 40.83,75.41 40.58,75.16 40.58,72.77 40.82,72.53 41.23,72.53 41.47,72.77 41.47,73.36 41.65,73.53 42.97,73.53 43.09,73.41 43.09,73.01 42.97,72.89 42.23,72.89 41.99,72.65 41.99,72.28 v1(41.75,72.03)
  BOTTOM w0.102: CN16.26 41.6,68.06 41.8,68.26 41.8,69.95 41.98,70.13 41.98,71.81 v1(41.75,72.03)
USBP3+: length 76.5
  TOP w0.102: U12.K10 76.42,69.29 v1(76.41,69.29)
  IN1 w0.102: v1(40.48,72.03) 40.28,71.83 40.15,71.83 40.07,71.91 40.07,75.34 41.09,76.35 42.43,76.35 42.95,75.83 46.9,75.83 48.29,74.44 48.29,73.96 48.5,73.75 49.38,73.75 49.48,73.65 49.48,73.37 49.38,73.27 48.5,73.27 48.29,73.05 48.29,71.68 47.37,70.77 47.37,70.25 48.97,68.66 49.23,68.66 49.53,68.96 49.53,69.42 49.66,69.55 50.04,69.55 50.17,69.42 50.17,68.5 50.38,68.29 51.07,68.29 51.85,69.07 52.03,69.07 52.21,68.89 52.21,68.71 51.3,67.8 51.3,67.5 51.96,66.84 53.42,66.84 54.7,68.12 54.7,68.67 54.94,68.91 55.12,68.91 55.24,68.8 56.04,68.8 56.23,68.99 56.23,69.47 56.35,69.6 56.61,69.6 56.73,69.47 56.73,69.1 56.97,68.86 57.4,68.86 57.62,69.09 57.62,69.99 57.75,70.12 58,70.12 58.13,69.99 58.13,69.22 58.39,68.96 58.59,68.96 58.72,68.83 58.72,68.56 58.59,68.44 57.71,68.44 57.47,68.2 57.47,67.79 57.71,67.55 58.28,67.55 58.45,67.38 58.45,66.93 58.69,66.7 64.74,66.7 65.35,67.3 65.35,68.02 65.45,68.12 65.82,68.12 65.97,67.97 65.97,67.45 66.22,67.2 66.93,67.2 67.25,67.51 67.25,68.28 67.38,68.4 67.68,68.4 68.18,67.91 68.81,67.91 69.26,68.35 70.44,68.35 71.11,69.02 71.49,69.02 71.63,68.88 71.63,68.35 72.06,67.92 72.86,67.92 73.35,68.4 73.35,69.21 73.12,69.43 73.12,69.83 73.3,70.02 73.58,70.02 74.04,69.56 75.87,69.56 76.14,69.84 76.72,69.84 76.79,69.77 76.79,69.67 v1(76.41,69.29)
  BOTTOM w0.102: CN16.24 40.6,68.06 40.44,68.22 40.44,70.53 40.1,70.87 40.1,71.65 v1(40.48,72.03)
USBP3-: length 76.5
  TOP w0.102: U12.H10 77.73,68.86 v1(77.32,69.27)
  IN1 w0.102: v1(39.67,72.06) 39.88,72.28 39.88,75.42 41.01,76.54 42.5,76.54 43.02,76.02 46.98,76.02 48.48,74.52 48.48,74.04 48.58,73.94 49.46,73.94 49.67,73.73 49.67,73.29 49.46,73.08 48.58,73.08 48.48,72.97 48.48,71.6 47.57,70.69 47.57,70.33 49.05,68.85 49.16,68.85 49.34,69.04 49.34,69.5 49.58,69.74 50.12,69.74 50.36,69.5 50.36,68.58 50.46,68.48 50.99,68.48 51.77,69.26 52.11,69.26 52.4,68.97 52.4,68.63 51.49,67.72 51.49,67.58 52.04,67.03 53.34,67.03 54.51,68.2 54.51,68.75 54.86,69.1 55.2,69.1 55.32,68.99 55.96,68.99 56.04,69.07 56.04,69.55 56.27,69.79 56.69,69.79 56.93,69.55 56.93,69.18 57.05,69.05 57.32,69.05 57.43,69.17 57.43,70.07 57.67,70.31 58.08,70.31 58.32,70.07 58.32,69.29 58.46,69.15 58.67,69.15 58.91,68.91 58.91,68.48 58.67,68.25 57.79,68.25 57.66,68.12 57.66,67.87 57.79,67.74 58.36,67.74 58.64,67.46 58.64,67.01 58.77,66.89 64.66,66.89 65.15,67.38 65.15,68.1 65.37,68.31 65.89,68.31 66.16,68.05 66.16,67.53 66.3,67.39 66.85,67.39 67.06,67.59 67.06,68.35 67.3,68.59 67.76,68.59 68.26,68.1 68.73,68.1 69.18,68.54 70.36,68.54 71.03,69.22 71.57,69.22 71.82,68.96 71.82,68.43 72.14,68.11 72.78,68.11 73.16,68.48 73.16,69.13 72.93,69.36 72.93,69.91 73.22,70.21 73.66,70.21 74.12,69.75 75.79,69.75 76.06,70.03 76.8,70.03 76.98,69.85 76.98,69.61 v1(77.32,69.27)
  BOTTOM w0.102: v1(39.67,72.06) 39.92,71.81 39.92,70.79 40.26,70.45 40.26,68.22 40.1,68.06 CN16.23
V_BLIGHT:
  vias: v1(26.2,67.11) v1(26.2,66.5) v2(26.84,66.8)
VCORF_UR: length 4.7
  TOP w0.102: U18.44 132.66,29.34 132.55,29.24 132.55,28.8 132.93,28.42 132.93,27.88 C126.1 133.12,26.85 v2(133.61,26.85)
VIS_V1P0_SIOX_PW: length 19.1
  TOP w0.254: U12.AF21 69.15,63.53 v1(68.78,63.91) 68.4,63.53 U12.AG21 ; U12.AN30 65.19,58.98 v1(64.7,59.46) 64.89,59.64 65.15,59.64 U12.AN29 ; U12.Y22 72.26,62.77 v1(71.91,62.43) 71.91,62.4 72.29,62.02 U12.Y24 72.54,62.26 72.85,62.26 U12.V24
  IN2 w0.635: v1(55.9,57.56) 55.9,55.93 56.3,55.53 57.2,55.53 57.78,56.11 57.78,56.72 59.27,58.22 64,58.22 64.58,58.8
  BOTTOM w0.381: v1(71.91,62.43) 72.03,62.43 72.66,63.05 C209.1 ; C239.1 64.2,59.06 64.61,59.46 v1(64.7,59.46)
  vias: v2(48.4,58.98) v2(52.7,58.12)
VL: length 127.9
  TOP w0.203: PC47.2 121.88,45.93 v1(121.71,45.76) PU8.11
  IN2 w0.102: v1(78.63,21.49) 79.43,20.69 88.9,20.69 91.84,17.75 94.94,17.75 96.59,16.1 105.44,16.1 107.2,17.86 107.2,19.49 109.41,21.71 109.41,23.54 112.76,26.89 112.76,31.2 114.64,33.08 116.76,33.08 118.36,34.67 120.88,34.67 121.75,35.53 121.79,35.53 122.61,35.54 123.91,36.84 123.91,40.15 125.29,41.53 125.29,41.99 125.06,42.22 124.55,42.22 121.71,45.06 v1(121.71,45.76)
  BOTTOM w0.102: PR173.1 PR172.1 38.57,16.51 38.5,16.43 38.5,15.39 39.28,14.61 41.01,14.61 41.39,14.22 41.39,11.71 42.14,10.96 47.07,10.96 48.56,9.47 54.97,9.47 58.87,13.38 58.87,15.93 61.81,18.87 62.33,18.87 64.37,18.87 67.12,21.62 74.39,21.62 v2(74.79,22.02) 78.1,22.02 v1(78.63,21.49)
VR_SVID_ALERT#: length 74.1
  TOP w0.14: R129.2 85.72,61.77 86.57,61.77 87.15,61.2 89.72,61.2 R127.1 91.23,60.68 91.66,61.1 93.83,61.1 v1(95.09,59.84)
  IN1 w0.14: v1(139.42,56.31) 139.42,56.08 138.68,55.34 133,55.34 132.24,54.58 129.78,54.58 129.08,53.87 126.81,53.87 126.36,54.32 124.64,54.32 124.32,54 121.36,54 121.03,54.32 119.85,54.32 119.49,54.32 119.35,54.18 119.34,54.18 119.31,54.15 118.76,54.15 118.2,53.58 117.6,53.58 117.6,53.58 116.93,53.58 114.91,55.6 113.14,55.6 111.43,57.31 109.37,57.31 108.92,57.77 101.08,57.77 99.25,59.6 99.25,60.04 99,60.29 98.65,60.29 98.54,60.19 95.99,60.19 95.92,60.12 95.37,60.12 v1(95.09,59.84)
  BOTTOM w0.14: PR97.1 133.07,65.03 PR99.2 133.75,65.24 135.15,65.24 v2(136.71,63.69) 138.18,62.22 138.18,60.89 139.6,59.46 139.6,56.49 v1(139.42,56.31)
VR_SVID_CLK: length 74.8
  TOP w0.14: v1(93.26,59.92) 93.21,59.87 92.08,59.87 91.52,59.31 86.99,59.31 R134.2
  IN1 w0.14: v1(140.02,56.41) 139.63,56.81 138.54,56.81 138.23,56.5 132.56,56.5 131.72,55.66 129.34,55.66 128.99,55.32 128.22,55.32 128.17,55.37 124.08,55.37 123.76,55.05 122.29,55.05 122.29,55.05 122.26,55.05 121.75,55.56 119.25,55.56 119.09,55.41 119.09,55.41 119.05,55.37 118.88,55.19 116.81,55.19 114.88,57.12 113.18,57.12 110.99,59.3 107.28,59.3 107.1,59.13 106.52,59.13 105.93,59.72 101.03,59.72 100.47,60.28 100.47,60.66 100.1,61.03 99.8,61.33 98.21,61.33 98.12,61.24 95.56,61.24 95.52,61.2 93.93,61.2 93.26,60.53 v1(93.26,59.92)
  BOTTOM w0.14: PR95.2 134.04,66.11 PR96.2 134.75,65.71 135.82,65.71 138.7,62.83 v2(138.7,62.04) 138.7,61.02 140.07,59.64 140.07,56.46 v1(140.02,56.41)
VR_SVID_DATA: length 88.6
  TOP w0.14: v1(94.45,59.69) 94.86,59.28 94.86,58.97 94.72,58.83 94.01,58.83 93.87,58.69 93.87,58.41 94.01,58.27 94.72,58.27 94.86,58.14 94.86,57.86 94.72,57.72 94.01,57.72 93.87,57.58 93.87,57.3 94.01,57.16 94.72,57.16 94.86,57.02 94.86,56.79 94.63,56.57 93.97,56.57 93.31,57.23 93.31,59.18 93.82,59.69 93.82,60.05 93.34,60.53 v2(92.35,60.53) 91.99,60.53 91.35,59.89 88.59,59.89 87.99,60.49 R135.2
  IN1 w0.14: v1(94.45,59.69) 94.15,59.69 93.87,59.97 93.87,60.38 94.15,60.66 95.72,60.66 95.78,60.71 98.33,60.71 98.43,60.81 99.58,60.81 99.91,60.49 99.91,59.77 100.48,59.2 100.92,59.2 101.54,59.2 101.68,59.06 101.68,58.48 101.82,58.34 102.1,58.34 102.24,58.48 102.24,59.06 102.38,59.2 103.12,59.2 103.26,59.06 103.26,58.43 103.4,58.29 103.68,58.29 103.82,58.43 103.82,59.06 103.96,59.2 104.24,59.2 104.38,59.06 104.38,58.43 104.52,58.29 104.8,58.29 104.94,58.43 104.94,59.06 105.08,59.2 105.36,59.2 105.5,59.06 105.5,58.7 105.91,58.29 107.17,58.29 107.31,58.43 107.31,58.56 107.45,58.7 107.73,58.7 107.87,58.56 107.87,58.43 108.01,58.29 108.29,58.29 108.43,58.43 108.43,58.56 108.57,58.7 108.85,58.7 108.99,58.56 108.99,58.43 109.13,58.29 109.38,58.29 109.78,57.89 110.57,57.89 110.71,58.03 110.71,58.26 110.85,58.39 111.13,58.39 111.27,58.26 111.27,58.03 111.41,57.89 111.6,57.89 113.38,56.12 115.14,56.12 116.59,54.67 116.82,54.67 119.09,54.67 119.27,54.84 119.33,54.84 119.47,54.99 121.54,54.99 122.01,54.52 124.1,54.52 124.42,54.85 127.65,54.85 127.7,54.79 128.16,54.79 128.3,54.65 128.3,54.57 128.44,54.43 128.72,54.43 128.86,54.57 128.86,54.65 129,54.79 129.21,54.79 129.54,55.12 131.99,55.12 132.8,55.93 138.4,55.93 v1(138.75,56.29)
  BOTTOM w0.14: PR98.2 132.05,64.78 PR104.2 133.81,64.03 135.6,64.03 137.64,62 137.64,60.62 139.08,59.18 139.08,56.99 138.75,56.67 v1(138.75,56.29)
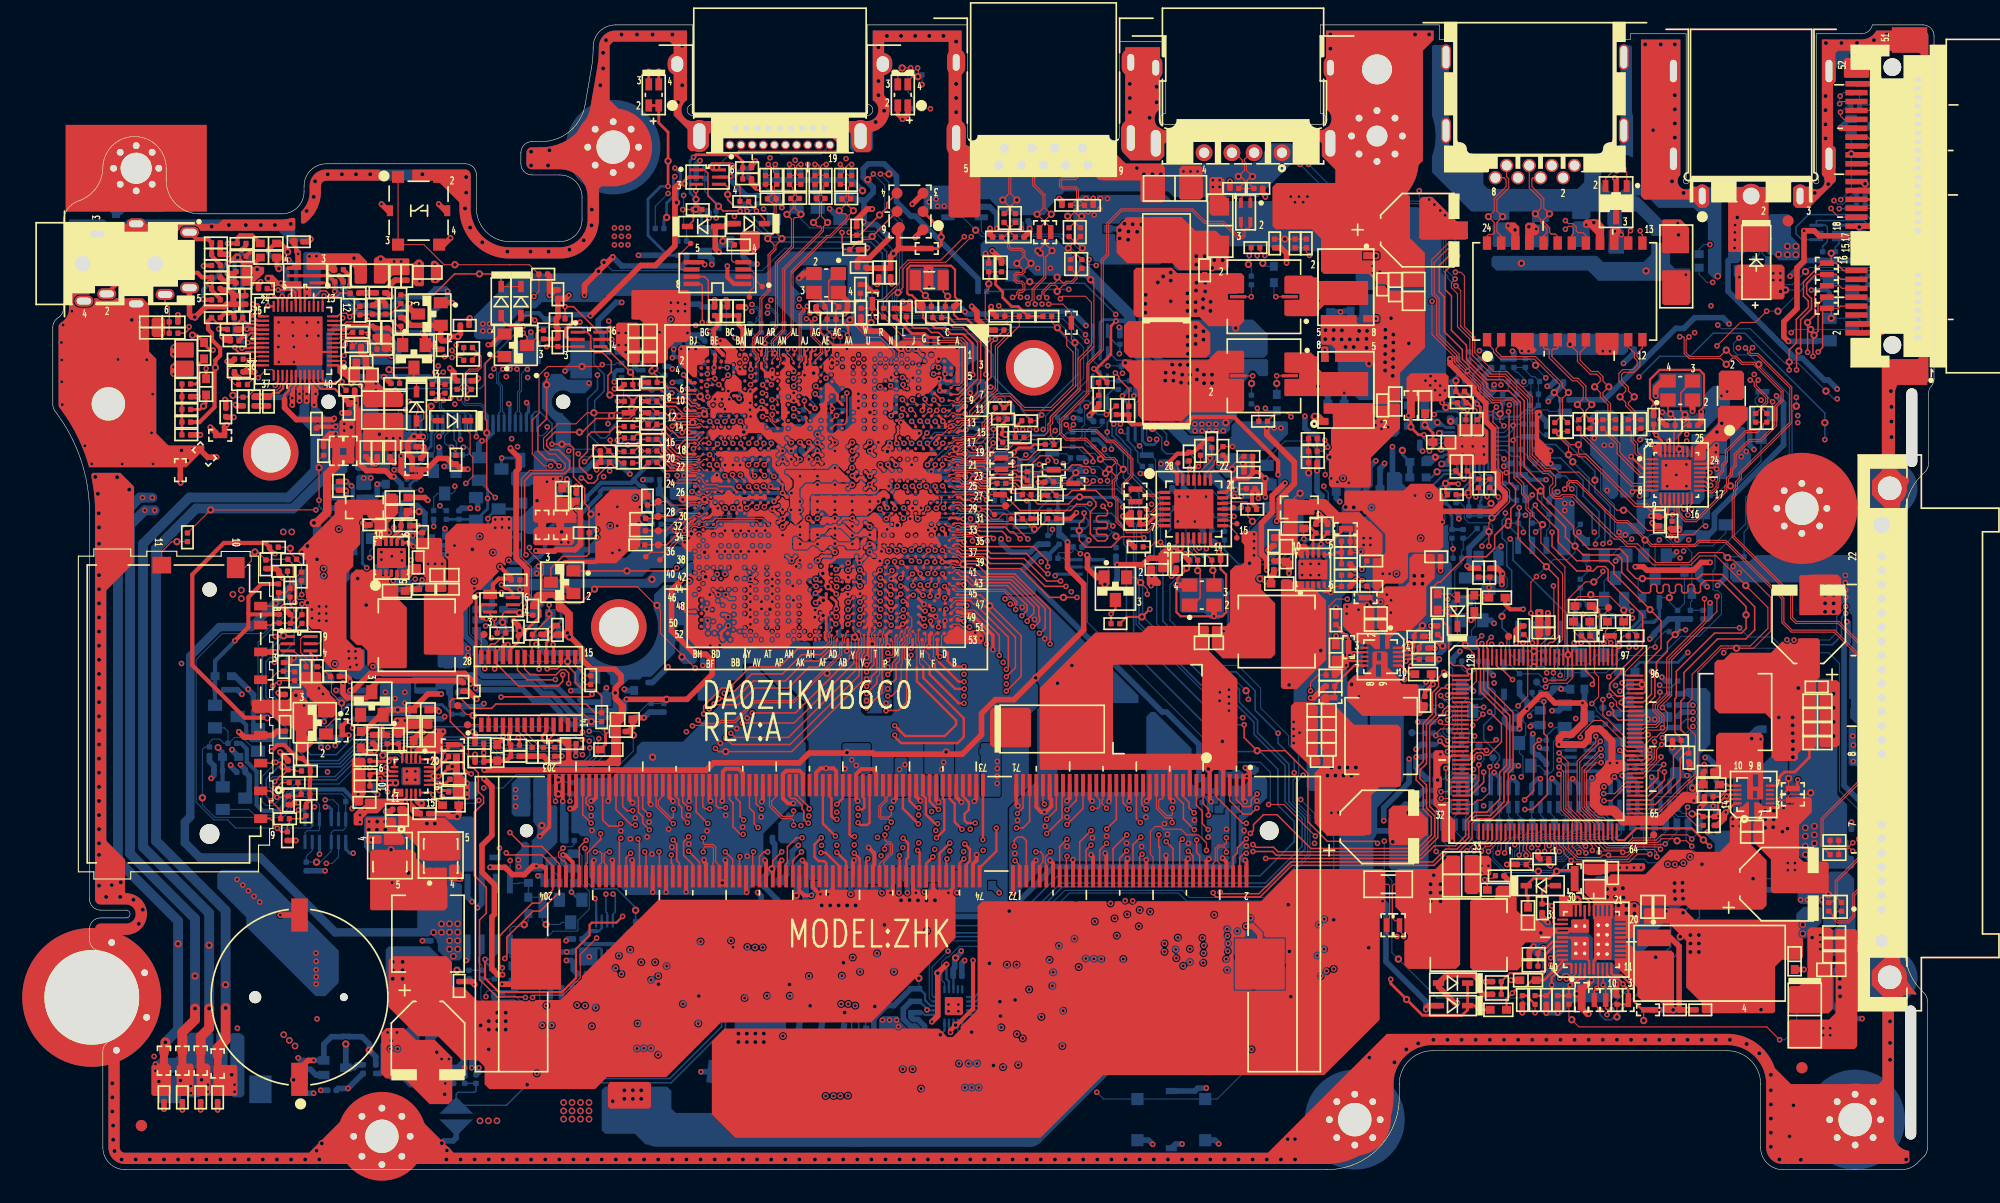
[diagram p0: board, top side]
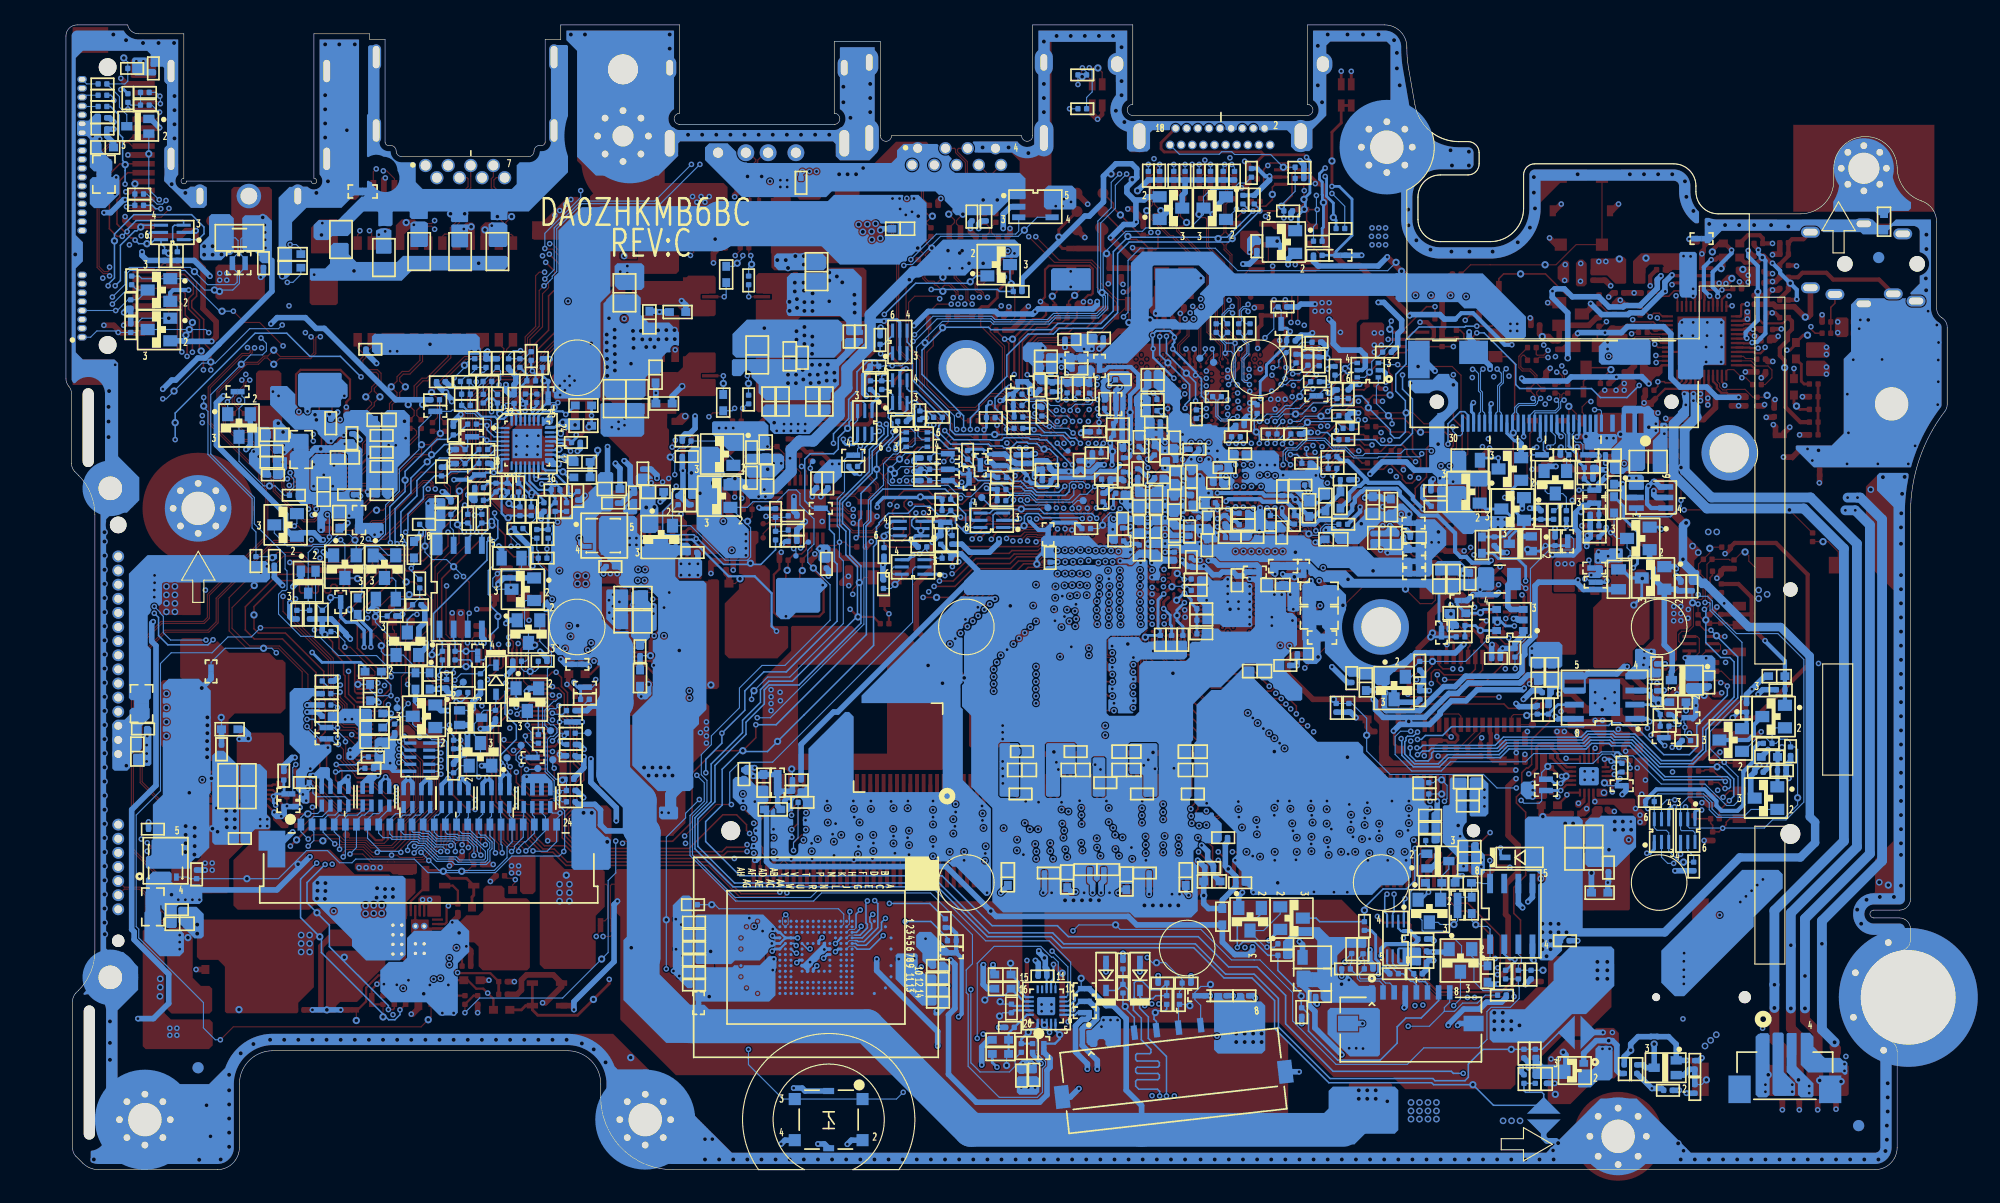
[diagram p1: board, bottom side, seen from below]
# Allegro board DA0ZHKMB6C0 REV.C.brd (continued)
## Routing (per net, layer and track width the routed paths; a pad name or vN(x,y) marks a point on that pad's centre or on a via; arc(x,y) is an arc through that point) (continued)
VRON: length 6.6
  TOP w0.102: U18.80 141.52,38.05 141.41,38.16 141.41,38.92 139.41,40.92 v1(139.41,42.29)
  BOTTOM w0.102: TP45.1 v1(139.41,42.29)
WAKE_SRC_1: length 141.7
  TOP w0.102: U18.84 143.03,39.65 143.17,39.8 144.23,39.8 144.28,39.85 144.34,39.9 144.72,40.28 144.72,40.76 144.12,41.36 144.12,41.8 145.15,42.83 145.15,46.02 148.56,49.42 v1(148.56,51.36)
  IN1 w0.102: v1(154.68,69.09) 155.52,68.25 157.11,68.25 157.34,68.01 157.34,67.04 157.11,66.8 156.66,66.8 151.69,61.83 151.69,56.24 152.7,55.23 152.7,53.46 150.32,51.08 149.6,51.08 149.27,51.41 148.61,51.41 v1(148.56,51.36) 148.15,50.95 144.47,50.95 144.11,50.6 142.43,50.6 142.15,50.87 137.31,50.87 137.18,51 132.19,51 131.47,50.29 127.59,50.29 126.69,49.39 123.82,49.39 122.88,48.45 116.14,48.45 115.89,48.2 115.89,44.78 114.8,43.69 111.54,43.69 110.68,42.82 107.47,42.82 107.03,42.38 v1(107.03,40.67)
  IN2 w0.102: v1(156.35,75.31) 156.04,75.31 155.16,74.43 155.16,70.38 155.54,70 155.54,69.49 155.13,69.09 v1(154.68,69.09)
  BOTTOM w0.102: Q20.3 v2(158.11,75.59) 156.63,75.59 v1(156.35,75.31) ; v1(107.03,40.67) 107.02,40.66 105.85,40.66 97.43,49.08 97.43,55.92 97.47,55.95 97.47,58 97.03,58.44 97.03,60.24 95.67,61.6 95.67,63.51 94.79,64.39 94.41,64.39 94.22,64.58 94.18,64.58 93.73,65.03 U25.3 93.1,65.03 92.83,65.3 92.83,66.32 93.29,66.78 94.15,66.78 94.39,67.01 R266.2 ; Q25.1 154.65,69.06 v1(154.68,69.09) 154.15,69.61 R516.1
WIMAX_LED#: length 3.1
  TOP w0.102: v1(160.78,95.15) 160.78,94.82 161.1,94.5 CN10.42
  BOTTOM w0.102: v1(160.78,95.15) 160.83,95.15 161.47,95.78 R204.1
WLAN_CLK_SCLK: length 12.5
  TOP w0.14: CN10.30 163.66,89.7 164.35,89 164.35,87.5 164.61,87.25 164.61,85.08 163.36,83.83 163.17,83.83 v1(162.98,83.64)
  BOTTOM w0.14: v1(162.98,83.64) 162.65,83.31 v2(161.92,83.31) 161.59,83.31 161.22,83.68 Q16.6 160.65,83.33 160.33,83 R223.1
WLAN_CLK_SDATA: length 19.9
  TOP w0.14: CN10.32 164.36,90.5 165.29,89.56 165.29,84.66 164.61,83.97 v1(164.14,83.97)
  BOTTOM w0.14: v1(164.14,83.97) v1(163.71,84.4) 163.71,84.57 162.88,85.4 158.69,85.4 158.61,85.32 158.61,84.98 Q16.3 159.44,84.98 159.6,84.81 159.6,83.49 159.18,83.07 R222.1
WLAN_LED1#: length 4.4
  TOP w0.102: v1(163.63,95.43) 163.5,95.3 CN10.44
  BOTTOM w0.102: R201.2 R204.2 163.38,95.78 R203.1 v1(163.63,95.43)
WPAN_LED#: length 3.4
  TOP w0.102: v1(160.71,95.91) 160.9,96.1 CN10.46
  BOTTOM w0.102: R201.1 161.09,96.93 v1(160.76,96.59) 160.71,96.54 v1(160.71,95.91)
XDP_H_PRDY#: length 1.9
  TOP w0.102: U12.D18 80.05,65.24 v1(80.05,65.36)
  BOTTOM w0.102: v1(80.05,65.36) 79.35,64.67 TP24.1
XDP_H_PREQ#: length 23
  TOP w0.102: R63.1 89.84,76.27 v2(90.35,75.75) 91.19,74.92 91.19,74.13 91.76,73.56 91.76,70.59 89.75,68.58 87.39,68.58 86.15,69.82 84.92,69.82 84.67,69.57 84.65,69.57 82.87,67.79 82.87,67.69 82.38,67.2 81.77,67.2 81.53,66.96 81.26,66.96 81.11,67.11 80.87,67.11 80.7,66.94 80.7,66.81 80.03,66.14 79.52,66.14 79.21,65.84 U12.F16
XDP_H_TCK: length 3.2
  TOP w0.102: v1(79.36,67.32) 79.7,66.98 U12.D14
  BOTTOM w0.102: v1(79.36,67.32) 79.77,66.91 80.21,66.91 81.11,67.81 R262.1
XDP_H_TDI: length 5.1
  TOP w0.102: U12.F12 79.02,67.83 v1(79.51,68.31)
  BOTTOM w0.102: R251.1 82.78,69.34 81.24,69.34 80.65,68.75 79.87,68.75 79.51,68.39 v1(79.51,68.31)
XDP_H_TDO: length 5.7
  TOP w0.102: U12.G16 78.31,65.97 v1(78.62,66.28)
  BOTTOM w0.102: v1(78.62,66.28) 79.05,66.71 80.3,66.71 80.45,66.86 v1(80.74,66.86) 81.13,66.86 81.86,67.6 82.2,67.6 82.32,67.72 R267.1
XDP_H_TMS: length 6.2
  TOP w0.102: U12.F14 79.02,66.97 v1(78.67,67.32)
  BOTTOM w0.102: v1(78.67,67.32) 79.17,67.82 80.21,67.82 80.99,68.6 80.99,68.8 81.31,69.12 82.85,69.12 R259.1
XDP_H_TRST#: length 4.1
  TOP w0.102: U12.G12 78.38,67.82 v1(78.88,68.31)
  BOTTOM w0.102: R250.2 77.13,69.75 76.85,69.47 76.85,69.06 77.05,68.86 78.45,68.86 78.88,68.43 v1(78.88,68.31)
XIN: length 7
  TOP w0.14: Y9.1 102.52,50.79 103.19,51.46 103.19,53.68 v2(102.97,53.9) C95.1 102.97,54.91 102.12,55.75 U13.10
XOUT: length 5.4
  TOP w0.14: U13.11 102.62,55.81 103.04,55.4 103.69,55.4 C96.1 104.25,54.01 v2(104.33,53.92) 104.44,53.81 Y9.3
XTAL1: length 7.7
  TOP w0.14: Y8.3 146.42,69.9 146.42,68.3 v2(146.8,67.92) 147.18,67.55 C79.1 146.83,66.98 146.45,66.6 146.45,66.29 146.22,66.06 U11.28
XTAL2: length 5
  TOP w0.14: U11.29 145.82,66.47 145.92,66.57 C78.1 145.92,67.58 v2(145.51,68) 145.27,68.23 Y8.1
XTAL25_IN: length 12.8
  TOP w0.14: v1(70.22,74.98) 69.65,75.55 R42.1 69.65,77.41 C32.1 69.44,77.84 69.09,78.19 69.09,78.3 Y6.3 ; v1(67.6,69.17) 67.6,68.63 U12.AH12
  BOTTOM w0.14: v1(67.6,69.17) 67.6,70.84 v2(68.43,71.67) 70.22,73.46 v1(70.22,74.98)
XTAL25_OUT: length 15.2
  TOP w0.14: Y6.1 70.49,80.63 69.79,79.94 69.79,78.26 70.1,77.95 70.37,77.95 C33.1 70.43,77.36 R42.2 70.43,75.64 70.83,75.24 v1(70.83,74.96) ; U12.AH10 68.22,68.83 v1(68.55,68.5)
  BOTTOM w0.14: v1(68.55,68.5) 68.55,68.83 68.14,69.24 68.14,70.64 v2(70.1,72.59) 70.83,73.33 v1(70.83,74.96)
N52444: length 3.8
  TOP w0.102: PR43.2 30.06,37.67 v2(29.68,37.29)
  TOP w0.203: 31.43,37.4 PU9.5
  TOP w0.254: PR43.2 PC57.2 31.18,38.22 31.18,37.64 31.43,37.4
N2441980: length 5.7
  TOP w0.254: PR11.1 v2(122.15,66.83) 122.15,66.79 122.83,66.12 v1(123.31,66.12)
  BOTTOM w0.203: PC113.1 123.97,65.68 124.9,65.68 125.16,65.93 PU12.22
  BOTTOM w0.254: PC113.1 123.31,65.85 v1(123.31,66.12)
N2441992: length 6.1
  TOP w0.254: PR12.2 123.42,67.02 v2(123.41,67.01) 124.13,66.28 PC19.1 124.13,64.96 v1(123.82,64.64)
  BOTTOM w0.203: PU12.21 125.21,65.53 125.05,65.37 124.55,65.37 v1(123.82,64.64)
N2443322: length 2.7
  BOTTOM w0.254: v2(121.38,64.72) 121.38,64.35 PC117.1
  BOTTOM w0.508: PR109.2 PC117.1
N2443370: length 1.9
  BOTTOM w0.508: PC101.1 116.15,70.76 v1(116.15,69.89) PR85.2
N2443568: length 23.3
  TOP w0.102: v1(127.98,60.53) 128.24,60.78 PR19.2 ; PR13.2 110.01,68.1 111.01,68.1 v1(111.37,67.74)
  IN2 w0.102: v1(111.37,67.74) 111.37,67.51 112.46,66.42 113.33,66.42 113.68,66.07 115.55,66.07 119.39,62.23 120.88,62.23 121.7,61.42 125.26,61.42 125.64,61.04 127.47,61.04 v1(127.98,60.53)
N2443616: length 3.2
  TOP w0.102: v1(107.92,71.43) PL7.4
  BOTTOM w0.102: PR89.1 107.81,69.72 v2(107.81,70.74) 107.81,71.32 v1(107.92,71.43)
N2443620: length 3
  TOP w0.102: v1(110.07,71.43) PL7.3
  BOTTOM w0.102: v1(110.07,71.43) v2(110.07,70.74) 110.08,70.73 PR91.1
N2444597: length 4.2
  BOTTOM w0.203: PR116.2 v1(127.36,60.6) 127.36,60.62 PC123.2 128.49,62.46 128.31,62.64 PU12.11
N2445489: length 10.2
  BOTTOM w0.102: PR93.1 134.58,68.22 134.45,68.35 133.5,68.35 133.21,68.05 132.49,68.05 131.92,67.48 131.71,67.48 131.71,67.48 131.1,67.48 130.93,67.31 130.93,66.73 130.53,66.33 PU12.2 ; PR93.1 135.59,69.26 PR90.1 ; PR93.1 135.59,66.31 v2(135.53,66.24)
N2446506: length 2.6
  BOTTOM w0.254: PR79.2 126.34,71.43 TP23.1 PR86.1
N2446664: length 3.1
  BOTTOM w0.102: v1(124.96,69.01) PR86.2
  BOTTOM w0.203: PR86.2 125.93,69.01 127.11,67.82 PU12.27
N2446955: length 2.8
  TOP w0.102: PR8.2 v2(110.81,83.73) PR7.1 PR6.1
N2448066: length 3.1
  TOP w0.102: v2(112.94,62.69) 112.94,63.62 PR17.2 PR16.1 PR15.1
N2453156: length 1.8
  BOTTOM w0.508: PR77.2 114.94,77.18 v1(115.82,77.18) 116.09,77.18 116.16,77.24 PC95.1
N2453320: length 37.5
  TOP w0.102: v1(109.01,82.25) 108.56,82.69 PR9.2
  IN2 w0.102: v1(109.01,82.25) 109.29,82.52 112.1,82.52 112.81,81.81 113.26,81.81 113.53,82.08 113.53,82.48 114.73,83.68 119.38,83.68 122.06,81 122.06,79.26 123.76,77.56 123.76,75.75 127.85,71.65 129.91,71.65 130.24,71.32 134.2,71.32 v1(134.28,71.25)
  BOTTOM w0.102: PR82.2 132.78,72.96 v2(133.36,72.38) 133.36,72.28 133.37,72.28 133.37,72.16 v1(134.28,71.25)
N2453360: length 2.4
  TOP w0.102: v1(107.79,78.54) PL6.4
  BOTTOM w0.102: v1(107.79,78.54) 107.8,78.55 PR75.1
N2453364: length 2.7
  TOP w0.102: v1(110,78.54) PL6.3
  BOTTOM w0.102: PR74.1 109.82,78.71 v1(110,78.54)
N2455134: length 1.8
  BOTTOM w0.254: PR92.2 121.92,67.86 v1(121.93,67.85) 121.92,67.84 PC111.1
N2455877: length 4.9
  BOTTOM w0.203: PR88.1 131.27,69.37 130.78,69.37 PC108.1 130.39,68.18 v1(130.23,68.01) 129.79,68.01 129.61,68.2 129.05,68.2 128.71,67.86 PU12.31
N2456910: length 88.4
  IN2 w0.102: v1(128.31,73.69) 125.9,76.1 125.9,79.01 124.73,80.18 124.73,80.84 119.89,85.69 114.2,85.69 113.04,84.53 101.41,84.53 97.1,80.21 95.65,80.21 94.63,79.2 92.35,79.2 90.06,76.91 85.51,76.91 85.08,76.48 82.94,76.48 82.18,75.72 75.18,75.72 72.66,73.2 66.08,73.2 64.61,74.68 61.54,74.68 v1(61.36,74.85)
  BOTTOM w0.102: PR80.1 127.99,72.96 PR81.2 PC98.1 129.39,73.27 128.97,73.69 v1(128.31,73.69) ; PR78.2 59.91,77.36 PR76.1 60.42,77.62 60.57,77.48 60.57,75.64 61.35,74.85 v1(61.36,74.85)
N2456918: length 60.2
  TOP w0.102: v1(129.84,68.61) 129.53,68.3 129.53,67.25 129.99,66.79 129.99,63.11 130.39,62.71 130.39,61.73 131.03,61.09 131.03,60.1 129.16,58.23 v2(129.16,57.4) v1(129.16,56.1)
  IN1 w0.102: v1(129.16,56.1) 128.86,55.79 128.81,55.79 128.71,55.69 128.37,55.69 128.27,55.79 123.98,55.79 123.75,55.56 123.61,55.42 122.45,55.42 122.44,55.43 122.41,55.43 121.91,55.93 119.09,55.93 118.72,55.56 116.98,55.56 115.87,56.67 115.86,56.67 115.03,57.5 113.33,57.5 111.12,59.7 108.17,59.7 107.78,60.09 101.19,60.09 100.85,60.43 100.85,60.81 100.17,61.49 99.86,61.8 99.58,61.8 99.58,61.81 98.4,61.81 98.23,61.63 97.35,61.63 97.21,61.77 95.23,61.77 95.03,61.57 94.63,61.57 v1(94.23,61.98)
  BOTTOM w0.102: PC109.1 129.63,68.95 129.84,68.75 v1(129.84,68.61) ; PR110.2 PR111.1 91.94,62.42 93.78,62.42 v1(94.23,61.98)
  BOTTOM w0.203: PU12.30 128.31,67.97 128.9,68.55 PC109.1
N2457578: length 9.1
  TOP w0.254: v1(127.91,68.28) 127.91,68.37 127.29,68.99 PC16.1 127.11,69.11 PR10.2 v2(126.19,70.99)
  BOTTOM w0.203: PU12.29 v1(127.91,68.28) 127.91,68.35 127.86,68.4 PR87.2 128.36,69.5 128.36,70.35 PC102.2 127.73,70.99 127.73,71.54 PR81.1
N2457590: length 3.3
  TOP w0.254: PR10.1 127.23,69.78 127.6,69.41 127.6,69.4 v1(128.1,68.9) 128.39,68.61 128.39,67.76 PC18.1
N2457790: length 2
  BOTTOM w0.203: PR80.2 127.36,71.97 v1(127.25,71.86) 126.97,71.58 PC102.1
N2457802: length 1
  BOTTOM w0.102: PR87.1 PC105.1
N2459346: length 3.1
  BOTTOM w0.203: PR107.2 131.45,62.71 v1(130.72,62.71) 130.19,62.71 130.01,62.89 130.01,63.8 129.89,63.93 PU12.8
N2459788: length 60.1
  IN2 w0.102: v1(90.9,63.53) 92.01,62.42 95.53,62.42 95.77,62.66 96.53,62.66 97.22,61.97 97.22,56.72 98.82,55.12 101.39,55.12 101.59,54.92 102.94,54.92 103.14,55.12 106.39,55.12 107.41,56.13 107.41,57.12 109.03,58.75 110.43,58.75 113.76,55.42 114.62,55.42 115.03,55.02 115.03,54.54 116.36,53.2 116.36,52.63 117.15,51.85 117.94,51.85 118.96,50.83 118.96,49.81 119.6,49.17 120.23,49.17 122.72,51.66 125.29,51.66 125.47,51.49 v1(125.47,51.31)
  BOTTOM w0.102: v1(125.47,51.31) 125.47,51.33 126.1,51.96 126.1,53.91 126.72,54.54 PR124.1 126.72,55.65 126.85,55.78 PR121.2 127.23,56.81 PC140.1 ; v1(90.9,63.53) 91.28,63.53 91.52,63.77 PR102.1 91.14,64.41 PR100.2
N2459816: length 53.6
  IN1 w0.102: v1(94.86,61.98) 97.29,61.98 97.43,61.84 98.15,61.84 98.32,62.01 99.66,62.01 99.66,62.01 100.32,62.01 101.32,61 107.19,61 108.24,59.95 111.22,59.95 113.44,57.73 115.08,57.73 115.94,56.87 115.96,56.87 117.06,55.77 118.64,55.77 119.01,56.14 121.99,56.14 122.5,55.63 122.53,55.63 122.53,55.63 123.52,55.63 123.66,55.77 123.66,55.77 123.91,56.01 128.45,56.01 v1(128.54,56.1)
  BOTTOM w0.102: PC137.1 126.58,60.01 126.95,59.64 126.95,58.6 127.36,58.2 129.24,58.2 129.51,57.94 129.51,57.25 128.54,56.29 v1(128.54,56.1) ; v1(94.86,61.98) 94.86,62.48 v2(94.68,62.66) 94.09,63.25 92.73,63.25 92.56,63.42 92.06,63.42 91.66,63.02 PR106.2 PR105.2
  BOTTOM w0.203: PC137.1 126.21,60.21 127.91,61.91 PU12.12
N2460379: length 12.3
  TOP w0.254: v1(126.41,61.7) 126.36,61.75 v2(125.26,61.75) 125.26,60.9 PR21.2
  BOTTOM w0.203: PC128.1 126.71,61.16 127.51,61.96 PU12.13
  BOTTOM w0.254: PR121.1 PC141.2 125.83,58.83 125.7,58.96 125.7,59.59 125.28,60.01 PR115.2 125.2,60.44 125.55,60.79 PC128.1 125.55,61.54 125.7,61.7 v1(126.41,61.7)
N2460411: length 1.8
  BOTTOM w0.102: PR124.2 v1(125.94,55.86) 125.94,56.18 125.83,56.29 PC141.1
N2460459: length 3.3
  TOP w0.254: PC20.1 127.47,62.63 127.47,61.09 v2(127.3,60.91) 127.12,60.73 PR21.1
N2460593: length 2.1
  BOTTOM w0.102: v1(124.98,58.27) 125.2,58.48 PR115.1
  BOTTOM w0.254: PC136.1 PR115.1
N2481405: length 1.4
  BOTTOM w0.102: PR83.1 130.9,70.27 PC108.2
N2482435: length 2.5
  BOTTOM w0.203: v2(129.35,59.94) 129.03,59.63 PR117.2 128.37,60.13 128.49,60.25 PC123.1
N16509126: length 16.7
  TOP w0.254: LED6.3 v1(53.6,98.82)
  IN1 w0.254: v1(53.6,98.82) 54.17,98.25 54.17,94.36 55.06,93.47 55.06,90.25 v1(55.95,89.36)
  BOTTOM w0.254: R192.1 54.97,85.43 v2(55.21,85.67) 55.21,86.97 55.82,87.58 55.82,89.23 v1(55.95,89.36)
N16512880: length 3.8
  TOP w0.102: U7.4 61.22,81.65 61.05,81.81 61.05,82.97 R24.1 61.02,83.49 60.32,83.49 v2(60.27,83.54)
N16529605: length 6
  TOP w0.102: v1(124.83,42.65) 125.19,42.29 125.67,42.29 125.83,42.45 U18.6
  BOTTOM w0.102: v1(124.83,42.65) 124.83,42.49 125.18,42.15 125.33,42.15 126.13,41.35 126.13,40.01 TP31.1
N16532690: length 2.1
  TOP w0.102: v1(76.32,67.84) 76.29,67.82 76.29,67.75 75.95,67.41 U12.M13
  BOTTOM w0.102: R270.2 76.28,67.23 v1(76.29,67.23) 76.29,67.26 76.28,67.26 76.28,67.81 v1(76.32,67.84)
N16563782: length 1.7
  BOTTOM w0.14: PU12.5 130.94,65.13 PR98.1
N16563868: length 2.7
  BOTTOM w0.14: PU12.4 131.23,65.53 v1(131.33,65.63) 131.64,65.94 PR97.2
N16564009: length 3.3
  BOTTOM w0.14: PR95.1 131.46,67.08 v1(131.33,66.95) 131.33,66.57 130.69,65.93 PU12.3
N16585380: length 1
  TOP w0.102: U13.18 106.04,59.44 TP55.1
N16624010: length 3.7
  BOTTOM w0.203: PC197.1 PR184.1 83.28,11.74 v2(82.64,12.37) 82.38,12.64 82.02,12.64 81.8,12.85 PU16.1
N16782265: length 49.4
  IN1 w0.102: v1(144.49,56.67) 144.14,57.02 144.09,57.02 142.21,58.9 135.27,58.9 133.9,60.27 130.67,60.27 130.4,60 127.55,60 127.31,59.76 124.61,59.76 124.43,59.58 120.89,59.58 119.6,60.87 118.08,60.87 116.3,62.65 114.56,62.65 v1(114.44,62.54)
  BOTTOM w0.102: v1(144.49,56.67) 144.11,56.29 PQ22.3 142.84,53.24 142.59,52.98 142.59,51.82 PR134.2 ; PQ11.2 109.18,63.9 110.84,65.56 PC112.2 112.99,65.44 113.5,64.92 114.04,64.92 v2(114.85,64.11) 114.44,63.7 v1(114.44,62.54)
N16827218: length 34.4
  IN1 w0.102: v1(28.52,55.07) 28.52,54.7 29.16,54.05 37.46,54.05 38.32,53.19 38.32,52.58 37.84,52.1 37.84,51.54 38.5,50.87 39.49,50.87 40.17,50.19 40.17,48.57 v1(39.44,47.83)
  BOTTOM w0.102: PR113.2 29.96,57.07 29.68,56.79 PQ18.3 28.79,55.96 28.52,55.68 v1(28.52,55.07) ; PQ28.2 48.2,44.35 47.92,44.63 47.92,45.25 PC163.2 v2(46.3,45.73) 43.31,45.73 41.22,47.83 v1(39.44,47.83)
N16827382: length 17.7
  TOP w0.254: LED6.2 LED6.1 54.5,94.19 55.34,93.35 v2(55.34,90.75) v1(55.34,88.47)
  BOTTOM w0.254: v1(55.34,88.47) 54.68,88.47 53.53,87.33 53.53,84.05 54.97,82.62 R197.1 R198.1
N16853934: length 15.6
  TOP w0.102: v1(149.04,62.71) U11.21
  BOTTOM w0.102: R516.2 153.37,69.61 153.13,69.37 153.13,68.99 153.64,68.48 Q25.3 153.64,63.74 151.41,61.52 v2(150.89,61.52) 150.38,61.52 149.55,60.68 R298.2 149.1,61.01 148.71,61.4 148.71,62.13 148.95,62.37 148.95,62.62 v1(149.04,62.71)
N17396502: length 4.5
  BOTTOM w0.102: R416.2 22.08,7.65 v2(21.66,8.08)
  BOTTOM w0.508: R416.2 R414.1 23.16,9.03 23.69,8.51 Q39.2
N17658483: length 2.1
  TOP w0.102: PR56.1 129.02,25.61 128.79,25.85 v1(128.79,26.1) 128.91,26.22 129.53,26.22 PC78.1
N17711248: length 6.4
  TOP w0.102: v2(143.09,13.42) PR70.2
  TOP w0.203: PR70.2 142.97,14.38 142.21,15.14 142.21,16.37 141.1,17.48 140.39,17.48 140.19,17.68 PU11.10
N17719024: length 8.8
  TOP w0.203: PU11.37 134.97,20.1 134.26,19.38 134.26,17.98 134,17.73 v1(133.98,17.73) 133.93,17.68 131.04,17.68 PR60.1
  TOP w0.254: PR61.2 PR60.1
N17726601: length 5.5
  TOP w0.203: PU11.1 136.59,18.39 136.46,18.52 136.06,18.52 134.81,17.26 v1(134.81,16.62) 134.81,16.13 PC88.1 PR63.2
N17863079: length 2.2
  TOP w0.102: PC89.2 v2(140.68,13.74)
  TOP w0.203: PR68.1 PC89.2
N17863093: length 3.6
  TOP w0.203: PR68.2 141.7,16.22 v1(141.23,16.69) 141.23,16.74 140.8,17.17 140.17,17.17 139.79,17.56 PU11.9
N17879873: length 1.8
  TOP w0.102: v1(103.75,55.88) 103.62,56.01 U13.13
  BOTTOM w0.102: v1(103.75,55.88) 103.55,55.68 TP56.1
N17879875: length 1.8
  TOP w0.102: U13.12 v1(103.12,55.93)
  BOTTOM w0.102: v1(103.12,55.93) 102.59,56.46 TP57.1
N18086472: length 6.4
  TOP w0.102: LED7.3 76,98.74 v2(76.39,99.13) 76.4,99.14 v1(77.16,99.14)
  BOTTOM w0.102: R193.1 77.4,96.47 76.9,96.97 76.9,98.88 v1(77.16,99.14)
N18086480: length 3
  TOP w0.102: v1(77.78,99.13) 77.85,99.06 77.85,98.39 v2(77.8,98.34) 77.3,98.34 76.9,97.94 LED7.4
  BOTTOM w0.102: v1(77.78,99.13) 77.4,98.75 R194.1
N18090006: length 74.8
  TOP w0.102: v1(90.62,78.36) 90.85,78.59 92.85,78.59 93.41,78.03 93.41,74.16 92.19,72.94 92.19,70.23 89.73,67.77 89.73,67.31 89.5,67.08 89.5,66.37 89.17,66.04 87.83,66.04 87.68,65.89 R104.1 86.94,65.48 86.15,65.48 85.56,64.89 84.76,64.89 83.88,64.01 82.64,64.01 82.42,63.78 81.75,63.78 81.63,63.9 80.99,63.9 U12.B20
  IN2 w0.102: v1(90.62,78.36) 90.06,78.92 86.12,78.92 85.54,78.33 82.54,78.33 80.74,76.53 74.29,76.53 v1(74.08,76.73)
  BOTTOM w0.102: v1(74.08,76.73) 73.68,77.14 73.68,81.81 72.58,82.91 65.83,82.91 63.81,80.89 50.32,80.89 v2(49.57,81.64)
N18134434: length 12.5
  TOP w0.102: D16.1 D19.1
  TOP w0.14: R52.2 34.24,78.7 36.14,80.59 v2(38.37,80.59) 39.89,80.59 40.33,80.16 D19.1
N18246859: length 7.8
  TOP w0.102: R166.1 125.72,51.82 126.03,51.51 D24.2 127.14,51.51 127.32,51.69 C101.2 128.39,51.69 128.62,51.46 R165.1 129.15,52.35 v1(129.18,52.38) 129.25,52.45 C98.1 C97.1
N18278202: length 124.3
  TOP w0.203: v1(98.67,50.42) 98.64,50.42 v2(97.96,49.73) 96.57,49.73 PR170.1 ; v1(51.25,22.78) 50.69,22.23 48.48,22.23 48.28,22.02 48.28,21.08 47.06,19.86 47.06,17.24 45.79,15.97 40.12,15.97 38.88,17.21 v1(38.88,18.92)
  IN2 w0.203: v1(51.25,22.78) 51.68,22.35 65.27,22.35 65.85,21.77 77.79,21.77 77.99,21.97 78.93,21.97 79.94,20.97 90.68,20.97 92.18,19.47 94.87,19.47 97.27,17.07 103.9,17.07 105.3,18.47 105.87,18.47 106.23,18.83 106.23,19.97 108.3,22.04 108.3,24.18 111.76,27.64 111.76,32.11 110.56,33.31 110.56,36.76 109.24,38.08 108.22,38.08 104.44,41.86 104.44,43.99 104.44,43.99 104.44,44.09 98.67,49.86 v1(98.67,50.42)
  BOTTOM w0.203: PU15.2 39.84,19.41 39.36,18.92 v1(38.88,18.92) 38.88,18.72 39.66,17.94 PR173.2
N18278204: length 6.4
  BOTTOM w0.102: v1(41.14,27.81) 41.14,27.32 41.11,27.3 PU15.8 41.88,25.74 41.94,25.81 PC183.2 42.79,25.27 42.76,25.25 PR168.1 PR169.1
N18278208: length 11.9
  IN1 w0.254: v1(40.17,28.93) 40.17,28.12 42.61,25.68 44.54,25.68 45.25,24.97 v1(46.65,24.97)
  BOTTOM w0.254: v1(40.17,28.93) 40.17,28.35 39.92,28.09 PD10.1 ; PQ35.1 47.34,24.28 v1(46.65,24.97) 46.65,25.53 PR166.1
N18278220: length 3.4
  BOTTOM w0.102: PQ35.3 45.78,22.25 45.59,22.06 v2(44.36,22.06) 44.03,22.39 PR169.2
N18278227: length 3.8
  BOTTOM w0.102: PQ35.2 45.56,25.2 45.46,25.3 PR166.2 45.46,26.42 44.82,27.05 PQ33.3
N18278261: length 8.4
  BOTTOM w0.102: PQ36.2 42.76,19.2 41.9,18.34 PC188.2 41.34,18.92 41.11,19.15 PU15.1 41.11,21.64 41.36,21.88 42.25,21.88 v2(42.4,22.04) 42.76,22.4 PR168.2
N18278273: length 2.3
  TOP w0.203: PR170.2 v1(95.18,50.01) 95.57,50.4 PQ37.3
N18314354: length 1
  TOP w0.102: v2(112.18,60.86) 112.08,60.86 111.42,60.2
N18314480:
  vias: v1(30.26,57.32)
N18512754: length 4.1
  BOTTOM w0.254: PU13.6 41.98,48.51 v2(41.99,48.51) 42.42,48.95 PR138.2 PR139.2
N18512806: length 4.4
  BOTTOM w0.254: PR132.2 44.08,50.84 PC151.1 42.03,50.06 v2(41.98,50.11) 41.69,50.41 PU13.4
N18596580: length 17.5
  TOP w0.254: LED6.4 v1(54.5,98.83)
  IN1 w0.254: v1(54.5,98.83) 54.58,98.76 54.58,94.49 55.57,93.5 55.57,90.5 v1(55.95,90.12)
  BOTTOM w0.254: R195.1 56.22,84.68 56.1,84.8 v2(56.1,87.02) 56.2,87.12 56.2,87.7 56.22,87.72 56.22,88.87 56.46,89.1 56.46,89.61 v1(55.95,90.12)
N19249672:
  vias: v1(48.25,19.15)
N19253605: length 2
  TOP w0.102: U12.G30 78.31,59.09 v1(78.71,59.49)
  BOTTOM w0.102: v1(78.71,59.49) 78.71,59.72 78.22,60.2 TP48.1
N19253641: length 5.8
  TOP w0.102: 82.46,60.76 81.91,60.76 81.88,60.78 81.21,60.78 80.93,60.5 U12.C27
  TOP w0.14: v1(83.34,60.25) 82.84,60.76 82.46,60.76
  BOTTOM w0.102: v1(83.34,60.25) 82.89,59.8 81.12,59.8 TP50.1
N19253642: length 4.8
  TOP w0.14: TP49.1 81.92,59.74 81.63,60.03 81,60.03 U12.B28
N19253643: length 6.8
  TOP w0.102: 82.98,60.99 81.13,60.99 81.13,60.99 U12.B26
  TOP w0.14: v1(83.97,60.25) 83.43,60.8 83.16,60.8 83.1,60.86 82.98,60.99
  BOTTOM w0.14: TP51.1 86.1,59.74 84.23,59.74 83.97,60 v1(83.97,60.25)
N19253669: length 2.7
  TOP w0.102: v1(66.11,73.84) 66.11,73.41 66.48,73.04 66.48,72.89 66.64,72.73 U12.AL3
  BOTTOM w0.102: TP52.1 65.98,73.71 v1(66.11,73.84)
N19253671: length 1.6
  TOP w0.102: v1(66.72,73.84) 66.72,73.46 66.64,73.38 U12.AL1
  BOTTOM w0.102: v1(66.72,73.84) 66.72,73.5 TP53.1
N19661024: length 5.6
  TOP w0.102: U18.107 136.66,44.21 136.21,43.76 134.59,43.76 134.26,43.44 v1(134.26,43.43)
  BOTTOM w0.102: TP40.1 133.9,43.43 v1(134.26,43.43)
N19667233: length 3.9
  TOP w0.102: U16.7 42.44,39.42 43.88,37.98 R182.1 R181.1
N19667243: length 2.6
  TOP w0.102: U16.6 41.79,39.51 43.12,38.18 R180.2
N19667397: length 2.5
  TOP w0.102: R533.2 47.94,44.43 46.99,45.38 U16.15
N19667450: length 1.2
  TOP w0.102: TP101.1 U16.1
N19667455: length 3.9
  TOP w0.102: TP100.1 37.23,40.95 39.01,40.95 39.19,40.76 U16.2
N19667489: length 6.8
  TOP w0.102: R530.2 v2(48.43,40.33) 47.76,41 43.93,41 43.74,40.8 U16.9
N19667717: length 2.1
  TOP w0.102: TP99.1 38.54,47.92 U16.28
N19837103: length 7.3
  BOTTOM w0.102: Q42.2 59.99,23.01 61.48,21.51 Q45.3 62.7,21.39 61.33,20.02 v1(61.18,20.02) 60.5,20.02 R523.1
N19870274:
  vias: v1(132.12,73.66) v1(132.73,73.63) v1(139.41,73.63) v1(140.05,73.63) v2(136.46,74.26)
N20005341: length 12.8
  TOP w0.102: Q46.5 23.92,47.32 24.15,47.55 24.15,48.16 23.87,48.44 23.29,48.44 22.83,48.9 22.83,51.05 22.57,51.31 22.09,51.31 21.96,51.44 21.96,52.65 21.84,52.78 21.84,53.23 R365.1 22.37,54.48 R363.1 21.35,55.49 v2(21.35,55.91) 21.25,56.01 R186.1
N20136993: length 3.4
  TOP w0.102: CN4.5 19.53,44.08 20.3,44.85 C80.1 21.7,44.85 R543.1
N20159096: length 72.4
  TOP w0.102: v1(141.29,90.04) 141.56,89.78 MR6.1
  IN2 w0.102: v1(151.65,74.83) 151.65,77.24 149.29,79.6 v1(149.29,79.83) 149.29,80.67 149.5,80.87 149.5,83.69 146.73,86.46 143.15,86.46 141.29,88.32 v1(141.29,90.04)
  BOTTOM w0.102: D34.1 148.07,80.54 148.78,79.83 v1(149.29,79.83) ; v1(151.65,74.83) 151.17,74.35 151.17,73.66 151.53,73.3 152.59,73.3 v2(153.43,72.47) 156.18,69.72 156.18,64.4 152.26,60.48 152.26,58.11 149.49,55.34 149.49,54.05 149.32,53.87 149.32,52.22 149.44,52.1 149.75,52.1 150.08,51.77 150.08,49.99 148.07,47.98 146.42,47.98 144.69,46.25 141.27,46.25 139.72,44.7 R361.1 C282.1
N20218729: length 3
  TOP w0.102: R419.2 v1(42.01,52.19) 42.01,51.91 42.21,51.71 42.21,51.08 41.95,50.83 U24.5
N20239051: length 23.1
  BOTTOM w0.102: PQ29.2 17.64,32.41 18.15,31.9 20.59,31.9 21.15,32.46 21.15,33.05 21.91,33.81 26,33.81 26.35,33.46 R187.2 26.35,33.12 Q50.6 26.35,30.77 26.1,30.53 25.26,30.53 25.05,30.31 Q50.3 25.05,28.66 24.05,27.67 v2(23.72,27.67) R234.1 22.8,28.19 23.33,28.73 Q51.5
N20248245: length 30.8
  BOTTOM w0.102: R356.2 15.82,38.35 16.35,38.89 17.06,38.89 18.3,37.64 PQ31.2 ; R356.2 15.76,39.43 15.43,39.75 PQ30.2 ; R356.2 15.38,38.35 15,38.74 14.37,38.74 14.09,38.46 R355.1 13.69,38.03 13.45,37.8 v2(13.45,33.46) 13.45,32.82 14.57,31.7 20.72,31.7 21.4,32.39 21.4,32.99 21.94,33.53 23.28,33.53 23.98,32.83 Q51.3 23.98,30.6 23.89,30.51 22.88,30.51 22.68,30.31 Q51.6
N20295671: length 10.3
  TOP w0.102: R166.2 124.98,50.34 125.38,49.95 126.14,49.95 126.33,49.76 D24.1 126.33,47.9 v2(127.04,47.19) 127.85,46.38 127.85,45.03 128.03,44.86 128.03,43.93 127.35,43.25 U18.4
N20307624: length 3.9
  TOP w0.102: CN4.11 9.8,54.39 9.8,55.6 10.7,56.51 v2(11.17,56.51) R316.1
N20310085: length 8
  TOP w0.508: C226.2 36.66,75.2 v2(36.42,74.96) 35.86,74.96 35.48,74.58 R297.1 34.89,74.71 Q27.2 32.22,75.97 31.53,76.67 R124.2
N20311584: length 4.7
  TOP w0.254: R34.2 79.57,82.88 79.9,83.21 v2(79.9,83.91) 79.9,84.58 U3.2
N20824488: length 6.5
  TOP w0.102: v1(92.96,68.66) 93.05,68.66 R551.1 94.07,70.22 94.04,70.26 R550.1
  BOTTOM w0.102: v1(92.96,68.66) 92.96,68.48 92.8,68.33 92.8,67.03 92.57,66.8 92.57,66.01 92.24,65.68 U25.5
N38782190: length 1.9
  BOTTOM w0.508: PC181.2 30.47,26.79 30.47,25.89 v1(30.52,25.83) PR167.1
N72970043: length 1.9
  TOP w0.102: TP58.1 106.49,57.23 105.78,57.94 U13.15
N72970046: length 1.4
  TOP w0.102: TP59.1 106.11,58.12 105.79,58.44 U13.16
N77036399: length 2.3
  BOTTOM w0.254: PR139.1 PR141.1 v2(46.45,47.93)
N77036417: length 4
  BOTTOM w0.508: PC155.2 40.19,46.69 v1(39.99,46.9) PR140.1 38.88,47.39 38.13,48.14 PU13.1
N77036440: length 27.2
  IN1 w0.254: v1(25.4,38.16) 25.4,40.98 26.05,41.63 26.94,41.63 29.05,43.74 36.52,43.74 37.46,42.8 38.65,42.8 39.03,43.18 39.03,44.15 38.32,44.86 38.32,48.31 v1(38.93,48.92)
  BOTTOM w0.254: PU13.5 40.27,49.46 39.73,48.92 v1(38.93,48.92) ; PR155.2 25.87,38.85 25.87,38.56 25.48,38.16 v1(25.4,38.16)
N77040681: length 2.2
  BOTTOM w0.102: PC154.2 v2(116.63,46.24)
  BOTTOM w0.508: PR146.1 PC154.2
N77040703: length 26.3
  TOP w0.102: v1(147.03,32.61) 146.9,32.49 146.9,31.88 147.81,30.97 PR52.1
  IN2 w0.102: v1(150.28,46.51) 149.67,46.51 149.01,45.85 149.01,45.85 148.54,45.37 148.54,40.72 148.12,40.31 148.12,38.41 149.01,37.52 149.01,34.04 147.59,32.61 v1(147.03,32.61)
  BOTTOM w0.102: v1(150.28,46.51) 150.69,46.91 v2(151.43,46.91) 154.88,46.91 156.15,45.64 PR144.1
N77040765: length 3.3
  TOP w0.102: v1(149.33,32.71) PC68.2
  TOP w0.203: PC68.2 149.98,33.55 150.58,34.15 PU10.11
N77090490: length 2.3
  TOP w0.102: v1(33.21,53.06) 32.98,52.82 PC39.2
  TOP w0.508: PC39.2 31.85,52.22 PR34.2
N77093840: length 9.9
  BOTTOM w0.102: PQ25.2 127.85,51.21 127.96,51.11 127.96,48.9 127.6,48.54 PQ26.3 127.6,46 127.85,45.75 PR143.1 128.23,45.08 127.98,44.83 v2(127.45,44.83) 127,44.83 126.72,45.1 PR142.2
N77097662: length 17.1
  BOTTOM w0.102: 143.21,56.65 143.09,56.54 PQ22.2 142.31,56.06 141,56.06 140.21,55.27 PQ21.2 ; 143.21,56.65 143.7,57.15 144.71,57.15 145.8,56.06 146.88,56.06 147.41,55.52 PQ24.3 147.41,51.18 147.29,51.05 PR136.1 PR137.2 ; 143.21,56.65 v2(143.21,56.65)
N77098719: length 6.1
  BOTTOM w0.102: PQ24.2 146.75,50.94 PC152.1 145.39,51.08 v2(145.39,51.47) 145,51.47 145,51.47 PR133.2
N77135926: length 4.3
  TOP w0.102: v2(158.11,33.91) 157.98,33.78 156.28,33.78 156.12,33.62 PR50.2 155.36,33.25 155.07,32.95 PU10.3
N77159527: length 2.3
  TOP w0.381: PR154.2 26.42,40.31 v1(26.76,40.31)
  BOTTOM w0.381: PU14.1 27.02,40.57 v1(26.76,40.31)
N77159544: length 4.7
  BOTTOM w0.102: v2(37.81,40.87) 37.69,40.99 PR151.2
  BOTTOM w0.254: PU14.7 35.01,41.84 PR150.2 PR151.2
N77159572: length 3.8
  BOTTOM w0.254: PR153.1 PC173.2 25.81,41.06 26.58,41.84 PU14.2
N77164289: length 16.3
  BOTTOM w0.102: v2(22.9,51) 22.95,51.05 PR129.2
  BOTTOM w0.508: PQ18.2 26.76,54.43 26.43,54.1 26.43,53.21 PQ23.2 ; PQ23.2 25.44,47.22 24.73,46.51 24.73,44.86 24.81,44.78 PQ27.3 ; PQ23.2 24.35,52.22 24.21,52.09 PR130.1 PR129.2
N77164358:
  vias: v1(22.6,41.76)
N77164885: length 10
  BOTTOM w0.254: PR118.2 PR119.1 37.98,58.51 PQ15.2 ; PQ15.2 39.11,59.47 v1(39.11,60.4) 39.11,61.24 PQ12.2 ; PQ15.2 38.07,57.71 38.24,57.53 38.73,57.53 39.39,56.88 PQ20.3
N77164911: length 7.5
  BOTTOM w0.254: PQ14.2 41.53,59.44 PQ15.3 39.9,59.44 39.13,58.67 v1(39.13,58.57) 39.13,57.63 39.83,56.94 40.47,56.94 PC119.2 PR103.2
N77164954: length 3.5
  BOTTOM w0.254: PQ20.2 36.63,55.65 v1(36.14,56.15) PC143.1 PR123.2
N77521058: length 6.3
  TOP w0.102: U18.30 127.72,32.85 128.11,33.25 128.53,33.25 129.2,33.92 129.2,36.2 v1(129.25,36.25)
  BOTTOM w0.102: TP41.1 129.53,36.53 v1(129.25,36.25)
N77521417: length 1.2
  BOTTOM w0.102: R374.1 122.29,39.27 TP36.1
N77522500: length 4.8
  TOP w0.102: TP18.1 139.92,50.38 139.11,49.57 139.11,47.02 139.06,46.97 U18.101
N77651911: length 1.5
  BOTTOM w0.102: CN10.45 167.71,95.66 R205.2
N77651913: length 1.5
  BOTTOM w0.102: CN10.47 167.58,96.67 R202.2
N77651966: length 3.4
  TOP w0.14: v2(159.95,82.46) R29.1 160.39,81.56 161.05,80.9 CN10.16
N77651968: length 2.4
  TOP w0.102: R32.1 160.39,80.54 160.84,80.1 CN10.14
N77651970: length 2.4
  TOP w0.102: R40.1 160.69,79.53 160.92,79.3 CN10.12
N77651972: length 2.3
  TOP w0.102: CN10.10 160.7,78.5 160.68,78.51 R46.1
N77651974: length 3.2
  TOP w0.102: v2(159.95,76.6) R50.1 160.6,77.5 160.8,77.7 CN10.8
N77651983: length 1.6
  BOTTOM w0.102: CN10.51 167.34,97.69 R200.2
N77714296: length 2.5
  TOP w0.102: PR33.2 109.01,52.73 v2(108.58,53.16)
  TOP w0.508: PR33.2 109.57,53.39 109.82,53.65 PC34.2
N77766782: length 3.7
  TOP w0.102: v1(127.88,39.01) 127.64,39.25 U18.14
  BOTTOM w0.102: R535.2 126.83,37.53 127.88,38.58 v1(127.88,39.01)
N107989610: length 4.6
  TOP w0.102: U9.7 25.72,74.77 25.87,74.93 28.06,74.93 28.35,74.64 28.53,74.64 29.17,74 C56.1
N107992729: length 5.9
  TOP w0.102: v2(16.2,69.67) 16.37,69.5 C68.2 17.48,69.5 18.18,70.21 19.78,70.21 19.83,70.16 20.18,70.16 20.46,70.43 20.46,70.71 20.66,70.91 U9.39
N107992826: length 5.5
  TOP w0.102: C63.2 16.37,70.64 15.76,71.25 15.76,71.97 16.11,72.31 17.19,72.31 17.65,72.77 U9.35
N107992865: length 3.3
  TOP w0.102: C63.1 18.12,71.26 v1(18.47,71.26) 19.19,71.98 19.73,71.98 19.86,71.85 U9.37
N107994632: length 1.9
  TOP w0.102: C57.1 17.49,72.92 17.55,72.98 18.13,72.98 18.33,73.17 U9.34
N108778749: length 15.9
  TOP w0.102: v1(25.36,79.02) R35.1
  TOP w0.279: R35.1 25.09,80.15 25.09,80.16 v1(24.76,80.49) 24.7,80.43 Q7.2 Q7.5
  TOP w0.508: Q27.3 32.6,76.99 32.07,77.52 v1(32.07,77.93)
  BOTTOM w0.508: v1(32.07,77.93) 31.08,76.94 28.69,76.94 28.54,77.09 27.43,77.09 25.39,79.12 25.39,79.86 v1(24.76,80.49)
N111127099: length 3.9
  TOP w0.203: C35.1 19.4,79.16 v1(20.26,79.16) 21.57,79.16 21.82,78.9 21.82,78.25 21.86,78.21 U9.19
N202517111: length 2.5
  BOTTOM w0.102: v2(155.24,40.69) 155.21,40.67 PR157.1
  BOTTOM w0.508: PR157.1 PC174.2
N202572550: length 2.7
  BOTTOM w0.254: PQ12.3 40.35,64.01 v1(40.38,64.03) 41.82,64.03 PR101.2
N202573721: length 5.1
  BOTTOM w0.254: PQ23.3 27.47,51.51 v2(28.19,50.8)
  BOTTOM w0.305: PQ23.3 28.49,53.24 29.26,54.01 PR127.2
N202573930: length 6.4
  BOTTOM w0.102: PQ25.3 130.56,52.22 130.81,52.48 130.81,53.2 v1(130.39,53.62) 130.14,53.87 128.49,53.87 128.23,54.13 PR125.2
N202576670: length 4.1
  BOTTOM w0.102: PQ21.3 139.8,53.24 139.53,52.97 PR135.2 138.73,51.33 v2(138.33,51.74)

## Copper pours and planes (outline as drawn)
5VUSB_0 on TOP (solid shape): 105.38,89.05 105.38,87.66 105.76,87.27 105.76,86.13 105.5,85.88 104.2,85.88 104.02,86.06 104.02,89.11 104.22,89.31 105.12,89.31
5VUSB_0 on TOP (solid shape): 96.52,90.52 99.68,90.52 100.04,90.15 100.04,87.23 99.83,87.02 97.98,87.02 97.82,87.18 97.82,88.96 97.78,89 94.48,89 94.45,89.03 94.1,89.03 93.82,89.31 93.82,90.83 93.55,91.1 91.84,91.1 91.66,91.28 91.66,92.35 91.79,92.48 94.55,92.48
5VUSB_0 on BOTTOM (solid shape): outline of 393 points within 82.9,85.88 111.73,92.35
+1.0V on TOP (solid shape): 133.95,68.22 133.95,67.88 133.91,67.8 133.7,67.59 133.7,65.81 134.75,64.76 134.75,63.38 134.65,63.28 134.33,63.28 133.28,64.34 133.28,68.23 133.4,68.35 133.82,68.35
+1.0V on TOP (solid shape): 45.81,62.31 45.81,62.03 45.63,61.85 45.36,61.85 45.25,61.75 45.25,60.9 45.68,60.48 47.34,60.48 47.41,60.41 47.41,59.96 47.24,59.79 47.01,59.79 46.8,59.58 46.8,59.29 46.92,59.17 47.1,58.99 47.1,58.26 47.03,58.19 43.4,58.19 43.2,58.39 43.2,62.3 43.31,62.41 45.71,62.41
+1.0V on BOTTOM (solid shape): 78.83,75.08 78.83,74.07 78.32,73.56 76.8,73.56 76.67,73.69 76.67,74.19 76.42,74.45 76.42,75.08 76.55,75.21 78.71,75.21
+1.0V on BOTTOM (solid shape): outline of 235 points within 41.22,61.47 48.5,71.6
+1.0V on BOTTOM (solid shape): outline of 339 points within 63.72,61.2 71.38,71.99
+1.0V on IN1 (solid shape): outline of 320 points within 64.43,61.27 74.01,66.22
+1.0V on IN2 (solid shape): outline of 97 points within 132.62,67.46 135.89,72.8
+1.0V on IN2 (solid shape): outline of 148 points within 55.23,63.88 58.51,66.14
+1.0V on IN2 (solid shape): outline of 172 points within 68.49,65.2 77.89,74.22
+1.0V on IN2 (solid shape): outline of 883 points within 71.67,57.58 89.12,66.25
+1.0V_S5 on TOP (solid shape): outline of 229 points within 33.37,46.33 41.32,58.8
+1.0V_S5 on BOTTOM (solid shape): 45.86,61.39 45.86,59.26 45.81,59.21 45.56,59.21 43.54,57.19 42.68,57.19 42.38,57.48 39.67,57.48 39.56,57.58 39.56,58.7 39.67,58.8 42.18,58.8 43.22,59.84 43.22,61.32 43.4,61.49 45.76,61.49
+1.0V_S5 on BOTTOM (solid shape): outline of 168 points within 63.98,72.54 78.2,82.61
+1.0V_S5 on BOTTOM (solid shape): outline of 189 points within 37.89,74.7 49.62,80.65
+1.0V_S5 on IN2 (solid shape): outline of 1067 points within 35.65,57.48 43.1,76.99
+1.0VSX on TOP (solid shape): 46.9,57.76 46.9,56.41 46.66,56.17 43.36,56.17 43.22,56.31 43.22,57.56 43.48,57.81 46.85,57.81
+1.0VSX on BOTTOM (solid shape): 47.82,58.45 47.82,54.31 47.79,54.28 47.79,53.39 47.77,53.37 46.55,53.37 46.32,53.59 46.32,54.92 45.05,56.19 45.05,57.48 46.09,58.52 47.74,58.52
+1.5V on TOP (solid shape): 19.78,69.75 19.78,69.59 19.7,69.48 19.68,69.34 19.65,69.27 19.57,69.24 18,69.24 17.87,69.37 17.87,69.68 18.06,69.88 19.65,69.88
+1.5V on BOTTOM (solid shape): 37.18,44.63 37.18,43.76 37.05,43.64 36.16,43.64 35.98,43.46 35.98,42.55 36.16,42.37 36.16,41.55 36.14,41.53 35.68,41.53 35.55,41.66 35.55,42.62 35.37,42.8 35.37,43.13 35.3,43.21 34.69,43.21 34.59,43.1 34.59,42.99 34.43,42.84 32.59,42.84 32.5,42.93 32.5,43.37 34.41,43.37 34.41,44.11 32.68,44.11 32.68,43.37 32.5,43.37 32.5,44.55 32.73,44.78 37.02,44.78
+1.05V on BOTTOM (solid shape): 59.47,54.02 59.38,53.92 58.23,53.92 58.23,53.99 57.53,53.99 57.53,53.98 57.47,53.92 57.47,53.59 57.28,53.41 57.07,53.41 56.85,53.18 56.81,53.17 56.77,53.19 56.36,53.32 56.12,52.96 56.1,52.89 56.02,52.86 54.86,52.86 54.35,52.35 46.88,52.35 46.4,51.87 44.11,51.87 43.86,52.12 40.91,52.12 40.73,52.3 40.73,54.03 40.91,54.2 42.1,54.2 42.21,54.1 42.21,53.39 42.43,53.16 53.33,53.16 54.05,53.89 54.07,53.89 54.11,53.92 55.85,53.92 56.13,53.8 56.4,53.92 56.55,53.92 57.31,54.68 59.47,54.68
+1.8V on TOP (solid shape): 39.96,52.12 39.96,51.34 38.7,51.34 38.7,52.1 38.79,52.19 39.89,52.19
+1.8V on TOP (solid shape): outline of 154 points within 48.78,54.55 53.76,61.2
+1.8V on BOTTOM (solid shape): 111.09,67.21 111.09,66.19 109.57,64.67 106.39,64.67 106.01,65.05 106.01,66.95 106.39,67.34 110.96,67.34
+1.8V on IN1 (solid shape): outline of 189 points within 48.27,55.47 53.26,63.63
+1.8V on IN2 (solid shape): outline of 513 points within 129.71,29.85 147.21,39.62
+1.8V on IN2 (solid shape): outline of 1003 points within 35.14,48.11 56.14,77.14
+1.8V on IN2 (solid shape): outline of 1120 points within 108.47,54.64 146.57,67.08
+1.8V_EMMC on BOTTOM (solid shape): 92.74,21.09 92.74,20.05 92.18,19.49 92.18,18.82 91.41,18.06 91.08,18.06 90.95,18.19 90.95,18.8 90.49,19.26 89.93,19.26 89.72,19.47 89.72,19.72 91.39,21.39 92.44,21.39
+1.8V_EMMC on BOTTOM (solid shape): outline of 248 points within 105.38,18.49 112.57,22.96
+1.8V_EMMC on IN1 (solid shape): outline of 290 points within 89.66,19.32 108.17,22.87
+1.8V_S5 on BOTTOM (solid shape): 109.95,62 109.95,61.24 109.82,61.11 108.47,61.11 107.71,60.35 105.76,60.35 105.5,60.6 105.5,61.87 105.76,62.13 108.3,62.13 108.42,62.26 109.69,62.26
+1.8V_S5 on BOTTOM (solid shape): 136.87,60.07 136.87,57.81 136.49,57.43 136.49,56.22 136.48,56.11 136.49,56 136.49,55.4 136.36,55.27 135.47,55.27 135.35,55.4 135.35,57.56 135.07,57.83 135.07,60.26 135.23,60.42 136.52,60.42
+1.8V_S5 on BOTTOM (solid shape): 89.33,83.69 90.31,83.69 92.72,81.28 92.72,80.85 92.3,80.44 88.33,80.44 87.71,81.05 86.02,81.05 85.03,82.04 83.66,82.04 83.46,82.25 83.46,82.66 84.14,82.66 84.14,82.6 84.16,82.55 84.18,82.5 84.2,82.45 84.24,82.41 84.27,82.38 84.32,82.35 84.37,82.32 84.42,82.31 84.47,82.3 84.52,82.3 84.58,82.31 84.63,82.32 84.68,82.35 84.72,82.38 84.76,82.41 84.79,82.45 84.82,82.5 84.84,82.55 84.85,82.6 84.85,82.66 84.85,82.71 84.84,82.76 84.82,82.81 84.79,82.86 84.76,82.9 84.72,82.93 84.68,82.96 84.63,82.99 84.58,83 84.52,83.01 84.47,83.01 84.42,83 84.37,82.99 84.32,82.96 84.27,82.93 84.24,82.9 84.2,82.86 84.18,82.81 84.16,82.76 84.14,82.71 84.14,82.66 83.46,82.66 83.46,83.29 83.86,83.69 89.32,83.69
+1.8V_S5 on IN1 (solid shape): outline of 345 points within 134.97,56.16 148.91,66.26
+1.8V_S5 on IN2 (solid shape): 107.28,60.86 107.28,60.53 106.6,59.84 105.76,59.84 105.63,59.97 105.63,60.86 105.76,60.99 107.15,60.99
+1.8V_S5 on IN2 (solid shape): 148.43,66.95 148.43,65.81 147.95,65.34 146.87,65.34 146.02,66.19 146.02,67.08 146.27,67.34 148.05,67.34
+1.8V_S5 on IN2 (solid shape): outline of 196 points within 71.61,78.66 90.14,84.21
+1.8V_S5 on IN2 (solid shape): outline of 350 points within 84.61,61.21 98.21,67.19
+1.8VPCU on TOP (solid shape): 108.35,57.32 108.35,55.25 108.68,54.92 108.68,53.7 108.65,53.62 108.58,53.6 108.14,53.16 108.58,52.73 108.65,52.7 108.68,52.63 108.68,52.22 109.95,50.95 109.95,46.38 109.57,46 105.21,46 104.24,46.97 104.24,48.82 104.33,48.9 105.5,48.9 105.88,49.28 105.88,53.9 106.36,54.38 106.9,54.38 107.15,54.64 107.15,56.21 106.91,56.45 106.91,57.33 107.06,57.48 108.19,57.48
+1.8VPCU on BOTTOM (solid shape): outline of 158 points within 107.79,55.01 113.25,65.05
+1.35V on BOTTOM (solid shape): 56.23,52.48 56.23,51.12 56.22,51.09 56.2,51.07 56.02,50.75 56.2,50.43 56.22,50.41 56.23,50.38 56.23,48.79 55.97,48.54 55.97,46.51 53.81,44.35 53.05,44.35 52.8,44.09 51.78,44.09 51.27,43.59 50.26,43.59 50.13,43.71 50.13,44.42 49.79,44.77 49.69,44.77 49.37,45.09 48.81,45.09 47.9,46 47.9,46.28 48.1,46.48 48.29,46.48 49.21,45.75 50.31,45.36 53.65,46.62 54.17,50.14 54.12,50.26 54.07,50.38 54.07,51.73 54.95,52.6 56.1,52.6
+1.35V on IN2 (solid shape): outline of 1052 points within 56.37,67.1 66.18,74.16
+1.35VSUS on TOP (solid shape): 87.98,41.34 87.98,38.13 87.85,38 84.55,38 84.29,38.25 84.29,41.3 84.55,41.55 87.76,41.55
+1.35VSUS on TOP (solid shape): 35.4,39.55 35.4,39.27 35.09,38.96 35.09,37.82 34.74,37.46 32.89,37.46 32.73,37.3 32.72,36.56 32.53,36.56 32.53,37.77 33.27,38.51 33.27,38.76 33.77,39.27 33.93,39.27 34.36,39.7 35.25,39.7
+1.35VSUS on TOP (solid shape): outline of 2055 points within 30.19,7.24 81.19,25.2
+1.35VSUS on BOTTOM (solid shape): 35.4,18.57 35.4,17.02 37.98,14.43 40.91,14.43 41.15,14.19 41.15,11.73 40.86,11.43 36.31,11.43 33.75,14 32.48,14 29.94,16.54 29.94,18.47 29.95,18.47 29.95,19.82 30.22,20.09 33.87,20.09
+1.35VSUS on BOTTOM (solid shape): outline of 5725 points within 58,22.68 88.61,54.92
+1.35VSUS on IN2 (solid shape): 35.35,39.57 35.35,39.27 34.86,38.79 34.86,37.72 34.76,37.62 33.67,37.62 33.62,37.66 33.62,39.21 33.65,39.31 33.64,39.41 33.93,39.7 35.22,39.7
+1.35VSUS on IN2 (solid shape): 38.77,15.27 38.95,15.21 39.14,15.27 40.73,15.27 41.11,14.88 41.11,12.58 40.89,12.35 38.66,12.35 37.66,13.36 37.66,14.86 38.07,15.27
+1.35VSUS on IN2 (solid shape): outline of 90 points within 56.13,48.26 61.18,51.99
+1.35VSX on BOTTOM (solid shape): 58,52.6 58,47.65 57.95,47.6 57.95,45.77 57.67,45.49 56.71,45.49 56.35,45.85 56.35,48.29 56.73,48.67 56.73,50.56 56.79,50.75 56.73,50.94 56.73,52.56 56.78,52.61 56.82,52.68 56.99,52.86 56.99,53.11 57.12,53.24 57.37,53.24
+3V on TOP (solid shape): 99.15,54.27 99.15,53.47 99.66,52.96 99.66,52.62 99.56,52.52 98.51,52.52 98.39,52.64 98.39,54.25 98.52,54.38 99.04,54.38
+3V on TOP (solid shape): 63.59,84.32 63.59,82.96 62.92,82.29 61.95,82.29 61.81,82.42 61.81,84.23 62.07,84.48 63.43,84.48
+3V on TOP (solid shape): 53.81,7.7 53.81,5.68 53.62,5.49 50.12,5.49 49.93,5.68 49.93,7.67 50.16,7.9 53.62,7.9
+3V on TOP (solid shape): 23.39,44.78 24.02,44.78 24.15,44.65 24.15,43.73 24.91,42.97 24.91,42.79 25.45,42.24 25.45,40.92 25.22,40.69 23.94,40.69 23.83,40.81 23.83,41.2 23.84,41.3 23.83,41.4 23.83,41.69 22.82,42.7 22.82,43.19 22.34,43.67 22.34,44.66 22.47,44.79 23.38,44.79
+3V on TOP (solid shape): 27.64,72.88 27.64,71.07 27.52,70.95 27.42,70.95 26.96,70.49 26.74,70.49 26.56,70.66 26.56,70.99 26.18,71.37 25.91,71.37 25.6,71.69 25.6,72.21 25.53,72.28 24.71,72.28 24.69,72.3 24.69,72.48 25.72,72.48 25.98,72.22 26.61,72.22 26.61,72.22 26.82,72.22 26.96,72.36 26.96,72.87 27.07,72.98 27.53,72.98
+3V on BOTTOM (solid shape): 62.98,83.75 62.98,82.44 62.86,82.31 62.61,82.31 62.48,82.44 62.48,82.96 62.23,83.21 61.81,83.21 61.69,83.34 61.69,83.72 62.02,84.05 62.68,84.05
+3V on BOTTOM (solid shape): 165.02,89.31 166.8,89.31 167.06,89.05 167.06,86.89 166.68,86.51 165.66,86.51 164.39,87.78 164.39,89.05 164.39,89.06 164.39,89.37 164.56,89.54 164.79,89.54
+3V on BOTTOM (solid shape): 55.64,7.08 55.64,5.5 56.27,4.87 56.27,2.48 56.06,2.27 53.31,2.27 52.36,3.23 49.69,3.23 49.37,3.55 49.37,7.16 49.69,7.48 55.25,7.48
+3V on BOTTOM (solid shape): 119.07,20.65 119.07,15.27 115.2,11.4 112.06,11.4 111.05,12.41 111.05,14.11 111.78,14.84 113.07,14.84 115.8,17.57 115.8,20.82 116.15,21.16 118.56,21.16
+3V on BOTTOM (solid shape): 46.06,33.36 46.07,33.34 46.07,33.31 46.05,33.11 46.13,32.93 46.13,32.28 46.38,32.02 46.38,29.48 46.26,29.36 45.75,29.36 45.62,29.48 45.62,33.29 45.75,33.42 46,33.42
+3V on BOTTOM (solid shape): 25.72,19.7 25.72,16.82 24.5,15.6 23.65,15.6 17.4,21.86 17.4,22.7 17.19,22.91 20.11,22.91 20.11,22.86 20.12,22.81 20.14,22.76 20.17,22.71 20.2,22.67 20.24,22.63 20.29,22.6 20.33,22.58 20.38,22.56 20.44,22.56 20.49,22.56 20.54,22.56 20.59,22.58 20.64,22.6 20.69,22.63 20.73,22.67 20.76,22.71 20.79,22.76 20.8,22.81 20.82,22.86 20.82,22.91 20.82,22.96 20.8,23.02 20.79,23.07 20.76,23.11 20.73,23.15 20.69,23.19 20.64,23.22 20.59,23.24 20.54,23.26 20.49,23.27 20.44,23.27 20.38,23.26 20.33,23.24 20.29,23.22 20.24,23.19 20.2,23.15 20.17,23.11 20.14,23.07 20.12,23.02 20.11,22.96 20.11,22.91 17.19,22.91 14.79,25.32 14.79,26.58 15.18,26.97 18.45,26.97
+3V on BOTTOM (solid shape): 163.54,53.62 163.54,42.44 163.35,42.24 161.74,42.24 161.56,42.42 161.56,46.84 161.84,47.12 161.84,49.86 161.61,50.08 161.58,50.2 161.52,50.3 161.5,50.37 161.52,50.44 161.44,50.98 160.92,50.8 160.85,50.74 160.76,50.77 160.57,50.95 160.57,51.01 160.56,51.06 160.56,51.61 160.57,51.71 160.56,51.82 160.56,52.37 160.57,52.48 160.56,52.58 160.56,52.72 160.44,52.83 160.36,52.83 160.35,52.84 160.16,52.88 159.97,52.83 159.6,52.83 159.4,52.88 159.2,52.83 151.17,52.83 150.84,53.16 150.84,54.38 151.22,54.76 152.65,54.76 153.18,55.3 161.87,55.3
+3V on BOTTOM (solid shape): outline of 593 points within 118.58,45.36 126.33,62.76
+3V on IN1 (solid shape): 127.22,50.83 127.22,50.14 126.76,49.68 125.44,49.68 125.19,49.94 125.19,50.83 125.31,50.95 127.09,50.95
+3V on IN1 (solid shape): 152.04,54.79 152.04,53.31 151.58,52.86 150.51,52.86 150.51,52.88 150.26,53.14 150.26,54.71 150.46,54.92 151.91,54.92
+3V on IN1 (solid shape): outline of 1277 points within 10.5,5.74 53.94,45.37
+3V on IN2 (solid shape): 63.02,83.27 63.02,82.32 62.92,82.22 62.92,81.53 62.87,81.48 61.69,81.48 61.65,81.51 61.65,83.23 61.81,83.4 62.89,83.4
+3V on IN2 (solid shape): 100.86,52.04 100.86,51.6 100.78,51.51 99.89,51.51 99.88,51.52 99.67,51.52 98.93,52.25 97.97,52.25 97.76,52.47 97.76,53.63 97.86,53.73 99.17,53.73
+3V on IN2 (solid shape): 125.09,51.38 125.25,50.99 125.67,50.99 126.04,50.99 126.33,50.7 126.33,49.94 126.2,49.81 123.9,49.81 123.79,49.92 123.79,51.28 123.97,51.46 125.01,51.46
+3V on IN2 (solid shape): 162.12,54.57 162.12,51.75 161.4,51.03 161.37,51.02 161.17,51.02 161.01,50.93 160.94,50.9 160.87,50.93 160.56,51.24 160.56,51.61 160.57,51.71 160.56,51.82 160.56,52.37 160.57,52.48 160.56,52.58 160.56,52.67 160.04,53.19 156.76,53.19 156.56,53.39 156.56,54.82 156.83,55.09 161.59,55.09
+3V on IN2 (solid shape): outline of 108 points within 35.53,76.09 47.99,80.14
+3V on IN2 (solid shape): outline of 271 points within 15.42,21.14 19.56,46.99
+3V on IN2 (solid shape): outline of 526 points within 161.1,75.21 165.03,90.27
+3V on IN2 (solid shape): outline of 572 points within 23.99,57.02 32.07,72.4
+3V3_SD_SW on TOP (solid shape): 22.56,43.12 22.56,42.55 23.31,41.8 23.31,41.61 23.13,41.31 23.29,41.01 23.31,40.99 23.31,40.97 23.44,40.84 23.44,39.7 23.39,39.62 23.3,39.6 22.82,39.27 23.3,38.93 23.39,38.92 23.44,38.84 23.44,38.3 22.67,37.54 22.11,37.54 21.86,37.79 21.86,39.47 21.39,39.95 20.59,39.95 20.52,40.02 20.52,40.03 19.45,41.1 18.13,41.1 17.9,41.33 17.9,42.19 17.99,42.28 21.12,42.28 21.41,42.57 21.41,42.87 21.7,43.16 22.51,43.16
+3V_EMMC on BOTTOM (solid shape): 94.58,19.29 94.58,17.14 92.2,14.76 91.04,14.76 90.9,14.9 90.9,17.42 91.04,17.57 91.92,17.57 92.23,17.88 92.56,18.03 92.59,18.39 92.59,19.32 92.73,19.46 94.42,19.46
+3V_EMMC on BOTTOM (solid shape): 101.13,20.42 101.13,20.29 102.91,18.52 103.04,18.52 103.17,18.39 103.17,18.31 103.04,18.19 102.91,18.19 102.66,17.93 102.66,17.78 102.56,17.68 102.48,17.68 102.33,17.83 102.33,18.09 102.02,18.39 101.92,18.59 101.72,18.69 101.41,19 101.31,19.28 101.03,19.38 100.73,19.69 100.45,19.69 100.35,19.79 100.35,19.94 100.42,20.02 100.73,20.02 100.83,20.12 100.83,20.47 100.85,20.5 101.06,20.5
+3V_EMMC on BOTTOM (solid shape): outline of 147 points within 105.29,15.12 112.6,19.21
+3V_EMMC on IN1 (solid shape): outline of 205 points within 92.62,16.9 106.06,20.09
+3V_HDD on BOTTOM (solid shape): 163.49,41.33 163.49,40.92 163.92,40.49 164.63,40.49 165.04,40.08 165.04,36.09 164.84,35.89 163.69,35.89 163.41,36.17 163.41,37.24 163.03,37.62 162.63,37.62 162.39,37.86 162.39,39.92 161.66,40.64 161.66,41.48 161.74,41.55 163.26,41.55
+3V_LDO on TOP (solid shape): 116.56,45.86 116.56,45.3 115.48,44.22 115.15,44.22 115.03,44.35 115.03,46.13 115.15,46.25 116.17,46.25
+3V_MINI1_VDD on TOP (solid shape): 163.37,99.81 163.37,98.32 163.3,98.25 161.17,98.25 161.09,98.32 161.09,99.87 161.25,100.03 163.16,100.03
+3V_MINI1_VDD on BOTTOM (solid shape): 163.25,99.92 163.25,98.7 162.99,98.45 161.22,98.45 161.09,98.58 161.09,98.91 161.22,99.03 161.76,99.03 161.85,99.12 161.85,99.9 162.03,100.08 163.1,100.08
+3V_MINI1_VDD on BOTTOM (solid shape): 167.18,94.39 168.07,94.39 168.2,94.26 168.2,93.12 168.07,92.99 167.31,92.99 167.06,92.74 167.06,90.2 166.68,89.81 165.15,89.81 165.03,89.94 165.03,90.7 166.04,91.72 166.04,94.89 166.17,95.02 166.55,95.02
+3V_MINI1_VDD on IN2 (solid shape): outline of 197 points within 161.85,75.59 167.07,100.03
+3V_RTC on BOTTOM (solid shape): 37.3,10.26 37.3,8.28 37.18,8.15 34.03,8.15 33.87,8.31 33.87,9.4 33.93,9.45 36.31,9.45 36.67,9.8 36.67,10.26 36.74,10.34 37.23,10.34
+3V_S5 on TOP (solid shape): outline of 206 points within 116.17,52.1 125.06,61.72
+3V_S5 on BOTTOM (solid shape): 157.94,84.47 159.21,84.47 159.24,84.45 159.24,84.25 159.18,84.19 157.45,84.19 157.24,84.4 157.24,84.59 157.39,84.73 157.67,84.73
+3V_S5 on BOTTOM (solid shape): 143.22,58.06 143.22,57.3 143.09,57.18 141.95,57.18 141.83,57.05 141.76,57 141.61,56.83 141.01,56.83 140.62,57.23 140.62,58.05 140.76,58.19 143.09,58.19
+3V_S5 on BOTTOM (solid shape): 117.95,62.38 117.95,61.62 117.72,61.39 117.72,61.26 117.57,61.11 117.57,57.56 117.31,57.3 116.17,57.3 115.92,57.56 115.92,59.59 116.17,59.84 116.17,61.47 116.2,61.5 116.38,61.5 116.91,61.75 116.47,62.15 116.46,62.15 116.42,62.16 116.41,62.24 116.8,62.64 117.69,62.64
+3V_S5 on IN1 (solid shape): 120.51,53.71 120.74,53.28 121.18,53.49 121.27,53.58 121.8,53.58 121.99,53.39 121.99,52.43 121.9,52.35 120.17,52.35 119.98,52.4 119.8,52.35 119.43,52.35 119.22,52.56 119.22,53.59 119.51,53.89 120.33,53.89
+3V_S5 on IN1 (solid shape): outline of 131 points within 138.51,53.98 143.48,57.54
+3V_S5 on IN2 (solid shape): outline of 517 points within 92.8,53.37 120.78,70.38
+3V_USB on TOP (solid shape): 101.69,55.98 101.69,55.78 101.31,55.41 101.31,54.76 101.19,54.64 100.93,54.64 100.68,54.38 100.68,53.97 100.45,53.75 99.54,53.75 99.43,53.86 99.43,55.44 99.9,55.91 101.12,55.91 101.34,56.13 101.55,56.13
+3V_USB on BOTTOM (solid shape): 101.95,62.51 101.95,61.87 101.82,61.75 100.04,61.75 99.41,62.38 99.41,63.78 99.53,63.91 100.55,63.91
+3V_USB on BOTTOM (solid shape): 101.76,55.9 101.79,55.81 101.72,55.73 101.52,55.54 101.52,55.26 101.52,54.84 101.29,54.61 100.58,54.61 100.42,54.76 100.42,56.01 100.67,56.25 101.4,56.25
+3V_USB on IN2 (solid shape): outline of 359 points within 97.76,55.27 109.44,63.78
+3VPCU on TOP (solid shape): 114.77,42.7 114.77,42.09 115.05,41.81 115.28,41.81 117.06,40.03 120.97,40.03 121.25,39.75 121.25,34.57 121.12,34.44 119.35,34.44 118.58,33.68 118.58,30.25 118.46,30.12 114.55,30.12 113.48,31.19 113.48,35.69 114.27,36.47 114.27,37.74 114.01,38 114.01,42.54 114.3,42.82 114.64,42.82
+3VPCU on TOP (solid shape): 147.18,34.01 147.46,33.91 147.74,34.01 148.02,34.01 148.15,33.88 148.15,33.2 147.84,32.89 147.49,32.89 147.39,32.99 146.79,32.99 146.31,33.47 146.31,33.69 146.64,34.01
+3VPCU on TOP (solid shape): 119.6,57.19 119.6,55.52 119.22,55.14 117.93,55.14 117.84,55.21 117.87,55.32 117.83,55.9 117.3,55.68 117.14,55.68 117.06,55.76 117.06,58.11 117.25,58.31 118.48,58.31
+3VPCU on TOP (solid shape): 141.46,36.64 141.46,35.86 141.41,35.77 141.31,35.77 141.04,35.8 140.83,35.64 140.76,35.59 140.68,35.61 140.16,35.53 140.28,35.02 140.33,34.95 140.3,34.86 140,34.56 139.91,34.53 139.84,34.59 139.32,34.74 139.24,34.22 139.26,34.15 139.23,34.08 139.13,33.82 139.24,33.57 139.27,33.5 139.25,33.43 139.18,33.31 139.16,33.17 139.02,33.03 138.41,33.03 138.27,33.18 138.27,34.8 138.3,34.88 138.38,34.9 138.73,35.07 138.71,35.46 138.7,35.49 138.72,35.53 139.54,36.35 139.54,36.41 139.55,36.42 139.6,36.53 139.61,36.65 139.61,36.66 139.62,36.68 139.79,36.86 141.24,36.86
+3VPCU on BOTTOM (solid shape): 115.87,32.56 115.87,31.72 115.66,31.52 114.26,31.52 114.14,31.63 114.14,32.56 114.24,32.66 115.76,32.66
+3VPCU on BOTTOM (solid shape): 31.64,10.87 31.64,9.3 31.92,9.02 32.91,9.02 33.2,8.73 33.2,7.46 33.14,7.39 32.07,7.39 31.44,8.03 30.37,8.03 30.09,8.31 30.09,10.97 30.27,11.15 31.36,11.15
+3VPCU on BOTTOM (solid shape): outline of 112 points within 139.41,35.84 141.78,38.89
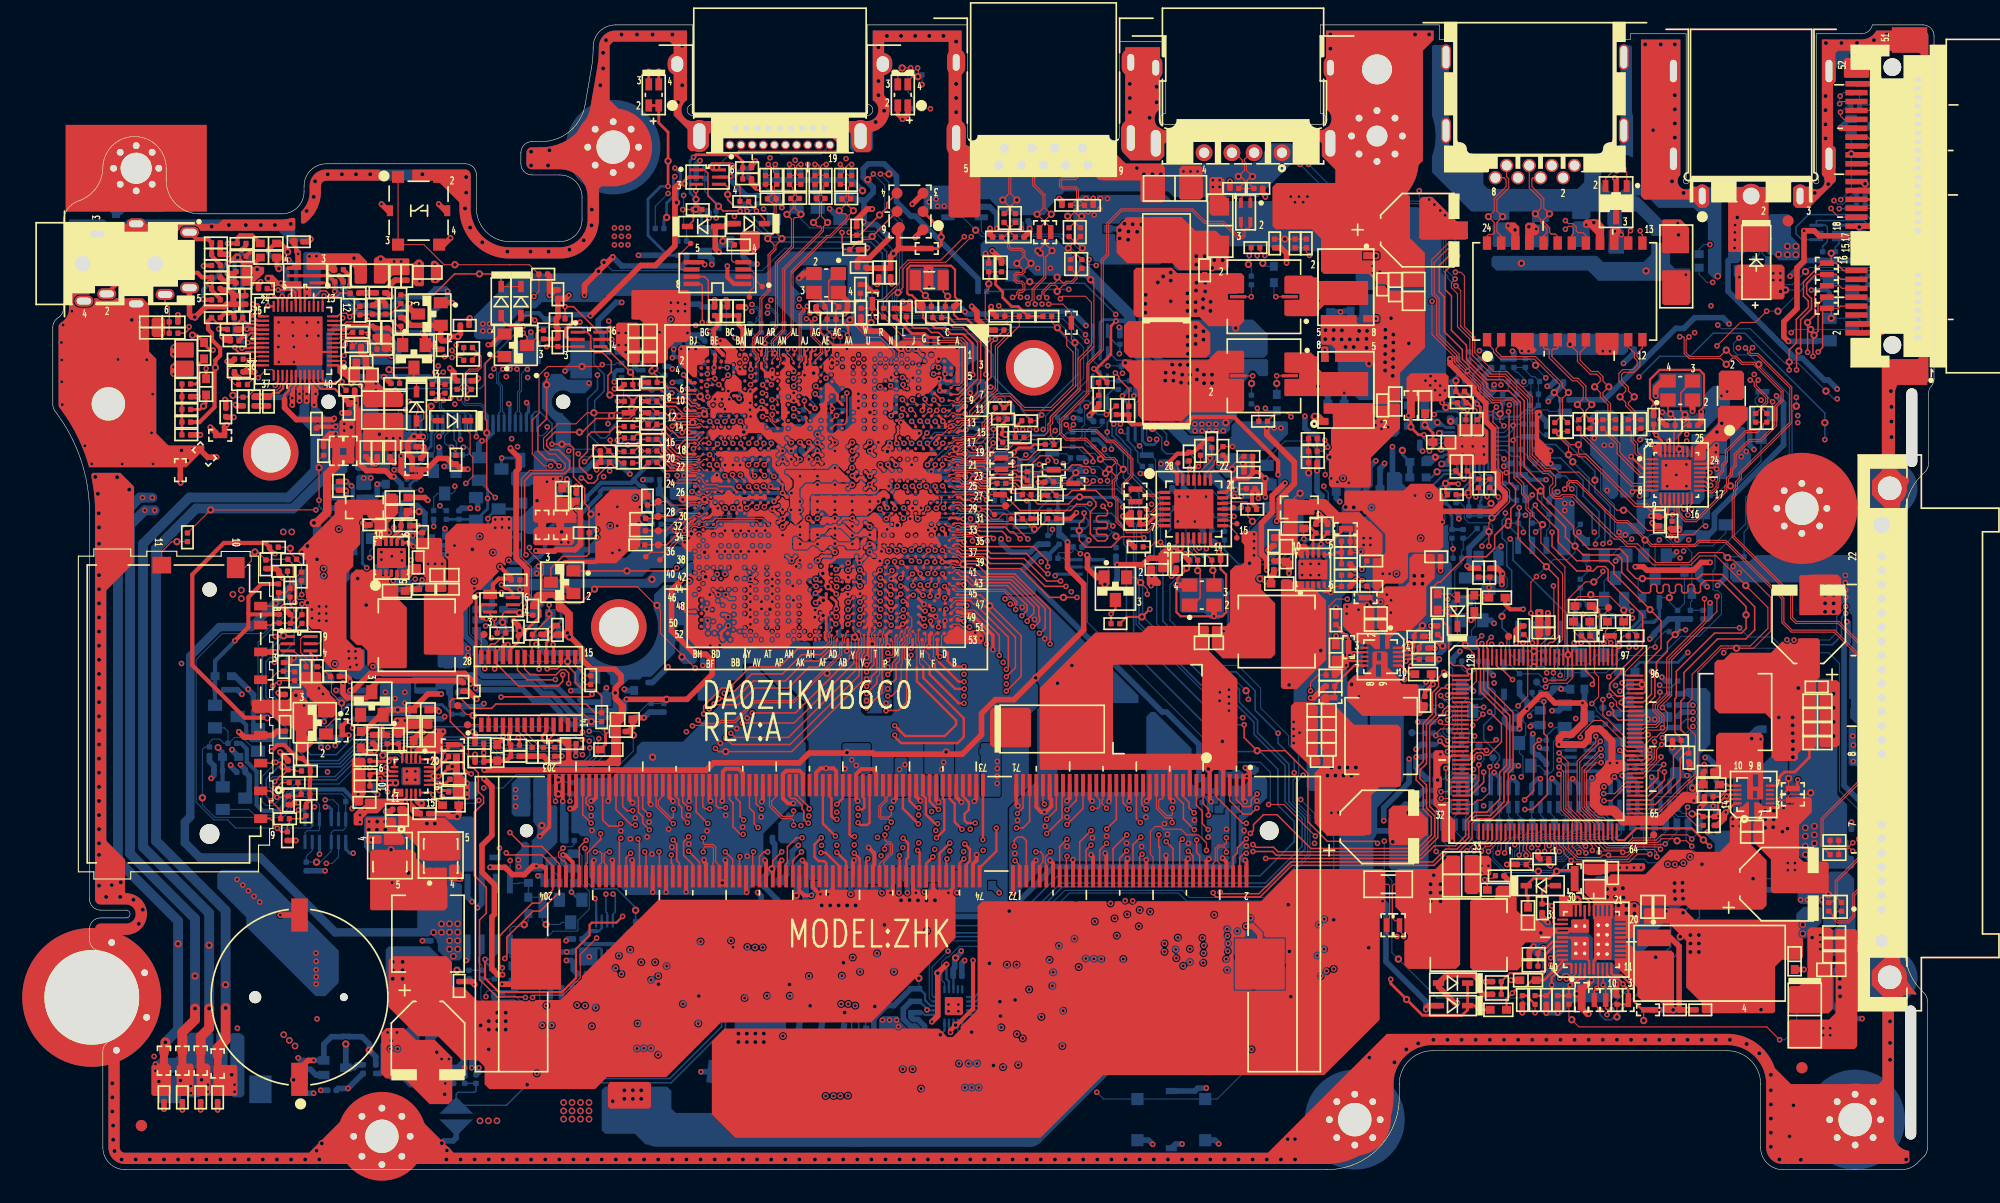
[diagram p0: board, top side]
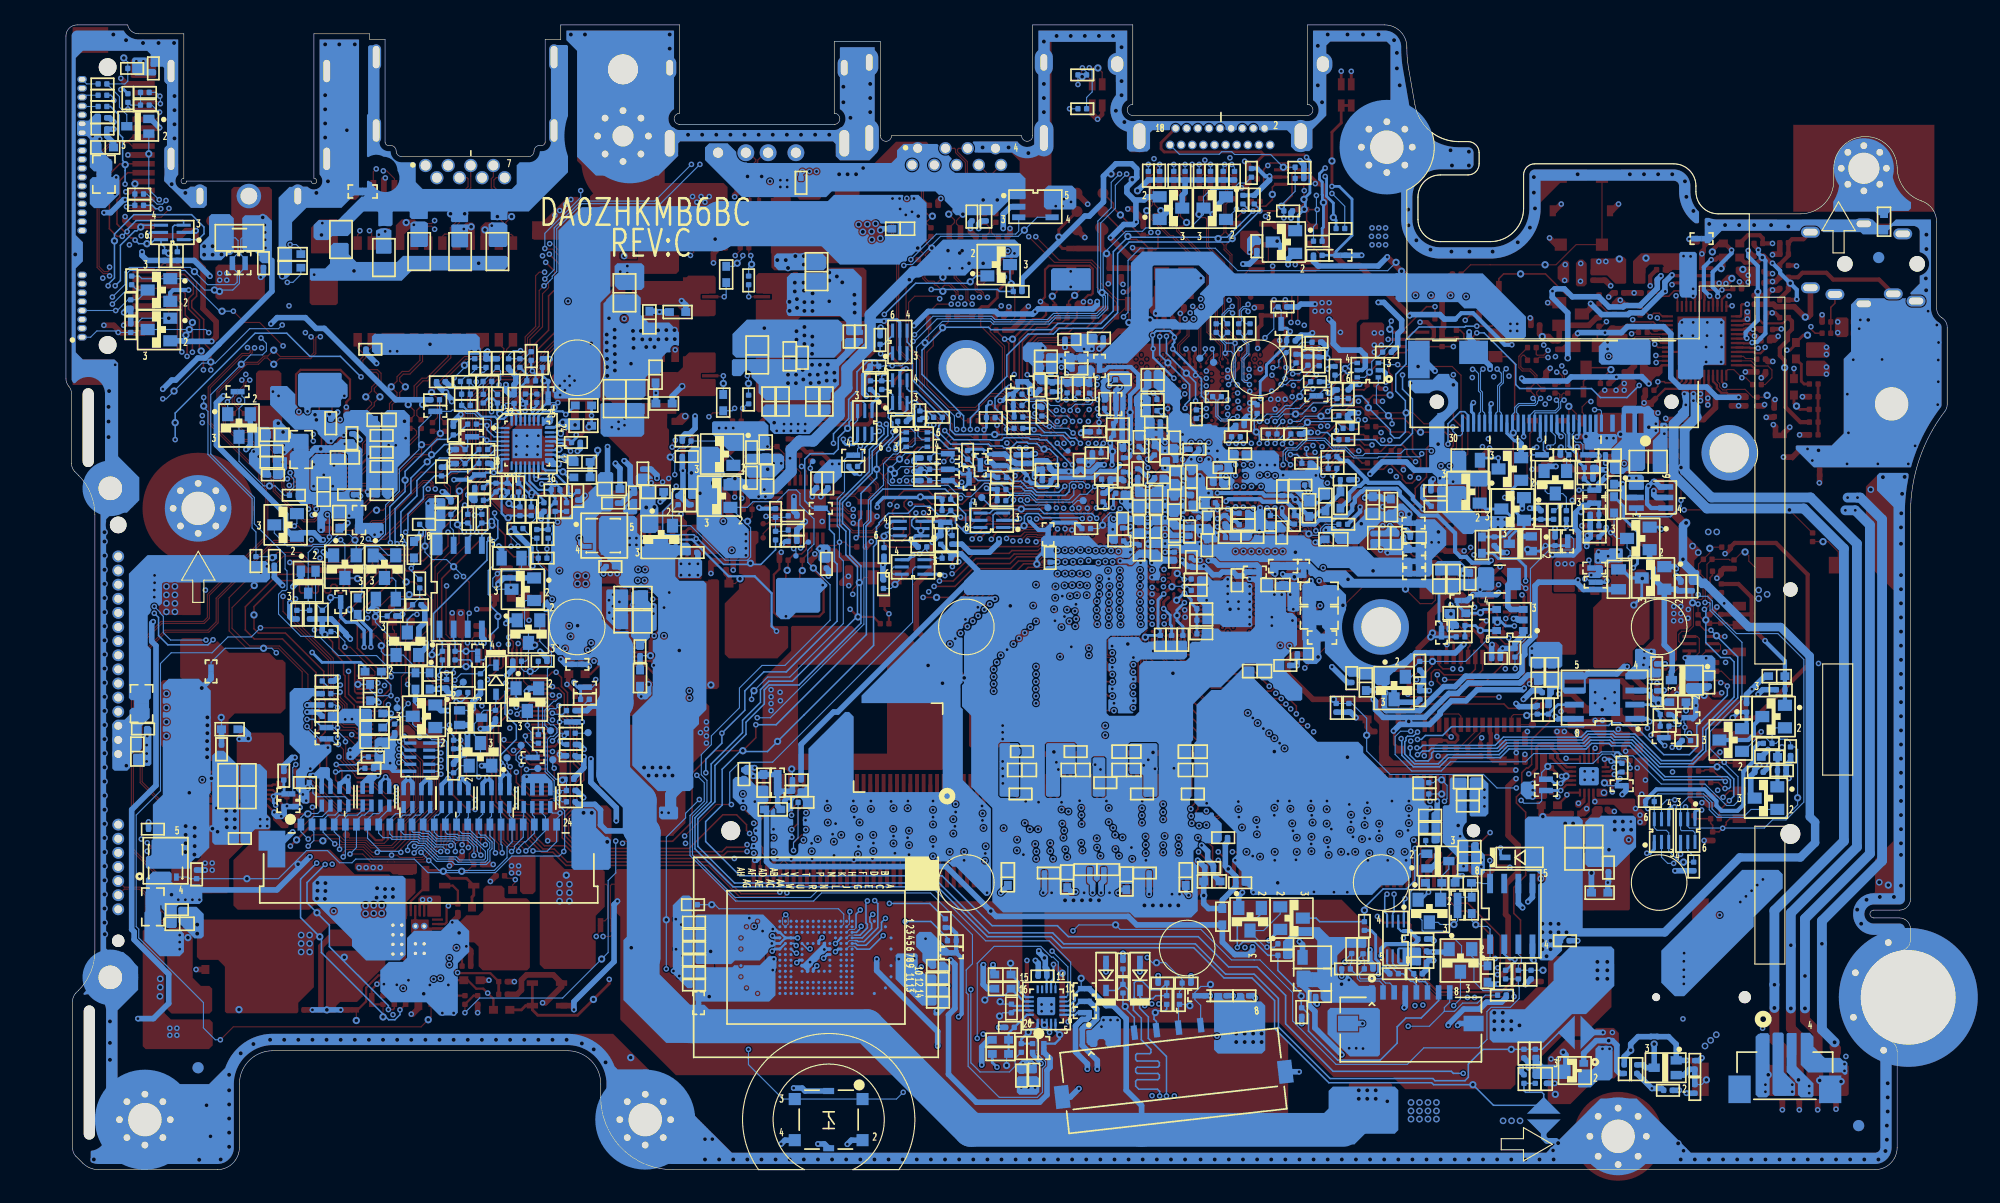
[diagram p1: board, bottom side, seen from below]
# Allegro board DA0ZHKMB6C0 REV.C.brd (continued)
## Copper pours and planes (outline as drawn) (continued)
+3VPCU on BOTTOM (solid shape): 149.09,42.91 149.09,38.28 148.17,37.36 148.17,36.21 148.51,35.88 148.51,34.73 148.51,34.73 148.51,34.16 148.27,33.92 148.27,33.32 147.9,32.94 147.41,32.94 147.3,33.05 147.3,33.84 147.31,33.85 147.31,34.16 147.71,34.56 147.71,35.22 147.54,35.4 147.54,35.46 147.53,35.52 147.47,35.67 147.36,35.78 147.34,35.8 147.25,35.8 147.18,35.81 147.12,35.81 145.33,37.61 145.33,38.15 145.43,38.26 146.07,38.26 146.08,38.25 146.47,38.25 146.65,38.43 146.65,38.8 147.38,39.53 147.41,39.54 147.42,39.53 147.82,39.7 147.77,40.13 147.74,40.2 147.77,40.27 147.87,40.52 147.76,40.77 147.73,40.84 147.76,40.92 147.87,41.16 147.78,41.41 147.75,41.48 147.78,41.55 147.86,41.87 147.64,42.12 147.63,42.12 147.59,42.16 147.44,42.16 146.78,42.82 146.78,43.18 146.93,43.33 148.67,43.33
+3VPCU on BOTTOM (solid shape): outline of 411 points within 111.6,34.06 121.25,58.83
+3VPCU on IN1 (solid shape): 48.71,15.67 48.71,15.11 47.92,14.33 47.29,14.33 46.42,15.19 46.42,15.82 46.55,15.95 48.43,15.95
+3VPCU on IN1 (solid shape): 121.56,31.55 121.56,30.91 121.35,30.71 116.58,30.71 115.79,29.92 114.93,29.92 114.72,30.12 114.72,31.39 119.34,31.39 119.35,31.34 119.36,31.29 119.38,31.24 119.41,31.19 119.44,31.15 119.48,31.12 119.52,31.09 119.57,31.06 119.62,31.05 119.67,31.04 119.73,31.04 119.78,31.05 119.83,31.06 119.88,31.09 119.92,31.12 119.96,31.15 120,31.19 120.02,31.24 120.04,31.29 120.05,31.34 120.06,31.39 120.05,31.45 120.04,31.5 120.02,31.55 120,31.6 119.96,31.64 119.92,31.67 119.88,31.7 119.83,31.73 119.78,31.74 119.73,31.75 119.67,31.75 119.62,31.74 119.57,31.73 119.52,31.7 119.48,31.67 119.44,31.64 119.41,31.6 119.38,31.55 119.36,31.5 119.35,31.45 119.34,31.39 114.72,31.39 114.72,32.18 114.96,32.42 120.68,32.42
+3VPCU on IN1 (solid shape): outline of 143 points within 59.94,13.94 68.57,17.7
+3VPCU on IN1 (solid shape): outline of 202 points within 137.38,33.93 141.7,37.11
+3VPCU on IN2 (solid shape): 48.28,14.86 48.28,13.67 47.31,12.7 45.64,12.7 42.96,10.02 41.77,10.02 41.29,9.54 37.69,9.54 36.69,10.54 30.37,10.54 30.12,10.8 30.12,11.51 30.34,11.74 41.68,11.74 42.92,12.98 43.68,12.98 43.68,12.93 43.69,12.87 43.71,12.82 43.74,12.78 43.77,12.74 43.81,12.7 43.86,12.67 43.9,12.65 43.96,12.63 44.01,12.62 44.06,12.62 44.11,12.63 44.16,12.65 44.21,12.67 44.26,12.7 44.3,12.74 44.33,12.78 44.36,12.82 44.38,12.87 44.39,12.93 44.39,12.98 44.39,13.03 44.38,13.08 44.36,13.13 44.33,13.18 44.3,13.22 44.26,13.26 44.21,13.29 44.16,13.31 44.11,13.33 44.06,13.34 44.01,13.34 43.96,13.33 43.9,13.31 43.86,13.29 43.81,13.26 43.77,13.22 43.74,13.18 43.71,13.13 43.69,13.08 43.68,13.03 43.68,12.98 42.92,12.98 44.35,14.4 44.38,14.4 44.43,14.4 44.48,14.41 44.53,14.43 44.58,14.46 44.62,14.49 44.66,14.53 44.69,14.57 44.72,14.62 44.74,14.67 44.74,14.72 44.75,14.77 44.74,14.8 45.21,15.27 47.87,15.27
+3VPCU_EC on TOP (solid shape): 134.08,50.32 134.08,48.03 133.87,47.83 133.44,47.83 133.34,47.93 133.34,48.01 133.32,48.03 133.32,50.32 133.44,50.44 133.95,50.44
+3VPCU_EC on TOP (solid shape): 124.98,37.74 125.06,37.71 125.09,37.64 125.09,37.59 125.09,37.55 125.24,37.32 125.51,37.27 125.59,37.24 125.62,37.17 125.62,36.7 125.44,36.53 125.06,36.53 124.81,36.27 124.81,35.45 124.94,35.31 124.94,34.42 124.88,34.36 124.55,34.18 124.55,33.81 124.58,33.78 124.6,33.75 124.63,33.69 124.61,33.62 124.62,33.16 125.08,33.1 125.45,33.1 125.62,32.93 125.62,31.9 126.13,31.39 126.13,29.57 126.02,29.46 124.99,29.46 124.9,29.55 124.9,32.08 124.17,32.81 124.17,37.56 124.35,37.74
+3VPCU_EC on BOTTOM (solid shape): 144.62,41.17 145.58,41.17 145.66,41.1 145.66,40.39 145.58,40.31 145.03,40.31 144.87,40.16 143.25,40.16 142.92,39.83 142.92,38.56 143.98,37.49 143.98,37.01 143.85,36.88 143.34,36.88 142.27,37.95 141.77,37.95 141.67,38.05 141.67,41.33 141.82,41.48 144.31,41.48
+3VPCU_EC on IN1 (solid shape): 144.11,37.87 144.11,36.22 143.48,35.59 143.48,35.44 143.45,35.32 143.48,35.19 143.48,31.65 142.01,30.18 135.15,30.18 134.5,29.53 134.32,29.43 134.21,29.24 133.82,28.85 133.82,28.47 133.7,28.35 133.19,28.35 133.06,28.47 133.06,28.6 133.39,28.98 133.06,29.36 133.06,30.51 134.23,31.68 140.75,31.68 142.33,33.26 142.33,37.86 142.59,38.13 143.86,38.13
+3VPCU_EC on IN1 (solid shape): 134.03,50.37 134.12,50.32 134.13,50.23 134.46,49.74 134.79,50.23 134.8,50.32 134.88,50.37 136.92,50.37 137.05,50.24 137.21,50.24 137.29,50.19 137.3,50.1 137.63,49.61 137.96,50.1 137.97,50.19 138.06,50.24 138.51,50.24 138.59,50.19 138.6,50.1 138.93,49.62 139.26,50.1 139.27,50.19 139.35,50.24 140.18,50.24 141.6,50.24 141.65,50.19 141.65,50.17 141.88,49.92 142.22,49.97 142.32,49.98 142.38,49.88 142.38,49.58 142.18,49.38 140.61,49.38 140.27,49.04 133.46,49.04 133.34,49.16 133.34,50.17 133.54,50.37
+3VPCU_EC on IN2 (solid shape): 134.2,29.86 134.2,29.24 133.82,28.85 133.82,28.6 133.7,28.47 133.32,28.47 133.3,28.49 133.3,28.74 133.37,29.12 133.06,29.36 133.06,29.87 133.32,30.12 133.94,30.12
+3VPCU_EC on IN2 (solid shape): outline of 293 points within 140.99,40.31 144.87,49.84
+5V on TOP (solid shape): 35.04,81.2 35.04,80.19 34.64,79.78 34.13,79.78 34,79.91 34,81.64 34.15,81.79 34.46,81.79
+5V on BOTTOM (solid shape): 162.02,26.19 162.02,23.78 160.61,23.78 160.61,23.51 160.37,23.27 160.37,22 160.11,21.74 159.35,21.74 159.22,21.87 159.22,23.65 158.97,23.9 157.19,23.9 156.94,24.16 156.94,25.43 157.19,25.68 159.48,25.68 159.73,25.93 159.73,26.7 159.86,26.82 161.38,26.82
+5V on IN1 (solid shape): 76.76,9.1 76.76,6.56 75.89,5.69 74.67,5.69 72.68,7.68 72.68,8.85 73.21,9.39 76.48,9.39
+5V on IN1 (solid shape): 17.72,52.4 17.72,51.08 17.06,50.43 15.4,48.77 11.7,48.77 9.68,46.75 9.4,46.75 9.19,46.96 9.19,49.53 10.74,51.08 14.88,51.08 16.58,52.78 17.34,52.78
+5V on IN1 (solid shape): 45.56,4.19 45.74,4.19 45.75,4.19 45.95,4.14 46.14,4.19 46.5,4.19 46.7,4.14 46.9,4.19 47.27,4.19 47.46,4.14 47.66,4.19 48.03,4.19 48.23,4.14 48.42,4.19 54.68,4.19 55.31,4.83 60.28,4.83 60.52,4.59 60.52,2.69 60.51,2.68 60.51,2.23 60.34,2.06 38.14,2.06 37.76,2.44 37.76,4.59 38.07,4.9 44.85,4.9
+5V on IN1 (solid shape): outline of 138 points within 15.56,8.69 22.8,20.43
+5V on IN1 (solid shape): outline of 462 points within 121.71,13.82 159.27,25.65
+5V on IN2 (solid shape): outline of 309 points within 13.83,2.87 40.45,20.81
+5V on IN2 (solid shape): outline of 1081 points within 14.06,48.25 35.6,81.69
+5V_HDD on TOP (solid shape): 160.09,21.54 160.09,14.43 159.71,14.05 156.28,14.05 156.05,14.28 156.05,16.28 156.3,16.54 157.06,16.54 157.8,17.27 157.8,17.82 157.85,18.01 157.8,18.19 157.8,21.41 157.8,21.42 157.8,21.56 158.04,21.79 159.83,21.79
+5V_HDD on BOTTOM (solid shape): 162.14,23.14 162.14,20.6 160.75,19.2 158.97,19.2 158.59,19.58 158.59,21.23 158.84,21.49 160.11,21.49 160.62,22 160.62,23.14 160.75,23.27 162.02,23.27
+5V_HDD on IN1 (solid shape): 165.04,47.85 165.04,44.73 164.79,44.48 164.13,44.48 163.77,44.12 163.77,34.04 161.29,31.56 161.29,27.93 162.34,26.89 162.34,19.65 161.89,19.2 158.97,19.2 158.59,19.58 158.59,21.11 160.11,22.63 160.11,25.04 159.22,25.93 159.22,32.16 162.32,35.26 162.32,47.22 163.11,48.01 164.89,48.01
+5V_S5 on TOP (solid shape): 125.54,71.37 125.54,69.6 125.06,69.11 121.96,69.11 121.76,69.32 121.76,71.25 121.75,71.26 122.14,71.65 125.26,71.65
+5V_S5 on TOP (solid shape): 31.93,34.26 31.93,32.95 31.8,32.83 29.99,32.83 29.21,32.06 28.34,32.06 27.89,31.61 27.89,31.07 27.78,30.96 27.17,30.96 27.04,31.09 27.04,32 27.52,32.49 27.7,32.49 28.06,32.84 28.06,33.29 28.16,33.39 31.55,33.39 31.73,33.56 31.73,34.26 31.74,34.27 31.92,34.27
+5V_S5 on TOP (solid shape): 158.93,47.64 158.93,44.31 158.59,43.97 158.59,38.07 158.41,37.9 158.41,37.87 157.37,37.87 156.96,37.47 156.96,36.97 156.76,36.77 154.95,36.77 154.58,37.14 154.58,40.49 154.02,41.05 149.89,41.05 149.45,41.49 149.45,45.61 149.71,45.87 150.28,45.87 150.91,46.51 152.74,46.51 152.74,46.51 154.49,46.51 154.52,46.51 155.52,47.5 155.6,47.53 155.67,47.48 155.92,47.32 156.21,47.41 156.28,47.44 156.35,47.4 156.76,47.33 156.96,47.69 156.99,47.77 157.06,47.8 158.77,47.8
+5V_S5 on TOP (solid shape): outline of 213 points within 22.11,44.88 27.98,60.27
+5V_S5 on BOTTOM (solid shape): 81.25,88.16 81.25,86.64 80.99,86.39 78.58,86.39 78.32,86.64 78.32,88.16 78.71,88.54 80.86,88.54
+5V_S5 on BOTTOM (solid shape): 28.08,46.76 28.08,45.47 28.43,45.12 28.43,45.12 28.92,44.62 28.92,44.15 27.14,44.15 27.02,44.27 25.87,44.27 25.72,44.42 25.72,44.98 25.82,45.09 26.33,45.09 26.48,45.24 26.48,45.72 26.2,46 26.2,46.74 26.33,46.86 27.98,46.86
+5V_S5 on BOTTOM (solid shape): 55.74,14.29 55.74,12.2 53.72,10.19 51.19,10.19 51.02,10.36 51.02,13.15 52.23,13.15 52.23,13.1 52.25,13.04 52.27,12.99 52.29,12.95 52.33,12.91 52.36,12.87 52.41,12.84 52.46,12.82 52.51,12.8 52.56,12.79 52.59,12.79 52.84,12.79 52.87,12.79 52.88,12.77 52.89,12.74 52.89,12.35 54.9,12.35 54.9,13.95 52.89,13.95 52.89,13.56 52.88,13.53 52.87,13.51 52.84,13.51 52.59,13.51 52.56,13.5 52.51,13.5 52.46,13.48 52.41,13.46 52.36,13.43 52.33,13.39 52.29,13.35 52.27,13.3 52.25,13.25 52.23,13.2 52.23,13.15 51.02,13.15 51.02,14.36 51.21,14.55 55.48,14.55
+5V_S5 on BOTTOM (solid shape): 124.91,84.51 124.91,80.73 125.31,80.33 125.31,69.49 125.2,69.38 121.24,69.38 121.12,69.49 121.12,78 120.97,78.16 123.69,78.16 123.69,78.1 123.7,78.05 123.71,78 123.74,77.95 123.77,77.91 123.8,77.87 123.84,77.84 123.89,77.81 123.94,77.79 123.99,77.78 124.04,77.77 124.1,77.78 124.15,77.79 124.2,77.81 124.25,77.84 124.29,77.87 124.32,77.91 124.35,77.95 124.38,78 124.39,78.05 124.4,78.1 124.4,78.16 124.39,78.21 124.38,78.26 124.35,78.31 124.32,78.35 124.29,78.39 124.25,78.43 124.2,78.45 124.15,78.47 124.1,78.48 124.04,78.49 123.99,78.48 123.94,78.47 123.89,78.45 123.84,78.43 123.8,78.39 123.77,78.35 123.74,78.31 123.71,78.26 123.7,78.21 123.69,78.16 120.97,78.16 120.23,78.89 120.23,84.73 120.27,84.77 120.27,85.68 121.19,86.6 122.81,86.6
+5V_S5 on BOTTOM (solid shape): outline of 247 points within 156.18,27.08 162.02,44.17
+5V_S5 on BOTTOM (solid shape): outline of 236 points within 91.79,81.43 101.67,87.71
+5V_S5 on IN1 (solid shape): 23.08,57.43 23.08,55.75 22.23,54.9 21.1,54.9 20.41,55.59 20.41,57.46 20.65,57.7 22.81,57.7
+5V_S5 on IN2 (solid shape): outline of 99 points within 22.98,44.98 27.65,50.95
+5V_S5 on IN2 (solid shape): outline of 795 points within 50.25,81.94 95.11,89.18
+5V_S5 on IN2 (solid shape): outline of 6136 points within 43.65,2.06 163.67,72.35
+5V_S5 on SVCC (solid shape): outline of 589 points within 10.35,2.03 54.58,85.37
+5VA on TOP (solid shape): 33.39,81.59 33.39,79.6 33.27,79.48 32.63,79.48 32.43,79.68 32.43,81.56 32.76,81.89 33.09,81.89
+5VA on TOP (solid shape): 18.28,77.32 18.28,76.66 18.47,76.47 19.43,76.47 19.45,76.45 19.45,76.3 19.42,76.28 17.75,76.28 17.67,76.35 17.67,77.32 17.8,77.44 18.15,77.44
+5VA on TOP (solid shape): 19.02,81.15 19.02,80.67 18.58,80.24 18.54,80.24 18.14,79.84 18.14,79.58 18.13,79.54 18.09,79.53 17.11,79.53 16.98,79.65 16.98,81.08 17.15,81.25 18.92,81.25
+5VA on IN2 (solid shape): outline of 366 points within 17.04,76.25 33.37,82.02
+VCC_CORE on TOP (solid shape): 75.28,60.73 75.28,60.48 75.15,60.35 75.02,60.35 74.9,60.48 74.64,60.48 74.39,60.22 74.39,60.1 74.01,59.72 74.01,59.59 73.37,58.95 72.23,58.95 72.1,59.08 71.85,59.08 71.59,58.83 70.83,58.83 70.58,59.08 70.2,59.08 69.94,58.83 69.43,59.33 69.05,59.33 68.8,59.08 68.67,59.08 68.42,58.83 68.29,58.83 68.16,58.95 68.16,60.48 68.29,60.6 74.01,60.6 74.51,61.11 74.9,61.11
+VCC_CORE on TOP (solid shape): 107.15,73.56 107.15,71.78 107.08,71.7 105.83,71.7 105.77,71.64 105.77,71.19 105.81,71.15 107.07,71.15 107.15,71.06 107.15,68.35 106.95,68.15 102.35,68.15 101.59,67.39 98.06,67.39 97.58,67.87 97.58,69.6 97.58,69.65 97.58,70.1 96.82,70.87 96.82,71.69 96.15,72.35 96.15,72.7 96.32,72.87 96.61,72.87 96.65,72.82 103.88,72.82 104.74,73.69 107.03,73.69
+VCC_CORE on BOTTOM (solid shape): 74.36,60.99 74.36,60.43 74.47,60.32 74.47,60.09 74.15,59.77 74.15,59.74 74.09,59.67 74.05,59.59 73.57,59.11 70.27,59.11 69.89,58.73 69.25,58.73 69,58.98 68.62,58.98 68.49,59.11 68.49,60.25 68.62,60.38 68.87,60.38 69,60.25 69,60.12 69.12,60 69.89,60 70.01,60.12 70.01,60.25 70.14,60.38 73.06,60.38 73.19,60.5 73.19,60.96 73.32,61.09 74.26,61.09
+VCC_CORE on BOTTOM (solid shape): 99.15,74.7 99.15,73.69 99.91,72.92 109.19,72.92 109.31,72.8 109.31,71.53 109.19,71.4 108.51,71.4 108.28,71.63 107.84,71.9 107.54,71.47 107.54,71.28 106.9,70.64 106.9,69.88 106.26,69.24 100.55,69.24 100.42,69.37 100.42,69.88 99.68,70.62 99.68,72.27 97.63,74.32 97.63,74.7 97.76,74.83 99.03,74.83
+VCC_CORE on SVCC (solid shape): 95.59,73.3 95.93,73.06 96.26,73.3 101.71,73.3 102.1,73 102.49,73.3 106.29,73.3 106.65,72.95 106.65,60.8 106.54,60.55 106.65,60.3 106.65,59.85 106.52,59.62 106.58,59.37 106.41,59.21 100.15,59.21 99.21,60.15 99.12,60.21 99.02,60.22 97.76,60.22 97.66,60.21 97.58,60.15 96.63,59.21 93.08,59.21 92.74,59.44 92.41,59.19 92.08,59.46 91.72,59.21 81.89,59.21 81.79,59.19 81.7,59.13 80.35,57.78 80.01,58 79.68,57.76 79.35,58.01 79.01,57.78 78.67,57.91 78.4,57.68 75.4,57.68 75.05,57.96 74.7,57.68 68.65,57.68 68.29,58.04 68.29,58.41 68.34,58.6 68.29,58.78 68.29,59.2 68.26,59.33 68.16,59.43 68.16,60.93 68.58,61.34 68.93,61.32 69.13,61.62 69.69,61.62 69.74,61.63 69.78,61.66 71.05,62.92 71.08,62.97 71.09,63.02 71.09,68.93 75.08,72.92 84.84,72.92 84.85,72.9 84.88,72.87 85.42,72.33 88.49,69.38 90.94,72.86 91.38,73.3
+VCC_GFX on TOP (solid shape): 101.13,80.67 106.9,80.67 107.15,80.42 107.15,78.92 107.07,78.83 105.83,78.83 105.77,78.83 105.7,78.77 105.7,78.31 105.75,78.26 107.09,78.26 107.15,78.2 107.15,76.35 106.7,75.9 103.95,75.9 103.14,76.71 97.45,76.71 97.2,76.96 97.2,80.9 97.45,81.15 100.65,81.15
+VCC_GFX on TOP (solid shape): 71.67,62.13 71.67,61.98 71.54,61.85 70.65,61.85 70.4,62.1 70.27,62.1 70.02,61.85 69.1,61.85 68.9,62.05 68.67,62.05 68.47,61.85 67.71,61.85 67.15,61.29 67.15,60.45 67.38,60.22 67.38,59.97 67.22,59.82 67.22,59.69 67.4,59.51 67.4,59.28 67.17,59.06 67.17,58.93 67.38,58.73 67.38,58.55 66.89,58.06 66.74,58.06 66.41,58.39 66.41,59.03 66.21,59.23 66.21,59.46 66.31,59.56 66.31,60.63 66.21,60.73 66.21,60.96 66.64,61.39 66.64,62.05 66.08,62.61 65.95,62.61 65.88,62.69 65.88,62.84 65.98,62.94 69.76,62.94 70.2,63.37 70.43,63.37
+VCC_GFX on TOP (solid shape): 57.37,78.89 57.37,74.86 56.96,74.45 55.96,74.45 55.34,73.83 55.34,72.92 54.97,72.56 53.19,72.56 53.1,72.64 53.1,76.17 52.8,76.48 52.29,76.48 52.28,76.49 52.12,76.49 52.08,76.53 55.24,76.53 55.24,76.48 55.24,76.43 55.26,76.37 55.28,76.33 55.31,76.28 55.35,76.24 55.39,76.21 55.44,76.18 55.49,76.16 55.54,76.15 55.59,76.15 55.64,76.15 55.7,76.16 55.75,76.18 55.79,76.21 55.83,76.24 55.87,76.28 55.9,76.33 55.92,76.37 55.94,76.43 55.95,76.48 55.95,76.53 55.94,76.58 55.92,76.64 55.9,76.68 55.87,76.73 55.83,76.77 55.79,76.8 55.75,76.83 55.7,76.85 55.64,76.86 55.59,76.86 55.54,76.86 55.49,76.85 55.44,76.83 55.39,76.8 55.35,76.77 55.31,76.73 55.28,76.68 55.26,76.64 55.24,76.58 55.24,76.53 52.08,76.53 52.04,76.57 52.04,79.02 52.16,79.15 57.12,79.15
+VCC_GFX on BOTTOM (solid shape): 100.8,80.67 103.98,80.67 104.36,80.29 104.36,76.96 104.21,76.81 99.58,76.81 99.03,76.25 99.03,75.21 98.9,75.08 97.88,75.08 97.63,75.34 97.63,80.29 98.39,81.05 100.42,81.05
+VCC_GFX on BOTTOM (solid shape): 70.7,63.95 70.7,63.01 70.58,62.89 70.32,62.89 69.81,62.38 69.12,62.38 68.77,62.03 68.49,62.03 68.36,61.9 68.36,61.27 68.24,61.14 67.6,61.14 67.47,61.01 67.47,60.31 67.58,60.2 68.16,60.2 68.24,60.13 68.24,59.43 67.86,59.05 67.36,59.05 67.02,58.88 67.03,58.5 67.03,58.4 66.94,58.35 66.46,58.35 66.08,58.73 66.08,59.49 66.33,59.74 66.33,60.25 66.01,60.58 66.01,61.04 66.16,61.19 66.41,61.19 66.75,61.53 66.75,62.27 67.15,62.66 67.35,62.66 67.73,62.28 68.24,62.28 68.57,62.61 68.57,63.14 68.82,63.4 69.79,63.4 69.9,63.51 69.9,64.03 69.99,64.12 70.53,64.12
+VCC_GFX on SVCC (solid shape): outline of 378 points within 49.88,58.7 106.65,87.4
+VDDQ on TOP (solid shape): 29.84,39.83 29.84,39.5 29.99,39.34 30.29,39.34 30.34,39.29 30.34,38.86 30.29,38.81 28.64,38.81 28.52,38.94 28.52,39.29 28.62,39.4 29.18,39.4 29.33,39.55 29.33,39.8 29.4,39.88 29.79,39.88
+VDDQ_VTT on BOTTOM (solid shape): 44.73,35.15 44.73,32.91 44.86,32.79 45.24,32.78 45.37,32.66 45.37,29.43 44.09,28.14 44.09,26.93 43.97,26.82 43.15,26.82 43.07,26.9 43.07,29.64 43.58,30.41 43.21,31.26 43.21,35.17 43.32,35.28 44.61,35.28
+VIN on TOP (solid shape): 31.97,32.44 31.97,32.03 32.35,31.65 35.27,31.65 36.67,30.25 36.67,27.97 36.51,27.81 33.17,27.81 32.88,28.09 32.88,28.96 31.08,30.76 31.08,32.03 30.98,32.13 30.98,32.59 31.11,32.72 31.69,32.72
+VIN on TOP (solid shape): 124.3,55.14 124.3,53.24 123.54,52.48 123.54,49.91 122.09,48.46 120.96,48.46 120.23,47.74 120.23,46.89 120.21,46.86 119.84,46.86 119.84,48.27 119.71,48.4 119.47,48.4 119.09,48.78 119.09,50.68 119.14,50.77 119.24,50.77 119.78,51.08 119.24,51.39 119.14,51.39 119.09,51.48 119.09,51.69 119.88,52.48 121.58,52.48 122.01,52.91 122.01,55.02 122.39,55.4 124.04,55.4
+VIN on TOP (solid shape): 115.61,88.77 115.63,88.74 115.69,88.68 115.77,88.61 115.89,88.51 115.95,88.47 116.03,88.41 116.21,88.3 116.39,88.19 116.58,88.09 116.77,88 116.96,87.92 117.06,87.88 117.15,87.84 117.35,87.77 117.55,87.7 117.75,87.65 117.96,87.6 118.16,87.56 118.37,87.53 118.58,87.51 118.79,87.49 119,87.48 119.2,87.48 119.41,87.49 119.62,87.51 119.83,87.53 120.04,87.56 120.24,87.6 120.45,87.65 120.65,87.7 120.85,87.77 121.05,87.84 121.14,87.88 121.75,87.88 122.06,87.56 122.06,83.82 123.41,82.47 123.41,79.59 123.24,79.43 120.08,79.43 119.83,79.68 119.24,79.68 118.3,80.62 114.29,80.62 114.06,80.85 114.06,81.81 118.9,81.81 118.93,81.81 118.99,81.8 119.05,81.81 119.08,81.81 119.24,81.81 119.42,82 119.42,82.47 119.23,82.65 117.77,82.65 117.77,81.81 114.06,81.81 114.06,83.77 113.22,84.61 109.99,84.61 109.69,84.91 109.69,88.41 110.05,88.77 113.96,88.77 113.96,88.77
+VIN on TOP (solid shape): outline of 86 points within 114.32,61.37 121.17,68.96
+VIN on TOP (solid shape): outline of 253 points within 137.76,17.53 154.14,33.05
+VIN on BOTTOM (solid shape): 83.68,8.26 83.68,6.96 83.46,6.73 81.91,6.73 81.65,6.99 81.65,8.18 81.88,8.41 83.53,8.41
+VIN on BOTTOM (solid shape): 119.85,81.31 119.85,79.53 119.47,79.15 117.44,79.15 117.19,79.4 117.19,81.31 117.44,81.56 119.6,81.56
+VIN on BOTTOM (solid shape): 120.6,52.1 120.6,49.54 119.7,48.64 118.81,48.64 118.66,48.79 118.66,52.17 118.7,52.22 120.48,52.22
+VIN on BOTTOM (solid shape): 121.12,68.86 121.12,66.25 120.82,65.94 117.43,65.94 117.19,66.19 117.19,68.73 117.44,68.99 121,68.99
+VIN on BOTTOM (solid shape): 153.51,36.32 153.51,29.48 153.27,29.24 152.69,29.24 152.48,29.44 152.48,30.34 152.19,30.63 150.97,30.63 150.82,30.79 150.82,31.62 151.12,31.93 151.12,35.87 151.74,36.49 153.34,36.49
+VIN on BOTTOM (solid shape): 23.26,53.77 23.26,52.81 23.05,52.6 22.47,52.6 22.19,52.32 21.53,52.32 21.33,52.53 21.33,52.83 21.7,53.2 22.01,53.2 22.29,53.48 22.29,53.8 22.44,53.95 23.08,53.95
+VIN on BOTTOM (solid shape): 37.99,31.48 37.99,27.06 37.75,26.82 36.92,26.82 36.69,26.59 36.11,26.2 36.66,25.77 36.8,25.64 36.8,19.05 36.57,18.82 35.53,18.82 34.64,19.71 34.64,20.55 34.08,21.11 33.11,21.11 32.78,21.44 32.78,31.45 33.11,31.78 37.7,31.78
+VIN on BOTTOM (solid shape): outline of 202 points within 138.65,18.82 147.03,26.44
+VIN on IN2 (solid shape): 153.6,32.42 153.6,25.13 152.49,24.03 145.89,24.03 145.25,24.66 145.25,26.47 145.58,26.8 148.15,26.8 150.21,28.85 150.21,31.29 150.47,31.56 150.73,31.56 150.99,31.83 150.99,32.61 151.3,32.92 153.1,32.92
+VIN on SVCC (solid shape): outline of 140 points within 34,2.03 141.7,88.16
GND on TOP (solid shape): 31.72,55.78 31.72,54.38 31.46,54.13 29.3,54.13 29.18,54.25 29.18,55.78 29.3,55.91 31.59,55.91
GND on TOP (solid shape): 81.86,15.42 81.86,14.02 81.73,13.89 80.36,13.89 80.23,14.02 80.23,15.49 80.26,15.52 81.75,15.52
GND on TOP (solid shape): 104.11,75.31 104.11,73.46 103.7,73.05 96.87,73.05 96.33,73.58 96.33,75.95 96.74,76.35 103.06,76.35
GND on TOP (solid shape): 79.21,81.29 79.21,79.19 78.63,79.19 78.32,79.5 78.32,81.32 78.4,81.39 79.11,81.39
GND on TOP (solid shape): 114.61,54.8 114.61,53.33 114.44,53.16 112.11,53.16 112.06,53.21 112.06,54.71 112.18,54.84 114.57,54.84
GND on TOP (solid shape): 77.32,77.32 77.25,77.24 75.43,77.24 75.43,77.72 76.67,77.72 76.8,77.85 76.8,78.01 76.93,78.14 77.32,78.14
GND on TOP (solid shape): 127.28,84.31 127.28,83.84 127.11,83.67 123.06,83.67 122.9,83.83 122.9,87.27 123.16,87.53 124.07,87.53
GND on TOP (solid shape): 103.42,90.1 103.42,87.47 103.22,87.27 101.44,87.27 101.31,87.4 101.31,90.07 101.57,90.32 103.2,90.32
GND on TOP (solid shape): 113.76,41.68 113.76,37.24 114.01,36.98 114.01,36.47 113.88,36.35 113.03,36.35 111.34,38.03 111.34,41.73 111.68,42.06 113.38,42.06
GND on TOP (solid shape): 123.66,31.57 123.66,30.25 123.54,30.12 123.52,30.12 122.62,29.22 120.5,29.22 120.15,29.58 120.15,32.37 120.54,32.77 122.47,32.77
GND on TOP (solid shape): 143.22,27.46 143.22,27.08 142.97,26.82 140.05,26.82 139.79,26.57 137.76,26.57 137.63,26.7 137.63,27.46 137.71,27.53 141.86,27.53 141.91,27.58 143.09,27.58
GND on TOP (solid shape): 155.75,81.18 155.75,78.48 155.57,78.3 151.45,78.3 151.31,78.44 151.31,81.18 151.56,81.43 155.5,81.43
GND on TOP (solid shape): 28.13,36.91 28.13,33.73 27.93,33.53 27.93,32.92 27.75,32.74 27.27,32.74 26.89,33.12 26.89,36.8 26.89,36.81 26.89,36.91 27.05,37.07 27.97,37.07
GND on TOP (solid shape): 52.8,75.97 52.8,72.67 52.67,72.54 51.86,72.54 50.64,73.77 50.64,76.04 50.82,76.23 52.54,76.23
GND on TOP (solid shape): 30.83,74.63 30.83,73.73 30.72,73.62 30.64,73.62 30.63,73.63 29.61,73.63 29.56,73.69 29.56,74.19 29.43,74.32 29.18,74.32 28.79,74.7 28.79,75.08 28.92,75.21 30.25,75.21
GND on TOP (solid shape): 97.25,59.28 97.25,57.89 97.17,57.81 96.82,57.81 96.49,58.14 96.49,58.29 96.28,58.5 96.16,58.5 96,58.65 96,58.9 96.16,59.06 96.49,59.06 96.79,59.36 97.17,59.36
GND on TOP (solid shape): 24.23,76.54 24.23,73.72 24.27,73.67 25.63,73.67 25.65,73.66 25.65,73.49 25.63,73.48 24.24,73.48 24.19,73.42 24.19,72.58 24.01,72.4 20.16,72.4 19.9,72.65 19.9,76.64 19.94,76.68 24.09,76.68
GND on TOP (solid shape): 128.24,28.22 129.12,28.22 129.38,27.97 129.38,26.7 129.17,26.49 128.52,26.49 128.36,26.33 128.36,25.04 128.11,24.79 127.22,24.79 126.97,25.04 126.97,28.19 127.08,28.31 128.15,28.31
GND on TOP (solid shape): 129.12,66.45 129.12,63.67 128.88,63.42 125.67,63.42 125.44,63.65 125.44,64.82 125.14,65.13 125.14,65.79 125.26,65.91 126.15,65.91 126.33,66.09 126.33,67.01 126.41,67.08 128.49,67.08
GND on TOP (solid shape): 160.72,43.78 160.72,38.25 160.49,38.02 159.02,38.02 158.89,38.15 158.89,43 158.77,43.13 158.77,43.74 159.07,44.04 160.46,44.04
GND on TOP (solid shape): 59.02,73.81 59.02,73.3 58.64,72.92 58.64,72.67 58.39,72.42 58.05,72.42 57.95,72.32 57.95,71.43 57.82,71.3 57.57,71.3 56.25,72.62 56.25,73.97 56.47,74.19 58.64,74.19
GND on TOP (solid shape): 102.76,84.48 104.61,84.48 105.76,83.34 105.76,81.17 105.51,80.92 101.31,80.92 100.68,81.56 96.61,81.56 95.67,82.5 95.67,84.79 96.59,85.7 101.54,85.7
GND on TOP (solid shape): 30.88,31.55 30.88,30.63 31.64,29.87 31.64,29.39 31.47,29.22 29.84,29.22 29.78,29.29 29.78,30.16 29.68,30.25 28.23,30.25 28.13,30.35 28.13,31.62 28.21,31.7 30.73,31.7
GND on TOP (solid shape): 103.98,48.82 103.98,46.68 106.54,44.12 106.54,36.19 106.32,35.97 88.87,35.97 88.76,36.07 88.76,37.43 103.36,37.43 103.36,45.43 95.36,45.43 95.36,37.43 88.76,37.43 88.76,43.33 93.77,48.34 97.93,48.34 98.52,48.92 103.88,48.92
GND on TOP (solid shape): 118.21,51.01 118.37,51.01 118.86,50.52 118.86,48.51 119.35,48.03 119.35,46.86 119.32,46.84 118.91,46.84 118.48,47.27 117.67,47.27 116.04,48.9 116.04,50.83 116.17,50.95 116.93,50.95 117,51.02 118.2,51.02
GND on TOP (solid shape): 162.3,21.47 162.3,11.11 162.03,10.85 156.33,10.85 156,11.18 156,13.24 156.27,13.51 159.76,13.51 160.34,14.1 160.34,21.48 160.51,21.64 162.13,21.64
GND on TOP (solid shape): 32.03,40.53 34.04,40.53 34.08,40.49 34.08,39.78 33.98,39.68 33.46,39.68 33.44,39.7 33.27,39.7 32.91,39.7 32.89,39.68 32.12,39.68 31.33,38.89 30.83,38.89 30.65,39.07 30.65,40.54 30.8,40.69 31.87,40.69
GND on TOP (solid shape): 160.85,53.21 160.85,50.14 160.62,49.91 157.14,49.91 157.1,49.93 157.09,49.96 157.09,53.42 157.15,53.47 157.18,53.48 157.68,53.49 158.19,53.54 160.52,53.54
GND on TOP (solid shape): 36.62,37.36 36.62,35.71 37.48,34.85 37.48,33.43 37.41,33.35 36.11,33.35 35.98,33.48 35.98,34.82 36.04,34.89 36.06,34.98 36.06,35.28 36.04,35.37 35.98,35.44 35.98,37.36 36.03,37.41 36.57,37.41
GND on TOP (solid shape): 157.93,33.52 158.01,33.49 158.1,33.48 158.21,33.37 158.21,32.16 157.06,31.01 157.06,28.09 157.45,27.71 159.53,27.71 159.73,27.51 159.73,25.04 159.55,24.87 154.7,24.87 154.52,25.04 154.52,27.91 152.95,29.49 152.95,31.19 153.05,31.29 153.05,33 153.1,33.05 153.48,33.05 153.81,32.72 155.41,32.72 155.54,32.84 156.57,32.84 156.63,32.9 156.63,33.44 156.7,33.52
GND on TOP (solid shape): 71.64,56.83 71.66,56.81 71.7,56.76 71.73,56.69 71.69,56.61 71.67,56.59 71.63,56.55 71.61,56.54 70.69,56.54 70.18,57.05 69.62,57.05 69.52,57.11 69.54,57.22 69.93,57.61 70.86,57.61
GND on TOP (solid shape): 120.21,79.09 123.19,79.09 123.41,78.87 123.41,73.94 121.17,71.7 121.17,69.19 121.12,69.14 120.21,69.14 119.96,68.89 118.94,68.89 118.74,69.09 118.74,72.49 118.56,72.67 115.33,72.67 115.33,73.86 114.98,74.22 114.21,74.22 114.04,74.4 114.04,76.86 114.06,76.89 117.26,76.89 117.26,76.25 117.44,76.07 119.24,76.07 119.42,76.25 119.42,76.81 119.24,76.99 119.02,76.99 118.89,77.11 118.89,79.38 119.04,79.53 119.78,79.53
GND on TOP (solid shape): 137.51,24.41 137.51,23.81 137.49,23.79 137.49,22.87 137.38,22.76 137.34,22.76 137.3,22.77 137.28,22.81 137.28,23.79 137.09,23.79 137.09,22.81 137.07,22.77 137.04,22.76 136.94,22.76 136.9,22.77 136.88,22.81 136.88,23.79 136.69,23.79 136.69,22.81 136.67,22.77 136.64,22.76 135.52,22.76 135.47,22.8 135.47,24.54 135.6,24.66 137.25,24.66
GND on TOP (solid shape): 28,74.19 28,73.63 28.46,73.18 28.46,72.39 28.81,72.03 29.18,72.03 29.3,71.91 29.3,71.27 29.32,71.26 29.32,70.79 29.7,70.4 29.79,70.31 30.95,70.31 31.52,69.74 31.52,68.79 31.33,68.61 28.16,68.61 27.91,68.86 27.91,70.27 28.06,70.56 27.91,70.85 27.91,70.89 28.16,71.15 28.16,71.91 27.88,72.19 27.88,72.95 27.46,73.37 27.46,74.23 27.55,74.31 27.88,74.31
GND on TOP (solid shape): 146.34,101.69 146.37,101.68 146.39,101.65 146.39,89.51 146.36,88.41 147.46,88.44 148.81,88.44 148.99,88.26 148.99,86.84 148.68,86.54 148.1,86.54 147.36,87.27 143.12,87.27 142.84,87.56 142.84,101.65 142.88,101.69
GND on TOP (solid shape): 35.03,56.7 35.03,55.2 35.4,54.83 35.4,52.1 35.27,51.97 35.23,51.97 33.62,51.97 33.49,52.1 33.49,52.6 33.45,52.65 33.42,52.72 33.45,52.8 33.57,53.11 33.37,53.38 33.37,54.49 33.18,54.68 32.73,54.68 32.6,54.8 32.6,55.77 32.78,56.02 32.7,56.31 32.7,56.74 32.8,56.84 34.88,56.84
GND on TOP (solid shape): 81.72,48.67 81.85,48.67 81.95,48.57 82.21,48.57 82.46,48.46 82.71,48.57 83.22,48.57 83.73,48.06 83.73,47.55 83.48,47.3 80.37,47.3 80.13,47.54 80.13,47.88 80.16,47.95 80.22,47.98 80.42,48.1 80.47,48.32 80.46,48.33 80.47,48.36 80.69,48.58 80.72,48.59 80.74,48.59 80.94,48.63 81.06,48.78 81.08,48.81 81.11,48.82 81.57,48.82
GND on TOP (solid shape): 69.83,58.72 69.94,58.72 69.99,58.72 70.07,58.73 70.09,58.75 70.6,58.75 70.62,58.73 70.71,58.72 70.79,58.65 70.77,58.54 70.72,58.49 70.7,58.49 70.55,58.41 70.47,58.26 70.47,58.24 70.42,58.19 69.59,58.19 69.4,58 69.1,58 69.05,58.08 68.97,58.14 68.93,58.23 68.97,58.31 69,58.33 69.03,58.35 69.11,58.47 69.13,58.62 69.15,58.68 69.21,58.72 69.27,58.74 69.33,58.77 69.78,58.77
GND on TOP (solid shape): 29.44,89.89 29.44,89.04 29.37,88.98 24.59,88.98 24.25,88.84 24.12,88.5 24.12,88 23.72,86.38 22.63,85.12 22.4,85.12 22.32,85.2 22.32,86.18 22.9,87.01 23.1,88 23.1,88.5 23.52,89.54 24.55,89.99 24.6,89.99 29.34,89.99
GND on TOP (solid shape): outline of 89 points within 29.53,5.89 35.93,12.75
GND on TOP (solid shape): 124.14,102.49 124.18,102.48 124.19,102.44 124.19,101.65 123.23,100.69 123.23,90.77 121.03,88.57 116.77,88.57 114.14,91.21 114.14,92.33 113.94,92.53 100.21,92.53 99.97,92.28 99.97,91.21 99.56,90.81 96.94,90.81 96.46,91.29 96.46,100.94 96.47,100.98 96.51,100.99 99.54,100.99 99.58,100.98 99.59,100.94 99.59,95.45 99.59,95.42 99.57,95.41 99.13,94.27 100.1,93.54 114,93.54 114.97,94.27 114.53,95.41 114.51,95.42 114.51,95.45 114.51,102.44 114.52,102.48 114.56,102.49
GND on TOP (solid shape): 76.57,67.47 76.62,67.39 76.62,67.36 77.38,66.6 77.48,66.6 77.49,66.6 77.6,66.57 77.71,66.6 77.72,66.6 78.14,66.6 78.2,66.54 78.2,66.15 77.64,65.6 77.57,65.57 77.5,65.6 77.38,65.68 77.24,65.7 77.17,65.74 77.14,65.81 76.98,66.07 76.69,65.99 76.61,65.95 76.53,65.98 76.52,65.99 76.41,65.99 76.39,65.99 76.37,66 76.31,66.05 76.25,66.08 76.22,66.1 76.21,66.13 76.21,66.67 76.25,66.89 76.1,67.06 76.04,67.14 76.07,67.23 76.11,67.29 76.14,67.36 76.14,67.38 76.22,67.46 76.25,67.48 76.27,67.48 76.38,67.46 76.48,67.48
GND on TOP (solid shape): 65.55,60.5 65.63,60.52 65.81,60.34 65.84,60.31 65.91,60.24 66.02,60.23 66.09,60.24 66.17,60.22 66.21,60.14 66.21,59.7 66.2,59.67 66.07,59.52 66.04,59.34 66.02,59.28 65.96,59.24 65.84,59.17 65.77,59.04 65.77,59.02 65.68,58.93 65.62,58.93 65.55,58.95 65.51,59.01 65.43,59.18 65.26,59.25 65.24,59.25 65.16,59.33 65.15,59.38 65.2,59.42 65.24,59.42 65.31,59.48 65.32,59.49 65.51,59.75 65.3,60 65.24,60.04 65.22,60.11 65.22,60.16 65.23,60.17 65.3,60.24 65.31,60.24 65.44,60.31 65.51,60.44
GND on TOP (solid shape): outline of 201 points within 59.78,71.46 62.63,74.83
GND on TOP (solid shape): outline of 126 points within 56.3,58.42 64.22,61.14
GND on TOP (solid shape): outline of 133 points within 32.32,81.98 87.19,102.49
GND on TOP (solid shape): outline of 156 points within 3.47,0.51 168.69,102.49
GND on TOP (solid shape): outline of 1572 points within 70.53,48.82 79.92,61.25
GND on TOP (solid shape): outline of 11442 points within 56.55,46.89 81.57,74.6
GND on BOTTOM (solid shape): 33.11,36.09 33.11,34.7 32.99,34.57 31.46,34.57 31.33,34.7 31.33,36.09 31.46,36.22 32.99,36.22
GND on BOTTOM (solid shape): 38.36,34.68 38.36,33.82 37.86,33.33 37.15,33.33 37.02,33.45 37.02,34.86 37.08,34.91 38.13,34.91
GND on BOTTOM (solid shape): 76.86,36.98 76.86,33.67 76.74,33.55 75.85,33.55 75.72,33.67 75.72,36.98 75.85,37.1 76.74,37.1
GND on BOTTOM (solid shape): 80.6,80.94 80.6,79.15 80.55,79.1 77.11,79.1 77.02,79.19 77.02,81.02 77.12,81.12 80.43,81.12
GND on BOTTOM (solid shape): 81.86,15.42 81.86,14.02 81.73,13.89 80.36,13.89 80.23,14.02 80.23,15.49 80.26,15.52 81.75,15.52
GND on BOTTOM (solid shape): 83.68,9.42 83.68,8.84 83.51,8.66 82.01,8.66 81.88,8.79 81.88,9.47 82.37,9.96 83.15,9.96
GND on BOTTOM (solid shape): 105.5,82.19 105.5,81.31 105.12,80.92 101.06,80.92 100.8,81.18 100.8,82.07 101.18,82.45 105.25,82.45
GND on BOTTOM (solid shape): 114.14,54.89 114.14,53.37 114.01,53.24 112.23,53.24 111.98,53.49 111.98,54.76 112.23,55.02 114.01,55.02
GND on BOTTOM (solid shape): 147.21,63.93 147.21,61.24 147.06,61.09 144.21,61.09 143.93,61.37 143.93,64.26 144.06,64.39 146.75,64.39
GND on BOTTOM (solid shape): 108.04,64.29 108.04,62.51 107.79,62.26 105.5,62.26 104.61,63.14 104.61,64.16 104.87,64.41 107.92,64.41
GND on BOTTOM (solid shape): 159.1,23.52 159.1,22.25 157.65,20.8 157.01,20.8 156.8,21.01 156.8,23 157.45,23.65 158.97,23.65
GND on BOTTOM (solid shape): 42.82,29.31 42.82,26.59 42.74,26.52 41.8,26.52 41.58,26.74 41.58,28.32 42.13,28.87 42.13,29.39 42.23,29.49 42.64,29.49
GND on BOTTOM (solid shape): 140.81,67.84 140.81,60.73 140.43,60.35 140.11,60.35 139.36,61.1 139.36,63.19 138.27,64.29 138.27,67.84 138.78,68.35 140.3,68.35
GND on BOTTOM (solid shape): 23.58,46.28 23.58,44.12 23.42,43.96 21.14,43.96 20.84,44.25 20.84,45.97 21.16,46.29 23.57,46.29
GND on BOTTOM (solid shape): 30.47,55.77 31.37,55.77 31.72,55.42 31.72,54.64 31.59,54.51 30.45,54.51 30.32,54.64 29.3,54.64 29.18,54.76 29.18,55.78 29.3,55.91 30.33,55.91
GND on BOTTOM (solid shape): 42.96,35.15 42.96,31.9 42.83,31.77 41.53,31.77 41.27,32.03 41.27,34.74 41.83,35.31 42.8,35.31
GND on BOTTOM (solid shape): 60.49,52.76 60.49,52.25 60.36,52.12 59.47,52.12 59.35,52 59.35,50.34 59.22,50.22 58.39,50.22 58.26,50.34 58.26,52.81 58.33,52.88 60.36,52.88
GND on BOTTOM (solid shape): 73.56,38.25 73.56,35.71 73.44,35.58 72.42,35.58 72.29,35.45 72.29,33.67 72.17,33.55 71.15,33.55 71.02,33.67 71.02,38.25 71.15,38.37 73.44,38.37
GND on BOTTOM (solid shape): 81.06,38.25 81.06,33.67 80.93,33.55 79.91,33.55 79.79,33.67 79.79,35.45 79.66,35.58 78.52,35.58 78.39,35.71 78.39,38.25 78.52,38.37 80.93,38.37
GND on BOTTOM (solid shape): 105.34,53.08 105.34,49.96 104.92,49.53 104.13,49.53 103.55,50.11 101.53,50.11 101.35,50.29 101.35,51.86 100.71,52.51 100.71,52.65 101.31,53.25 105.18,53.25
GND on BOTTOM (solid shape): 109.26,75.18 109.26,73.38 108.93,73.05 100.11,73.05 99.47,73.69 99.47,74.51 99.34,74.64 99.34,76.09 99.75,76.49 107.95,76.49
GND on BOTTOM (solid shape): 114.62,23.78 114.62,17.64 113.31,16.32 112.92,16.32 112.85,16.39 112.85,22.91 112.92,22.98 112.92,24.46 113.12,24.67 113.74,24.67
GND on BOTTOM (solid shape): 162.2,39.8 162.2,37.67 162.42,37.44 163.07,37.44 163.16,37.34 163.16,36.47 163.01,36.32 161.69,36.32 161.51,36.5 161.51,39.75 161.69,39.93 162.07,39.93
GND on BOTTOM (solid shape): 50.38,58.04 50.38,57.71 50.59,57.51 51.76,57.51 51.88,57.38 51.88,57.07 51.78,56.97 49.37,56.97 49.27,57.07 49.27,57.46 50,58.19 50.23,58.19
GND on BOTTOM (solid shape): 85.25,38.25 85.25,33.67 85.12,33.55 83.6,33.55 83.47,33.67 83.47,37.27 83.35,37.39 83.35,37.85 83.47,37.96 83.47,38.25 83.6,38.37 85.12,38.37
GND on BOTTOM (solid shape): 146.85,35.7 147.3,35.7 147.4,35.6 147.41,35.58 147.41,35.34 147.4,35.32 147.3,35.21 147.28,35.2 145.54,35.2 145.46,35.29 145.46,36.09 145.59,36.22 146.33,36.22
GND on BOTTOM (solid shape): 152.24,66.68 152.24,64.92 152.75,64.41 152.75,63.53 151.48,62.26 150.97,62.26 150.84,62.38 150.84,66.68 150.99,66.83 152.09,66.83
GND on BOTTOM (solid shape): 37.63,46.94 37.63,45.36 37.44,45.16 34.77,45.16 34.61,45.32 34.61,47.2 34.9,47.49 37.09,47.49
GND on BOTTOM (solid shape): 45.22,50.4 45.22,49.71 45.03,49.52 45.03,48.44 44.94,48.35 44.64,48.35 44.32,48.66 44,48.66 43.91,48.75 43.91,49.16 44.26,49.51 44.26,50.35 44.35,50.44 45.18,50.44
GND on BOTTOM (solid shape): 46.07,54.54 46.07,53.49 46.04,53.47 44.03,53.47 43.91,53.34 42.71,53.34 42.64,53.42 42.64,53.98 42.74,54.08 43.11,54.08 43.8,54.77 45.84,54.77
GND on BOTTOM (solid shape): 106.52,68.61 106.52,67.72 105.88,67.08 105.88,66.57 105.5,66.19 102.33,66.19 100.42,68.1 100.42,68.73 100.55,68.86 106.26,68.86
GND on BOTTOM (solid shape): 24.22,76.15 24.22,71.27 24.04,71.09 22.22,71.09 21.94,71.37 21.94,72.29 21.81,72.42 20.16,72.42 20.03,72.54 20.03,76.35 20.29,76.61 23.77,76.61
GND on BOTTOM (solid shape): 71.24,81.05 71.24,77.45 71.42,77.27 71.42,76.89 71.26,76.73 69.86,76.73 66.78,79.81 66.78,80.29 67.58,81.09 71.19,81.09
GND on BOTTOM (solid shape): 90.73,18.6 90.73,14.82 91.18,14.37 91.18,13.97 91.07,13.85 90.65,13.85 89.68,14.82 89.68,18.23 90.17,18.73 90.6,18.73
GND on BOTTOM (solid shape): 156.05,37.26 156.05,29.46 155.82,29.23 153.86,29.23 153.64,29.45 153.64,36.33 153.79,36.49 153.81,36.49 155.02,37.69 155.62,37.69
GND on BOTTOM (solid shape): 25.82,67.11 25.82,66.25 26.48,65.58 26.48,62.79 26.33,62.64 25.29,62.64 25.15,62.78 25.15,66.93 25.16,66.94 25.16,67.08 25.29,67.21 25.72,67.21
GND on BOTTOM (solid shape): 128.24,35.41 128.24,33.68 127.83,33.68 127.83,34.77 127.45,34.77 127.45,33.68 127.04,33.68 127.04,34.77 126.64,34.77 126.64,33.68 126.23,33.68 126.23,34.77 125.85,34.77 125.85,33.68 125.44,33.68 125.44,34.94 126.11,35.61 128.03,35.61
GND on BOTTOM (solid shape): 123.74,32.28 123.74,27.19 123.52,26.98 120.5,26.98 120.4,26.98 120.2,27.18 120.2,29.68 120.46,29.95 120.69,29.95 121.52,30.78 121.52,32.24 121.79,32.51 123.32,32.51 123.5,32.51
GND on BOTTOM (solid shape): 144.58,34.95 144.67,34.95 144.74,34.88 144.76,34.88 144.76,33.96 144.66,33.86 144.45,33.86 144.39,33.92 144.39,34.54 144.2,34.72 144.07,34.72 143.99,34.64 143.99,33.89 143.92,33.82 143.72,33.82 143.6,33.94 143.6,35.51 143.63,35.54 143.98,35.54
GND on BOTTOM (solid shape): 76.14,13.65 76.14,13.42 76.14,13.41 77,12.55 77.31,12.55 77.42,12.45 77.42,11.44 77.01,11.03 76.58,11.03 76.42,11.19 76.42,11.59 76.26,11.75 75.89,11.75 75.71,11.57 75.71,11.25 75.49,11.03 74.54,11.03 74.32,11.25 74.32,13.48 74.65,13.82 75.97,13.82
GND on BOTTOM (solid shape): 142.7,34.88 142.7,33.93 142.61,33.84 142.42,33.84 142.33,33.93 142.33,34.71 142.27,34.78 142,34.78 141.92,34.69 141.92,33.89 141.86,33.84 141.59,33.84 141.52,33.92 141.52,34.89 141.21,35.2 141.08,35.2 140.93,35.35 140.93,35.66 140.97,35.7 141.88,35.7
GND on BOTTOM (solid shape): 148.34,71.53 148.34,68.78 148.15,68.6 147.83,68.6 147.76,68.53 147.76,68.16 147.56,67.96 147.39,67.96 147.21,68.14 147.21,68.44 147.21,68.48 147.1,68.58 144.63,68.58 144.45,68.76 144.45,69.24 144.32,69.38 144.04,69.38 143.86,69.56 143.86,70.61 144.4,71.14 144.4,71.6 144.49,71.7 148.16,71.7
GND on BOTTOM (solid shape): 65.19,53.01 65.57,53.01 65.57,53.01 66.08,53.01 66.46,53.39 67.35,53.39 67.47,53.27 67.47,51.23 67,50.75 67,49.12 66.95,49.07 65.4,49.07 65.15,48.82 62.65,48.82 62.52,48.95 62.52,52.63 62.65,52.76 62.9,52.76 63.03,52.88 64.3,52.88 64.43,53.01 64.43,53.27 64.55,53.39 64.81,53.39
GND on BOTTOM (solid shape): 83.15,74 83.15,72.92 82.9,72.67 82.64,72.67 82.26,72.29 82.26,71.27 81.63,70.64 80.74,70.64 80.73,70.64 79.47,70.64 79.33,70.5 77.17,70.5 76.93,70.74 76.93,71.4 76.8,71.53 76.8,71.53 76.67,71.66 76.67,72.09 76.96,72.38 78.05,72.38 78.17,72.26 78.17,71.78 78.44,71.51 78.59,71.51 78.96,71.15 79.36,71.15 79.57,71.35 79.79,71.35 79.99,71.15 80.74,71.15 81.32,71.72 81.32,73.46 81,73.78 81,74.01 81.44,74.45 82.7,74.45
GND on BOTTOM (solid shape): 70.86,62.46 70.86,61.82 71.44,61.24 71.57,61.24 72.23,61.24 72.39,61.39 72.93,61.39 73.06,61.27 73.06,60.63 72.93,60.5 72.06,60.5 72.05,60.51 71.91,60.53 71.77,60.51 71.77,60.5 69.97,60.5 69.69,60.22 69.33,60.22 69.05,60.5 68.36,60.5 68.24,60.38 67.85,60.38 67.73,60.5 67.73,60.89 67.85,61.01 68.36,61.01 68.49,61.14 68.49,61.77 68.62,61.9 68.95,61.9 69.2,62.15 69.82,62.15 70.2,62.54 70.78,62.54
GND on BOTTOM (solid shape): 118.37,51.92 118.37,51.63 118.38,51.61 118.38,47.98 117.95,47.55 117.95,46.89 117.82,46.76 117.31,46.76 117.19,46.89 117.19,47.37 116.66,47.9 116.64,48.21 116.4,48.4 116.29,48.47 116.16,48.5 116.1,48.54 116.07,48.61 116.07,50.82 116.22,50.97 116.61,50.97 116.85,51.21 116.85,51.92 117.04,52.12 118.17,52.12
GND on BOTTOM (solid shape): 31.33,74.09 31.33,72.67 31.08,72.42 26.76,72.42 26.67,72.5 26.67,73.18 30.09,73.18 30.09,73.15 30.1,73.1 30.11,73.05 30.14,73 30.17,72.96 30.2,72.92 30.24,72.88 30.29,72.86 30.34,72.84 30.39,72.83 30.45,72.82 30.5,72.83 30.55,72.84 30.6,72.86 30.65,72.88 30.69,72.92 30.72,72.96 30.75,73 30.78,73.05 30.79,73.1 30.8,73.15 30.8,73.2 30.79,73.26 30.78,73.31 30.75,73.36 30.72,73.4 30.69,73.44 30.65,73.47 30.6,73.5 30.55,73.52 30.5,73.53 30.45,73.53 30.39,73.53 30.34,73.52 30.29,73.5 30.24,73.47 30.2,73.44 30.17,73.4 30.14,73.36 30.11,73.31 30.1,73.26 30.09,73.2 30.09,73.18 26.67,73.18 26.67,74.55 26.87,74.75 30.68,74.75
GND on BOTTOM (solid shape): 31.31,31.67 32.15,31.67 32.55,31.27 32.55,27.48 32.3,27.23 29.76,27.23 27.98,29.01 27.98,29.68 28.21,29.68 28.22,29.62 28.23,29.56 28.25,29.51 28.28,29.46 28.31,29.41 28.35,29.36 28.4,29.33 28.45,29.3 28.5,29.27 28.56,29.26 28.62,29.25 28.68,29.25 28.74,29.26 28.79,29.27 28.85,29.3 28.9,29.33 28.94,29.36 28.98,29.41 29.02,29.46 29.04,29.51 29.06,29.56 29.08,29.62 29.08,29.68 29.08,29.74 29.06,29.8 29.04,29.85 29.02,29.91 28.98,29.95 28.94,30 28.9,30.03 28.85,30.07 28.79,30.09 28.74,30.1 28.68,30.11 28.62,30.11 28.56,30.1 28.5,30.09 28.45,30.07 28.4,30.03 28.35,30 28.31,29.95 28.28,29.91 28.25,29.85 28.23,29.8 28.22,29.74 28.21,29.68 27.98,29.68 27.98,31.65 28.19,31.85 31.13,31.85
GND on BOTTOM (solid shape): 72.26,71.74 72.26,70.41 73.14,69.54 73.14,68.71 73.06,68.63 73.06,65.71 72.93,65.58 72.3,65.58 72.05,65.84 71.66,65.84 71.54,65.71 71.54,64.95 71.41,64.82 71.14,64.82 70.63,64.31 69.89,64.31 69.66,64.08 69.66,63.6 69.64,63.58 69.22,63.58 69.13,63.67 69.13,64.67 69.13,64.69 69.11,64.8 69.05,64.89 69.05,65.05 69.31,65.3 70.01,65.3 70.02,65.27 70.28,65.08 70.6,65.18 71.12,65.7 71.28,65.86 71.28,67.53 71.63,67.88 71.63,69.46 71.87,69.69 71.87,69.87 71.88,69.88 71.88,70.13 71.78,70.24 71.7,70.24 71.56,70.37 71.56,71.73 71.6,71.77 71.6,71.77 71.77,71.95 72.06,71.95
GND on BOTTOM (solid shape): 68.42,63.88 68.42,63.86 68.5,63.69 68.65,63.58 68.72,63.5 68.69,63.41 68.47,63.19 68.47,62.97 68.45,62.93 68.41,62.92 68.36,62.92 68.24,62.79 68.24,62.54 68.19,62.49 67.78,62.49 67.35,62.92 67.02,62.92 66.89,62.79 66.89,62.76 66.34,62.2 66.34,61.65 66.18,61.49 65.78,61.49 65.7,61.57 65.7,62.74 65.52,62.92 65.19,62.92 65.14,62.97 65.14,63.35 65.22,63.42 65.9,63.42 66.16,63.68 66.16,64.02 66.33,64.19 66.59,64.19 66.84,63.93 66.84,63.8 66.88,63.76 66.89,63.75 67.27,63.56 67.56,63.88 67.56,63.9 67.56,64.22 67.63,64.29 68.01,64.29
GND on BOTTOM (solid shape): 73.57,54.92 74.46,54.92 74.59,54.79 74.59,54.66 74.46,54.54 73.7,54.54 73.57,54.41 73.32,54.41 72.68,55.04 71.92,55.04 71.79,54.92 71.79,54.54 71.57,54.31 71.54,54.31 71.17,54 71.44,53.6 71.46,53.6 71.66,53.39 71.66,53.14 71.54,53.01 70.9,53.01 70.86,53.05 70.85,53.07 70.83,53.21 70.78,53.33 70.78,53.73 70.88,53.97 70.79,54.21 70.78,54.23 70.78,54.28 70.55,54.51 69.43,54.51 69.25,54.69 69.25,55.04 69.38,55.17 70.39,55.17 70.43,55.21 70.44,55.21 70.6,55.3 70.69,55.46 70.7,55.47 71.03,55.81 72.68,55.81
GND on BOTTOM (solid shape): 146.39,89.51 146.3,88.49 147.32,88.32 147.39,88.37 147.46,88.44 148.81,88.44 148.82,88.43 149.1,88.43 150.08,87.45 150.08,80.44 149.75,80.11 149.51,80.11 149.43,80.16 149.35,80.18 148.86,80.67 148.86,82.78 148.9,82.86 148.98,82.88 149.39,83.24 148.98,83.59 148.9,83.61 148.86,83.69 148.86,85.24 147.57,86.54 144.42,86.54 142.84,88.11 142.84,101.67 142.87,101.69 146.39,101.69
GND on BOTTOM (solid shape): 61.95,59.74 62.03,59.7 62.05,59.62 62.28,59.2 62.72,59.38 63.04,59.38 63.09,59.33 63.16,59.29 63.16,57.84 63.28,57.71 63.42,57.71 63.48,57.69 63.53,57.68 63.81,57.68 63.87,57.69 63.92,57.71 64.17,57.71 64.81,58.35 65.06,58.35 65.19,58.22 65.19,57.72 64.82,57.35 64.8,57.35 64.66,57.29 64.6,57.15 64.6,57.12 64.58,57.07 64.57,57.02 64.57,56.72 64.58,56.67 64.49,56.59 62.79,56.59 62.51,56.87 62.51,57.18 62.45,57.24 61.29,57.24 61.23,57.19 60.38,57.19 60.23,57.33 59.6,57.33 59.47,57.46 59.47,57.84 59.95,58.32 61.05,58.32 61.43,58.7 61.43,59.31 61.47,59.35 61.49,59.39 61.63,59.53 61.63,59.62 61.76,59.74
GND on BOTTOM (solid shape): outline of 100 points within 114.06,69.24 120.87,78.77
GND on BOTTOM (solid shape): 124.14,102.49 124.18,102.48 124.19,102.44 124.19,101.63 123.23,100.67 123.23,91.14 121.53,89.43 115.92,89.43 114.13,91.22 114.14,91.24 114.14,92.33 113.94,92.53 100.21,92.53 99.97,92.28 99.97,91.19 99.58,90.81 96.94,90.81 96.46,91.29 96.46,100.94 96.47,100.98 96.51,100.99 99.54,100.99 99.58,100.98 99.59,100.94 99.59,95.45 99.59,95.42 99.57,95.41 99.13,94.27 100.1,93.54 114,93.54 114.97,94.27 114.53,95.41 114.51,95.42 114.51,95.45 114.51,102.44 114.52,102.48 114.56,102.49
GND on BOTTOM (solid shape): 76.17,70.97 76.17,70.87 76.16,70.86 76.09,70.63 76.17,70.41 76.17,70.13 76.12,70.09 76.12,69.54 76.03,69.35 76.06,69.13 76.07,69.1 75.98,69.01 75.6,69.01 75.43,69.19 75.43,69.85 75.27,70.01 75.25,70.12 75.35,70.18 75.71,70.58 75.26,70.88 75.23,70.87 75.15,70.96 75.15,71.22 75.09,71.36 74.94,71.42 74.66,71.42 74.52,71.36 74.46,71.22 74.46,71.08 74.06,70.67 74.06,70.26 74.38,69.94 74.38,69.12 74.39,69.11 74.39,68.22 74.46,68.14 74.46,64.77 74.28,64.59 73.93,64.59 73.84,64.68 73.84,65.35 73.95,65.46 73.95,68.35 73.88,68.42 73.88,69.79 73.33,70.34 73.33,71.53 73.66,71.85 75.28,71.85
GND on BOTTOM (solid shape): 74.69,58.95 74.76,58.95 74.8,58.94 74.81,58.9 74.8,58.88 74.79,58.86 74.97,58.2 75.15,58.86 75.14,58.87 75.12,58.89 75.12,58.9 75.14,58.94 75.17,58.95 75.23,58.95 75.51,58.67 75.51,56.64 75.18,56.31 74.71,56.31 74.59,56.44 74.59,57.92 74.41,58.09 73.8,58.09 73.63,58.27 73.3,58.27 73.02,57.99 72.33,57.99 72.15,57.81 71.64,57.81 71.6,57.84 71.57,57.84 71.42,57.99 70.55,57.99 70.25,58.04 70.02,57.84 70.01,57.84 69.92,57.84 69.89,57.81 69.84,57.81 69.62,57.58 69.38,57.58 69.38,57.58 68.77,57.58 68.65,57.46 67.73,57.46 66.72,56.44 65.7,56.44 65.45,56.69 65.45,57.15 66.39,58.09 67.58,58.09 67.63,58.04 68.52,58.04 68.57,58.09 68.95,58.09 69.4,58.54 69.95,58.54 70.27,58.85 71.48,58.85 71.56,58.81 71.58,58.72 71.91,58.25 72.25,58.72 72.26,58.81 72.35,58.85 73.57,58.85 73.82,59.11 74.53,59.11
GND on BOTTOM (solid shape): outline of 180 points within 106.01,27.58 109.24,35.33
GND on BOTTOM (solid shape): outline of 83 points within 68.37,41.05 75.45,47.93
GND on BOTTOM (solid shape): outline of 428 points within 55.49,59.64 63.47,64.72
GND on BOTTOM (solid shape): outline of 150 points within 22.32,81.98 87.63,102.49
GND on BOTTOM (solid shape): outline of 182 points within 3.47,0.51 168.69,102.49
GND on BOTTOM (solid shape): outline of 1835 points within 46.26,24.71 67.72,45.29
GND on BOTTOM (solid shape): outline of 1958 points within 85.48,24.64 105.83,51.6
GND on SGND (solid shape): outline of 1989 points within 3.39,0.51 168.69,102.49
GND on IN1 (solid shape): 33.11,36.09 33.11,34.7 32.99,34.57 31.46,34.57 31.33,34.7 31.33,36.09 31.46,36.22 32.99,36.22
GND on IN1 (solid shape): 80.27,80.89 80.27,79.34 80.03,79.1 77.11,79.1 77.02,79.19 77.02,80.3 77.83,81.12 80.04,81.12
GND on IN1 (solid shape): 81.86,15.06 81.86,14.02 81.73,13.89 80.36,13.89 80.23,14.02 80.23,15.06 80.28,15.11 81.8,15.11
GND on IN1 (solid shape): 114.77,54.86 114.77,52.8 114.58,52.6 112.19,52.6 111.98,52.81 111.98,54.87 112.25,55.14 114.49,55.14
GND on IN1 (solid shape): 31.72,55.78 31.72,54.38 31.64,54.31 29.13,54.31 29.05,54.38 29.05,55.65 29.3,55.91 31.59,55.91
GND on IN1 (solid shape): 71.24,78.75 71.06,78.58 68.01,78.58 67.68,78.91 67.68,79.76 67.6,79.84 67.06,79.84 66.85,80.06 66.85,80.4 67.54,81.09 71.24,81.09
GND on IN1 (solid shape): 105.34,53.08 105.34,49.96 104.92,49.53 104.13,49.53 103.55,50.11 101.53,50.11 101.35,50.29 101.35,51.86 100.71,52.51 100.71,52.64 101.32,53.25 105.18,53.25
GND on IN1 (solid shape): 148.34,71.39 148.34,68.78 148.15,68.6 147.83,68.6 147.82,68.58 144.63,68.58 144.45,68.76 144.45,69.24 144.32,69.38 144.04,69.38 143.97,69.45 143.97,69.51 144.85,70.39 144.85,71.09 145.18,71.42 148.3,71.42
GND on IN1 (solid shape): 124.15,102.49 124.18,102.48 124.19,102.45 124.19,101.62 123.36,100.79 123.36,90.48 122.84,89.96 114.52,89.96 114.14,90.34 114.14,92.33 113.94,92.53 100.21,92.53 99.28,91.59 96.89,91.59 96.46,92.03 96.46,100.95 96.47,100.98 96.51,100.99 99.54,100.99 99.57,100.98 99.59,100.95 99.59,95.44 99.59,95.42 99.57,95.41 99.13,94.28 100.1,93.54 114,93.54 114.97,94.28 114.53,95.41 114.51,95.42 114.51,95.44 114.51,102.45 114.52,102.48 114.55,102.49
GND on IN1 (solid shape): outline of 119 points within 22.32,81.98 87.19,102.49
GND on IN1 (solid shape): outline of 170 points within 3.47,0.51 168.69,102.49
GND on IN2 (solid shape): 33.11,36.09 33.11,34.7 32.99,34.57 31.46,34.57 31.33,34.7 31.33,36.09 31.46,36.22 32.99,36.22
GND on IN2 (solid shape): 80.6,80.94 80.6,79.15 80.55,79.1 77.11,79.1 77.02,79.19 77.02,81.02 77.12,81.12 80.43,81.12
GND on IN2 (solid shape): 81.86,15.42 81.86,14.02 81.73,13.89 80.36,13.89 80.23,14.02 80.23,15.49 80.26,15.52 81.75,15.52
GND on IN2 (solid shape): 31.72,55.78 31.72,54.38 31.65,54.32 29.11,54.32 29.05,54.38 29.05,55.65 29.3,55.91 31.59,55.91
GND on IN2 (solid shape): 71.51,81.14 71.51,77 71.4,76.89 70.77,76.89 69.09,78.58 68.01,78.58 66.85,79.73 66.85,80.51 67.59,81.25 71.4,81.25
GND on IN2 (solid shape): 114.52,55.14 114.52,53.11 114.27,52.86 112.23,52.86 112.11,52.98 112.11,55.14 112.23,55.27 114.39,55.27
GND on IN2 (solid shape): 105.34,53.08 105.34,49.96 104.92,49.53 104.13,49.53 103.55,50.11 101.53,50.11 101.35,50.29 101.35,51.86 100.71,52.51 100.71,52.64 101.31,53.25 105.18,53.25
GND on IN2 (solid shape): 148.34,71.53 148.34,68.78 148.15,68.6 147.83,68.6 147.76,68.53 147.76,68.16 147.56,67.96 147.39,67.96 147.21,68.14 147.21,68.44 147.21,68.48 147.1,68.58 144.63,68.58 144.45,68.76 144.45,69.24 144.32,69.38 144.04,69.38 143.86,69.56 143.86,70.61 144.4,71.14 144.4,71.6 144.49,71.7 148.16,71.7
GND on IN2 (solid shape): outline of 172 points within 3.47,0.51 168.69,102.49
GND on IN2 (solid shape): outline of 196 points within 22.32,81.98 124.19,102.49
GND on SVCC (solid shape): 66.15,78.19 66.15,78.18 66.26,78.08 66.26,75.14 65.37,74.25 65.37,73.36 64.99,72.98 64.99,70.56 64.56,70.13 63.07,70.13 62.73,70.38 62.39,70.13 62.38,70.13 62.17,70.34 62.17,73.57 62.37,73.89 62.17,74.21 62.17,77.8 62.76,78.38 65.95,78.38
GND on SVCC (solid shape): outline of 103 points within 123.41,29.49 147.79,76.99
GND on SVCC (solid shape): outline of 412 points within 3.65,0.76 31.38,78.82
GND on SVCC (solid shape): outline of 562 points within 22.32,81.98 124.01,102.24
GND on SVCC (solid shape): outline of 582 points within 17.77,10.31 111.85,72.48
GND on SVCC (solid shape): outline of 783 points within 142.84,0.76 168.44,102.24
V1P8_AA18_PEW on IN2 (solid shape): outline of 308 points within 76.49,66.47 80.94,68.21
VDD10 on TOP (solid shape): 152.11,71.65 152.11,69.44 151.92,69.24 149.95,69.24 149.83,69.37 149.83,71.65 150.08,71.91 151.86,71.91
VDD10 on BOTTOM (solid shape): 150.59,64.16 150.59,62.26 150.46,62.13 149.83,62.13 149.44,62.51 149.44,62.89 149.32,63.02 149.32,64.06 149.37,64.11 149.78,64.11 149.95,64.29 150.46,64.29
